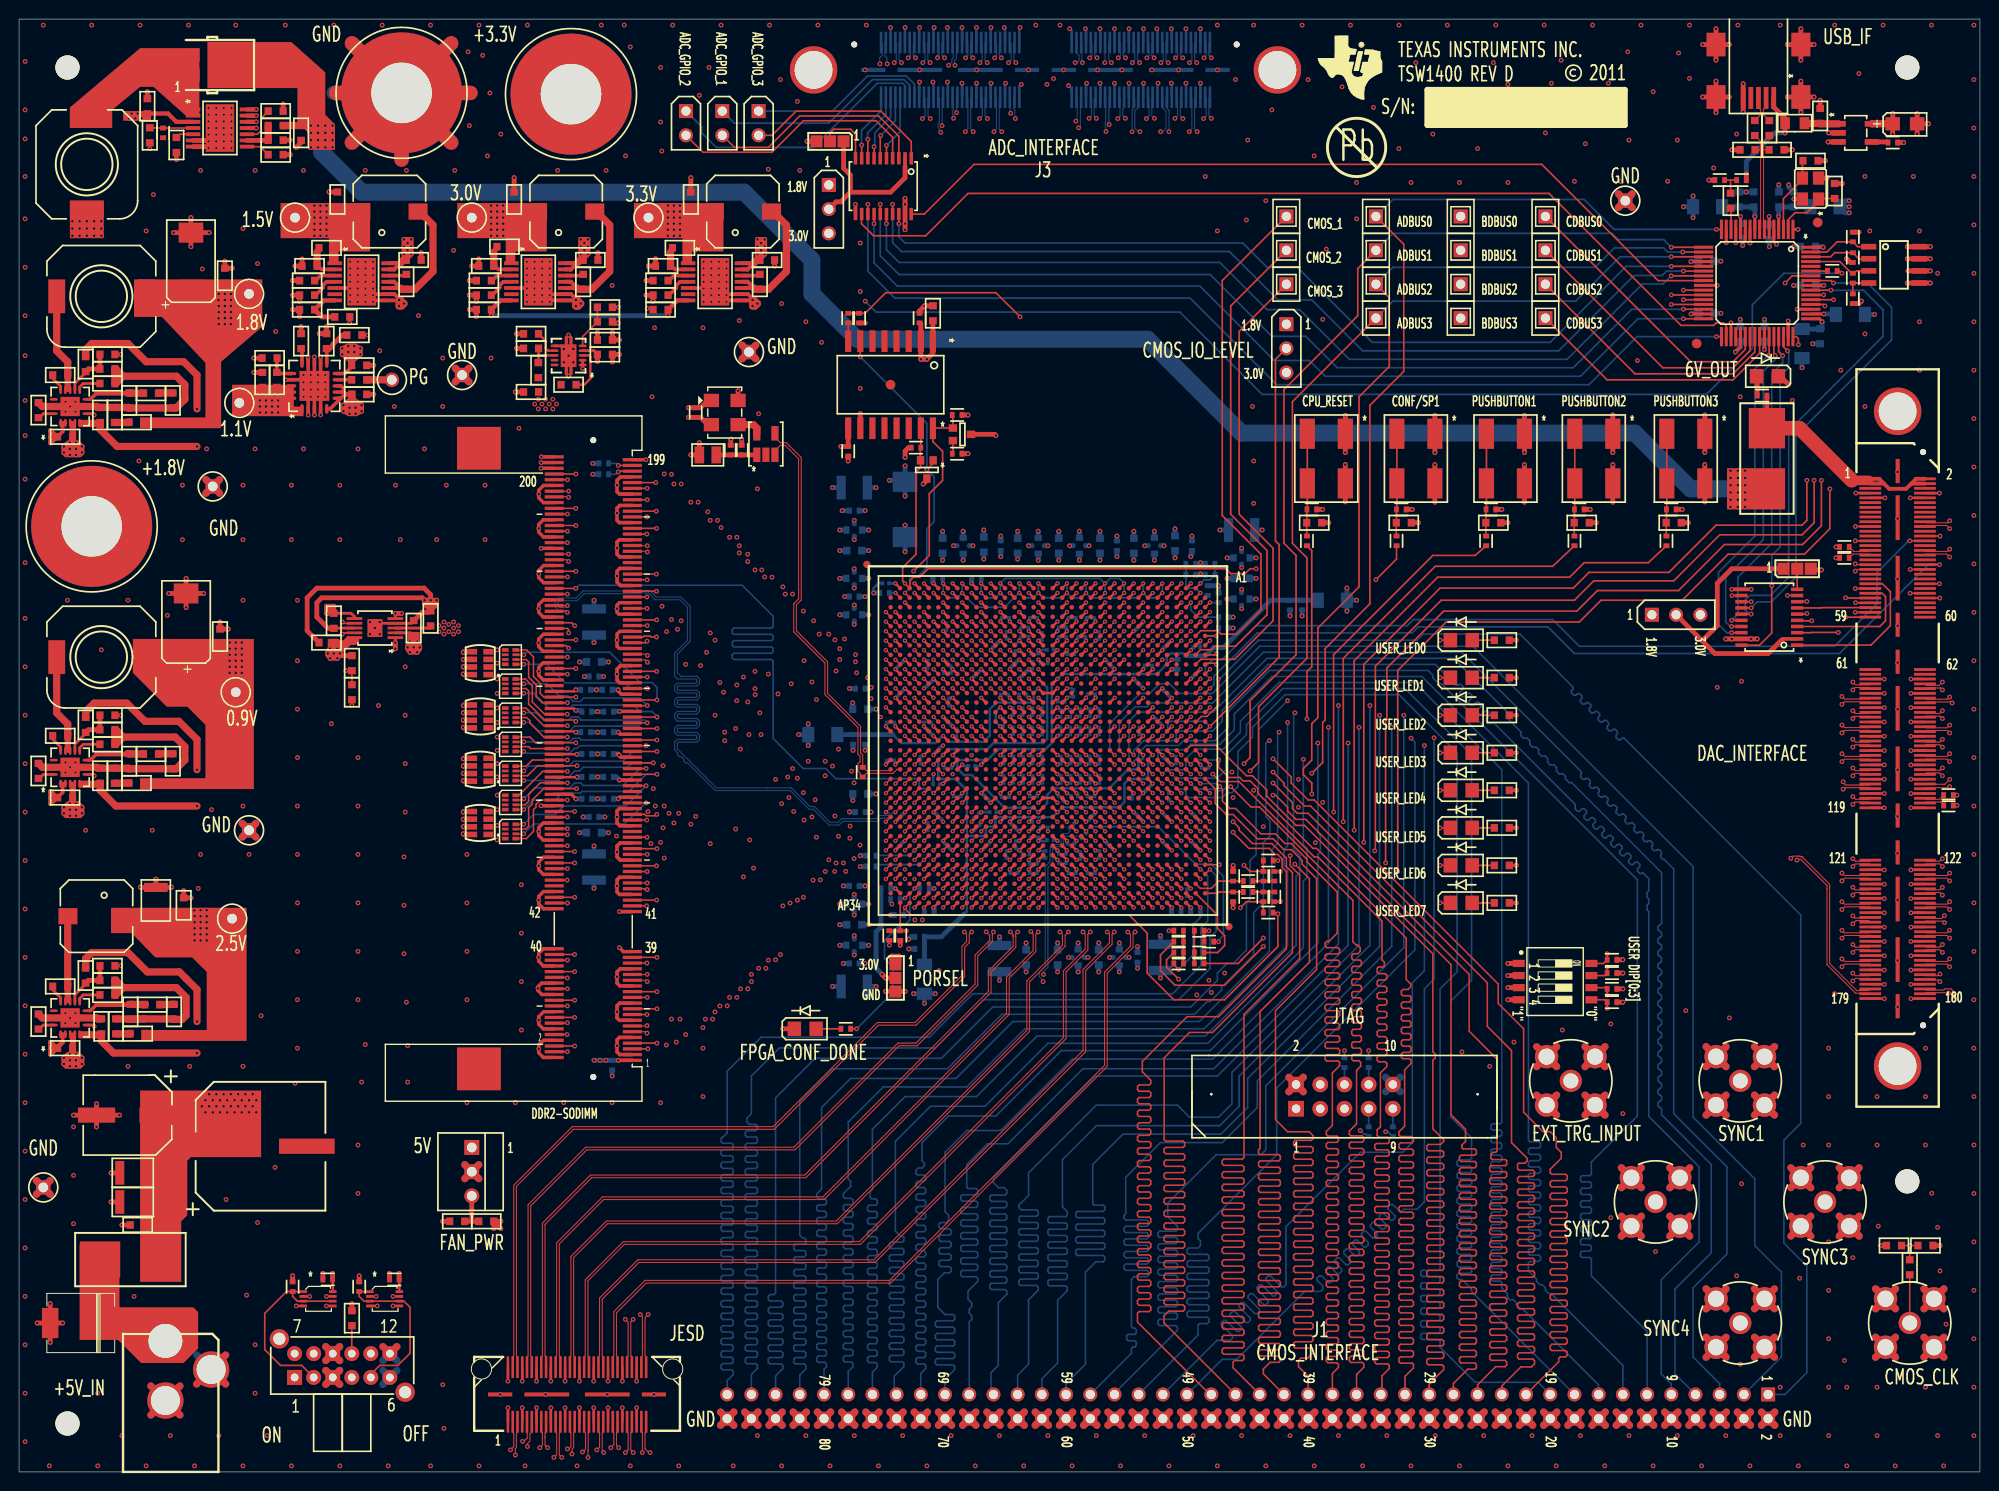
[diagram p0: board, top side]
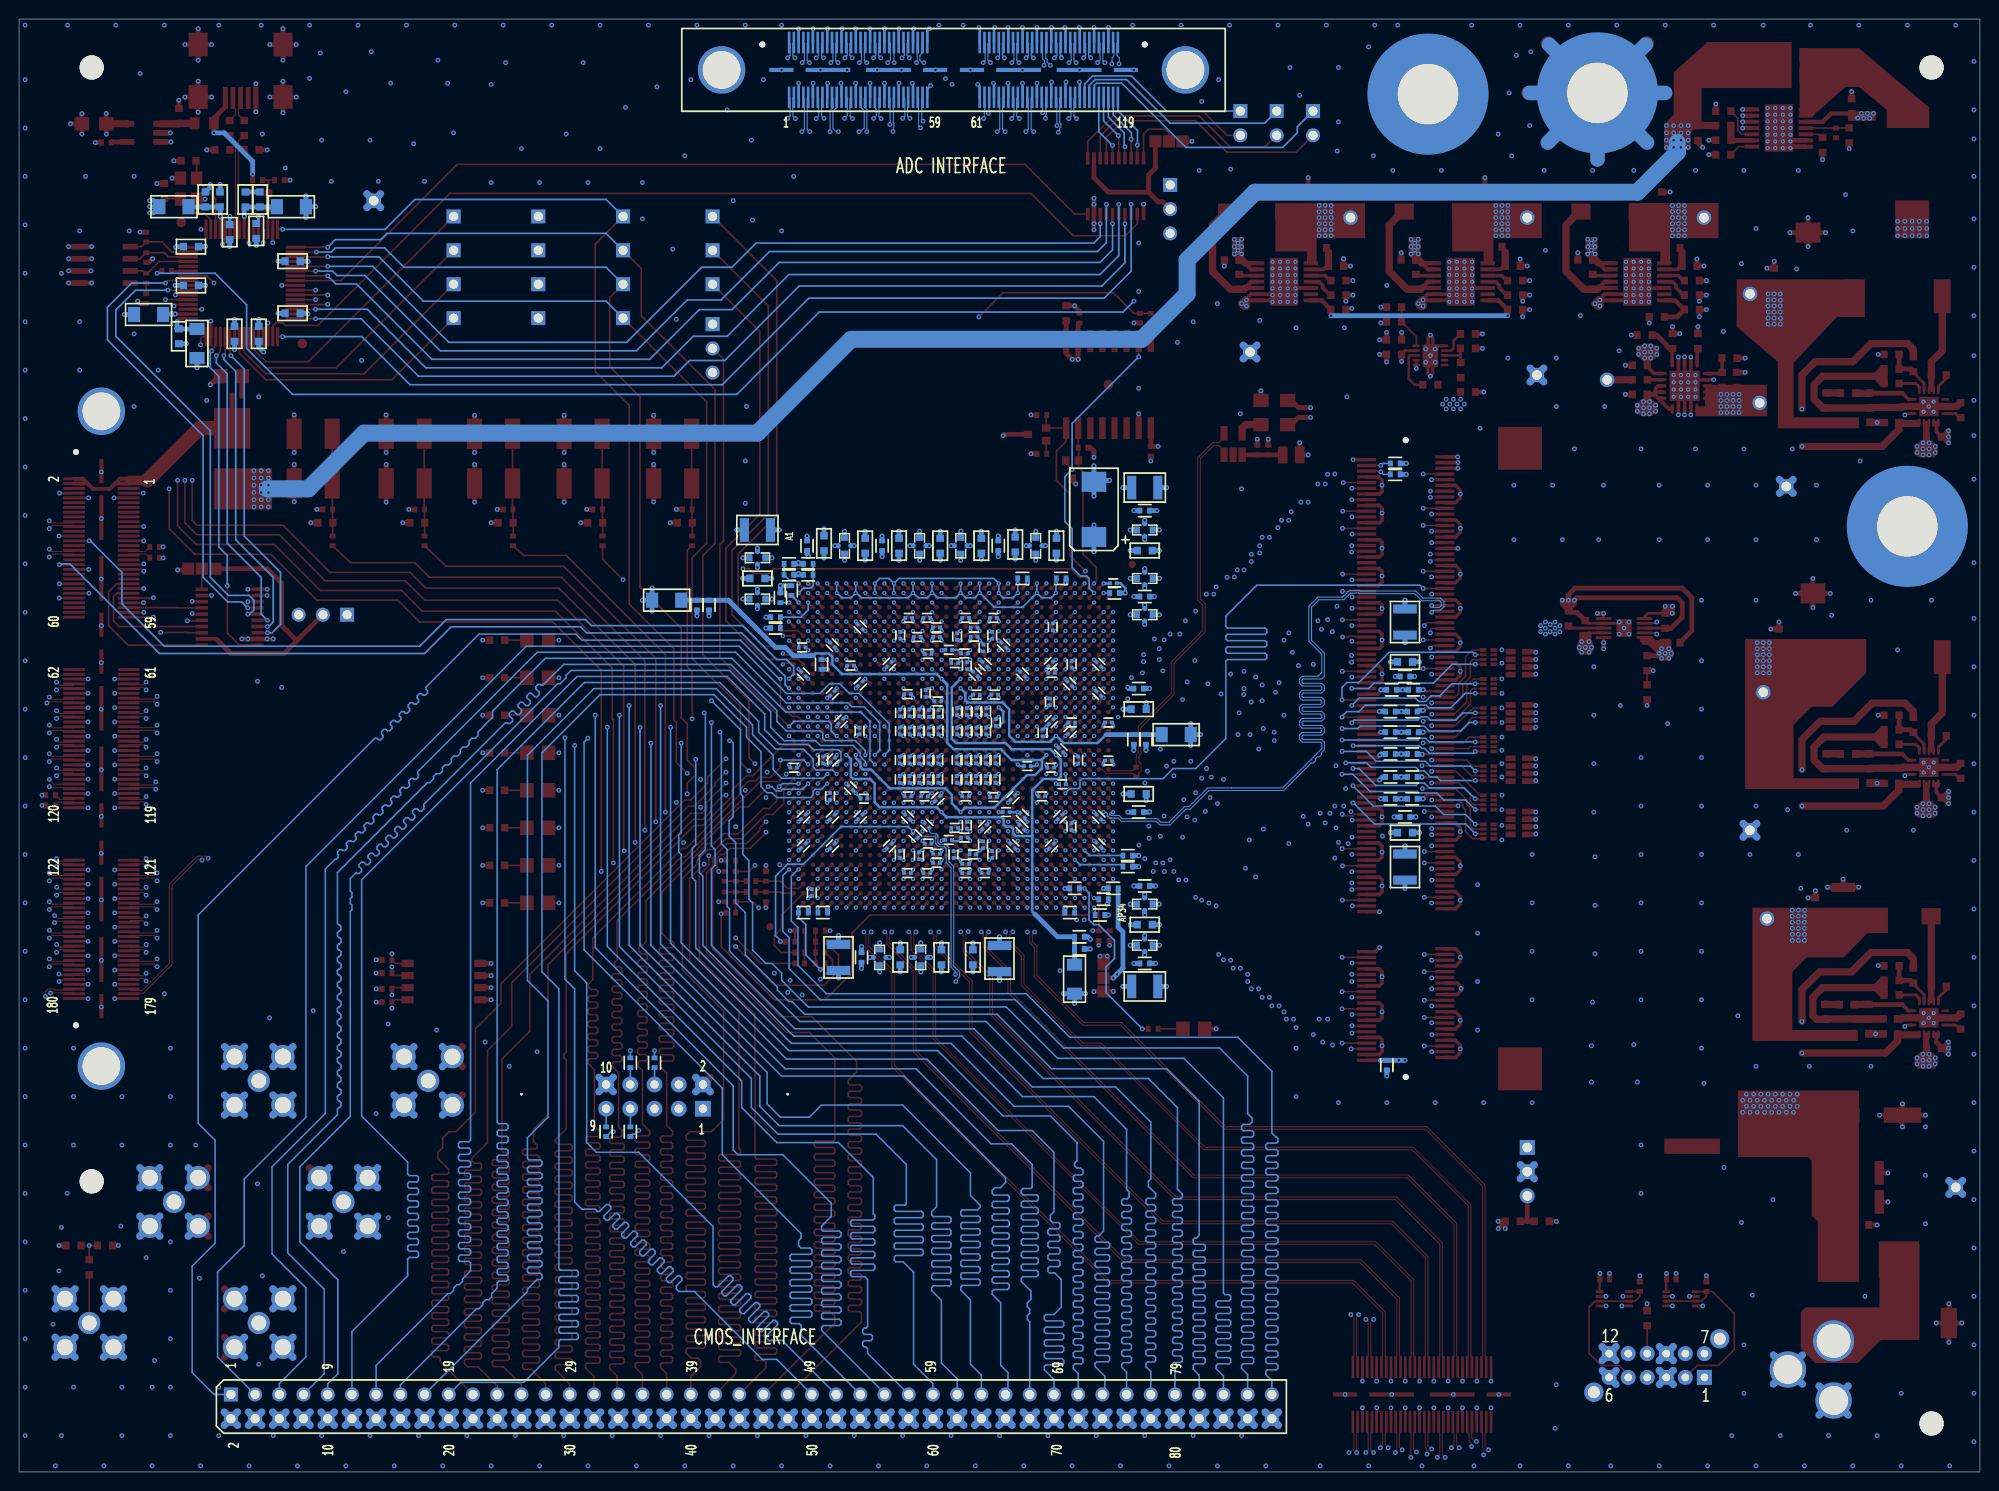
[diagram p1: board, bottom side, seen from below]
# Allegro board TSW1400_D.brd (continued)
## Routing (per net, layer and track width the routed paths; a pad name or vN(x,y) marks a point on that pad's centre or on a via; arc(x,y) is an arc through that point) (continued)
ADBUS0: length 118.5
  TOP w0.178: U3.16 v1(178.09,130.34) ; v1(135.64,73.28) 136.78,74.42 136.78,78.61 137.03,78.87 137.03,86.36 141.73,91.06 141.73,111.89 145.29,115.44 145.29,128.78 TP1.1 ; U5.D22 v2(121.95,71.2)
  L10-SIG4 w0.102: 121.97,71.2 v2(121.95,71.2)
  L10-SIG4 w0.178: v1(135.64,73.28) 135.64,72.92 133.17,70.46 130.99,70.46 130.51,70.94 128.96,70.94 128.52,71.37 125.86,71.37 125.22,70.74 122.43,70.74 121.97,71.2
  BOTTOM w0.178: TP1.1 144.15,133.48 164.21,133.48 167.35,130.34 v1(178.09,130.34)
ADBUS1: length 110.6
  TOP w0.178: v1(128.52,74.3) 129.16,74.93 129.16,80.9 133.99,85.72 133.99,96.14 132.72,97.41 132.72,113.54 140.46,121.28 140.46,126.24 TP2.1 ; U5.J20 v2(116.95,73.2) ; U3.17 v1(173.35,128.46)
  L10-SIG4 w0.178: v2(116.95,73.2) 116.95,73.21 117.45,73.71 118.19,73.71 118.44,73.96 118.44,74.35 118.77,74.68 122.15,74.68 123.29,75.82 127,75.82 v1(128.52,74.3)
  BOTTOM w0.178: TP2.1 144.15,129.92 167.13,129.92 167.79,129.26 172.56,129.26 v1(173.35,128.46)
ADBUS2: length 113.5
  TOP w0.178: U3.18 v1(174.55,127.96) ; TP3.1 143.76,123.19 143.76,115.95 140.59,112.78 140.59,92.84 136.27,88.52 136.27,79.12 135.64,78.49 135.64,74.68 134.75,73.79 134.75,73.15 135.64,72.26 v1(135.64,71.12) ; U5.D25 v2(121.95,68.2)
  L10-SIG4 w0.178: v1(135.64,71.12) 136.63,71.12 137.29,70.46 137.29,69.88 136.63,69.22 126.16,69.22 125.63,68.68 122.43,68.68 v2(121.95,68.2)
  BOTTOM w0.178: TP3.1 144.15,126.36 165.35,126.36 167.39,128.4 172.54,128.4 172.98,127.96 v1(174.55,127.96)
ADBUS3: length 102.5
  TOP w0.178: U5.F21 v2(119.95,72.2) ; U3.19 v1(173.35,127.46) ; TP4.1 133.6,112.27 133.6,97.41 135.13,95.89 135.13,85.34 130.05,80.26 130.05,74.42 v1(129.16,73.53)
  L10-SIG4 w0.178: v1(129.16,73.53) 128.02,73.53 127.65,73.89 126.47,73.89 126.24,73.66 120.65,73.66 120.4,73.41 120.4,72.65 v2(119.95,72.2)
  BOTTOM w0.178: v1(173.35,127.46) 167.98,127.46 163.32,122.81 144.15,122.81 TP4.1
ADC_0: length 90.3
  TOP w0.178: U3.24 171.96,124.96 159.77,137.16 100.2,137.16 94.99,131.94 U16.20
ADC_1: length 94.7
  TOP w0.178: U16.18 v1(92.31,130.94) ; U3.21 v1(173.35,126.46)
  BOTTOM w0.178: v1(92.31,130.94) 92.31,129.56 92.96,128.9 128.4,128.9 130.94,126.36 134.11,126.36 141.99,118.49 160.66,118.49 168.63,126.46 v1(173.35,126.46)
ADC_2: length 98.3
  TOP w0.178: U3.22 v1(174.62,125.96) ; U16.17 v1(91.66,132.97)
  BOTTOM w0.178: v1(174.62,125.96) 172.85,125.96 172.39,125.5 169.44,125.5 161.54,117.6 140.97,117.6 135.64,122.94 132.08,122.94 127,128.02 92.58,128.02 91.66,128.94 v1(91.66,132.97)
ADC_3: length 97.9
  TOP w0.178: U16.16 v1(91.01,130.94) ; U3.23 v1(173.35,125.46)
  BOTTOM w0.178: v1(173.35,125.46) 172.5,124.61 170.33,124.61 162.43,116.71 139.57,116.71 134.37,121.92 130.94,121.92 125.98,126.87 92.33,126.87 91.01,128.19 v1(91.01,130.94)
ADC_4: length 100.2
  TOP w0.178: U3.30 v1(174.62,121.96) ; U16.15 v1(90.36,132.97)
  BOTTOM w0.178: v1(90.36,132.97) 90.36,127.57 92.33,125.6 124.97,125.6 131.44,119.13 135,119.13 138.3,115.82 163.07,115.82 169.21,121.96 v1(174.62,121.96)
ADC_5: length 99.6
  TOP w0.178: U3.32 v1(174.62,120.96) ; U16.14 v1(89.71,130.94)
  BOTTOM w0.178: v1(174.62,120.96) 169.86,120.96 163.83,114.94 137.03,114.94 135.38,116.59 131.7,116.59 123.89,124.4 92.14,124.4 89.71,126.83 v1(89.71,130.94)
ADC_6: length 104.6
  TOP w0.178: U3.33 v1(178.09,119.09) ; U16.13 v1(89.06,132.97)
  BOTTOM w0.178: v1(178.09,119.09) 169.76,119.09 164.72,114.05 131.95,114.05 122.87,123.13 91.88,123.13 89.06,125.95 v1(89.06,132.97)
ADC_7: length 101.2
  TOP w0.178: U16.12 88.39,131.93 88.39,130.94 89.66,129.67 95.12,129.67 99.57,134.11 160.53,134.11 174.37,120.27 177.8,120.27 178.05,120.52 178.82,120.52 179.12,120.22 U3.34
ADC_GPIO_0: length 20.2
  TOP w0.178: U16.1 93.61,139.56 90.42,142.75 81.53,142.75 78.99,140.21 JP5.2
ADC_GPIO_1: length 23.6
  TOP w0.178: U16.3 92.31,140.1 90.17,142.24 81.92,142.24 78.61,138.94 75.06,138.94 JP6.2
ADC_GPIO_2: length 26.7
  TOP w0.178: JP7.2 71.75,138.43 78.99,138.43 82.3,141.73 89.92,141.73 91.66,139.99 U16.4
ADC_GPIO_3: length 7
  TOP w0.178: U16.5 v1(91.01,139.14)
  BOTTOM w0.178: J3.111 92.45,140.58 v1(91.01,139.14)
ADC_GPIO_4: length 7.1
  TOP w0.178: U16.6 90.36,140.18 v1(90.4,140.18)
  BOTTOM w0.178: J3.113 91.95,141.73 90.39,140.18 v1(90.4,140.18)
ADC_GPIO_5: length 7.1
  TOP w0.178: U16.7 v1(89.71,139.02)
  BOTTOM w0.178: v1(89.71,139.02) 89.79,139.1 89.79,140.46 91.45,142.12 J3.115
ADC_GPIO_6: length 7.2
  TOP w0.178: U16.8 v1(89.06,139.79)
  BOTTOM w0.178: v1(89.06,139.79) 89.03,139.83 89.03,140.46 90.95,142.38 J3.117
ADC_GPIO_7: length 7.3
  TOP w0.178: U16.9 v1(88.41,139.18)
  BOTTOM w0.178: v1(88.41,139.18) 88.39,139.19 88.39,140.72 90.45,142.77 J3.119
ASDI: length 91.8
  TOP w0.178: R156.2 v1(132.08,64.14) ; U19.15 C351.1 94.55,107.38 94.55,106.15 DN1.2 94.59,105.38 94.11,104.9 94.11,96.27 92.71,94.87 92.71,93.44 v2(92.95,93.2) U5.AM1 93.47,92.72 93.47,93.47 93.85,93.85 94.49,93.85 95.38,94.74 126.62,94.74 127.13,94.23 128.65,94.23 129.16,94.74 v1(129.79,94.74)
  L3-SIG1 w0.178: v1(132.08,64.14) 129.41,66.8 129.41,68.58 127.89,70.1 127.25,70.1 126.49,70.87 126.49,72.52 126.36,72.64 126.36,83.57 130.43,87.63 130.43,94.11 v1(129.79,94.74)
BDBUS0: length 106.7
  TOP w0.178: U5.D23 v2(121.95,70.2) ; U3.26 v1(174.62,123.96)
  L3-SIG1 w0.178: TP5.1 140.59,121.03 140.59,97.92 132.46,89.79 132.46,88.14 127.13,82.8 127.13,74.3 126.75,73.91 126.75,73.03 127.76,72.02 127.76,71.11 v1(127.38,70.74)
  L4-SIG2 w0.178: v2(121.95,70.2) 122.49,70.74 v1(127.38,70.74)
  L10-SIG4 w0.178: TP5.1 153.03,129.92 167.89,129.92 173.35,124.46 174.13,124.46 v1(174.62,123.96)
BDBUS1: length 104.2
  TOP w0.178: U5.J21 v2(116.95,72.2) ; U3.27 v1(173.35,123.46)
  L3-SIG1 w0.178: v1(127.25,73.41) 127.89,74.04 127.89,82.17 136.4,90.68 136.4,92.46 141.99,98.04 141.99,118.87 TP6.1
  L4-SIG2 w0.178: v1(127.25,73.41) 127.04,73.62 125.46,73.62 125.43,73.65 125.06,73.65 125.04,73.62 117.78,73.62 117.53,73.37 117.53,73.36 117.42,73.25 117.42,72.67 v2(116.95,72.2)
  L10-SIG4 w0.178: TP6.1 153.16,126.24 169.04,126.24 171.83,123.44 173.34,123.44 v1(173.35,123.46)
BDBUS2: length 103.2
  TOP w0.178: U3.28 v1(174.62,122.96) ; U5.D26 v2(121.95,67.2)
  L3-SIG1 w0.178: TP7.1 144.91,118.24 144.91,99.44 137.54,92.08 137.54,90.42 129.79,82.68 129.79,72.77 128.91,71.88 128.91,71.12 130.56,69.47 v1(130.56,67.69)
  L4-SIG2 w0.178: v2(121.95,67.2) 121.95,67.2 122.37,66.78 126.56,66.78 126.72,66.62 128.6,66.62 129.67,67.69 v1(130.56,67.69)
  L10-SIG4 w0.178: v1(174.62,122.96) 174.6,122.94 172.72,122.94 172.47,122.68 153.16,122.68 TP7.1
BDBUS3: length 96.9
  TOP w0.178: U3.29 v1(173.35,122.46) ; U5.F22 v2(119.95,71.2)
  L3-SIG1 w0.178: TP8.1 145.67,115.44 145.67,98.17 138.68,91.19 138.68,90.17 130.56,82.04 130.56,72.52 v1(129.54,71.5)
  L4-SIG2 w0.178: v1(129.54,71.5) 129.29,71.25 125.73,71.25 125.22,71.75 120.5,71.75 v2(119.95,71.2)
  L10-SIG4 w0.178: v1(173.35,122.46) 173.26,122.46 170.05,119.25 153.03,119.25 TP8.1
CDBUS0: length 117.1
  TOP w0.178: U3.38 181.12,117.75 179.83,116.46 175.39,116.46 TP9.1 ; U5.D24 v2(121.95,69.2)
  L3-SIG1 w0.178: TP9.1 157.61,129.16 157.61,124.33 147.19,113.92 147.19,99.82 147.26,99.75 147.26,94.55 133.99,81.28 133.99,80.77 132.46,79.25 132.46,78.23 133.48,77.22 133.48,70.48 v1(134.24,69.72)
  L4-SIG2 w0.102: v2(121.95,69.2) 122.03,69.2
  L4-SIG2 w0.178: v1(134.24,69.72) 133.68,70.28 127.69,70.28 127.13,69.72 122.56,69.72 122.03,69.2
CDBUS1: length 112.5
  TOP w0.178: U5.H21 v2(117.95,72.2) ; TP10.1 172.47,115.82 179.83,115.82 181.62,117.61 U3.39
  L3-SIG1 w0.178: TP10.1 158.5,126.49 158.5,123.95 149.1,114.55 149.1,94.74 135,80.64 135,79.76 134.11,78.87 134.11,72.77 v1(134.24,72.64)
  L4-SIG2 w0.178: v2(117.95,72.2) 118.44,72.69 125.32,72.69 125.38,72.76 125.43,72.76 125.59,72.92 127.68,72.92 127.71,72.9 132.46,72.9 132.72,72.64 v1(134.24,72.64)
CDBUS2: length 113
  TOP w0.178: U5.D27 v2(121.95,66.2) ; U3.40 182.12,117.48 179.83,115.19 169.54,115.19 TP11.1
  L3-SIG1 w0.178: v1(136.02,66.01) 136.02,66.04 135,67.06 135,73.91 135.38,74.3 135.38,77.98 136.14,78.74 136.14,79.5 150.62,93.98 150.62,115.06 TP11.1
  L4-SIG2 w0.178: v2(121.95,66.2) 122.49,65.66 130.48,65.66 130.81,65.99 135.71,65.99 135.74,66.01 v1(136.02,66.01)
CDBUS3: length 106.8
  TOP w0.178: TP12.1 166.62,114.55 179.83,114.55 182.62,117.34 U3.41 ; U5.F23 v2(119.95,70.2)
  L3-SIG1 w0.178: TP12.1 152.53,113.41 152.53,93.42 137.92,78.82 137.92,71.37 v1(136.78,70.23)
  L10-SIG4 w0.178: v2(119.95,70.2) 120.43,69.72 125.35,69.72 125.48,69.85 127.36,69.85 127.79,70.28 129.77,70.28 130.2,69.85 133.16,69.85 133.54,70.23 v1(136.78,70.23)
CLK_GXB1_M: length 79.5
  TOP w0.114: U5.AD34 v2(100.95,59.2) ; J2.54 64.3,12.08 64.18,12.19 64.18,15.75 64.44,16 v1(64.43,16)
  L9-SIG3 w0.102: v2(100.95,59.2) 100.95,59.06 100.98,59.03 100.98,34.95 91.17,25.15 65.53,25.15 64.14,23.75 64.14,16.3 v1(64.43,16)
CLK_GXB1_P: length 80.7
  TOP w0.114: U5.AD33 v2(100.95,60.2) ; v1(63.61,16) 63.62,16 63.63,16 63.91,15.72 63.91,12.18 63.8,12.06 J2.52
  L9-SIG3 w0.102: v2(100.95,60.2) 100.95,59.74 100.57,59.36 100.57,59.04 100.7,58.92 100.7,35.07 91.05,25.43 65.42,25.43 63.86,23.86 63.86,16.25 v1(63.61,16)
CLK_GXB2_M: length 79.3
  TOP w0.114: U5.AB34 v2(102.95,59.2) ; J2.60 65.8,12.08 65.68,12.19 65.68,16.19 v1(66.01,16.51)
  L9-SIG3 w0.102: v2(102.95,59.2) 102.95,57.02 103.66,56.32 103.66,33.93 90.55,20.83 66.52,20.83 66.42,20.73 66.42,20.7 65.66,19.94 65.66,16.86 v1(66.01,16.51)
CLK_GXB2_P: length 80.4
  TOP w0.114: J2.58 65.3,12.06 65.41,12.18 65.41,16.29 v1(65.19,16.51) ; U5.AB33 v2(102.95,60.2)
  L9-SIG3 w0.102: v2(102.95,60.2) 102.95,59.77 102.57,59.39 102.57,59.04 102.67,58.94 102.67,56.91 103.38,56.2 103.38,34.05 90.44,21.11 66.41,21.11 66.14,20.84 66.14,20.82 65.38,20.05 65.38,16.7 v1(65.19,16.51)
CLK_GXB3_M: length 83.3
  TOP w0.114: v1(64.44,2.03) 64.18,2.28 64.18,4.08 64.3,4.19 J2.53 ; U5.M34 v2(113.95,59.2)
  L4-SIG2 w0.102: v1(64.44,2.03) 64.16,2.31 64.16,4.21 70.61,10.66 70.61,16.89 105.03,51.31 106.05,51.31 111.12,56.39 111.12,57.15 112,58.03 112.56,58.03 112.58,58.04 113.16,58.04 113.95,58.83 v2(113.95,59.2)
CLK_GXB3_P: length 84.4
  TOP w0.114: J2.51 63.8,4.19 63.91,4.08 63.91,2.32 v1(63.62,2.03) ; U5.M33 v2(113.95,60.2)
  L4-SIG2 w0.102: v2(113.95,60.2) 113.95,60.1 113.41,59.56 113.41,58.67 113.03,58.29 112.58,58.29 112.56,58.31 111.89,58.31 110.85,57.27 110.85,56.5 105.93,51.59 104.91,51.59 70.33,17.01 70.33,10.77 63.88,4.32 63.88,2.3 v1(63.62,2.03)
CLK_GXB4_M: length 82.7
  TOP w0.114: v1(66.21,2.03) 66.07,2.03 65.68,2.41 65.68,4.06 65.8,4.17 J2.59 ; U5.K34 v2(115.95,59.2)
  L4-SIG2 w0.102: v2(115.95,59.2) 115.95,59.04 114.8,57.89 114.29,57.89 113.69,57.29 113.69,56.65 111.02,53.99 111.02,52.92 110.72,52.62 110.72,52.04 81,22.33 80.87,22.33 74.42,15.88 74.42,12.93 65.91,4.42 65.91,2.33 v1(66.21,2.03)
CLK_GXB4_P: length 83.5
  TOP w0.114: U5.K33 v2(115.95,60.2) ; v1(65.39,2.03) 65.41,2.05 65.41,4.08 65.3,4.19 J2.57
  L4-SIG2 w0.102: v1(65.39,2.03) 65.63,2.28 65.63,4.54 74.14,13.04 74.14,15.99 80.76,22.61 80.88,22.61 110.44,52.16 110.44,52.74 110.74,53.04 110.74,54.1 113.41,56.77 113.41,57.4 114.17,58.17 114.68,58.17 115.32,58.8 115.32,59.03 115.33,59.04 115.33,59.36 115.32,59.37 115.32,59.44 115.95,60.07 v2(115.95,60.2)
CLK_OSCN: length 42.8
  TOP w0.114: U6.4 79.31,108.52 79.88,107.95 80.52,107.95 82.07,106.4 82.07,91.47 81.56,90.96 81.56,88.24 84.84,84.96 84.84,81.66 88.29,78.21 88.29,75.41 88.52,75.18 R76.1 88.54,73.91 88.9,73.56 91.31,73.56 U5.AP20
CLK_OSCP: length 44.8
  TOP w0.114: U6.3 79.31,107.12 79.86,107.67 80.4,107.67 81.79,106.28 81.79,91.58 81.28,91.07 81.28,88.12 84.56,84.85 84.56,81.55 88.01,78.09 88.01,75.3 88.24,75.07 88.24,74.52 88.02,74.3 88.02,73.53 88.27,73.28 88.27,73.15 R76.2 88.9,73.28 91.27,73.28 91.27,73.27 91.63,73.27 91.63,73.28 91.69,73.28 92.12,73.7 U5.AN20
CMOS_CLK: length 115
  TOP w0.165: R16.1 v1(198.37,23.75) ; v1(198.37,23.75) C46.2 ; v1(198.37,23.75) R15.2 ; U5.B18 v2(123.95,75.2)
  L3-SIG1 w0.102: 125.35,74.42 124.57,75.2 v2(123.95,75.2)
  L3-SIG1 w0.114: v1(198.37,23.75) 194.94,27.18 194.94,32.38 187.2,40.13 187.2,43.56 179.32,51.44 153.29,51.44 152.15,52.58 132.33,52.58 129.92,54.99 129.92,56.26 131.19,57.53 131.19,64.01 128.91,66.29 128.91,68.07 127.76,69.22 127.25,69.22 126.36,70.1 126.36,70.48 125.6,71.25 125.6,71.68 125.48,71.81 125.48,72.52 125.73,72.77 125.73,74.04 125.35,74.42
CMOS_PORT0_0: length 140
  TOP w0.165: U5.B15 123.51,78.7 124.05,79.25 124.64,79.25 125.86,80.47 v2(125.86,83.19)
  BOTTOM w0.165: J1.1 185.28,8.13 187.58,10.42 187.58,21.59 185.17,24 185.17,34.8 186.94,36.58 186.94,58.42 168.41,76.96 168.17,76.96 168.02,76.81 167.79,76.81 167.56,77.04 167.56,77.28 167.71,77.43 167.71,77.66 167.47,77.89 167.24,77.89 167.09,77.74 166.86,77.74 166.62,77.98 166.62,78.21 166.77,78.36 166.77,78.59 166.54,78.83 166.3,78.83 166.16,78.68 165.92,78.68 165.69,78.91 165.69,79.15 165.84,79.29 165.84,79.53 165.6,79.76 165.37,79.76 165.22,79.61 164.99,79.61 164.76,79.85 164.76,80.08 164.9,80.23 164.9,80.46 164.67,80.69 164.44,80.69 164.29,80.55 164.06,80.55 163.82,80.78 163.82,81.01 163.97,81.16 163.97,81.39 163.74,81.63 163.5,81.63 163.35,81.48 163.12,81.48 162.89,81.71 162.89,81.95 163.04,82.1 163.04,82.33 157.48,87.88 147.32,87.88 146.69,87.25 130.05,87.25 125.98,83.19 v2(125.86,83.19)
CMOS_PORT0_1: length 140
  TOP w0.165: U5.L18 v2(114.95,75.2)
  BOTTOM w0.165: J1.3 184.91,12.06 184.91,20.95 182.12,23.75 182.12,30.73 175.64,37.21 175.64,63.5 152.53,86.61 130.18,86.61 125.22,81.66 121.72,81.66 120.7,82.68 119.63,82.68 118.62,81.66 117.6,81.66 114.43,78.49 114.43,75.72 v2(114.95,75.2)
CMOS_PORT0_2: length 140.1
  TOP w0.165: U5.K18 v2(115.95,75.2)
  BOTTOM w0.165: v2(115.95,75.2) 115.44,75.71 115.44,78.61 117.09,80.26 118.36,80.26 118.77,80.67 125.25,80.67 130.56,85.98 151.38,85.98 163.92,73.44 163.92,73.21 163.84,73.13 163.84,72.89 164.07,72.66 164.3,72.66 164.39,72.74 164.62,72.74 164.85,72.51 164.85,72.28 164.77,72.19 164.77,71.96 165,71.72 165.24,71.72 165.32,71.81 165.55,71.81 165.79,71.58 165.79,71.34 165.7,71.26 165.7,71.02 165.94,70.79 166.17,70.79 166.25,70.87 166.49,70.87 166.72,70.64 166.72,70.41 166.64,70.32 166.64,70.09 166.87,69.86 167.1,69.86 167.19,69.94 167.42,69.94 167.66,69.71 167.66,69.47 167.57,69.39 167.57,69.16 167.81,68.92 168.04,68.92 168.12,69.01 168.36,69.01 168.59,68.77 168.59,68.54 168.51,68.46 168.51,68.22 168.74,67.99 168.97,67.99 169.06,68.07 169.29,68.07 169.52,67.84 169.52,67.61 169.44,67.52 169.44,67.29 169.67,67.05 169.91,67.05 169.99,67.14 170.22,67.14 170.46,66.91 170.46,66.67 170.37,66.59 170.37,66.35 170.61,66.12 170.84,66.12 170.92,66.2 171.16,66.2 171.39,65.97 171.39,65.74 171.31,65.65 171.31,65.42 171.54,65.19 171.77,65.19 171.86,65.27 172.09,65.27 172.33,65.04 172.33,64.8 172.24,64.72 172.24,64.49 172.47,64.25 172.6,64.25 173.61,63.25 173.61,37.59 179.2,32 179.2,22.86 175.64,19.3 175.64,12.06 178.44,9.27 178.44,8.13
CMOS_PORT0_3: length 140
  TOP w0.165: U5.K19 v2(115.95,74.2)
  BOTTOM w0.165: v2(115.95,74.2) 116.46,74.71 116.46,78.74 117.42,79.71 125.3,79.71 130.94,85.34 150.52,85.34 156.06,79.8 156.06,79.17 156.83,78.4 156.83,78.37 157.58,77.62 157.58,77.24 157.86,76.97 158.24,76.97 158.51,76.69 158.51,76.31 158.79,76.03 159.17,76.03 159.45,75.76 159.45,75.38 159.72,75.1 160.11,75.1 160.38,74.82 160.38,74.44 160.66,74.16 161.04,74.16 161.32,73.89 161.32,73.51 161.59,73.23 161.97,73.23 162.25,72.95 162.25,72.7 162.65,72.3 162.91,72.3 172.34,62.87 172.34,57.54 172.17,57.38 172.12,57.38 171.96,57.21 171.96,56.88 172.12,56.72 172.17,56.72 172.34,56.55 172.34,56.22 172.17,56.06 172.12,56.06 171.96,55.89 171.96,55.56 172.12,55.4 172.17,55.4 172.34,55.23 172.34,54.9 172.17,54.74 172.12,54.74 171.96,54.57 171.96,54.24 172.12,54.08 172.17,54.08 172.34,53.91 172.34,53.58 172.17,53.42 172.12,53.42 171.96,53.25 171.96,52.92 172.12,52.75 172.17,52.75 172.34,52.59 172.34,52.26 172.17,52.09 172.12,52.09 171.96,51.93 171.96,51.6 172.12,51.43 172.17,51.43 172.34,51.27 172.34,50.94 172.17,50.77 172.12,50.77 171.96,50.61 171.96,50.28 172.12,50.11 172.17,50.11 172.34,49.95 172.34,49.62 172.17,49.45 172.12,49.45 171.96,49.29 171.96,48.96 172.12,48.79 172.17,48.79 172.34,48.63 172.34,48.3 172.17,48.13 172.12,48.13 171.96,47.97 171.96,47.64 172.12,47.47 172.17,47.47 172.34,47.31 172.34,46.98 172.17,46.81 172.12,46.81 171.96,46.65 171.96,46.32 172.12,46.15 172.17,46.15 172.34,45.99 172.34,45.66 172.17,45.49 172.12,45.49 171.96,45.33 171.96,44.99 172.12,44.83 172.17,44.83 172.34,44.66 172.34,44.33 172.17,44.17 172.12,44.17 171.96,44 171.96,43.67 172.12,43.51 172.17,43.51 172.34,43.34 172.34,43.01 172.17,42.85 172.12,42.85 171.96,42.68 171.96,42.35 172.12,42.19 172.17,42.19 172.34,42.02 172.34,41.69 172.17,41.53 172.12,41.53 171.96,41.36 171.96,41.03 172.12,40.87 172.17,40.87 172.34,40.7 172.34,40.37 172.17,40.21 172.12,40.21 171.96,40.04 171.96,39.71 172.12,39.55 172.17,39.55 172.34,39.38 172.34,39.05 172.17,38.89 172.12,38.89 171.96,38.72 171.96,38.39 172.12,38.23 172.17,38.23 172.34,38.06 172.34,37.47 177.55,32.26 177.55,22.99 173.74,19.18 173.74,10.29 175.9,8.13
CMOS_PORT0_4: length 140
  TOP w0.165: U5.J18 v2(116.95,75.2)
  BOTTOM w0.165: v2(116.95,75.2) 116.97,75.22 116.97,75.69 117.98,76.71 121.16,76.71 121.41,76.96 121.41,77.47 121.67,77.72 125.22,77.72 126.24,78.74 126.24,79.88 131.06,84.71 148.59,84.71 150.75,82.55 150.98,82.55 151.04,82.61 151.28,82.61 151.51,82.37 151.51,82.14 151.16,81.79 151.16,81.56 151.39,81.32 151.63,81.32 151.98,81.67 152.21,81.67 152.44,81.44 152.44,81.21 152.09,80.86 152.09,80.62 152.33,80.39 152.56,80.39 152.91,80.74 153.14,80.74 153.38,80.51 153.38,80.27 153.03,79.92 153.03,79.69 153.26,79.45 153.49,79.45 153.84,79.8 154.08,79.8 154.31,79.57 154.31,79.34 153.96,78.99 153.96,78.75 154.19,78.52 154.43,78.52 154.49,78.58 154.72,78.58 163.28,70.02 163.28,69.79 163.27,69.78 163.27,69.55 163.5,69.31 163.74,69.31 163.98,69.56 164.22,69.56 164.45,69.33 164.45,69.1 164.2,68.85 164.2,68.61 164.44,68.38 164.67,68.38 164.92,68.63 165.15,68.63 165.39,68.4 165.39,68.16 165.14,67.91 165.14,67.68 165.37,67.45 165.6,67.45 165.85,67.7 166.09,67.7 166.32,67.46 166.32,67.23 166.07,66.98 166.07,66.75 166.3,66.51 166.54,66.51 166.79,66.76 167.02,66.76 167.25,66.53 167.25,66.29 167,66.05 167,65.81 167.24,65.58 167.47,65.58 167.72,65.83 167.95,65.83 168.19,65.59 168.19,65.36 167.94,65.11 167.94,64.88 168.17,64.64 168.41,64.64 168.65,64.89 168.89,64.89 169.12,64.66 169.12,64.43 168.87,64.18 168.87,63.94 169.11,63.71 169.34,63.71 169.59,63.96 169.82,63.96 170.06,63.73 170.06,63.49 169.81,63.24 169.81,63.01 170.04,62.78 170.27,62.78 170.36,62.87 170.99,62.24 170.99,60.95 170.81,60.77 170.81,60.29 170.99,60.11 170.99,59.63 170.81,59.45 170.81,58.97 170.99,58.79 170.99,37.29 176.28,32 176.28,24.13 172.3,20.15 172.3,10.29 173.35,9.23 J1.9
CMOS_PORT0_5: length 140
  TOP w0.165: U5.J19 v2(116.95,74.2)
  BOTTOM w0.165: v2(116.95,74.2) 116.95,74.53 117.47,75.06 117.47,75.44 118.24,76.2 121.67,76.2 122.17,76.71 125.48,76.71 126.87,78.11 126.87,79.76 131.19,84.07 147.83,84.07 148.34,83.57 148.34,83.31 148.97,82.68 149.22,82.68 169.8,62.1 169.8,37.34 164.97,32.51 164.97,31.25 164.81,31.08 164,31.08 163.83,30.92 163.83,30.59 164,30.42 164.81,30.42 164.97,30.26 164.97,29.93 164.81,29.76 164,29.76 163.83,29.6 163.83,29.27 164,29.1 164.81,29.1 164.97,28.94 164.97,28.61 164.81,28.44 164,28.44 163.83,28.27 163.83,27.94 164,27.78 164.81,27.78 164.97,27.61 164.97,27.28 164.81,27.12 164,27.12 163.83,26.95 163.83,26.62 164,26.46 164.81,26.46 164.97,26.29 164.97,25.96 164.81,25.8 164,25.8 163.83,25.63 163.83,25.3 164,25.14 164.81,25.14 164.97,24.97 164.97,24.64 164.81,24.48 164,24.48 163.83,24.31 163.83,23.98 164,23.82 164.81,23.82 164.97,23.65 164.97,23.32 164.81,23.16 164,23.16 163.83,22.99 163.83,22.66 164,22.5 164.81,22.5 164.97,22.33 164.97,20.57 170.81,14.73 J1.11
CMOS_PORT0_6: length 140
  TOP w0.165: U5.F19 v2(119.95,74.2)
  BOTTOM w0.165: 168.28,8.13 168.28,11.18 160.75,18.71 160.49,18.71 160.15,19.05 160.15,19.3 159.81,19.64 159.56,19.64 159.22,19.98 159.22,20.23 158.37,21.08 158.37,21.92 158.53,22.08 159.47,22.08 159.64,22.25 159.64,22.58 159.47,22.74 158.53,22.74 158.37,22.91 158.37,23.24 158.53,23.41 159.47,23.41 159.64,23.57 159.64,23.9 159.47,24.07 158.53,24.07 158.37,24.23 158.37,24.56 158.53,24.73 159.47,24.73 159.64,24.89 159.64,25.22 159.47,25.39 158.53,25.39 158.37,25.55 158.37,25.88 158.53,26.05 159.47,26.05 159.64,26.21 159.64,26.54 159.47,26.71 158.53,26.71 158.37,26.87 158.37,27.2 158.53,27.37 159.47,27.37 159.64,27.53 159.64,27.86 159.47,28.03 158.53,28.03 158.37,28.19 158.37,28.52 158.53,28.69 159.47,28.69 159.64,28.85 159.64,29.18 159.47,29.35 158.53,29.35 158.37,29.51 158.37,29.84 158.53,30.01 159.47,30.01 159.64,30.17 159.64,30.5 159.47,30.67 158.53,30.67 158.37,30.83 158.37,31.16 158.53,31.33 159.47,31.33 159.64,31.5 159.64,31.83 159.47,31.99 158.53,31.99 158.37,32.16 158.37,32.49 158.53,32.65 159.47,32.65 159.64,32.82 159.64,33.15 159.47,33.31 158.53,33.31 158.37,33.48 158.37,33.81 158.53,33.97 159.47,33.97 159.64,34.14 159.64,34.47 159.47,34.63 158.53,34.63 158.37,34.8 158.37,72.26 147.19,83.44 131.44,83.44 127.51,79.5 127.51,77.85 125.98,76.33 122.94,76.33 122.37,75.76 119.76,75.76 119.51,75.51 119.51,74.64 v2(119.95,74.2)
CMOS_PORT0_7: length 140
  TOP w0.165: U5.F20 v2(119.95,73.2)
  BOTTOM w0.165: 165.74,8.13 165.74,9.12 157.73,17.12 157.5,17.12 157.09,17.54 157.09,17.77 156.8,18.06 156.44,18.06 156.15,18.34 156.15,18.7 155.57,19.28 155.57,19.85 155.41,20.01 154.6,20.01 154.43,20.18 154.43,20.51 154.6,20.67 155.41,20.67 155.57,20.84 155.57,21.17 155.41,21.33 154.6,21.33 154.43,21.5 154.43,21.83 154.6,21.99 155.41,21.99 155.57,22.16 155.57,22.49 155.41,22.65 154.6,22.65 154.43,22.82 154.43,23.15 154.6,23.31 155.41,23.31 155.57,23.48 155.57,23.81 155.41,23.98 154.6,23.98 154.43,24.14 154.43,24.47 154.6,24.64 155.41,24.64 155.57,24.8 155.57,25.13 155.41,25.3 154.6,25.3 154.43,25.46 154.43,25.79 154.6,25.96 155.41,25.96 155.57,26.12 155.57,26.45 155.41,26.62 154.6,26.62 154.43,26.78 154.43,27.11 154.6,27.28 155.41,27.28 155.57,27.44 155.57,27.77 155.41,27.94 154.6,27.94 154.43,28.1 154.43,28.43 154.6,28.6 155.41,28.6 155.57,28.76 155.57,29.09 155.41,29.26 154.6,29.26 154.43,29.42 154.43,29.75 154.6,29.92 155.41,29.92 155.57,30.08 155.57,30.41 155.41,30.58 154.6,30.58 154.43,30.74 154.43,31.07 154.6,31.24 155.41,31.24 155.57,31.4 155.57,31.73 155.41,31.9 154.6,31.9 154.43,32.07 154.43,32.4 154.6,32.56 155.41,32.56 155.57,32.73 155.57,33.06 155.41,33.22 154.6,33.22 154.43,33.39 154.43,33.72 154.6,33.88 155.41,33.88 155.57,34.05 155.57,34.38 155.41,34.54 154.6,34.54 154.43,34.71 154.43,35.04 154.6,35.2 155.41,35.2 155.57,35.37 155.57,35.7 155.41,35.86 154.6,35.86 154.43,36.03 154.43,36.36 154.6,36.52 155.41,36.52 155.57,36.69 155.57,73.66 146.43,82.8 132.21,82.8 128.14,78.74 128.14,77.6 126.36,75.82 123.44,75.82 122.43,74.8 122.43,73.96 122.1,73.64 120.39,73.64 v2(119.95,73.2)
CMOS_PORT0_8: length 140.1
  TOP w0.165: U5.E20 v2(120.95,73.2)
  BOTTOM w0.165: J1.17 152.4,18.92 152.4,19.18 151.4,20.18 151.04,20.18 150.88,20.34 150.88,20.67 151.04,20.84 152.23,20.84 152.4,21 152.4,21.34 152.23,21.5 151.04,21.5 150.88,21.67 150.88,22 151.04,22.16 152.23,22.16 152.4,22.33 152.4,22.66 152.23,22.82 151.04,22.82 150.88,22.99 150.88,23.32 151.04,23.48 152.23,23.48 152.4,23.65 152.4,23.98 152.23,24.14 151.04,24.14 150.88,24.31 150.88,24.64 151.04,24.8 152.23,24.8 152.4,24.97 152.4,25.3 152.23,25.46 151.04,25.46 150.88,25.63 150.88,25.96 151.04,26.12 152.23,26.12 152.4,26.29 152.4,26.62 152.23,26.78 151.04,26.78 150.88,26.95 150.88,27.28 151.04,27.44 152.23,27.44 152.4,27.61 152.4,27.94 152.23,28.1 151.04,28.1 150.88,28.27 150.88,28.6 151.04,28.76 152.23,28.76 152.4,28.93 152.4,29.26 152.23,29.43 151.04,29.43 150.88,29.59 150.88,29.92 151.04,30.09 152.23,30.09 152.4,30.25 152.4,30.58 152.23,30.75 151.04,30.75 150.88,30.91 150.88,31.24 151.04,31.41 152.23,31.41 152.4,31.57 152.4,31.9 152.23,32.07 151.04,32.07 150.88,32.23 150.88,32.56 151.04,32.73 152.23,32.73 152.4,32.89 152.4,35.05 150.24,37.21 150.24,49.4 152.4,51.56 152.4,75.18 145.41,82.17 132.59,82.17 128.78,78.36 128.78,77.34 126.62,75.18 126.62,73.66 125.72,72.76 124.83,72.76 124.83,72.76 121.39,72.76 v2(120.95,73.2)
CMOS_PORT0_9: length 140
  TOP w0.165: U5.E21 v2(120.95,72.2)
  BOTTOM w0.165: 160.66,8.13 159.38,9.4 152.78,9.4 149.1,13.08 149.1,13.73 148.93,13.89 147.23,13.89 147.07,14.06 147.07,14.39 147.23,14.55 148.93,14.55 149.1,14.72 149.1,15.05 148.93,15.21 147.23,15.21 147.07,15.38 147.07,15.71 147.23,15.87 148.93,15.87 149.1,16.04 149.1,16.37 148.93,16.53 147.23,16.53 147.07,16.7 147.07,17.03 147.23,17.19 148.93,17.19 149.1,17.36 149.1,17.69 148.93,17.85 147.23,17.85 147.07,18.02 147.07,18.35 147.23,18.51 148.93,18.51 149.1,18.68 149.1,19.01 148.93,19.17 147.23,19.17 147.07,19.34 147.07,19.67 147.23,19.83 148.93,19.83 149.1,20 149.1,20.33 148.93,20.5 147.23,20.5 147.07,20.66 147.07,20.99 147.23,21.16 148.93,21.16 149.1,21.32 149.1,50.67 150.88,52.45 150.88,75.44 144.78,81.53 132.84,81.53 129.41,78.11 129.41,77.09 127.89,75.56 127.89,71.88 127.25,71.25 126.75,71.25 126.24,70.74 122.68,70.74 122.43,70.99 122.43,71.37 122.17,71.63 121.54,71.63 121.03,72.14 121.01,72.14 v2(120.95,72.2)
CMOS_PORT0_10: length 140
  TOP w0.165: v1(131.57,74.8) 133.48,72.9 133.48,72.26 135.25,70.48 135.89,70.48 155.19,51.18 155.19,49.15 157.86,46.48 157.86,37.73 159.91,35.69 160.66,35.69 161.29,35.05 161.29,34.04 161.8,33.52 161.8,32.9 160.66,31.75 160.66,31.39 160.82,31.22 162.27,31.22 162.43,31.06 162.43,30.73 162.27,30.56 160.82,30.56 160.66,30.4 160.66,30.07 160.82,29.9 162.27,29.9 162.43,29.74 162.43,29.41 162.27,29.24 160.82,29.24 160.66,29.08 160.66,28.75 160.82,28.58 162.27,28.58 162.43,28.41 162.43,28.08 162.27,27.92 160.82,27.92 160.66,27.75 160.66,27.42 160.82,27.26 162.27,27.26 162.43,27.09 162.43,26.76 162.27,26.6 160.82,26.6 160.66,26.43 160.66,26.1 160.82,25.94 162.27,25.94 162.43,25.77 162.43,25.44 162.27,25.28 160.82,25.28 160.66,25.11 160.66,24.78 160.82,24.62 162.27,24.62 162.43,24.45 162.43,24.12 162.27,23.96 160.82,23.96 160.66,23.79 160.66,23.46 160.82,23.3 162.27,23.3 162.43,23.13 162.43,22.8 162.27,22.64 160.82,22.64 160.66,22.47 160.66,22.14 160.82,21.98 162.27,21.98 162.43,21.81 162.43,21.48 162.27,21.32 160.82,21.32 160.66,21.15 160.66,20.82 160.82,20.66 162.27,20.66 162.43,20.49 162.43,20.16 162.27,19.99 160.82,19.99 160.66,19.83 160.66,19.5 160.82,19.33 162.27,19.33 162.43,19.17 162.43,18.84 162.27,18.67 160.82,18.67 160.66,18.51 160.66,18.18 160.82,18.01 162.27,18.01 162.43,17.85 162.43,17.52 162.27,17.35 160.82,17.35 160.66,17.19 160.66,16.86 160.82,16.69 162.27,16.69 162.43,16.53 162.43,16.2 162.27,16.03 160.82,16.03 160.66,15.87 160.66,15.54 160.82,15.37 162.27,15.37 162.43,15.21 162.43,14.88 162.27,14.71 160.82,14.71 160.66,14.55 160.66,14.22 160.82,14.05 162.27,14.05 162.43,13.89 162.43,13.56 162.27,13.39 160.82,13.39 160.66,13.23 160.66,12.9 160.82,12.73 162.27,12.73 162.43,12.57 162.43,12.24 162.27,12.07 161.71,12.07 161.54,11.9 161.54,11.56 158.12,8.13 ; U5.D18 v2(121.95,75.2)
  L10-SIG4 w0.114: v1(131.57,74.8) 131.44,74.93 128.78,74.93 127.38,76.33 123.08,76.33 v2(121.95,75.2)
CMOS_PORT0_11: length 140
  TOP w0.165: U5.D19 v2(121.95,74.2) ; v1(131.57,73.41) 132.72,72.26 132.72,72.01 134.87,69.85 135.51,69.85 154.05,51.31 154.05,46.74 156.59,44.2 156.59,34.54 158.24,32.89 158.24,32.64 157.99,32.38 157.35,32.38 157.23,32.26 157.23,31.82 157.39,31.65 158.84,31.65 159,31.49 159,31.16 158.84,30.99 157.39,30.99 157.23,30.83 157.23,30.5 157.39,30.33 158.84,30.33 159,30.17 159,29.84 158.84,29.67 157.39,29.67 157.23,29.51 157.23,29.18 157.39,29.01 158.84,29.01 159,28.85 159,28.52 158.84,28.35 157.39,28.35 157.23,28.18 157.23,27.85 157.39,27.69 158.84,27.69 159,27.52 159,27.19 158.84,27.03 157.39,27.03 157.23,26.86 157.23,26.53 157.39,26.37 158.84,26.37 159,26.2 159,25.87 158.84,25.71 157.39,25.71 157.23,25.54 157.23,25.21 157.39,25.05 158.84,25.05 159,24.88 159,24.55 158.84,24.39 157.39,24.39 157.23,24.22 157.23,23.89 157.39,23.73 158.84,23.73 159,23.56 159,23.23 158.84,23.07 157.39,23.07 157.23,22.9 157.23,22.57 157.39,22.41 158.84,22.41 159,22.24 159,21.91 158.84,21.75 157.39,21.75 157.23,21.58 157.23,21.25 157.39,21.09 158.84,21.09 159,20.92 159,20.59 158.84,20.43 157.39,20.43 157.23,20.26 157.23,19.93 157.39,19.76 158.84,19.76 159,19.6 159,19.27 158.84,19.1 157.39,19.1 157.23,18.94 157.23,18.61 157.39,18.44 158.84,18.44 159,18.28 159,17.95 158.84,17.78 157.39,17.78 157.23,17.62 157.23,17.29 157.39,17.12 158.84,17.12 159,16.96 159,16.63 158.84,16.46 157.39,16.46 157.23,16.3 157.23,15.97 157.39,15.8 158.84,15.8 159,15.64 159,15.31 158.84,15.14 157.39,15.14 157.23,14.98 157.23,14.65 157.39,14.48 158.84,14.48 159,14.32 159,13.99 158.84,13.82 157.39,13.82 157.23,13.66 157.23,13.33 157.39,13.16 158.84,13.16 159,13 159,12.67 158.84,12.5 157.39,12.5 157.23,12.34 157.23,12.01 157.39,11.84 158.84,11.84 159,11.67 159,11.34 158.67,11.01 157.57,11.01 155.57,9.02 J1.23
  L10-SIG4 w0.114: v2(121.95,74.2) 122.26,74.2 122.73,74.68 125.09,74.68 125.51,74.26 126.03,74.26 126.19,74.42 127.81,74.42 128.35,73.88 128.69,73.88 128.85,74.04 130.94,74.04 v1(131.57,73.41)
CMOS_PORT0_12: length 140
  TOP w0.165: J1.25 153.03,9.14 154.93,11.04 155.92,11.04 156.08,11.21 156.08,11.54 155.92,11.7 154.47,11.7 154.31,11.87 154.31,12.2 154.47,12.36 155.92,12.36 156.08,12.53 156.08,12.86 155.92,13.02 154.47,13.02 154.31,13.19 154.31,13.52 154.47,13.68 155.92,13.68 156.08,13.85 156.08,14.18 155.92,14.34 154.47,14.34 154.31,14.51 154.31,14.84 154.47,15 155.92,15 156.08,15.17 156.08,15.5 155.92,15.66 154.47,15.66 154.31,15.83 154.31,16.16 154.47,16.32 155.92,16.32 156.08,16.49 156.08,16.82 155.92,16.98 154.47,16.98 154.31,17.15 154.31,17.48 154.47,17.65 155.92,17.65 156.08,17.81 156.08,18.14 155.92,18.31 154.47,18.31 154.31,18.47 154.31,18.8 154.47,18.97 155.92,18.97 156.08,19.13 156.08,19.46 155.92,19.63 154.47,19.63 154.31,19.79 154.31,20.12 154.47,20.29 155.92,20.29 156.08,20.45 156.08,20.78 155.92,20.95 154.47,20.95 154.31,21.11 154.31,21.44 154.47,21.61 155.92,21.61 156.08,21.77 156.08,22.1 155.92,22.27 154.47,22.27 154.31,22.43 154.31,22.76 154.47,22.93 155.92,22.93 156.08,23.09 156.08,23.42 155.92,23.59 154.47,23.59 154.31,23.75 154.31,24.08 154.47,24.25 155.92,24.25 156.08,24.41 156.08,24.74 155.92,24.91 154.47,24.91 154.31,25.07 154.31,25.4 154.47,25.57 155.92,25.57 156.08,25.74 156.08,26.07 155.92,26.23 154.47,26.23 154.31,26.4 154.31,26.73 154.47,26.89 155.92,26.89 156.08,27.06 156.08,27.39 155.92,27.55 154.47,27.55 154.31,27.72 154.31,28.05 154.47,28.21 155.92,28.21 156.08,28.38 156.08,28.71 155.92,28.87 154.47,28.87 154.31,29.04 154.31,29.37 154.47,29.53 155.92,29.53 156.08,29.7 156.08,30.03 155.92,30.19 154.47,30.19 154.31,30.36 154.31,30.69 154.47,30.85 155.92,30.85 156.08,31.02 156.08,31.37 155.96,31.5 154.43,31.5 154.31,31.62 154.31,32 154.43,32.13 155.96,32.13 156.08,32.26 156.08,32.64 155.96,32.77 154.56,32.77 154.43,32.89 154.43,33.27 154.69,33.53 154.94,33.53 155.07,33.66 155.07,43.31 152.15,46.23 152.15,52.2 135.25,69.09 134.11,69.09 133.6,69.6 133.6,70.23 v1(131.57,72.26) ; U5.D20 v2(121.95,73.2)
  L10-SIG4 w0.114: v1(131.57,72.26) 130.81,73.03 127.46,73.03 127.19,72.76 122.39,72.76 v2(121.95,73.2)
CMOS_PORT0_13: length 140.1
  TOP w0.165: U5.D21 v2(121.95,72.2) ; v1(131.57,70.99) 131.83,70.99 133.1,69.72 133.1,69.34 133.99,68.45 135,68.45 150.24,53.21 150.24,37.47 151.76,35.94 151.76,34.67 151.38,34.29 151.38,34.01 151.51,33.88 152.74,33.88 152.91,33.72 152.91,33.39 152.74,33.22 151.3,33.22 151.13,33.06 151.13,32.73 151.3,32.56 152.74,32.56 152.91,32.4 152.91,32.07 152.74,31.9 151.3,31.9 151.13,31.74 151.13,31.41 151.3,31.24 152.74,31.24 152.91,31.08 152.91,30.75 152.74,30.58 151.3,30.58 151.13,30.42 151.13,30.09 151.3,29.92 152.74,29.92 152.91,29.76 152.91,29.43 152.74,29.26 151.3,29.26 151.13,29.1 151.13,28.77 151.3,28.6 152.74,28.6 152.91,28.44 152.91,28.11 152.74,27.94 151.3,27.94 151.13,27.78 151.13,27.45 151.3,27.28 152.74,27.28 152.91,27.12 152.91,26.79 152.74,26.62 151.3,26.62 151.13,26.45 151.13,26.12 151.3,25.96 152.74,25.96 152.91,25.79 152.91,25.46 152.74,25.3 151.3,25.3 151.13,25.13 151.13,24.8 151.3,24.64 152.74,24.64 152.91,24.47 152.91,24.14 152.74,23.98 151.3,23.98 151.13,23.81 151.13,23.48 151.3,23.32 152.74,23.32 152.91,23.15 152.91,22.82 152.74,22.66 151.3,22.66 151.13,22.49 151.13,22.16 151.3,22 152.74,22 152.91,21.83 152.91,21.5 152.74,21.34 151.3,21.34 151.13,21.17 151.13,20.84 151.3,20.68 152.74,20.68 152.91,20.51 152.91,20.18 152.74,20.02 151.3,20.02 151.13,19.85 151.13,19.52 151.3,19.36 152.74,19.36 152.91,19.19 152.91,18.86 152.74,18.7 151.3,18.7 151.13,18.53 151.13,18.2 151.3,18.03 152.74,18.03 152.91,17.87 152.91,17.54 152.74,17.37 151.3,17.37 151.13,17.21 151.13,16.88 151.3,16.71 152.74,16.71 152.91,16.55 152.91,16.22 152.74,16.05 151.3,16.05 151.13,15.89 151.13,15.56 151.3,15.39 152.74,15.39 152.91,15.23 152.91,14.9 152.74,14.73 151.3,14.73 151.13,14.57 151.13,14.24 151.3,14.07 152.74,14.07 152.91,13.91 152.91,13.58 152.74,13.41 151.3,13.41 151.13,13.25 151.13,12.92 151.3,12.75 152.74,12.75 152.91,12.59 152.91,12.26 152.74,12.09 151.3,12.09 151.13,11.93 151.13,11.6 151.3,11.43 152.74,11.43 152.91,11.27 152.91,10.94 152.74,10.77 151.99,10.77 150.5,9.27 150.5,8.13
  L10-SIG4 w0.102: 125.51,72.29 124.97,71.75 122.4,71.75 v2(121.95,72.2)
  L10-SIG4 w0.114: v1(131.57,70.99) 130.27,72.29 125.51,72.29
CMOS_PORT0_14: length 140
  TOP w0.165: U5.C18 122.95,76.2 125.6,76.2 128.78,73.03 129.41,73.03 130.91,71.53 130.91,70.89 133.99,67.82 134.87,67.82 148.34,54.36 148.34,44.07 148.59,43.81 148.59,43.43 148.34,43.18 148.34,35.99 149.48,34.85 149.48,34.67 149.16,34.35 147.87,34.35 147.7,34.19 147.7,33.86 147.87,33.69 149.31,33.69 149.48,33.53 149.48,33.2 149.31,33.03 147.87,33.03 147.7,32.87 147.7,32.54 147.87,32.37 149.31,32.37 149.48,32.21 149.48,31.88 149.31,31.71 147.87,31.71 147.7,31.55 147.7,31.22 147.87,31.05 149.31,31.05 149.48,30.89 149.48,30.55 149.31,30.39 147.87,30.39 147.7,30.22 147.7,29.89 147.87,29.73 149.31,29.73 149.48,29.56 149.48,29.23 149.31,29.07 147.87,29.07 147.7,28.9 147.7,28.57 147.87,28.41 149.31,28.41 149.48,28.24 149.48,27.91 149.31,27.75 147.87,27.75 147.7,27.58 147.7,27.25 147.87,27.09 149.31,27.09 149.48,26.92 149.48,26.59 149.31,26.43 147.87,26.43 147.7,26.26 147.7,25.93 147.87,25.77 149.31,25.77 149.48,25.6 149.48,25.27 149.31,25.11 147.87,25.11 147.7,24.94 147.7,24.61 147.87,24.45 149.31,24.45 149.48,24.28 149.48,23.95 149.31,23.79 147.87,23.79 147.7,23.62 147.7,23.29 147.87,23.13 149.31,23.13 149.48,22.96 149.48,22.63 149.31,22.46 147.87,22.46 147.7,22.3 147.7,21.97 147.87,21.8 149.31,21.8 149.48,21.64 149.48,21.31 149.31,21.14 147.87,21.14 147.7,20.98 147.7,20.65 147.87,20.48 149.31,20.48 149.48,20.32 149.48,19.99 149.31,19.82 147.87,19.82 147.7,19.66 147.7,19.33 147.87,19.16 149.31,19.16 149.48,19 149.48,18.67 149.31,18.5 147.87,18.5 147.7,18.34 147.7,18.01 147.87,17.84 149.31,17.84 149.48,17.68 149.48,17.35 149.31,17.18 147.87,17.18 147.7,17.02 147.7,16.69 147.87,16.52 149.31,16.52 149.48,16.36 149.48,16.03 149.31,15.86 147.87,15.86 147.7,15.7 147.7,15.37 147.87,15.2 149.31,15.2 149.48,15.04 149.48,14.71 149.31,14.54 147.87,14.54 147.7,14.38 147.7,14.04 147.87,13.88 149.31,13.88 149.48,13.71 149.48,13.38 149.31,13.22 147.87,13.22 147.7,13.05 147.7,12.72 147.87,12.56 149.31,12.56 149.48,12.39 149.48,12.06 149.31,11.9 147.87,11.9 147.7,11.73 147.7,11.4 147.87,11.24 149.31,11.24 149.48,11.07 149.48,10.74 147.96,9.22 147.96,8.13
CMOS_PORT0_15: length 140
  TOP w0.165: J1.31 145.41,10.02 146.3,10.91 146.3,11.28 146.18,11.41 144.95,11.41 144.78,11.57 144.78,11.9 144.95,12.07 146.14,12.07 146.3,12.23 146.3,12.56 146.14,12.73 144.95,12.73 144.78,12.89 144.78,13.22 144.95,13.39 146.14,13.39 146.3,13.55 146.3,13.88 146.14,14.05 144.95,14.05 144.78,14.21 144.78,14.54 144.95,14.71 146.14,14.71 146.3,14.87 146.3,15.2 146.14,15.37 144.95,15.37 144.78,15.53 144.78,15.86 144.95,16.03 146.14,16.03 146.3,16.19 146.3,16.52 146.14,16.69 144.95,16.69 144.78,16.85 144.78,17.19 144.95,17.35 146.14,17.35 146.3,17.52 146.3,17.85 146.14,18.01 144.95,18.01 144.78,18.18 144.78,18.51 144.95,18.67 146.14,18.67 146.3,18.84 146.3,19.17 146.14,19.33 144.95,19.33 144.78,19.5 144.78,19.83 144.95,19.99 146.14,19.99 146.3,20.16 146.3,20.49 146.14,20.65 144.95,20.65 144.78,20.82 144.78,21.15 144.95,21.31 146.14,21.31 146.3,21.48 146.3,21.81 146.14,21.97 144.95,21.97 144.78,22.14 144.78,22.47 144.95,22.63 146.14,22.63 146.3,22.8 146.3,23.13 146.14,23.29 144.95,23.29 144.78,23.46 144.78,23.79 144.95,23.95 146.14,23.95 146.3,24.12 146.3,24.45 146.14,24.61 144.95,24.61 144.78,24.78 144.78,25.11 144.95,25.28 146.14,25.28 146.3,25.44 146.3,25.77 146.14,25.94 144.95,25.94 144.78,26.1 144.78,26.43 144.95,26.6 146.14,26.6 146.3,26.76 146.3,27.09 146.14,27.26 144.95,27.26 144.78,27.42 144.78,27.75 144.95,27.92 146.14,27.92 146.3,28.08 146.3,28.41 146.14,28.58 144.95,28.58 144.78,28.74 144.78,29.07 144.95,29.24 146.14,29.24 146.3,29.4 146.3,29.73 146.14,29.9 144.95,29.9 144.78,30.06 144.78,30.39 144.95,30.56 146.14,30.56 146.3,30.72 146.3,31.05 146.14,31.22 144.95,31.22 144.78,31.38 144.78,31.71 144.95,31.88 146.14,31.88 146.3,32.04 146.3,32.37 146.14,32.54 144.95,32.54 144.78,32.7 144.78,33.03 144.95,33.2 146.14,33.2 146.3,33.36 146.3,33.7 146.14,33.86 144.95,33.86 144.78,34.03 144.78,34.36 144.95,34.52 146.14,34.52 146.3,34.69 146.3,35.02 146.14,35.18 144.95,35.18 144.78,35.35 144.78,35.68 145.38,36.27 145.38,42.18 146.05,42.85 146.05,43.18 145.88,43.35 145.2,43.35 145.03,43.51 145.03,43.84 145.2,44.01 145.88,44.01 146.05,44.17 146.05,44.5 145.88,44.67 145.2,44.67 145.03,44.83 145.03,45.16 145.2,45.33 145.88,45.33 146.05,45.49 146.05,45.82 145.88,45.99 145.2,45.99 145.03,46.15 145.03,46.48 145.2,46.65 145.88,46.65 146.05,46.81 146.05,47.14 145.88,47.31 145.2,47.31 145.03,47.47 145.03,47.8 145.2,47.97 145.88,47.97 146.05,48.13 146.05,48.46 145.88,48.63 145.2,48.63 145.03,48.79 145.03,49.12 145.2,49.29 145.88,49.29 146.05,49.46 146.05,49.79 145.88,49.95 145.2,49.95 145.03,50.12 145.03,50.45 145.2,50.61 145.73,50.61 146.02,50.9 146.02,51.17 145.54,51.65 145.54,56.01 136.14,65.41 135.76,65.41 129.98,71.19 129.98,71.68 129.72,71.94 129.71,71.94 129.16,72.49 128.44,72.49 128.08,72.85 126.92,72.85 125.86,73.91 v1(125.86,74.68) ; U5.C19 v2(122.94,74.21)
  BOTTOM w0.165: v2(122.94,74.21) 123.41,74.68 v1(125.86,74.68)
CMOS_PORT0_16: length 140
  TOP w0.165: v1(125.25,73.2) 126.03,72.42 127.99,72.42 135.89,64.52 136.27,64.52 143,57.78 143,53.72 143.26,53.47 143.26,53.09 143.13,52.96 142.62,52.96 142.49,52.83 142.49,52.43 142.66,52.27 143.34,52.27 143.51,52.1 143.51,51.77 143.34,51.61 142.66,51.61 142.49,51.44 142.49,51.11 142.66,50.95 143.34,50.95 143.51,50.78 143.51,50.45 143.34,50.29 142.66,50.29 142.49,50.12 142.49,49.79 142.66,49.63 143.34,49.63 143.51,49.46 143.51,49.13 143.34,48.97 142.66,48.97 142.49,48.8 142.49,48.47 142.66,48.3 143.34,48.3 143.51,48.14 143.51,47.81 143.34,47.64 142.66,47.64 142.49,47.48 142.49,47.15 142.66,46.98 143.34,46.98 143.51,46.82 143.51,46.49 143.34,46.32 142.66,46.32 142.49,46.16 142.49,45.83 142.66,45.66 143.34,45.66 143.51,45.5 143.51,45.17 143.34,45 142.66,45 142.49,44.84 142.49,44.51 142.66,44.34 143.34,44.34 143.51,44.18 143.51,43.85 143.34,43.68 142.66,43.68 142.49,43.52 142.49,43.19 142.66,43.02 143.34,43.02 143.51,42.86 143.51,42.53 142.84,41.85 142.84,36.2 142.49,35.86 142.49,35.31 142.69,35.11 143.6,35.11 143.76,34.94 143.76,34.61 143.6,34.45 142.41,34.45 142.24,34.28 142.24,33.95 142.41,33.79 143.6,33.79 143.76,33.62 143.76,33.29 143.6,33.13 142.41,33.13 142.24,32.96 142.24,32.63 142.41,32.47 143.6,32.47 143.76,32.3 143.76,31.97 143.6,31.81 142.41,31.81 142.24,31.64 142.24,31.31 142.41,31.15 143.6,31.15 143.76,30.98 143.76,30.65 143.6,30.49 142.41,30.49 142.24,30.32 142.24,29.99 142.41,29.83 143.6,29.83 143.76,29.66 143.76,29.33 143.6,29.17 142.41,29.17 142.24,29 142.24,28.67 142.41,28.5 143.6,28.5 143.76,28.34 143.76,28.01 143.6,27.84 142.41,27.84 142.24,27.68 142.24,27.35 142.41,27.18 143.6,27.18 143.76,27.02 143.76,26.69 143.6,26.52 142.41,26.52 142.24,26.36 142.24,26.03 142.41,25.86 143.6,25.86 143.76,25.7 143.76,25.37 143.6,25.2 142.41,25.2 142.24,25.04 142.24,24.71 142.41,24.54 143.6,24.54 143.76,24.38 143.76,24.05 143.6,23.88 142.41,23.88 142.24,23.72 142.24,23.39 142.41,23.22 143.6,23.22 143.76,23.06 143.76,22.73 143.6,22.56 142.41,22.56 142.24,22.4 142.24,22.07 142.41,21.9 143.6,21.9 143.76,21.74 143.76,21.41 143.6,21.24 142.41,21.24 142.24,21.08 142.24,20.75 142.41,20.58 143.6,20.58 143.76,20.41 143.76,20.08 143.6,19.92 142.41,19.92 142.24,19.75 142.24,19.42 142.41,19.26 143.6,19.26 143.76,19.09 143.76,18.76 143.6,18.6 142.41,18.6 142.24,18.43 142.24,18.1 142.41,17.94 143.6,17.94 143.76,17.77 143.76,17.44 143.6,17.28 142.41,17.28 142.24,17.11 142.24,16.78 142.41,16.62 143.6,16.62 143.76,16.45 143.76,16.12 143.6,15.96 142.41,15.96 142.24,15.79 142.24,15.46 142.41,15.3 143.6,15.3 143.76,15.13 143.76,14.8 143.6,14.64 142.41,14.64 142.24,14.47 142.24,14.14 142.41,13.98 143.6,13.98 143.76,13.81 143.76,13.48 143.6,13.32 142.41,13.32 142.24,13.15 142.24,12.82 142.41,12.66 143.6,12.66 143.76,12.49 143.76,12.16 143.6,11.99 142.41,11.99 142.24,11.83 142.24,11.5 142.41,11.33 143.6,11.33 143.76,11.17 143.76,10.84 143,10.08 143,8.26 J1.33 ; U5.C20 v2(122.95,73.2)
  L3-SIG1 w0.102: v2(122.95,73.2) 123.41,73.66 124.71,73.66 125.17,73.2 v1(125.25,73.2)
CMOS_PORT0_17: length 140
  TOP w0.165: U5.C21 v2(122.95,72.2) ; 140.34,8.13 140.34,10.22 141.1,10.98 141.1,11.31 140.93,11.48 139.74,11.48 139.57,11.64 139.57,11.97 139.74,12.14 140.93,12.14 141.1,12.3 141.1,12.63 140.93,12.8 139.74,12.8 139.57,12.96 139.57,13.29 139.74,13.46 140.93,13.46 141.1,13.63 141.1,13.96 140.93,14.12 139.74,14.12 139.57,14.29 139.57,14.62 139.74,14.78 140.93,14.78 141.1,14.95 141.1,15.28 140.93,15.44 139.74,15.44 139.57,15.61 139.57,15.94 139.74,16.1 140.93,16.1 141.1,16.27 141.1,16.6 140.93,16.76 139.74,16.76 139.57,16.93 139.57,17.26 139.74,17.42 140.93,17.42 141.1,17.59 141.1,17.92 140.93,18.08 139.74,18.08 139.57,18.25 139.57,18.58 139.74,18.74 140.93,18.74 141.1,18.91 141.1,19.24 140.93,19.4 139.74,19.4 139.57,19.57 139.57,19.9 139.74,20.06 140.93,20.06 141.1,20.23 141.1,20.56 140.93,20.72 139.74,20.72 139.57,20.89 139.57,21.22 139.74,21.38 140.93,21.38 141.1,21.55 141.1,21.88 140.93,22.05 139.74,22.05 139.57,22.21 139.57,22.54 139.74,22.71 140.93,22.71 141.1,22.87 141.1,23.2 140.93,23.37 139.74,23.37 139.57,23.53 139.57,23.86 139.74,24.03 140.93,24.03 141.1,24.19 141.1,24.52 140.93,24.69 139.74,24.69 139.57,24.85 139.57,25.18 139.74,25.35 140.93,25.35 141.1,25.51 141.1,25.84 140.93,26.01 139.74,26.01 139.57,26.17 139.57,26.5 139.74,26.67 140.93,26.67 141.1,26.83 141.1,27.16 140.93,27.33 139.74,27.33 139.57,27.49 139.57,27.82 139.74,27.99 140.93,27.99 141.1,28.15 141.1,28.48 140.93,28.65 139.74,28.65 139.57,28.81 139.57,29.14 139.74,29.31 140.93,29.31 141.1,29.47 141.1,29.8 140.93,29.97 139.74,29.97 139.57,30.14 139.57,30.47 139.74,30.63 140.93,30.63 141.1,30.8 141.1,31.13 140.93,31.29 139.74,31.29 139.57,31.46 139.57,31.79 139.74,31.95 140.93,31.95 141.1,32.12 141.1,32.45 140.93,32.61 139.74,32.61 139.57,32.78 139.57,33.11 139.74,33.27 140.93,33.27 141.1,33.44 141.1,33.77 140.93,33.93 139.74,33.93 139.57,34.1 139.57,34.43 139.74,34.59 140.93,34.59 141.1,34.76 141.1,35.09 140.93,35.25 139.74,35.25 139.57,35.42 139.57,35.75 140.34,36.51 140.34,42.13 140.77,42.56 140.77,42.95 140.59,43.13 139.99,43.13 139.83,43.29 139.83,43.63 139.99,43.79 140.68,43.79 140.84,43.96 140.84,44.29 140.68,44.45 139.99,44.45 139.83,44.62 139.83,44.95 139.99,45.11 140.68,45.11 140.84,45.28 140.84,45.61 140.68,45.77 139.99,45.77 139.83,45.94 139.83,46.27 139.99,46.43 140.68,46.43 140.84,46.6 140.84,46.93 140.68,47.09 139.99,47.09 139.83,47.26 139.83,47.59 139.99,47.75 140.68,47.75 140.84,47.92 140.84,48.25 140.68,48.41 139.99,48.41 139.83,48.58 139.83,48.91 139.99,49.07 140.68,49.07 140.84,49.24 140.84,49.57 140.68,49.73 139.99,49.73 139.83,49.9 139.83,50.23 139.99,50.39 140.68,50.39 140.84,50.56 140.84,50.89 140.68,51.05 139.99,51.05 139.83,51.22 139.83,51.55 139.99,51.72 140.68,51.72 140.84,51.88 140.84,52.21 140.68,52.38 139.99,52.38 139.83,52.54 139.83,52.87 139.99,53.04 140.68,53.04 140.84,53.2 140.84,53.53 140.68,53.7 139.99,53.7 139.83,53.86 139.83,54.19 139.99,54.36 140.46,54.36 140.72,54.61 140.72,54.99 140.46,55.24 140.31,55.24 139.95,55.6 139.95,59.94 130.15,69.75 129.26,69.75 v1(127.13,71.88)
  BOTTOM w0.165: v2(122.95,72.2) 123.52,71.63 124.04,71.63 124.05,71.61 125.63,71.61 125.8,71.44 126.31,71.44 126.75,71.88 v1(127.13,71.88)
CMOS_PORT0_18: length 140
  TOP w0.165: J1.37 137.79,10.32 138.43,10.96 138.43,11.29 138.26,11.45 137.33,11.45 137.16,11.62 137.16,11.95 137.33,12.12 138.26,12.12 138.43,12.28 138.43,12.61 138.26,12.78 137.33,12.78 137.16,12.94 137.16,13.27 137.33,13.44 138.26,13.44 138.43,13.6 138.43,13.93 138.26,14.1 137.33,14.1 137.16,14.26 137.16,14.59 137.33,14.76 138.26,14.76 138.43,14.92 138.43,15.25 138.26,15.42 137.33,15.42 137.16,15.58 137.16,15.91 137.33,16.08 138.26,16.08 138.43,16.24 138.43,16.57 138.26,16.74 137.33,16.74 137.16,16.9 137.16,17.23 137.33,17.4 138.26,17.4 138.43,17.56 138.43,17.89 138.26,18.06 137.33,18.06 137.16,18.22 137.16,18.55 137.33,18.72 138.26,18.72 138.43,18.88 138.43,19.21 138.26,19.38 137.33,19.38 137.16,19.54 137.16,19.87 137.33,20.04 138.26,20.04 138.43,20.21 138.43,20.54 138.26,20.7 137.33,20.7 137.16,20.87 137.16,21.2 137.33,21.36 138.26,21.36 138.43,21.53 138.43,21.86 138.26,22.02 137.33,22.02 137.16,22.19 137.16,22.52 137.33,22.68 138.26,22.68 138.43,22.85 138.43,23.18 138.26,23.34 137.33,23.34 137.16,23.51 137.16,23.84 137.33,24 138.26,24 138.43,24.17 138.43,24.5 138.26,24.66 137.33,24.66 137.16,24.83 137.16,25.16 137.33,25.32 138.26,25.32 138.43,25.49 138.43,25.82 138.26,25.98 137.33,25.98 137.16,26.15 137.16,26.48 137.33,26.64 138.26,26.64 138.43,26.81 138.43,27.14 138.26,27.3 137.33,27.3 137.16,27.47 137.16,27.8 137.33,27.96 138.26,27.96 138.43,28.13 138.43,28.46 138.26,28.63 137.33,28.63 137.16,28.79 137.16,29.12 137.33,29.29 138.26,29.29 138.43,29.45 138.43,29.78 138.26,29.95 137.33,29.95 137.16,30.11 137.16,30.44 137.33,30.61 138.26,30.61 138.43,30.77 138.43,31.1 138.26,31.27 137.33,31.27 137.16,31.43 137.16,31.76 137.33,31.93 138.26,31.93 138.43,32.09 138.43,32.42 138.26,32.59 137.33,32.59 137.16,32.75 137.16,33.08 137.33,33.25 138.26,33.25 138.43,33.41 138.43,33.74 138.26,33.91 137.33,33.91 137.16,34.07 137.16,34.4 137.33,34.57 138.26,34.57 138.43,34.73 138.43,35.06 138.26,35.23 137.33,35.23 137.16,35.39 137.16,35.72 137.79,36.36 137.79,41.85 138.56,42.61 138.56,42.94 138.39,43.11 137.2,43.11 137.03,43.27 137.03,43.6 137.2,43.77 138.39,43.77 138.56,43.93 138.56,44.26 138.39,44.43 137.2,44.43 137.03,44.59 137.03,44.92 137.2,45.09 138.39,45.09 138.56,45.25 138.56,45.58 138.39,45.75 137.2,45.75 137.03,45.91 137.03,46.24 137.2,46.41 138.39,46.41 138.56,46.57 138.56,46.9 138.39,47.07 137.2,47.07 137.03,47.23 137.03,47.56 137.2,47.73 138.39,47.73 138.56,47.89 138.56,48.22 138.39,48.39 137.2,48.39 137.03,48.55 137.03,48.88 137.2,49.05 138.39,49.05 138.56,49.21 138.56,49.54 138.39,49.71 137.2,49.71 137.03,49.87 137.03,50.21 137.2,50.37 138.39,50.37 138.56,50.54 138.56,50.87 138.39,51.03 137.2,51.03 137.03,51.2 137.03,51.53 137.2,51.69 138.39,51.69 138.56,51.86 138.56,52.19 138.39,52.35 137.2,52.35 137.03,52.52 137.03,52.85 137.2,53.01 138.39,53.01 138.56,53.18 138.56,53.51 138.39,53.67 137.2,53.67 137.03,53.84 137.03,54.17 137.2,54.33 138.39,54.33 138.56,54.5 138.56,54.83 138.39,54.99 137.2,54.99 137.03,55.16 137.03,55.49 137.2,55.65 137.44,55.65 138.3,56.52 138.3,60.83 135.13,64.01 135.13,64.26 133.48,65.91 132.84,65.91 131.83,66.93 130.3,66.93 127.64,69.6 127.03,69.6 126.26,70.36 126.26,71.6 v1(125.98,71.88) ; U5.B21 v2(123.95,72.2)
  BOTTOM w0.165: v2(123.95,72.2) 125.67,72.2 v1(125.98,71.88)
CMOS_PORT0_19: length 140
  TOP w0.165: U5.A21 124.45,72.7 125.5,71.65 125.5,70.13 126.67,68.96 127.38,68.96 129.92,66.42 131.57,66.42 132.72,65.28 133.48,65.28 134.62,64.14 134.62,63.75 136.14,62.23 136.14,52.7 131.83,48.39 131.83,36.96 133.1,35.69 135.36,35.69 135.76,35.28 135.76,34.95 135.6,34.79 133.9,34.79 133.73,34.62 133.73,34.29 133.9,34.13 135.6,34.13 135.76,33.96 135.76,33.63 135.6,33.46 133.9,33.46 133.73,33.3 133.73,32.97 133.9,32.8 135.6,32.8 135.76,32.64 135.76,32.31 135.6,32.14 133.9,32.14 133.73,31.98 133.73,31.65 133.9,31.48 135.6,31.48 135.76,31.32 135.76,30.99 135.6,30.82 133.9,30.82 133.73,30.66 133.73,30.33 133.9,30.16 135.6,30.16 135.76,30 135.76,29.67 135.6,29.5 133.9,29.5 133.73,29.34 133.73,29.01 133.9,28.84 135.6,28.84 135.76,28.68 135.76,28.35 135.6,28.18 133.9,28.18 133.73,28.02 133.73,27.69 133.9,27.52 135.6,27.52 135.76,27.36 135.76,27.03 135.6,26.86 133.9,26.86 133.73,26.7 133.73,26.37 133.9,26.2 135.6,26.2 135.76,26.04 135.76,25.7 135.6,25.54 133.9,25.54 133.73,25.37 133.73,25.04 133.9,24.88 135.6,24.88 135.76,24.71 135.76,24.38 135.6,24.22 133.9,24.22 133.73,24.05 133.73,23.72 133.9,23.56 135.6,23.56 135.76,23.39 135.76,23.06 135.6,22.9 133.9,22.9 133.73,22.73 133.73,22.4 133.9,22.24 135.6,22.24 135.76,22.07 135.76,21.74 135.6,21.58 133.9,21.58 133.73,21.41 133.73,21.08 133.9,20.92 135.6,20.92 135.76,20.75 135.76,20.42 135.6,20.26 133.9,20.26 133.73,20.09 133.73,19.76 133.9,19.6 135.6,19.6 135.76,19.43 135.76,19.1 135.6,18.94 133.9,18.94 133.73,18.77 133.73,18.44 133.9,18.28 135.6,18.28 135.76,18.11 135.76,17.78 135.6,17.62 133.9,17.62 133.73,17.45 133.73,17.12 133.9,16.95 135.6,16.95 135.76,16.79 135.76,16.46 135.6,16.29 133.9,16.29 133.73,16.13 133.73,15.8 133.9,15.63 135.6,15.63 135.76,15.47 135.76,15.14 135.6,14.97 133.9,14.97 133.73,14.81 133.73,14.48 133.9,14.31 135.6,14.31 135.76,14.15 135.76,13.82 135.6,13.65 133.9,13.65 133.73,13.49 133.73,13.16 133.9,12.99 135.6,12.99 135.76,12.83 135.76,12.5 135.2,11.94 134.49,11.94 134.24,11.68 134.24,11.05 135.25,10.03 J1.39
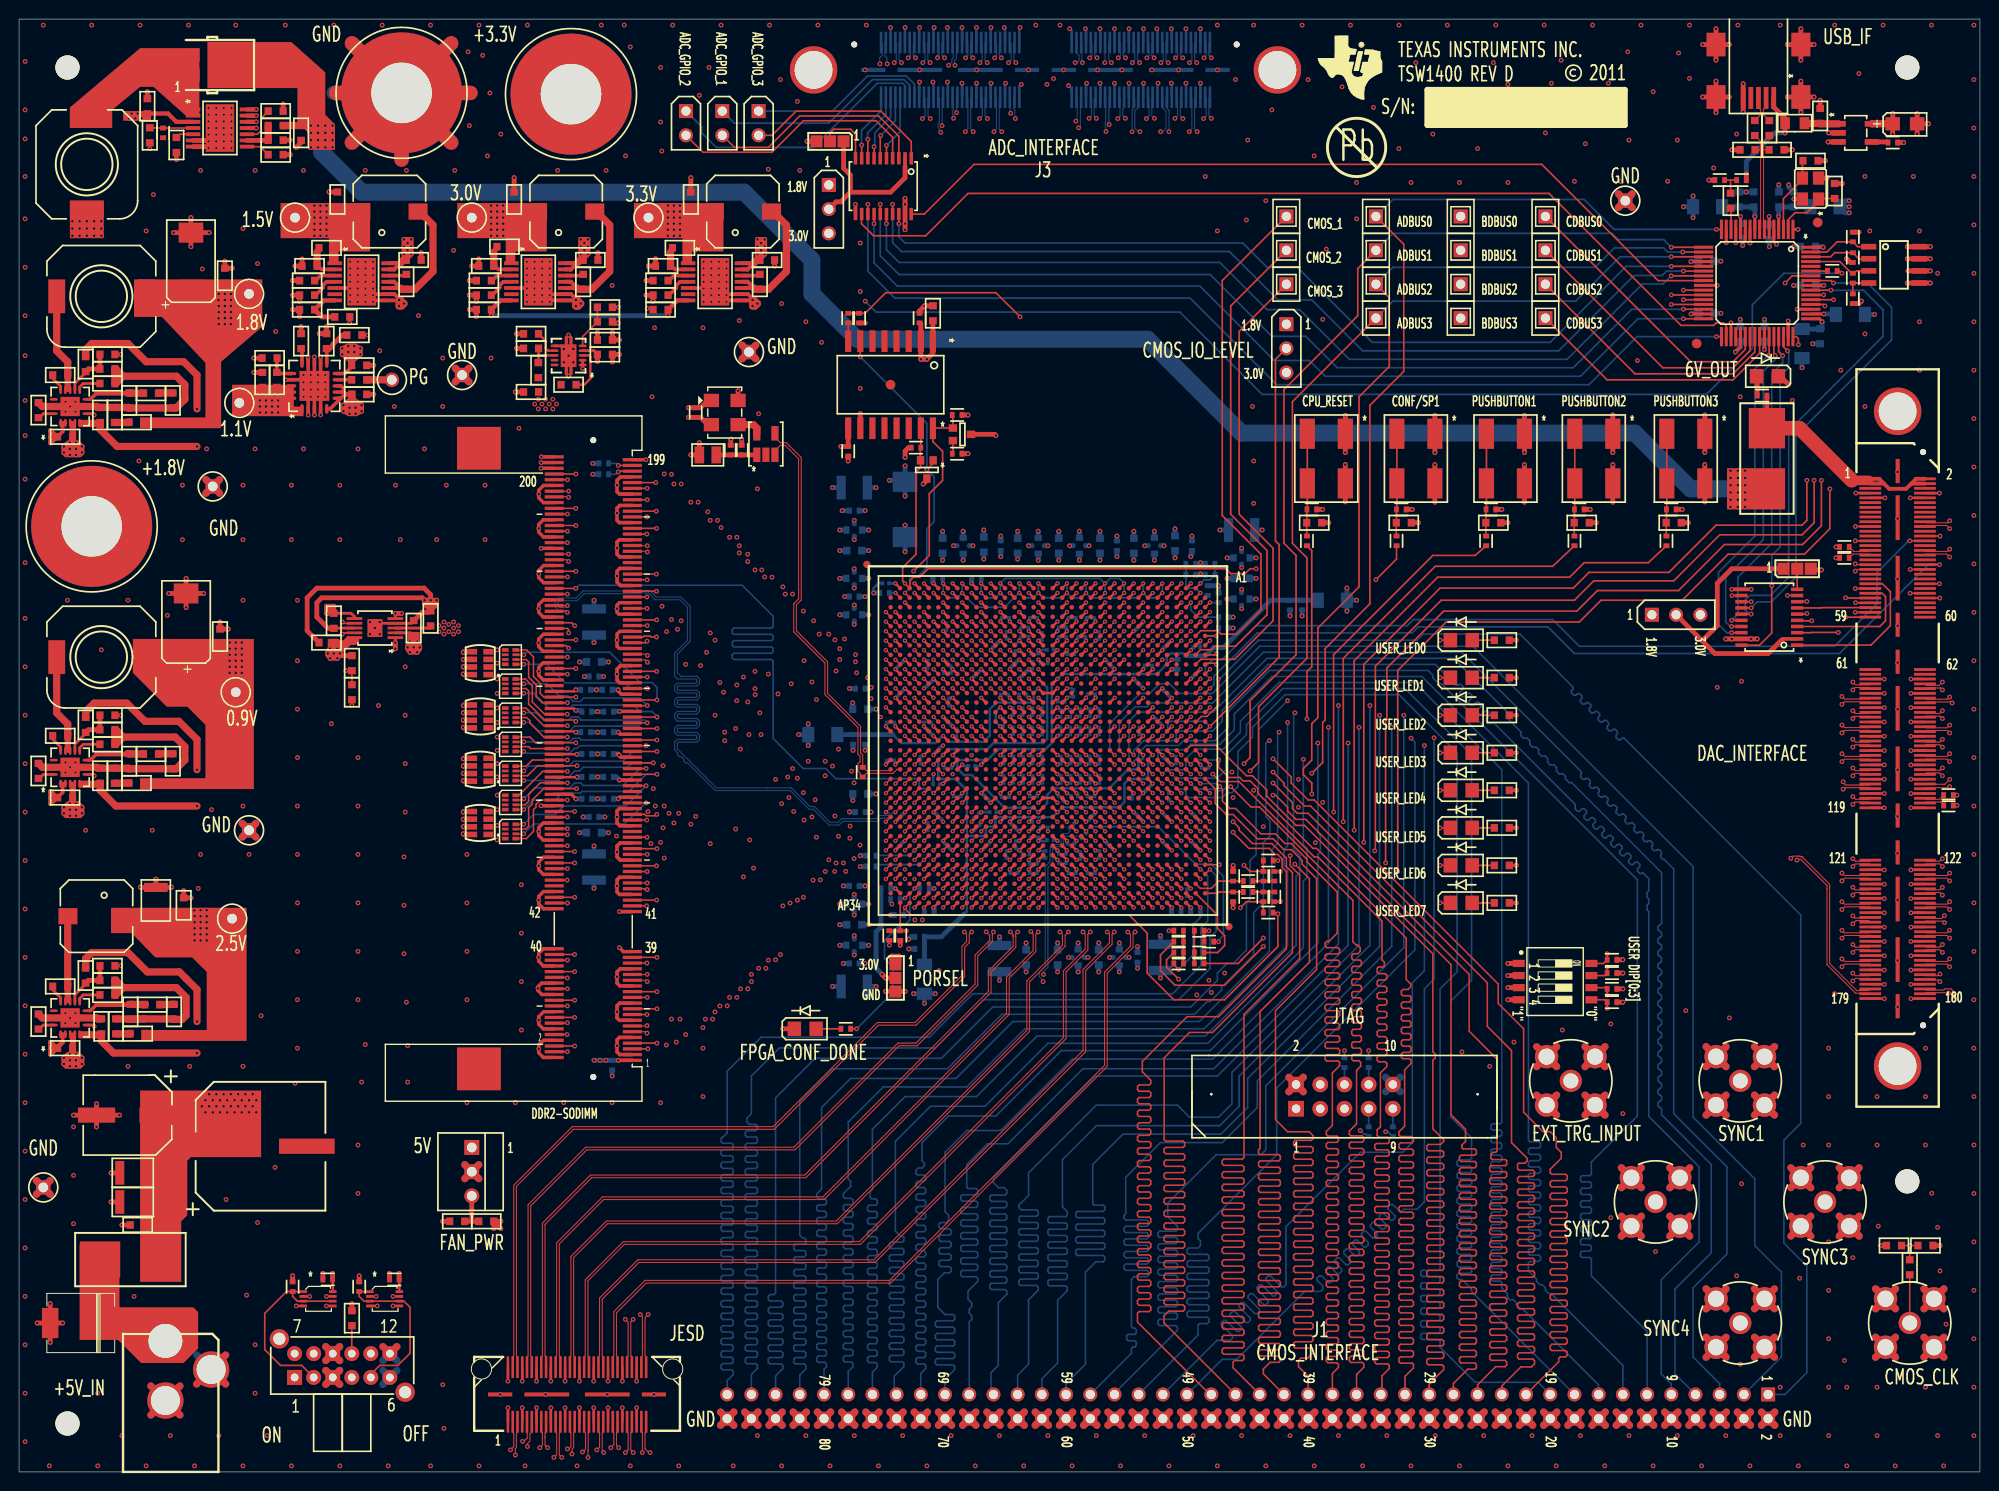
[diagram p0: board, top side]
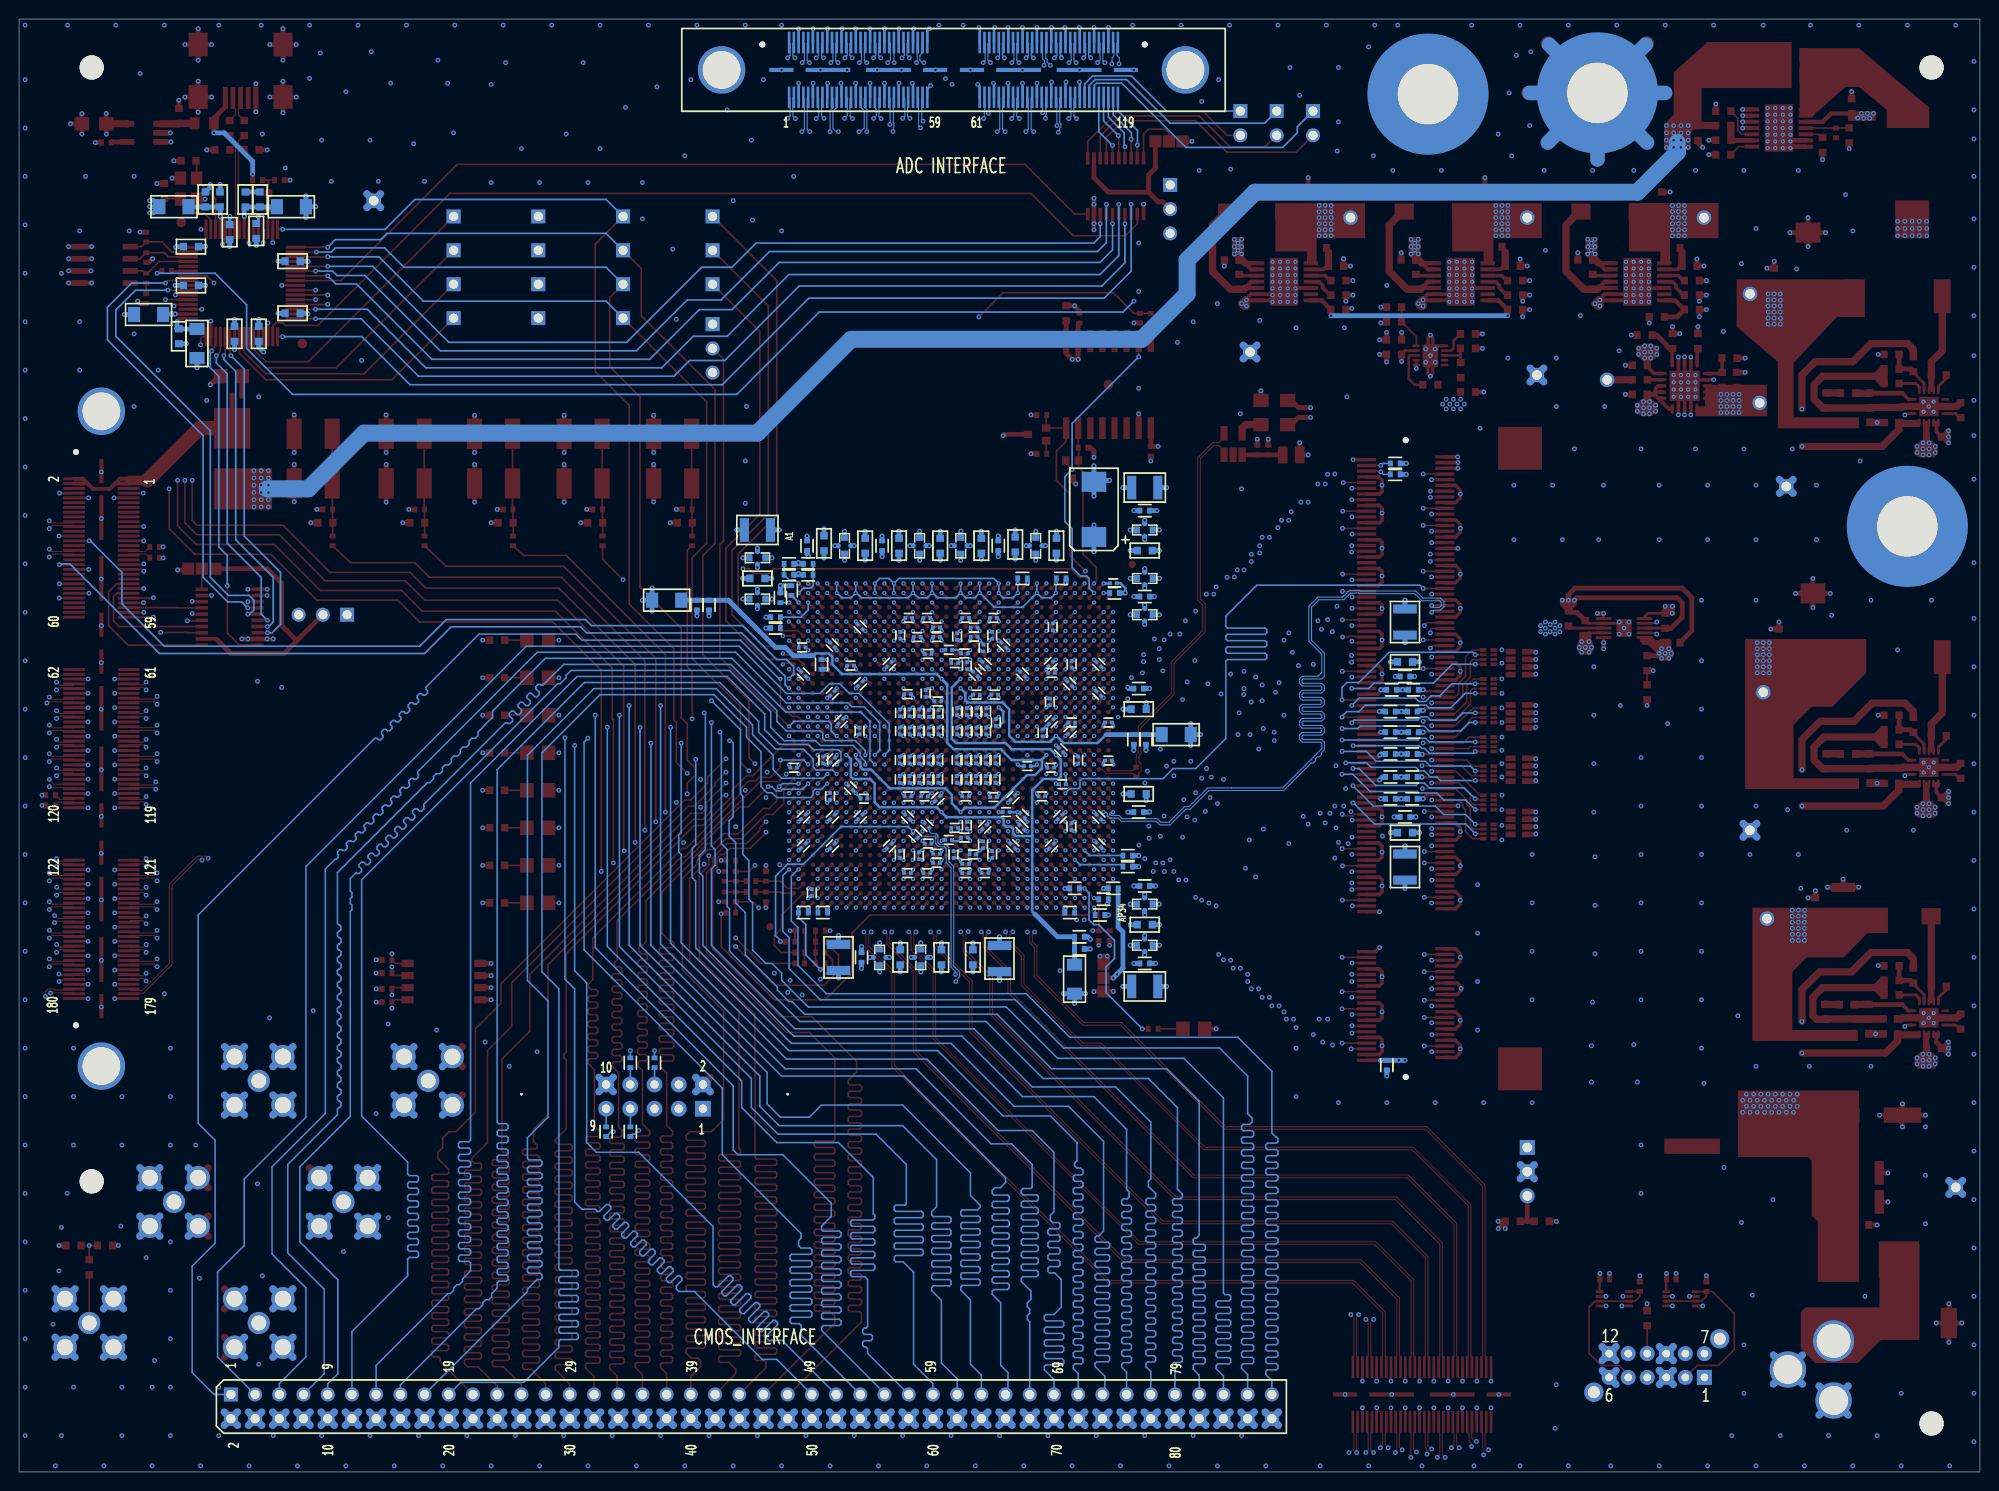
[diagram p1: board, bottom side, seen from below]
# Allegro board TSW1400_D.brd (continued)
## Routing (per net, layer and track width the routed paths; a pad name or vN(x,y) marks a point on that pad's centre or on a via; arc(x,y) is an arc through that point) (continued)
CMOS_PORT0_20: length 140
  TOP w0.165: v1(125.93,63.7) U5.A30 ; v1(133.86,63.75) 135.38,62.23 135.38,53.47 130.21,48.3 130.21,33.95 130.05,33.78 130.05,33.45 130.21,33.29 132.17,33.29 132.33,33.12 132.33,32.79 132.17,32.63 130.21,32.63 130.05,32.46 130.05,32.13 130.21,31.96 132.17,31.96 132.33,31.8 132.33,31.47 132.17,31.3 130.21,31.3 130.05,31.14 130.05,30.81 130.21,30.64 132.17,30.64 132.33,30.48 132.33,30.15 132.17,29.98 130.21,29.98 130.05,29.82 130.05,29.49 130.21,29.32 132.17,29.32 132.33,29.16 132.33,28.83 132.17,28.66 130.21,28.66 130.05,28.5 130.05,28.17 130.21,28 132.17,28 132.33,27.84 132.33,27.51 132.17,27.34 130.21,27.34 130.05,27.18 130.05,26.85 130.21,26.68 132.17,26.68 132.33,26.52 132.33,26.19 132.17,26.02 130.21,26.02 130.05,25.86 130.05,25.53 130.21,25.36 132.17,25.36 132.33,25.2 132.33,24.87 132.17,24.7 130.21,24.7 130.05,24.54 130.05,24.21 130.21,24.04 132.17,24.04 132.33,23.87 132.33,23.54 132.17,23.38 130.21,23.38 130.05,23.21 130.05,22.88 130.21,22.72 132.17,22.72 132.33,22.55 132.33,22.22 132.17,22.06 130.21,22.06 130.05,21.89 130.05,21.56 130.21,21.4 132.17,21.4 132.33,21.23 132.33,20.9 132.17,20.74 130.21,20.74 130.05,20.57 130.05,20.24 130.21,20.08 132.17,20.08 132.33,19.91 132.33,19.58 132.17,19.42 130.21,19.42 130.05,19.25 130.05,18.92 130.21,18.76 132.17,18.76 132.33,18.59 132.33,18.26 132.17,18.1 130.21,18.1 130.05,17.93 130.05,17.6 130.21,17.44 132.17,17.44 132.33,17.27 132.33,16.94 132.17,16.78 130.21,16.78 130.05,16.61 130.05,16.28 130.21,16.12 132.17,16.12 132.33,15.95 132.33,15.62 132.17,15.45 130.21,15.45 130.05,15.29 130.05,14.96 130.21,14.79 132.17,14.79 132.33,14.63 132.33,14.3 132.17,14.13 130.21,14.13 130.05,13.97 130.05,13.64 130.21,13.47 132.17,13.47 132.33,13.31 132.33,12.98 132.17,12.81 130.21,12.81 130.05,12.65 130.05,12.32 130.21,12.15 132.17,12.15 132.33,11.99 132.33,11.66 132.17,11.49 131.25,11.49 130.56,10.79 130.56,10.29 132.72,8.13
  L10-SIG4 w0.114: v1(125.93,63.7) 125.93,63.7 126.87,64.64 130.68,64.64 131.7,63.63 133.73,63.63 v1(133.86,63.75)
CMOS_PORT0_21: length 140
  TOP w0.165: v1(133.37,64.64) 133.37,63.61 134.37,62.61 134.37,53.85 128.52,48.01 128.52,32.98 128.36,32.82 126.4,32.82 126.24,32.65 126.24,32.32 126.4,32.16 128.36,32.16 128.52,31.99 128.52,31.66 128.36,31.5 126.4,31.5 126.24,31.33 126.24,31 126.4,30.84 128.36,30.84 128.52,30.67 128.52,30.34 128.36,30.18 126.4,30.18 126.24,30.01 126.24,29.68 126.4,29.52 128.36,29.52 128.52,29.35 128.52,29.02 128.36,28.86 126.4,28.86 126.24,28.69 126.24,28.36 126.4,28.19 128.36,28.19 128.52,28.03 128.52,27.7 128.36,27.53 126.4,27.53 126.24,27.37 126.24,27.04 126.4,26.87 128.36,26.87 128.52,26.71 128.52,26.38 128.36,26.21 126.4,26.21 126.24,26.05 126.24,25.72 126.4,25.55 128.36,25.55 128.52,25.39 128.52,25.06 128.36,24.89 126.4,24.89 126.24,24.73 126.24,24.4 126.4,24.23 128.36,24.23 128.52,24.07 128.52,23.74 128.36,23.57 126.4,23.57 126.24,23.41 126.24,23.08 126.4,22.91 128.36,22.91 128.52,22.75 128.52,22.42 128.36,22.25 126.4,22.25 126.24,22.09 126.24,21.76 126.4,21.59 128.36,21.59 128.52,21.43 128.52,21.1 128.36,20.93 126.4,20.93 126.24,20.77 126.24,20.44 126.4,20.27 128.36,20.27 128.52,20.11 128.52,19.77 128.36,19.61 126.4,19.61 126.24,19.44 126.24,19.11 126.4,18.95 128.36,18.95 128.52,18.78 128.52,18.45 128.36,18.29 126.4,18.29 126.24,18.12 126.24,17.79 126.4,17.63 128.36,17.63 128.52,17.46 128.52,17.13 128.36,16.97 126.4,16.97 126.24,16.8 126.24,16.47 126.4,16.31 128.36,16.31 128.52,16.14 128.52,15.81 128.36,15.65 126.4,15.65 126.24,15.48 126.24,15.15 126.4,14.99 128.36,14.99 128.52,14.82 128.52,14.49 128.36,14.33 126.4,14.33 126.24,14.16 126.24,13.83 126.4,13.67 128.36,13.67 128.52,13.5 128.52,13.17 128.36,13.01 126.4,13.01 126.24,12.84 126.24,12.51 126.4,12.35 128.36,12.35 128.52,12.18 128.52,11.85 128.36,11.68 127.55,11.68 127.38,11.52 127.38,10.92 130.18,8.13 ; U5.B29 v2(123.95,64.2)
  L9-SIG3 w0.102: v2(123.95,64.2) 123.95,64.14 124.38,63.7 125.07,63.7 125.35,63.98
  L9-SIG3 w0.114: v1(133.37,64.64) 133.22,64.64 132.08,63.5 130.81,63.5 129.79,64.52 125.88,64.52 125.35,63.98
CMOS_PORT1_0: length 140
  TOP w0.165: v1(127.38,68.2) 128.02,67.56 128.02,67.31 129.41,65.91 131.44,65.91 132.97,64.39 132.97,63.5 133.6,62.87 133.6,54.48 125.22,46.1 122.81,46.1 120.14,43.43 120.14,34.86 120.31,34.7 122.14,34.7 122.3,34.53 122.3,34.2 122.14,34.04 120.31,34.04 120.14,33.87 120.14,33.54 120.31,33.38 122.14,33.38 122.3,33.21 122.3,32.88 122.14,32.72 120.31,32.72 120.14,32.55 120.14,32.22 120.31,32.06 122.14,32.06 122.3,31.89 122.3,31.56 122.14,31.4 120.31,31.4 120.14,31.23 120.14,30.9 120.31,30.74 122.14,30.74 122.3,30.57 122.3,30.24 122.14,30.08 120.31,30.08 120.14,29.91 120.14,29.58 120.31,29.42 122.14,29.42 122.3,29.25 122.3,28.92 122.14,28.76 120.31,28.76 120.14,28.59 120.14,28.26 120.31,28.09 122.14,28.09 122.3,27.93 122.3,27.6 122.14,27.43 120.31,27.43 120.14,27.27 120.14,26.94 120.31,26.77 122.14,26.77 122.3,26.61 122.3,26.28 122.14,26.11 120.31,26.11 120.14,25.95 120.14,25.62 120.31,25.45 122.14,25.45 122.3,25.29 122.3,24.96 122.14,24.79 120.31,24.79 120.14,24.63 120.14,24.3 120.31,24.13 122.14,24.13 122.3,23.97 122.3,23.64 122.14,23.47 120.31,23.47 120.14,23.31 120.14,22.98 120.31,22.81 122.14,22.81 122.3,22.65 122.3,22.32 122.14,22.15 120.31,22.15 120.14,21.99 120.14,21.66 120.31,21.49 122.14,21.49 122.3,21.33 122.3,21 122.14,20.83 120.31,20.83 120.14,20.67 120.14,20.34 120.31,20.17 122.14,20.17 122.3,20 122.3,19.67 122.14,19.51 120.31,19.51 120.14,19.34 120.14,19.01 120.31,18.85 122.14,18.85 122.3,18.68 122.3,18.35 122.14,18.19 120.31,18.19 120.14,18.02 120.14,17.69 120.31,17.53 122.14,17.53 122.3,17.36 122.3,17.03 122.14,16.87 120.63,16.87 120.14,16.38 120.14,15.62 127.64,8.13 ; U5.B20 v2(123.95,73.2)
  L9-SIG3 w0.102: v2(123.95,73.2) 123.47,72.72 122.76,72.72 122.43,72.39 122.43,69.11 122.68,68.86 122.68,68.81 122.78,68.71 125.35,68.71
  L9-SIG3 w0.114: 125.35,68.71 126.87,68.71 v1(127.38,68.2)
CMOS_PORT1_1: length 140
  TOP w0.165: U5.K17 v2(115.95,77.2) ; 125.09,8.13 124.94,8.13 117.35,15.72 117.35,16.65 117.51,16.82 118.58,16.82 118.75,16.98 118.75,17.31 118.58,17.48 117.51,17.48 117.35,17.64 117.35,17.97 117.51,18.14 118.58,18.14 118.75,18.3 118.75,18.63 118.58,18.8 117.51,18.8 117.35,18.96 117.35,19.29 117.51,19.46 118.58,19.46 118.75,19.62 118.75,19.95 118.58,20.12 117.51,20.12 117.35,20.28 117.35,20.61 117.51,20.78 118.58,20.78 118.75,20.94 118.75,21.27 118.58,21.44 117.51,21.44 117.35,21.6 117.35,21.94 117.51,22.1 118.58,22.1 118.75,22.27 118.75,22.6 118.58,22.76 117.51,22.76 117.35,22.93 117.35,23.26 117.51,23.42 118.58,23.42 118.75,23.59 118.75,23.92 118.58,24.08 117.51,24.08 117.35,24.25 117.35,24.58 117.51,24.74 118.58,24.74 118.75,24.91 118.75,25.24 118.58,25.4 117.51,25.4 117.35,25.57 117.35,25.9 117.51,26.06 118.58,26.06 118.75,26.23 118.75,26.56 118.58,26.72 117.51,26.72 117.35,26.89 117.35,27.22 117.51,27.38 118.58,27.38 118.75,27.55 118.75,27.88 118.58,28.04 117.51,28.04 117.35,28.21 117.35,28.54 117.51,28.7 118.58,28.7 118.75,28.87 118.75,29.2 118.58,29.36 117.51,29.36 117.35,29.53 117.35,29.86 117.51,30.03 118.58,30.03 118.75,30.19 118.75,30.52 118.58,30.69 117.51,30.69 117.35,30.85 117.35,31.18 117.51,31.35 118.58,31.35 118.75,31.51 118.75,31.84 118.58,32.01 117.51,32.01 117.35,32.17 117.35,32.5 117.51,32.67 118.58,32.67 118.75,32.83 118.75,33.16 118.58,33.33 117.51,33.33 117.35,33.49 117.35,33.82 117.51,33.99 118.58,33.99 118.75,34.15 118.75,34.48 118.58,34.65 117.51,34.65 117.35,34.81 117.35,35.14 117.51,35.31 118.58,35.31 118.75,35.47 118.75,35.8 118.58,35.97 117.51,35.97 117.35,36.13 117.35,36.46 117.51,36.63 118.58,36.63 118.75,36.79 118.75,37.12 118.58,37.29 117.51,37.29 117.35,37.45 117.35,37.78 117.51,37.95 118.58,37.95 118.75,38.11 118.75,38.45 118.58,38.61 117.51,38.61 117.35,38.78 117.35,39.11 117.51,39.27 118.58,39.27 118.75,39.44 118.75,39.77 118.58,39.93 117.51,39.93 117.35,40.1 117.35,40.43 117.51,40.59 118.58,40.59 118.75,40.76 118.75,41.09 117.86,41.98 117.86,43.05 122.56,47.75 125.86,47.75 132.97,54.86 132.97,62.98 132.52,63.43 132.52,64.32 132.06,64.77 131.8,64.77 131.17,65.41 129.03,65.41 127.38,67.06 v1(127.38,67.11)
  L9-SIG3 w0.102: 125.2,67.59 121.89,67.59 121.41,68.07 121.41,70.36 121.03,70.74 116.84,70.74 116.46,71.12 116.46,75.82 115.95,76.33 v2(115.95,77.2)
  L9-SIG3 w0.114: v1(127.38,67.11) 127.33,67.11 127.25,67.18 125.6,67.18 125.2,67.59
CMOS_PORT1_2: length 140
  TOP w0.165: U5.K16 v2(115.95,78.2)
  L9-SIG3 w0.102: v2(115.95,78.2) 116.24,78.2 116.84,77.6 119.25,77.6 119.51,77.34 119.51,76.58 120.4,75.69 122.3,75.69
  L9-SIG3 w0.114: v1(148.46,77.01) 147.12,77.01 145.92,75.82 140.72,75.82 138.3,73.41 136.09,73.41 135.81,73.69 132.43,73.69 131.95,74.17 131.06,74.17 130.18,75.06 126.06,75.06 126.03,75.09 125.38,75.09 125.09,74.8 123.19,74.8 122.3,75.69
  BOTTOM w0.165: v1(148.46,77.01) 148.46,51.69 147.45,50.67 147.45,28.32 146.69,27.56 145.29,27.56 145.07,27.34 144.84,27.34 144.13,28.05 143.9,28.05 143.66,27.81 143.66,27.58 144.37,26.87 144.37,26.64 144.13,26.41 143.9,26.41 143.2,27.11 142.96,27.11 142.73,26.88 142.73,26.65 143.43,25.94 143.43,25.71 143.2,25.47 142.97,25.47 142.26,26.18 142.03,26.18 141.79,25.94 141.79,25.71 142.5,25.01 142.5,24.77 142.27,24.54 142.03,24.54 141.33,25.24 141.09,25.24 140.86,25.01 140.86,24.78 141.57,24.07 141.57,23.84 141.33,23.6 141.1,23.6 140.39,24.31 140.16,24.31 139.93,24.08 139.93,23.84 140.63,23.14 140.63,22.9 140.4,22.67 140.17,22.67 139.46,23.38 139.23,23.38 138.99,23.14 138.99,22.91 139.7,22.2 139.7,21.97 139.47,21.74 139.23,21.74 138.53,22.44 138.29,22.44 138.06,22.21 138.06,21.98 138.76,21.27 138.76,21.04 138.53,20.8 138.3,20.8 137.59,21.51 137.36,21.51 137.12,21.28 137.12,21.04 137.83,20.34 137.83,20.1 137.6,19.87 137.36,19.87 136.66,20.57 136.42,20.57 136.19,20.34 136.19,20.11 136.78,19.52 136.78,19.19 136.53,18.93 134.89,18.93 127.76,11.81 126.24,11.81 122.56,8.13
CMOS_PORT1_3: length 140.1
  TOP w0.165: U5.J17 v2(116.95,77.2)
  L9-SIG3 w0.102: v2(116.95,77.2) 116.96,77.2 ; 118.44,75.72 118.44,74.09
  L9-SIG3 w0.114: 118.44,74.09 118.85,73.69 125.65,73.69 125.88,73.91 128.04,73.91 129.06,72.9 133.86,72.9 134.11,73.15 134.49,73.15 134.87,72.77 143.89,72.77 147.32,76.2 v1(147.45,76.2) ; 116.96,77.2 118.44,75.72
  BOTTOM w0.165: 120.02,8.13 125.69,13.8 127.09,13.8 127.32,14.04 127.32,14.27 126.16,15.43 126.16,15.67 126.39,15.9 126.62,15.9 127.79,14.74 128.02,14.74 128.26,14.97 128.26,15.2 127.09,16.37 127.09,16.6 127.33,16.84 127.56,16.84 128.72,15.67 128.96,15.67 129.19,15.91 129.19,16.14 128.03,17.3 128.03,17.54 128.26,17.77 128.49,17.77 129.66,16.61 129.89,16.61 130.12,16.84 130.12,17.07 128.96,18.24 128.96,18.47 129.19,18.7 129.43,18.7 130.59,17.54 130.82,17.54 131.06,17.77 131.06,18.01 129.89,19.17 129.89,19.4 130.13,19.64 130.36,19.64 131.52,18.47 131.76,18.47 131.99,18.71 131.99,18.94 130.83,20.1 130.83,20.34 131.06,20.57 131.29,20.57 132.46,19.41 132.69,19.41 132.93,19.64 132.93,25.74 140.72,33.53 145.16,33.53 146.18,34.54 146.18,51.31 147.45,52.58 v1(147.45,76.2)
CMOS_PORT1_4: length 140.1
  TOP w0.165: U5.J16 v2(116.95,78.2)
  L9-SIG3 w0.102: 124.59,75.95 124.46,76.07 123.06,76.07 122.81,76.33 122.17,76.33 121.41,77.09 121.41,78.61 121.28,78.74 117.49,78.74 v2(116.95,78.2)
  L9-SIG3 w0.114: v1(146.05,76.96) 137.95,76.96 135.32,74.33 133.69,74.33 132.08,75.95 124.59,75.95
  BOTTOM w0.165: v1(146.05,76.96) 146.46,76.56 146.46,54.76 131.95,40.26 131.95,33.27 123.7,25.02 123.7,24.51 123.95,24.26 123.95,23.75 123.69,23.48 122.72,23.48 122.56,23.32 122.56,22.99 122.72,22.82 124.68,22.82 124.84,22.66 124.84,22.33 124.68,22.16 122.72,22.16 122.56,22 122.56,21.67 122.72,21.5 124.68,21.5 124.84,21.34 124.84,21.01 124.68,20.84 122.72,20.84 122.56,20.68 122.56,20.35 122.72,20.18 124.68,20.18 124.84,20.02 124.84,19.69 124.68,19.52 122.72,19.52 122.56,19.36 122.56,19.03 122.72,18.86 124.68,18.86 124.84,18.7 124.84,18.37 124.68,18.2 122.72,18.2 122.56,18.04 122.56,17.71 122.72,17.54 124.68,17.54 124.84,17.38 124.84,17.05 124.68,16.88 122.72,16.88 122.56,16.72 122.56,16.39 122.72,16.22 124.68,16.22 124.84,16.06 124.84,15.73 124.68,15.56 123.86,15.56 123.7,15.39 123.7,14.35 117.47,8.13
CMOS_PORT1_5: length 140
  TOP w0.165: U5.B14 v2(123.95,80.2)
  L9-SIG3 w0.102: v2(123.95,80.2) 123.95,80.14 124.59,79.5
  L9-SIG3 w0.114: v1(145.29,79.38) 144.88,78.96 141.99,78.96 141.5,79.45 134.7,79.45 134.37,79.12 133.73,79.12 133.35,79.5 124.59,79.5
  BOTTOM w0.165: 114.94,8.13 114.94,8.26 120.65,13.97 121.54,14.86 121.54,15.19 121.37,15.35 119.67,15.35 119.51,15.52 119.51,15.85 119.67,16.01 121.37,16.01 121.54,16.18 121.54,16.51 121.37,16.67 119.67,16.67 119.51,16.84 119.51,17.17 119.67,17.34 121.37,17.34 121.54,17.5 121.54,17.83 121.37,18 119.67,18 119.51,18.16 119.51,18.49 119.67,18.66 121.37,18.66 121.54,18.82 121.54,19.15 121.37,19.32 119.67,19.32 119.51,19.48 119.51,19.81 119.67,19.98 121.37,19.98 121.54,20.14 121.54,20.47 121.37,20.64 119.67,20.64 119.51,20.8 119.51,21.13 119.67,21.3 121.37,21.3 121.54,21.46 121.54,21.79 121.37,21.96 119.67,21.96 119.51,22.12 119.51,22.45 119.67,22.62 121.37,22.62 121.54,22.78 121.54,23.11 121.37,23.28 119.67,23.28 119.51,23.44 119.51,23.77 119.67,23.94 121.37,23.94 121.54,24.1 121.54,24.43 121.37,24.6 119.67,24.6 119.51,24.76 119.51,25.09 119.67,25.26 121.37,25.26 121.54,25.43 121.54,25.78 120.52,26.8 120.52,28.19 125.6,33.27 130.3,33.27 130.81,33.78 130.81,40.51 145.29,54.99 145.29,79.25 145.16,79.38 v1(145.29,79.38)
CMOS_PORT1_6: length 140
  TOP w0.165: U5.G16 v2(118.95,78.2)
  L4-SIG2 w0.102: 119.55,77.6 v2(118.95,78.2)
  L4-SIG2 w0.114: 119.55,77.6 124.86,77.6 124.87,77.6 124.97,77.6 125.6,78.23 128.52,78.23 130.43,80.14 136.91,80.14 138.3,78.74 143.38,78.74 v1(144.02,78.11)
  BOTTOM w0.165: 112.39,8.13 116.71,12.45 116.71,12.94 116.88,13.11 117.06,13.11 117.22,13.27 117.22,13.6 117.06,13.77 116.37,13.77 116.2,13.93 116.2,14.26 116.37,14.43 117.06,14.43 117.22,14.59 117.22,14.92 117.06,15.09 116.88,15.09 116.71,15.25 116.71,20.19 117,20.48 118.33,20.48 118.49,20.65 118.49,20.98 118.33,21.14 116.12,21.14 115.95,21.31 115.95,21.64 116.12,21.8 118.33,21.8 118.49,21.97 118.49,22.3 118.33,22.46 116.12,22.46 115.95,22.63 115.95,22.96 116.12,23.12 118.33,23.12 118.49,23.29 118.49,23.62 118.33,23.78 116.12,23.78 115.95,23.95 115.95,24.28 116.12,24.44 118.33,24.44 118.49,24.61 118.49,24.94 118.33,25.11 116.12,25.11 115.95,25.27 115.95,25.6 116.12,25.77 118.33,25.77 118.49,25.93 118.49,26.26 118.33,26.43 116.12,26.43 115.95,26.59 115.95,26.92 116.12,27.09 116.12,30.9 119.76,34.54 126.24,34.54 129.92,38.23 129.92,41.02 144.02,55.12 v1(144.02,78.11)
CMOS_PORT1_7: length 140
  TOP w0.165: U5.F15 v2(119.95,79.2)
  L10-SIG4 w0.114: v2(119.95,79.2) 119.97,79.2 120.47,79.71 132.92,79.71 133.38,80.16 135.97,80.16 136.4,79.73 142.39,79.73 v1(142.75,79.38)
  BOTTOM w0.165: v1(142.75,79.38) 142.75,55.12 128.91,41.27 128.91,38.23 126.11,35.43 115.82,35.43 112.65,32.26 112.65,28.12 112.78,27.99 113.75,27.99 113.92,27.83 113.92,27.5 113.75,27.33 111.04,27.33 110.87,27.17 110.87,26.84 111.04,26.67 113.75,26.67 113.92,26.5 113.92,26.17 113.75,26.01 111.04,26.01 110.87,25.84 110.87,25.51 111.04,25.35 113.75,25.35 113.92,25.18 113.92,24.85 113.75,24.69 111.04,24.69 110.87,24.52 110.87,24.19 111.04,24.03 113.75,24.03 113.92,23.86 113.92,23.53 113.75,23.37 111.04,23.37 110.87,23.2 110.87,22.87 111.04,22.71 113.75,22.71 113.92,22.54 113.92,22.21 113.75,22.05 112.98,22.05 111.89,20.95 111.89,11.3 109.86,9.27 109.86,8.13
CMOS_PORT1_8: length 140
  TOP w0.165: U5.E14 v2(120.95,80.2)
  L9-SIG3 w0.114: v2(120.95,80.2) 121.4,80.2 121.79,80.59 121.79,80.59 123.75,82.55 123.75,82.55 123.79,82.59 139.54,82.59 v1(141.73,80.39)
  BOTTOM w0.165: v1(141.73,80.39) 141.73,55.24 128.02,41.53 128.02,38.35 125.98,36.32 113.03,36.32 109.47,32.77 109.47,27.81 109.98,27.3 109.98,26.95 109.82,26.78 108.12,26.78 107.95,26.62 107.95,26.29 108.12,26.12 109.82,26.12 109.98,25.96 109.98,25.63 109.82,25.46 108.12,25.46 107.95,25.3 107.95,24.97 108.12,24.8 109.82,24.8 109.98,24.64 109.98,24.31 109.82,24.14 108.12,24.14 107.95,23.98 107.95,23.65 108.12,23.48 109.82,23.48 109.98,23.32 109.98,22.99 109.82,22.82 108.12,22.82 107.95,22.65 107.95,22.32 108.12,22.16 109.82,22.16 109.98,21.99 109.98,21.66 109.82,21.5 108.12,21.5 107.95,21.33 107.95,21 108.12,20.84 109.82,20.84 109.98,20.67 109.98,20.34 109.82,20.18 108.12,20.18 107.95,20.01 107.95,19.68 108.12,19.52 109.82,19.52 109.98,19.35 109.98,19.02 108.97,18.01 108.97,11.43 107.31,9.78 107.31,8.13
CMOS_PORT1_9: length 140.1
  TOP w0.165: U5.E15 v2(120.95,79.2)
  L9-SIG3 w0.102: v2(120.95,79.2) 121.38,79.63 ; 122.56,79.63 123.32,79.63
  L9-SIG3 w0.114: 121.38,79.63 122.56,79.63 ; 123.32,79.63 123.77,79.17 133.17,79.17 133.86,78.49 136.14,78.49 136.27,78.61 140.08,78.61 v1(140.59,78.11)
  BOTTOM w0.165: v1(140.59,78.11) 140.59,55.24 127.25,41.91 127.25,38.61 125.86,37.21 122.81,37.21 121.54,38.48 113.03,38.48 105.92,31.37 105.92,29 104.9,27.99 104.9,27.74 105.16,27.49 106.77,27.49 106.93,27.33 106.93,27 106.77,26.83 105.07,26.83 104.9,26.67 104.9,26.34 105.07,26.17 106.77,26.17 106.93,26.01 106.93,25.67 106.77,25.51 105.07,25.51 104.9,25.34 104.9,25.01 105.07,24.85 106.77,24.85 106.93,24.68 106.93,24.35 106.77,24.19 105.07,24.19 104.9,24.02 104.9,23.69 105.07,23.53 106.77,23.53 106.93,23.36 106.93,23.03 106.77,22.87 105.07,22.87 104.9,22.7 104.9,22.37 105.07,22.21 106.77,22.21 106.93,22.04 106.93,21.71 106.77,21.55 105.07,21.55 104.9,21.38 104.9,21.05 105.07,20.89 106.77,20.89 106.93,20.72 106.93,20.39 106.77,20.23 105.07,20.23 104.9,20.06 104.9,19.73 105.07,19.57 106.77,19.57 106.93,19.4 106.93,19.07 105.92,18.05 105.92,11.3 104.78,10.16 104.78,8.13
CMOS_PORT1_10: length 140
  TOP w0.165: U5.E17 v2(120.95,77.2)
  L9-SIG3 w0.102: 124.33,75.69 122.94,75.69 122.68,75.95 121.92,75.95 120.95,76.92 v2(120.95,77.2)
  L9-SIG3 w0.114: 124.33,75.69 124.59,75.44 131.7,75.44 133.1,74.04 137.03,74.04 v1(139.45,76.45)
  BOTTOM w0.165: 102.23,8.13 101.98,8.38 101.98,10.41 102.74,11.18 102.74,17.75 103.63,18.64 103.63,18.97 103.47,19.13 102.02,19.13 101.85,19.3 101.85,19.63 102.02,19.79 103.47,19.79 103.63,19.96 103.63,20.29 103.47,20.45 102.02,20.45 101.85,20.62 101.85,20.95 102.02,21.11 103.47,21.11 103.63,21.28 103.63,21.61 103.47,21.77 102.02,21.77 101.85,21.94 101.85,22.27 102.02,22.43 103.47,22.43 103.63,22.6 103.63,22.93 103.47,23.1 102.02,23.1 101.85,23.26 101.85,23.59 102.02,23.76 103.47,23.76 103.63,23.92 103.63,24.25 103.47,24.42 102.02,24.42 101.85,24.58 101.85,24.91 102.02,25.08 103.47,25.08 103.63,25.24 103.63,25.57 103.47,25.74 102.02,25.74 101.85,25.9 101.85,26.23 102.02,26.4 103.47,26.4 103.63,26.56 103.63,26.89 103.47,27.06 102.02,27.06 101.85,27.22 101.85,27.55 102.02,27.72 103.47,27.72 103.63,27.88 103.63,28.21 103.47,28.38 102.02,28.38 101.85,28.54 101.85,28.87 102.02,29.04 103.47,29.04 103.63,29.2 103.63,29.53 103.35,29.82 102.77,29.82 102.23,30.35 102.23,30.86 112.9,41.53 125.73,41.53 139.45,55.24 v1(139.45,76.45)
CMOS_PORT1_11: length 140
  TOP w0.165: U5.D14 v2(121.95,80.2)
  L9-SIG3 w0.114: v1(138.43,80.39) 137.29,81.53 125.16,81.53 125.11,81.59 123.62,81.59 122.24,80.2 v2(121.95,80.2)
  BOTTOM w0.165: v1(138.43,80.39) 138.43,55.37 125.35,42.29 111.63,42.29 103.76,34.42 101.6,34.42 99.44,32.26 99.44,29.85 99.57,29.73 100.42,29.73 100.58,29.56 100.58,29.23 100.42,29.07 98.97,29.07 98.81,28.9 98.81,28.57 98.97,28.41 100.42,28.41 100.58,28.24 100.58,27.91 100.42,27.75 98.97,27.75 98.81,27.58 98.81,27.25 98.97,27.08 100.42,27.08 100.58,26.92 100.58,26.59 100.42,26.42 98.97,26.42 98.81,26.26 98.81,25.93 98.97,25.76 100.42,25.76 100.58,25.6 100.58,25.27 100.42,25.1 98.97,25.1 98.81,24.94 98.81,24.61 98.97,24.44 100.42,24.44 100.58,24.28 100.58,23.95 100.42,23.78 98.97,23.78 98.81,23.62 98.81,23.29 98.97,23.12 100.42,23.12 100.58,22.96 100.58,22.63 100.42,22.46 98.97,22.46 98.81,22.3 98.81,21.97 98.97,21.8 100.42,21.8 100.58,21.64 100.58,21.31 100.42,21.14 98.97,21.14 98.81,20.98 98.81,20.65 98.97,20.48 100.42,20.48 100.58,20.32 100.58,19.99 99.57,18.97 99.57,18.11 99.95,17.73 99.95,17.32 99.69,17.07 99.69,16.66 99.95,16.41 99.95,16 99.69,15.75 J1.67
CMOS_PORT1_12: length 140
  TOP w0.165: U5.D15 v2(121.95,79.2)
  L9-SIG3 w0.102: 125.35,78.58 125.23,78.58 125.2,78.61 122.54,78.61 v2(121.95,79.2)
  L9-SIG3 w0.114: 125.35,78.58 125.38,78.58 125.7,78.26 132.31,78.26 132.84,77.72 137,77.72 v1(137.38,78.11)
  BOTTOM w0.165: 97.16,8.13 97.16,9.71 98.17,10.73 98.17,11.06 98.01,11.23 96.3,11.23 96.14,11.39 96.14,11.72 96.3,11.89 98.01,11.89 98.17,12.05 98.17,12.38 98.01,12.55 96.3,12.55 96.14,12.71 96.14,13.04 96.3,13.21 98.01,13.21 98.17,13.37 98.17,13.7 98.01,13.87 96.3,13.87 96.14,14.03 96.14,14.36 96.3,14.53 98.01,14.53 98.17,14.69 98.17,15.02 98.01,15.19 96.3,15.19 96.14,15.35 96.14,15.68 96.3,15.85 98.01,15.85 98.17,16.01 98.17,16.34 98.01,16.51 97.16,16.51 96.39,17.27 96.39,20.19 97.08,20.88 97.62,20.88 97.79,21.04 97.79,21.37 97.62,21.54 96.69,21.54 96.52,21.7 96.52,22.04 96.69,22.2 97.62,22.2 97.79,22.37 97.79,22.7 97.62,22.86 96.69,22.86 96.52,23.03 96.52,23.36 96.69,23.52 97.62,23.52 97.79,23.69 97.79,24.02 97.62,24.18 96.69,24.18 96.52,24.35 96.52,24.68 96.69,24.84 97.62,24.84 97.79,25.01 97.79,25.34 97.62,25.5 96.69,25.5 96.52,25.67 96.52,26 96.69,26.16 97.28,26.16 97.54,26.42 97.54,26.92 97.16,27.3 97.16,33.53 99.44,35.81 103,35.81 110.49,43.31 125.22,43.31 137.38,55.47 v1(137.38,78.11)
CMOS_PORT1_13: length 140.1
  TOP w0.165: U5.D16 v2(121.95,78.2)
  L9-SIG3 w0.102: 125.6,77.47 125.22,77.47 125.11,77.58 124.79,77.58 124.68,77.47 123.32,77.47 123.06,77.72 122.43,77.72 v2(121.95,78.2)
  L9-SIG3 w0.114: 125.6,77.47 131.32,77.47 131.95,76.83 135.89,76.83 v1(136.27,76.45)
  BOTTOM w0.165: 94.61,8.13 94.61,10.33 95.12,10.84 95.12,11.17 94.96,11.33 94.27,11.33 94.11,11.5 94.11,11.83 94.27,11.99 94.96,11.99 95.12,12.16 95.12,12.49 94.96,12.66 94.27,12.66 94.11,12.82 94.11,13.15 94.27,13.32 94.96,13.32 95.12,13.48 95.12,13.81 94.96,13.98 94.27,13.98 94.11,14.14 94.11,14.47 94.27,14.64 94.96,14.64 95.12,14.8 95.12,15.13 94.96,15.3 94.27,15.3 94.11,15.46 94.11,15.79 94.27,15.96 94.96,15.96 95.12,16.12 95.12,16.45 94.96,16.62 94.27,16.62 94.11,16.78 94.11,17.11 94.27,17.28 94.96,17.28 95.12,17.44 95.12,17.77 94.96,17.94 94.27,17.94 94.11,18.1 94.11,18.43 94.27,18.6 94.96,18.6 95.12,18.76 95.12,19.09 94.96,19.26 94.27,19.26 94.11,19.42 94.11,19.75 94.27,19.92 94.96,19.92 95.12,20.08 95.12,20.41 94.96,20.58 94.27,20.58 94.11,20.75 94.11,21.08 94.27,21.24 94.96,21.24 95.12,21.41 95.12,21.74 94.96,21.9 94.27,21.9 94.11,22.07 94.11,22.4 94.27,22.56 94.96,22.56 95.12,22.73 95.12,23.06 94.96,23.22 94.27,23.22 94.11,23.39 94.11,23.72 94.27,23.88 94.96,23.88 95.12,24.05 95.12,24.38 94.96,24.54 94.27,24.54 94.11,24.71 94.11,25.04 94.27,25.2 94.96,25.2 95.12,25.37 95.12,25.7 94.96,25.86 94.27,25.86 94.11,26.03 94.11,26.36 94.27,26.52 94.96,26.52 95.12,26.69 95.12,27.02 94.96,27.18 94.27,27.18 94.11,27.35 94.11,27.68 94.27,27.84 94.96,27.84 95.12,28.01 95.12,28.34 94.96,28.5 94.27,28.5 94.11,28.67 94.11,29 94.27,29.17 94.96,29.17 95.12,29.33 95.12,29.66 94.96,29.83 94.27,29.83 94.11,29.99 94.11,30.32 94.27,30.49 94.96,30.49 95.12,30.65 95.12,30.98 94.96,31.15 94.27,31.15 94.11,31.31 94.11,31.64 94.34,31.88 94.74,31.88 95,32.13 95,32.38 94.74,32.64 94.74,34.54 97.54,37.34 102.49,37.34 109.35,44.2 124.97,44.2 136.27,55.5 136.27,64.77 136.53,65.02 136.53,66.8 136.27,67.06 v1(136.27,76.45)
CMOS_PORT1_14: length 140
  TOP w0.165: U5.D17 v2(121.95,77.2)
  L9-SIG3 w0.102: 122.94,76.71 122.44,76.71 v2(121.95,77.2)
  L9-SIG3 w0.114: v1(134.75,74.75) 133.2,76.3 130.84,76.3 130.68,76.45 123.19,76.45 122.94,76.71
  BOTTOM w0.165: 92.08,8.13 91.82,8.38 91.82,10.05 92.84,11.06 92.84,11.39 92.67,11.56 91.48,11.56 91.31,11.72 91.31,12.05 91.48,12.22 92.67,12.22 92.84,12.38 92.84,12.71 92.67,12.88 91.48,12.88 91.31,13.04 91.31,13.37 91.48,13.54 92.67,13.54 92.84,13.7 92.84,14.03 92.67,14.2 91.48,14.2 91.31,14.36 91.31,14.69 91.48,14.86 92.67,14.86 92.84,15.02 92.84,15.35 92.67,15.52 91.48,15.52 91.31,15.68 91.31,16.01 91.48,16.18 92.67,16.18 92.84,16.34 92.84,16.68 92.67,16.84 91.48,16.84 91.31,17.01 91.31,17.34 91.48,17.5 92.67,17.5 92.84,17.67 92.84,18 92.67,18.16 91.48,18.16 91.31,18.33 91.31,18.66 91.48,18.82 92.67,18.82 92.84,18.99 92.84,19.32 92.67,19.48 91.48,19.48 91.31,19.65 91.31,19.98 91.48,20.14 92.67,20.14 92.84,20.31 92.84,20.64 92.67,20.8 91.48,20.8 91.31,20.97 91.31,21.3 91.48,21.46 92.67,21.46 92.84,21.63 92.84,21.96 92.67,22.12 91.48,22.12 91.31,22.29 91.31,22.62 91.48,22.78 92.67,22.78 92.84,22.95 92.84,23.28 92.67,23.44 91.48,23.44 91.31,23.61 91.31,23.94 91.48,24.1 92.67,24.1 92.84,24.27 92.84,24.6 92.67,24.77 92.46,24.77 91.95,25.27 91.95,34.67 95.63,38.35 101.35,38.35 107.95,44.96 124.71,44.96 134.75,54.99 134.75,61.98 135.13,62.36 135.13,65.41 134.75,65.79 v1(134.75,74.75)
CMOS_PORT1_15: length 140
  TOP w0.165: U5.C14 v2(122.95,80.2)
  L9-SIG3 w0.114: v2(122.95,80.2) 123.25,80.2 123.7,80.64 124.21,80.64 124.56,80.29 124.56,80.04 124.79,79.81 125.38,79.81 125.73,80.16 133.32,80.16 v1(133.86,79.63)
  BOTTOM w0.165: 89.53,8.13 89.53,10.46 90.04,10.97 90.04,11.3 89.88,11.47 89.19,11.47 89.03,11.63 89.03,11.96 89.19,12.13 89.88,12.13 90.04,12.29 90.04,12.62 89.88,12.79 89.19,12.79 89.03,12.95 89.03,13.28 89.19,13.45 89.88,13.45 90.04,13.61 90.04,13.94 89.88,14.11 89.19,14.11 89.03,14.27 89.03,14.6 89.19,14.77 89.88,14.77 90.04,14.93 90.04,15.26 89.88,15.43 89.19,15.43 89.03,15.59 89.03,15.92 89.19,16.09 89.88,16.09 90.04,16.25 90.04,16.58 89.88,16.75 89.19,16.75 89.03,16.92 89.03,17.25 89.19,17.41 89.88,17.41 90.04,17.58 90.04,17.91 89.88,18.07 89.19,18.07 89.03,18.24 89.03,18.57 89.19,18.73 89.88,18.73 90.04,18.9 90.04,19.23 89.88,19.39 89.19,19.39 89.03,19.56 89.03,19.89 89.19,20.05 89.88,20.05 90.04,20.22 90.04,20.55 89.88,20.71 89.19,20.71 89.03,20.88 89.03,21.21 89.19,21.37 89.88,21.37 90.04,21.54 90.04,21.87 89.88,22.03 89.19,22.03 89.03,22.2 89.03,22.53 89.19,22.69 89.88,22.69 90.04,22.86 90.04,23.19 89.88,23.35 89.19,23.35 89.03,23.52 89.03,23.85 89.19,24.01 89.88,24.01 90.04,24.18 90.04,24.51 89.88,24.67 89.19,24.67 89.03,24.84 89.03,25.17 89.19,25.34 89.88,25.34 90.04,25.5 90.04,25.83 89.88,26 89.19,26 89.03,26.16 89.03,26.49 89.19,26.66 89.88,26.66 90.04,26.82 90.04,27.15 89.88,27.32 89.19,27.32 89.03,27.48 89.03,27.81 89.19,27.98 89.88,27.98 90.04,28.14 90.04,28.47 89.88,28.64 89.47,28.64 89.28,28.83 89.28,29.39 89.53,29.64 89.53,35.94 92.96,39.37 100.46,39.37 106.81,45.72 124.46,45.72 133.99,55.24 133.99,62.48 134.37,62.87 134.37,64.64 133.73,65.28 133.73,79.5 v1(133.86,79.63)
CMOS_PORT1_16: length 140
  TOP w0.165: U5.C15 v2(122.95,79.2)
  L9-SIG3 w0.102: 125.6,78.87 123.44,78.87 123.11,79.2 v2(122.95,79.2)
  L9-SIG3 w0.114: 125.6,78.87 125.86,78.61 v1(133.1,78.61)
  BOTTOM w0.165: v1(133.1,78.61) 133.1,65.66 132.72,65.28 132.72,63.63 133.1,63.25 133.1,55.24 124.33,46.48 105.54,46.48 99.44,40.39 90.68,40.39 87,36.7 87,30.73 87.25,30.48 87.25,29.95 86.49,29.19 86.49,28.86 86.65,28.7 87.34,28.7 87.5,28.53 87.5,28.2 87.34,28.04 86.65,28.04 86.49,27.87 86.49,27.54 86.65,27.38 87.34,27.38 87.5,27.21 87.5,26.88 87.34,26.72 86.65,26.72 86.49,26.55 86.49,26.22 86.65,26.06 87.34,26.06 87.5,25.89 87.5,25.56 87.34,25.4 86.65,25.4 86.49,25.23 86.49,24.9 86.65,24.74 87.34,24.74 87.5,24.57 87.5,24.24 87.34,24.07 86.65,24.07 86.49,23.91 86.49,23.58 86.65,23.41 87.34,23.41 87.5,23.25 87.5,22.92 87.34,22.75 86.65,22.75 86.49,22.59 86.49,22.26 86.65,22.09 87.34,22.09 87.5,21.93 87.5,21.6 87.34,21.43 86.65,21.43 86.49,21.27 86.49,20.94 86.65,20.77 87.34,20.77 87.5,20.61 87.5,20.28 87.34,20.11 86.65,20.11 86.49,19.95 86.49,19.62 86.65,19.45 87.34,19.45 87.5,19.29 87.5,18.96 87.34,18.79 86.65,18.79 86.49,18.63 86.49,18.3 86.65,18.13 87.34,18.13 87.5,17.97 87.5,17.64 87.34,17.47 86.65,17.47 86.49,17.31 86.49,16.98 86.65,16.81 87.34,16.81 87.5,16.65 87.5,16.31 87.34,16.15 86.65,16.15 86.49,15.98 86.49,15.65 86.65,15.49 87.34,15.49 87.5,15.32 87.5,14.99 87.34,14.83 86.65,14.83 86.49,14.66 86.49,14.33 86.65,14.17 87.34,14.17 87.5,14 87.5,13.67 87.34,13.51 86.65,13.51 86.49,13.34 86.49,13.01 86.65,12.85 87.34,12.85 87.5,12.68 87.5,12.35 87.34,12.19 86.65,12.19 86.49,12.02 86.49,11.69 86.65,11.53 87.34,11.53 87.5,11.36 87.5,11.03 87,10.52 87,8.13
CMOS_PORT1_17: length 140.1
  TOP w0.165: U5.C16 v2(122.95,78.2)
  L9-SIG3 w0.102: v2(122.95,78.2) 123.35,78.2 123.75,77.8 124.69,77.8 124.7,77.81 125.1,77.81 125.14,77.85 125.6,77.85
  L9-SIG3 w0.114: v1(132.21,77.6) 131.95,77.85 125.6,77.85
  BOTTOM w0.165: 84.45,8.13 84.45,10.75 84.71,11 84.71,11.33 84.54,11.5 83.86,11.5 83.69,11.66 83.69,11.99 83.86,12.16 84.54,12.16 84.71,12.32 84.71,12.65 84.54,12.82 83.86,12.82 83.69,12.98 83.69,13.31 83.86,13.48 84.54,13.48 84.71,13.64 84.71,13.97 84.54,14.14 83.86,14.14 83.69,14.3 83.69,14.63 83.86,14.8 84.54,14.8 84.71,14.96 84.71,15.29 84.54,15.46 83.86,15.46 83.69,15.62 83.69,15.95 83.86,16.12 84.54,16.12 84.71,16.28 84.71,16.62 84.54,16.78 83.86,16.78 83.69,16.95 83.69,17.28 83.86,17.44 84.54,17.44 84.71,17.61 84.71,17.94 84.54,18.1 83.86,18.1 83.69,18.27 83.69,18.6 83.86,18.76 84.54,18.76 84.71,18.93 84.71,19.26 84.54,19.42 83.86,19.42 83.69,19.59 83.69,19.92 83.86,20.08 84.54,20.08 84.71,20.25 84.71,20.58 84.54,20.74 83.86,20.74 83.69,20.91 83.69,21.24 83.86,21.4 84.54,21.4 84.71,21.57 84.71,21.9 84.54,22.06 83.86,22.06 83.69,22.23 83.69,22.56 83.86,22.72 84.54,22.72 84.71,22.89 84.71,23.22 84.54,23.38 83.86,23.38 83.69,23.55 83.69,23.88 83.86,24.04 84.54,24.04 84.71,24.21 84.71,24.54 84.54,24.7 83.86,24.7 83.69,24.87 83.69,25.2 83.86,25.37 84.54,25.37 84.71,25.53 84.71,25.86 84.54,26.03 83.86,26.03 83.69,26.19 83.69,26.52 83.86,26.69 84.54,26.69 84.71,26.85 84.71,27.18 84.54,27.35 83.86,27.35 83.69,27.51 83.69,27.84 83.86,28.01 84.54,28.01 84.71,28.17 84.71,28.5 84.54,28.67 83.86,28.67 83.69,28.83 83.69,29.16 84.2,29.67 84.2,38.23 87.25,41.27 98.3,41.27 104.27,47.24 123.83,47.24 131.19,54.61 131.19,59.05 131.44,59.31 131.44,65.3 132.05,65.91 132.05,77.44 v1(132.21,77.6)
CMOS_PORT1_18: length 140
  TOP w0.165: U5.C17 v2(122.95,77.2)
  L9-SIG3 w0.102: v2(122.95,77.2) 123.06,77.09 123.06,77.09
  L9-SIG3 w0.114: v1(131.19,76.71) 131.09,76.81 124.58,76.81 124.31,77.09 123.06,77.09
  BOTTOM w0.165: v1(131.19,76.71) 131.19,76.83 130.81,76.45 130.81,68.73 131.24,68.3 131.24,66.7 130.56,66.01 130.56,59.69 129.54,58.67 129.54,54.23 126.17,50.86 126.17,50.55 124.97,49.34 124.65,49.34 123.32,48.01 103.12,48.01 97.41,42.29 85.34,42.29 81.92,38.86 81.92,24.82 82.19,24.54 82.38,24.54 82.55,24.38 82.55,24.05 82.38,23.88 81.45,23.88 81.28,23.72 81.28,23.39 81.45,23.22 82.38,23.22 82.55,23.06 82.55,22.73 82.38,22.56 81.45,22.56 81.28,22.4 81.28,22.07 81.45,21.9 82.38,21.9 82.55,21.74 82.55,21.41 82.38,21.24 81.45,21.24 81.28,21.08 81.28,20.75 81.45,20.58 82.38,20.58 82.55,20.41 82.55,20.08 82.38,19.92 81.45,19.92 81.28,19.75 81.28,19.42 81.45,19.26 82.38,19.26 82.55,19.09 82.55,18.76 82.38,18.6 81.45,18.6 81.28,18.43 81.28,18.1 81.45,17.94 82.38,17.94 82.55,17.77 82.55,17.44 82.38,17.28 81.45,17.28 81.28,17.11 81.28,16.78 81.45,16.62 82.38,16.62 82.55,16.45 82.55,16.12 82.38,15.96 81.45,15.96 81.28,15.79 81.28,15.46 81.45,15.3 82.38,15.3 82.55,15.13 82.55,14.8 82.38,14.64 81.45,14.64 81.28,14.47 81.28,14.14 81.45,13.98 82.38,13.98 82.55,13.81 82.55,13.48 82.38,13.32 81.45,13.32 81.28,13.15 81.28,12.82 81.45,12.66 82.38,12.66 82.55,12.49 82.55,12.16 82.38,11.99 81.45,11.99 81.28,11.83 81.28,11.5 81.45,11.33 82.38,11.33 82.55,11.17 82.55,10.79 81.92,10.16 81.92,8.13
CMOS_PORT1_19: length 140
  TOP w0.165: U5.A14 v2(124.95,80.2)
  L9-SIG3 w0.102: v2(124.95,80.2) 125.03,80.2
  L9-SIG3 w0.114: 125.03,80.2 125.73,80.9 v1(133.1,80.9)
  BOTTOM w0.165: 79.38,8.13 79.38,10.08 80.14,10.84 80.14,11.17 79.97,11.33 78.78,11.33 78.61,11.5 78.61,11.83 78.78,11.99 79.97,11.99 80.14,12.16 80.14,12.49 79.97,12.66 78.78,12.66 78.61,12.82 78.61,13.15 78.78,13.32 79.97,13.32 80.14,13.48 80.14,13.81 79.97,13.98 78.78,13.98 78.61,14.14 78.61,14.47 78.78,14.64 79.97,14.64 80.14,14.8 80.14,15.13 79.97,15.3 78.78,15.3 78.61,15.46 78.61,15.79 78.78,15.96 79.97,15.96 80.14,16.12 80.14,16.45 79.97,16.62 78.78,16.62 78.61,16.78 78.61,17.11 78.78,17.28 79.97,17.28 80.14,17.44 80.14,17.77 79.97,17.94 78.78,17.94 78.61,18.1 78.61,18.43 78.78,18.6 79.21,18.6 79.38,18.76 79.38,39.24 83.52,43.38 96.77,43.38 102.16,48.77 122.94,48.77 125.73,51.56 125.73,52.32 126.75,53.34 127.38,53.34 128.78,54.74 128.78,59.69 129.16,60.07 129.16,64.14 129.79,64.77 129.79,70.87 130.05,71.12 130.05,77.85 v1(133.1,80.9)
CMOS_PORT1_20: length 140.1
  TOP w0.165: U5.A31 124.45,62.73 124.92,63.2 v2(124.95,63.2)
  BOTTOM w0.165: 76.83,8.13 76.83,10.23 77.47,10.86 77.47,11.19 77.3,11.36 76.37,11.36 76.2,11.52 76.2,11.85 76.37,12.02 77.3,12.02 77.47,12.18 77.47,12.51 77.3,12.68 76.37,12.68 76.2,12.84 76.2,13.17 76.37,13.34 77.3,13.34 77.47,13.5 77.47,13.84 77.3,14 76.37,14 76.2,14.17 76.2,14.5 76.37,14.66 77.3,14.66 77.47,14.83 77.47,15.16 77.3,15.32 76.37,15.32 76.2,15.49 76.2,15.82 76.37,15.98 77.3,15.98 77.47,16.15 77.47,16.48 77.3,16.64 76.37,16.64 76.2,16.81 76.2,17.14 76.37,17.3 77.3,17.3 77.47,17.47 77.47,17.8 77.3,17.96 76.37,17.96 76.2,18.13 76.2,18.46 76.37,18.62 77.3,18.62 77.47,18.79 77.47,19.12 77.3,19.28 76.37,19.28 76.2,19.45 76.2,19.78 76.37,19.94 77.3,19.94 77.47,20.11 77.47,20.44 77.3,20.6 76.37,20.6 76.2,20.77 76.2,21.1 76.37,21.26 77.3,21.26 77.47,21.43 77.47,21.76 77.3,21.92 76.37,21.92 76.2,22.09 76.2,22.42 76.37,22.59 77.3,22.59 77.47,22.75 77.47,23.08 77.3,23.25 76.37,23.25 76.2,23.41 76.2,23.74 76.37,23.91 77.3,23.91 77.47,24.07 77.47,24.4 77.3,24.57 76.37,24.57 76.2,24.73 76.2,25.06 76.37,25.23 77.3,25.23 77.47,25.39 77.47,25.72 77.3,25.89 76.37,25.89 76.2,26.05 76.2,26.38 76.37,26.55 77.3,26.55 77.47,26.71 77.47,27.04 77.3,27.21 76.37,27.21 76.2,27.37 76.2,27.7 76.37,27.87 77.3,27.87 77.47,28.03 77.47,28.36 77.3,28.53 76.37,28.53 76.2,28.69 76.2,29.02 76.37,29.19 77.3,29.19 77.47,29.35 77.47,29.68 77.3,29.85 76.37,29.85 76.2,30.01 76.2,30.35 76.37,30.51 77.3,30.51 77.47,30.68 77.47,31.01 77.3,31.17 76.37,31.17 76.2,31.34 76.2,31.67 76.37,31.83 77.3,31.83 77.47,32 77.47,32.33 77.3,32.49 76.37,32.49 76.2,32.66 76.2,32.99 76.37,33.15 77.3,33.15 77.47,33.32 77.47,33.65 77.3,33.81 76.37,33.81 76.2,33.98 76.2,34.31 76.37,34.47 77.3,34.47 77.47,34.64 77.47,34.97 77.3,35.13 76.37,35.13 76.2,35.3 76.2,35.63 76.37,35.79 77.3,35.79 77.47,35.96 77.47,36.29 77.3,36.45 76.61,36.45 76.37,36.7 76.37,37.11 76.83,37.58 76.83,41.53 79.78,44.48 96.14,44.48 101.19,49.53 121.67,49.53 124.95,52.81 124.95,56.06 125.6,56.71 125.6,62.55 v2(124.95,63.2)
CMOS_PORT1_21: length 140
  TOP w0.165: U5.B30 v2(123.95,63.2)
  BOTTOM w0.165: v2(123.95,63.2) 124,63.2 124.71,62.48 124.71,57.78 124.02,57.09 124.02,53.15 121.03,50.16 100.08,50.16 95.5,45.59 77.85,45.59 74.3,42.04 74.3,35.56 73.88,35.14 73.83,35.14 73.66,34.98 73.66,34.65 73.83,34.48 74.76,34.48 74.93,34.32 74.93,33.99 74.76,33.82 73.83,33.82 73.66,33.66 73.66,33.33 73.83,33.16 74.76,33.16 74.93,33 74.93,32.67 74.76,32.5 73.83,32.5 73.66,32.34 73.66,32.01 73.83,31.84 74.76,31.84 74.93,31.68 74.93,31.35 74.76,31.18 73.83,31.18 73.66,31.02 73.66,30.69 73.83,30.52 74.76,30.52 74.93,30.36 74.93,30.03 74.76,29.86 73.83,29.86 73.66,29.7 73.66,29.36 73.83,29.2 74.76,29.2 74.93,29.03 74.93,28.7 74.76,28.54 73.83,28.54 73.66,28.37 73.66,28.04 73.83,27.88 74.76,27.88 74.93,27.71 74.93,27.38 74.76,27.22 73.83,27.22 73.66,27.05 73.66,26.72 73.83,26.56 74.76,26.56 74.93,26.39 74.93,26.06 74.76,25.9 73.83,25.9 73.66,25.73 73.66,25.4 73.83,25.24 74.76,25.24 74.93,25.07 74.93,24.74 74.76,24.58 73.83,24.58 73.66,24.41 73.66,24.08 73.83,23.92 74.76,23.92 74.93,23.75 74.93,23.42 74.76,23.26 73.83,23.26 73.66,23.09 73.66,22.76 73.83,22.6 74.76,22.6 74.93,22.43 74.93,22.1 74.76,21.94 73.83,21.94 73.66,21.77 73.66,21.44 73.83,21.28 74.76,21.28 74.93,21.11 74.93,20.78 74.76,20.61 73.83,20.61 73.66,20.45 73.66,20.12 73.83,19.95 74.76,19.95 74.93,19.79 74.93,19.46 74.76,19.29 73.83,19.29 73.66,19.13 73.66,18.8 73.83,18.63 74.76,18.63 74.93,18.47 74.93,18.14 74.76,17.97 73.83,17.97 73.66,17.81 73.66,17.48 73.83,17.31 74.76,17.31 74.93,17.15 74.93,16.82 74.76,16.65 73.83,16.65 73.66,16.49 73.66,16.16 73.83,15.99 74.76,15.99 74.93,15.83 74.93,15.5 74.76,15.33 73.83,15.33 73.66,15.17 73.66,14.84 73.83,14.67 74.76,14.67 74.93,14.51 74.93,14.18 74.76,14.01 73.83,14.01 73.66,13.85 73.66,13.52 73.83,13.35 74.76,13.35 74.93,13.19 74.93,12.85 74.76,12.69 73.83,12.69 73.66,12.52 73.66,12.19 73.83,12.03 74.76,12.03 74.93,11.86 74.93,11.53 74.76,11.37 73.83,11.37 73.66,11.2 73.66,10.87 73.83,10.71 74.76,10.71 74.93,10.54 74.93,10.21 74.3,9.58 74.3,8.13
CMOS_SP1: length 89.4
  TOP w0.178: U5.A10 v2(124.95,84.2) ; J4.26 v1(201.55,98.17)
  L9-SIG3 w0.102: 125.35,84.2 v2(124.95,84.2)
  L9-SIG3 w0.178: v1(201.55,98.17) 202.44,98.17 203.2,97.41 203.2,95.89 202.56,95.25 202.06,95.25 201.42,95.89 192.41,95.89 189.99,93.47 178.82,93.47 177.93,92.58 140.34,92.58 139.7,91.95 137.41,91.95 133.48,88.01 131.95,88.01 128.14,84.2 125.35,84.2
CMOS_SP2: length 87.4
  TOP w0.178: J4.28 v1(198.38,97.67) ; U5.A11 v2(124.95,83.2)
  BOTTOM w0.178: v2(124.95,83.2) 124.46,83.69 124.46,84.45 125.22,85.22 126.24,85.22 129.79,88.77 145.67,88.77 146.3,89.41 160.91,89.41 163.7,86.61 190.5,86.61 194.94,91.06 194.94,94.36 198.25,97.67 v1(198.38,97.67)
CMOS_SP3: length 87.1
  TOP w0.178: J4.38 v1(201.5,95.17) ; U5.A12 v2(124.95,82.2)
  BOTTOM w0.178: v2(124.95,82.2) 125,82.2 125.37,82.57 125.37,83.46 129.92,88.01 146.18,88.01 146.81,88.65 160.4,88.65 163.19,85.85 191.01,85.85 200.41,95.25 201.42,95.25 v1(201.5,95.17)
CMOS_SP4: length 106
  TOP w0.178: J4.40 v1(198.43,94.67) ; U5.A13 v2(124.95,81.2)
  L10-SIG4 w0.102: v2(124.95,81.2) 125.35,81.2
  L10-SIG4 w0.178: v1(198.43,94.67) 198.86,94.23 202.95,94.23 204.09,93.09 204.09,79.5 203.45,78.87 202.44,78.87 202.06,78.49 201.04,78.49 198.63,80.9 195.2,80.9 192.41,83.69 185.55,83.69 183.13,81.28 145.92,81.28 144.65,82.55 131.95,82.55 130.6,81.2 125.35,81.2
CMOS_SP5: length 81.4
  TOP w0.178: U5.A4 v2(124.95,90.2) ; J4.46 v1(201.5,93.17)
  L10-SIG4 w0.102: v2(124.95,90.2) 125.35,90.2
  L10-SIG4 w0.178: 125.35,90.2 126.52,90.2 128.4,92.08 134.75,92.08 137.29,94.61 187.32,94.61 188.34,93.6 195.96,93.6 196.6,92.96 201.29,92.96 v1(201.5,93.17)
CMOS_SP6: length 79.5
  TOP w0.178: U5.A6 v2(125.6,87.7) ; J4.50 v1(198.41,92.17)
  L10-SIG4 w0.178: v2(125.6,87.7) 125.6,88.27 126.36,89.03 128.52,89.03 130.94,91.44 135.25,91.44 137.92,94.11 186.69,94.11 188.34,92.46 191.77,92.46 192.28,91.95 198.19,91.95 v1(198.41,92.17)
CMOS_SP7: length 83.4
  TOP w0.178: J4.52 v1(201.52,91.67) ; U5.A7 v2(124.95,87.2)
  L10-SIG4 w0.102: 125.35,87.2 v2(124.95,87.2)
  L10-SIG4 w0.178: 125.35,87.2 127.84,87.2 130.94,90.3 134.87,90.3 138.05,93.47 141.48,93.47 141.99,92.96 170.05,92.96 170.56,93.47 186.31,93.47 188.98,90.81 192.45,90.81 192.51,90.74 192.88,90.74 192.94,90.81 200.66,90.81 v1(201.52,91.67)
CPU_RESET: length 30.2
  TOP w0.178: v1(135.13,78.99) 135.13,83.95 135.64,84.45 135.64,96.65 R103.1 ; U5.A17 v2(124.95,77.2)
  L4-SIG2 w0.178: v1(135.13,78.99) 134.24,78.11 129.41,78.11 129.03,77.72 125.87,77.72 125.35,77.2 v2(124.95,77.2)
DA0N: length 135.4
  TOP w0.114: U5.AB26 v2(102.95,67.2) ; v1(191.26,52.99) 191.54,53.27 194.13,53.27 J4.165
  L4-SIG2 w0.102: v1(191.26,52.99) 191.05,53.21 190.3,53.21 190.01,52.92 187.49,52.92 187.39,52.82 187.39,51.83 187.13,51.56 186.69,51.56 186.43,51.83 186.43,52.82 186.32,52.92 186.12,52.92 186.02,52.82 186.02,51.83 185.75,51.56 185.32,51.56 185.05,51.83 185.05,52.82 184.95,52.92 184.75,52.92 184.65,52.82 184.65,51.83 184.38,51.56 183.95,51.56 183.68,51.83 183.68,52.82 183.58,52.92 183.38,52.92 183.28,52.82 183.28,51.83 183.01,51.56 182.58,51.56 182.31,51.83 182.31,52.82 182.21,52.92 182.01,52.92 181.9,52.82 181.9,51.83 181.64,51.56 181.2,51.56 180.94,51.83 180.94,52.82 180.84,52.92 180.63,52.92 180.53,52.82 180.53,51.83 180.27,51.56 179.83,51.56 179.57,51.83 179.57,52.82 179.47,52.92 179.26,52.92 179.16,52.82 179.16,51.83 178.9,51.56 178.46,51.56 178.2,51.83 178.2,52.82 178.09,52.92 177.89,52.92 177.79,52.82 177.79,51.83 177.52,51.56 177.09,51.56 176.82,51.83 176.82,52.82 176.72,52.92 176.52,52.92 176.42,52.82 176.42,51.83 176.15,51.56 175.72,51.56 175.45,51.83 175.45,52.82 175.35,52.92 175.15,52.92 175.05,52.82 175.05,51.83 174.78,51.56 174.35,51.56 174.08,51.83 174.08,52.82 173.98,52.92 173.78,52.92 173.67,52.82 173.67,51.83 173.41,51.56 172.97,51.56 172.71,51.83 172.71,52.82 172.61,52.92 172.4,52.92 172.3,52.82 172.3,51.83 172.04,51.56 171.6,51.56 171.34,51.83 171.34,52.82 171.24,52.92 170.52,52.92 168.34,55.09 165.74,55.09 163.47,52.83 158.23,52.83 157.08,53.98 155.72,53.98 154.45,52.7 131.06,52.7 130.81,52.96 124.97,52.96 121.28,56.64 121.28,59 121.33,59.04 121.33,59.36 121.28,59.4 121.28,60 121.33,60.04 121.33,60.36 121.11,60.58 104.55,60.58 103.33,61.8 103.33,67.28 103.03,67.58 102.77,67.58 102.56,67.37 102.56,67.11 102.64,67.03 102.78,67.03 v2(102.95,67.2)
DA0P: length 135.5
  TOP w0.114: U5.AC25 v2(101.95,68.2) ; v1(191.26,53.81) 191.52,53.55 194.13,53.55 J4.163
  L4-SIG2 w0.102: v1(191.26,53.81) 191.26,53.8 190.95,53.49 190.18,53.49 189.89,53.2 187.38,53.2 187.11,52.93 187.11,51.94 187.01,51.84 186.81,51.84 186.7,51.94 186.7,52.93 186.44,53.2 186,53.2 185.74,52.93 185.74,51.94 185.64,51.84 185.43,51.84 185.33,51.94 185.33,52.93 185.07,53.2 184.63,53.2 184.37,52.93 184.37,51.94 184.27,51.84 184.06,51.84 183.96,51.94 183.96,52.93 183.7,53.2 183.26,53.2 183,52.93 183,51.94 182.89,51.84 182.69,51.84 182.59,51.94 182.59,52.93 182.32,53.2 181.89,53.2 181.62,52.93 181.62,51.94 181.52,51.84 181.32,51.84 181.22,51.94 181.22,52.93 180.95,53.2 180.52,53.2 180.25,52.93 180.25,51.94 180.15,51.84 179.95,51.84 179.85,51.94 179.85,52.93 179.58,53.2 179.15,53.2 178.88,52.93 178.88,51.94 178.78,51.84 178.58,51.84 178.47,51.94 178.47,52.93 178.21,53.2 177.77,53.2 177.51,52.93 177.51,51.94 177.41,51.84 177.2,51.84 177.1,51.94 177.1,52.93 176.84,53.2 176.4,53.2 176.14,52.93 176.14,51.94 176.04,51.84 175.83,51.84 175.73,51.94 175.73,52.93 175.47,53.2 175.03,53.2 174.77,52.93 174.77,51.94 174.66,51.84 174.46,51.84 174.36,51.94 174.36,52.93 174.09,53.2 173.66,53.2 173.39,52.93 173.39,51.94 173.29,51.84 173.09,51.84 172.99,51.94 172.99,52.93 172.72,53.2 172.29,53.2 172.02,52.93 172.02,51.94 171.92,51.84 171.72,51.84 171.62,51.94 171.62,52.93 171.35,53.2 170.64,53.2 168.46,55.37 165.62,55.37 163.36,53.11 158.34,53.11 157.1,54.36 155.7,54.36 154.33,52.98 131.18,52.98 130.93,53.24 125.08,53.24 121.56,56.76 121.56,58.41 121.52,58.45 121.52,58.9 121.57,58.94 121.57,59.46 121.52,59.5 121.52,59.9 121.57,59.94 121.57,60.46 121.21,60.82 104.65,60.82 103.57,61.9 103.57,67.38 103.13,67.82 102.66,67.82 102.27,68.2 v2(101.95,68.2)
DA1N: length 135.4
  TOP w0.114: U5.AA27 v2(103.95,66.2) ; v1(192.41,54.5) 192.68,54.77 194.13,54.77 J4.159
  L10-SIG4 w0.102: v2(103.95,66.2) 103.95,66.37 104.07,66.49 104.21,66.49 104.33,66.37 104.33,58.75 105.32,57.76 122.06,57.76 125.08,54.74 127.38,54.74 128.16,53.96 133.69,53.96 133.96,54.23 133.96,55.21 134.06,55.32 134.26,55.32 134.36,55.21 134.36,54.23 134.63,53.96 135.06,53.96 135.33,54.23 135.33,55.21 135.43,55.32 135.63,55.32 135.74,55.21 135.74,54.23 136,53.96 136.44,53.96 136.7,54.23 136.7,55.21 136.8,55.32 137.01,55.32 137.11,55.21 137.11,54.23 137.37,53.96 137.81,53.96 138.07,54.23 138.07,55.21 138.17,55.32 138.38,55.32 138.48,55.21 138.48,54.23 138.74,53.96 139.18,53.96 139.44,54.23 139.44,55.21 139.55,55.32 139.75,55.32 139.85,55.21 139.85,54.23 140.12,53.96 140.55,53.96 140.82,54.23 140.82,55.21 140.92,55.32 141.12,55.32 141.22,55.21 141.22,54.23 141.49,53.96 141.92,53.96 142.19,54.23 142.19,55.21 142.29,55.32 142.49,55.32 142.59,55.21 142.59,54.23 142.86,53.96 143.29,53.96 143.56,54.23 143.56,55.21 143.66,55.32 143.86,55.32 143.97,55.21 143.97,54.23 144.23,53.96 144.67,53.96 144.93,54.23 144.93,55.21 145.03,55.32 145.24,55.32 145.34,55.21 145.34,54.23 145.6,53.96 146.04,53.96 146.3,54.23 146.3,55.21 146.4,55.32 146.61,55.32 146.71,55.21 146.71,54.23 146.97,53.96 147.41,53.96 147.67,54.23 147.67,55.21 147.78,55.32 147.98,55.32 148.08,55.21 148.08,54.23 148.35,53.96 148.78,53.96 149.05,54.23 149.05,55.21 149.15,55.32 149.35,55.32 149.45,55.21 149.45,54.23 149.72,53.96 150.15,53.96 150.42,54.23 150.42,55.21 150.52,55.32 150.72,55.32 150.82,55.21 150.82,54.23 151.09,53.96 151.52,53.96 151.79,54.23 151.79,55.21 151.89,55.32 152.09,55.32 152.2,55.21 152.2,54.23 152.46,53.96 152.89,53.96 153.16,54.23 153.16,55.21 153.26,55.32 153.47,55.32 153.57,55.21 153.57,54.71 154.31,53.96 164.7,53.96 165.5,54.76 192.14,54.76 v1(192.41,54.5)
DA1P: length 135.4
  TOP w0.114: v1(192.41,55.32) 192.68,55.05 194.13,55.05 J4.157 ; U5.AA26 v2(103.95,67.2)
  L10-SIG4 w0.102: v2(103.95,67.2) 103.95,67.09 104.57,66.47 104.57,58.85 104.95,58.46 105.01,58.46 105.44,58.04 122.17,58.04 125.2,55.02 127.5,55.02 128.27,54.24 133.58,54.24 133.68,54.34 133.68,55.33 133.94,55.6 134.38,55.6 134.64,55.33 134.64,54.34 134.75,54.24 134.95,54.24 135.05,54.34 135.05,55.33 135.32,55.6 135.75,55.6 136.02,55.33 136.02,54.34 136.12,54.24 136.32,54.24 136.42,54.34 136.42,55.33 136.69,55.6 137.12,55.6 137.39,55.33 137.39,54.34 137.49,54.24 137.69,54.24 137.79,54.34 137.79,55.33 138.06,55.6 138.49,55.6 138.76,55.33 138.76,54.34 138.86,54.24 139.06,54.24 139.16,54.34 139.16,55.33 139.43,55.6 139.86,55.6 140.13,55.33 140.13,54.34 140.23,54.24 140.43,54.24 140.54,54.34 140.54,55.33 140.8,55.6 141.24,55.6 141.5,55.33 141.5,54.34 141.6,54.24 141.81,54.24 141.91,54.34 141.91,55.33 142.17,55.6 142.61,55.6 142.87,55.33 142.87,54.34 142.97,54.24 143.18,54.24 143.28,54.34 143.28,55.33 143.54,55.6 143.98,55.6 144.24,55.33 144.24,54.34 144.35,54.24 144.55,54.24 144.65,54.34 144.65,55.33 144.92,55.6 145.35,55.6 145.62,55.33 145.62,54.34 145.72,54.24 145.92,54.24 146.02,54.34 146.02,55.33 146.29,55.6 146.72,55.6 146.99,55.33 146.99,54.34 147.09,54.24 147.29,54.24 147.39,54.34 147.39,55.33 147.66,55.6 148.09,55.6 148.36,55.33 148.36,54.34 148.46,54.24 148.66,54.24 148.77,54.34 148.77,55.33 149.03,55.6 149.47,55.6 149.73,55.33 149.73,54.34 149.83,54.24 150.04,54.24 150.14,54.34 150.14,55.33 150.4,55.6 150.84,55.6 151.1,55.33 151.1,54.34 151.2,54.24 151.41,54.24 151.51,54.34 151.51,55.33 151.77,55.6 152.21,55.6 152.47,55.33 152.47,54.34 152.58,54.24 152.78,54.24 152.88,54.34 152.88,55.33 153.15,55.6 153.58,55.6 153.85,55.33 153.85,54.82 154.43,54.24 164.58,54.24 165.38,55.04 192.12,55.04 v1(192.41,55.32)
DA2N: length 135.4
  TOP w0.114: J4.153 194.13,56.27 191.54,56.27 v1(191.26,55.99) ; U5.Y25 v2(104.95,68.2)
  L4-SIG2 w0.102: v1(191.26,55.99) 191.05,56.21 191.03,56.18 189.4,56.18 189.01,55.79 189.01,55.71 188.27,54.97 186.96,54.97 186.85,54.87 186.85,54.49 186.59,54.22 186.15,54.22 185.89,54.49 185.89,55.63 185.79,55.73 185.58,55.73 185.48,55.63 185.48,54.49 185.22,54.22 184.78,54.22 184.52,54.49 184.52,55.63 184.42,55.73 184.21,55.73 184.11,55.63 184.11,54.49 183.85,54.22 183.41,54.22 183.15,54.49 183.15,55.63 183.04,55.73 182.84,55.73 182.74,55.63 182.74,54.49 182.47,54.22 182.04,54.22 181.77,54.49 181.77,55.63 181.67,55.73 181.47,55.73 181.37,55.63 181.37,54.49 181.1,54.22 180.67,54.22 180.4,54.49 180.4,55.63 180.3,55.73 180.1,55.73 180,55.63 180,54.49 179.73,54.22 179.3,54.22 179.03,54.49 179.03,55.63 178.93,55.73 178.73,55.73 178.63,55.63 178.63,54.49 178.36,54.22 177.93,54.22 177.66,54.49 177.66,55.63 177.56,55.73 177.36,55.73 177.25,55.63 177.25,54.49 176.99,54.22 176.55,54.22 176.29,54.49 176.29,55.63 176.19,55.73 175.98,55.73 175.88,55.63 175.88,54.49 175.62,54.22 175.18,54.22 174.92,54.49 174.92,55.63 174.82,55.73 174.61,55.73 174.51,55.63 174.51,54.49 174.25,54.22 173.81,54.22 173.55,54.49 173.55,55.63 173.44,55.73 173.24,55.73 173.14,55.63 173.14,55.24 172.87,54.97 171.07,54.97 169.86,56.18 169.49,56.18 169.39,56.08 168.5,56.08 168.43,56.01 167.36,56.01 167.28,56.08 166.39,56.08 166.29,56.18 164.41,56.18 163.78,55.55 161.36,55.55 161.1,55.82 161.1,56.34 161,56.44 160.79,56.44 160.69,56.34 160.69,54.93 160.43,54.66 159.99,54.66 159.73,54.93 159.73,56.34 159.62,56.44 159.42,56.44 159.32,56.34 159.32,55.82 159.05,55.55 155.75,55.55 153.8,53.59 131.84,53.59 131.58,53.85 125.86,53.85 124.29,55.42 124.14,55.42 124.05,55.32 123.9,55.32 123.76,55.46 123.76,55.61 123.86,55.7 123.86,55.85 123.71,55.99 123.57,55.99 123.47,55.89 123.33,55.89 123.18,56.04 123.18,56.18 123.28,56.28 123.28,56.42 123.14,56.57 123,56.57 122.9,56.47 122.75,56.47 122.61,56.61 122.61,56.76 122.71,56.85 122.71,57 122.33,57.37 122.33,61.39 122.14,61.58 121.79,61.58 121.78,61.57 121.12,61.57 121.11,61.58 120.79,61.58 120.78,61.57 120.12,61.57 120.11,61.58 119.79,61.58 119.78,61.57 119.12,61.57 119.11,61.58 118.79,61.58 118.78,61.57 118.12,61.57 118.11,61.58 117.79,61.58 117.78,61.57 116.12,61.57 116.11,61.58 115.79,61.58 115.78,61.57 114.12,61.57 114.11,61.58 113.79,61.58 113.78,61.57 113.12,61.57 113.11,61.58 112.79,61.58 112.78,61.57 112.12,61.57 112.11,61.58 111.79,61.58 111.78,61.57 111.12,61.57 111.11,61.58 110.79,61.58 110.78,61.57 110.12,61.57 110.11,61.58 109.79,61.58 109.78,61.57 109.12,61.57 109.11,61.58 108.24,61.58 107.33,62.49 107.33,67.44 107.19,67.58 105.57,67.58 v2(104.95,68.2)
DA2P: length 135.5
  TOP w0.114: v1(191.26,56.82) 191.52,56.55 194.13,56.55 J4.151 ; U5.AA24 v2(103.95,69.2)
  L4-SIG2 w0.102: v1(191.26,56.82) 190.91,56.46 189.28,56.46 188.73,55.91 188.73,55.82 188.16,55.25 186.84,55.25 186.58,54.99 186.58,54.6 186.47,54.5 186.27,54.5 186.17,54.6 186.17,55.74 185.9,56.01 185.47,56.01 185.2,55.74 185.2,54.6 185.1,54.5 184.9,54.5 184.8,54.6 184.8,55.74 184.53,56.01 184.1,56.01 183.83,55.74 183.83,54.6 183.73,54.5 183.53,54.5 183.43,54.6 183.43,55.74 183.16,56.01 182.73,56.01 182.46,55.74 182.46,54.6 182.36,54.5 182.16,54.5 182.05,54.6 182.05,55.74 181.79,56.01 181.35,56.01 181.09,55.74 181.09,54.6 180.99,54.5 180.78,54.5 180.68,54.6 180.68,55.74 180.42,56.01 179.98,56.01 179.72,55.74 179.72,54.6 179.62,54.5 179.41,54.5 179.31,54.6 179.31,55.74 179.05,56.01 178.61,56.01 178.35,55.74 178.35,54.6 178.24,54.5 178.04,54.5 177.94,54.6 177.94,55.74 177.67,56.01 177.24,56.01 176.97,55.74 176.97,54.6 176.87,54.5 176.67,54.5 176.57,54.6 176.57,55.74 176.3,56.01 175.87,56.01 175.6,55.74 175.6,54.6 175.5,54.5 175.3,54.5 175.2,54.6 175.2,55.74 174.93,56.01 174.5,56.01 174.23,55.74 174.23,54.6 174.13,54.5 173.93,54.5 173.82,54.6 173.82,55.74 173.56,56.01 173.12,56.01 172.86,55.74 172.86,55.36 172.76,55.25 171.19,55.25 169.98,56.46 169.38,56.46 169.27,56.36 168.39,56.36 168.31,56.29 167.47,56.29 167.4,56.36 166.51,56.36 166.41,56.46 164.3,56.46 163.66,55.83 161.48,55.83 161.38,55.93 161.38,56.45 161.11,56.72 160.68,56.72 160.41,56.45 160.41,55.04 160.31,54.94 160.11,54.94 160.01,55.04 160.01,56.45 159.74,56.72 159.31,56.72 159.04,56.45 159.04,55.93 158.94,55.83 155.64,55.83 153.68,53.87 131.95,53.87 131.7,54.13 125.97,54.13 122.61,57.49 122.61,58.29 122.57,58.33 122.57,61.49 122.24,61.82 121.69,61.82 121.68,61.81 121.22,61.81 121.21,61.82 120.69,61.82 120.68,61.81 120.22,61.81 120.21,61.82 119.69,61.82 119.68,61.81 119.22,61.81 119.21,61.82 118.69,61.82 118.68,61.81 118.22,61.81 118.21,61.82 117.69,61.82 117.68,61.81 116.22,61.81 116.21,61.82 115.69,61.82 115.68,61.81 114.22,61.81 114.21,61.82 113.69,61.82 113.68,61.81 113.22,61.81 113.21,61.82 112.69,61.82 112.68,61.81 112.22,61.81 112.21,61.82 111.69,61.82 111.68,61.81 111.22,61.81 111.21,61.82 110.69,61.82 110.68,61.81 110.22,61.81 110.21,61.82 109.69,61.82 109.68,61.81 109.22,61.81 109.21,61.82 108.34,61.82 107.57,62.59 107.57,67.56 107.31,67.82 105.67,67.82 105.33,68.16 105.33,68.36 105.11,68.58 104.57,68.58 v2(103.95,69.2)
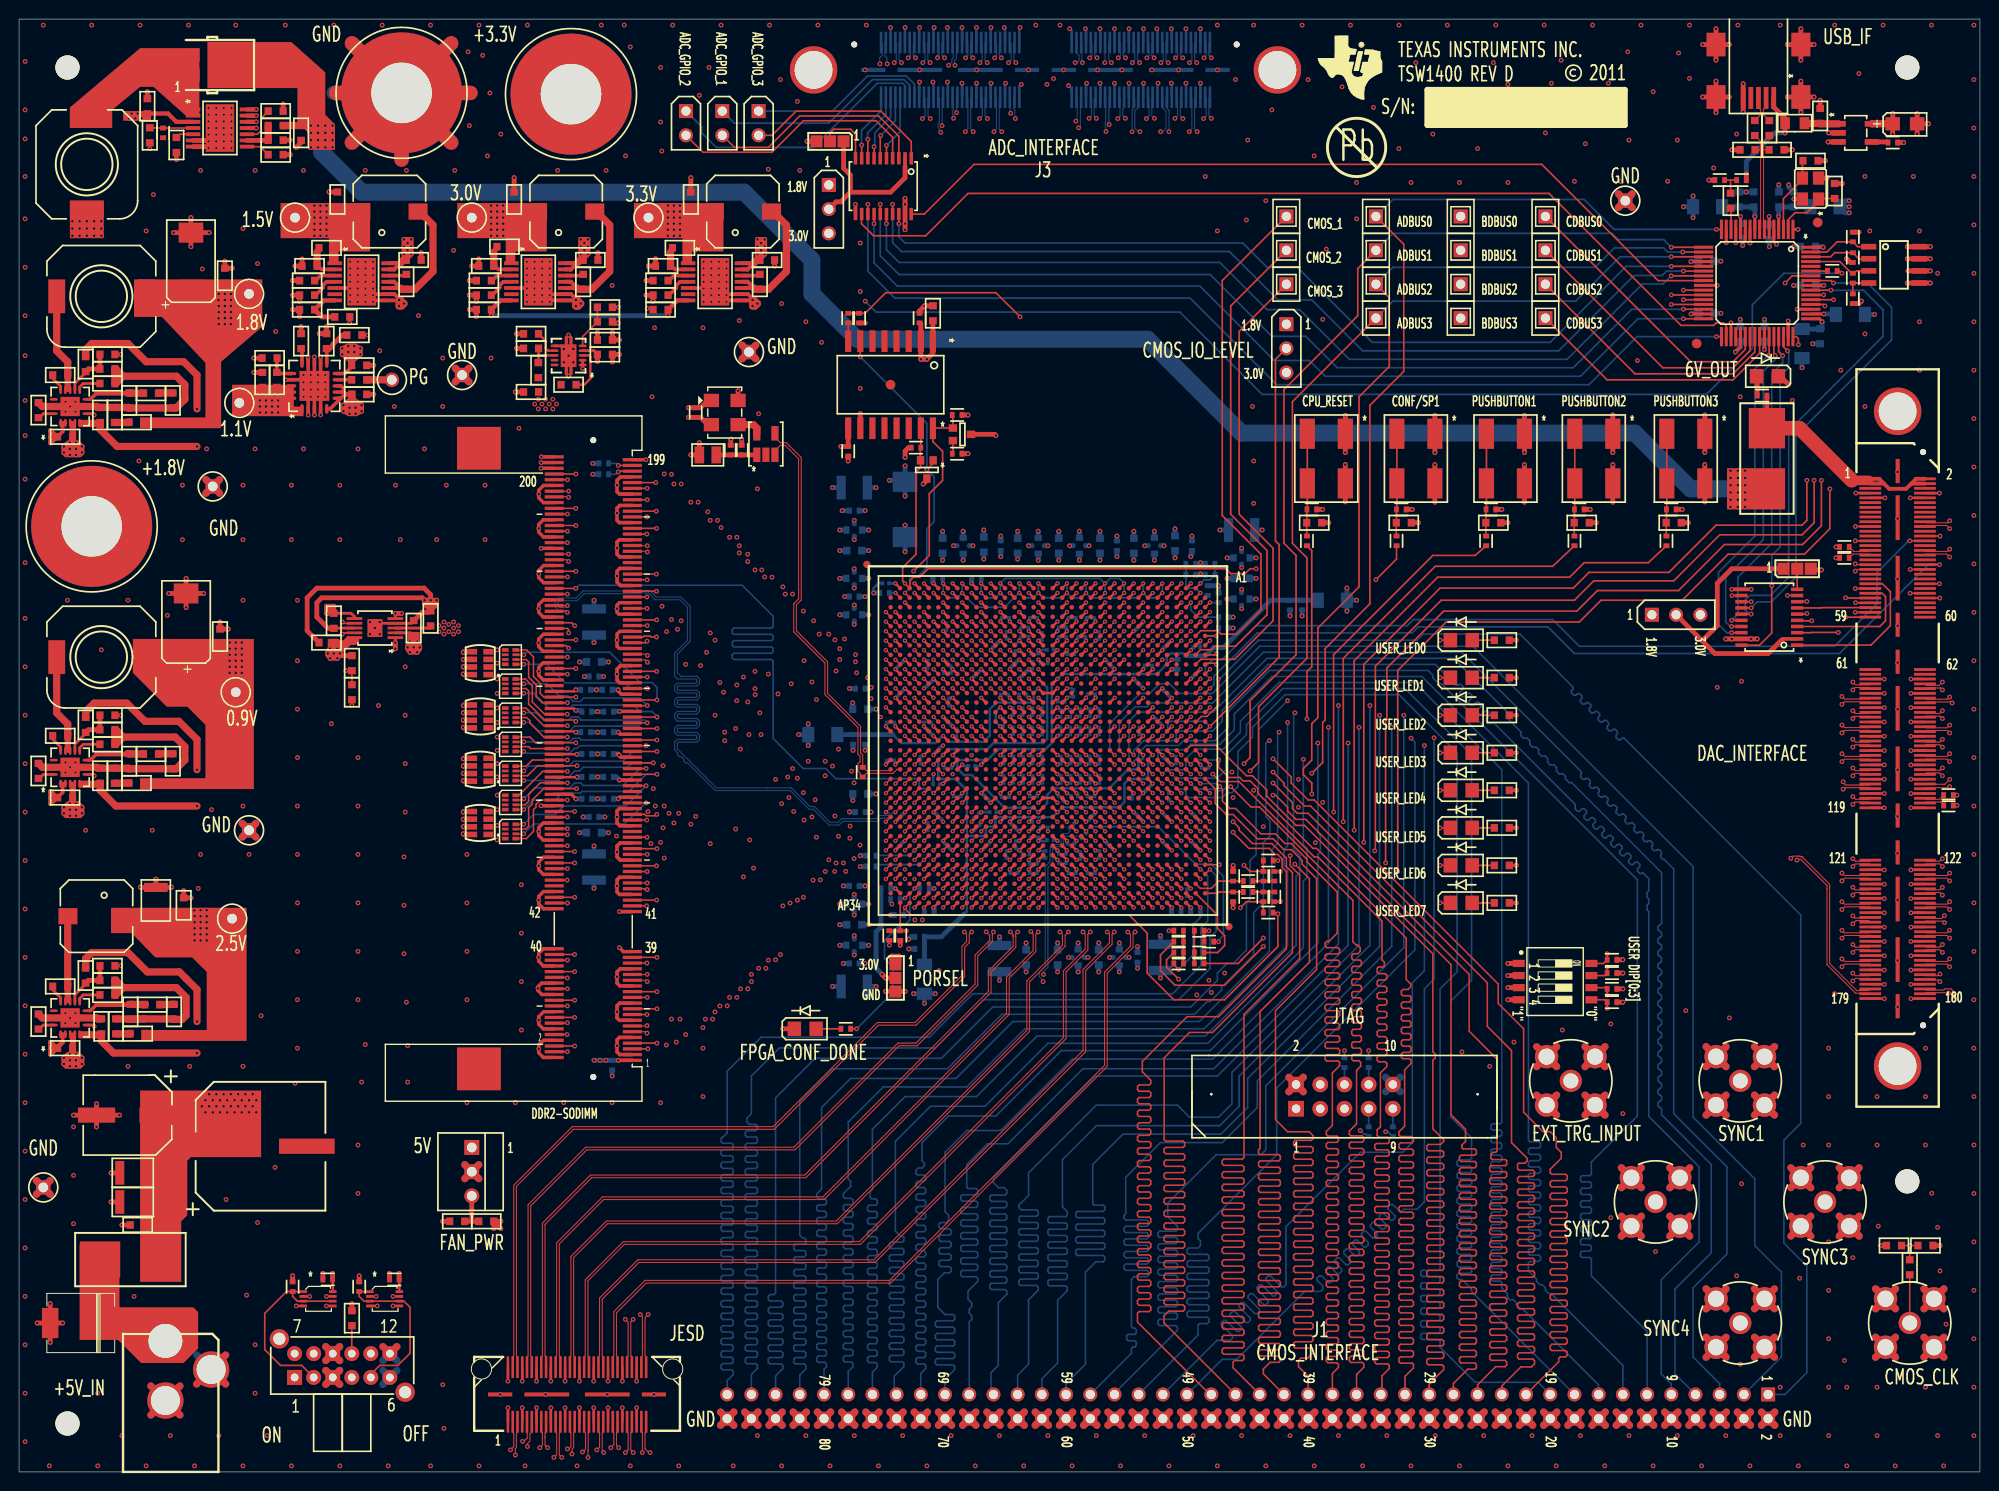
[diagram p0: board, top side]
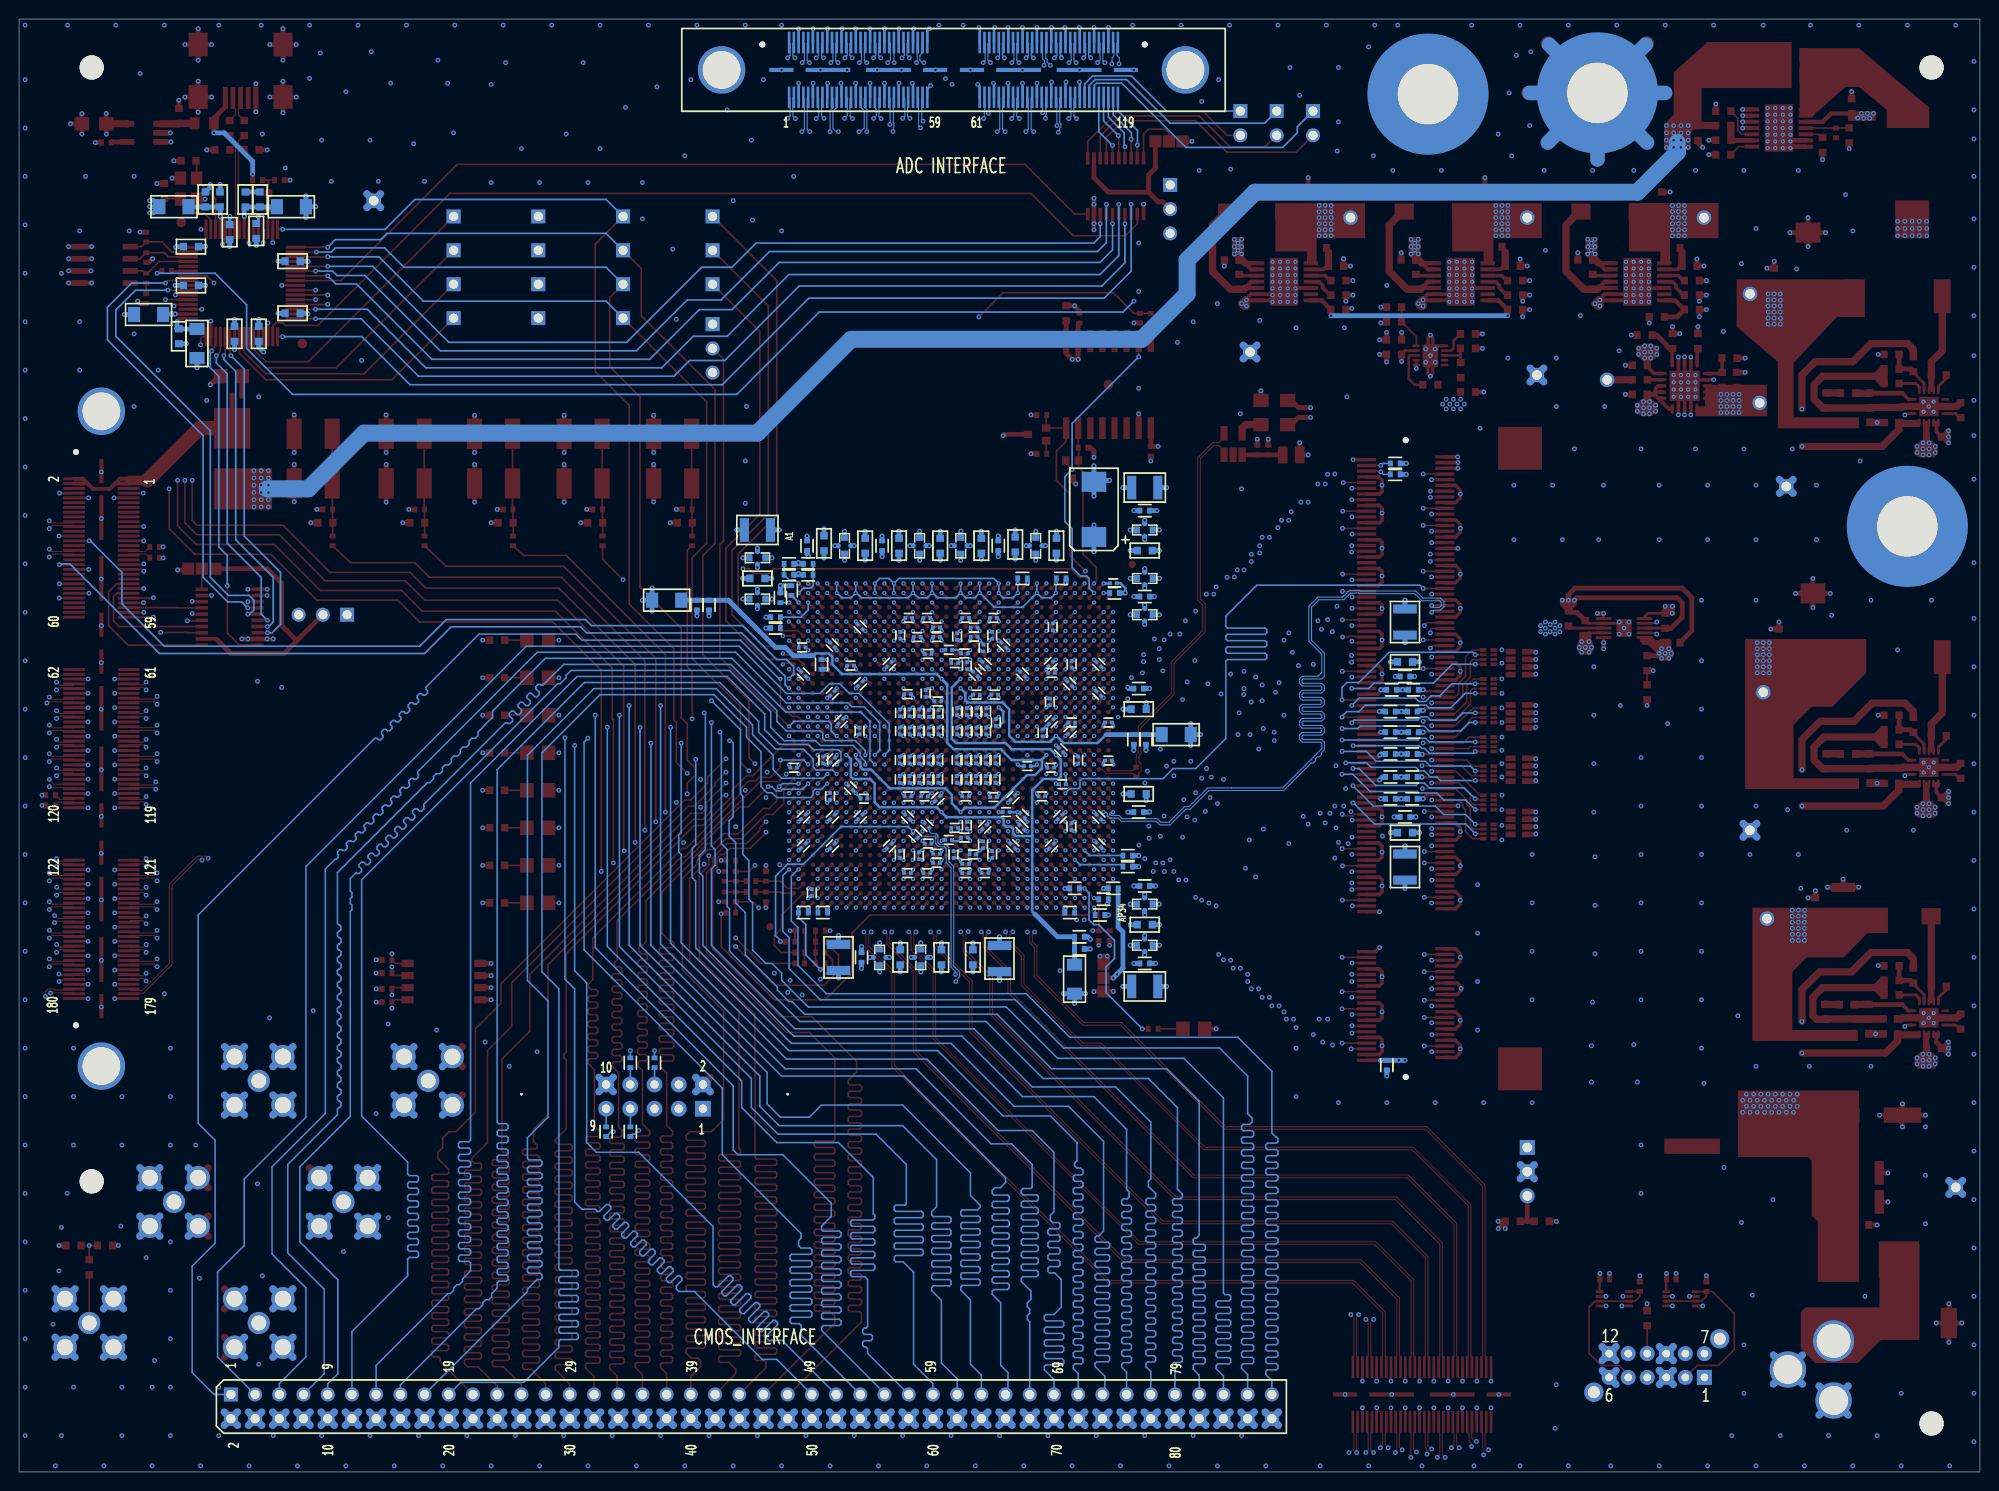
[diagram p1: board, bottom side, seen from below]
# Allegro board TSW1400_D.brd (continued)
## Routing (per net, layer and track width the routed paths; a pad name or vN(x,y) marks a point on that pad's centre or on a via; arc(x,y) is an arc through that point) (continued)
DA3N: length 135.5
  TOP w0.114: U5.Y24 v2(104.95,69.2) ; J4.147 194.08,57.83 192.73,57.83 v1(192.41,57.5)
  L4-SIG2 w0.102: v1(192.41,57.5) 192.15,57.76 187.35,57.76 187.07,58.04 187.07,58.8 186.97,58.9 186.76,58.9 186.66,58.8 186.66,56.88 186.4,56.62 185.96,56.62 185.7,56.88 185.7,58.8 185.59,58.9 185.39,58.9 185.29,58.8 185.29,56.88 185.02,56.62 184.59,56.62 184.32,56.88 184.32,58.8 184.22,58.9 184.02,58.9 183.92,58.8 183.92,56.88 183.65,56.62 183.22,56.62 182.95,56.88 182.95,58.8 182.85,58.9 182.65,58.9 182.55,58.8 182.55,56.88 182.28,56.62 181.85,56.62 181.58,56.88 181.58,58.8 181.48,58.9 181.28,58.9 181.17,58.8 181.17,56.88 180.91,56.62 180.47,56.62 180.21,56.88 180.21,58.8 180.11,58.9 179.9,58.9 179.8,58.8 179.8,56.88 179.54,56.62 179.1,56.62 178.84,56.88 178.84,58.8 178.74,58.9 178.53,58.9 178.43,58.8 178.43,56.88 178.17,56.62 177.73,56.62 177.47,56.88 177.47,58.8 177.36,58.9 177.16,58.9 177.06,58.8 177.06,58.02 176.79,57.76 171.77,57.76 171.5,58.02 171.5,58.83 171.4,58.93 171.2,58.93 171.1,58.83 171.1,58.02 170.83,57.76 168.97,57.76 168.28,58.45 167.08,58.45 166.39,57.76 158.55,57.76 157.43,56.64 154.45,56.64 152.64,54.84 132.6,54.84 130.69,56.74 126.26,56.74 124.48,58.53 124.48,59.46 123.46,60.48 123.46,61.35 122.23,62.58 121.69,62.58 121.69,62.59 121.21,62.59 121.21,62.58 120.69,62.58 120.69,62.59 120.21,62.59 120.21,62.58 119.69,62.58 119.69,62.59 119.21,62.59 119.21,62.58 118.69,62.58 118.69,62.59 118.21,62.59 118.21,62.58 117.69,62.58 117.69,62.59 116.21,62.59 116.21,62.58 115.69,62.58 115.69,62.59 115.21,62.59 115.21,62.58 114.69,62.58 114.69,62.59 114.21,62.59 114.21,62.58 113.69,62.58 113.69,62.59 113.21,62.59 113.21,62.58 112.69,62.58 112.69,62.59 112.21,62.59 112.21,62.58 111.69,62.58 111.69,62.59 111.21,62.59 111.21,62.58 110.69,62.58 110.69,62.59 110.21,62.59 110.21,62.58 109.69,62.58 109.69,62.59 109.21,62.59 109.21,62.58 108.61,62.58 108.32,62.87 108.32,67.03 108.33,67.04 108.33,67.36 108.32,67.37 108.32,67.52 107.27,68.57 107.12,68.57 107.11,68.58 105.69,68.58 105.33,68.94 105.33,69.48 105.19,69.62 105.04,69.62 104.95,69.53 v2(104.95,69.2)
DA3P: length 135.3
  TOP w0.114: v1(192.41,58.33) 192.62,58.11 194.16,58.11 194.21,58.17 J4.145 ; U5.Y23 v2(104.95,70.2)
  L4-SIG2 w0.102: v2(104.95,70.2) 104.95,70.14 105.23,69.86 105.29,69.86 105.57,69.58 105.57,69.04 105.79,68.82 107.21,68.82 107.22,68.81 107.37,68.81 108.56,67.62 108.56,67.47 108.57,67.46 108.57,66.94 108.56,66.93 108.56,62.97 108.71,62.82 108.79,62.82 108.79,62.82 109.11,62.82 109.11,62.82 109.79,62.82 109.79,62.82 110.11,62.82 110.11,62.82 110.79,62.82 110.79,62.82 111.11,62.82 111.11,62.82 111.79,62.82 111.79,62.82 112.11,62.82 112.11,62.82 112.79,62.82 112.79,62.82 113.11,62.82 113.11,62.82 113.79,62.82 113.79,62.82 114.11,62.82 114.11,62.82 114.79,62.82 114.79,62.82 115.11,62.82 115.11,62.82 115.79,62.82 115.79,62.82 116.11,62.82 116.11,62.82 117.79,62.82 117.79,62.82 118.11,62.82 118.11,62.82 118.79,62.82 118.79,62.82 119.11,62.82 119.11,62.82 119.79,62.82 119.79,62.82 120.11,62.82 120.11,62.82 120.79,62.82 120.79,62.82 121.11,62.82 121.11,62.82 121.79,62.82 121.79,62.82 122.33,62.82 123.7,61.45 123.7,60.58 124.71,59.56 124.71,58.63 124.85,58.49 124.91,58.49 126.38,57.02 130.81,57.02 132.72,55.12 152.53,55.12 154.31,56.92 157.31,56.92 158.43,58.04 166.27,58.04 166.97,58.73 168.39,58.73 169.09,58.04 170.72,58.04 170.82,58.14 170.82,58.94 171.08,59.21 171.52,59.21 171.78,58.94 171.78,58.14 171.88,58.04 176.68,58.04 176.78,58.14 176.78,58.92 177.05,59.18 177.48,59.18 177.75,58.92 177.75,57 177.85,56.9 178.05,56.9 178.15,57 178.15,58.92 178.42,59.18 178.85,59.18 179.12,58.92 179.12,57 179.22,56.9 179.42,56.9 179.52,57 179.52,58.92 179.79,59.18 180.22,59.18 180.49,58.92 180.49,57 180.59,56.9 180.79,56.9 180.9,57 180.9,58.92 181.16,59.18 181.6,59.18 181.86,58.92 181.86,57 181.96,56.9 182.17,56.9 182.27,57 182.27,58.92 182.53,59.18 182.97,59.18 183.23,58.92 183.23,57 183.33,56.9 183.54,56.9 183.64,57 183.64,58.92 183.9,59.18 184.34,59.18 184.6,58.92 184.6,57 184.71,56.9 184.91,56.9 185.01,57 185.01,58.92 185.28,59.18 185.71,59.18 185.98,58.92 185.98,57 186.08,56.9 186.28,56.9 186.38,57 186.38,58.92 186.65,59.18 187.08,59.18 187.35,58.92 187.35,58.17 187.47,58.04 188.09,58.04 188.21,58.17 188.47,58.17 188.59,58.04 192.12,58.04 v1(192.41,58.33)
DA4N: length 135.4
  TOP w0.114: J4.141 194.13,59.28 191.54,59.28 v1(191.26,59) ; U5.W23 v2(105.95,70.2)
  L10-SIG4 w0.102: v2(105.95,70.2) 105.56,70.2 105.48,70.29 105.48,70.46 105.6,70.58 106.2,70.58 106.33,70.45 106.33,70.04 106.13,69.84 105.71,69.84 105.33,69.46 105.33,64.04 105.33,61.92 105.33,59.94 105.69,59.58 125.19,59.58 126.43,58.34 127.74,57.03 137.21,57.03 138.34,58.16 140.58,58.16 141.71,57.03 149.16,57.03 150.53,58.4 150.74,58.4 150.84,58.3 150.84,57.29 151.1,57.03 151.54,57.03 151.8,57.29 151.8,58.3 151.9,58.4 152.11,58.4 152.21,58.3 152.21,57.29 152.47,57.03 152.91,57.03 153.17,57.29 153.17,58.3 153.28,58.4 153.48,58.4 153.58,58.3 153.58,57.29 153.85,57.03 154.28,57.03 154.55,57.29 154.55,58.3 154.65,58.4 154.85,58.4 154.95,58.3 154.95,57.29 155.22,57.03 155.65,57.03 155.92,57.29 155.92,58.3 156.02,58.4 156.22,58.4 156.32,58.3 156.32,57.29 156.59,57.03 157.02,57.03 157.29,57.29 157.29,58.3 157.39,58.4 157.59,58.4 157.7,58.3 157.7,57.29 157.96,57.03 158.4,57.03 158.66,57.29 158.66,58.3 158.76,58.4 158.97,58.4 159.07,58.3 159.07,57.29 159.33,57.03 159.77,57.03 160.03,57.29 160.03,58.3 160.13,58.4 160.34,58.4 160.44,58.3 160.44,57.29 160.7,57.03 161.14,57.03 161.4,57.29 161.4,58.3 161.51,58.4 161.71,58.4 161.81,58.3 161.81,57.29 162.08,57.03 162.51,57.03 162.78,57.29 162.78,58.3 162.88,58.4 163.08,58.4 163.18,58.3 163.18,57.29 163.45,57.03 163.88,57.03 164.15,57.29 164.15,58.3 164.25,58.4 164.45,58.4 164.55,58.3 164.55,57.29 164.82,57.03 165.25,57.03 165.52,57.29 165.52,58.3 165.62,58.4 165.82,58.4 165.93,58.3 165.93,57.29 166.19,57.03 166.63,57.03 166.89,57.29 166.89,58.3 166.99,58.4 167.2,58.4 167.3,58.3 167.3,57.29 167.56,57.03 187.95,57.03 189.27,58.34 190.18,59.26 191,59.26 v1(191.26,59)
DA4P: length 135.3
  TOP w0.114: U5.Y22 v2(104.95,71.2) ; J4.139 194.13,59.56 191.52,59.56 v1(191.26,59.82)
  L10-SIG4 w0.102: v1(191.26,59.82) 190.98,59.54 190.06,59.54 187.83,57.31 167.68,57.31 167.58,57.41 167.58,58.42 167.31,58.68 166.88,58.68 166.61,58.42 166.61,57.41 166.51,57.31 166.31,57.31 166.21,57.41 166.21,58.42 165.94,58.68 165.51,58.68 165.24,58.42 165.24,57.41 165.14,57.31 164.94,57.31 164.83,57.41 164.83,58.42 164.57,58.68 164.13,58.68 163.87,58.42 163.87,57.41 163.77,57.31 163.56,57.31 163.46,57.41 163.46,58.42 163.2,58.68 162.76,58.68 162.5,58.42 162.5,57.41 162.4,57.31 162.19,57.31 162.09,57.41 162.09,58.42 161.83,58.68 161.39,58.68 161.13,58.42 161.13,57.41 161.02,57.31 160.82,57.31 160.72,57.41 160.72,58.42 160.45,58.68 160.02,58.68 159.75,58.42 159.75,57.41 159.65,57.31 159.45,57.31 159.35,57.41 159.35,58.42 159.08,58.68 158.65,58.68 158.38,58.42 158.38,57.41 158.28,57.31 158.08,57.31 157.98,57.41 157.98,58.42 157.71,58.68 157.28,58.68 157.01,58.42 157.01,57.41 156.91,57.31 156.71,57.31 156.6,57.41 156.6,58.42 156.34,58.68 155.9,58.68 155.64,58.42 155.64,57.41 155.54,57.31 155.33,57.31 155.23,57.41 155.23,58.42 154.97,58.68 154.53,58.68 154.27,58.42 154.27,57.41 154.17,57.31 153.96,57.31 153.86,57.41 153.86,58.42 153.6,58.68 153.16,58.68 152.9,58.42 152.9,57.41 152.79,57.31 152.59,57.31 152.49,57.41 152.49,58.42 152.22,58.68 151.79,58.68 151.52,58.42 151.52,57.41 151.42,57.31 151.22,57.31 151.12,57.41 151.12,58.42 150.85,58.68 150.42,58.68 149.04,57.31 141.83,57.31 140.69,58.44 138.22,58.44 137.09,57.31 127.86,57.31 126.62,58.54 125.55,59.62 125.35,59.82 105.79,59.82 105.57,60.04 105.57,61.26 105.57,63.36 105.57,69.36 105.81,69.6 106.23,69.6 106.57,69.94 106.57,70.55 106.3,70.82 105.33,70.82 v2(104.95,71.2)
DA5N: length 135.4
  TOP w0.114: U5.V25 v2(106.95,68.2) ; J4.135 194.13,60.78 192.68,60.78 v1(192.41,60.51)
  L10-SIG4 w0.102: v1(192.41,60.51) 192.18,60.73 186.35,60.73 185.52,59.9 185.52,59.83 185.25,59.56 184.82,59.56 184.55,59.83 184.55,60.63 184.45,60.73 184.25,60.73 184.15,60.63 184.15,59.83 183.88,59.56 183.45,59.56 183.18,59.83 183.18,60.63 183.08,60.73 182.88,60.73 182.77,60.63 182.77,59.83 182.51,59.56 182.07,59.56 181.81,59.83 181.81,60.63 181.71,60.73 181.5,60.73 181.4,60.63 181.4,59.83 181.14,59.56 180.7,59.56 180.44,59.83 180.44,60.63 180.34,60.73 180.13,60.73 180.03,60.63 180.03,59.83 179.77,59.56 179.33,59.56 179.07,59.83 179.07,60.63 178.96,60.73 178.76,60.73 178.66,60.63 178.66,59.83 178.39,59.56 177.96,59.56 177.69,59.83 177.69,60.63 177.59,60.73 177.39,60.73 177.29,60.63 177.29,59.83 177.02,59.56 176.59,59.56 176.32,59.83 176.32,60.63 176.22,60.73 176.02,60.73 175.92,60.63 175.92,59.83 175.65,59.56 175.22,59.56 174.95,59.83 174.95,60.63 174.85,60.73 174.65,60.73 174.54,60.63 174.54,59.83 174.28,59.56 173.85,59.56 173.58,59.83 173.58,60.63 173.48,60.73 173.27,60.73 173.17,60.63 173.17,59.83 172.91,59.56 172.47,59.56 172.21,59.83 172.21,60.63 172.11,60.73 171.9,60.73 171.8,60.63 171.8,59.83 171.54,59.56 171.1,59.56 170.84,59.83 170.84,60.63 170.73,60.73 170.53,60.73 170.43,60.63 170.43,59.83 170.16,59.56 169.73,59.56 169.46,59.83 169.46,60.63 169.36,60.73 169.16,60.73 169.06,60.63 169.06,59.83 168.79,59.56 168.36,59.56 168.09,59.83 168.09,60.63 167.99,60.73 167.79,60.73 167.69,60.63 167.69,59.83 167.42,59.56 166.99,59.56 166.72,59.83 166.72,60.63 166.62,60.73 166.42,60.73 166.32,60.63 166.32,59.83 166.05,59.56 165.62,59.56 165.35,59.83 165.35,60.63 165.25,60.73 165.05,60.73 164.94,60.63 164.94,59.83 164.68,59.56 164.24,59.56 163.98,59.83 163.98,60.63 163.88,60.73 163.67,60.73 163.57,60.63 163.57,59.83 163.31,59.56 162.87,59.56 162.61,59.83 162.61,60.63 162.51,60.73 162.3,60.73 162.2,60.63 162.2,59.83 161.94,59.56 161.5,59.56 161.24,59.83 161.24,60.63 161.13,60.73 160.93,60.73 160.83,60.63 160.83,59.83 160.56,59.56 160.13,59.56 159.86,59.83 159.86,60.63 159.76,60.73 159.56,60.73 159.46,60.63 159.46,59.83 159.19,59.56 158.76,59.56 158.49,59.83 158.49,59.83 157.58,60.73 143.76,60.73 142.97,59.94 136.14,59.94 135.25,59.05 129.67,59.05 128.14,60.58 108.37,60.58 107.33,61.62 107.33,68.44 107.19,68.58 106.61,68.58 106.53,68.51 106.53,68.28 106.61,68.2 v2(106.95,68.2)
DA5P: length 135.4
  TOP w0.114: J4.133 194.13,61.06 192.68,61.06 v1(192.41,61.33) ; U5.W24 v2(105.95,69.2)
  L10-SIG4 w0.102: v2(105.95,69.2) 106.33,68.82 107.29,68.82 107.57,68.54 107.57,61.72 108.47,60.82 125.19,60.82 125.23,60.86 128.26,60.86 129.78,59.33 135.14,59.33 136.03,60.22 142.86,60.22 143.65,61.01 157.7,61.01 158.6,60.11 158.61,60.11 158.87,59.84 159.08,59.84 159.18,59.94 159.18,60.75 159.44,61.01 159.88,61.01 160.14,60.75 160.14,59.94 160.24,59.84 160.45,59.84 160.55,59.94 160.55,60.75 160.81,61.01 161.25,61.01 161.51,60.75 161.51,59.94 161.62,59.84 161.82,59.84 161.92,59.94 161.92,60.75 162.19,61.01 162.62,61.01 162.89,60.75 162.89,59.94 162.99,59.84 163.19,59.84 163.29,59.94 163.29,60.75 163.56,61.01 163.99,61.01 164.26,60.75 164.26,59.94 164.36,59.84 164.56,59.84 164.66,59.94 164.66,60.75 164.93,61.01 165.36,61.01 165.63,60.75 165.63,59.94 165.73,59.84 165.93,59.84 166.04,59.94 166.04,60.75 166.3,61.01 166.74,61.01 167,60.75 167,59.94 167.1,59.84 167.31,59.84 167.41,59.94 167.41,60.75 167.67,61.01 168.11,61.01 168.37,60.75 168.37,59.94 168.47,59.84 168.68,59.84 168.78,59.94 168.78,60.75 169.04,61.01 169.48,61.01 169.74,60.75 169.74,59.94 169.85,59.84 170.05,59.84 170.15,59.94 170.15,60.75 170.42,61.01 170.85,61.01 171.12,60.75 171.12,59.94 171.22,59.84 171.42,59.84 171.52,59.94 171.52,60.75 171.79,61.01 172.22,61.01 172.49,60.75 172.49,59.94 172.59,59.84 172.79,59.84 172.89,59.94 172.89,60.75 173.16,61.01 173.59,61.01 173.86,60.75 173.86,59.94 173.96,59.84 174.16,59.84 174.27,59.94 174.27,60.75 174.53,61.01 174.97,61.01 175.23,60.75 175.23,59.94 175.33,59.84 175.54,59.84 175.64,59.94 175.64,60.75 175.9,61.01 176.34,61.01 176.6,60.75 176.6,59.94 176.7,59.84 176.91,59.84 177.01,59.94 177.01,60.75 177.27,61.01 177.71,61.01 177.97,60.75 177.97,59.94 178.08,59.84 178.28,59.84 178.38,59.94 178.38,60.75 178.65,61.01 179.08,61.01 179.35,60.75 179.35,59.94 179.45,59.84 179.65,59.84 179.75,59.94 179.75,60.75 180.02,61.01 180.45,61.01 180.72,60.75 180.72,59.94 180.82,59.84 181.02,59.84 181.12,59.94 181.12,60.75 181.39,61.01 181.82,61.01 182.09,60.75 182.09,59.94 182.19,59.84 182.39,59.84 182.5,59.94 182.5,60.75 182.76,61.01 183.2,61.01 183.46,60.75 183.46,59.94 183.56,59.84 183.77,59.84 183.87,59.94 183.87,60.75 184.13,61.01 184.57,61.01 184.83,60.75 184.83,59.94 184.93,59.84 185.14,59.84 185.24,59.94 185.24,60.02 186.23,61.01 192.09,61.01 v1(192.41,61.33)
DA6N: length 135.3
  TOP w0.114: J4.129 194.13,62.28 191.54,62.28 v1(191.26,62) ; U5.U25 v2(108.95,68.2)
  L10-SIG4 w0.102: v2(108.95,68.2) 108.95,68.34 109.08,68.47 109.17,68.47 109.33,68.31 109.33,61.94 109.69,61.58 124.55,61.58 124.61,61.52 142.34,61.52 143.13,62.31 145.44,62.31 145.54,62.2 145.54,62.04 145.81,61.77 146.24,61.77 146.51,62.04 146.51,62.74 146.61,62.84 146.81,62.84 146.91,62.74 146.91,62.04 147.18,61.77 147.61,61.77 147.88,62.04 147.88,62.74 147.98,62.84 148.18,62.84 148.29,62.74 148.29,62.04 148.55,61.77 148.99,61.77 149.25,62.04 149.25,62.74 149.35,62.84 149.56,62.84 149.66,62.74 149.66,62.04 149.92,61.77 150.36,61.77 150.62,62.04 150.62,62.74 150.72,62.84 150.93,62.84 151.03,62.74 151.03,62.04 151.29,61.77 151.73,61.77 151.99,62.04 151.99,62.74 152.1,62.84 152.3,62.84 152.4,62.74 152.4,62.04 152.67,61.77 153.1,61.77 153.37,62.04 153.37,62.74 153.47,62.84 153.67,62.84 153.77,62.74 153.77,62.04 154.04,61.77 154.47,61.77 154.74,62.04 154.74,62.74 154.84,62.84 155.04,62.84 155.14,62.74 155.14,62.04 155.41,61.77 155.84,61.77 156.11,62.04 156.11,62.74 156.21,62.84 156.41,62.84 156.52,62.74 156.52,62.04 156.78,61.77 157.22,61.77 157.48,62.04 157.48,62.74 157.58,62.84 157.79,62.84 157.89,62.74 157.89,62.04 158.15,61.77 158.59,61.77 158.85,62.04 158.85,62.74 158.95,62.84 159.16,62.84 159.26,62.74 159.26,62.04 159.52,61.77 159.96,61.77 160.22,62.04 160.22,62.74 160.33,62.84 160.53,62.84 160.63,62.74 160.63,62.04 160.9,61.77 161.33,61.77 161.6,62.04 161.6,62.74 161.7,62.84 161.9,62.84 162,62.74 162,62.04 162.27,61.77 162.7,61.77 162.97,62.04 162.97,62.74 163.07,62.84 163.27,62.84 163.37,62.74 163.37,62.04 163.64,61.77 164.07,61.77 164.34,62.04 164.34,62.74 164.44,62.84 164.64,62.84 164.74,62.74 164.74,62.04 165.01,61.77 165.44,61.77 165.71,62.04 165.71,62.74 165.81,62.84 166.01,62.84 166.12,62.74 166.12,62.04 166.38,61.77 166.82,61.77 167.08,62.04 167.08,62.74 167.18,62.84 167.39,62.84 167.49,62.74 167.49,62.04 167.75,61.77 168.19,61.77 168.45,62.04 168.45,62.74 168.55,62.84 168.76,62.84 168.86,62.74 168.86,62.04 169.12,61.77 169.56,61.77 169.82,62.04 169.82,62.74 169.93,62.84 170.13,62.84 170.23,62.74 170.23,62.04 170.5,61.77 170.93,61.77 171.2,62.04 171.2,62.74 171.3,62.84 171.5,62.84 171.6,62.74 171.6,62.04 171.87,61.77 172.3,61.77 172.57,62.04 172.57,62.74 172.67,62.84 172.87,62.84 172.97,62.74 172.97,62.04 173.24,61.77 173.67,61.77 173.94,62.04 173.94,62.74 174.04,62.84 174.24,62.84 174.35,62.74 174.35,62.04 174.61,61.77 175.05,61.77 175.31,62.04 175.31,62.74 175.41,62.84 175.62,62.84 175.72,62.74 175.72,62.04 175.98,61.77 176.42,61.77 176.68,62.04 176.68,62.74 176.78,62.84 176.99,62.84 177.09,62.74 177.09,62.04 177.35,61.77 177.79,61.77 178.05,62.04 178.05,62.74 178.16,62.84 178.36,62.84 178.46,62.74 178.46,62.04 178.73,61.77 179.27,61.77 179.43,61.93 179.43,62.2 179.53,62.31 183.07,62.31 183.4,62.64 183.87,62.64 184.2,62.31 190.95,62.31 v1(191.26,62)
DA6P: length 135.5
  TOP w0.114: U5.T24 v2(109.95,69.2) ; v1(191.26,62.82) 191.52,62.56 194.13,62.56 J4.127
  L10-SIG4 w0.102: v2(109.95,69.2) 109.95,68.81 109.57,68.43 109.57,62.04 109.79,61.82 124.65,61.82 124.71,61.76 125.17,61.76 125.21,61.8 142.23,61.8 143.01,62.59 145.56,62.59 145.82,62.32 145.82,62.15 145.92,62.05 146.13,62.05 146.23,62.15 146.23,62.85 146.49,63.12 146.93,63.12 147.19,62.85 147.19,62.15 147.3,62.05 147.5,62.05 147.6,62.15 147.6,62.85 147.87,63.12 148.3,63.12 148.57,62.85 148.57,62.15 148.67,62.05 148.87,62.05 148.97,62.15 148.97,62.85 149.24,63.12 149.67,63.12 149.94,62.85 149.94,62.15 150.04,62.05 150.24,62.05 150.34,62.15 150.34,62.85 150.61,63.12 151.04,63.12 151.31,62.85 151.31,62.15 151.41,62.05 151.61,62.05 151.71,62.15 151.71,62.85 151.98,63.12 152.41,63.12 152.68,62.85 152.68,62.15 152.78,62.05 152.98,62.05 153.09,62.15 153.09,62.85 153.35,63.12 153.79,63.12 154.05,62.85 154.05,62.15 154.15,62.05 154.36,62.05 154.46,62.15 154.46,62.85 154.72,63.12 155.16,63.12 155.42,62.85 155.42,62.15 155.52,62.05 155.73,62.05 155.83,62.15 155.83,62.85 156.09,63.12 156.53,63.12 156.79,62.85 156.79,62.15 156.9,62.05 157.1,62.05 157.2,62.15 157.2,62.85 157.47,63.12 157.9,63.12 158.17,62.85 158.17,62.15 158.27,62.05 158.47,62.05 158.57,62.15 158.57,62.85 158.84,63.12 159.27,63.12 159.54,62.85 159.54,62.15 159.64,62.05 159.84,62.05 159.94,62.15 159.94,62.85 160.21,63.12 160.64,63.12 160.91,62.85 160.91,62.15 161.01,62.05 161.21,62.05 161.32,62.15 161.32,62.85 161.58,63.12 162.02,63.12 162.28,62.85 162.28,62.15 162.38,62.05 162.59,62.05 162.69,62.15 162.69,62.85 162.95,63.12 163.39,63.12 163.65,62.85 163.65,62.15 163.75,62.05 163.96,62.05 164.06,62.15 164.06,62.85 164.32,63.12 164.76,63.12 165.02,62.85 165.02,62.15 165.13,62.05 165.33,62.05 165.43,62.15 165.43,62.85 165.7,63.12 166.13,63.12 166.4,62.85 166.4,62.15 166.5,62.05 166.7,62.05 166.8,62.15 166.8,62.85 167.07,63.12 167.5,63.12 167.77,62.85 167.77,62.15 167.87,62.05 168.07,62.05 168.17,62.15 168.17,62.85 168.44,63.12 168.87,63.12 169.14,62.85 169.14,62.15 169.24,62.05 169.44,62.05 169.55,62.15 169.55,62.85 169.81,63.12 170.25,63.12 170.51,62.85 170.51,62.15 170.61,62.05 170.82,62.05 170.92,62.15 170.92,62.85 171.18,63.12 171.62,63.12 171.88,62.85 171.88,62.15 171.98,62.05 172.19,62.05 172.29,62.15 172.29,62.85 172.55,63.12 172.99,63.12 173.25,62.85 173.25,62.15 173.36,62.05 173.56,62.05 173.66,62.15 173.66,62.85 173.93,63.12 174.36,63.12 174.63,62.85 174.63,62.15 174.73,62.05 174.93,62.05 175.03,62.15 175.03,62.85 175.3,63.12 175.73,63.12 176,62.85 176,62.15 176.1,62.05 176.3,62.05 176.4,62.15 176.4,62.85 176.67,63.12 177.1,63.12 177.37,62.85 177.37,62.15 177.47,62.05 177.67,62.05 177.78,62.15 177.78,62.85 178.04,63.12 178.48,63.12 178.74,62.85 178.74,62.15 178.84,62.05 179.05,62.05 179.15,62.15 179.15,62.32 179.41,62.59 182.95,62.59 183.28,62.92 183.99,62.92 184.32,62.59 184.91,62.59 185.01,62.69 185.01,62.74 185.11,62.84 185.31,62.84 185.42,62.74 185.42,62.69 185.52,62.59 191.03,62.59 v1(191.26,62.82)
DA7N: length 135.4
  TOP w0.114: U5.R24 v2(110.95,69.2) ; v1(192.41,63.51) 192.68,63.78 194.13,63.78 J4.123
  L10-SIG4 w0.102: v2(110.95,69.2) 110.95,69.08 110.33,68.46 110.33,68.04 110.34,67.9 110.34,67.46 110.33,67.46 110.33,66.94 110.34,66.94 110.34,66.46 110.33,66.46 110.33,65.94 110.34,65.94 110.34,65.46 110.33,65.46 110.33,64.94 110.34,64.94 110.34,64.46 110.33,64.46 110.33,63.94 110.34,63.94 110.34,63.46 110.33,63.46 110.33,62.94 110.69,62.58 125.3,62.58 125.34,62.53 125.68,62.53 125.73,62.58 130.68,62.58 131.03,62.23 133.63,62.23 133.98,62.58 140.7,62.58 140.7,62.58 141.12,62.58 141.28,62.74 143.1,64.57 143.34,64.57 155.96,64.57 156.38,64.98 156.55,64.98 156.75,65.19 156.75,65.36 156.95,65.56 157.13,65.56 157.33,65.76 157.33,65.93 157.9,66.5 158.42,66.5 159.46,65.46 159.46,65.42 159.73,65.16 160.16,65.16 160.43,65.42 160.43,66.4 160.53,66.5 160.73,66.5 160.83,66.4 160.83,65.42 161.1,65.16 161.53,65.16 161.8,65.42 161.8,66.4 161.9,66.5 162.1,66.5 162.2,66.4 162.2,65.42 162.47,65.16 162.9,65.16 163.17,65.42 163.17,66.4 163.27,66.5 163.47,66.5 163.58,66.4 163.58,65.42 163.84,65.16 164.28,65.16 164.54,65.42 164.54,66.4 164.64,66.5 164.85,66.5 164.95,66.4 164.95,65.42 165.21,65.16 165.65,65.16 165.91,65.42 165.91,66.4 166.01,66.5 166.22,66.5 166.32,66.4 166.32,65.42 166.58,65.16 167.02,65.16 167.28,65.42 167.28,66.4 167.39,66.5 167.59,66.5 167.69,66.4 167.69,65.42 167.96,65.16 168.39,65.16 168.66,65.42 168.66,66.4 168.76,66.5 168.96,66.5 169.06,66.4 169.06,65.42 169.33,65.16 169.76,65.16 170.03,65.42 170.03,66.4 170.13,66.5 170.33,66.5 170.43,66.4 170.43,65.42 170.7,65.16 171.13,65.16 171.4,65.42 171.4,66.4 171.5,66.5 171.7,66.5 171.81,66.4 171.81,65.42 172.07,65.16 172.51,65.16 172.77,65.42 172.77,66.4 172.87,66.5 173.08,66.5 173.18,66.4 173.18,65.42 173.44,65.16 173.88,65.16 174.14,65.42 174.14,66.4 174.24,66.5 174.45,66.5 174.55,66.4 174.55,65.42 174.81,65.16 175.25,65.16 175.51,65.42 175.51,66.4 175.62,66.5 175.82,66.5 175.92,66.4 175.92,65.42 176.19,65.16 176.62,65.16 176.89,65.42 176.89,66.4 176.99,66.5 177.19,66.5 177.29,66.4 177.29,65.42 177.56,65.16 177.99,65.16 178.26,65.42 178.26,66.4 178.36,66.5 178.56,66.5 178.66,66.4 178.66,65.42 178.93,65.16 179.36,65.16 179.63,65.42 179.63,66.4 179.73,66.5 179.93,66.5 180.04,66.4 180.04,65.42 180.3,65.16 180.74,65.16 181,65.42 181,66.4 181.1,66.5 181.31,66.5 181.41,66.4 181.41,65.42 181.67,65.16 182.11,65.16 182.37,65.42 182.37,66.4 182.47,66.5 182.68,66.5 182.78,66.4 182.78,65.42 183.04,65.16 183.48,65.16 183.74,65.42 183.74,66.4 183.85,66.5 184.05,66.5 184.15,66.4 184.15,65.42 184.42,65.16 189.58,65.16 190.98,63.75 192.16,63.75 v1(192.41,63.51)
DA7P: length 135.4
  TOP w0.114: U5.R23 v2(110.95,70.2) ; J4.121 194.13,64.06 192.68,64.06 v1(192.41,64.33)
  L10-SIG4 w0.102: v1(192.41,64.33) 192.18,64.11 191.03,64.11 189.69,65.44 184.53,65.44 184.43,65.54 184.43,66.51 184.16,66.78 183.73,66.78 183.46,66.51 183.46,65.54 183.36,65.44 183.16,65.44 183.06,65.54 183.06,66.51 182.79,66.78 182.36,66.78 182.09,66.51 182.09,65.54 181.99,65.44 181.79,65.44 181.69,65.54 181.69,66.51 181.42,66.78 180.99,66.78 180.72,66.51 180.72,65.54 180.62,65.44 180.42,65.44 180.31,65.54 180.31,66.51 180.05,66.78 179.61,66.78 179.35,66.51 179.35,65.54 179.25,65.44 179.04,65.44 178.94,65.54 178.94,66.51 178.68,66.78 178.24,66.78 177.98,66.51 177.98,65.54 177.88,65.44 177.67,65.44 177.57,65.54 177.57,66.51 177.31,66.78 176.87,66.78 176.61,66.51 176.61,65.54 176.5,65.44 176.3,65.44 176.2,65.54 176.2,66.51 175.93,66.78 175.5,66.78 175.23,66.51 175.23,65.54 175.13,65.44 174.93,65.44 174.83,65.54 174.83,66.51 174.56,66.78 174.13,66.78 173.86,66.51 173.86,65.54 173.76,65.44 173.56,65.44 173.46,65.54 173.46,66.51 173.19,66.78 172.76,66.78 172.49,66.51 172.49,65.54 172.39,65.44 172.19,65.44 172.08,65.54 172.08,66.51 171.82,66.78 171.38,66.78 171.12,66.51 171.12,65.54 171.02,65.44 170.81,65.44 170.71,65.54 170.71,66.51 170.45,66.78 170.01,66.78 169.75,66.51 169.75,65.54 169.65,65.44 169.44,65.44 169.34,65.54 169.34,66.51 169.08,66.78 168.64,66.78 168.38,66.51 168.38,65.54 168.27,65.44 168.07,65.44 167.97,65.54 167.97,66.51 167.7,66.78 167.27,66.78 167,66.51 167,65.54 166.9,65.44 166.7,65.44 166.6,65.54 166.6,66.51 166.33,66.78 165.9,66.78 165.63,66.51 165.63,65.54 165.53,65.44 165.33,65.44 165.23,65.54 165.23,66.51 164.96,66.78 164.53,66.78 164.26,66.51 164.26,65.54 164.16,65.44 163.96,65.44 163.86,65.54 163.86,66.51 163.59,66.78 163.16,66.78 162.89,66.51 162.89,65.54 162.79,65.44 162.59,65.44 162.48,65.54 162.48,66.51 162.22,66.78 161.78,66.78 161.52,66.51 161.52,65.54 161.42,65.44 161.21,65.44 161.11,65.54 161.11,66.51 160.85,66.78 160.41,66.78 160.15,66.51 160.15,66.04 159.89,65.79 159.53,65.79 158.53,66.78 157.78,66.78 155.85,64.85 143.22,64.85 142.99,64.85 141,62.86 140.58,62.86 133.87,62.86 133.52,62.51 131.15,62.51 130.8,62.86 125.59,62.86 125.55,62.82 125.35,62.82 125.29,62.82 110.79,62.82 110.57,63.04 110.57,63.36 110.58,63.36 110.58,64.04 110.57,64.04 110.57,64.36 110.58,64.36 110.58,65.04 110.57,65.04 110.57,65.36 110.58,65.36 110.58,66.04 110.57,66.04 110.57,66.36 110.58,66.36 110.58,67.04 110.57,67.04 110.57,67.36 110.58,67.36 110.58,68.04 110.57,68.04 110.57,68.05 110.57,68.36 111.03,68.82 111.11,68.82 111.33,69.04 111.33,69.36 111.19,69.5 111.19,69.91 110.95,70.14 v2(110.95,70.2)
DA8N: length 135.5
  TOP w0.114: U5.J27 v2(116.95,66.2) ; v1(191.39,71.63) 191.54,71.77 194.13,71.77 J4.111
  L4-SIG2 w0.102: v2(116.95,66.2) 117.29,66.54 117.44,66.54 117.69,66.29 118.38,66.29 118.62,66.53 118.62,66.67 120.52,68.58 120.79,68.58 121.79,68.58 122.79,68.58 123.79,68.58 124.79,68.58 127.13,68.58 127.57,69.02 133.29,69.02 133.48,68.83 134.49,68.83 137.16,71.5 146.56,71.5 147.7,72.64 152.02,72.64 155.07,69.6 157.9,69.6 158,69.49 158,69.1 158.26,68.83 158.7,68.83 158.96,69.1 158.96,70.26 159.06,70.36 159.27,70.36 159.37,70.26 159.37,69.1 159.63,68.83 160.07,68.83 160.33,69.1 160.33,70.26 160.44,70.36 160.64,70.36 160.74,70.26 160.74,69.1 161.01,68.83 161.44,68.83 161.71,69.1 161.71,70.26 161.81,70.36 162.01,70.36 162.11,70.26 162.11,69.1 162.38,68.83 162.81,68.83 163.08,69.1 163.08,70.26 163.18,70.36 163.38,70.36 163.48,70.26 163.48,69.1 163.75,68.83 164.18,68.83 164.45,69.1 164.45,70.26 164.55,70.36 164.75,70.36 164.86,70.26 164.86,69.1 165.12,68.83 165.56,68.83 165.82,69.1 165.82,70.26 165.92,70.36 166.13,70.36 166.23,70.26 166.23,69.1 166.49,68.83 166.93,68.83 167.19,69.1 167.19,70.26 167.29,70.36 167.5,70.36 167.6,70.26 167.6,69.1 167.86,68.83 168.3,68.83 168.56,69.1 168.56,70.26 168.67,70.36 168.87,70.36 168.97,70.26 168.97,69.1 169.24,68.83 169.67,68.83 169.94,69.1 169.94,70.26 170.04,70.36 170.24,70.36 170.34,70.26 170.34,69.1 170.61,68.83 171.04,68.83 171.31,69.1 171.31,70.26 171.41,70.36 171.61,70.36 171.71,70.26 171.71,69.1 171.98,68.83 172.41,68.83 172.68,69.1 172.68,70.26 172.78,70.36 172.98,70.36 173.09,70.26 173.09,69.1 173.35,68.83 173.79,68.83 174.05,69.1 174.05,70.26 174.15,70.36 174.36,70.36 174.46,70.26 174.46,69.1 174.72,68.83 175.16,68.83 175.42,69.1 175.42,70.26 175.52,70.36 175.73,70.36 175.83,70.26 175.83,69.1 176.09,68.83 176.53,68.83 176.79,69.1 176.79,70.26 176.9,70.36 177.1,70.36 177.2,70.26 177.2,69.1 177.47,68.83 177.9,68.83 178.17,69.1 178.17,70.26 178.27,70.36 178.47,70.36 178.57,70.26 178.57,69.1 178.84,68.83 179.27,68.83 179.54,69.1 179.54,70.26 179.64,70.36 179.84,70.36 179.94,70.26 179.94,69.1 180.21,68.83 180.64,68.83 180.91,69.1 180.91,70.26 181.01,70.36 181.21,70.36 181.31,70.26 181.31,69.1 181.58,68.83 182.01,68.83 182.28,69.1 182.28,70.26 182.38,70.36 182.58,70.36 182.69,70.26 182.69,69.1 182.95,68.83 183.39,68.83 183.65,69.1 183.65,70.26 183.75,70.36 183.96,70.36 184.06,70.26 184.06,69.1 184.32,68.83 184.76,68.83 185.02,69.1 185.02,70.26 185.12,70.36 185.33,70.36 185.43,70.26 185.43,70.21 186.04,69.6 188.34,69.6 190.6,71.86 191.16,71.86 v1(191.39,71.63)
DA8P: length 135.4
  TOP w0.114: v1(191.39,72.39) 191.39,72.31 191.64,72.05 194.13,72.05 J4.109 ; U5.H26 v2(117.95,67.2)
  L4-SIG2 w0.102: v2(117.95,67.2) 117.61,66.86 117.61,66.71 117.79,66.53 118.28,66.53 118.38,66.63 118.38,66.77 120.42,68.82 120.69,68.82 120.69,68.82 121.21,68.82 121.21,68.82 121.69,68.82 121.69,68.82 122.21,68.82 122.21,68.82 122.69,68.82 122.69,68.82 123.21,68.82 123.21,68.82 123.69,68.82 123.69,68.82 124.21,68.82 124.21,68.82 124.69,68.82 124.69,68.82 125.31,68.82 125.35,68.86 127.01,68.86 127.46,69.3 133.4,69.3 133.59,69.11 134.38,69.11 137.04,71.78 146.44,71.78 147.59,72.92 152.13,72.92 155.18,69.88 158.01,69.88 158.28,69.61 158.28,69.22 158.38,69.11 158.58,69.11 158.68,69.22 158.68,70.37 158.95,70.64 159.38,70.64 159.65,70.37 159.65,69.22 159.75,69.11 159.95,69.11 160.06,69.22 160.06,70.37 160.32,70.64 160.76,70.64 161.02,70.37 161.02,69.22 161.12,69.11 161.33,69.11 161.43,69.22 161.43,70.37 161.69,70.64 162.13,70.64 162.39,70.37 162.39,69.22 162.49,69.11 162.7,69.11 162.8,69.22 162.8,70.37 163.06,70.64 163.5,70.64 163.76,70.37 163.76,69.22 163.87,69.11 164.07,69.11 164.17,69.22 164.17,70.37 164.44,70.64 164.87,70.64 165.14,70.37 165.14,69.22 165.24,69.11 165.44,69.11 165.54,69.22 165.54,70.37 165.81,70.64 166.24,70.64 166.51,70.37 166.51,69.22 166.61,69.11 166.81,69.11 166.91,69.22 166.91,70.37 167.18,70.64 167.61,70.64 167.88,70.37 167.88,69.22 167.98,69.11 168.18,69.11 168.28,69.22 168.28,70.37 168.55,70.64 168.98,70.64 169.25,70.37 169.25,69.22 169.35,69.11 169.55,69.11 169.66,69.22 169.66,70.37 169.92,70.64 170.36,70.64 170.62,70.37 170.62,69.22 170.72,69.11 170.93,69.11 171.03,69.22 171.03,70.37 171.29,70.64 171.73,70.64 171.99,70.37 171.99,69.22 172.09,69.11 172.3,69.11 172.4,69.22 172.4,70.37 172.66,70.64 173.1,70.64 173.36,70.37 173.36,69.22 173.47,69.11 173.67,69.11 173.77,69.22 173.77,70.37 174.04,70.64 174.47,70.64 174.74,70.37 174.74,69.22 174.84,69.11 175.04,69.11 175.14,69.22 175.14,70.37 175.41,70.64 175.84,70.64 176.11,70.37 176.11,69.22 176.21,69.11 176.41,69.11 176.51,69.22 176.51,70.37 176.78,70.64 177.21,70.64 177.48,70.37 177.48,69.22 177.58,69.11 177.78,69.11 177.89,69.22 177.89,70.37 178.15,70.64 178.59,70.64 178.85,70.37 178.85,69.22 178.95,69.11 179.16,69.11 179.26,69.22 179.26,70.37 179.52,70.64 179.96,70.64 180.22,70.37 180.22,69.22 180.32,69.11 180.53,69.11 180.63,69.22 180.63,70.37 180.89,70.64 181.33,70.64 181.59,70.37 181.59,69.22 181.7,69.11 181.9,69.11 182,69.22 182,70.37 182.27,70.64 182.7,70.64 182.97,70.37 182.97,69.22 183.07,69.11 183.27,69.11 183.37,69.22 183.37,70.37 183.64,70.64 184.07,70.64 184.34,70.37 184.34,69.22 184.44,69.11 184.64,69.11 184.74,69.22 184.74,70.37 185.01,70.64 185.44,70.64 185.71,70.37 185.71,70.32 186.16,69.88 188.23,69.88 190.49,72.14 191.13,72.14 v1(191.39,72.39)
DA9N: length 135.4
  TOP w0.114: U5.P24 v2(111.95,69.2) ; J4.105 194.23,73.16 194.13,73.27 192.64,73.27 192.41,73.03 v1(192.41,73.02)
  L4-SIG2 w0.102: v2(111.95,69.2) 111.95,69.34 111.95,69.35 111.95,69.5 111.99,69.54 112.2,69.54 112.33,69.4 112.33,66.89 112.64,66.58 115.21,66.58 115.57,66.94 115.57,74.36 115.79,74.58 122.78,74.58 122.78,74.59 123.1,74.59 123.11,74.58 125.1,74.58 125.2,74.68 125.26,74.68 125.66,75.08 126.03,75.08 126.32,74.79 129.3,74.79 130.25,73.84 135.95,73.84 136.21,73.58 153.5,73.58 153.5,73.57 153.51,73.57 154.67,72.42 157.24,72.42 158.54,73.72 159.31,73.72 159.41,73.62 159.41,72.53 159.68,72.26 160.11,72.26 160.38,72.53 160.38,73.62 160.48,73.72 160.68,73.72 160.78,73.62 160.78,72.53 161.05,72.26 161.48,72.26 161.75,72.53 161.75,73.62 161.85,73.72 162.05,73.72 162.16,73.62 162.16,72.53 162.42,72.26 162.86,72.26 163.12,72.53 163.12,73.62 163.22,73.72 163.43,73.72 163.53,73.62 163.53,72.53 163.79,72.26 164.23,72.26 164.49,72.53 164.49,73.62 164.59,73.72 164.8,73.72 164.9,73.62 164.9,72.53 165.16,72.26 165.6,72.26 165.86,72.53 165.86,73.62 165.97,73.72 166.17,73.72 166.27,73.62 166.27,72.53 166.54,72.26 166.97,72.26 167.24,72.53 167.24,73.62 167.34,73.72 167.54,73.72 167.64,73.62 167.64,72.53 167.91,72.26 168.34,72.26 168.61,72.53 168.61,73.62 168.71,73.72 168.91,73.72 169.01,73.62 169.01,72.53 169.28,72.26 169.71,72.26 169.98,72.53 169.98,73.62 170.08,73.72 170.28,73.72 170.39,73.62 170.39,72.53 170.65,72.26 171.09,72.26 171.35,72.53 171.35,73.62 171.45,73.72 171.66,73.72 171.76,73.62 171.76,72.53 172.02,72.26 172.46,72.26 172.72,72.53 172.72,73.62 172.82,73.72 173.03,73.72 173.13,73.62 173.13,72.53 173.39,72.26 173.83,72.26 174.09,72.53 174.09,73.62 174.2,73.72 174.4,73.72 174.5,73.62 174.5,72.53 174.77,72.26 175.2,72.26 175.47,72.53 175.47,73.62 175.57,73.72 175.77,73.72 175.87,73.62 175.87,72.53 176.14,72.26 176.57,72.26 176.84,72.53 176.84,73.62 176.94,73.72 177.14,73.72 177.24,73.62 177.24,72.53 177.51,72.26 177.94,72.26 178.21,72.53 178.21,73.62 178.31,73.72 178.51,73.72 178.61,73.62 178.61,72.53 178.88,72.26 179.31,72.26 179.58,72.53 179.58,73.62 179.68,73.72 179.88,73.72 179.99,73.62 179.99,72.53 180.25,72.26 180.69,72.26 180.95,72.53 180.95,72.97 181.29,73.3 182.37,73.3 182.91,72.77 185.42,72.77 185.95,73.3 192.13,73.3 192.41,73.03 v1(192.41,73.02)
DA9P: length 135.3
  TOP w0.114: v1(192.41,73.85) 192.69,73.56 194.13,73.56 194.23,73.67 J4.103 ; U5.P23 v2(111.95,70.2)
  L4-SIG2 w0.102: v2(111.95,70.2) 112.57,69.58 112.57,66.98 112.73,66.82 115.11,66.82 115.33,67.04 115.33,74.49 115.66,74.82 122.68,74.82 122.69,74.83 123.2,74.83 123.21,74.82 125.01,74.82 125.55,75.36 126.14,75.36 126.44,75.07 129.42,75.07 130.37,74.12 136.07,74.12 136.32,73.86 153.61,73.86 153.62,73.85 153.63,73.85 153.97,73.52 154.79,72.69 157.13,72.69 158.43,74 159.43,74 159.69,73.73 159.69,72.64 159.79,72.54 160,72.54 160.1,72.64 160.1,73.73 160.36,74 160.8,74 161.06,73.73 161.06,72.64 161.17,72.54 161.37,72.54 161.47,72.64 161.47,73.73 161.74,74 162.17,74 162.44,73.73 162.44,72.64 162.54,72.54 162.74,72.54 162.84,72.64 162.84,73.73 163.11,74 163.54,74 163.81,73.73 163.81,72.64 163.91,72.54 164.11,72.54 164.21,72.64 164.21,73.73 164.48,74 164.91,74 165.18,73.73 165.18,72.64 165.28,72.54 165.48,72.54 165.58,72.64 165.58,73.73 165.85,74 166.28,74 166.55,73.73 166.55,72.64 166.65,72.54 166.85,72.54 166.96,72.64 166.96,73.73 167.22,74 167.66,74 167.92,73.73 167.92,72.64 168.02,72.54 168.23,72.54 168.33,72.64 168.33,73.73 168.59,74 169.03,74 169.29,73.73 169.29,72.64 169.39,72.54 169.6,72.54 169.7,72.64 169.7,73.73 169.96,74 170.4,74 170.66,73.73 170.66,72.64 170.77,72.54 170.97,72.54 171.07,72.64 171.07,73.73 171.34,74 171.77,74 172.04,73.73 172.04,72.64 172.14,72.54 172.34,72.54 172.44,72.64 172.44,73.73 172.71,74 173.14,74 173.41,73.73 173.41,72.64 173.51,72.54 173.71,72.54 173.81,72.64 173.81,73.73 174.08,74 174.51,74 174.78,73.73 174.78,72.64 174.88,72.54 175.08,72.54 175.19,72.64 175.19,73.73 175.45,74 175.89,74 176.15,73.73 176.15,72.64 176.25,72.54 176.46,72.54 176.56,72.64 176.56,73.73 176.82,74 177.26,74 177.52,73.73 177.52,72.64 177.62,72.54 177.83,72.54 177.93,72.64 177.93,73.73 178.19,74 178.63,74 178.89,73.73 178.89,72.64 179,72.54 179.2,72.54 179.3,72.64 179.3,73.73 179.57,74 180,74 180.27,73.73 180.27,72.64 180.37,72.54 180.57,72.54 180.67,72.64 180.67,73.08 181.17,73.58 182.49,73.58 183.02,73.05 185.3,73.05 185.84,73.58 192.15,73.58 192.41,73.84 v1(192.41,73.85)
DA10N: length 135.4
  TOP w0.114: J4.99 194.14,74.76 191.51,74.76 v1(191.26,74.51) ; U5.N26 v2(112.95,67.2)
  L4-SIG2 w0.102: v1(191.26,74.51) 191.24,74.54 189,74.54 188.38,75.16 188.15,75.16 186.86,76.44 186.66,76.44 186.56,76.34 186.56,75.42 186.29,75.16 185.86,75.16 185.59,75.42 185.59,76.34 185.49,76.44 185.29,76.44 185.19,76.34 185.19,75.42 184.92,75.16 184.49,75.16 184.22,75.42 184.22,76.34 184.12,76.44 183.92,76.44 183.81,76.34 183.81,75.42 183.55,75.16 183.11,75.16 182.85,75.42 182.85,76.34 182.75,76.44 182.54,76.44 182.44,76.34 182.44,75.42 182.18,75.16 181.74,75.16 181.48,75.42 181.48,76.34 181.38,76.44 181.17,76.44 181.07,76.34 181.07,75.42 180.81,75.16 180.37,75.16 180.11,75.42 180.11,76.34 180,76.44 179.8,76.44 179.7,76.34 179.7,75.42 179.43,75.16 179,75.16 178.73,75.42 178.73,76.34 178.63,76.44 178.43,76.44 178.33,76.34 178.33,75.42 178.06,75.16 177.63,75.16 177.36,75.42 177.36,76.34 177.26,76.44 177.06,76.44 176.96,76.34 176.96,75.42 176.69,75.16 176.26,75.16 175.99,75.42 175.99,76.34 175.89,76.44 175.69,76.44 175.58,76.34 175.58,75.42 175.32,75.16 174.88,75.16 174.62,75.42 174.62,76.34 174.52,76.44 174.31,76.44 174.21,76.34 174.21,75.42 173.95,75.16 173.51,75.16 173.25,75.42 173.25,76.34 173.15,76.44 172.94,76.44 172.84,76.34 172.84,75.42 172.58,75.16 172.14,75.16 171.88,75.42 171.88,76.34 171.77,76.44 171.57,76.44 171.47,76.34 171.47,75.42 171.2,75.16 170.77,75.16 170.5,75.42 170.5,76.34 170.4,76.44 170.2,76.44 170.1,76.34 170.1,75.42 169.83,75.16 169.4,75.16 169.13,75.42 169.13,76.34 169.03,76.44 168.83,76.44 168.73,76.34 168.73,75.42 168.46,75.16 168.03,75.16 167.76,75.42 167.76,76.34 167.66,76.44 167.46,76.44 167.36,76.34 167.36,75.42 167.09,75.16 166.66,75.16 166.39,75.42 166.39,76.34 166.29,76.44 166.09,76.44 165.98,76.34 165.98,75.42 165.72,75.16 165.28,75.16 165.02,75.42 165.02,76.34 164.92,76.44 164.71,76.44 164.61,76.34 164.61,75.42 164.35,75.16 163.91,75.16 163.65,75.42 163.65,76.34 163.55,76.44 163.34,76.44 163.24,76.34 163.24,75.42 162.98,75.16 162.54,75.16 162.28,75.42 162.28,76.34 162.17,76.44 161.97,76.44 161.87,76.34 161.87,75.42 161.6,75.16 161.17,75.16 160.9,75.42 160.9,76.34 160.8,76.44 160.6,76.44 160.5,76.34 160.5,75.42 160.23,75.16 159.8,75.16 159.53,75.42 159.53,76.34 159.43,76.44 159.23,76.44 159.13,76.34 159.13,75.42 158.86,75.16 158.23,75.16 157.54,74.47 136.59,74.47 136.37,74.69 135.14,75.92 126.23,75.92 126.01,75.7 114.91,75.7 114.57,75.36 114.57,74.04 114.58,74.03 114.58,71.37 114.57,71.36 114.57,68.96 114.57,68.94 114.21,68.58 113.79,68.58 113.55,68.34 113.55,68.01 112.95,67.41 v2(112.95,67.2)
DA10P: length 135.5
  TOP w0.114: J4.97 194.17,75.17 194.06,75.06 191.54,75.06 v1(191.26,75.34) ; U5.N25 v2(112.95,68.2)
  L4-SIG2 w0.102: v1(191.26,75.34) 191.13,75.21 191.13,75.01 190.94,74.82 189.12,74.82 188.5,75.44 188.26,75.44 186.98,76.72 186.54,76.72 186.44,76.62 186.28,76.46 186.28,75.54 186.18,75.44 185.97,75.44 185.87,75.54 185.87,76.46 185.61,76.72 185.17,76.72 184.91,76.46 184.91,75.54 184.8,75.44 184.6,75.44 184.5,75.54 184.5,76.46 184.23,76.72 183.8,76.72 183.53,76.46 183.53,75.54 183.43,75.44 183.23,75.44 183.13,75.54 183.13,76.46 182.86,76.72 182.43,76.72 182.16,76.46 182.16,75.54 182.06,75.44 181.86,75.44 181.76,75.54 181.76,76.46 181.49,76.72 181.06,76.72 180.79,76.46 180.79,75.54 180.69,75.44 180.49,75.44 180.39,75.54 180.39,76.46 180.12,76.72 179.69,76.72 179.42,76.46 179.42,75.54 179.32,75.44 179.12,75.44 179.01,75.54 179.01,76.46 178.75,76.72 178.31,76.72 178.05,76.46 178.05,75.54 177.95,75.44 177.74,75.44 177.64,75.54 177.64,76.46 177.38,76.72 176.94,76.72 176.68,76.46 176.68,75.54 176.58,75.44 176.37,75.44 176.27,75.54 176.27,76.46 176.01,76.72 175.57,76.72 175.31,76.46 175.31,75.54 175.2,75.44 175,75.44 174.9,75.54 174.9,76.46 174.63,76.72 174.2,76.72 173.93,76.46 173.93,75.54 173.83,75.44 173.63,75.44 173.53,75.54 173.53,76.46 173.26,76.72 172.83,76.72 172.56,76.46 172.56,75.54 172.46,75.44 172.26,75.44 172.16,75.54 172.16,76.46 171.89,76.72 171.46,76.72 171.19,76.46 171.19,75.54 171.09,75.44 170.89,75.44 170.78,75.54 170.78,76.46 170.52,76.72 170.08,76.72 169.82,76.46 169.82,75.54 169.72,75.44 169.51,75.44 169.41,75.54 169.41,76.46 169.15,76.72 168.71,76.72 168.45,76.46 168.45,75.54 168.35,75.44 168.14,75.44 168.04,75.54 168.04,76.46 167.78,76.72 167.34,76.72 167.08,76.46 167.08,75.54 166.97,75.44 166.77,75.44 166.67,75.54 166.67,76.46 166.4,76.72 165.97,76.72 165.7,76.46 165.7,75.54 165.6,75.44 165.4,75.44 165.3,75.54 165.3,76.46 165.03,76.72 164.6,76.72 164.33,76.46 164.33,75.54 164.23,75.44 164.03,75.44 163.93,75.54 163.93,76.46 163.66,76.72 163.23,76.72 162.96,76.46 162.96,75.54 162.86,75.44 162.66,75.44 162.55,75.54 162.55,76.46 162.29,76.72 161.85,76.72 161.59,76.46 161.59,75.54 161.49,75.44 161.28,75.44 161.18,75.54 161.18,76.46 160.92,76.72 160.48,76.72 160.22,76.46 160.22,75.54 160.12,75.44 159.91,75.44 159.81,75.54 159.81,76.46 159.55,76.72 159.11,76.72 158.85,76.46 158.85,75.54 158.74,75.44 158.12,75.44 157.43,74.75 136.7,74.75 135.25,76.2 126.11,76.2 125.9,75.98 114.79,75.98 114.33,75.52 114.33,75.04 114.33,75.04 114.33,74.46 114.33,74.46 114.33,70.99 114.33,70.99 114.33,69.04 114.11,68.82 113.69,68.82 113.32,68.44 113.32,68.12 113.25,68.05 113.1,68.05 v2(112.95,68.2)
DA11N: length 135.4
  TOP w0.114: U5.M24 v2(113.95,69.2) ; v1(192.41,76.03) 192.41,76.03 192.64,76.26 194.14,76.26 194.23,76.17 J4.93
  L4-SIG2 w0.102: v1(192.41,76.03) 190.7,76.03 189.23,77.5 179.41,77.5 179.22,77.69 177.75,77.69 177.55,77.5 174.45,77.5 174.19,77.76 174.19,78.45 174.09,78.55 173.88,78.55 173.78,78.45 173.78,77.76 173.52,77.5 173.08,77.5 172.82,77.76 172.82,78.45 172.72,78.55 172.51,78.55 172.41,78.45 172.41,77.76 172.15,77.5 171.71,77.5 171.45,77.76 171.45,78.45 171.34,78.55 171.14,78.55 171.04,78.45 171.04,77.76 170.77,77.5 170.34,77.5 170.07,77.76 170.07,78.45 169.97,78.55 169.77,78.55 169.67,78.45 169.67,77.76 169.4,77.5 168.97,77.5 168.7,77.76 168.7,78.45 168.6,78.55 168.4,78.55 168.3,78.45 168.3,77.76 168.03,77.5 167.6,77.5 167.33,77.76 167.33,78.45 167.23,78.55 167.03,78.55 166.92,78.45 166.92,77.76 166.66,77.5 166.22,77.5 165.96,77.76 165.96,78.45 165.86,78.55 165.65,78.55 165.55,78.45 165.55,77.76 165.29,77.5 164.85,77.5 164.59,77.76 164.59,78.45 164.49,78.55 164.28,78.55 164.18,78.45 164.18,77.76 163.92,77.5 163.48,77.5 163.22,77.76 163.22,78.45 163.11,78.55 162.91,78.55 162.81,78.45 162.81,77.76 162.54,77.5 162.11,77.5 161.84,77.76 161.84,78.45 161.74,78.55 161.54,78.55 161.44,78.45 161.44,77.76 161.17,77.5 160.74,77.5 160.47,77.76 160.47,78.45 160.37,78.55 160.17,78.55 160.07,78.45 160.07,77.76 159.8,77.5 159.37,77.5 159.1,77.76 159.1,78.45 159,78.55 158.8,78.55 158.69,78.45 158.69,77.76 158.43,77.5 156.31,77.5 156.04,77.76 156.04,80.14 155.94,80.25 155.74,80.25 155.63,80.14 155.63,77.76 155.37,77.5 154.93,77.5 154.67,77.76 154.67,80.14 154.57,80.25 154.36,80.25 154.26,80.14 154.26,77.76 154,77.5 153.56,77.5 153.3,77.76 153.3,80.14 153.2,80.25 152.99,80.25 152.89,80.14 152.89,77.76 152.63,77.5 152.19,77.5 151.93,77.76 151.93,80.14 151.82,80.25 151.62,80.25 151.52,80.14 151.52,77.76 151.25,77.5 150.82,77.5 150.55,77.76 150.55,80.14 150.45,80.25 150.25,80.25 150.15,80.14 150.15,77.76 149.88,77.5 144.81,77.5 144.48,77.17 134.76,77.17 134.38,76.78 132.15,76.78 131.92,76.78 131.47,77.24 129.81,77.24 129.24,76.67 125.68,76.67 125.54,76.53 114.58,76.53 113.57,75.52 113.57,70.04 113.61,70 113.61,69.99 113.95,69.65 v2(113.95,69.2)
DA11P: length 135.5
  TOP w0.114: U5.N23 v2(112.95,70.2) ; J4.91 194.23,76.67 194.12,76.56 192.7,76.56 v1(192.41,76.85)
  L4-SIG2 w0.102: v1(192.41,76.85) 192.27,76.71 192.27,76.46 192.24,76.43 192.24,76.43 192.11,76.3 190.82,76.3 189.35,77.77 179.53,77.77 179.32,77.98 177.65,77.98 177.44,77.77 174.57,77.77 174.47,77.88 174.47,78.56 174.2,78.83 173.77,78.83 173.5,78.56 173.5,77.88 173.4,77.77 173.2,77.77 173.1,77.88 173.1,78.56 172.83,78.83 172.4,78.83 172.13,78.56 172.13,77.88 172.03,77.77 171.83,77.77 171.72,77.88 171.72,78.56 171.46,78.83 171.02,78.83 170.76,78.56 170.76,77.88 170.66,77.77 170.45,77.77 170.35,77.88 170.35,78.56 170.09,78.83 169.65,78.83 169.39,78.56 169.39,77.88 169.29,77.77 169.08,77.77 168.98,77.88 168.98,78.56 168.72,78.83 168.28,78.83 168.02,78.56 168.02,77.88 167.91,77.77 167.71,77.77 167.61,77.88 167.61,78.56 167.34,78.83 166.91,78.83 166.64,78.56 166.64,77.88 166.54,77.77 166.34,77.77 166.24,77.88 166.24,78.56 165.97,78.83 165.54,78.83 165.27,78.56 165.27,77.88 165.17,77.77 164.97,77.77 164.87,77.88 164.87,78.56 164.6,78.83 164.17,78.83 163.9,78.56 163.9,77.88 163.8,77.77 163.6,77.77 163.49,77.88 163.49,78.56 163.23,78.83 162.8,78.83 162.53,78.56 162.53,77.88 162.43,77.77 162.22,77.77 162.12,77.88 162.12,78.56 161.86,78.83 161.42,78.83 161.16,78.56 161.16,77.88 161.06,77.77 160.85,77.77 160.75,77.88 160.75,78.56 160.49,78.83 160.05,78.83 159.79,78.56 159.79,77.88 159.68,77.77 159.48,77.77 159.38,77.88 159.38,78.56 159.11,78.83 158.68,78.83 158.41,78.56 158.41,77.88 158.31,77.77 156.42,77.77 156.32,77.88 156.32,80.26 156.06,80.53 155.62,80.53 155.36,80.26 155.36,77.88 155.25,77.77 155.05,77.77 154.95,77.88 154.95,80.26 154.68,80.53 154.25,80.53 153.98,80.26 153.98,77.88 153.88,77.77 153.68,77.77 153.58,77.88 153.58,80.26 153.31,80.53 152.88,80.53 152.61,80.26 152.61,77.88 152.51,77.77 152.31,77.77 152.21,77.88 152.21,80.26 151.94,80.53 151.51,80.53 151.24,80.26 151.24,77.88 151.14,77.77 150.94,77.77 150.83,77.88 150.83,80.26 150.57,80.53 150.13,80.53 149.87,80.26 149.87,77.88 149.77,77.77 144.69,77.77 144.36,77.44 134.64,77.44 134.26,77.06 132.27,77.06 132.04,77.06 131.58,77.52 129.7,77.52 129.22,77.04 129.12,76.95 125.56,76.95 125.43,76.81 114.5,76.81 113.33,75.64 113.33,70.21 113.27,70.15 113,70.15 v2(112.95,70.2)
DA12N: length 135.4
  TOP w0.114: v1(191.26,77.52) 191.53,77.79 194.12,77.79 194.24,77.67 J4.87 ; U5.N27 v2(112.95,66.2)
  L10-SIG4 w0.102: v2(112.95,66.2) 113.33,66.58 115.21,66.58 115.57,66.94 115.57,68.38 115.77,68.58 116.21,68.58 116.57,68.94 116.57,73.42 116.57,73.42 116.57,74.04 116.57,75.04 116.57,77.04 116.57,77.46 116.69,77.58 129.05,77.58 130.59,76.04 130.6,76.04 131,75.64 145.81,75.64 145.97,75.8 147.65,77.47 148.69,77.47 152.23,73.93 158.02,73.93 158.28,74.2 158.28,75 158.38,75.1 158.59,75.1 158.69,75 158.69,74.2 158.95,73.93 159.39,73.93 159.65,74.2 159.65,75 159.75,75.1 159.96,75.1 160.06,75 160.06,74.2 160.32,73.93 160.76,73.93 161.02,74.2 161.02,75 161.13,75.1 161.33,75.1 161.43,75 161.43,74.2 161.7,73.93 162.13,73.93 162.4,74.2 162.4,75 162.5,75.1 162.7,75.1 162.8,75 162.8,74.2 163.07,73.93 163.5,73.93 163.77,74.2 163.77,75 163.87,75.1 164.07,75.1 164.17,75 164.17,74.2 164.44,73.93 164.87,73.93 165.14,74.2 165.14,75 165.24,75.1 165.44,75.1 165.55,75 165.55,74.2 165.81,73.93 166.25,73.93 166.51,74.2 166.51,75 166.61,75.1 166.82,75.1 166.92,75 166.92,74.2 167.18,73.93 167.62,73.93 167.88,74.2 167.88,75 167.98,75.1 168.19,75.1 168.29,75 168.29,74.2 168.55,73.93 168.99,73.93 169.25,74.2 169.25,75 169.36,75.1 169.56,75.1 169.66,75 169.66,74.2 169.93,73.93 170.36,73.93 170.63,74.2 170.63,75 170.73,75.1 170.93,75.1 171.03,75 171.03,74.2 171.3,73.93 171.73,73.93 172,74.2 172,75 172.1,75.1 172.3,75.1 172.4,75 172.4,74.2 172.67,73.93 173.1,73.93 173.37,74.2 173.37,75 173.47,75.1 173.67,75.1 173.77,75 173.77,74.2 174.04,73.93 174.47,73.93 174.74,74.2 174.74,75 174.84,75.1 175.04,75.1 175.15,75 175.15,74.2 175.41,73.93 175.85,73.93 176.11,74.2 176.11,75 176.21,75.1 176.42,75.1 176.52,75 176.52,74.2 176.78,73.93 177.22,73.93 177.48,74.2 177.48,75 177.58,75.1 177.79,75.1 177.89,75 177.89,74.2 178.15,73.93 178.59,73.93 178.85,74.2 178.85,75 178.96,75.1 179.16,75.1 179.26,75 179.26,74.2 179.53,73.93 179.96,73.93 180.23,74.2 180.23,75 180.33,75.1 180.53,75.1 180.63,75 180.63,74.2 180.9,73.93 181.33,73.93 181.6,74.2 181.6,75 181.7,75.1 181.9,75.1 182,75 182,74.2 182.27,73.93 182.7,73.93 182.97,74.2 182.97,75 183.07,75.1 183.27,75.1 183.38,75 183.38,74.2 183.64,73.93 184.08,73.93 184.34,74.2 184.34,75 184.44,75.1 184.65,75.1 184.75,75 184.75,74.2 185.01,73.93 186.16,73.93 190.05,77.83 190.99,77.83 191.26,77.55 v1(191.26,77.52)
DA12P: length 135.5
  TOP w0.114: J4.85 194.22,78.17 194.13,78.08 191.52,78.08 v1(191.26,78.34) ; U5.M26 v2(113.95,67.2)
  L10-SIG4 w0.102: v1(191.26,78.34) 191.03,78.11 190.17,78.11 190.17,78.11 189.94,78.11 189.92,78.11 186.03,74.21 185.13,74.21 185.03,74.32 185.03,75.11 184.76,75.38 184.33,75.38 184.06,75.11 184.06,74.32 183.96,74.21 183.76,74.21 183.66,74.32 183.66,75.11 183.39,75.38 182.96,75.38 182.69,75.11 182.69,74.32 182.59,74.21 182.39,74.21 182.28,74.32 182.28,75.11 182.02,75.38 181.58,75.38 181.32,75.11 181.32,74.32 181.22,74.21 181.01,74.21 180.91,74.32 180.91,75.11 180.65,75.38 180.21,75.38 179.95,75.11 179.95,74.32 179.85,74.21 179.64,74.21 179.54,74.32 179.54,75.11 179.28,75.38 178.84,75.38 178.58,75.11 178.58,74.32 178.47,74.21 178.27,74.21 178.17,74.32 178.17,75.11 177.9,75.38 177.47,75.38 177.2,75.11 177.2,74.32 177.1,74.21 176.9,74.21 176.8,74.32 176.8,75.11 176.53,75.38 176.1,75.38 175.83,75.11 175.83,74.32 175.73,74.21 175.53,74.21 175.43,74.32 175.43,75.11 175.16,75.38 174.73,75.38 174.46,75.11 174.46,74.32 174.36,74.21 174.16,74.21 174.05,74.32 174.05,75.11 173.79,75.38 173.35,75.38 173.09,75.11 173.09,74.32 172.99,74.21 172.78,74.21 172.68,74.32 172.68,75.11 172.42,75.38 171.98,75.38 171.72,75.11 171.72,74.32 171.62,74.21 171.41,74.21 171.31,74.32 171.31,75.11 171.05,75.38 170.61,75.38 170.35,75.11 170.35,74.32 170.24,74.21 170.04,74.21 169.94,74.32 169.94,75.11 169.67,75.38 169.24,75.38 168.97,75.11 168.97,74.32 168.87,74.21 168.67,74.21 168.57,74.32 168.57,75.11 168.3,75.38 167.87,75.38 167.6,75.11 167.6,74.32 167.5,74.21 167.3,74.21 167.2,74.32 167.2,75.11 166.93,75.38 166.5,75.38 166.23,75.11 166.23,74.32 166.13,74.21 165.93,74.21 165.82,74.32 165.82,75.11 165.56,75.38 165.12,75.38 164.86,75.11 164.86,74.32 164.76,74.21 164.55,74.21 164.45,74.32 164.45,75.11 164.19,75.38 163.75,75.38 163.49,75.11 163.49,74.32 163.39,74.21 163.18,74.21 163.08,74.32 163.08,75.11 162.82,75.38 162.38,75.38 162.12,75.11 162.12,74.32 162.01,74.21 161.81,74.21 161.71,74.32 161.71,75.11 161.44,75.38 161.01,75.38 160.74,75.11 160.74,74.32 160.64,74.21 160.44,74.21 160.34,74.32 160.34,75.11 160.07,75.38 159.64,75.38 159.37,75.11 159.37,74.32 159.27,74.21 159.07,74.21 158.97,74.32 158.97,75.11 158.7,75.38 158.27,75.38 158,75.11 158,74.32 157.9,74.21 152.35,74.21 148.82,77.75 148.81,77.75 147.53,77.75 147.37,77.59 145.7,75.92 131.12,75.92 129.16,77.88 125.32,77.88 125.27,77.82 116.59,77.82 116.33,77.56 116.33,77.46 116.33,77.46 116.33,76.94 116.33,76.94 116.33,75.46 116.33,75.46 116.33,74.94 116.33,74.94 116.33,74.46 116.33,74.46 116.33,73.94 116.33,73.94 116.33,73.52 116.33,73.51 116.33,69.04 116.11,68.82 115.67,68.82 115.33,68.48 115.33,67.04 115.11,66.82 113.69,66.82 113.51,67 113.51,67.2 113.61,67.3 113.85,67.3 v2(113.95,67.2)
DA13N: length 135.3
  TOP w0.114: U5.K27 v2(115.95,66.2) ; v1(192.41,79.03) 192.41,79.04 192.63,79.26 194.14,79.26 194.23,79.17 J4.81
  L10-SIG4 w0.102: v2(115.95,66.2) 115.95,66.29 116.05,66.4 116.26,66.4 116.31,66.34 116.31,65.87 116.26,65.82 114.11,65.82 114.11,65.82 113.79,65.82 113.79,65.82 113.11,65.82 113.11,65.82 112.79,65.82 112.57,66.04 112.57,67.43 112.72,67.58 113.21,67.58 113.23,67.61 113.67,67.61 113.69,67.58 114.21,67.58 114.57,67.94 114.57,68.36 114.58,68.37 114.58,69.03 114.57,69.04 114.57,69.36 114.79,69.58 115.28,69.58 115.62,69.92 115.62,71.42 115.57,71.47 115.57,78.46 115.69,78.58 124.3,78.58 124.35,78.62 125.19,78.62 125.23,78.58 131.74,78.58 131.86,78.58 132.72,77.72 135.25,77.72 136.12,78.59 149.24,78.59 151.19,76.63 157.23,76.63 157.84,77.24 158.28,77.24 158.35,77.17 158.35,76.62 158.62,76.35 159.05,76.35 159.32,76.62 159.32,77.36 159.42,77.46 159.62,77.46 159.72,77.36 159.72,76.62 159.99,76.35 160.42,76.35 160.69,76.62 160.69,77.36 160.79,77.46 160.99,77.46 161.1,77.36 161.1,76.62 161.36,76.35 161.8,76.35 162.06,76.62 162.06,77.36 162.16,77.46 162.37,77.46 162.47,77.36 162.47,76.62 162.73,76.35 163.17,76.35 163.43,76.62 163.43,77.36 163.53,77.46 163.74,77.46 163.84,77.36 163.84,76.62 164.1,76.35 164.54,76.35 164.8,76.62 164.8,77.36 164.91,77.46 165.11,77.46 165.21,77.36 165.21,76.62 165.48,76.35 165.91,76.35 166.18,76.62 166.18,77.36 166.28,77.46 166.48,77.46 166.58,77.36 166.58,76.62 166.85,76.35 167.28,76.35 167.55,76.62 167.55,77.36 167.65,77.46 167.85,77.46 167.95,77.36 167.95,76.62 168.22,76.35 168.65,76.35 168.92,76.62 168.92,77.36 169.02,77.46 169.22,77.46 169.33,77.36 169.33,76.62 169.59,76.35 170.03,76.35 170.29,76.62 170.29,77.36 170.39,77.46 170.6,77.46 170.7,77.36 170.7,76.62 170.96,76.35 171.4,76.35 171.66,76.62 171.66,77.36 171.76,77.46 171.97,77.46 172.07,77.36 172.07,76.62 172.33,76.35 172.77,76.35 173.03,76.62 173.03,77.36 173.14,77.46 173.34,77.46 173.44,77.36 173.44,76.62 173.71,76.35 174.14,76.35 174.41,76.62 174.41,77.36 174.51,77.46 174.71,77.46 174.81,77.36 174.81,76.62 175.08,76.35 175.51,76.35 175.78,76.62 175.78,77.36 175.88,77.46 176.08,77.46 176.18,77.36 176.18,76.62 176.45,76.35 176.88,76.35 177.15,76.62 177.15,77.36 177.25,77.46 177.45,77.46 177.55,77.36 177.55,76.62 177.82,76.35 178.25,76.35 178.52,76.62 178.52,77.36 178.62,77.46 178.82,77.46 178.93,77.36 178.93,76.62 179.19,76.35 179.63,76.35 179.89,76.62 179.89,77.36 179.99,77.46 180.2,77.46 180.3,77.36 180.3,76.62 180.56,76.35 181,76.35 181.26,76.62 181.26,77.36 181.36,77.46 181.57,77.46 181.67,77.36 181.67,76.62 181.93,76.35 182.37,76.35 182.63,76.62 182.63,77.36 182.74,77.46 182.94,77.46 183.04,77.36 183.04,76.65 183.33,76.35 187.1,76.35 189.97,79.23 192.17,79.23 192.37,79.03 v1(192.41,79.03)
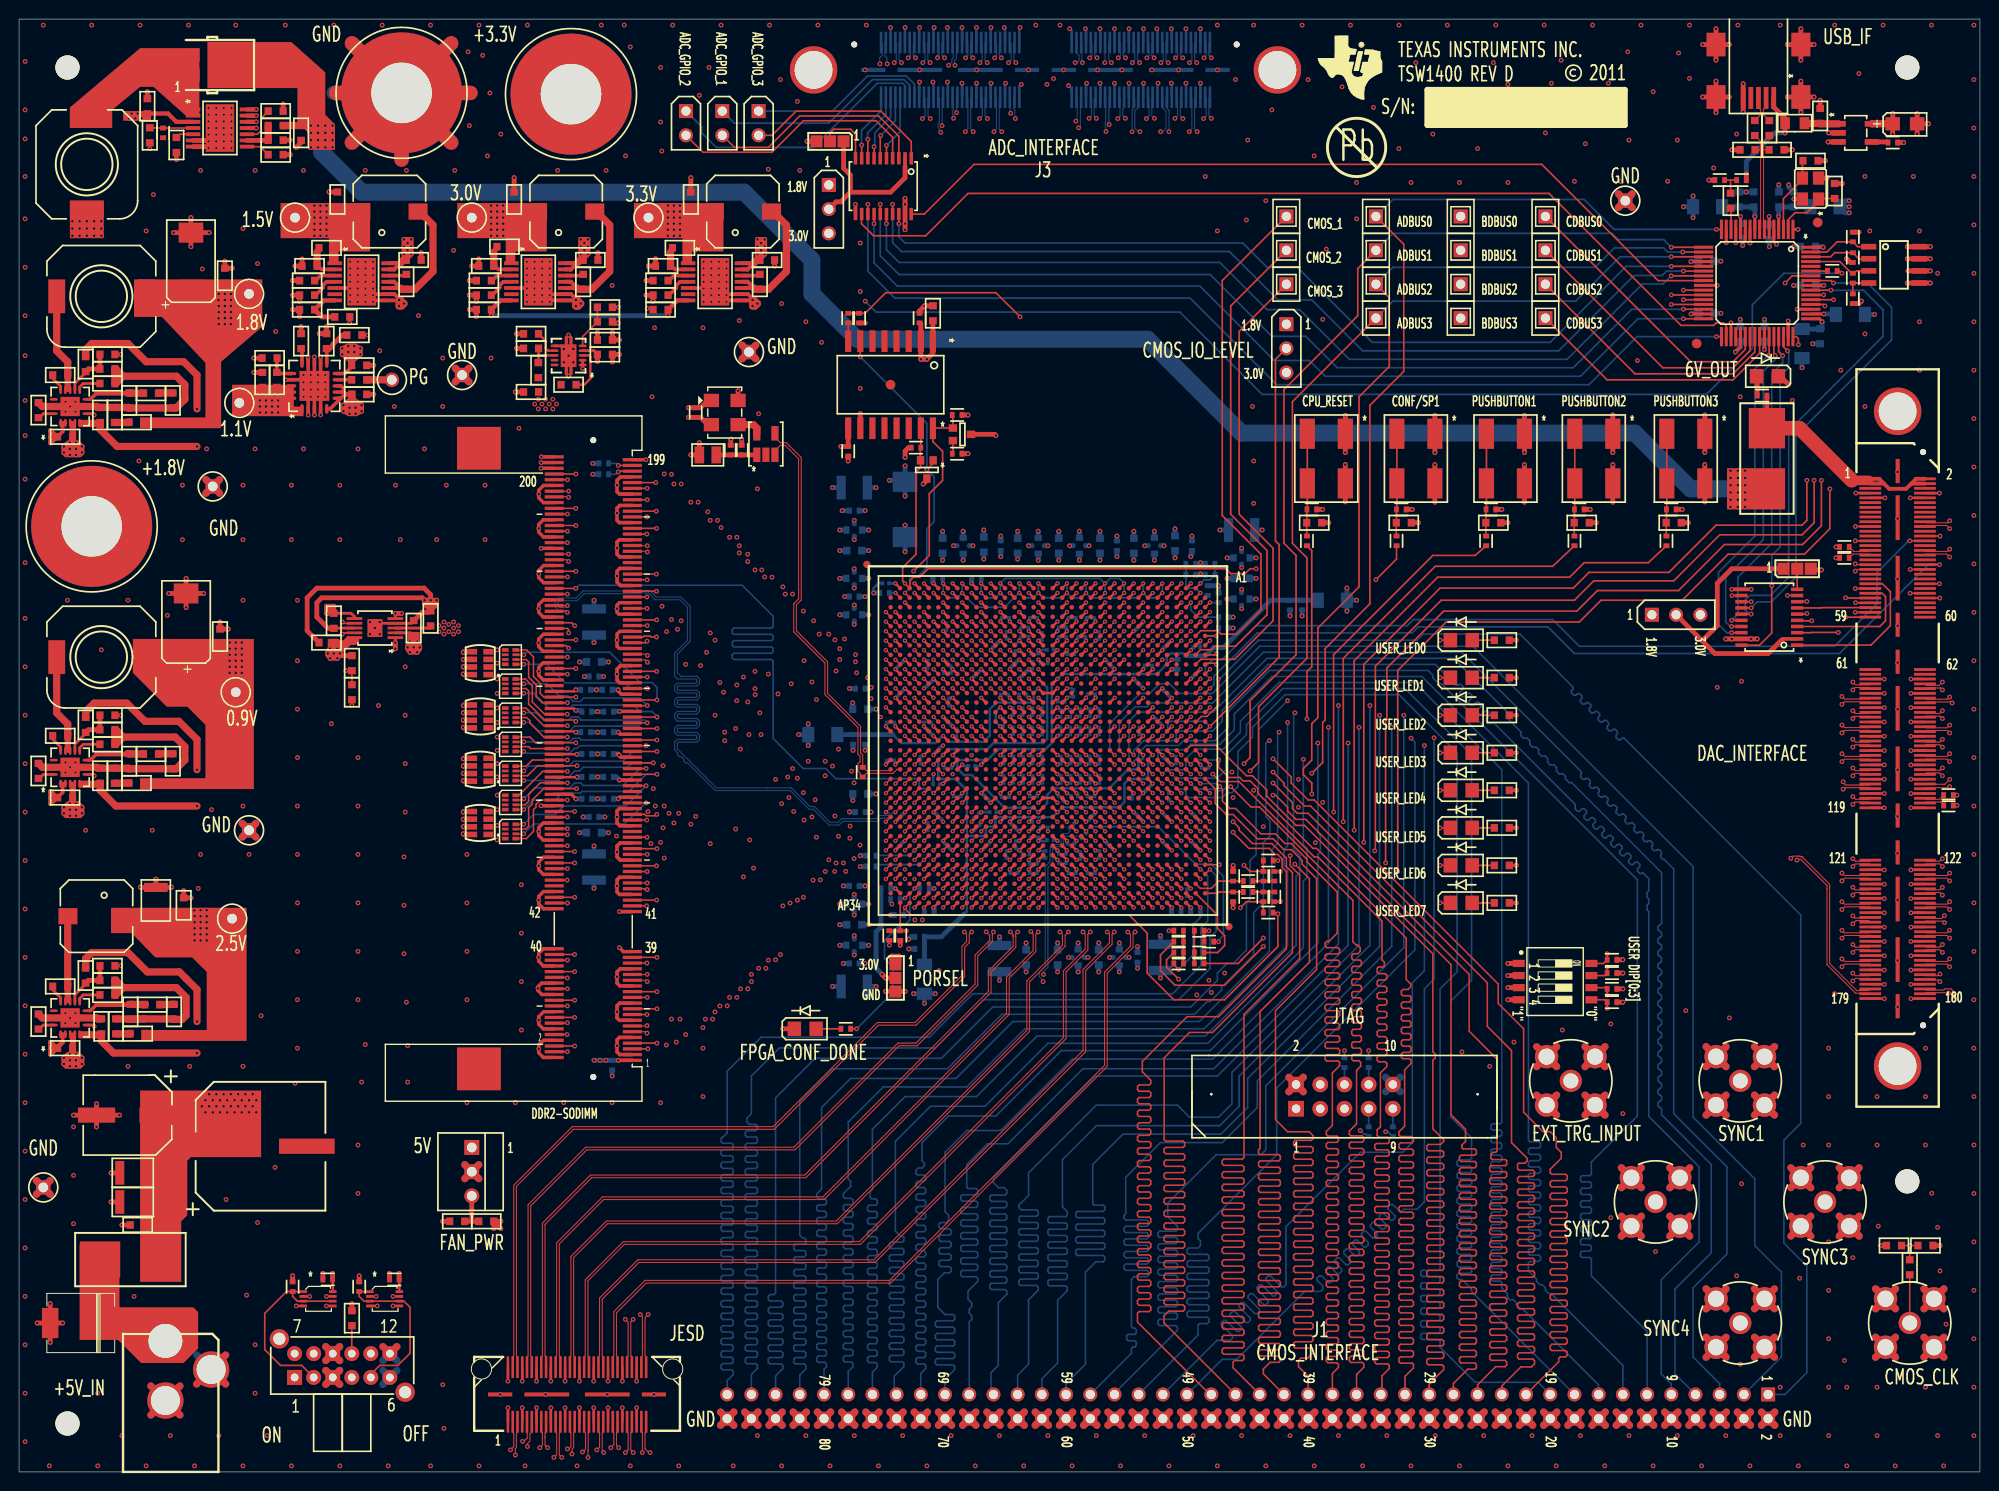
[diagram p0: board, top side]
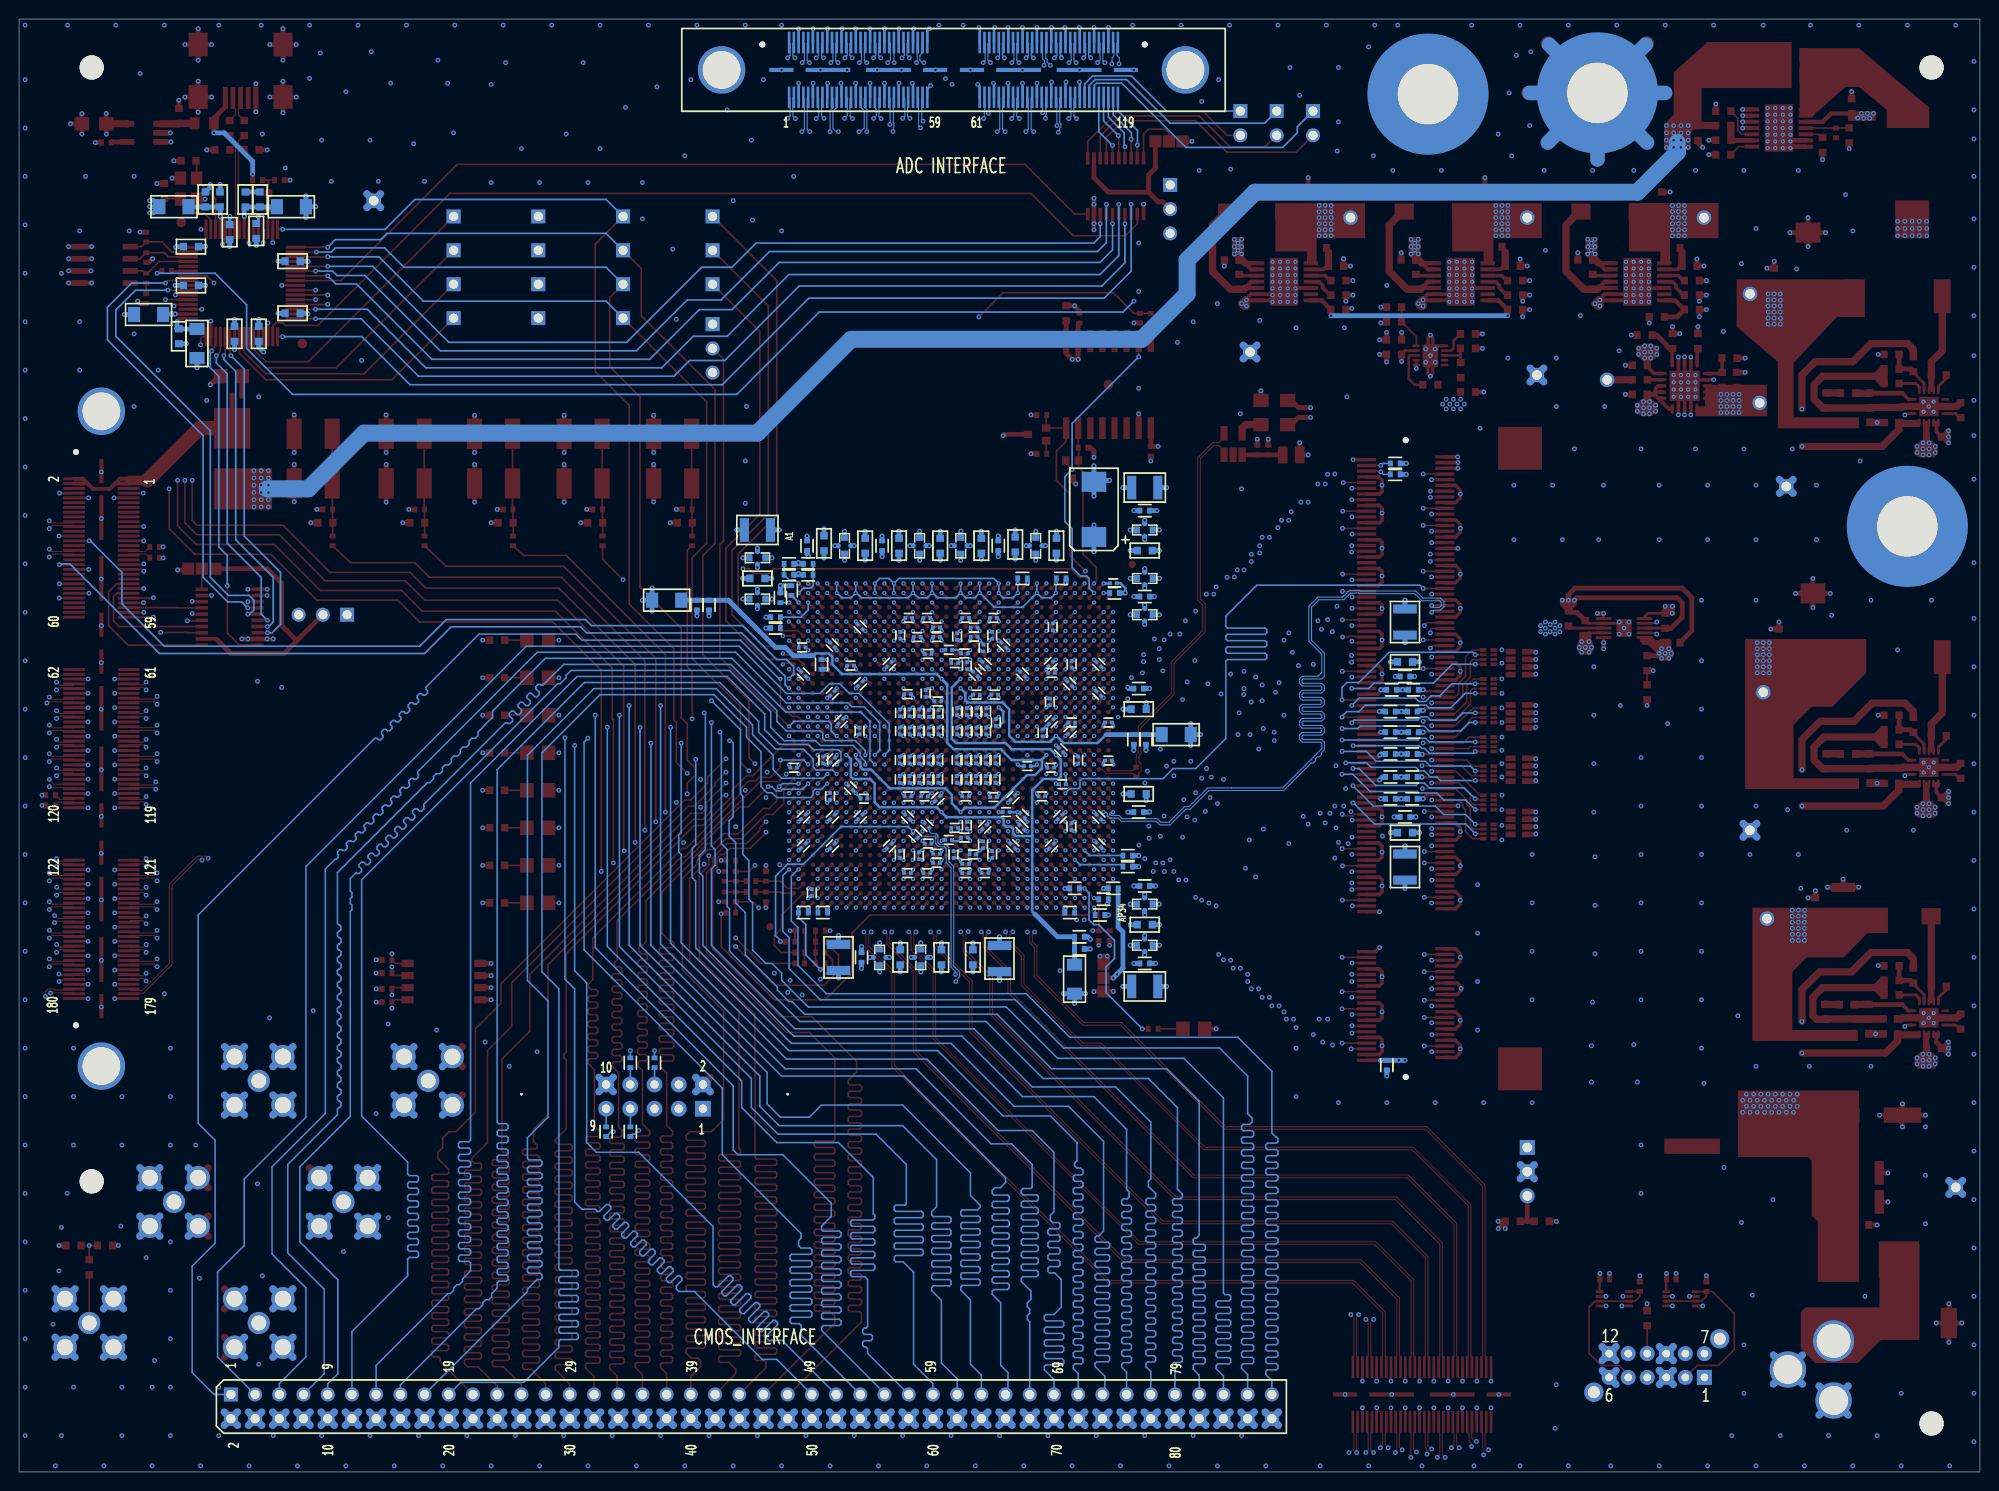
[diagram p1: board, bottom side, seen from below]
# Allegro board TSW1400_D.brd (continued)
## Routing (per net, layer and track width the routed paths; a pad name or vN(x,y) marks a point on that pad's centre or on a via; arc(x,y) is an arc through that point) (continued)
DA13P: length 135.5
  TOP w0.114: J4.79 194.23,79.67 194.12,79.55 192.7,79.55 v1(192.41,79.85) ; U5.K26 v2(115.95,67.2)
  L10-SIG4 w0.102: v2(115.95,67.2) 116.56,66.59 116.56,65.79 116.36,65.58 114.21,65.58 114.21,65.58 113.69,65.58 113.69,65.58 113.21,65.58 113.21,65.58 112.69,65.58 112.33,65.94 112.33,67.55 112.6,67.82 113.11,67.82 113.13,67.84 113.77,67.84 113.79,67.82 114.11,67.82 114.33,68.04 114.33,68.46 114.34,68.47 114.34,68.93 114.33,68.94 114.33,69.46 114.69,69.82 115.18,69.82 115.38,70.02 115.38,71.32 115.33,71.37 115.33,78.58 115.61,78.86 118.75,78.86 118.79,78.82 124.21,78.82 124.25,78.86 131.63,78.86 131.97,78.86 132.14,78.7 132.83,78 135.14,78 136,78.87 149.35,78.87 151.31,76.91 157.1,76.91 157.67,77.48 157.67,77.48 157.93,77.74 158.37,77.74 158.63,77.48 158.63,76.74 158.73,76.63 158.94,76.63 159.04,76.74 159.04,77.48 159.3,77.74 159.74,77.74 160,77.48 160,76.74 160.11,76.63 160.31,76.63 160.41,76.74 160.41,77.48 160.68,77.74 161.11,77.74 161.38,77.48 161.38,76.74 161.48,76.63 161.68,76.63 161.78,76.74 161.78,77.48 162.05,77.74 162.48,77.74 162.75,77.48 162.75,76.74 162.85,76.63 163.05,76.63 163.15,76.74 163.15,77.48 163.42,77.74 163.85,77.74 164.12,77.48 164.12,76.74 164.22,76.63 164.42,76.63 164.52,76.74 164.52,77.48 164.79,77.74 165.22,77.74 165.49,77.48 165.49,76.74 165.59,76.63 165.79,76.63 165.9,76.74 165.9,77.48 166.16,77.74 166.6,77.74 166.86,77.48 166.86,76.74 166.96,76.63 167.17,76.63 167.27,76.74 167.27,77.48 167.53,77.74 167.97,77.74 168.23,77.48 168.23,76.74 168.33,76.63 168.54,76.63 168.64,76.74 168.64,77.48 168.9,77.74 169.34,77.74 169.6,77.48 169.6,76.74 169.71,76.63 169.91,76.63 170.01,76.74 170.01,77.48 170.28,77.74 170.71,77.74 170.98,77.48 170.98,76.74 171.08,76.63 171.28,76.63 171.38,76.74 171.38,77.48 171.65,77.74 172.08,77.74 172.35,77.48 172.35,76.74 172.45,76.63 172.65,76.63 172.75,76.74 172.75,77.48 173.02,77.74 173.45,77.74 173.72,77.48 173.72,76.74 173.82,76.63 174.02,76.63 174.13,76.74 174.13,77.48 174.39,77.74 174.83,77.74 175.09,77.48 175.09,76.74 175.19,76.63 175.4,76.63 175.5,76.74 175.5,77.48 175.76,77.74 176.2,77.74 176.46,77.48 176.46,76.74 176.56,76.63 176.77,76.63 176.87,76.74 176.87,77.48 177.13,77.74 177.57,77.74 177.83,77.48 177.83,76.74 177.94,76.63 178.14,76.63 178.24,76.74 178.24,77.48 178.51,77.74 178.94,77.74 179.21,77.48 179.21,76.74 179.31,76.63 179.51,76.63 179.61,76.74 179.61,77.48 179.88,77.74 180.31,77.74 180.58,77.48 180.58,76.74 180.68,76.63 180.88,76.63 180.98,76.74 180.98,77.48 181.25,77.74 183.06,77.74 183.32,77.48 183.32,77.16 183.84,76.63 186.98,76.63 189.86,79.51 192.07,79.51 v1(192.41,79.85)
DA14N: length 135.4
  TOP w0.114: J4.75 194.24,80.68 194.13,80.78 191.53,80.78 v1(191.26,80.52) ; U5.L23 v2(114.95,70.2)
  L10-SIG4 w0.102: v1(191.26,80.52) 190.4,81.38 186.96,81.38 184.03,78.44 183.38,78.44 183.12,78.71 183.12,79.65 183.02,79.76 182.81,79.76 182.71,79.65 182.71,78.71 182.45,78.44 182.01,78.44 181.75,78.71 181.75,79.65 181.65,79.76 181.44,79.76 181.34,79.65 181.34,78.71 181.08,78.44 180.64,78.44 180.38,78.71 180.38,79.65 180.27,79.76 180.07,79.76 179.97,79.65 179.97,78.71 179.7,78.44 179.27,78.44 179,78.71 179,79.65 178.9,79.76 178.7,79.76 178.6,79.65 178.6,78.71 178.33,78.44 177.9,78.44 177.63,78.71 177.63,79.65 177.53,79.76 177.33,79.76 177.23,79.65 177.23,78.71 176.96,78.44 176.53,78.44 176.26,78.71 176.26,79.65 176.16,79.76 175.96,79.76 175.85,79.65 175.85,78.71 175.59,78.44 175.15,78.44 174.89,78.71 174.89,79.65 174.79,79.76 174.58,79.76 174.48,79.65 174.48,78.71 174.22,78.44 173.78,78.44 173.52,78.71 173.52,79.65 173.42,79.76 173.21,79.76 173.11,79.65 173.11,78.71 172.85,78.44 172.41,78.44 172.15,78.71 172.15,79.65 172.04,79.76 171.84,79.76 171.74,79.65 171.74,78.71 171.47,78.44 171.04,78.44 170.77,78.71 170.77,79.65 170.67,79.76 170.47,79.76 170.37,79.65 170.37,78.71 170.1,78.44 169.67,78.44 169.4,78.71 169.4,79.65 169.3,79.76 169.1,79.76 169,79.65 169,78.71 168.73,78.44 168.3,78.44 168.03,78.71 168.03,79.65 167.93,79.76 167.73,79.76 167.62,79.65 167.62,78.71 167.36,78.44 166.92,78.44 166.66,78.71 166.66,79.65 166.56,79.76 166.35,79.76 166.25,79.65 166.25,78.71 165.99,78.44 165.55,78.44 165.29,78.71 165.29,79.65 165.19,79.76 164.98,79.76 164.88,79.65 164.88,78.71 164.62,78.44 164.18,78.44 163.92,78.71 163.92,79.65 163.81,79.76 163.61,79.76 163.51,79.65 163.51,78.71 163.24,78.44 162.81,78.44 162.54,78.71 162.54,79.65 162.44,79.76 162.24,79.76 162.14,79.65 162.14,78.71 161.87,78.44 161.44,78.44 161.17,78.71 161.17,79.65 161.07,79.76 160.87,79.76 160.77,79.65 160.77,78.71 160.5,78.44 160.07,78.44 159.8,78.71 159.8,79.65 159.7,79.76 159.5,79.76 159.39,79.65 159.39,78.71 159.13,78.44 158.69,78.44 158.43,78.71 158.43,79.65 158.33,79.76 158.12,79.76 158.02,79.65 158.02,78.71 157.76,78.44 151.34,78.44 150.04,79.74 150.01,79.74 149.48,80.26 144.83,80.26 143.34,81.76 132.82,81.76 131.63,80.58 120.69,80.58 118.79,80.58 116.52,80.58 114.56,78.61 114.56,75.47 114.57,75.46 114.57,74.94 114.42,74.79 114.42,70.58 114.8,70.2 v2(114.95,70.2)
DA14P: length 135.4
  TOP w0.114: v1(191.26,81.34) 191.53,81.08 194.13,81.08 194.22,81.17 J4.73 ; U5.M23 v2(113.95,70.2)
  L10-SIG4 w0.102: v2(113.95,70.2) 114.18,70.43 114.18,74.89 114.33,75.04 114.33,75.36 114.32,75.37 114.32,78.71 116.42,80.82 118.69,80.82 120.59,80.82 125.31,80.82 125.35,80.86 131.52,80.86 132.7,82.04 143.45,82.04 144.95,80.54 149.6,80.54 150.12,80.02 150.16,80.02 151.45,78.72 157.64,78.72 157.74,78.82 157.74,79.77 158.01,80.04 158.44,80.04 158.71,79.77 158.71,78.82 158.81,78.72 159.01,78.72 159.12,78.82 159.12,79.77 159.38,80.04 159.82,80.04 160.08,79.77 160.08,78.82 160.18,78.72 160.39,78.72 160.49,78.82 160.49,79.77 160.75,80.04 161.19,80.04 161.45,79.77 161.45,78.82 161.55,78.72 161.76,78.72 161.86,78.82 161.86,79.77 162.12,80.04 162.56,80.04 162.82,79.77 162.82,78.82 162.93,78.72 163.13,78.72 163.23,78.82 163.23,79.77 163.5,80.04 163.93,80.04 164.2,79.77 164.2,78.82 164.3,78.72 164.5,78.72 164.6,78.82 164.6,79.77 164.87,80.04 165.3,80.04 165.57,79.77 165.57,78.82 165.67,78.72 165.87,78.72 165.97,78.82 165.97,79.77 166.24,80.04 166.67,80.04 166.94,79.77 166.94,78.82 167.04,78.72 167.24,78.72 167.35,78.82 167.35,79.77 167.61,80.04 168.05,80.04 168.31,79.77 168.31,78.82 168.41,78.72 168.62,78.72 168.72,78.82 168.72,79.77 168.98,80.04 169.42,80.04 169.68,79.77 169.68,78.82 169.78,78.72 169.99,78.72 170.09,78.82 170.09,79.77 170.35,80.04 170.79,80.04 171.05,79.77 171.05,78.82 171.16,78.72 171.36,78.72 171.46,78.82 171.46,79.77 171.73,80.04 172.16,80.04 172.43,79.77 172.43,78.82 172.53,78.72 172.73,78.72 172.83,78.82 172.83,79.77 173.1,80.04 173.53,80.04 173.8,79.77 173.8,78.82 173.9,78.72 174.1,78.72 174.2,78.82 174.2,79.77 174.47,80.04 174.9,80.04 175.17,79.77 175.17,78.82 175.27,78.72 175.47,78.72 175.57,78.82 175.57,79.77 175.84,80.04 176.27,80.04 176.54,79.77 176.54,78.82 176.64,78.72 176.84,78.72 176.95,78.82 176.95,79.77 177.21,80.04 177.65,80.04 177.91,79.77 177.91,78.82 178.01,78.72 178.22,78.72 178.32,78.82 178.32,79.77 178.58,80.04 179.02,80.04 179.28,79.77 179.28,78.82 179.38,78.72 179.59,78.72 179.69,78.82 179.69,79.77 179.95,80.04 180.39,80.04 180.65,79.77 180.65,78.82 180.76,78.72 180.96,78.72 181.06,78.82 181.06,79.77 181.33,80.04 181.76,80.04 182.03,79.77 182.03,78.82 182.13,78.72 182.33,78.72 182.43,78.82 182.43,79.77 182.7,80.04 183.13,80.04 183.4,79.77 183.4,78.82 183.5,78.72 183.91,78.72 186.85,81.66 190.92,81.66 191.24,81.33 191.25,81.33 v1(191.26,81.34)
DA15N: length 135.3
  TOP w0.114: U5.K24 v2(115.95,69.2) ; J4.69 194.23,82.17 194.12,82.28 192.65,82.28 192.41,82.04 v1(192.41,82.03)
  L9-SIG3 w0.102: v1(192.4,82.03) 192.06,82.37 185.43,82.37 183.5,84.3 180.92,84.3 180.65,84.57 180.65,85.72 180.55,85.83 180.35,85.83 180.24,85.72 180.24,84.57 179.98,84.3 179.54,84.3 179.28,84.57 179.28,85.72 179.18,85.83 178.97,85.83 178.87,85.72 178.87,84.57 178.61,84.3 178.17,84.3 177.91,84.57 177.91,85.72 177.81,85.83 177.6,85.83 177.5,85.72 177.5,84.57 177.24,84.3 176.8,84.3 176.54,84.57 176.54,85.72 176.43,85.83 176.23,85.83 176.13,85.72 176.13,84.57 175.86,84.3 175.43,84.3 175.16,84.57 175.16,85.72 175.06,85.83 174.86,85.83 174.76,85.72 174.76,84.57 174.49,84.3 174.06,84.3 173.79,84.57 173.79,85.72 173.69,85.83 173.49,85.83 173.39,85.72 173.39,84.57 173.12,84.3 172.69,84.3 172.42,84.57 172.42,85.72 172.32,85.83 172.12,85.83 172.01,85.72 172.01,84.57 171.75,84.3 171.31,84.3 171.05,84.57 171.05,85.72 170.95,85.83 170.74,85.83 170.64,85.72 170.64,84.57 170.38,84.3 169.94,84.3 169.68,84.57 169.68,85.72 169.58,85.83 169.37,85.83 169.27,85.72 169.27,84.57 169.01,84.3 168.57,84.3 168.31,84.57 168.31,85.72 168.2,85.83 168,85.83 167.9,85.72 167.9,84.57 167.63,84.3 167.2,84.3 166.93,84.57 166.93,85.72 166.83,85.83 166.63,85.83 166.53,85.72 166.53,84.57 166.26,84.3 165.83,84.3 165.56,84.57 165.56,85.72 165.46,85.83 165.26,85.83 165.16,85.72 165.16,84.57 164.89,84.3 164.46,84.3 164.19,84.57 164.19,85.72 164.09,85.83 163.89,85.83 163.78,85.72 163.78,84.57 163.52,84.3 161.57,84.3 156.49,89.38 145.89,89.38 145.54,89.03 145.54,88.92 145.14,88.52 144.71,88.52 144.44,88.78 144.44,88.9 144.34,89 144.14,89 144.04,88.9 144.04,88.78 143.77,88.52 143.34,88.52 143.07,88.78 143.07,88.9 142.97,89 142.77,89 142.66,88.9 142.66,88.78 142.4,88.52 141.96,88.52 141.7,88.78 141.7,88.9 141.6,89 141.39,89 141.29,88.9 141.29,88.78 141.03,88.52 140.59,88.52 140.33,88.78 140.33,88.9 140.23,89 140.02,89 139.92,88.9 139.92,88.78 139.66,88.52 139.22,88.52 138.96,88.78 138.96,88.9 138.85,89 138.65,89 138.55,88.9 138.55,88.78 138.28,88.52 137.85,88.52 137.58,88.78 137.58,88.9 137.48,89 136.46,89 131.03,83.57 125.46,83.57 125.48,83.58 122.57,83.58 120.02,81.03 119,81.03 118.75,80.77 118.7,80.77 117.51,79.58 115.63,79.58 115.23,79.18 115.23,79.16 114.57,78.5 114.57,76.83 115.57,75.83 115.57,69.58 v2(115.95,69.2)
DA15P: length 135.4
  TOP w0.114: v1(192.41,82.85) 192.68,82.58 194.14,82.58 194.23,82.67 J4.67 ; U5.L24 v2(114.95,69.2)
  L9-SIG3 w0.102: v2(114.95,69.2) 115.33,69.58 115.33,75.74 114.33,76.74 114.33,78.63 115.49,79.82 117.41,79.82 118.6,81.01 118.65,81.01 118.9,81.26 119.87,81.26 122.43,83.82 125.31,83.82 125.35,83.86 125.66,83.86 125.68,83.85 130.91,83.85 136.35,89.28 137.6,89.28 137.86,89.02 137.86,88.9 137.96,88.8 138.17,88.8 138.27,88.9 138.27,89.02 138.53,89.28 138.97,89.28 139.23,89.02 139.23,88.9 139.34,88.8 139.54,88.8 139.64,88.9 139.64,89.02 139.91,89.28 140.34,89.28 140.61,89.02 140.61,88.9 140.71,88.8 140.91,88.8 141.01,88.9 141.01,89.02 141.28,89.28 141.71,89.28 141.98,89.02 141.98,88.9 142.08,88.8 142.28,88.8 142.38,88.9 142.38,89.02 142.65,89.28 143.08,89.28 143.35,89.02 143.35,88.9 143.45,88.8 143.65,88.8 143.76,88.9 143.76,89.02 144.02,89.28 144.46,89.28 144.84,88.9 145.01,88.9 145.77,89.66 156.61,89.66 161.69,84.58 163.4,84.58 163.51,84.68 163.51,85.84 163.77,86.11 164.21,86.11 164.47,85.84 164.47,84.68 164.57,84.58 164.78,84.58 164.88,84.68 164.88,85.84 165.14,86.11 165.58,86.11 165.84,85.84 165.84,84.68 165.94,84.58 166.15,84.58 166.25,84.68 166.25,85.84 166.51,86.11 166.95,86.11 167.21,85.84 167.21,84.68 167.32,84.58 167.52,84.58 167.62,84.68 167.62,85.84 167.89,86.11 168.32,86.11 168.59,85.84 168.59,84.68 168.69,84.58 168.89,84.58 168.99,84.68 168.99,85.84 169.26,86.11 169.69,86.11 169.96,85.84 169.96,84.68 170.06,84.58 170.26,84.58 170.36,84.68 170.36,85.84 170.63,86.11 171.06,86.11 171.33,85.84 171.33,84.68 171.43,84.58 171.63,84.58 171.74,84.68 171.74,85.84 172,86.11 172.43,86.11 172.7,85.84 172.7,84.68 172.8,84.58 173.01,84.58 173.11,84.68 173.11,85.84 173.37,86.11 173.81,86.11 174.07,85.84 174.07,84.68 174.17,84.58 174.38,84.58 174.48,84.68 174.48,85.84 174.74,86.11 175.18,86.11 175.44,85.84 175.44,84.68 175.55,84.58 175.75,84.58 175.85,84.68 175.85,85.84 176.12,86.11 176.55,86.11 176.82,85.84 176.82,84.68 176.92,84.58 177.12,84.58 177.22,84.68 177.22,85.84 177.49,86.11 177.92,86.11 178.19,85.84 178.19,84.68 178.29,84.58 178.49,84.58 178.59,84.68 178.59,85.84 178.86,86.11 179.29,86.11 179.56,85.84 179.56,84.68 179.66,84.58 179.86,84.58 179.96,84.68 179.96,85.84 180.23,86.11 180.66,86.11 180.93,85.84 180.93,84.68 181.03,84.58 183.62,84.58 185.55,82.65 192.2,82.65 192.4,82.85 v1(192.41,82.85)
DAC_0: length 35.8
  TOP w0.178: U3.46 185.12,118.03 v1(185.55,117.6) ; v1(183.9,92.96) 183.9,88.01 182.62,86.73 U17.20
  BOTTOM w0.178: v1(185.55,117.6) 185.67,117.47 185.67,115.82 184.78,114.94 184.78,97.03 183.9,96.14 v1(183.9,92.96)
DAC_1: length 35.2
  TOP w0.178: U3.43 183.62,117.22 183.51,117.11 v1(183.51,117.09) ; U17.18 v1(179.68,88.03)
  BOTTOM w0.178: v1(179.68,88.03) 179.18,88.03 178.31,88.9 178.31,94.36 182.12,98.17 182.12,115.7 v1(183.51,117.09)
DAC_2: length 34
  TOP w0.178: U17.17 v1(179.68,88.68) ; U3.44 184.12,117.23 v1(184.25,117.09)
  BOTTOM w0.178: v1(184.25,117.09) 184.25,116.69 183.01,115.44 183.01,97.79 179.07,93.85 179.07,89.15 179.54,88.68 v1(179.68,88.68)
DAC_3: length 33.2
  TOP w0.178: v1(185.04,117.09) 184.62,117.51 U3.45 ; U17.16 v1(179.68,89.33)
  BOTTOM w0.178: v1(185.04,117.09) 185.04,116.33 183.9,115.19 183.9,97.41 180.34,93.85 180.34,89.99 v1(179.68,89.33)
DAC_4: length 49
  TOP w0.178: U3.55 v1(190.12,123.96) ; U17.15 v1(181.74,89.98)
  BOTTOM w0.178: v1(190.12,123.96) 190.13,123.95 193.52,123.95 195.58,121.89 195.58,119.13 185.67,109.22 185.67,93.85 183.77,91.95 181.61,91.95 181.1,91.44 181.1,90.42 181.52,90.01 181.72,90.01 v1(181.74,89.98)
DAC_5: length 49.2
  TOP w0.178: v1(190.37,124.71) 190.12,124.96 U3.57 ; U17.14 v1(181.74,90.63)
  BOTTOM w0.178: v1(181.74,90.63) 182.37,91.26 183.84,91.26 186.44,93.85 186.44,108.71 196.47,118.75 196.47,122.17 193.93,124.71 v1(190.37,124.71)
DAC_6: length 68.3
  TOP w0.178: U17.13 v1(181.74,91.28) ; U5.B11 v2(123.95,83.2)
  L3-SIG1 w0.178: v1(181.74,91.28) 180.72,90.26 v1(180.72,82.93)
  L10-SIG4 w0.102: v2(123.95,83.2) 123.95,83.06 124.33,82.68 125.35,82.68
  L10-SIG4 w0.178: 125.35,82.68 129.79,82.68 130.43,83.31 146.3,83.31 147.07,82.55 177.29,82.55 177.67,82.93 v1(180.72,82.93)
DAC_7: length 67.5
  TOP w0.178: U5.B12 v2(123.95,82.2) ; U17.12 v1(179.72,91.93)
  L3-SIG1 w0.178: v1(179.72,91.93) 178.18,90.39 v1(178.18,82.3)
  L10-SIG4 w0.102: 125.35,81.66 124.46,81.66 123.95,82.17 v2(123.95,82.2)
  L10-SIG4 w0.178: 125.35,81.66 129.92,81.66 131.19,82.93 145.67,82.93 146.69,81.92 177.8,81.92 v1(178.18,82.3)
DAC_GPIO_0: length 16.6
  TOP w0.178: U17.1 194.3,86.73 196.34,88.77 196.34,92.33 195.5,93.17 J4.45
DAC_GPIO_1: length 12.3
  TOP w0.178: v1(192.66,92.67) J4.47 ; U17.3 188.06,88.03 188.09,88.06 v1(190.88,88.06)
  L3-SIG1 w0.178: v1(190.88,88.06) 191.57,88.06 193.42,89.92 193.42,91.9 v1(192.66,92.67)
DAC_GPIO_2: length 13.8
  TOP w0.178: U17.4 195.23,88.68 195.83,89.28 195.83,91.82 195.49,92.17 J4.49
DAC_GPIO_3: length 8.7
  TOP w0.178: v1(191.64,91.69) 191.67,91.67 J4.51 ; v1(188.09,89.28) 186.61,89.28 U17.5
  L3-SIG1 w0.178: v1(188.09,89.28) 190.5,91.69 v1(191.64,91.69)
DAC_GPIO_4: length 9.3
  TOP w0.178: v1(192.69,91.19) 192.71,91.17 J4.53 ; U17.6 187.52,89.98 v1(187.58,90.04)
  L3-SIG1 w0.178: v1(192.69,91.19) 192.69,91.53 191.9,92.33 189.87,92.33 v1(187.58,90.04)
DAC_GPIO_5: length 7.7
  TOP w0.178: J4.55 189.12,90.67 189.08,90.63 U17.7
DAC_GPIO_6: length 11.5
  TOP w0.178: v1(187.58,91.31) 186.53,91.31 U17.8 ; v1(192.66,90.16) J4.57
  L3-SIG1 w0.178: v1(192.66,90.16) 190.11,90.16 188.59,88.65 187.71,88.65 186.94,89.41 186.94,90.68 v1(187.58,91.31)
DAC_GPIO_7: length 13.4
  TOP w0.178: U17.9 186.58,91.95 v1(185.55,91.95) ; J4.59 v1(191.64,89.66)
  L3-SIG1 w0.178: v1(191.64,89.66) 190.76,89.66 189.1,88.01 187.2,88.01 185.55,89.66 v1(185.55,91.95)
DACLKN: length 135.3
  TOP w0.114: J4.117 194.23,70.16 194.13,70.27 192.65,70.27 192.41,70.03 v1(192.41,70.02) ; U5.M29 v2(113.95,64.2)
  L10-SIG4 w0.102: v2(113.95,64.2) 113.96,64.2 114.34,64.58 114.69,64.58 114.69,64.58 115.21,64.58 115.21,64.58 115.69,64.58 115.69,64.58 116.21,64.58 116.21,64.58 117.69,64.58 117.69,64.58 118.21,64.58 118.21,64.58 120.69,64.58 120.69,64.58 121.21,64.58 121.21,64.58 122.19,64.58 123.19,65.58 125.35,65.58 125.35,65.58 125.44,65.58 126,66.14 131.84,66.14 132.32,66.62 136.23,66.62 136.59,66.27 140.34,66.27 143.92,69.85 145.08,69.85 145.18,69.75 145.18,69.61 145.45,69.34 145.88,69.34 146.15,69.61 146.15,70.26 146.25,70.36 146.45,70.36 146.55,70.26 146.55,69.61 146.82,69.34 147.25,69.34 147.52,69.61 147.52,70.26 147.62,70.36 147.82,70.36 147.92,70.26 147.92,69.61 148.19,69.34 148.62,69.34 148.89,69.61 148.89,70.26 148.99,70.36 149.19,70.36 149.3,70.26 149.3,69.61 149.56,69.34 150,69.34 150.26,69.61 150.26,70.26 150.36,70.36 150.57,70.36 150.67,70.26 150.67,69.61 150.93,69.34 151.37,69.34 151.63,69.61 151.63,70.26 151.73,70.36 151.94,70.36 152.04,70.26 152.04,69.61 152.3,69.34 152.74,69.34 153,69.61 153,70.26 153.11,70.36 153.31,70.36 153.41,70.26 153.41,69.61 153.68,69.34 154.11,69.34 154.38,69.61 154.38,70.26 154.48,70.36 154.68,70.36 154.78,70.26 154.78,69.61 155.05,69.34 155.48,69.34 155.75,69.61 155.75,70.26 155.85,70.36 156.05,70.36 156.15,70.26 156.15,69.61 156.42,69.34 156.85,69.34 157.12,69.61 157.12,70.26 157.22,70.36 157.42,70.36 157.53,70.26 157.53,69.61 157.79,69.34 158.23,69.34 158.49,69.61 158.49,70.26 158.59,70.36 158.8,70.36 158.9,70.26 158.9,69.61 159.16,69.34 159.6,69.34 159.86,69.61 159.86,70.26 159.96,70.36 160.17,70.36 160.27,70.26 160.27,69.61 160.53,69.34 160.97,69.34 161.23,69.61 161.23,70.26 161.34,70.36 161.54,70.36 161.64,70.26 161.64,69.61 161.91,69.34 162.34,69.34 162.61,69.61 162.61,70.26 162.71,70.36 162.91,70.36 163.01,70.26 163.01,69.61 163.28,69.34 163.71,69.34 163.98,69.61 163.98,70.26 164.08,70.36 164.28,70.36 164.38,70.26 164.38,69.61 164.65,69.34 165.08,69.34 165.35,69.61 165.35,70.26 165.45,70.36 165.65,70.36 165.75,70.26 165.75,69.61 166.02,69.34 166.45,69.34 166.72,69.61 166.72,70.26 166.82,70.36 167.02,70.36 167.13,70.26 167.13,69.61 167.39,69.34 167.83,69.34 168.09,69.61 168.09,70.26 168.19,70.36 168.4,70.36 168.5,70.26 168.5,69.61 168.76,69.34 169.2,69.34 169.46,69.61 169.46,70.26 169.56,70.36 169.77,70.36 169.87,70.26 169.87,69.61 170.14,69.34 170.57,69.34 170.83,69.61 170.83,70.26 170.94,70.36 171.14,70.36 171.24,70.26 171.24,69.61 171.51,69.34 171.94,69.34 172.21,69.61 172.21,70.26 172.31,70.36 172.51,70.36 172.61,70.26 172.61,69.61 172.88,69.34 173.31,69.34 173.58,69.61 173.58,70.26 173.68,70.36 173.88,70.36 173.98,70.26 173.98,69.61 174.25,69.34 174.68,69.34 174.95,69.61 174.95,70.26 175.05,70.36 175.25,70.36 175.36,70.26 175.36,69.61 175.62,69.34 176.06,69.34 176.32,69.61 176.32,70.26 176.42,70.36 176.63,70.36 176.73,70.26 176.73,69.61 176.99,69.34 177.43,69.34 177.69,69.61 177.69,70.26 177.79,70.36 178,70.36 178.1,70.26 178.1,69.61 178.36,69.34 178.8,69.34 179.06,69.61 179.06,70.26 179.17,70.36 179.37,70.36 179.47,70.26 179.47,69.61 179.74,69.34 180.17,69.34 180.44,69.61 180.44,70.26 180.54,70.36 180.74,70.36 180.84,70.26 180.84,69.61 181.11,69.34 181.54,69.34 181.81,69.61 181.81,70.26 181.91,70.36 182.11,70.36 182.21,70.26 182.21,69.61 182.48,69.34 182.91,69.34 183.18,69.61 183.18,70.26 183.28,70.36 183.48,70.36 183.59,70.26 183.59,69.61 183.85,69.34 184.29,69.34 184.55,69.61 184.55,70.26 184.65,70.36 184.86,70.36 184.96,70.26 184.96,69.61 185.22,69.34 185.66,69.34 185.92,69.61 185.92,70.26 186.02,70.36 186.23,70.36 186.33,70.26 186.33,69.61 186.59,69.34 187.03,69.34 187.29,69.61 187.29,70.26 187.4,70.36 187.6,70.36 187.7,70.26 187.7,69.61 187.97,69.34 188.4,69.34 188.67,69.61 188.67,70.26 188.77,70.36 188.97,70.36 189.07,70.26 189.07,70.12 189.49,69.7 190.86,69.7 191.45,70.29 192.13,70.29 v1(192.41,70.02)
DACLKP: length 135.3
  TOP w0.114: U5.M28 v2(113.95,65.2) ; v1(192.41,70.84) 192.69,70.56 194.13,70.56 194.23,70.66 J4.115
  L10-SIG4 w0.102: v2(113.95,65.2) 114.33,64.82 114.79,64.82 114.79,64.82 115.11,64.82 115.11,64.82 115.79,64.82 115.79,64.82 116.11,64.82 116.11,64.82 117.79,64.82 117.79,64.82 118.11,64.82 118.11,64.82 120.79,64.82 120.79,64.82 121.11,64.82 121.11,64.82 122.09,64.82 123.09,65.82 125.19,65.82 125.24,65.86 125.32,65.86 125.88,66.42 131.72,66.42 132.21,66.9 136.35,66.9 136.7,66.55 140.22,66.55 143.8,70.13 145.2,70.13 145.46,69.86 145.46,69.72 145.56,69.62 145.77,69.62 145.87,69.72 145.87,70.37 146.13,70.64 146.57,70.64 146.83,70.37 146.83,69.72 146.93,69.62 147.14,69.62 147.24,69.72 147.24,70.37 147.5,70.64 147.94,70.64 148.2,70.37 148.2,69.72 148.31,69.62 148.51,69.62 148.61,69.72 148.61,70.37 148.88,70.64 149.31,70.64 149.58,70.37 149.58,69.72 149.68,69.62 149.88,69.62 149.98,69.72 149.98,70.37 150.25,70.64 150.68,70.64 150.95,70.37 150.95,69.72 151.05,69.62 151.25,69.62 151.35,69.72 151.35,70.37 151.62,70.64 152.05,70.64 152.32,70.37 152.32,69.72 152.42,69.62 152.62,69.62 152.72,69.72 152.72,70.37 152.99,70.64 153.42,70.64 153.69,70.37 153.69,69.72 153.79,69.62 153.99,69.62 154.1,69.72 154.1,70.37 154.36,70.64 154.8,70.64 155.06,70.37 155.06,69.72 155.16,69.62 155.37,69.62 155.47,69.72 155.47,70.37 155.73,70.64 156.17,70.64 156.43,70.37 156.43,69.72 156.53,69.62 156.74,69.62 156.84,69.72 156.84,70.37 157.1,70.64 157.54,70.64 157.8,70.37 157.8,69.72 157.91,69.62 158.11,69.62 158.21,69.72 158.21,70.37 158.48,70.64 158.91,70.64 159.18,70.37 159.18,69.72 159.28,69.62 159.48,69.62 159.58,69.72 159.58,70.37 159.85,70.64 160.28,70.64 160.55,70.37 160.55,69.72 160.65,69.62 160.85,69.62 160.95,69.72 160.95,70.37 161.22,70.64 161.65,70.64 161.92,70.37 161.92,69.72 162.02,69.62 162.22,69.62 162.33,69.72 162.33,70.37 162.59,70.64 163.03,70.64 163.29,70.37 163.29,69.72 163.39,69.62 163.6,69.62 163.7,69.72 163.7,70.37 163.96,70.64 164.4,70.64 164.66,70.37 164.66,69.72 164.76,69.62 164.97,69.62 165.07,69.72 165.07,70.37 165.33,70.64 165.77,70.64 166.03,70.37 166.03,69.72 166.14,69.62 166.34,69.62 166.44,69.72 166.44,70.37 166.71,70.64 167.14,70.64 167.41,70.37 167.41,69.72 167.51,69.62 167.71,69.62 167.81,69.72 167.81,70.37 168.08,70.64 168.51,70.64 168.78,70.37 168.78,69.72 168.88,69.62 169.08,69.62 169.18,69.72 169.18,70.37 169.45,70.64 169.88,70.64 170.15,70.37 170.15,69.72 170.25,69.62 170.45,69.62 170.56,69.72 170.56,70.37 170.82,70.64 171.26,70.64 171.52,70.37 171.52,69.72 171.62,69.62 171.83,69.62 171.93,69.72 171.93,70.37 172.19,70.64 172.63,70.64 172.89,70.37 172.89,69.72 172.99,69.62 173.2,69.62 173.3,69.72 173.3,70.37 173.56,70.64 174,70.64 174.26,70.37 174.26,69.72 174.37,69.62 174.57,69.62 174.67,69.72 174.67,70.37 174.94,70.64 175.37,70.64 175.64,70.37 175.64,69.72 175.74,69.62 175.94,69.62 176.04,69.72 176.04,70.37 176.31,70.64 176.74,70.64 177.01,70.37 177.01,69.72 177.11,69.62 177.31,69.62 177.41,69.72 177.41,70.37 177.68,70.64 178.11,70.64 178.38,70.37 178.38,69.72 178.48,69.62 178.68,69.62 178.79,69.72 178.79,70.37 179.05,70.64 179.49,70.64 179.75,70.37 179.75,69.72 179.85,69.62 180.06,69.62 180.16,69.72 180.16,70.37 180.42,70.64 180.86,70.64 181.12,70.37 181.12,69.72 181.22,69.62 181.43,69.62 181.53,69.72 181.53,70.37 181.79,70.64 182.23,70.64 182.49,70.37 182.49,69.72 182.6,69.62 182.8,69.62 182.9,69.72 182.9,70.37 183.17,70.64 183.6,70.64 183.87,70.37 183.87,69.72 183.97,69.62 184.17,69.62 184.27,69.72 184.27,70.37 184.54,70.64 184.97,70.64 185.24,70.37 185.24,69.72 185.34,69.62 185.54,69.62 185.64,69.72 185.64,70.37 185.91,70.64 186.34,70.64 186.61,70.37 186.61,69.72 186.71,69.62 186.91,69.62 187.01,69.72 187.01,70.37 187.28,70.64 187.71,70.64 187.98,70.37 187.98,69.72 188.08,69.62 188.28,69.62 188.39,69.72 188.39,70.37 188.65,70.64 189.09,70.64 189.35,70.37 189.35,70.23 189.61,69.98 190.74,69.98 191.33,70.57 192.13,70.57 v1(192.41,70.84)
DATA0: length 133.2
  TOP w0.178: R134.1 C354.1 88.77,121.54 90.93,123.7 102.49,123.7 v1(105.03,121.16) ; v1(125.86,55.63) R127.2 ; U5.P26 v2(111.95,67.2)
  L3-SIG1 w0.178: v1(125.86,55.63) 125.86,52.2 125.98,52.07 125.98,51.56 134.75,42.8 136.65,42.8 137.79,41.66 137.79,36.96 138.94,35.81 v1(140.72,35.81)
  L9-SIG3 w0.102: v2(111.95,67.2) 111.95,67.25 111.51,67.69 111.51,68.45 111.25,68.71 108.2,68.71 107.57,69.34 107.57,84.84 107.44,84.96 107.44,94.11
  L9-SIG3 w0.178: 107.44,94.11 107.44,97.03 105.03,99.44 v1(105.03,121.16)
  BOTTOM w0.178: R135.2 112.07,67.08 v2(111.95,67.2) 112.44,67.69 119.51,67.69 123.44,63.75 125.09,63.75 126.36,62.48 126.36,56.26 125.86,55.75 v1(125.86,55.63) ; 141.6,35.18 141.35,35.43 141.1,35.43 v1(140.72,35.81)
DATA1: length 1
  TOP w0.114: U5.R25 v2(110.95,68.2)
  BOTTOM w0.114: R136.2 110.82,68.07 v2(110.95,68.2)
DB0N: length 135.3
  TOP w0.114: v1(202.56,52.99) 202.28,53.27 200.08,53.27 J4.166 ; U5.AG12 v2(97.95,82.2)
  L9-SIG3 w0.102: v2(97.95,82.2) 98.16,81.99 98.24,81.99 98.37,81.86 98.37,81.38 99.31,80.44 99.31,80.37 99.33,80.36 99.33,80.04 99.31,80.03 99.31,79.37 99.33,79.36 99.33,79.04 99.31,79.03 99.31,78.37 99.33,78.36 99.33,76.77 100.28,75.82 100.28,75.39 100.33,75.34 100.33,69.3 100.33,69.29 100.33,61.94 100.69,61.58 103.16,61.58 103.33,61.41 103.33,61.04 103.33,61.04 103.33,60.36 103.33,60.36 103.33,60.04 103.33,60.04 103.33,59.36 103.33,59.36 103.33,58.37 103.4,58.29 104.32,57.38 104.82,57.38 105.29,56.91 105.29,56.49 108.55,53.24 117.59,53.24 118.74,52.08 118.74,51.72 119.66,50.8 125.37,50.8 125.64,51.07 154.1,51.07 154.29,51.26 190.69,51.26 190.77,51.34 192.76,53.31 195.91,53.31 196.34,52.88 197.74,52.88 198.09,53.24 202.32,53.24 v1(202.56,52.99)
DB0P: length 135.3
  TOP w0.114: v1(202.56,53.81) 202.3,53.55 200.08,53.55 J4.164 ; U5.AF12 v2(98.95,82.2)
  L9-SIG3 w0.102: v1(202.56,53.81) 202.56,53.8 202.28,53.52 197.98,53.52 197.62,53.16 196.46,53.16 196.03,53.59 192.65,53.59 190.58,51.54 187.8,51.54 187.68,51.66 187.4,51.66 187.27,51.54 186.99,51.54 186.86,51.66 186.58,51.66 186.46,51.54 186.18,51.54 186.05,51.66 185.77,51.66 185.65,51.54 185.37,51.54 185.24,51.66 184.96,51.66 184.83,51.54 154.18,51.54 153.99,51.35 125.53,51.35 125.26,51.08 119.78,51.08 119.02,51.84 119.02,52.2 117.7,53.52 108.66,53.52 105.57,56.61 105.57,57.03 104.92,57.68 104.42,57.68 103.57,58.53 103.57,59.46 103.57,59.46 103.57,59.94 103.57,59.94 103.57,60.46 103.57,60.46 103.57,60.94 103.57,60.94 103.57,61.51 103.26,61.82 100.79,61.82 100.57,62.04 100.57,69.39 100.57,69.39 100.57,75.44 100.52,75.49 100.52,75.92 99.57,76.87 99.57,78.46 99.55,78.47 99.55,78.93 99.57,78.94 99.57,79.46 99.55,79.47 99.55,79.93 99.57,79.94 99.57,80.52 98.61,81.48 98.61,81.86 v2(98.95,82.2)
DB1N: length 135.3
  TOP w0.114: J4.160 200.08,54.77 201.53,54.77 v1(201.8,54.5) ; U5.AF11 v2(98.95,83.2)
  L9-SIG3 w0.102: v2(98.95,83.2) 98.95,82.84 99.2,82.59 100.12,82.59 100.57,82.14 100.57,82.04 100.79,81.82 101.4,81.82 101.55,81.67 101.55,81.48 101.57,81.46 101.57,80.94 101.55,80.92 101.55,78.95 101.66,78.84 101.66,70.93 101.55,70.82 101.55,69.48 101.57,69.46 101.57,62.95 101.7,62.82 103.51,62.82 104.56,61.77 104.56,60.47 104.57,60.46 104.57,58.97 105.22,58.32 105.45,58.32 106.29,57.48 107.76,57.48 117.65,57.48 119.66,55.47 123.23,55.47 124.41,54.3 131.61,54.3 131.88,54.03 131.88,53.85 131.98,53.75 132.18,53.75 132.28,53.85 132.28,54.03 132.55,54.3 132.98,54.3 133.25,54.03 133.25,53.85 133.35,53.75 133.55,53.75 133.66,53.85 133.66,54.03 133.92,54.3 134.36,54.3 134.62,54.03 134.62,53.85 134.72,53.75 134.93,53.75 135.03,53.85 135.03,54.03 135.29,54.3 135.73,54.3 135.99,54.03 135.99,53.85 136.09,53.75 136.3,53.75 136.4,53.85 136.4,54.03 136.66,54.3 137.1,54.3 137.36,54.03 137.36,53.85 137.47,53.75 137.67,53.75 137.77,53.85 137.77,54.03 138.04,54.3 164.88,54.3 165.83,55.25 166.06,55.25 166.06,55.24 191.22,55.24 192.01,56.03 192.88,56.03 193.89,55.02 200,55.02 200.64,54.38 201.68,54.38 v1(201.8,54.5)
DB1P: length 135.3
  TOP w0.114: U5.AE12 v2(99.95,82.2) ; J4.158 200.08,55.05 201.53,55.05 v1(201.8,55.32)
  L9-SIG3 w0.102: v2(99.95,82.2) 100.07,82.2 100.69,81.58 101.3,81.58 101.31,81.57 101.31,81.38 101.33,81.36 101.33,81.04 101.31,81.02 101.31,78.85 101.42,78.74 101.42,71.02 101.32,70.92 101.31,70.92 101.31,69.38 101.33,69.36 101.33,62.85 101.6,62.58 103.41,62.58 104.32,61.67 104.32,60.37 104.33,60.36 104.33,58.87 105.12,58.08 105.29,58.08 106.17,57.2 107.88,57.2 117.54,57.2 119.54,55.19 123.11,55.19 124.29,54.02 131.5,54.02 131.6,53.91 131.6,53.73 131.86,53.47 132.3,53.47 132.56,53.73 132.56,53.91 132.67,54.02 132.87,54.02 132.97,53.91 132.97,53.73 133.24,53.47 133.67,53.47 133.94,53.73 133.94,53.91 134.04,54.02 134.24,54.02 134.34,53.91 134.34,53.73 134.61,53.47 135.04,53.47 135.31,53.73 135.31,53.91 135.41,54.02 135.61,54.02 135.71,53.91 135.71,53.73 135.98,53.47 136.41,53.47 136.68,53.73 136.68,53.91 136.78,54.02 136.98,54.02 137.09,53.91 137.09,53.73 137.35,53.47 137.79,53.47 138.05,53.73 138.05,53.91 138.15,54.02 165,54.02 165.95,54.97 191.34,54.97 192.13,55.75 192.76,55.75 193.78,54.74 199.89,54.74 200.52,54.1 201.61,54.1 201.61,54.09 201.97,54.09 202.21,54.33 202.21,54.67 201.8,55.08 v1(201.8,55.32)
DB2N: length 135.3
  TOP w0.114: v1(202.56,55.99) 202.28,56.27 200.08,56.27 J4.154 ; U5.AD11 v2(100.95,83.2)
  L9-SIG3 w0.102: v2(100.95,83.2) 101.18,83.2 101.28,83.1 101.28,82.89 101.17,82.78 100.8,82.78 100.57,83.01 100.57,83.39 100.76,83.58 102.17,83.58 102.33,83.42 102.33,82.04 102.28,81.99 102.28,70.41 102.33,70.36 102.33,63.78 102.53,63.58 104.12,63.58 104.31,63.39 104.31,63.38 104.33,63.36 104.33,62.88 104.63,62.58 105.16,62.58 105.33,62.41 105.33,58.93 105.71,58.55 106.3,58.55 106.51,58.33 106.63,58.33 106.88,58.08 125.14,58.08 126.45,56.77 130.67,56.77 131.32,56.11 140.86,56.11 141.2,55.78 141.67,55.78 142,56.11 142.24,56.11 142.57,55.78 143.04,55.78 143.37,56.11 143.61,56.11 143.94,55.78 144.41,55.78 144.74,56.11 144.98,56.11 145.31,55.78 145.78,55.78 146.12,56.11 146.35,56.11 146.69,55.78 147.15,55.78 147.49,56.11 147.72,56.11 148.06,55.78 148.52,55.78 148.86,56.11 189.01,56.11 190.17,57.28 191.64,57.28 192.18,56.74 194.92,56.74 195.4,56.26 202.3,56.26 v1(202.56,55.99)
DB2P: length 135.3
  TOP w0.114: U5.AD12 v2(100.95,82.2) ; v1(202.56,56.82) 202.3,56.55 200.08,56.55 J4.152
  L9-SIG3 w0.102: v2(100.95,82.2) 100.95,82.29 100.33,82.91 100.33,83.49 100.66,83.82 102.26,83.82 102.57,83.51 102.57,81.94 102.51,81.89 102.51,70.51 102.57,70.46 102.57,63.88 102.63,63.82 104.22,63.82 104.55,63.49 104.55,63.48 104.57,63.46 104.57,62.98 104.73,62.82 105.26,62.82 105.57,62.51 105.57,59.03 105.81,58.78 106.4,58.78 106.61,58.57 106.73,58.57 106.98,58.32 125.3,58.32 126.57,57.05 130.78,57.05 131.44,56.39 140.98,56.39 141.32,56.06 141.55,56.06 141.89,56.39 142.35,56.39 142.69,56.06 142.92,56.06 143.26,56.39 143.72,56.39 144.06,56.06 144.29,56.06 144.63,56.39 145.1,56.39 145.43,56.06 145.67,56.06 146,56.39 146.47,56.39 146.8,56.06 147.04,56.06 147.37,56.39 147.84,56.39 148.17,56.06 148.41,56.06 148.74,56.39 188.9,56.39 190.06,57.56 190.29,57.56 191.76,57.56 192.29,57.02 195.05,57.02 195.53,56.54 202.3,56.54 202.56,56.81 v1(202.56,56.82)
DB3N: length 135.5
  TOP w0.114: U5.AE9 v2(99.95,85.2) ; v1(202.02,57.62) 201.87,57.78 200.08,57.78 J4.148
  L9-SIG3 w0.102: v1(202.02,57.62) 201.89,57.49 200.26,57.49 199.71,58.04 194.48,58.04 193.32,59.2 192.24,59.2 191.53,58.49 167.86,58.49 167.71,58.34 167.71,58.1 167.63,58.01 167.41,58.01 167.3,58.12 167.3,58.23 167.04,58.49 166.6,58.49 166.34,58.23 166.34,58.12 166.24,58.01 166.03,58.01 165.93,58.12 165.93,58.23 165.67,58.49 165.23,58.49 164.97,58.23 164.97,58.12 164.87,58.01 164.66,58.01 164.56,58.12 164.56,58.23 164.3,58.49 163.86,58.49 163.6,58.23 163.6,58.12 163.49,58.01 163.29,58.01 163.19,58.12 163.19,58.23 162.92,58.49 162.49,58.49 162.06,58.06 161.89,58.06 161.46,58.49 132.9,58.49 132.55,58.14 127.42,58.14 125.49,60.07 125.23,60.07 125.19,60.03 123.58,60.03 123.37,59.82 106.79,59.82 106.57,60.04 106.57,63.56 106.31,63.82 105.68,63.82 105.57,63.93 105.57,64.56 105.31,64.82 103.69,64.82 103.57,64.94 103.57,84.46 103.21,84.82 99.53,84.82 99.35,85 99.35,85.25 99.53,85.43 99.72,85.43 v2(99.95,85.2)
DB3P: length 135.5
  TOP w0.114: U5.AE10 v2(99.95,84.2) ; J4.146 200.08,58.06 201.71,58.06 v1(202.01,58.36)
  L9-SIG3 w0.102: v1(202.01,58.36) 202.43,57.94 202.43,57.45 202.18,57.21 200.15,57.21 199.6,57.76 194.36,57.76 193.2,58.92 192.35,58.92 191.65,58.21 168.08,58.21 167.99,58.12 167.99,57.98 167.74,57.73 167.29,57.73 167.02,58 167.02,58.11 166.92,58.21 166.72,58.21 166.62,58.11 166.62,58 166.35,57.73 165.92,57.73 165.65,58 165.65,58.11 165.55,58.21 165.35,58.21 165.25,58.11 165.25,58 164.98,57.73 164.55,57.73 164.28,58 164.28,58.11 164.18,58.21 163.98,58.21 163.87,58.11 163.87,58 163.61,57.73 163.18,57.73 162.91,58 162.91,58.11 162.81,58.21 162.6,58.21 162.18,57.78 161.77,57.78 161.35,58.21 133.01,58.21 132.66,57.86 127.3,57.86 125.38,59.78 123.67,59.78 123.47,59.58 106.69,59.58 106.33,59.94 106.33,63.46 106.21,63.58 105.58,63.58 105.33,63.83 105.33,64.46 105.21,64.58 103.59,64.58 103.33,64.84 103.33,79.51 103.3,79.54 103.3,79.59 103.33,79.62 103.33,84.36 103.11,84.58 100.33,84.58 v2(99.95,84.2)
DB4N: length 135.3
  TOP w0.114: J4.142 200.08,59.28 202.28,59.28 v1(202.56,59) ; U5.AE8 v2(99.95,86.2)
  L9-SIG3 w0.102: v2(99.95,86.2) 100.23,86.2 100.3,86.13 100.3,86 100.14,85.84 99.73,85.84 99.57,86 99.57,86.28 99.87,86.58 103.15,86.58 103.33,86.4 103.33,85.94 103.69,85.58 104.16,85.58 104.33,85.41 104.33,65.85 104.6,65.58 106.11,65.58 106.33,65.36 106.33,64.94 106.69,64.58 107.11,64.58 107.34,64.35 107.34,60.83 107.59,60.58 110.11,60.58 110.11,60.58 110.69,60.58 110.69,60.58 111.11,60.58 111.11,60.58 111.69,60.58 111.69,60.58 112.11,60.58 112.11,60.58 112.69,60.58 112.69,60.58 113.11,60.58 113.11,60.58 113.69,60.58 113.69,60.58 114.11,60.58 114.11,60.58 114.69,60.58 114.69,60.58 115.11,60.58 115.11,60.58 115.69,60.58 115.69,60.58 116.11,60.58 116.11,60.58 116.69,60.58 116.69,60.58 117.11,60.58 117.11,60.58 117.69,60.58 117.69,60.58 118.11,60.58 118.11,60.58 118.69,60.58 118.69,60.58 119.11,60.58 119.11,60.58 119.69,60.58 119.69,60.58 120.11,60.58 120.11,60.58 120.69,60.58 120.69,60.58 121.01,60.58 121.11,60.58 121.11,60.58 121.69,60.58 121.69,60.58 128,60.58 129.45,59.13 140.04,59.13 141.26,60.35 159.29,60.35 159.44,60.2 160.2,60.2 160.35,60.35 160.66,60.35 160.81,60.2 161.57,60.2 161.72,60.35 162.03,60.35 162.18,60.2 162.94,60.2 163.1,60.35 163.4,60.35 163.68,60.07 164.19,60.07 164.47,60.35 191.49,60.35 192.07,59.77 194.37,59.77 194.91,59.23 202.33,59.23 v1(202.56,59)
DB4P: length 135.4
  TOP w0.114: U5.AF9 v2(98.95,85.2) ; v1(202.56,59.82) 202.3,59.56 200.08,59.56 J4.140
  L9-SIG3 w0.102: v2(98.95,85.2) 99.33,85.58 99.33,86.38 99.77,86.82 103.25,86.82 103.57,86.5 103.57,86.04 103.79,85.82 104.26,85.82 104.57,85.51 104.57,65.95 104.7,65.82 106.21,65.82 106.57,65.46 106.57,65.04 106.79,64.82 107.21,64.82 107.58,64.45 107.58,60.93 107.69,60.82 110.21,60.82 110.21,60.82 110.59,60.82 110.59,60.82 111.21,60.82 111.21,60.82 111.59,60.82 111.59,60.82 112.21,60.82 112.21,60.82 112.59,60.82 112.59,60.82 113.21,60.82 113.21,60.82 113.59,60.82 113.59,60.82 114.21,60.82 114.21,60.82 114.59,60.82 114.59,60.82 115.21,60.82 115.21,60.82 115.59,60.82 115.59,60.82 116.21,60.82 116.21,60.82 116.59,60.82 116.59,60.82 117.21,60.82 117.21,60.82 117.59,60.82 117.59,60.82 118.21,60.82 118.21,60.82 118.59,60.82 118.59,60.82 119.21,60.82 119.21,60.82 119.59,60.82 119.59,60.82 120.21,60.82 120.21,60.82 120.59,60.82 120.59,60.82 121.11,60.82 121.21,60.82 121.21,60.82 121.59,60.82 121.59,60.82 125.19,60.82 125.23,60.86 128.12,60.86 129.57,59.41 139.93,59.41 141.14,60.63 159.4,60.63 159.55,60.48 160.08,60.48 160.24,60.63 160.77,60.63 160.93,60.48 161.46,60.48 161.61,60.63 162.14,60.63 162.3,60.48 162.83,60.48 162.98,60.63 163.52,60.63 163.8,60.35 164.07,60.35 164.35,60.63 191.61,60.63 192.19,60.05 194.49,60.05 195.02,59.51 202.28,59.51 202.56,59.8 v1(202.56,59.82)
DB5N: length 136.2
  TOP w0.114: J4.136 200.08,60.78 201.53,60.78 v1(201.8,60.51) ; U5.AF10 v2(98.95,84.2)
  L9-SIG3 w0.102: v1(201.8,60.51) 201.55,60.76 195.2,60.76 194.18,61.77 192.17,61.77 191.61,61.21 190.82,61.21 190.49,61.54 125.23,61.54 125.19,61.58 108.64,61.58 108.19,62.03 108.19,65.54 107.16,66.58 105.87,66.58 105.68,66.58 105.33,66.93 105.33,86.39 105.14,86.58 104.69,86.58 104.33,86.94 104.33,87.36 104.11,87.58 98.76,87.58 98.57,87.39 98.57,83.7 98.69,83.58 98.96,83.58 99.07,83.69 99.07,84.08 v2(98.95,84.2)
DB5P: length 136.1
  TOP w0.114: J4.134 200.08,61.06 201.53,61.06 v1(201.8,61.33) ; U5.AG11 v2(97.96,83.19)
  L9-SIG3 w0.102: v2(97.96,83.19) 97.96,83.23 98.33,83.6 98.33,87.51 98.64,87.82 104.21,87.82 104.57,87.46 104.57,87.04 104.79,86.82 105.24,86.82 105.57,86.49 105.57,67.02 105.77,66.82 107.25,66.82 108.43,65.64 108.43,62.13 108.74,61.82 190.61,61.82 190.93,61.49 191.49,61.49 192.05,62.05 194.3,62.05 195.31,61.04 201.51,61.04 v1(201.8,61.33)
DB6N: length 135.4
  TOP w0.114: v1(202.56,62) 202.28,62.28 200.08,62.28 J4.130 ; U5.AC11 v2(101.95,83.2)
  L4-SIG2 w0.102: v2(101.95,83.2) 101.95,83.2 101.34,82.58 101.34,79.75 102.29,78.8 102.29,76.89 103.3,75.87 105.89,75.87 106.33,75.43 106.33,69.89 106.64,69.58 107.15,69.58 107.34,69.39 107.36,69.39 108.18,68.57 108.78,68.57 108.79,68.58 109.11,68.58 109.33,68.36 109.33,67.94 109.34,67.94 109.34,66.46 109.33,66.46 109.33,65.94 109.34,65.94 109.34,65.46 109.33,65.46 109.33,63.94 109.69,63.58 122.24,63.58 123.24,62.58 124.49,62.58 124.73,62.35 124.73,62.32 125.15,61.9 125.15,61.84 126.16,60.83 126.16,59.05 126.72,58.5 126.75,58.5 127.46,57.78 152.95,57.78 158.41,63.25 159.18,63.25 159.28,63.14 159.28,63.1 159.55,62.84 159.98,62.84 160.25,63.1 160.25,63.55 160.35,63.65 160.55,63.65 160.65,63.55 160.65,63.1 160.92,62.84 161.35,62.84 161.62,63.1 161.62,63.55 161.72,63.65 161.92,63.65 162.02,63.55 162.02,63.1 162.29,62.84 162.72,62.84 162.99,63.1 162.99,63.55 163.09,63.65 163.29,63.65 163.4,63.55 163.4,63.1 163.66,62.84 164.1,62.84 164.36,63.1 164.36,63.55 164.46,63.65 164.67,63.65 164.77,63.55 164.77,63.1 165.03,62.84 165.47,62.84 165.73,63.1 165.73,63.55 165.83,63.65 166.04,63.65 166.14,63.55 166.14,63.1 166.4,62.84 166.84,62.84 167.1,63.1 167.1,63.55 167.21,63.65 167.41,63.65 167.51,63.55 167.51,63.4 167.66,63.25 191.52,63.25 192.69,62.07 202.49,62.07 v1(202.56,62)
DB6P: length 135.4
  TOP w0.114: J4.128 200.08,62.56 202.3,62.56 v1(202.56,62.82) ; U5.AC12 v2(101.95,82.2)
  L4-SIG2 w0.102: v1(202.56,62.82) 202.1,62.35 192.81,62.35 191.63,63.53 167.82,63.53 167.79,63.55 167.79,63.67 167.52,63.93 167.09,63.93 166.82,63.67 166.82,63.22 166.72,63.12 166.52,63.12 166.42,63.22 166.42,63.67 166.15,63.93 165.72,63.93 165.45,63.67 165.45,63.22 165.35,63.12 165.15,63.12 165.05,63.22 165.05,63.67 164.78,63.93 164.35,63.93 164.08,63.67 164.08,63.22 163.98,63.12 163.78,63.12 163.67,63.22 163.67,63.67 163.41,63.93 162.97,63.93 162.71,63.67 162.71,63.22 162.61,63.12 162.4,63.12 162.3,63.22 162.3,63.67 162.04,63.93 161.6,63.93 161.34,63.67 161.34,63.22 161.24,63.12 161.03,63.12 160.93,63.22 160.93,63.67 160.67,63.93 160.23,63.93 159.97,63.67 159.97,63.22 159.86,63.12 159.66,63.12 159.56,63.22 159.56,63.26 159.29,63.53 158.29,63.53 152.83,58.06 127.57,58.06 126.86,58.78 126.83,58.78 126.44,59.17 126.44,60.95 124.97,62.42 124.97,62.44 124.59,62.82 123.34,62.82 122.34,63.82 109.79,63.82 109.57,64.04 109.57,65.36 109.58,65.36 109.58,66.04 109.57,66.04 109.57,66.36 109.58,66.36 109.58,68.04 109.57,68.04 109.57,68.54 109.3,68.81 109.22,68.81 109.21,68.82 108.69,68.82 108.68,68.81 108.28,68.81 107.27,69.82 106.74,69.82 106.57,69.99 106.57,75.55 105.99,76.12 103.4,76.12 102.54,76.99 102.54,78.94 101.59,79.89 101.59,82.51 101.91,82.82 101.99,82.82 102.08,82.73 102.08,82.33 v2(101.95,82.2)
DB7N: length 135.3
  TOP w0.114: U5.AB9 v2(102.95,85.2) ; J4.124 200.08,63.78 201.53,63.78 v1(201.8,63.51)
  L4-SIG2 w0.102: v2(102.95,85.2) 102.95,85.13 102.78,84.95 102.68,84.95 102.57,85.07 102.57,86.36 102.79,86.58 106.11,86.58 106.33,86.36 106.33,85.87 106.62,85.58 107.11,85.58 107.33,85.36 107.33,84.81 108.55,83.59 108.68,83.59 108.69,83.58 109.21,83.58 109.22,83.59 109.68,83.59 109.69,83.58 110.21,83.58 110.22,83.59 110.68,83.59 110.69,83.58 111.21,83.58 111.22,83.59 111.68,83.59 111.69,83.58 112.21,83.58 112.22,83.59 113.68,83.59 113.69,83.58 114.21,83.58 114.22,83.59 114.68,83.59 114.69,83.58 115.21,83.58 115.22,83.59 117.68,83.59 117.69,83.58 118.21,83.58 118.22,83.59 118.68,83.59 118.69,83.58 119.21,83.58 119.22,83.59 120.68,83.59 120.69,83.58 121.21,83.58 121.22,83.59 121.55,83.59 122.64,84.68 122.64,84.7 124.18,86.23 126.24,86.23 127.51,87.5 127.64,87.5 131.98,91.85 139.69,91.85 139.89,92.05 165.81,92.05 171.22,86.64 198.73,86.64 204.06,81.31 204.06,67.09 201.74,64.77 201.55,64.77 201.29,64.52 201.29,64.14 201.8,63.63 v1(201.8,63.51)
DB7P: length 135.4
  TOP w0.114: v1(201.8,64.33) 201.53,64.06 200.08,64.06 J4.122 ; U5.AC10 v2(101.95,84.2)
  L4-SIG2 w0.102: v2(101.95,84.2) 102.33,84.58 102.33,86.46 102.69,86.82 106.21,86.82 106.57,86.46 106.57,85.97 106.72,85.82 107.21,85.82 107.57,85.46 107.57,84.91 108.65,83.83 108.78,83.83 108.79,83.82 109.11,83.82 109.12,83.83 109.78,83.83 109.79,83.82 110.11,83.82 110.12,83.83 110.78,83.83 110.79,83.82 111.11,83.82 111.12,83.83 111.78,83.83 111.79,83.82 112.11,83.82 112.12,83.83 113.78,83.83 113.79,83.82 114.11,83.82 114.12,83.83 114.78,83.83 114.79,83.82 115.11,83.82 115.12,83.83 117.78,83.83 117.79,83.82 118.11,83.82 118.12,83.83 118.78,83.83 118.79,83.82 119.11,83.82 119.12,83.83 120.78,83.83 120.79,83.82 121.11,83.82 121.12,83.83 121.45,83.83 122.41,84.78 122.41,84.79 124.08,86.47 125.19,86.47 125.23,86.51 126.12,86.51 127.39,87.78 127.52,87.78 131.86,92.13 139.57,92.13 139.78,92.33 165.93,92.33 171.34,86.92 198.85,86.92 204.34,81.42 204.34,66.98 201.8,64.44 201.8,64.33 v1(201.8,64.33)
DB8N: length 135.3
  TOP w0.114: J4.112 200.08,71.77 202.3,71.77 v1(202.56,71.88) ; U5.AB10 v2(102.95,84.2)
  L4-SIG2 w0.102: v1(202.56,71.88) 202.44,72.01 202.43,72.01 202.33,72.11 199.78,72.11 198.61,73.28 198.23,73.28 196.75,74.76 195.42,74.76 193.55,76.64 193.55,76.71 190.37,79.88 181.88,79.88 181.65,80.12 181.34,80.12 181.11,79.88 180.51,79.88 180.28,80.12 179.97,80.12 179.74,79.88 179.14,79.88 178.91,80.12 178.6,80.12 178.37,79.88 177.77,79.88 177.53,80.12 177.23,80.12 177,79.88 176.4,79.88 176.16,80.12 158.9,80.12 157.71,81.31 157.11,81.31 148.17,81.31 146.75,82.72 146.55,82.72 146.45,82.62 146.45,81.57 146.18,81.31 145.75,81.31 145.48,81.57 145.48,82.62 145.38,82.72 145.18,82.72 145.08,82.62 145.08,81.57 144.81,81.31 144.38,81.31 144.11,81.57 144.11,82.62 144.01,82.72 143.81,82.72 143.71,82.62 143.71,81.57 143.44,81.31 143.01,81.31 142.74,81.57 142.74,82.62 142.64,82.72 142.44,82.72 142.33,82.62 142.33,81.57 142.07,81.31 141.63,81.31 141.37,81.57 141.37,82.62 141.27,82.72 141.06,82.72 140.96,82.62 140.96,81.57 140.7,81.31 140.26,81.31 140,81.57 140,82.62 139.9,82.72 139.69,82.72 139.59,82.62 139.59,81.57 139.33,81.31 138.89,81.31 138.63,81.57 138.63,82.62 138.52,82.72 138.32,82.72 138.22,82.62 138.22,81.57 137.95,81.31 137.52,81.31 137.25,81.57 137.25,82.62 137.15,82.72 136.95,82.72 136.85,82.62 136.85,81.57 136.58,81.31 136.15,81.31 135.88,81.57 135.88,82.62 135.78,82.72 135.58,82.72 135.48,82.62 135.48,82.38 134.41,81.31 130.07,81.31 127.53,78.77 124.84,78.77 124.66,78.58 103.69,78.58 103.33,78.94 103.33,78.97 103.33,78.98 103.33,79.04 103.33,79.04 103.33,79.36 103.33,79.36 103.33,79.43 103.17,79.58 102.68,79.58 102.33,79.93 102.33,83.58 v2(102.95,84.2)
DB8P: length 135.3
  TOP w0.114: v1(202.56,72.64) 202.06,72.14 200,72.14 J4.110 ; U5.AB11 v2(102.95,83.2)
  L4-SIG2 w0.102: v1(202.56,72.64) 202.31,72.39 199.9,72.39 198.73,73.56 198.35,73.56 196.87,75.04 195.54,75.04 193.83,76.75 193.83,76.82 190.49,80.16 182,80.16 181.76,80.4 181.23,80.4 180.99,80.16 180.63,80.16 180.39,80.4 179.86,80.4 179.62,80.16 179.26,80.16 179.02,80.4 178.49,80.4 178.25,80.16 177.88,80.16 177.65,80.4 177.11,80.4 176.88,80.16 176.51,80.16 176.28,80.4 159.01,80.4 157.82,81.58 156.99,81.58 148.28,81.58 146.87,83 146.44,83 146.17,82.73 146.17,81.69 146.07,81.58 145.87,81.58 145.76,81.69 145.76,82.73 145.5,83 145.06,83 144.8,82.73 144.8,81.69 144.7,81.58 144.49,81.58 144.39,81.69 144.39,82.73 144.13,83 143.69,83 143.43,82.73 143.43,81.69 143.33,81.58 143.12,81.58 143.02,81.69 143.02,82.73 142.76,83 142.32,83 142.06,82.73 142.06,81.69 141.95,81.58 141.75,81.58 141.65,81.69 141.65,82.73 141.38,83 140.95,83 140.68,82.73 140.68,81.69 140.58,81.58 140.38,81.58 140.28,81.69 140.28,82.73 140.01,83 139.58,83 139.31,82.73 139.31,81.69 139.21,81.58 139.01,81.58 138.91,81.69 138.91,82.73 138.64,83 138.21,83 137.94,82.73 137.94,81.69 137.84,81.58 137.64,81.58 137.53,81.69 137.53,82.73 137.27,83 136.83,83 136.57,82.73 136.57,81.69 136.47,81.58 136.26,81.58 136.16,81.69 136.16,82.73 135.9,83 135.46,83 135.2,82.73 135.2,82.49 134.29,81.58 129.96,81.58 127.42,79.04 125.23,79.04 125.19,79 124.74,79 124.56,78.82 103.79,78.82 103.57,79.04 103.57,79.46 103.57,79.46 103.57,79.53 103.27,79.82 102.78,79.82 102.57,80.03 102.57,83.48 102.81,83.72 103.02,83.72 103.12,83.62 103.12,83.44 102.95,83.27 v2(102.95,83.2)
DB9N: length 135.5
  TOP w0.114: U5.AB12 v2(102.95,82.2) ; v1(201.8,73.02) 201.55,73.28 201.51,73.28 201.45,73.33 200.13,73.33 J4.106
  L4-SIG2 w0.102: v2(102.95,82.2) 103.33,81.82 103.33,80.89 103.64,80.58 104.22,80.58 104.33,80.47 104.33,79.94 104.69,79.58 119.23,79.58 119.24,79.59 120.68,79.59 120.69,79.58 126.09,79.58 131.44,84.92 131.44,85.14 131.54,85.24 131.74,85.24 131.84,85.14 131.84,84.47 132.11,84.2 132.54,84.2 132.81,84.47 132.81,85.14 132.91,85.24 133.11,85.24 133.21,85.14 133.21,84.47 133.48,84.2 133.91,84.2 134.18,84.47 134.18,85.14 134.28,85.24 134.48,85.24 134.58,85.14 134.58,84.47 134.85,84.2 135.28,84.2 135.55,84.47 135.55,85.14 135.65,85.24 135.85,85.24 135.96,85.14 135.96,84.47 136.22,84.2 136.66,84.2 136.92,84.47 136.92,85.14 137.02,85.24 137.23,85.24 137.33,85.14 137.33,84.47 137.59,84.2 138.03,84.2 138.29,84.47 138.29,85.14 138.39,85.24 138.6,85.24 138.7,85.14 138.7,84.47 138.96,84.2 139.4,84.2 139.66,84.47 139.66,85.14 139.77,85.24 139.97,85.24 140.07,85.14 140.07,84.47 140.34,84.2 140.77,84.2 141.04,84.47 141.04,85.14 141.14,85.24 141.34,85.24 141.44,85.14 141.44,84.47 141.71,84.2 142.14,84.2 142.41,84.47 142.41,85.14 142.51,85.24 142.71,85.24 142.81,85.14 142.81,84.47 143.08,84.2 143.51,84.2 143.78,84.47 143.78,85.14 143.88,85.24 144.08,85.24 144.19,85.14 144.19,84.47 144.45,84.2 144.89,84.2 145.15,84.47 145.15,85.14 145.25,85.24 145.46,85.24 145.56,85.14 145.56,84.47 145.82,84.2 146.26,84.2 146.52,84.47 146.52,85.14 146.62,85.24 146.83,85.24 146.93,85.14 146.93,84.47 147.19,84.2 147.63,84.2 147.89,84.47 147.89,85.14 148,85.24 148.2,85.24 148.3,85.14 148.3,84.47 148.57,84.2 149,84.2 149.27,84.47 149.27,85.14 149.37,85.24 149.57,85.24 149.67,85.14 149.67,84.47 149.94,84.2 150.37,84.2 150.64,84.47 150.64,85.14 150.74,85.24 150.94,85.24 151.04,85.14 151.04,84.86 151.7,84.2 157.37,84.2 160.06,81.51 190.17,81.51 190.5,81.84 191.47,81.84 193.17,80.14 193.17,79.12 194.69,77.6 196.47,77.6 197.74,76.33 198.74,76.33 199.26,75.8 199.26,75.49 199.26,75.49 199.26,75.25 199.26,75.25 201.09,73.43 201.36,73.15 201.67,73.15 v1(201.8,73.02)
DB9P: length 135.3
  TOP w0.114: J4.104 200.03,73.61 201.57,73.61 v1(201.8,73.85) ; U5.AA12 v2(103.95,82.2)
  L4-SIG2 w0.102: v1(201.8,73.85) 201.83,73.82 201.83,73.56 201.71,73.43 201.48,73.43 199.54,75.37 199.54,75.92 198.86,76.61 197.85,76.61 196.58,77.88 194.81,77.88 193.45,79.24 193.45,80.25 191.58,82.12 190.38,82.12 190.05,81.79 160.17,81.79 157.48,84.48 151.82,84.48 151.32,84.97 151.32,85.25 151.06,85.52 150.62,85.52 150.36,85.25 150.36,84.58 150.26,84.48 150.05,84.48 149.95,84.58 149.95,85.25 149.69,85.52 149.25,85.52 148.99,85.25 148.99,84.58 148.89,84.48 148.68,84.48 148.58,84.58 148.58,85.25 148.31,85.52 147.88,85.52 147.62,85.25 147.62,84.58 147.51,84.48 147.31,84.48 147.21,84.58 147.21,85.25 146.94,85.52 146.51,85.52 146.24,85.25 146.24,84.58 146.14,84.48 145.94,84.48 145.84,84.58 145.84,85.25 145.57,85.52 145.14,85.52 144.87,85.25 144.87,84.58 144.77,84.48 144.57,84.48 144.47,84.58 144.47,85.25 144.2,85.52 143.77,85.52 143.5,85.25 143.5,84.58 143.4,84.48 143.2,84.48 143.09,84.58 143.09,85.25 142.83,85.52 142.39,85.52 142.13,85.25 142.13,84.58 142.03,84.48 141.82,84.48 141.72,84.58 141.72,85.25 141.46,85.52 141.02,85.52 140.76,85.25 140.76,84.58 140.66,84.48 140.45,84.48 140.35,84.58 140.35,85.25 140.09,85.52 139.65,85.52 139.39,85.25 139.39,84.58 139.28,84.48 139.08,84.48 138.98,84.58 138.98,85.25 138.71,85.52 138.28,85.52 138.01,85.25 138.01,84.58 137.91,84.48 137.71,84.48 137.61,84.58 137.61,85.25 137.34,85.52 136.91,85.52 136.64,85.25 136.64,84.58 136.54,84.48 136.34,84.48 136.24,84.58 136.24,85.25 135.97,85.52 135.54,85.52 135.27,85.25 135.27,84.58 135.17,84.48 134.97,84.48 134.86,84.58 134.86,85.25 134.6,85.52 134.16,85.52 133.9,85.25 133.9,84.58 133.8,84.48 133.59,84.48 133.49,84.58 133.49,85.25 133.23,85.52 132.79,85.52 132.53,85.25 132.53,84.58 132.43,84.48 132.22,84.48 132.12,84.58 132.12,85.25 131.86,85.52 131.42,85.52 131.16,85.25 131.16,85.04 125.98,79.86 125.35,79.86 125.31,79.82 120.79,79.82 120.78,79.83 120.59,79.83 119.14,79.83 119.13,79.82 104.79,79.82 104.57,80.04 104.57,80.56 104.31,80.82 103.79,80.82 103.57,81.04 103.57,81.84 103.93,82.2 v2(103.95,82.2)
DB10N: length 135.4
  TOP w0.114: U5.Y12 v2(104.95,82.2) ; v1(202.56,74.51) 202.3,74.78 200.08,74.78 J4.100
  L4-SIG2 w0.102: v2(104.95,82.2) 105.31,81.84 105.31,81.38 105.33,81.36 105.33,80.94 105.69,80.58 107.11,80.58 107.18,80.51 108.72,80.51 108.79,80.58 113.11,80.58 113.18,80.51 118.72,80.51 118.79,80.58 119.11,80.58 119.18,80.51 120.72,80.51 120.79,80.58 125.29,80.58 125.35,80.52 125.48,80.52 130.05,85.09 130.05,85.93 130.47,86.35 130.47,86.36 131.2,87.1 131.2,87.3 131.36,87.45 131.51,87.45 131.61,87.35 131.61,86.45 131.88,86.18 132.31,86.18 132.58,86.45 132.58,87.35 132.68,87.45 132.88,87.45 132.98,87.35 132.98,86.45 133.25,86.18 133.68,86.18 133.95,86.45 133.95,87.35 134.05,87.45 134.25,87.45 134.35,87.35 134.35,86.45 134.62,86.18 135.05,86.18 135.32,86.45 135.32,87.35 135.42,87.45 135.62,87.45 135.72,87.35 135.72,86.45 135.99,86.18 136.42,86.18 136.69,86.45 136.69,87.35 136.79,87.45 136.99,87.45 137.1,87.35 137.1,86.45 137.36,86.18 137.8,86.18 138.06,86.45 138.06,87.35 138.16,87.45 138.37,87.45 138.47,87.35 138.47,86.45 138.73,86.18 139.17,86.18 139.43,86.45 139.43,87.35 139.53,87.45 139.74,87.45 139.84,87.35 139.84,86.45 140.1,86.18 140.54,86.18 140.8,86.45 140.8,87.35 140.91,87.45 141.11,87.45 141.21,87.35 141.21,86.45 141.48,86.18 141.91,86.18 142.18,86.45 142.18,87.35 142.28,87.45 142.48,87.45 142.58,87.35 142.58,86.45 142.85,86.18 143.28,86.18 143.55,86.45 143.55,87.35 143.65,87.45 143.85,87.45 143.95,87.35 143.95,86.45 144.22,86.18 144.65,86.18 144.92,86.45 144.92,87.35 145.02,87.45 145.22,87.45 145.33,87.35 145.33,86.45 145.59,86.18 157.52,86.18 160.87,82.83 178.68,82.83 179.26,83.41 182.05,83.41 182.64,82.83 189.36,82.83 189.87,83.33 192.89,83.33 194.44,81.78 194.44,80.05 195.29,79.2 196.12,79.2 197.52,77.8 198.86,77.8 200.48,76.18 200.48,75.62 201.04,75.05 202.27,75.05 202.56,74.76 v1(202.56,74.51)
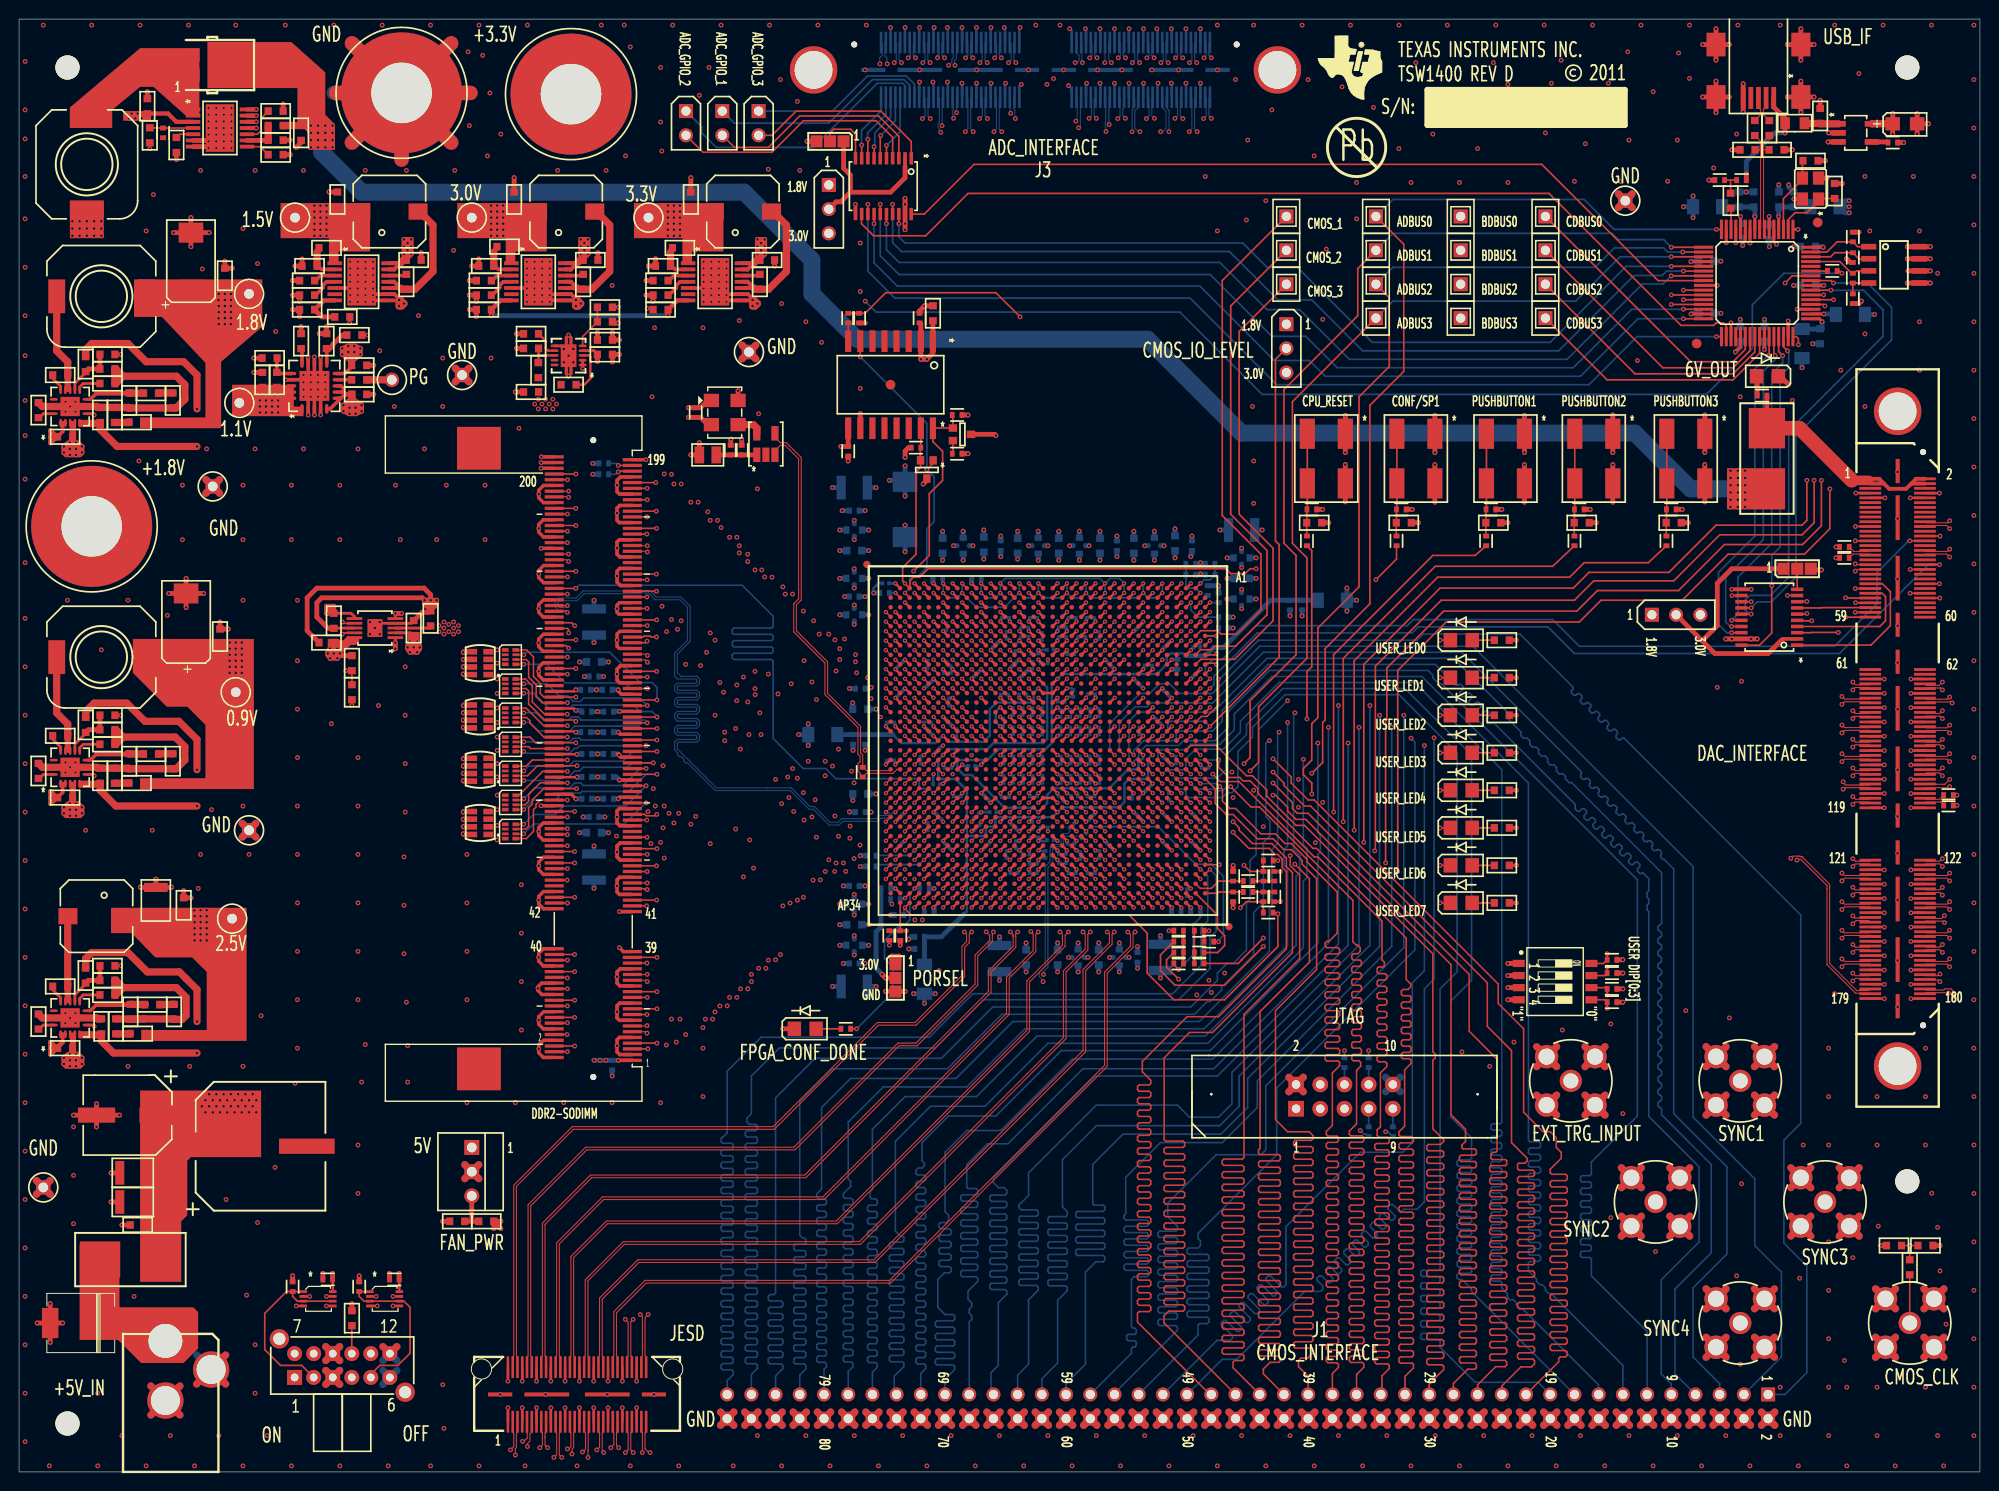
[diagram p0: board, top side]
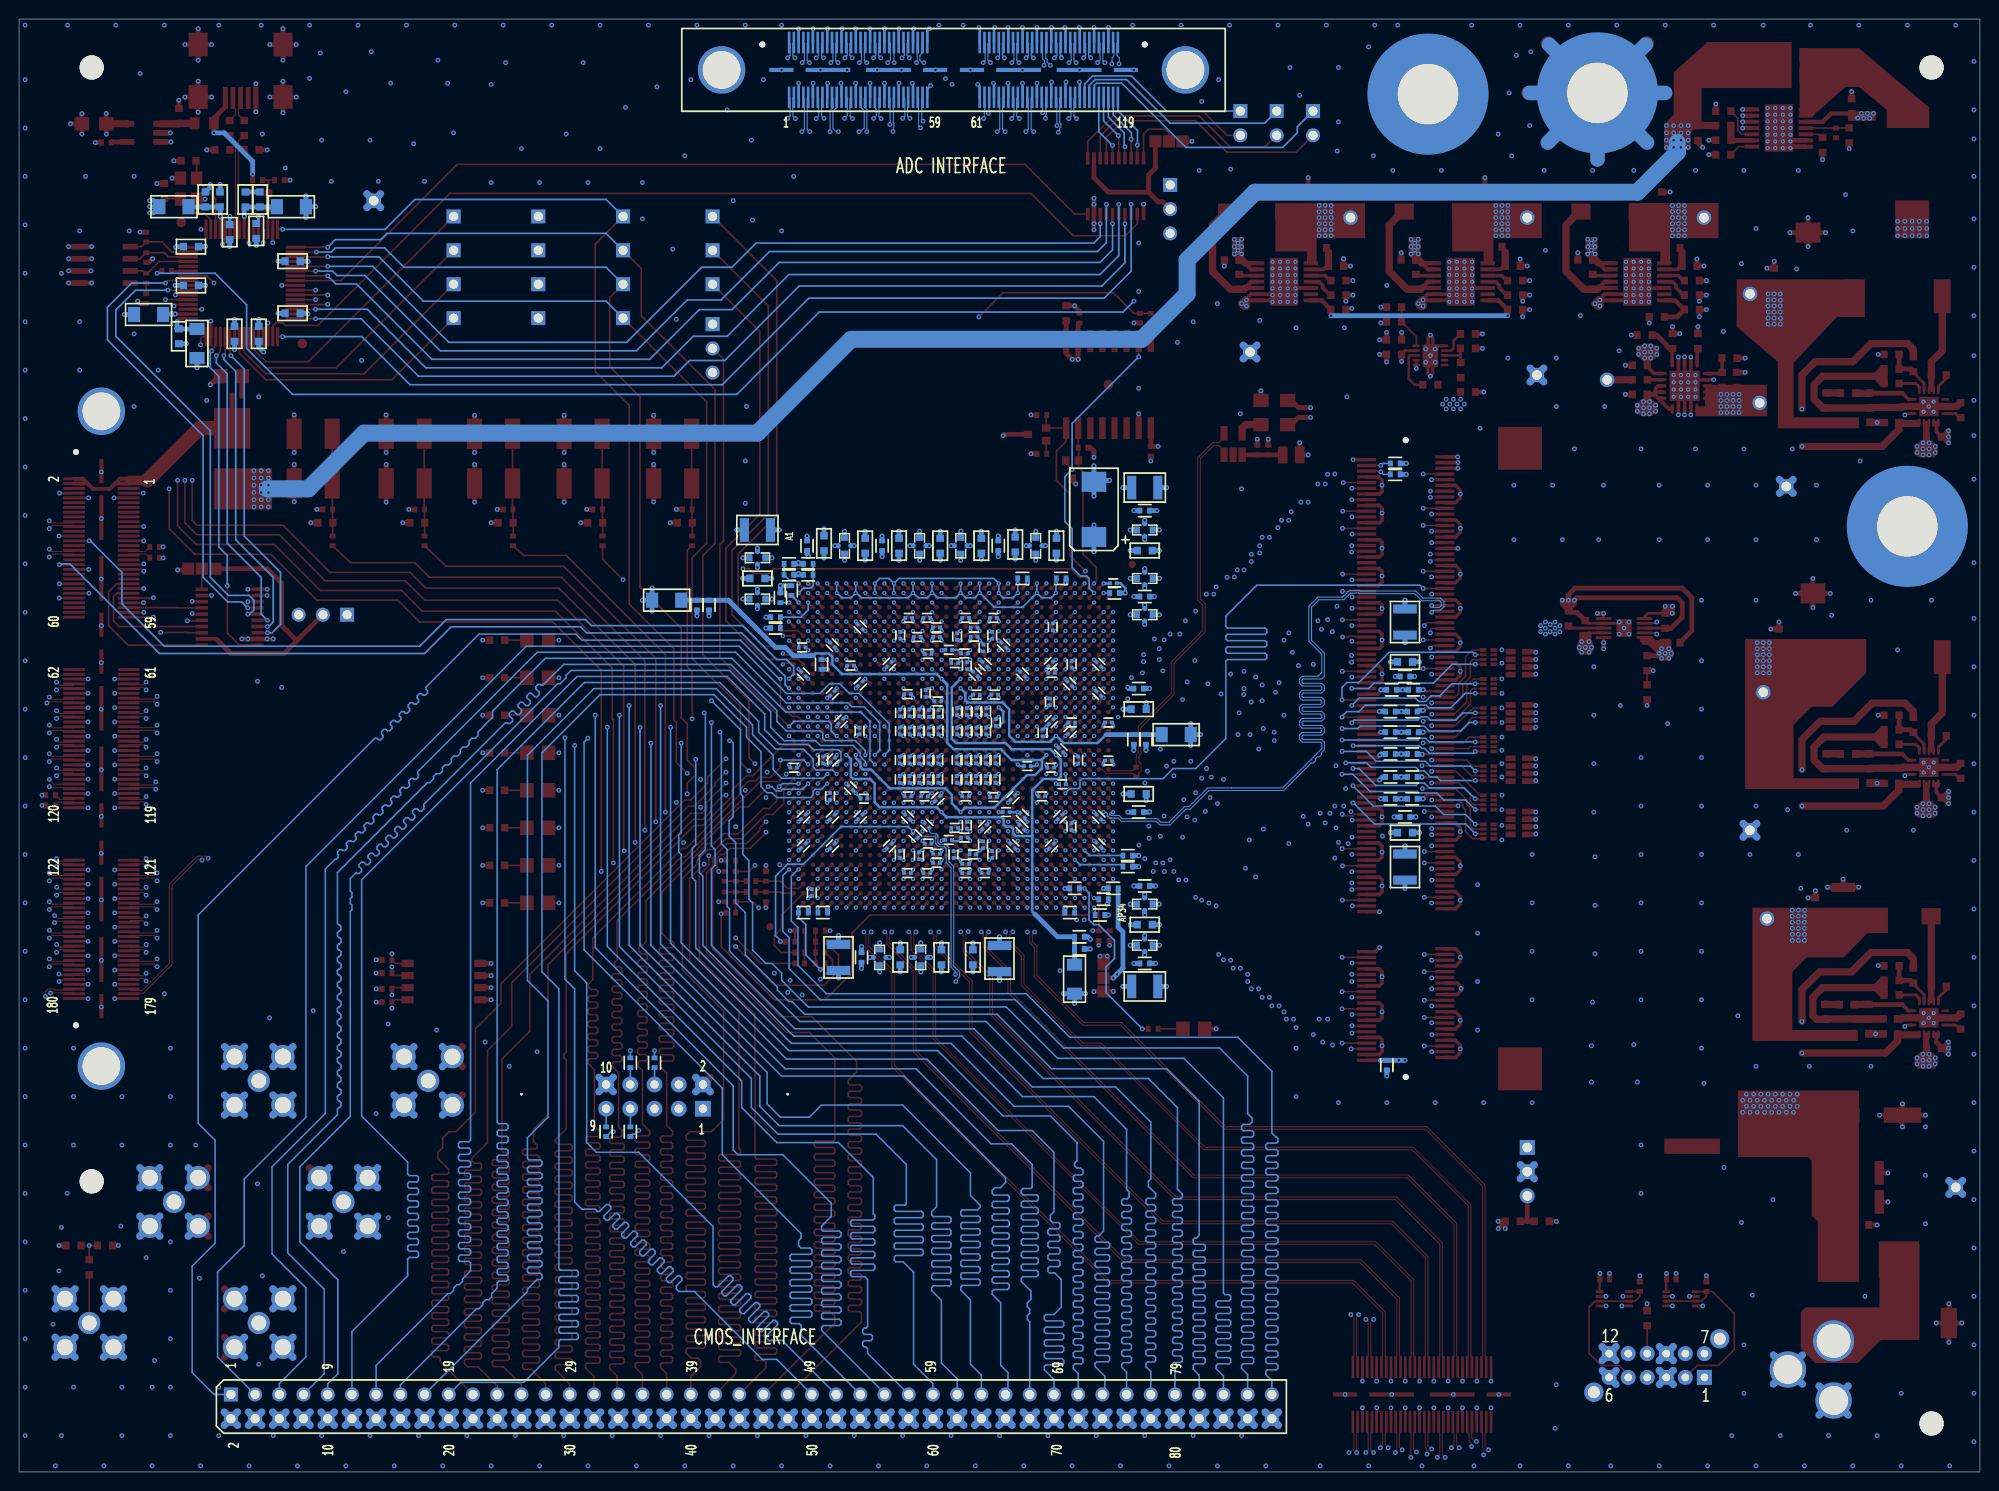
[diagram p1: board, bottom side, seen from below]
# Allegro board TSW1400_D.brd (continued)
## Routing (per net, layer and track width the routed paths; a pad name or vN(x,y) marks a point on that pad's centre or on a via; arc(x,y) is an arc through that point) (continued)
DB10P: length 135.3
  TOP w0.114: J4.98 200.08,75.06 202.28,75.06 v1(202.56,75.34) ; U5.W12 v2(105.95,82.2)
  L4-SIG2 w0.102: v2(105.95,82.2) 105.81,82.34 105.43,82.34 105.33,82.24 105.33,82.16 105.55,81.94 105.55,81.48 105.57,81.46 105.57,81.04 105.79,80.82 107.21,80.82 107.28,80.75 108.62,80.75 108.69,80.82 113.21,80.82 113.28,80.75 118.62,80.75 118.69,80.82 119.21,80.82 119.28,80.75 120.62,80.75 120.69,80.82 125.38,80.82 125.41,80.84 129.77,85.21 129.77,86.04 130.19,86.46 130.19,86.47 130.92,87.21 130.92,87.42 131.24,87.73 131.62,87.73 131.89,87.47 131.89,86.56 131.99,86.46 132.19,86.46 132.3,86.56 132.3,87.47 132.56,87.73 133,87.73 133.26,87.47 133.26,86.56 133.36,86.46 133.57,86.46 133.67,86.56 133.67,87.47 133.93,87.73 134.37,87.73 134.63,87.47 134.63,86.56 134.73,86.46 134.94,86.46 135.04,86.56 135.04,87.47 135.3,87.73 135.74,87.73 136,87.47 136,86.56 136.11,86.46 136.31,86.46 136.41,86.56 136.41,87.47 136.68,87.73 137.11,87.73 137.38,87.47 137.38,86.56 137.48,86.46 137.68,86.46 137.78,86.56 137.78,87.47 138.05,87.73 138.48,87.73 138.75,87.47 138.75,86.56 138.85,86.46 139.05,86.46 139.15,86.56 139.15,87.47 139.42,87.73 139.85,87.73 140.12,87.47 140.12,86.56 140.22,86.46 140.42,86.46 140.53,86.56 140.53,87.47 140.79,87.73 141.23,87.73 141.49,87.47 141.49,86.56 141.59,86.46 141.8,86.46 141.9,86.56 141.9,87.47 142.16,87.73 142.6,87.73 142.86,87.47 142.86,86.56 142.96,86.46 143.17,86.46 143.27,86.56 143.27,87.47 143.53,87.73 143.97,87.73 144.23,87.47 144.23,86.56 144.34,86.46 144.54,86.46 144.64,86.56 144.64,87.47 144.91,87.73 145.34,87.73 145.61,87.47 145.61,86.56 145.71,86.46 157.63,86.46 160.99,83.11 178.56,83.11 179.15,83.69 182.17,83.69 182.75,83.11 189.25,83.11 189.75,83.61 193,83.61 194.72,81.9 194.72,80.17 195.41,79.48 196.24,79.48 197.64,78.08 198.98,78.08 200.76,76.29 200.76,75.73 201.16,75.33 202.41,75.33 202.42,75.34 v1(202.56,75.34)
DB11N: length 135.5
  TOP w0.114: v1(201.8,76.03) 201.55,76.28 200.08,76.28 J4.94 ; U5.AA8 v2(103.95,86.2)
  L4-SIG2 w0.102: v2(103.95,86.2) 104.54,85.61 104.54,85 104.73,84.82 106.22,84.82 106.57,84.47 106.57,83.96 106.71,83.82 107.22,83.82 108.23,82.81 108.69,82.81 108.69,82.82 109.21,82.82 109.21,82.81 109.69,82.81 109.69,82.82 110.21,82.82 110.21,82.81 110.69,82.81 110.69,82.82 111.21,82.82 111.21,82.81 111.69,82.81 111.69,82.82 112.21,82.82 112.21,82.81 112.69,82.81 112.69,82.82 113.21,82.82 113.21,82.81 113.69,82.81 113.69,82.82 114.21,82.82 114.21,82.81 117.69,82.81 117.69,82.82 118.21,82.82 118.21,82.81 119.69,82.81 119.69,82.82 120.21,82.82 120.21,82.81 121.52,82.81 122.52,83.82 125.19,83.82 125.23,83.86 125.63,83.86 126.34,84.57 126.34,84.57 126.58,84.81 126.66,84.89 126.66,85.77 127.51,86.63 127.65,86.63 131.6,90.58 138.2,90.58 138.63,91.01 139.31,91.01 139.73,91.01 140.16,90.58 140.96,90.58 141.92,91.54 142.36,91.54 142.62,91.28 142.62,90.68 142.72,90.58 142.93,90.58 143.03,90.68 143.03,91.28 143.29,91.54 143.73,91.54 143.99,91.28 143.99,90.68 144.1,90.58 144.3,90.58 144.4,90.68 144.4,91.28 144.67,91.54 145.1,91.54 145.37,91.28 145.37,90.68 145.47,90.58 145.67,90.58 145.77,90.68 145.77,91.28 146.04,91.54 146.47,91.54 146.74,91.28 146.74,90.68 146.84,90.58 147.04,90.58 147.14,90.68 147.14,91.28 147.41,91.54 147.84,91.54 148.11,91.28 148.11,90.68 148.21,90.58 148.41,90.58 148.52,90.68 148.52,91.28 148.78,91.54 149.22,91.54 149.48,91.28 149.48,90.68 149.58,90.58 149.79,90.58 149.89,90.68 149.89,91.28 150.15,91.54 150.59,91.54 150.85,91.28 150.85,90.68 150.95,90.58 151.16,90.58 151.26,90.68 151.26,91.28 151.52,91.54 151.96,91.54 152.22,91.28 152.22,90.68 152.33,90.58 152.53,90.58 152.63,90.68 152.63,91.28 152.9,91.54 153.33,91.54 153.6,91.28 153.6,90.68 153.7,90.58 153.9,90.58 154,90.68 154,91.28 154.27,91.54 154.7,91.54 154.97,91.28 154.97,90.68 155.07,90.58 155.27,90.58 155.37,90.68 155.37,91.28 155.64,91.54 156.07,91.54 156.34,91.28 156.34,90.68 156.44,90.58 156.64,90.58 156.75,90.68 156.75,91.28 157.01,91.54 157.78,91.54 163.45,85.88 198.74,85.88 200.03,84.6 200.03,82.77 203.32,79.48 203.32,77.18 202.43,76.3 202.07,76.3 v1(201.8,76.03)
DB11P: length 135.5
  TOP w0.114: U5.AA9 v2(103.95,85.2) ; J4.92 200.08,76.56 201.51,76.56 v1(201.8,76.85)
  L4-SIG2 w0.102: v1(201.8,76.85) 202.07,76.58 202.32,76.58 203.04,77.3 203.04,79.36 199.75,82.65 199.75,84.48 198.63,85.6 163.33,85.6 157.67,91.26 157.13,91.26 157.02,91.16 157.02,90.56 156.76,90.3 156.32,90.3 156.06,90.56 156.06,91.16 155.96,91.26 155.75,91.26 155.65,91.16 155.65,90.56 155.39,90.3 154.95,90.3 154.69,90.56 154.69,91.16 154.59,91.26 154.38,91.26 154.28,91.16 154.28,90.56 154.02,90.3 153.58,90.3 153.32,90.56 153.32,91.16 153.21,91.26 153.01,91.26 152.91,91.16 152.91,90.56 152.64,90.3 152.21,90.3 151.94,90.56 151.94,91.16 151.84,91.26 151.64,91.26 151.54,91.16 151.54,90.56 151.27,90.3 150.84,90.3 150.57,90.56 150.57,91.16 150.47,91.26 150.27,91.26 150.17,91.16 150.17,90.56 149.9,90.3 149.47,90.3 149.2,90.56 149.2,91.16 149.1,91.26 148.9,91.26 148.8,91.16 148.8,90.56 148.53,90.3 148.1,90.3 147.83,90.56 147.83,91.16 147.73,91.26 147.53,91.26 147.42,91.16 147.42,90.56 147.16,90.3 146.72,90.3 146.46,90.56 146.46,91.16 146.36,91.26 146.15,91.26 146.05,91.16 146.05,90.56 145.79,90.3 145.35,90.3 145.09,90.56 145.09,91.16 144.99,91.26 144.78,91.26 144.68,91.16 144.68,90.56 144.42,90.3 143.98,90.3 143.72,90.56 143.72,91.16 143.61,91.26 143.41,91.26 143.31,91.16 143.31,90.56 143.04,90.3 142.61,90.3 142.34,90.56 142.34,91.16 142.24,91.26 142.04,91.26 141.07,90.3 140.04,90.3 139.61,90.73 139.19,90.73 138.75,90.73 138.32,90.3 131.71,90.3 127.76,86.35 127.62,86.35 126.94,85.66 126.94,84.77 126.78,84.61 126.46,84.29 126.46,84.29 125.75,83.58 122.62,83.58 121.62,82.58 120.11,82.58 120.11,82.58 119.79,82.58 119.79,82.58 118.11,82.58 118.11,82.58 117.79,82.58 117.79,82.58 114.11,82.58 114.11,82.58 113.79,82.58 113.79,82.58 113.11,82.58 113.11,82.58 112.79,82.58 112.79,82.58 112.11,82.58 112.11,82.58 111.79,82.58 111.79,82.58 111.11,82.58 111.11,82.58 110.79,82.58 110.79,82.58 110.11,82.58 110.11,82.58 109.79,82.58 109.79,82.58 109.11,82.58 109.11,82.58 108.79,82.58 108.79,82.58 108.13,82.58 107.12,83.58 106.61,83.58 106.33,83.86 106.33,84.37 106.12,84.58 104.57,84.58 104.3,84.85 104.3,85.51 104.03,85.79 103.77,85.79 103.67,85.69 103.67,85.49 103.95,85.21 v2(103.95,85.2)
DB12N: length 135.5
  TOP w0.114: U5.Y10 v2(104.95,84.2) ; v1(202.56,77.52) 202.3,77.78 200.08,77.78 J4.88
  L4-SIG2 w0.102: v1(202.56,77.52) 201.74,77.52 200.58,78.68 200.58,79.1 198.86,80.82 197.9,80.82 196.45,82.27 195.54,82.27 193.25,84.56 172.27,84.56 172.17,84.45 172.17,84.34 171.9,84.07 171.47,84.07 171.2,84.34 171.2,84.45 171.1,84.56 170.9,84.56 170.8,84.45 170.8,84.34 170.53,84.07 170.1,84.07 169.83,84.34 169.83,84.45 169.73,84.56 169.53,84.56 169.43,84.45 169.43,84.34 169.16,84.07 168.73,84.07 168.46,84.34 168.46,84.45 168.36,84.56 168.16,84.56 168.05,84.45 168.05,84.34 167.79,84.07 167.35,84.07 167.09,84.34 167.09,84.45 166.99,84.56 166.78,84.56 166.68,84.45 166.68,84.34 166.42,84.07 165.98,84.07 165.72,84.34 165.72,84.45 165.62,84.56 165.41,84.56 165.31,84.45 165.31,84.34 165.05,84.07 164.61,84.07 164.35,84.34 164.35,84.45 164.24,84.56 164.04,84.56 163.94,84.45 163.94,84.34 163.67,84.07 163.24,84.07 162.97,84.34 162.97,84.45 162.87,84.56 161.67,84.56 157.02,89.2 154.88,89.2 154.78,89.1 154.78,88.66 154.51,88.39 154.08,88.39 153.81,88.66 153.81,89.1 153.71,89.2 153.51,89.2 153.4,89.1 153.4,88.66 153.14,88.39 152.7,88.39 152.44,88.66 152.44,89.1 152.34,89.2 152.13,89.2 152.03,89.1 152.03,88.66 151.77,88.39 151.33,88.39 151.07,88.66 151.07,89.1 150.97,89.2 150.76,89.2 150.66,89.1 150.66,88.66 150.4,88.39 149.96,88.39 149.7,88.66 149.7,89.1 149.59,89.2 149.39,89.2 149.29,89.1 149.29,88.66 149.02,88.39 148.59,88.39 148.32,88.66 148.32,89.1 148.22,89.2 148.02,89.2 147.92,89.1 147.92,88.66 147.65,88.39 147.22,88.39 146.95,88.66 146.95,89.1 146.85,89.2 146.65,89.2 146.55,89.1 146.55,88.66 146.28,88.39 145.85,88.39 145.58,88.66 145.58,89.1 145.48,89.2 145.28,89.2 145.17,89.1 145.17,88.66 144.91,88.39 144.47,88.39 144.21,88.66 144.21,89.1 144.11,89.2 143.9,89.2 143.8,89.1 143.8,88.66 143.54,88.39 143.1,88.39 142.84,88.66 142.84,89.1 142.74,89.2 142.53,89.2 142.43,89.1 142.43,88.66 142.17,88.39 141.73,88.39 141.47,88.66 141.47,89.1 141.36,89.2 141.16,89.2 141.06,89.1 141.06,88.66 140.79,88.39 140.36,88.39 140.09,88.66 140.09,89.1 139.99,89.2 139.79,89.2 139.69,89.1 139.69,88.66 139.42,88.39 138.99,88.39 138.72,88.66 138.72,89.1 138.62,89.2 138.42,89.2 138.32,89.1 138.32,88.66 138.05,88.39 137.62,88.39 137.35,88.66 137.35,89.1 137.25,89.2 137.05,89.2 136.94,89.1 136.94,88.66 136.68,88.39 136.24,88.39 135.98,88.66 135.98,89.1 135.88,89.2 135.37,89.2 134.91,88.75 131.42,88.75 128.02,85.34 128.02,84.2 125.59,81.77 125.59,81.73 125.37,81.51 125.18,81.51 125.11,81.58 124.79,81.58 124.79,81.58 124.11,81.58 124.11,81.58 123.79,81.58 123.79,81.58 121.11,81.58 121.11,81.58 120.79,81.58 120.79,81.58 118.11,81.58 118.11,81.58 117.79,81.58 117.79,81.58 115.11,81.58 115.11,81.58 114.79,81.58 114.79,81.58 113.11,81.58 113.11,81.58 112.79,81.58 112.79,81.58 112.11,81.58 112.11,81.58 111.79,81.58 111.79,81.58 111.11,81.58 111.11,81.58 110.79,81.58 110.79,81.58 110.11,81.58 110.11,81.58 109.79,81.58 109.79,81.58 109.11,81.58 109.11,81.58 108.79,81.58 108.79,81.58 107.11,81.58 107.11,81.58 106.69,81.58 106.33,81.94 106.33,82.36 106.11,82.58 103.74,82.58 103.35,82.97 103.35,83.54 103.61,83.8 104.55,83.8 v2(104.95,84.2)
DB12P: length 135.4
  TOP w0.114: v1(202.56,78.34) 202.28,78.06 200.08,78.06 J4.86 ; U5.AA11 v2(103.95,83.2)
  L4-SIG2 w0.102: v2(103.95,83.2) 104.05,83.1 104.46,83.1 104.57,83.21 104.57,83.47 104.48,83.56 103.71,83.56 103.59,83.44 103.59,83.07 103.84,82.82 106.21,82.82 106.57,82.46 106.57,82.04 106.79,81.82 107.21,81.82 107.21,81.81 108.69,81.81 108.69,81.82 109.21,81.82 109.21,81.81 109.69,81.81 109.69,81.82 110.21,81.82 110.21,81.81 110.69,81.81 110.69,81.82 111.21,81.82 111.21,81.81 111.69,81.81 111.69,81.82 112.21,81.82 112.21,81.81 112.69,81.81 112.69,81.82 113.21,81.82 113.21,81.81 114.69,81.81 114.69,81.82 115.21,81.82 115.21,81.81 117.69,81.81 117.69,81.82 118.21,81.82 118.21,81.81 120.69,81.81 120.69,81.82 121.21,81.82 121.21,81.81 123.69,81.81 123.69,81.82 124.21,81.82 124.21,81.81 124.69,81.81 124.69,81.82 125.24,81.82 127.74,84.32 127.74,85.46 131.3,89.03 134.8,89.03 135.25,89.48 135.99,89.48 136.26,89.22 136.26,88.77 136.36,88.67 136.56,88.67 136.67,88.77 136.67,89.22 136.93,89.48 137.37,89.48 137.63,89.22 137.63,88.77 137.73,88.67 137.94,88.67 138.04,88.77 138.04,89.22 138.3,89.48 138.74,89.48 139,89.22 139,88.77 139.1,88.67 139.31,88.67 139.41,88.77 139.41,89.22 139.67,89.48 140.11,89.48 140.37,89.22 140.37,88.77 140.48,88.67 140.68,88.67 140.78,88.77 140.78,89.22 141.05,89.48 141.48,89.48 141.75,89.22 141.75,88.77 141.85,88.67 142.05,88.67 142.15,88.77 142.15,89.22 142.42,89.48 142.85,89.48 143.12,89.22 143.12,88.77 143.22,88.67 143.42,88.67 143.52,88.77 143.52,89.22 143.79,89.48 144.22,89.48 144.49,89.22 144.49,88.77 144.59,88.67 144.79,88.67 144.89,88.77 144.89,89.22 145.16,89.48 145.59,89.48 145.86,89.22 145.86,88.77 145.96,88.67 146.16,88.67 146.27,88.77 146.27,89.22 146.53,89.48 146.97,89.48 147.23,89.22 147.23,88.77 147.33,88.67 147.54,88.67 147.64,88.77 147.64,89.22 147.9,89.48 148.34,89.48 148.6,89.22 148.6,88.77 148.7,88.67 148.91,88.67 149.01,88.77 149.01,89.22 149.28,89.48 149.71,89.48 149.97,89.22 149.97,88.77 150.08,88.67 150.28,88.67 150.38,88.77 150.38,89.22 150.65,89.48 151.08,89.48 151.35,89.22 151.35,88.77 151.45,88.67 151.65,88.67 151.75,88.77 151.75,89.22 152.02,89.48 152.45,89.48 152.72,89.22 152.72,88.77 152.82,88.67 153.02,88.67 153.12,88.77 153.12,89.22 153.39,89.48 153.82,89.48 154.09,89.22 154.09,88.77 154.19,88.67 154.39,88.67 154.5,88.77 154.5,89.22 154.76,89.48 157.14,89.48 161.79,84.84 162.99,84.84 163.25,84.57 163.25,84.45 163.36,84.35 163.56,84.35 163.66,84.45 163.66,84.57 163.93,84.84 164.36,84.84 164.63,84.57 164.63,84.45 164.73,84.35 164.93,84.35 165.03,84.45 165.03,84.57 165.3,84.84 165.73,84.84 166,84.57 166,84.45 166.1,84.35 166.3,84.35 166.4,84.45 166.4,84.57 166.67,84.84 167.1,84.84 167.37,84.57 167.37,84.45 167.47,84.35 167.67,84.35 167.78,84.45 167.78,84.57 168.04,84.84 168.48,84.84 168.74,84.57 168.74,84.45 168.84,84.35 169.05,84.35 169.15,84.45 169.15,84.57 169.41,84.84 169.85,84.84 170.11,84.57 170.11,84.45 170.21,84.35 170.42,84.35 170.52,84.45 170.52,84.57 170.78,84.84 171.22,84.84 171.48,84.57 171.48,84.45 171.59,84.35 171.79,84.35 171.89,84.45 171.89,84.57 172.16,84.84 193.37,84.84 195.66,82.55 196.57,82.55 198.02,81.1 198.97,81.1 200.86,79.21 200.86,78.79 201.86,77.8 202.19,77.8 202.56,78.17 v1(202.56,78.34)
DB13N: length 135.3
  TOP w0.114: J4.82 200.08,79.28 201.55,79.28 v1(201.8,79.03) ; U5.V10 v2(106.95,84.2)
  L10-SIG4 w0.102: v2(106.95,84.2) 106.87,84.28 106.53,84.28 106.45,84.2 106.45,83.97 106.53,83.89 107.28,83.89 108.33,84.94 108.33,85.46 108.69,85.82 115.66,85.82 116.59,86.74 117.62,86.74 117.69,86.82 120.21,86.82 120.28,86.74 122.62,86.74 122.69,86.82 123.21,86.82 123.28,86.74 130.34,86.74 132.55,88.95 134.85,88.95 137.46,91.57 139.37,91.57 140.35,90.59 141.39,90.59 142.75,91.95 144.04,91.95 144.31,91.68 144.31,91.31 144.41,91.21 144.61,91.21 144.71,91.31 144.71,91.68 144.98,91.95 145.41,91.95 145.68,91.68 145.68,91.31 145.78,91.21 145.98,91.21 146.08,91.31 146.08,91.68 146.35,91.95 146.78,91.95 147.05,91.68 147.05,91.31 147.15,91.21 147.35,91.21 147.46,91.31 147.46,91.68 147.72,91.95 148.16,91.95 148.42,91.68 148.42,91.31 148.52,91.21 148.73,91.21 148.83,91.31 148.83,91.68 149.09,91.95 149.53,91.95 149.79,91.68 149.79,91.31 149.89,91.21 150.1,91.21 150.2,91.31 150.2,91.68 150.46,91.95 150.9,91.95 151.16,91.68 151.16,91.31 151.27,91.21 151.47,91.21 151.57,91.31 151.57,91.68 151.84,91.95 152.27,91.95 152.54,91.68 152.54,91.31 152.64,91.21 152.84,91.21 152.94,91.31 152.94,91.68 153.21,91.95 153.64,91.95 153.91,91.68 153.91,91.31 154.01,91.21 154.21,91.21 154.31,91.31 154.31,91.68 154.58,91.95 155.01,91.95 155.28,91.68 155.28,91.31 155.38,91.21 155.58,91.21 155.68,91.31 155.68,91.68 155.95,91.95 156.38,91.95 156.65,91.68 156.65,91.31 156.75,91.21 156.95,91.21 157.06,91.31 157.06,91.68 157.32,91.95 157.76,91.95 158.02,91.68 158.02,91.31 158.12,91.21 158.33,91.21 158.43,91.31 158.43,91.68 158.69,91.95 159.13,91.95 159.39,91.68 159.39,91.31 159.49,91.21 159.7,91.21 159.8,91.31 159.8,91.68 160.07,91.95 160.5,91.95 160.76,91.68 160.76,91.31 160.87,91.21 161.07,91.21 161.17,91.31 161.17,91.68 161.44,91.95 161.87,91.95 162.14,91.68 162.14,91.31 162.24,91.21 162.44,91.21 162.54,91.31 162.54,91.68 162.81,91.95 163.24,91.95 163.51,91.68 163.51,91.31 163.61,91.21 163.81,91.21 163.91,91.31 163.91,91.68 164.18,91.95 164.61,91.95 164.88,91.68 164.88,91.31 164.98,91.21 165.18,91.21 165.29,91.31 165.29,91.68 165.55,91.95 165.99,91.95 166.25,91.68 166.25,91.31 166.35,91.21 166.56,91.21 166.66,91.31 166.66,91.68 166.92,91.95 167.36,91.95 167.62,91.68 167.62,91.31 167.72,91.21 167.93,91.21 168.03,91.31 168.03,91.68 168.29,91.95 168.73,91.95 168.99,91.68 168.99,91.48 169.05,91.42 169.14,91.42 169.67,91.95 178.57,91.95 181.4,89.12 182.1,89.12 183.85,87.37 191.29,87.37 192.19,88.27 200.28,88.27 203.59,84.96 203.59,80.11 202.82,79.34 202.12,79.34 v1(201.8,79.03)
DB13P: length 135.4
  TOP w0.114: J4.80 200.08,79.56 201.51,79.56 v1(201.8,79.85) ; U5.W11 v2(105.95,83.2)
  L10-SIG4 w0.102: v2(105.95,83.2) 106.4,83.65 107.37,83.65 108.57,84.84 108.57,85.36 108.79,85.58 115.76,85.58 116.68,86.5 117.71,86.5 117.79,86.58 120.11,86.58 120.19,86.5 122.71,86.5 122.79,86.58 123.11,86.58 123.19,86.5 125.19,86.5 125.23,86.46 130.45,86.46 132.66,88.67 134.96,88.67 137.58,91.29 139.25,91.29 140.23,90.31 141.51,90.31 142.87,91.67 143.92,91.67 144.03,91.57 144.03,91.2 144.29,90.93 144.73,90.93 144.99,91.2 144.99,91.57 145.09,91.67 145.3,91.67 145.4,91.57 145.4,91.2 145.66,90.93 146.1,90.93 146.36,91.2 146.36,91.57 146.46,91.67 146.67,91.67 146.77,91.57 146.77,91.2 147.03,90.93 147.47,90.93 147.73,91.2 147.73,91.57 147.84,91.67 148.04,91.67 148.14,91.57 148.14,91.2 148.41,90.93 148.84,90.93 149.11,91.2 149.11,91.57 149.21,91.67 149.41,91.67 149.51,91.57 149.51,91.2 149.78,90.93 150.21,90.93 150.48,91.2 150.48,91.57 150.58,91.67 150.78,91.67 150.88,91.57 150.88,91.2 151.15,90.93 151.58,90.93 151.85,91.2 151.85,91.57 151.95,91.67 152.15,91.67 152.26,91.57 152.26,91.2 152.52,90.93 152.96,90.93 153.22,91.2 153.22,91.57 153.32,91.67 153.53,91.67 153.63,91.57 153.63,91.2 153.89,90.93 154.33,90.93 154.59,91.2 154.59,91.57 154.69,91.67 154.9,91.67 155,91.57 155,91.2 155.26,90.93 155.7,90.93 155.96,91.2 155.96,91.57 156.07,91.67 156.27,91.67 156.37,91.57 156.37,91.2 156.64,90.93 157.07,90.93 157.34,91.2 157.34,91.57 157.44,91.67 157.64,91.67 157.74,91.57 157.74,91.2 158.01,90.93 158.44,90.93 158.71,91.2 158.71,91.57 158.81,91.67 159.01,91.67 159.11,91.57 159.11,91.2 159.38,90.93 159.81,90.93 160.08,91.2 160.08,91.57 160.18,91.67 160.38,91.67 160.49,91.57 160.49,91.2 160.75,90.93 161.19,90.93 161.45,91.2 161.45,91.57 161.55,91.67 161.76,91.67 161.86,91.57 161.86,91.2 162.12,90.93 162.56,90.93 162.82,91.2 162.82,91.57 162.92,91.67 163.13,91.67 163.23,91.57 163.23,91.2 163.49,90.93 163.93,90.93 164.19,91.2 164.19,91.57 164.3,91.67 164.5,91.67 164.6,91.57 164.6,91.2 164.87,90.93 165.3,90.93 165.57,91.2 165.57,91.57 165.67,91.67 165.87,91.67 165.97,91.57 165.97,91.2 166.24,90.93 166.67,90.93 166.94,91.2 166.94,91.57 167.04,91.67 167.24,91.67 167.34,91.57 167.34,91.2 167.61,90.93 168.04,90.93 168.31,91.2 168.31,91.57 168.41,91.67 168.61,91.67 168.72,91.57 168.72,91.2 168.98,90.93 169.42,90.93 169.68,91.2 169.68,91.57 169.78,91.67 170.13,91.67 170.23,91.57 170.23,91.54 170.33,91.44 170.54,91.44 170.64,91.54 170.64,91.57 170.74,91.67 170.94,91.67 171.04,91.57 171.04,91.54 171.15,91.44 171.35,91.44 171.45,91.54 171.45,91.57 171.55,91.67 171.76,91.67 171.86,91.57 171.86,91.54 171.96,91.44 172.16,91.44 172.26,91.54 172.26,91.57 172.37,91.67 178.46,91.67 181.28,88.84 181.98,88.84 183.73,87.09 191.41,87.09 192.3,87.99 200.16,87.99 203.31,84.84 203.31,80.23 202.7,79.62 202.03,79.62 v1(201.8,79.85)
DB14N: length 135.5
  TOP w0.114: J4.76 200.07,80.77 202.72,80.77 v1(202.83,80.66) ; U5.R10 v2(110.95,84.2)
  L10-SIG4 w0.102: v2(110.95,84.2) 111.47,84.72 111.49,84.72 111.58,84.81 111.69,84.81 111.69,84.82 112.21,84.82 112.21,84.81 112.69,84.81 112.69,84.82 113.21,84.82 113.21,84.81 113.69,84.81 113.69,84.82 114.21,84.82 114.21,84.81 114.69,84.81 114.69,84.82 115.21,84.82 115.21,84.81 115.69,84.81 115.69,84.82 116.21,84.82 116.21,84.81 116.69,84.81 116.69,84.82 117.21,84.82 117.21,84.81 117.69,84.81 117.69,84.82 118.21,84.82 118.21,84.81 118.69,84.81 118.69,84.82 119.21,84.82 119.21,84.81 120.69,84.81 120.69,84.82 121.21,84.82 121.21,84.81 122.02,84.81 122.08,84.87 122.92,85.71 125.13,85.71 125.4,85.44 128.62,85.44 129.03,85.85 132.9,85.85 134.35,87.3 139.38,87.3 140.59,88.51 141.39,88.51 141.49,88.61 141.49,89.24 141.76,89.51 142.19,89.51 142.46,89.24 142.46,88.61 142.56,88.51 142.76,88.51 142.86,88.61 142.86,89.24 143.13,89.51 143.56,89.51 143.83,89.24 143.83,88.61 143.93,88.51 144.13,88.51 144.23,88.61 144.23,89.24 144.5,89.51 144.93,89.51 145.2,89.24 145.2,88.61 145.3,88.51 145.5,88.51 145.61,88.61 145.61,89.24 145.87,89.51 146.31,89.51 146.57,89.24 146.57,88.61 146.67,88.51 146.88,88.51 146.98,88.61 146.98,89.24 147.24,89.51 147.68,89.51 147.94,89.24 147.94,88.61 148.04,88.51 148.25,88.51 148.35,88.61 148.35,89.24 148.61,89.51 149.05,89.51 149.31,89.24 149.31,88.61 149.42,88.51 149.62,88.51 149.72,88.61 149.72,89.24 149.99,89.51 150.42,89.51 150.69,89.24 150.69,88.61 150.79,88.51 150.99,88.51 151.09,88.61 151.09,89.24 151.36,89.51 151.79,89.51 152.06,89.24 152.06,88.61 152.16,88.51 152.36,88.51 152.46,88.61 152.46,89.24 152.73,89.51 153.16,89.51 153.43,89.24 153.43,88.61 153.53,88.51 153.73,88.51 153.83,88.61 153.83,89.24 154.1,89.51 154.53,89.51 154.8,89.24 154.8,88.61 154.9,88.51 155.1,88.51 155.21,88.61 155.21,89.24 155.47,89.51 155.91,89.51 156.17,89.24 156.17,88.61 156.27,88.51 156.48,88.51 156.58,88.61 156.58,89.24 156.84,89.51 157.28,89.51 157.54,89.24 157.54,88.61 157.64,88.51 157.85,88.51 157.95,88.61 157.95,89.24 158.21,89.51 158.65,89.51 158.91,89.24 159.65,88.51 160.25,88.51 160.51,88.24 160.51,87.78 160.61,87.68 160.76,87.68 160.92,87.84 160.92,88.24 161.18,88.51 161.62,88.51 161.88,88.24 161.88,87.78 161.98,87.68 162.19,87.68 162.29,87.78 162.29,88.24 162.55,88.51 162.99,88.51 163.25,88.24 163.25,87.78 163.36,87.68 163.56,87.68 163.66,87.78 163.66,88.24 163.93,88.51 164.36,88.51 164.63,88.24 164.63,87.78 164.73,87.68 164.93,87.68 165.03,87.78 165.03,88.24 165.3,88.51 165.73,88.51 166,88.24 166,87.78 166.1,87.68 166.3,87.68 166.4,87.78 166.4,88.24 166.67,88.51 167.1,88.51 167.37,88.24 167.37,87.78 167.47,87.68 167.67,87.68 167.78,87.78 167.78,88.24 168.04,88.51 168.48,88.51 168.74,88.24 168.74,87.78 168.84,87.68 169.05,87.68 169.15,87.78 169.15,88.24 169.41,88.51 169.85,88.51 170.11,88.24 170.11,87.78 170.21,87.68 170.42,87.68 170.52,87.78 170.52,88.24 170.78,88.51 171.22,88.51 171.48,88.24 171.48,87.78 171.59,87.68 171.79,87.68 171.89,87.78 171.89,88.24 172.16,88.51 172.59,88.51 172.86,88.24 172.86,87.78 172.96,87.68 173.16,87.68 173.26,87.78 173.26,88.24 173.53,88.51 174.91,88.51 176.94,86.47 178.77,86.47 178.91,86.33 193.08,86.33 193.72,86.97 199.34,86.97 202.82,83.49 202.82,81.66 202.97,81.51 202.97,81.45 202.97,81.45 202.97,81.09 202.83,80.95 v1(202.83,80.66)
DB14P: length 135.5
  TOP w0.114: J4.74 200.09,81.05 201.53,81.05 201.54,81.06 202.35,81.06 v1(202.57,81.28) ; U5.R11 v2(110.95,83.2)
  L10-SIG4 w0.102: v1(202.57,81.28) 202.56,81.52 202.54,81.55 202.54,83.38 199.23,86.69 193.83,86.69 193.2,86.06 178.79,86.06 178.66,86.19 178.45,86.19 178.35,86.09 178.35,86.06 178.25,85.95 178.05,85.95 177.95,86.06 177.95,86.09 177.84,86.19 176.83,86.19 174.79,88.23 173.64,88.23 173.54,88.13 173.54,87.67 173.28,87.4 172.84,87.4 172.58,87.67 172.58,88.13 172.47,88.23 172.27,88.23 172.17,88.13 172.17,87.67 171.9,87.4 171.47,87.4 171.2,87.67 171.2,88.13 171.1,88.23 170.9,88.23 170.8,88.13 170.8,87.67 170.53,87.4 170.1,87.4 169.83,87.67 169.83,88.13 169.73,88.23 169.53,88.23 169.43,88.13 169.43,87.67 169.16,87.4 168.73,87.4 168.46,87.67 168.46,88.13 168.36,88.23 168.16,88.23 168.05,88.13 168.05,87.67 167.79,87.4 167.35,87.4 167.09,87.67 167.09,88.13 166.99,88.23 166.78,88.23 166.68,88.13 166.68,87.67 166.42,87.4 165.98,87.4 165.72,87.67 165.72,88.13 165.62,88.23 165.41,88.23 165.31,88.13 165.31,87.67 165.05,87.4 164.61,87.4 164.35,87.67 164.35,88.13 164.24,88.23 164.04,88.23 163.94,88.13 163.94,87.67 163.67,87.4 163.24,87.4 162.97,87.67 162.97,88.13 162.87,88.23 162.67,88.23 162.57,88.13 162.57,87.67 162.3,87.4 161.87,87.4 161.6,87.67 161.6,88.13 161.5,88.23 161.3,88.23 161.2,88.13 161.2,87.67 160.93,87.4 160.5,87.4 160.23,87.67 160.23,88.13 160.13,88.23 158.9,88.23 158.64,88.49 158.64,89.13 158.53,89.23 158.33,89.23 158.23,89.13 158.23,88.49 157.96,88.23 157.53,88.23 157.26,88.49 157.26,89.13 157.16,89.23 156.96,89.23 156.86,89.13 156.86,88.49 156.59,88.23 156.16,88.23 155.89,88.49 155.89,89.13 155.79,89.23 155.59,89.23 155.49,89.13 155.49,88.49 155.22,88.23 154.79,88.23 154.52,88.49 154.52,89.13 154.42,89.23 154.22,89.23 154.11,89.13 154.11,88.49 153.85,88.23 153.41,88.23 153.15,88.49 153.15,89.13 153.05,89.23 152.84,89.23 152.74,89.13 152.74,88.49 152.48,88.23 152.04,88.23 151.78,88.49 151.78,89.13 151.68,89.23 151.47,89.23 151.37,89.13 151.37,88.49 151.11,88.23 150.67,88.23 150.41,88.49 150.41,89.13 150.3,89.23 150.1,89.23 150,89.13 150,88.49 149.73,88.23 149.3,88.23 149.03,88.49 149.03,89.13 148.93,89.23 148.73,89.23 148.63,89.13 148.63,88.49 148.36,88.23 147.93,88.23 147.66,88.49 147.66,89.13 147.56,89.23 147.36,89.23 147.26,89.13 147.26,88.49 146.99,88.23 146.56,88.23 146.29,88.49 146.29,89.13 146.19,89.23 145.99,89.23 145.88,89.13 145.88,88.49 145.62,88.23 145.18,88.23 144.92,88.49 144.92,89.13 144.82,89.23 144.61,89.23 144.51,89.13 144.51,88.49 144.25,88.23 143.81,88.23 143.55,88.49 143.55,89.13 143.45,89.23 143.24,89.23 143.14,89.13 143.14,88.49 142.88,88.23 142.44,88.23 142.18,88.49 142.18,89.13 142.07,89.23 141.87,89.23 141.77,89.13 141.77,88.49 141.67,88.39 141.5,88.23 140.7,88.23 139.5,87.02 134.47,87.02 133.02,85.57 129.15,85.57 128.73,85.16 125.28,85.16 125.18,85.26 125.18,85.32 125.03,85.47 123.02,85.47 122.12,84.57 121.12,84.57 121.11,84.58 120.79,84.58 120.78,84.57 119.12,84.57 119.11,84.58 118.79,84.58 118.78,84.57 118.12,84.57 118.11,84.58 117.79,84.58 117.78,84.57 117.12,84.57 117.11,84.58 116.79,84.58 116.78,84.57 116.12,84.57 116.11,84.58 115.79,84.58 115.78,84.57 115.12,84.57 115.11,84.58 114.79,84.58 114.78,84.57 114.12,84.57 114.11,84.58 113.79,84.58 113.78,84.57 113.12,84.57 113.11,84.58 112.79,84.58 112.78,84.57 112.12,84.57 112.11,84.58 111.79,84.58 111.78,84.57 111.67,84.57 111.58,84.48 111.57,84.48 111.48,84.39 111.48,84.18 110.95,83.64 v2(110.95,83.2)
DB15N: length 135.3
  TOP w0.114: U5.U10 v2(108.95,84.2) ; J4.70 200.02,82.17 200.08,82.23 201.57,82.23 201.58,82.24 201.6,82.24 v1(201.8,82.03)
  L10-SIG4 w0.102: v1(201.8,82.03) 201.72,82.03 201.68,82.07 201.6,82.07 200.18,83.49 200.18,83.76 198.24,85.7 195.67,85.7 194.88,84.91 172.21,84.91 172.1,85.01 172.1,85.04 172,85.14 171.8,85.14 171.7,85.04 171.7,85.01 171.6,84.91 171.39,84.91 171.29,85.01 171.29,85.04 171.19,85.14 170.99,85.14 170.89,85.04 170.89,85.01 170.78,84.91 170.15,84.91 170.07,85 170.07,85.15 169.81,85.42 169.37,85.42 169.11,85.15 169.11,84.51 169,84.4 168.8,84.4 168.7,84.51 168.7,85.15 168.43,85.42 168,85.42 167.73,85.15 167.73,84.51 167.63,84.4 167.43,84.4 167.33,84.51 167.33,85.15 167.06,85.42 166.63,85.42 166.36,85.15 166.36,84.51 166.26,84.4 166.06,84.4 165.96,84.51 165.96,85.15 165.69,85.42 165.26,85.42 164.99,85.15 164.99,84.51 164.89,84.4 164.69,84.4 164.58,84.51 164.58,85.15 164.32,85.42 163.88,85.42 163.62,85.15 163.62,84.51 163.52,84.4 163.31,84.4 163.21,84.51 163.21,85.15 162.95,85.42 162.51,85.42 162.25,85.15 162.25,84.51 162.15,84.4 161.94,84.4 161.84,84.51 161.84,85.15 161.58,85.42 161.14,85.42 160.88,85.15 160.88,84.51 160.77,84.4 160.57,84.4 160.47,84.51 160.47,85.15 160.2,85.42 159.77,85.42 159.5,85.15 159.5,84.51 159.4,84.4 159.2,84.4 159.1,84.51 159.1,85.15 158.83,85.42 158.4,85.42 158.13,85.15 158.13,84.51 158.03,84.4 157.83,84.4 157.73,84.51 157.73,85.15 157.46,85.42 157.03,85.42 156.76,85.15 156.76,84.51 156.66,84.4 156.46,84.4 156.35,84.51 156.35,85.15 156.09,85.42 155.65,85.42 155.39,85.15 155.39,84.51 155.29,84.4 155.08,84.4 154.98,84.51 154.98,85.15 154.72,85.42 154.28,85.42 154.02,85.15 154.02,84.51 153.92,84.4 153.71,84.4 153.61,84.51 153.61,85.15 153.35,85.42 152.91,85.42 152.65,85.15 152.65,84.51 152.54,84.4 152.34,84.4 152.24,84.51 152.24,85.15 151.97,85.42 151.54,85.42 151.27,85.15 151.27,84.51 151.17,84.4 150.97,84.4 150.87,84.51 150.87,85.15 150.6,85.42 150.17,85.42 149.9,85.15 149.9,84.51 149.8,84.4 149.6,84.4 149.5,84.51 149.5,85.15 149.23,85.42 148.8,85.42 148.53,85.15 148.53,84.51 148.43,84.4 148.23,84.4 148.12,84.51 148.12,85.15 147.86,85.42 147.42,85.42 147.16,85.15 147.16,84.51 147.06,84.4 146.85,84.4 146.75,84.51 146.75,85.15 146.49,85.42 146.05,85.42 145.79,85.15 145.79,84.51 145.69,84.4 145.48,84.4 145.38,84.51 145.38,85.15 145.12,85.42 144.68,85.42 144.42,85.15 144.42,84.51 144.31,84.4 144.11,84.4 144.01,84.51 144.01,85.15 143.74,85.42 143.31,85.42 143.04,85.15 143.04,84.51 142.94,84.4 142.74,84.4 142.64,84.51 142.64,85.15 142.37,85.42 141.94,85.42 141.67,85.15 141.67,84.51 141.57,84.4 141.37,84.4 141.27,84.51 141.27,84.65 141,84.91 129.49,84.91 128.44,83.86 125.3,83.86 125.26,83.82 111.68,83.82 111.33,83.47 111.33,82.94 111.34,82.93 111.34,82.47 111.33,82.46 111.33,81.97 111.18,81.82 111.11,81.82 111.11,81.82 110.79,81.82 110.79,81.82 110.71,81.82 110.57,81.96 110.57,82.46 110.49,82.54 110.49,83.36 110.17,83.69 109.45,83.69 108.95,84.19 v2(108.95,84.2)
DB15P: length 135.3
  TOP w0.114: J4.68 200.13,82.51 201.46,82.51 v1(201.8,82.85) ; U5.T11 v2(109.95,83.2)
  L10-SIG4 w0.102: v1(201.8,82.85) 201.8,82.63 202.21,82.22 202.21,81.81 202.02,81.62 201.59,81.62 201.28,81.93 201.28,81.99 199.9,83.37 199.9,83.64 198.12,85.42 195.78,85.42 195,84.63 170.03,84.63 169.79,84.87 169.79,85.04 169.69,85.14 169.49,85.14 169.38,85.04 169.38,84.29 169.21,84.12 168.58,84.12 168.42,84.29 168.42,85.04 168.32,85.14 168.11,85.14 168.01,85.04 168.01,84.39 167.75,84.12 167.31,84.12 167.05,84.39 167.05,85.04 166.95,85.14 166.74,85.14 166.64,85.04 166.64,84.39 166.38,84.12 165.94,84.12 165.68,84.39 165.68,85.04 165.57,85.14 165.37,85.14 165.27,85.04 165.27,84.39 165,84.12 164.57,84.12 164.3,84.39 164.3,85.04 164.2,85.14 164,85.14 163.9,85.04 163.9,84.39 163.63,84.12 163.2,84.12 162.93,84.39 162.93,85.04 162.83,85.14 162.63,85.14 162.53,85.04 162.53,84.39 162.26,84.12 161.83,84.12 161.56,84.39 161.56,85.04 161.46,85.14 161.26,85.14 161.15,85.04 161.15,84.39 160.89,84.12 160.46,84.12 160.19,84.39 160.19,85.04 160.09,85.14 159.88,85.14 159.78,85.04 159.78,84.39 159.52,84.12 159.08,84.12 158.82,84.39 158.82,85.04 158.72,85.14 158.51,85.14 158.41,85.04 158.41,84.39 158.15,84.12 157.71,84.12 157.45,84.39 157.45,85.04 157.34,85.14 157.14,85.14 157.04,85.04 157.04,84.39 156.77,84.12 156.34,84.12 156.07,84.39 156.07,85.04 155.97,85.14 155.77,85.14 155.67,85.04 155.67,84.39 155.4,84.12 154.97,84.12 154.7,84.39 154.7,85.04 154.6,85.14 154.4,85.14 154.3,85.04 154.3,84.39 154.03,84.12 153.6,84.12 153.33,84.39 153.33,85.04 153.23,85.14 153.03,85.14 152.93,85.04 152.93,84.39 152.66,84.12 152.23,84.12 151.96,84.39 151.96,85.04 151.86,85.14 151.66,85.14 151.55,85.04 151.55,84.39 151.29,84.12 150.85,84.12 150.59,84.39 150.59,85.04 150.49,85.14 150.28,85.14 150.18,85.04 150.18,84.39 149.92,84.12 149.48,84.12 149.22,84.39 149.22,85.04 149.12,85.14 148.91,85.14 148.81,85.04 148.81,84.39 148.55,84.12 148.11,84.12 147.85,84.39 147.85,85.04 147.74,85.14 147.54,85.14 147.44,85.04 147.44,84.39 147.17,84.12 146.74,84.12 146.47,84.39 146.47,85.04 146.37,85.14 146.17,85.14 146.07,85.04 146.07,84.39 145.8,84.12 145.37,84.12 145.1,84.39 145.1,85.04 145,85.14 144.8,85.14 144.7,85.04 144.7,84.39 144.43,84.12 144,84.12 143.73,84.39 143.73,85.04 143.63,85.14 143.43,85.14 143.32,85.04 143.32,84.39 143.06,84.12 142.62,84.12 142.36,84.39 142.36,85.04 142.26,85.14 142.05,85.14 141.95,85.04 141.95,84.39 141.69,84.12 141.25,84.12 140.99,84.39 140.99,84.53 140.89,84.63 129.6,84.63 128.55,83.58 111.78,83.58 111.57,83.37 111.57,83.04 111.58,83.03 111.58,82.37 111.57,82.36 111.57,81.88 111.28,81.58 111.21,81.58 111.21,81.58 110.69,81.58 110.69,81.58 110.61,81.58 110.33,81.86 110.33,82.06 110.33,82.36 110.21,82.48 110.21,82.93 109.95,83.19 v2(109.95,83.2)
DBCLKN: length 135.4
  TOP w0.114: J4.39 192.84,94.67 v1(192.66,94.49) ; U5.U9 v2(108.95,85.2)
  L9-SIG3 w0.102: v1(192.66,94.49) 192.67,94.5 192.84,94.5 192.92,94.59 196.86,94.59 197.62,93.83 202.67,93.83 204.09,95.25 204.09,101.6 202.01,103.68 199.86,103.68 194.04,109.5 134.21,109.5 133.22,110.49 126.22,110.49 113.77,98.03 113.77,97.4 110.61,94.24 109.99,94.24 109.33,93.58 109.33,86.04 109.29,86 109.29,85.54 v2(108.95,85.2)
DBCLKP: length 135.3
  TOP w0.114: J4.37 192.74,95.17 v1(192.66,95.25) ; U5.T9 v2(109.95,85.2)
  L9-SIG3 w0.102: v1(192.66,95.25) 193.04,94.87 196.98,94.87 197.74,94.11 202.55,94.11 203.81,95.37 203.81,101.48 201.89,103.4 199.75,103.4 193.93,109.22 137.25,109.22 137.15,109.12 137.15,108.94 137.04,108.84 136.84,108.84 136.74,108.94 136.74,109.12 136.64,109.22 136.44,109.22 136.33,109.12 136.33,108.94 136.23,108.84 136.03,108.84 135.93,108.94 135.93,109.12 135.83,109.22 134.1,109.22 133.11,110.21 126.34,110.21 114.05,97.92 114.05,97.28 110.73,93.96 110.11,93.96 110.05,93.91 109.99,93.91 109.57,93.48 109.57,85.94 109.52,85.9 109.52,85.63 v2(109.95,85.2)
DCLK: length 97.2
  TOP w0.178: R126.2 120.4,53.72 120.4,52.96 v1(121.67,51.69) ; v1(93.85,94.49) 95.5,96.14 95.5,102.62 96.9,104.01 96.9,107.06 95.89,108.08 U19.16 95.9,109.5 DN2.1 97.98,110.81 C353.1
  TOP w0.254: U5.AM3 v2(92.95,91.2)
  L9-SIG3 w0.102: v2(92.95,91.2) 93.47,91.72 93.47,93.6 93.85,93.98 93.85,94.11
  L9-SIG3 w0.178: 93.85,94.11 v1(93.85,94.49)
  L10-SIG4 w0.102: 99.44,58.29 99.44,63.37 98.55,64.26 98.55,66.42 98.93,66.8 99.19,66.8 99.44,67.06 99.44,67.44 99.69,67.69 100.33,67.69 100.46,67.82 100.46,69.47 100.71,69.72 100.71,70.9 100.57,71.04 100.57,71.36 100.71,71.5 100.71,72.52 101.98,73.79 101.98,80.26 101.47,80.77 101.47,82.42 101.22,82.68 100.71,82.68 100.46,82.93 100.46,87.5 100.2,87.76 93.6,87.76 93.47,87.88 93.47,90.04 92.95,90.56 v2(92.95,91.2)
  L10-SIG4 w0.178: v1(121.67,51.69) 118.87,54.48 101.85,54.48 100.58,55.75 100.58,57.15 99.44,58.29
DCLK_M: length 118.6
  TOP w0.114: U5.AA6 v2(103.95,88.2)
  L3-SIG1 w0.102: v1(111.57,147.83) 111.57,147.89 111.23,148.23 110.59,148.23 110.19,147.83 108.88,147.83 106.83,145.78 106.83,141.58 109.04,139.37 109.04,137.77 109.54,137.28 109.69,137.28 109.8,137.16 109.8,136.96 109.72,136.87 109.31,136.87 109.04,136.6 109.04,136.17 109.31,135.9 110.06,135.9 110.16,135.8 110.16,135.6 110.06,135.5 109.31,135.5 109.04,135.23 109.04,134.8 109.31,134.53 110.06,134.53 110.16,134.43 110.16,134.23 110.06,134.13 109.31,134.13 109.04,133.86 109.04,133.43 109.31,133.16 110.06,133.16 110.16,133.06 110.16,132.86 110.06,132.76 109.31,132.76 109.04,132.49 109.04,132.06 109.31,131.79 110.06,131.79 110.16,131.69 110.16,131.49 110.06,131.38 109.31,131.38 109.04,131.12 109.04,130.68 109.31,130.42 110.06,130.42 110.16,130.32 110.16,130.11 110.06,130.01 109.31,130.01 109.04,129.75 109.04,129.31 109.31,129.05 110.06,129.05 110.16,128.95 110.16,128.74 110.06,128.64 109.31,128.64 109.04,128.38 109.04,127.94 109.31,127.68 110.06,127.68 110.16,127.57 110.16,127.37 110.06,127.27 109.31,127.27 109.04,127 109.04,126.57 109.31,126.3 110.06,126.3 110.16,126.2 110.16,126 110.06,125.9 109.31,125.9 109.04,125.63 109.04,125.2 109.31,124.93 110.06,124.93 110.16,124.83 110.16,124.63 110.06,124.53 109.31,124.53 109.04,124.26 109.04,123.83 109.31,123.56 110.06,123.56 110.16,123.46 110.16,123.26 110.06,123.15 109.31,123.15 109.04,122.89 109.04,122.45 109.31,122.19 110.06,122.19 110.16,122.09 110.16,121.88 110.06,121.78 109.31,121.78 109.04,121.52 109.04,121.08 109.31,120.82 110.06,120.82 110.16,120.72 110.16,120.51 110.06,120.41 109.31,120.41 109.04,120.15 109.04,119.71 109.31,119.45 110.06,119.45 110.16,119.34 110.16,119.14 110.06,119.04 109.31,119.04 109.04,118.77 109.04,118.34 109.31,118.07 110.06,118.07 110.16,117.97 110.16,117.77 110.06,117.67 109.31,117.67 109.04,117.4 109.04,116.97 109.31,116.7 110.06,116.7 110.16,116.6 110.16,116.4 110.06,116.3 109.31,116.3 109.04,116.03 109.04,115.6 109.31,115.33 110.06,115.33 110.16,115.23 110.16,115.03 110.06,114.92 109.31,114.92 109.04,114.66 109.04,114.22 109.31,113.96 110.06,113.96 110.16,113.86 110.16,113.65 110.06,113.55 109.31,113.55 109.04,113.29 109.04,112.85 109.31,112.59 110.06,112.59 110.16,112.49 110.16,112.28 110.06,112.18 109.31,112.18 109.04,111.92 109.04,111.48 109.31,111.22 110.06,111.22 110.16,111.11 110.16,110.91 110.06,110.81 109.31,110.81 109.04,110.54 109.04,110.11 109.31,109.84 110.06,109.84 110.16,109.74 110.16,109.54 110.06,109.44 109.31,109.44 109.04,109.17 109.04,108.74 109.31,108.47 110.06,108.47 110.16,108.37 110.16,108.17 110.06,108.07 109.31,108.07 109.04,107.8 109.04,107.37 109.31,107.1 110.06,107.1 110.16,107 110.16,106.8 110.06,106.69 109.31,106.69 109.04,106.43 109.04,105.99 109.31,105.73 110.06,105.73 110.16,105.63 110.16,105.42 110.06,105.32 109.31,105.32 109.04,105.06 109.04,104.62 109.31,104.36 110.06,104.36 110.16,104.26 110.16,104.05 110.06,103.95 109.31,103.95 109.04,103.69 109.04,103.25 109.31,102.99 110.06,102.99 110.16,102.88 110.16,102.68 110.06,102.58 109.31,102.58 109.04,102.31 109.04,101.88 109.31,101.61 110.06,101.61 110.16,101.51 110.16,101.31 110.06,101.21 109.31,101.21 109.04,100.94 109.04,100.39 107.92,99.28 107.92,98.54 106.81,97.42 106.81,96.85 104.63,94.67 104.63,94.16 104.33,93.87 104.33,87.92 104.22,87.81 104.04,87.81 103.96,87.88 103.96,88.19 v2(103.95,88.2)
  BOTTOM w0.114: R54.1 103.86,88.11 v2(103.95,88.2) ; v1(111.57,147.83) 111.51,147.89 111.51,149.88 J3.56
DCLK_P: length 118.4
  TOP w0.114: U5.AA7 v2(103.95,87.2)
  L3-SIG1 w0.102: v1(110.81,147.83) 110.79,147.83 110.52,147.55 108.99,147.55 107.11,145.67 107.11,141.7 109.32,139.49 109.32,137.9 109.66,137.56 110.17,137.56 110.44,137.29 110.44,136.86 110.17,136.59 109.42,136.59 109.32,136.49 109.32,136.29 109.42,136.18 110.17,136.18 110.44,135.92 110.44,135.48 110.17,135.22 109.42,135.22 109.32,135.12 109.32,134.91 109.42,134.81 110.17,134.81 110.44,134.55 110.44,134.11 110.17,133.85 109.42,133.85 109.32,133.75 109.32,133.54 109.42,133.44 110.17,133.44 110.44,133.18 110.44,132.74 110.17,132.48 109.42,132.48 109.32,132.37 109.32,132.17 109.42,132.07 110.17,132.07 110.44,131.8 110.44,131.37 110.17,131.1 109.42,131.1 109.32,131 109.32,130.8 109.42,130.7 110.17,130.7 110.44,130.43 110.44,130 110.17,129.73 109.42,129.73 109.32,129.63 109.32,129.43 109.42,129.33 110.17,129.33 110.44,129.06 110.44,128.63 110.17,128.36 109.42,128.36 109.32,128.26 109.32,128.06 109.42,127.95 110.17,127.95 110.44,127.69 110.44,127.25 110.17,126.99 109.42,126.99 109.32,126.89 109.32,126.68 109.42,126.58 110.17,126.58 110.44,126.32 110.44,125.88 110.17,125.62 109.42,125.62 109.32,125.52 109.32,125.31 109.42,125.21 110.17,125.21 110.44,124.95 110.44,124.51 110.17,124.25 109.42,124.25 109.32,124.14 109.32,123.94 109.42,123.84 110.17,123.84 110.44,123.57 110.44,123.14 110.17,122.87 109.42,122.87 109.32,122.77 109.32,122.57 109.42,122.47 110.17,122.47 110.44,122.2 110.44,121.77 110.17,121.5 109.42,121.5 109.32,121.4 109.32,121.2 109.42,121.1 110.17,121.1 110.44,120.83 110.44,120.4 110.17,120.13 109.42,120.13 109.32,120.03 109.32,119.83 109.42,119.72 110.17,119.72 110.44,119.46 110.44,119.03 110.17,118.76 109.42,118.76 109.32,118.66 109.32,118.45 109.42,118.35 110.17,118.35 110.44,118.09 110.44,117.65 110.17,117.39 109.42,117.39 109.32,117.29 109.32,117.08 109.42,116.98 110.17,116.98 110.44,116.72 110.44,116.28 110.17,116.02 109.42,116.02 109.32,115.91 109.32,115.71 109.42,115.61 110.17,115.61 110.44,115.34 110.44,114.91 110.17,114.64 109.42,114.64 109.32,114.54 109.32,114.34 109.42,114.24 110.17,114.24 110.44,113.97 110.44,113.54 110.17,113.27 109.42,113.27 109.32,113.17 109.32,112.97 109.42,112.87 110.17,112.87 110.44,112.6 110.44,112.17 110.17,111.9 109.42,111.9 109.32,111.8 109.32,111.6 109.42,111.5 110.17,111.5 110.44,111.23 110.44,110.8 110.17,110.53 109.42,110.53 109.32,110.43 109.32,110.23 109.42,110.12 110.17,110.12 110.44,109.86 110.44,109.42 110.17,109.16 109.42,109.16 109.32,109.06 109.32,108.85 109.42,108.75 110.17,108.75 110.44,108.49 110.44,108.05 110.17,107.79 109.42,107.79 109.32,107.69 109.32,107.48 109.42,107.38 110.17,107.38 110.44,107.12 110.44,106.68 110.17,106.42 109.42,106.42 109.32,106.31 109.32,106.11 109.42,106.01 110.17,106.01 110.44,105.74 110.44,105.31 110.17,105.04 109.42,105.04 109.32,104.94 109.32,104.74 109.42,104.64 110.17,104.64 110.44,104.37 110.44,103.94 110.17,103.67 109.42,103.67 109.32,103.57 109.32,103.37 109.42,103.27 110.17,103.27 110.44,103 110.44,102.57 110.17,102.3 109.42,102.3 109.32,102.2 109.32,102 109.42,101.89 110.17,101.89 110.44,101.63 110.44,101.19 110.17,100.93 109.42,100.93 109.32,100.83 109.32,100.28 108.2,99.16 108.2,98.42 107.09,97.31 107.09,96.73 104.91,94.55 104.91,94.05 104.8,93.94 104.74,93.94 104.57,93.77 104.57,87.82 v2(103.95,87.2)
  BOTTOM w0.114: v2(103.95,87.2) 103.75,87.4 R54.2 ; J3.58 111,149.88 111,148.82 111.23,148.59 111.23,148.08 110.97,147.83 v1(110.81,147.83)
DDR2_A0: length 82.2
  TOP w0.165: U5.AE24 v2(99.95,69.21) ; RN12.6 53.27,79.12 53.59,78.8 53.59,78.56 55.08,77.08 J6.102 v1(57.52,77.08)
  L4-SIG2 w0.102: 99.71,76.31 99.95,76.07 99.95,75.82 99.57,75.44 99.57,74.8 100.2,74.17 ; v2(99.95,69.21) 99.97,69.22 ; 95.57,75.95 96.49,75.95 96.62,75.82 97.11,75.82 97.13,75.83
  L4-SIG2 w0.114: 99.97,69.22 100.2,69.45 100.2,69.94 100.09,70.05 100.06,70.05 99.95,70.17 99.95,70.4 100.06,70.51 100.34,70.51 100.46,70.62 100.46,70.85 100.34,70.97 100.06,70.97 99.95,71.08 99.95,71.31 100.06,71.42 100.34,71.42 100.46,71.54 100.46,71.77 100.34,71.88 100.06,71.88 99.95,72 99.95,72.22 100.06,72.34 100.34,72.34 100.46,72.45 100.46,72.68 100.34,72.8 100.06,72.8 99.95,72.91 99.95,73.14 100.06,73.25 100.34,73.25 100.46,73.37 100.46,73.6 100.34,73.71 100.32,73.71 100.2,73.82 100.2,74.17 ; 95.57,75.95 94.74,75.95 94.36,76.33 92.86,76.33 92.35,76.83 90.12,76.83 89.87,77.09 82.93,77.09 82.19,76.35 81.57,76.35 81.38,76.54 81.11,76.54 80.92,76.35 80.66,76.35 80.47,76.54 80.2,76.54 80.01,76.35 79.74,76.35 79.55,76.54 79.29,76.54 79.1,76.35 78.83,76.35 78.64,76.54 78.37,76.54 78.18,76.35 77.91,76.35 77.72,76.54 77.46,76.54 77.27,76.35 77,76.35 76.81,76.54 76.54,76.54 76.35,76.35 75.46,76.35 75.31,76.2 73.81,76.2 73.25,76.76 72.73,76.76 72.53,76.57 72.27,76.57 72.17,76.66 72.17,76.85 72.08,76.95 71.81,76.95 71.72,76.85 71.72,76.66 71.62,76.57 71.35,76.57 71.26,76.66 71.26,76.85 71.16,76.95 70.9,76.95 70.8,76.85 70.8,76.66 70.71,76.57 70.44,76.57 70.25,76.76 69.93,76.76 69.43,77.25 69.14,77.25 69.03,77.15 69.03,76.93 68.92,76.82 68.68,76.82 68.57,76.93 68.57,77.15 68.47,77.25 68.22,77.25 68.12,77.15 68.12,76.93 68.01,76.82 67.77,76.82 67.55,77.04 67.49,77.04 67.31,77.22 66.65,77.22 66.51,77.08 65.92,77.08 65.66,77.34 65.42,77.34 65.15,77.08 64.88,77.08 64.76,77.19 64.76,77.61 64.65,77.72 64.42,77.72 64.31,77.61 64.31,77.19 64.19,77.08 63.96,77.08 63.85,77.19 63.85,77.61 63.73,77.72 63.51,77.72 63.39,77.61 63.39,77.19 63.28,77.08 62.75,77.08 62.61,77.22 62.24,77.22 62.1,77.08 61.8,77.08 61.69,77.19 61.69,77.61 61.58,77.72 61.35,77.72 61.23,77.61 61.23,77.19 61.12,77.08 60.35,77.08 60.23,77.19 60.23,77.23 60.12,77.34 59.89,77.34 59.77,77.23 59.77,77.19 59.66,77.08 59.43,77.08 59.32,77.19 59.32,77.23 59.2,77.34 58.97,77.34 58.86,77.23 58.86,77.19 58.75,77.08 58.16,77.08 57.66,76.58 56.13,76.58 55.94,76.39 55.94,76.01 55.75,75.82 55.56,75.82 55.45,75.93 55.45,76.59 55.33,76.71 55.11,76.71 54.99,76.59 54.99,75.93 54.88,75.82 54.65,75.82 54.53,75.93 54.53,76.59 54.42,76.71 54.19,76.71 54.08,76.59 54.08,75.93 53.96,75.82 53.72,75.82 53.47,76.07 53.47,76.83 53.68,77.05 57.49,77.05 v1(57.52,77.08) ; 97.13,75.83 97.5,76.2 97.74,76.2 97.85,76.09 97.85,76.06 97.97,75.95 98.2,75.95 98.31,76.06 98.31,76.34 98.42,76.45 98.65,76.45 99.03,76.07 99.21,76.07 99.45,76.31 99.71,76.31
DDR2_A1: length 82.3
  TOP w0.165: J6.101 v1(66.93,76.78) ; v1(52.95,76.58) 52.95,76.58 RN13.7 ; U5.AF23 v2(98.96,70.21)
  L10-SIG4 w0.102: 90.37,76.15 96.27,76.15 96.6,75.82 97.26,75.82 97.56,76.12 99.9,76.12 100.46,75.56 100.46,75.06 100.08,74.68 96.77,74.68 96.52,74.42 96.52,73.91 96.7,73.74 98.27,73.74 98.65,73.36 98.65,72.72 98.15,72.21 97.61,72.21 97.23,72.59 95.55,72.59 95.41,72.45 95.41,72.31 95.53,72.19 96.42,72.19 96.54,72.07 96.54,71.93 96.39,71.78 94.67,71.78 94.36,71.48 94.36,71.25 94.79,70.82 98.35,70.82 v2(98.96,70.21)
  L10-SIG4 w0.114: 90.37,76.15 89.94,76.58 86.87,76.58 86.67,76.78 84.4,76.78 83.41,75.79 82.42,75.79 82.29,75.92 77.11,75.92 75.91,77.12 73.47,77.12 73.36,77.24 73.36,77.39 73.24,77.51 73.02,77.51 72.9,77.39 72.9,76.85 72.79,76.73 72.56,76.73 72.44,76.85 72.44,77.39 72.33,77.51 72.1,77.51 71.99,77.39 71.99,76.85 71.87,76.73 71.64,76.73 71.53,76.85 71.53,77.39 71.42,77.51 71.19,77.51 71.07,77.39 71.07,76.85 70.96,76.73 70.73,76.73 70.61,76.85 70.61,77.39 70.5,77.51 70.27,77.51 70.16,77.39 70.16,76.85 70.04,76.73 69.81,76.73 69.7,76.85 69.7,77.39 69.59,77.51 69.36,77.51 69.24,77.39 69.24,76.85 69.13,76.73 68.9,76.73 68.79,76.85 68.79,77.39 68.67,77.51 68.44,77.51 68.33,77.39 68.33,76.85 68.21,76.73 67.99,76.73 67.87,76.85 67.87,77.01 67.76,77.12 67.27,77.12 v1(66.93,76.78)
  BOTTOM w0.165: v1(52.95,76.58) 57.78,76.58 58.17,76.96 58.8,76.96 58.98,76.78 v1(66.93,76.78)
DDR2_A2: length 82.2
  TOP w0.165: v1(58.42,76.48) J6.100 54.2,76.48 53.61,77.08 RN13.8 ; U5.AF25 v2(98.95,68.21)
  L4-SIG2 w0.102: 97.79,75.59 96.11,75.59 ; 99.81,68.69 100.22,68.69 100.46,68.45 100.46,62.87 100.28,62.69 98.63,62.69 98.4,62.92 98.4,63.93 99.57,65.1 99.57,67.6 v2(98.95,68.21)
  L4-SIG2 w0.114: 96.11,75.59 94.61,75.59 94.26,75.95 92.15,75.95 91.64,76.45 91.06,76.45 90.81,76.2 89.99,76.2 89.39,76.8 89.15,76.8 88.93,76.58 88.69,76.58 88.47,76.8 88.23,76.8 88.02,76.58 87.78,76.58 87.56,76.8 87.32,76.8 87.1,76.58 86.86,76.58 86.65,76.8 86.4,76.8 86.19,76.58 85.95,76.58 85.73,76.8 85.49,76.8 85.27,76.58 85.03,76.58 84.82,76.8 84.58,76.8 84.36,76.58 83.92,76.58 83.13,75.79 81.91,75.79 81.73,75.97 81.46,75.97 81.36,75.88 81.36,75.7 81.27,75.6 81,75.6 80.91,75.7 80.91,75.88 80.81,75.97 80.54,75.97 80.45,75.88 80.45,75.7 80.36,75.6 80.08,75.6 79.99,75.7 79.99,75.88 79.9,75.97 79.63,75.97 79.53,75.88 79.53,75.7 79.44,75.6 79.17,75.6 79.08,75.7 79.08,75.88 78.99,75.97 78.71,75.97 78.62,75.88 78.62,75.7 78.53,75.6 78.25,75.6 78.16,75.7 78.16,75.88 78.07,75.97 77.8,75.97 77.71,75.88 77.71,75.7 77.61,75.6 77.34,75.6 77.25,75.7 77.25,75.88 77.16,75.97 76.88,75.97 76.7,75.79 76.3,75.79 75.87,75.36 75.39,75.36 75.13,75.62 73.48,75.62 73.03,76.07 72.63,76.07 72.47,75.92 72.17,75.92 72.09,76 72.09,76.15 72.02,76.23 71.71,76.23 71.64,76.15 71.64,76 71.56,75.92 71.26,75.92 71.18,76 71.18,76.15 71.1,76.23 70.8,76.23 70.72,76.15 70.72,76 70.65,75.92 70.34,75.92 70.26,76 70.26,76.15 70.19,76.23 69.88,76.23 69.73,76.07 69.37,76.07 68.96,76.48 67.25,76.48 67.11,76.34 66.75,76.34 66.47,76.62 65.59,76.62 65.46,76.48 64.81,76.48 64.6,76.68 64.35,76.68 64.25,76.58 64.25,76.38 64.15,76.28 63.89,76.28 63.79,76.38 63.79,76.58 63.69,76.68 63.43,76.68 63.33,76.58 63.33,76.38 63.23,76.28 62.98,76.28 62.88,76.38 62.88,76.58 62.77,76.68 62.52,76.68 62.42,76.58 62.42,76.38 62.32,76.28 62.06,76.28 61.96,76.38 61.96,76.58 61.86,76.68 61.6,76.68 61.5,76.58 61.5,76.38 61.4,76.28 61.15,76.28 61.05,76.38 61.05,76.58 60.95,76.68 60.69,76.68 60.59,76.58 60.59,76.38 60.49,76.28 60.23,76.28 60.13,76.38 60.13,76.58 60.03,76.68 59.78,76.68 59.67,76.58 59.67,76.38 59.57,76.28 59.32,76.28 59.12,76.48 v1(58.42,76.48) ; 99.81,68.69 99.44,69.06 99.44,71.59 99.33,71.7 98.92,71.7 98.81,71.82 98.81,72.04 98.92,72.16 99.33,72.16 99.44,72.27 99.44,72.5 99.33,72.62 98.92,72.62 98.81,72.73 98.81,72.96 98.92,73.07 99.33,73.07 99.44,73.19 99.44,74.3 98.93,74.8 98.93,75.06 99.19,75.31 99.19,75.44 99.04,75.59 98.83,75.59 98.68,75.44 98.45,75.44 98.3,75.59 97.79,75.59
DDR2_A3: length 82.3
  TOP w0.165: v1(65.78,76.18) 65.78,76.18 J6.99 ; U5.AF26 v2(98.95,67.21) ; RN13.5 v1(52.95,75.58)
  L3-SIG1 w0.102: v2(98.95,67.21) 98.35,67.82 97.66,67.82 97.41,68.07 97.41,68.45 97.66,68.71 101.98,68.71 102.23,68.96 102.23,69.47 101.98,69.72 97.66,69.72 97.41,69.98 97.41,70.36 97.66,70.61 102.11,70.61 102.36,70.87 102.36,71.5 102.11,71.75 98.68,71.75 98.42,72.01 98.42,72.99 98.53,73.09 98.83,73.09 98.93,73.2 98.93,73.4 98.83,73.5 98.53,73.5 98.42,73.6 98.42,74.68 98.93,75.18 v2(99.95,75.18)
  L10-SIG4 w0.102: 95.93,75.72 96.06,75.59 99.54,75.59 v2(99.95,75.18)
  L10-SIG4 w0.114: v1(65.78,76.18) 67.59,76.18 67.71,76.06 68.05,76.06 68.11,76.12 68.11,76.24 68.16,76.3 68.5,76.3 68.56,76.24 68.56,76.12 68.62,76.06 68.96,76.06 69.02,76.12 69.02,76.24 69.08,76.3 69.42,76.3 69.48,76.24 69.48,76.12 69.54,76.06 69.87,76.06 69.93,76.12 69.93,76.24 69.99,76.3 70.33,76.3 70.39,76.24 70.39,76.12 70.45,76.06 70.79,76.06 70.85,76.12 70.85,76.24 70.91,76.3 71.25,76.3 71.31,76.24 71.31,76.12 71.36,76.06 71.7,76.06 71.76,76.12 71.76,76.24 71.82,76.3 72.16,76.3 72.22,76.24 72.22,76.12 72.28,76.06 72.62,76.06 72.68,76.12 72.68,76.24 72.74,76.3 73.08,76.3 73.13,76.24 73.13,76.12 73.19,76.06 73.53,76.06 73.59,76.12 73.59,76.24 73.65,76.3 73.99,76.3 74.11,76.18 74.46,76.18 74.61,76.33 75.95,76.33 76.83,75.44 83.67,75.44 84.56,76.33 86.28,76.33 86.41,76.2 89.18,76.2 89.66,75.72 95.93,75.72
  BOTTOM w0.165: v1(52.95,75.58) 53.14,75.39 57.76,75.39 58.27,75.9 58.55,75.9 58.83,76.18 v1(65.78,76.18)
DDR2_A4: length 82.2
  TOP w0.165: v1(57.53,75.88) J6.98 53.67,75.88 53.47,76.08 RN13.6 ; U5.AF27 v2(98.95,66.21)
  L3-SIG1 w0.114: v1(85.98,66.67) 85.98,64.77 85.74,64.53 85.47,64.53 85.26,64.75 85.26,67.57 86.01,68.33 86.01,69.17 85.85,69.33 85.85,70.05 85.74,70.16 85.59,70.16 85.47,70.28 85.47,70.51 85.59,70.62 85.74,70.62 85.85,70.74 85.85,70.96 85.74,71.08 85.59,71.08 85.47,71.19 85.47,71.42 85.59,71.54 85.74,71.54 85.85,71.65 85.85,71.88 85.74,71.99 85.59,71.99 85.47,72.11 85.47,72.34 85.59,72.45 85.74,72.45 85.85,72.56 85.85,72.79 85.74,72.91 85.59,72.91 85.47,73.02 85.47,73.25 85.59,73.36 85.74,73.36 85.85,73.48 85.85,75.69 v1(85.98,75.82)
  L4-SIG2 w0.102: v2(98.95,66.21) 98.61,66.21 98.15,66.67 95.65,66.67 95.5,66.82 90.53,66.82 90.2,67.16
  L4-SIG2 w0.114: 90.2,67.16 87.96,67.16 87.78,66.98 86.84,66.98 86.54,66.67 v1(85.98,66.67) ; v1(57.53,75.88) 57.46,75.95 56.52,75.95 56.01,75.44 53.72,75.44 53.59,75.31 53.59,75.06 53.72,74.93 56.13,74.93 56.52,75.31 57.66,75.31 58.23,75.88 59.12,75.88 59.24,75.76 59.24,75.17 59.35,75.06 59.58,75.06 59.69,75.17 59.69,75.76 59.81,75.88 61.22,75.88 61.33,75.76 61.33,75.17 61.45,75.06 61.67,75.06 61.79,75.17 61.79,75.76 61.9,75.88 63.38,75.88 63.5,75.76 63.5,75.17 63.61,75.06 63.84,75.06 63.95,75.17 63.95,75.76 64.07,75.88 64.3,75.88 64.41,75.76 64.41,75.17 64.52,75.06 64.75,75.06 64.87,75.17 64.87,75.76 64.98,75.88 65.45,75.88 65.59,75.74 65.96,75.74 66.23,76.02 68.44,76.02 69.02,75.44 69.36,75.44 69.55,75.63 69.82,75.63 69.91,75.53 69.91,75.34 70.01,75.25 70.27,75.25 70.37,75.34 70.37,75.53 70.46,75.63 70.73,75.63 70.82,75.53 70.82,75.34 70.92,75.25 71.19,75.25 71.28,75.34 71.28,75.53 71.38,75.63 71.64,75.63 71.74,75.53 71.74,75.34 71.83,75.25 72.1,75.25 72.29,75.44 72.8,75.44 73.3,74.93 73.56,74.93 73.67,75.04 73.67,75.06 73.79,75.18 74.02,75.18 74.13,75.06 74.13,75.04 74.25,74.93 74.47,74.93 74.59,75.04 74.59,75.06 74.7,75.18 74.93,75.18 75.05,75.06 75.05,75.04 75.16,74.93 76.2,74.93 76.58,75.31 82.04,75.31 82.17,75.44 83.57,75.44 84.18,76.05 84.61,76.05 84.73,75.93 84.73,75.92 84.84,75.81 85.07,75.81 85.19,75.92 85.19,75.93 85.3,76.05 85.75,76.05 v1(85.98,75.82)
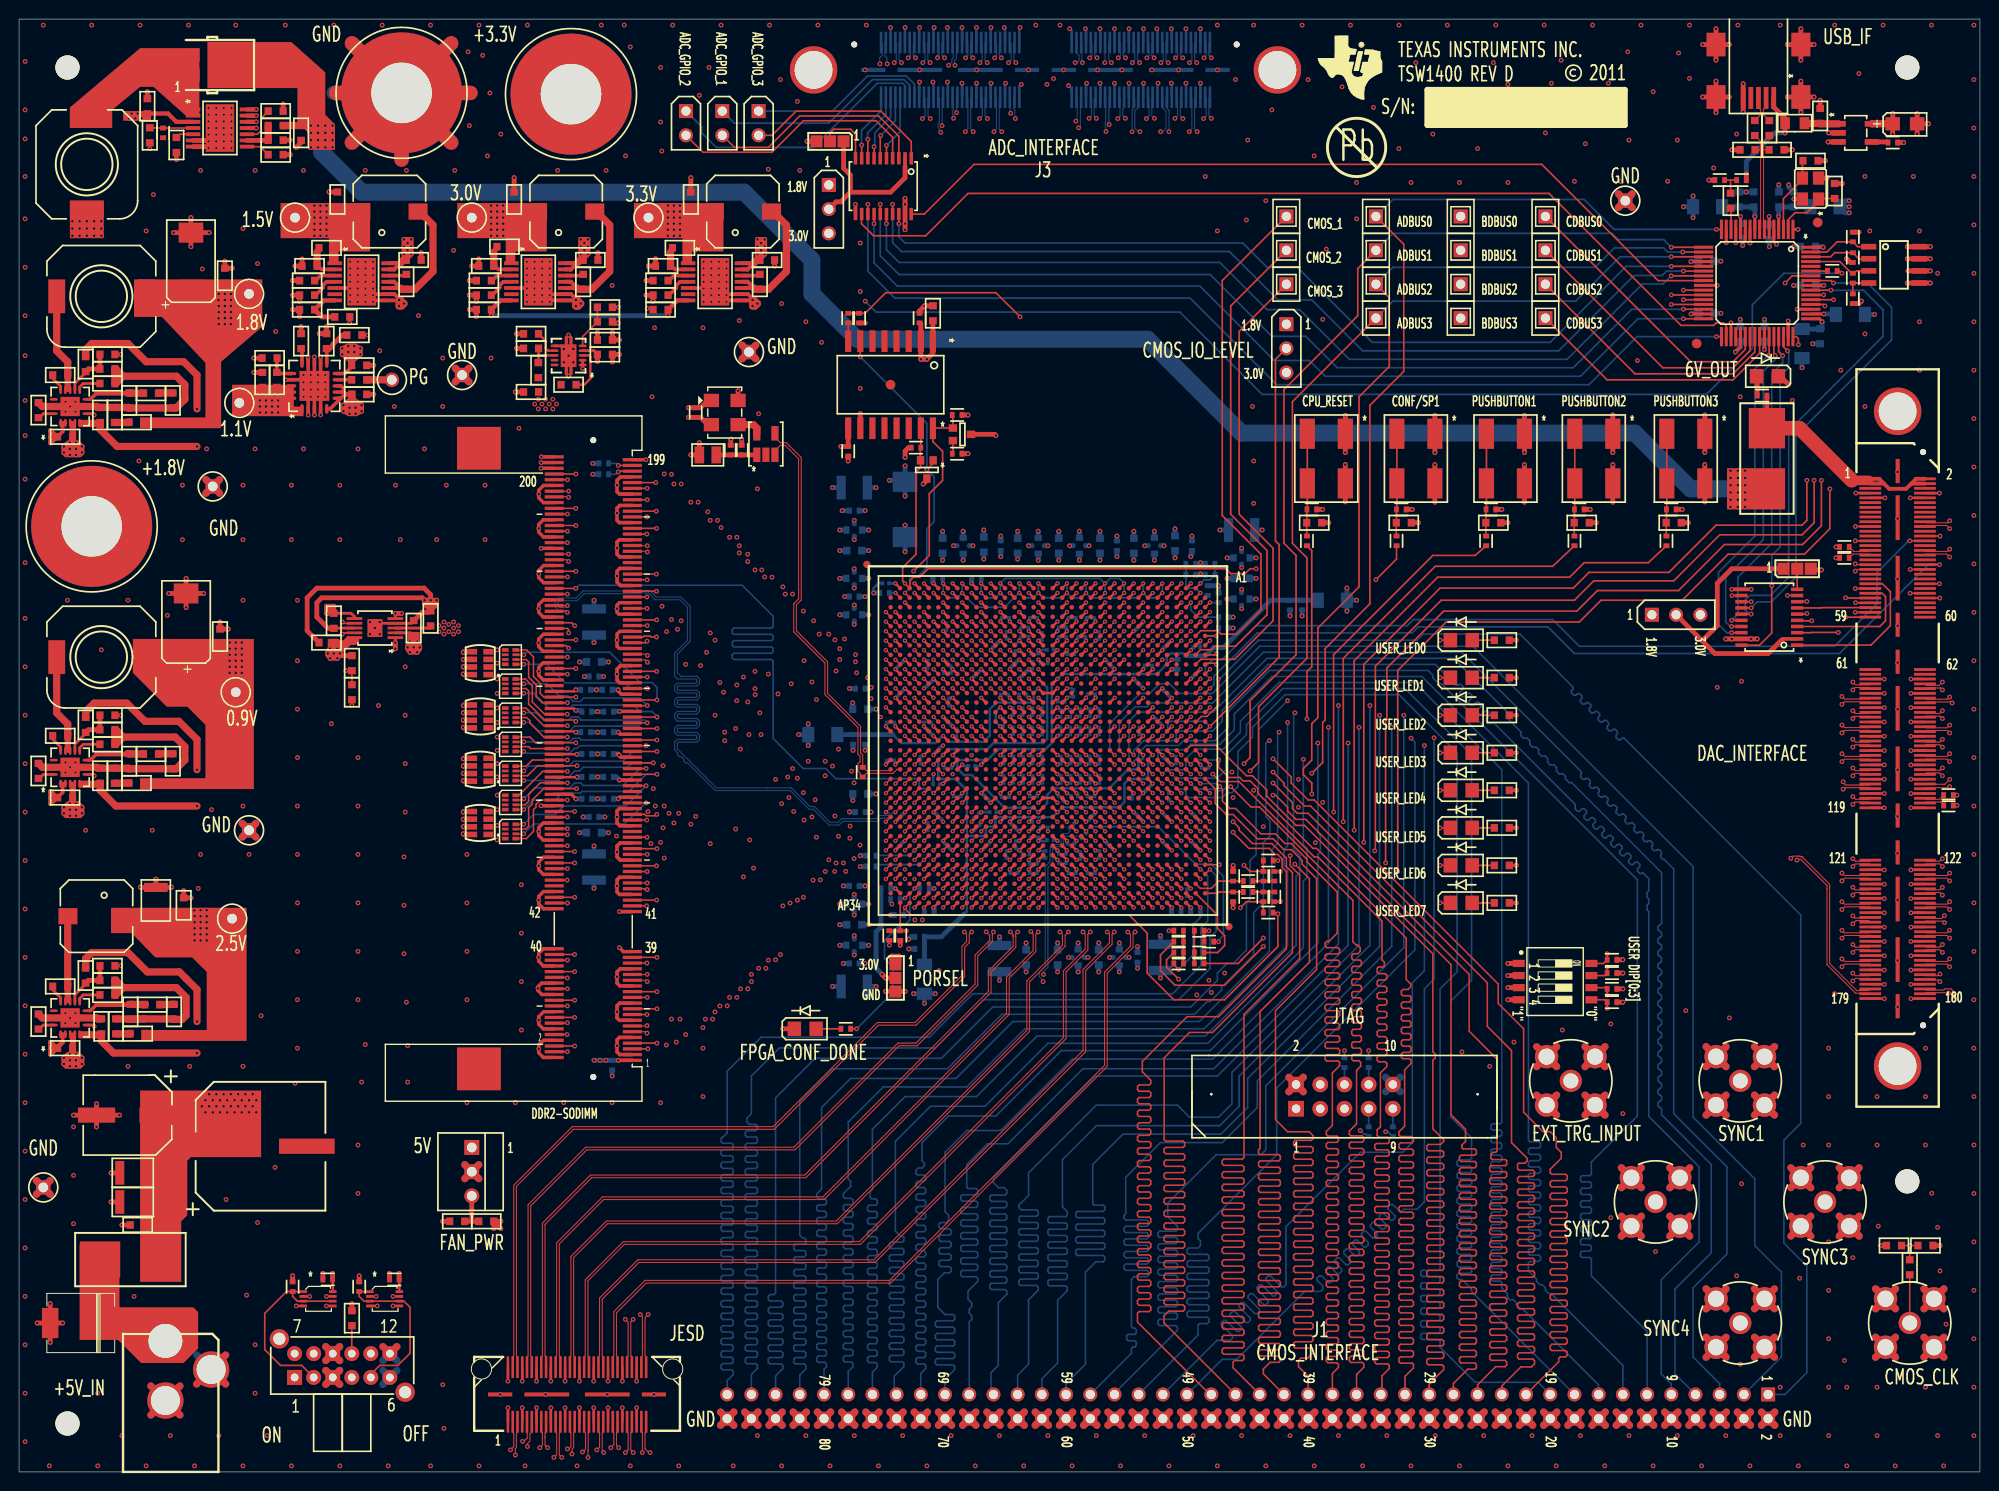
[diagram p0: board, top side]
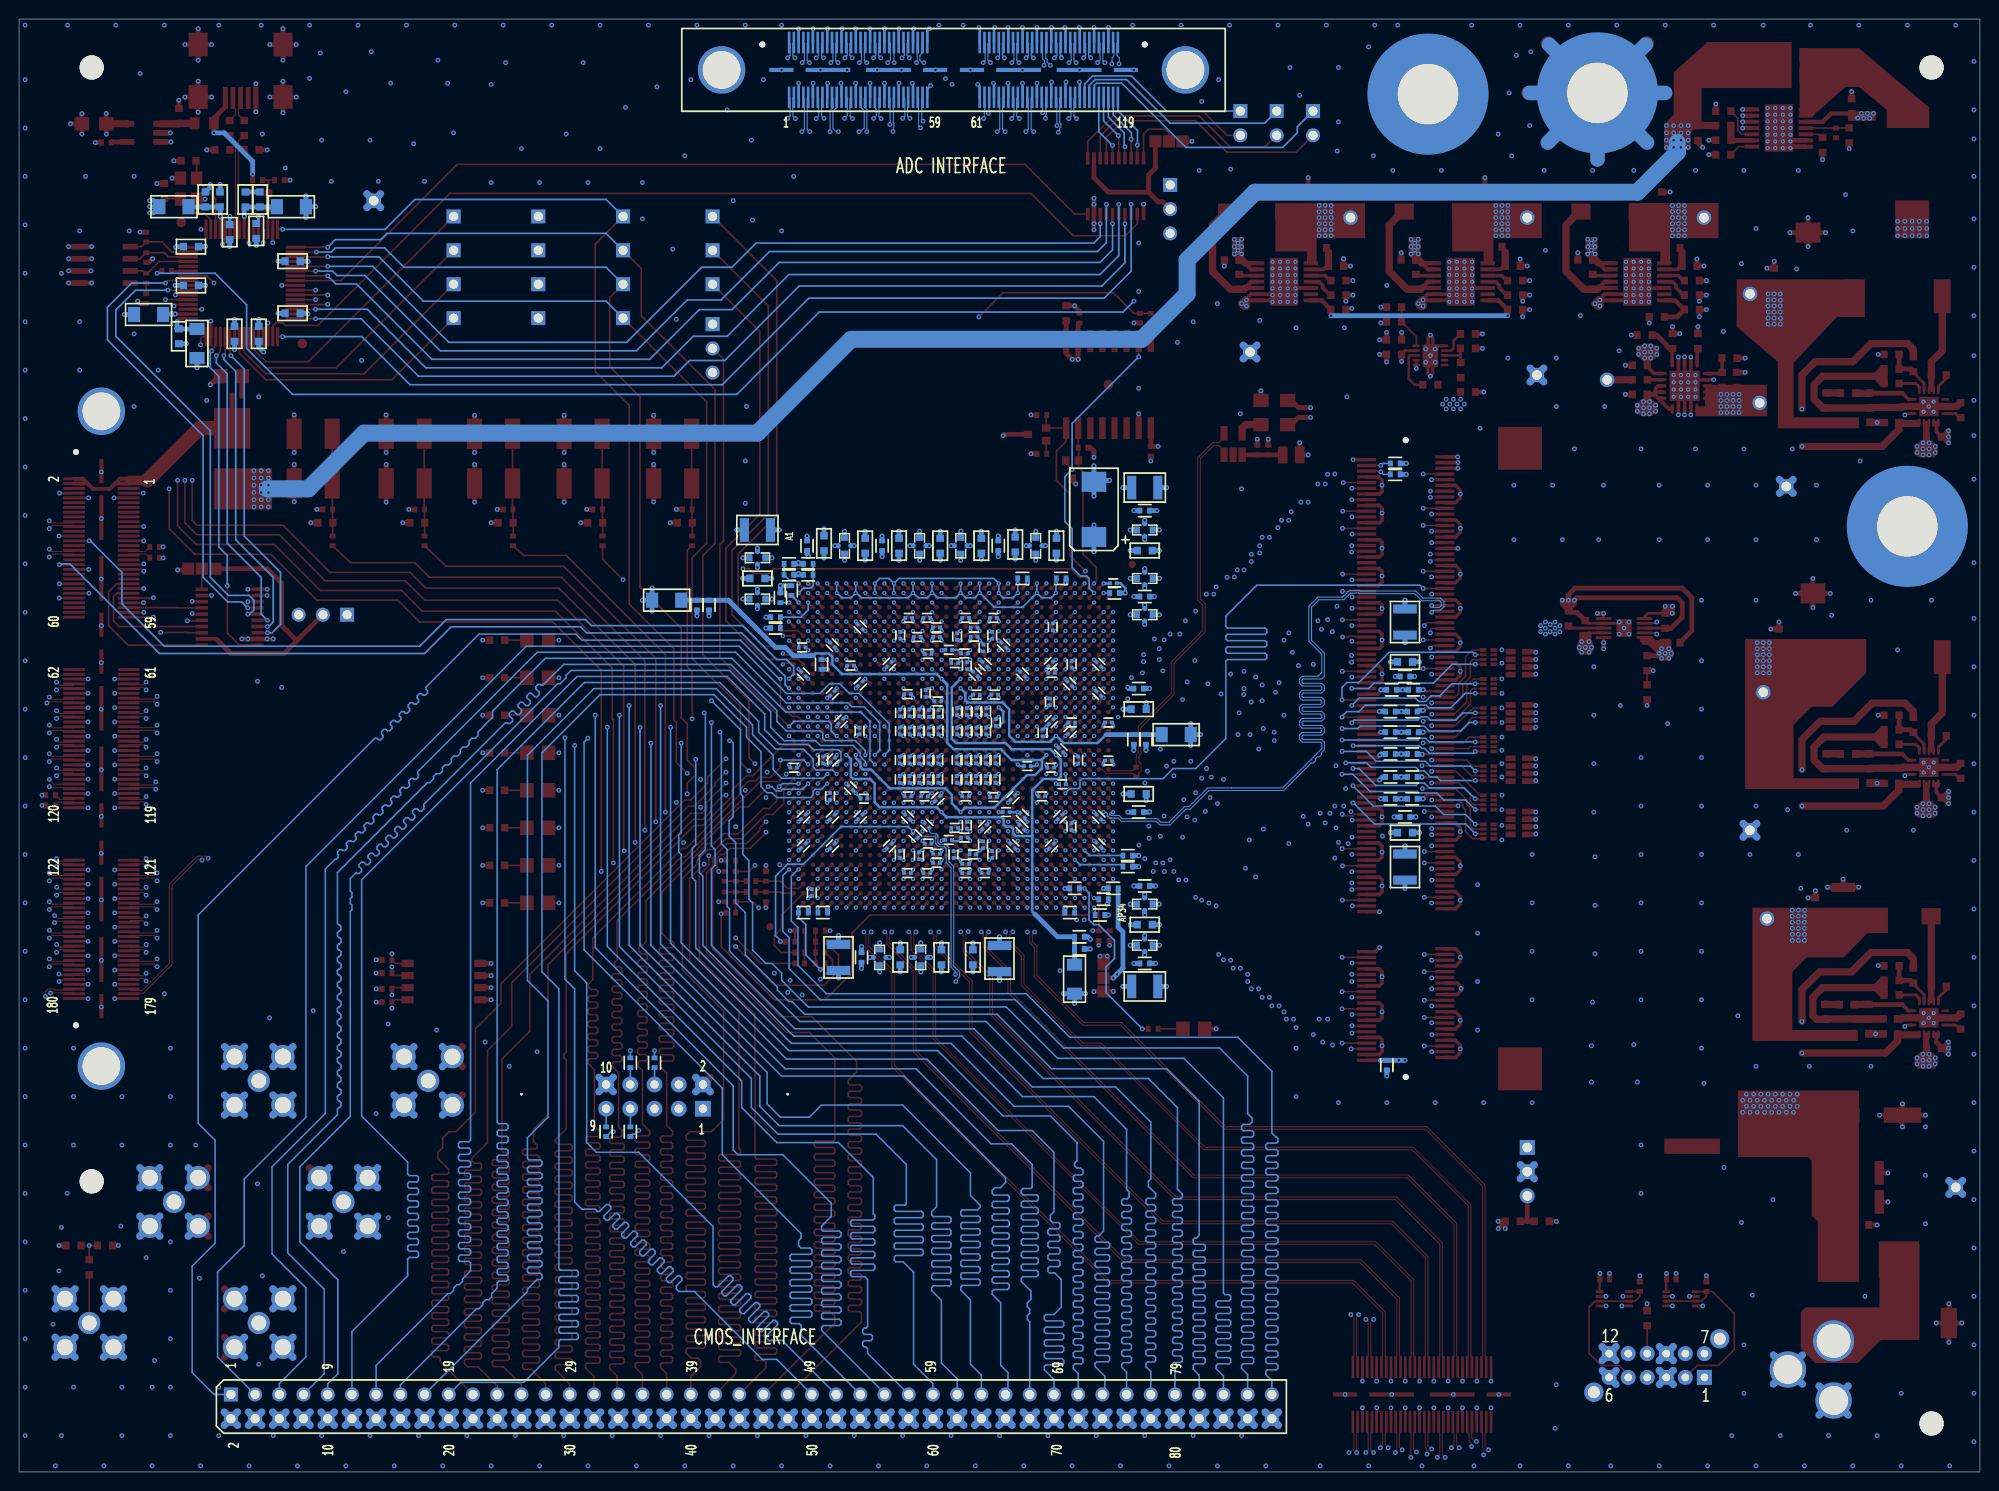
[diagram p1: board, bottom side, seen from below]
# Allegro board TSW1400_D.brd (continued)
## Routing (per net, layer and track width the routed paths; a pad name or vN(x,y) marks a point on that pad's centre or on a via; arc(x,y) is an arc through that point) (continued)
DDR2_A5: length 82.2
  TOP w0.165: J6.97 v1(66.93,75.58) ; U5.AG23 v2(97.96,70.21) ; v1(52.95,73.53) 52.95,73.53 RN18.7
  L4-SIG2 w0.102: 90.11,75.07 90.26,75.07 90.42,75.23 90.42,75.69 90.53,75.79 90.78,75.79 90.86,75.72 90.86,75.44 ; 97.63,67.82 98.25,67.82
  L4-SIG2 w0.114: 98.25,67.82 98.42,68 98.42,68.38 98.65,68.6 99.01,68.6 99.19,68.77 99.19,68.96 99.01,69.14 99.01,69.52 98.45,70.08 98.45,71.42 98.25,71.63 97.92,71.63 97.79,71.75 97.79,71.88 97.92,72.01 98.3,72.01 98.41,72.12 98.41,72.33 98.3,72.44 97.92,72.44 97.81,72.55 97.81,72.71 97.89,72.8 98.2,72.8 98.41,73.01 98.41,73.27 98.65,73.51 98.65,73.72 98.41,73.96 98.41,74.43 98.17,74.68 97.69,74.68 97.51,74.5 97.31,74.5 97.13,74.68 96.67,74.68 96.49,74.5 96.29,74.5 96.11,74.68 95.71,74.68 95.5,74.47 95.29,74.47 95.08,74.68 94.82,74.68 94.49,75.01 94.49,75.31 94.2,75.6 92.59,75.6 92.38,75.39 92.08,75.39 91.59,75.87 91.39,75.87 91.26,75.74 91.26,75.46 91.16,75.36 90.93,75.36 90.86,75.44 ; 90.11,75.07 90.02,75.16 90.02,75.74 89.92,75.84 89.69,75.84 89.59,75.74 89.59,74.93 89.46,74.8 88.98,74.8 88.87,74.9 88.87,75.08 89.2,75.41 89.2,75.92 88.95,76.17 88.49,76.17 88.24,75.92 87.99,75.92 87.73,76.17 87,76.17 86.77,75.95 86.77,75.59 86.46,75.29 85.83,75.29 85.6,75.51 85.24,75.51 85.04,75.31 84.76,75.31 84.58,75.49 84.22,75.49 83.51,74.78 83.26,74.78 82.98,75.06 82.42,75.06 82.17,74.8 81.59,74.8 81.39,74.6 81.21,74.6 81.07,74.74 81.07,74.87 80.93,75.01 80.75,75.01 80.61,74.87 80.61,74.74 80.47,74.6 80.3,74.6 80.16,74.74 80.16,74.87 80.02,75.01 79.84,75.01 79.7,74.87 79.7,74.74 79.56,74.6 79.38,74.6 79.24,74.74 79.24,74.87 79.1,75.01 78.92,75.01 78.78,74.87 78.78,74.74 78.64,74.6 78.47,74.6 78.33,74.74 78.33,74.87 78.19,75.01 77.93,75.01 77.8,74.88 77.8,74.7 77.7,74.6 77.5,74.6 77.39,74.7 77.39,74.9 77.29,75.01 77.09,75.01 76.63,74.55 75.77,74.55 75.69,74.47 75.34,74.47 75.26,74.55 74.85,74.55 74.78,74.47 74.19,74.47 74.12,74.55 73.79,74.55 73.71,74.47 73.2,74.47 73.13,74.55 72.67,74.55 72.47,74.75 72.21,74.75 72.03,74.57 71.75,74.57 71.66,74.66 71.66,74.84 71.57,74.93 71.29,74.93 71.2,74.84 71.2,74.66 71.11,74.57 70.84,74.57 70.75,74.66 70.75,74.84 70.66,74.93 70.38,74.93 70.29,74.84 70.29,74.66 70.2,74.57 69.92,74.57 69.83,74.66 69.83,74.84 69.74,74.93 69.46,74.93 69.24,74.7 69.01,74.7 68.91,74.8 68.91,75.06 68.81,75.16 68.66,75.16 68.53,75.03 68.53,74.8 68.43,74.7 68.17,74.7 68,74.87 68,75.09 68.28,75.36 68.28,75.54 68.12,75.69 67.59,75.69 67.46,75.56 67.46,75.39 67.64,75.21 67.64,75.08 67.46,74.9 67.23,74.9 67.03,75.11 66.94,75.11 66.93,75.11 66.16,75.11 66.02,75.11 65.94,75.02 65.34,75.02 65.26,75.1 65.26,75.31 65.38,75.44 66.31,75.44 66.45,75.58 v1(66.93,75.58) ; 97.63,67.82 97.46,68 97.46,68.55 97.73,68.82 98.26,68.82 98.45,69.01 98.45,69.42 97.96,69.91 v2(97.96,70.21)
  BOTTOM w0.165: v1(66.93,75.58) 64.38,75.58 63.35,74.55 58.19,74.55 57.68,74.04 53.47,74.04 v1(52.95,73.53)
DDR2_A6: length 82.2
  TOP w0.165: RN18.8 53.2,74.03 53.85,74.68 J6.94 v1(57.53,74.68) ; U5.AG24 v2(97.96,69.21)
  L4-SIG2 w0.102: 92.69,74.83 92.91,74.83 92.91,74.82 93.21,74.82 93.22,74.82 94.09,74.82 94.49,74.42 94.49,73.94 94.77,73.66 97.16,73.66 97.43,73.38 ; 97.43,71.09 97.59,70.94 97.59,70.38 97.58,70.37 97.58,70.05 97.59,70.04 97.59,69.6 97.96,69.22 v2(97.96,69.21)
  L4-SIG2 w0.114: 97.43,73.38 97.43,71.09 ; v1(57.53,74.68) 57.27,74.42 56.3,74.42 56.18,74.55 55.84,74.55 55.72,74.42 55.39,74.42 55.26,74.55 54.93,74.55 54.8,74.42 54.47,74.42 54.35,74.55 54.02,74.55 53.89,74.42 53.56,74.42 53.43,74.55 53.1,74.55 52.97,74.42 52.45,74.42 52.32,74.55 52.32,76.45 52.1,76.68 51.31,76.68 51.17,76.54 51.17,75.81 51.05,75.69 50.83,75.69 50.71,75.81 50.71,76.56 50.6,76.68 50.01,76.68 49.61,76.28 49.61,75.49 49.82,75.28 51.72,75.28 51.82,75.18 51.82,74.93 51.69,74.8 49.78,74.8 49.56,74.57 49.56,73.99 49.89,73.66 50.8,73.66 50.93,73.79 50.93,74.3 51.05,74.42 51.56,74.42 51.69,74.3 51.69,73.79 51.82,73.66 52.07,73.66 52.45,74.04 57.78,74.04 58.42,74.68 66.14,74.68 66.28,74.82 66.81,74.82 67.08,74.55 67.84,74.55 68.22,74.17 69.13,74.17 69.24,74.28 69.59,74.28 69.64,74.23 69.64,74.11 69.7,74.05 70.04,74.05 70.1,74.11 70.1,74.23 70.16,74.28 70.5,74.28 70.56,74.23 70.56,74.11 70.62,74.05 70.96,74.05 71.02,74.11 71.02,74.23 71.07,74.28 71.42,74.28 71.47,74.23 71.47,74.11 71.54,74.04 71.86,74.04 71.99,74.17 80.64,74.17 80.77,74.3 81.96,74.3 82.12,74.14 83.53,74.14 84.35,74.96 84.4,74.96 84.41,74.96 84.75,74.96 84.76,74.96 88.09,74.96 88.57,74.47 90.12,74.47 90.58,74.93 92.58,74.93 92.69,74.83
DDR2_A7: length 82.3
  TOP w0.165: v1(58.55,74.08) J6.92 54.39,74.08 53.34,73.03 RN18.6 ; U5.AG26 v2(97.96,67.21)
  L4-SIG2 w0.102: 90.68,67.82 93.68,67.82 93.7,67.79 93.9,67.79 94.12,67.56 94.78,67.56 94.79,67.58 96.11,67.58 96.12,67.56 96.32,67.56 96.67,67.21 v2(97.96,67.21)
  L4-SIG2 w0.114: v1(67.56,67.56) 69.98,67.56 70.1,67.44 72.84,67.44 73.06,67.65 73.3,67.65 73.52,67.44 73.76,67.44 73.97,67.65 74.22,67.65 74.43,67.44 74.56,67.44 75,67 75.37,67 75.55,67.18 75.98,67.18 76.11,67.31 76.44,67.31 76.57,67.18 76.9,67.18 77.03,67.31 77.36,67.31 77.48,67.18 77.81,67.18 77.94,67.31 78.27,67.31 78.4,67.18 78.73,67.18 78.85,67.31 79.18,67.31 79.31,67.18 79.64,67.18 79.77,67.31 80.1,67.31 80.23,67.18 80.56,67.18 80.68,67.31 81.01,67.31 81.14,67.18 81.47,67.18 81.6,67.31 81.93,67.31 82.05,67.18 83.06,67.18 83.44,67.56 83.97,67.56 84.2,67.79 86.33,67.79 86.75,68.21 87.06,68.21 87.07,68.22 87.61,68.22 87.86,67.97 90.53,67.97 90.68,67.82 ; v1(67.56,74.08) 67.43,73.94 66.29,73.94 66.01,74.23 65.41,74.23 65.27,74.08 64.7,74.08 64.59,73.96 64.59,73.93 64.47,73.81 64.24,73.81 64.13,73.93 64.13,74.23 64.01,74.34 63.78,74.34 63.67,74.23 63.67,73.93 63.56,73.81 63.33,73.81 63.21,73.93 63.21,74.23 63.1,74.34 62.87,74.34 62.76,74.23 62.76,73.93 62.64,73.81 62.41,73.81 62.3,73.93 62.3,74.23 62.18,74.34 61.96,74.34 61.84,74.23 61.84,73.93 61.73,73.81 61.5,73.81 61.38,73.93 61.38,74.23 61.27,74.34 61.04,74.34 60.93,74.23 60.93,73.93 60.81,73.81 60.58,73.81 60.47,73.93 60.47,74.23 60.36,74.34 60.13,74.34 60.01,74.23 60.01,73.93 59.9,73.81 59.67,73.81 59.56,73.93 59.56,73.96 59.44,74.08 v1(58.55,74.08)
  L9-SIG3 w0.114: v1(67.56,74.08) 67.69,73.95 67.69,70.87 67.23,70.41 67.23,69.49 67.41,69.31 67.41,68.63 66.88,68.1 66.88,67.31 68.15,66.04 68.15,63.93 67.56,63.35 67.56,59.66 67.01,59.11 67.01,58.34 67.34,58.01 67.77,58.01 68.5,58.75 68.5,66.88 67.82,67.56 v1(67.56,67.56)
DDR2_A8: length 82.3
  TOP w0.165: U5.AG27 v2(97.96,66.21) ; J6.93 v1(66.55,74.38) ; RN18.5 v1(52.95,72.53)
  L9-SIG3 w0.114: v1(66.55,74.38) 66.55,73.99 66.78,73.76 67.08,73.76 67.34,73.5 67.34,72.75 67.06,72.47 67.06,71.25 66.27,70.46 66.27,69.67 66.42,69.52 66.42,66.93 v1(67.31,66.04)
  L10-SIG4 w0.102: v2(97.96,66.21) 97.41,65.66 97.41,64.14 97.92,63.63 98.17,63.63 98.48,63.32 98.48,62.03 98.17,61.72 97.79,61.72 97.43,62.08 97.43,62.36 97.05,62.74 96.65,62.74 96.52,62.87 96.52,65.41 96.24,65.68 95.78,65.68 95.5,65.41 95.5,62.81 96.47,61.85 96.47,61.12 96.17,60.82 95.52,60.82 94.39,61.95 94.39,64.34 93.91,64.82 93.79,64.82 93.57,65.04 93.57,65.16 92.91,65.82 90.59,65.82
  L10-SIG4 w0.114: v1(67.31,66.04) 70.48,66.04 71.03,65.49 72.44,65.49 72.72,65.21 73.04,65.21 73.11,65.28 73.11,65.42 73.18,65.49 73.5,65.49 73.57,65.42 73.57,65.28 73.64,65.21 73.95,65.21 74.02,65.28 74.02,65.42 74.09,65.49 74.41,65.49 74.48,65.42 74.48,65.28 74.55,65.21 74.87,65.21 74.94,65.28 74.94,65.42 75.01,65.49 75.33,65.49 75.4,65.42 75.4,65.28 75.47,65.21 75.78,65.21 75.85,65.28 75.85,65.42 75.92,65.49 76.24,65.49 76.31,65.42 76.31,65.28 76.38,65.21 76.7,65.21 76.77,65.28 76.77,65.42 76.84,65.49 77.16,65.49 77.22,65.42 77.22,65.28 77.29,65.21 77.61,65.21 77.68,65.28 77.68,65.42 77.75,65.49 78.07,65.49 78.14,65.42 78.14,65.28 78.21,65.21 78.53,65.21 78.6,65.28 78.6,65.42 78.67,65.49 78.98,65.49 79.05,65.42 79.05,65.28 79.12,65.21 79.44,65.21 79.51,65.28 79.51,65.42 79.58,65.49 79.9,65.49 79.97,65.42 79.97,65.28 80.04,65.21 80.36,65.21 80.43,65.28 80.43,65.42 80.5,65.49 80.81,65.49 80.88,65.42 80.88,65.28 80.95,65.21 81.27,65.21 81.34,65.28 81.34,65.42 81.41,65.49 81.73,65.49 81.8,65.42 81.8,65.28 81.87,65.21 82.18,65.21 82.25,65.28 82.25,65.42 82.32,65.49 82.64,65.49 82.71,65.42 82.71,65.28 82.78,65.21 83.1,65.21 83.17,65.28 83.17,65.42 83.24,65.49 83.56,65.49 83.7,65.35 84.02,65.35 84.33,65.66 87.5,65.66 88.04,66.19 90.22,66.19 90.59,65.82
  BOTTOM w0.165: v1(52.95,72.53) 56.62,72.53 56.99,72.9 57.66,72.9 58.29,73.53 58.8,73.53 59.18,73.91 63.88,73.91 64.35,74.38 v1(66.55,74.38)
DDR2_A9: length 82.3
  TOP w0.165: J6.91 65.78,73.78 v1(65.79,73.79) ; v1(52.95,70.61) 52.82,70.48 RN19.7 ; U5.AH28 v2(96.95,65.2)
  L3-SIG1 w0.102: v2(96.95,65.2) 96.96,65.21 96.96,64.84 97.13,64.67 98.15,64.67 98.33,64.48 98.33,63.91 98.12,63.7 97.71,63.7 97.49,63.47 97.49,63.07 97.1,62.69 95.81,62.69 95.48,63.02 95.48,63.35 95.78,63.65 96.06,63.65 96.42,64.01 96.42,64.36 96.06,64.72 95.76,64.72 95.48,65 95.48,65.41 95.73,65.66 96.04,65.66 96.39,66.01 96.39,66.45 96.06,66.78 95.73,66.78 95.48,67.03 95.48,67.39 95.78,67.69 96.22,67.69 96.47,67.94 96.47,68.43 96.19,68.71 95.66,68.71 95.45,68.91 95.45,69.55 95.61,69.7 96.22,69.7 96.42,69.9 96.42,70.56 96.57,70.71 97.13,70.71 97.43,71.02 97.43,71.6 97.76,71.93 97.76,72.14 97.43,72.47 97.43,72.8 97.92,73.28 97.92,73.23 v2(97.95,73.2)
  L10-SIG4 w0.102: v2(97.95,73.2) 97.92,73.23 97.9,73.23 97.51,72.85 97.14,72.85 97.11,72.82 96.79,72.82 96.76,72.85 96.14,72.85 96.11,72.82 92.69,72.82 92.25,73.25 90.3,73.25
  L10-SIG4 w0.114: 90.3,73.25 90.04,73.51 89.2,73.51 88.77,73.94 87,73.94 85.64,72.58 84.29,72.58 83.54,73.33 80.87,73.33 80.77,73.43 79.14,73.43 78.89,73.69 78.71,73.69 78.54,73.51 78.54,73.29 78.43,73.18 78.2,73.18 78.09,73.29 78.09,73.57 77.97,73.69 77.74,73.69 77.63,73.57 77.63,73.29 77.52,73.18 77.29,73.18 77.17,73.29 77.17,73.57 77.06,73.69 76.83,73.69 76.71,73.57 76.71,73.29 76.6,73.18 76.37,73.18 76.26,73.29 76.26,73.57 76.14,73.69 75.91,73.69 75.8,73.57 75.8,73.29 75.69,73.18 75.46,73.18 75.34,73.29 75.34,73.57 75.23,73.69 75,73.69 74.89,73.57 74.89,73.29 74.77,73.18 74.54,73.18 74.43,73.29 74.43,73.57 74.31,73.69 74.09,73.69 73.97,73.57 73.97,73.29 73.86,73.18 73.63,73.18 73.51,73.29 73.51,73.57 73.4,73.69 73.17,73.69 73.06,73.57 73.06,73.29 72.94,73.18 72.71,73.18 72.6,73.29 72.6,73.57 72.49,73.69 72.26,73.69 72.14,73.57 72.14,73.29 72.03,73.18 71.8,73.18 71.69,73.29 71.69,73.57 71.57,73.69 71.34,73.69 71.23,73.57 71.23,73.29 71.11,73.18 70.89,73.18 70.77,73.29 70.77,73.57 70.66,73.69 70.43,73.69 70.31,73.57 70.31,73.29 70.2,73.18 69.97,73.18 69.86,73.29 69.86,73.57 69.74,73.69 69.51,73.69 69.4,73.57 69.4,73.29 69.29,73.18 69.06,73.18 68.94,73.29 68.94,73.57 68.83,73.69 68.6,73.69 68.49,73.57 68.49,73.29 68.37,73.18 68.14,73.18 68.03,73.29 68.03,73.32 67.91,73.43 67.49,73.43 67.28,73.64 65.93,73.64 v1(65.79,73.79)
  BOTTOM w0.165: v1(52.95,70.61) 52.96,70.61 54.1,71.75 57.78,71.75 58.29,72.26 58.93,72.26 59.18,72.01 63.37,72.01 65.15,73.79 v1(65.79,73.79)
DDR2_A10: length 82.3
  TOP w0.165: v1(66.93,77.98) J6.105 ; U5.AJ26 v2(95.95,67.2) ; RN12.5 v1(52.95,78.62)
  L3-SIG1 w0.114: v1(75.18,77.98) 75.18,76.94 74.47,76.23 74.47,75.9 74.59,75.79 74.89,75.79 75.01,75.68 75.01,75.45 74.89,75.33 74.05,75.33 73.94,75.22 73.94,74.99 74.05,74.88 74.89,74.88 75.01,74.76 75.01,74.53 74.89,74.42 74.05,74.42 73.94,74.3 73.94,74.08 74.05,73.96 74.89,73.96 75.01,73.85 75.01,73.62 74.89,73.5 74.05,73.5 73.94,73.39 73.94,73.16 74.05,73.05 74.89,73.05 75.01,72.93 75.01,72.7 74.89,72.59 74.05,72.59 73.94,72.48 73.94,72.25 74.05,72.13 74.89,72.13 75.01,72.02 75.01,71.79 74.89,71.68 74.05,71.68 73.94,71.56 73.94,71.33 74.05,71.22 74.89,71.22 75.01,71.1 75.01,70.88 74.89,70.76 74.05,70.76 73.94,70.65 73.94,70.42 74.05,70.3 74.89,70.3 75.01,70.19 75.01,69.96 74.89,69.85 74.05,69.85 73.94,69.73 73.94,67.67 74.17,67.44 74.17,64.14 74.42,63.88 74.8,63.88 75.06,64.14 75.06,67.31 v1(75.18,67.44)
  L10-SIG4 w0.102: 90.4,66.83 90.78,66.83 90.79,66.82 91.11,66.82 91.12,66.83 92.78,66.83 92.79,66.82 93.11,66.82 93.12,66.83 93.78,66.83 93.79,66.82 95.57,66.82 v2(95.95,67.2)
  L10-SIG4 w0.114: v1(75.18,67.44) 75.29,67.34 82.5,67.34 82.62,67.45 82.62,67.7 82.73,67.82 82.96,67.82 83.07,67.7 83.07,67.45 83.19,67.34 83.42,67.34 83.53,67.45 83.53,67.7 83.64,67.82 83.87,67.82 83.99,67.7 83.99,67.45 84.1,67.34 84.33,67.34 84.44,67.45 84.44,67.7 84.56,67.82 84.79,67.82 84.9,67.7 84.9,67.45 85.02,67.34 85.24,67.34 85.36,67.45 85.36,67.7 85.47,67.82 85.7,67.82 85.82,67.7 85.82,67.45 85.93,67.34 86.22,67.34 86.37,67.18 88.9,67.18 89.1,66.98 90.25,66.98 90.4,66.83 ; v1(75.18,77.98) 75.13,78.03 73.47,78.03 73.42,77.98 v1(66.93,77.98)
  BOTTOM w0.165: v1(66.93,77.98) 65.28,77.98 65.02,78.23 58.29,78.23 57.78,77.72 54.48,77.72 53.58,78.62 v1(52.95,78.62)
DDR2_A11: length 82.2
  TOP w0.165: U5.AJ28 v2(95.95,65.2) ; v1(57.53,73.48) J6.90 54.94,73.48 52.44,70.98 RN19.8
  L3-SIG1 w0.114: v1(87.17,66.47) 87.17,66.95 88.01,67.79 88.01,70.92 87.18,71.76 87.18,72.62 87.35,72.8 v1(87.35,73.51)
  L4-SIG2 w0.102: v2(95.95,65.2) 95.95,65.21 95.96,65.22 95.96,65.75 95.12,66.59 94.8,66.59 94.8,66.59 93.07,66.59 93.06,66.58 90.89,66.58 90.89,66.58 90.79,66.58 90.79,66.57 90.7,66.57
  L4-SIG2 w0.114: v1(87.35,73.51) 86.33,73.51 86.14,73.32 84.87,73.32 84.75,73.44 84.38,73.44 84.22,73.28 80.84,73.28 80.73,73.38 79.98,73.38 79.87,73.49 79.87,73.55 79.75,73.66 79.52,73.66 79.41,73.55 79.41,73.22 79.3,73.1 79.07,73.1 78.95,73.22 78.95,73.55 78.84,73.66 78.61,73.66 78.5,73.55 78.5,73.22 78.38,73.1 78.15,73.1 78.04,73.22 78.04,73.55 77.92,73.66 77.7,73.66 77.58,73.55 77.58,73.22 77.47,73.1 77.24,73.1 77.12,73.22 77.12,73.55 77.01,73.66 76.78,73.66 76.67,73.55 76.67,73.22 76.55,73.1 76.32,73.1 76.21,73.22 76.21,73.55 76.1,73.66 75.87,73.66 75.75,73.55 75.75,73.22 75.64,73.1 75.41,73.1 75.3,73.22 75.3,73.55 75.18,73.66 74.95,73.66 74.84,73.55 74.84,73.22 74.72,73.1 74.5,73.1 74.38,73.22 74.38,73.55 74.27,73.66 74.04,73.66 73.92,73.55 73.92,73.22 73.81,73.1 73.58,73.1 73.47,73.22 73.47,73.55 73.35,73.66 73.12,73.66 73.01,73.55 73.01,73.22 72.89,73.1 72.67,73.1 72.55,73.22 72.55,73.55 72.44,73.66 72.21,73.66 72.09,73.55 72.09,73.22 71.98,73.1 71.75,73.1 71.64,73.22 71.64,73.55 71.52,73.66 71.29,73.66 71.18,73.55 71.18,73.22 71.07,73.1 70.84,73.1 70.72,73.22 70.72,73.55 70.61,73.66 70.38,73.66 70.27,73.55 70.27,73.22 70.15,73.1 69.92,73.1 69.81,73.22 69.81,73.55 69.69,73.66 69.47,73.66 69.35,73.55 69.35,73.22 69.24,73.1 69.01,73.1 68.89,73.22 68.89,73.55 68.78,73.66 68.55,73.66 68.44,73.55 68.44,73.22 68.32,73.1 68.09,73.1 67.98,73.22 67.98,73.27 67.87,73.38 67.35,73.38 67.11,73.62 66.75,73.62 66.48,73.35 65.75,73.35 65.55,73.15 65.29,73.15 65.1,73.35 64.84,73.35 64.64,73.15 64.38,73.15 64.18,73.35 63.92,73.35 63.73,73.15 63.46,73.15 63.27,73.35 63.01,73.35 62.81,73.15 62.55,73.15 62.35,73.35 62.09,73.35 61.9,73.15 61.64,73.15 61.44,73.35 58.11,73.35 57.66,72.9 54.36,72.9 53.47,72.01 51.05,72.01 50.8,72.26 50.8,73.06 51.05,73.31 52.42,73.31 52.7,73.03 53.47,73.03 53.98,73.53 57.48,73.53 v1(57.53,73.48) ; v1(87.17,66.47) 87.3,66.6 88.14,66.6 88.29,66.75 89.46,66.75 89.69,66.52 90.65,66.52 90.7,66.57
DDR2_A12: length 82.2
  TOP w0.165: J6.89 v1(66.93,73.18) ; RN19.5 v1(52.95,69.48) ; U5.AJ29 v2(95.95,64.2)
  L4-SIG2 w0.102: 93.37,62.74 94.31,63.68 95.43,63.68 v2(95.95,64.2)
  L4-SIG2 w0.114: 93.37,62.74 90.24,62.74 90.12,62.62 90.12,62.27 90.01,62.15 89.78,62.15 89.67,62.27 89.67,63.21 89.55,63.32 89.32,63.32 89.21,63.21 89.21,62.27 89.09,62.15 88.87,62.15 88.75,62.27 88.75,62.62 88.64,62.74 88.27,62.74 87.12,63.88 87.12,64.26 86.74,64.64 85.15,64.64 85.14,64.65 84.78,64.65 84.78,64.64 84.33,64.64 83.95,64.26 67.82,64.26 v1(67.69,64.39)
  L9-SIG3 w0.114: v1(66.93,73.18) 65.13,73.18 63.53,71.58 62.64,71.58 59.89,68.83 59.89,66.88 62.64,64.14 63.2,64.14 63.3,64.03 63.3,63.2 63.4,63.09 63.6,63.09 63.7,63.2 63.7,65.07 63.81,65.18 64.01,65.18 64.11,65.07 64.11,63.2 64.21,63.09 64.42,63.09 64.52,63.2 64.52,65.07 64.62,65.18 64.82,65.18 64.92,65.07 64.92,63.2 65.03,63.09 65.23,63.09 65.33,63.2 65.33,64.03 65.43,64.14 67.44,64.14 v1(67.69,64.39)
  BOTTOM w0.165: v1(66.93,73.18) 65.79,73.18 63.98,71.37 59.05,71.37 58.9,71.21 56.99,71.21 56.26,70.48 53.95,70.48 v1(52.95,69.48)
DDR2_A13: length 82.2
  TOP w0.165: v1(58.42,81.28) J6.116 55.07,81.28 54.69,81.66 54.69,82.73 53.98,83.44 53.98,85.5 53.25,86.22 RN8.8 ; U5.AK27 v2(94.96,66.21)
  L3-SIG1 w0.114: v1(76.45,80.77) 76.68,80.54 76.68,79.63 76.81,79.5 76.81,79.17 76.75,79.11 76.62,79.11 76.56,79.05 76.56,78.72 76.81,78.46 76.81,78.26 76.68,78.13 76.68,77.86 77.02,77.52 77.02,74.61 76.66,74.25 76.66,73.92 76.53,73.79 76.53,73.46 76.6,73.39 76.73,73.39 76.8,73.33 76.8,73 76.73,72.94 76.6,72.94 76.53,72.87 76.53,72.55 76.6,72.48 76.73,72.48 76.8,72.41 76.8,72.09 76.73,72.02 76.6,72.02 76.53,71.96 76.53,71.63 76.6,71.57 76.73,71.57 76.8,71.5 76.8,71.17 76.73,71.11 76.6,71.11 76.53,71.04 76.53,70.72 76.6,70.65 76.73,70.65 76.8,70.58 76.8,70.26 76.73,70.19 76.6,70.19 76.53,70.13 76.53,69.8 76.6,69.74 76.73,69.74 76.8,69.67 76.8,69.35 76.73,69.28 76.6,69.28 76.53,69.21 76.53,68.89 76.6,68.82 76.73,68.82 76.8,68.76 76.8,68.43 76.73,68.37 76.6,68.37 76.53,68.3 76.53,67.97 76.6,67.91 76.73,67.91 76.8,67.84 76.8,67.52 76.73,67.45 76.6,67.45 76.53,67.38 76.53,67.06 76.66,66.93 v1(76.66,66.29)
  L4-SIG2 w0.102: 90.27,66.19 90.65,65.82 92.17,65.82 93.25,65.82 93.26,65.82 94.52,65.82 94.91,66.21 v2(94.96,66.21)
  L4-SIG2 w0.114: v1(76.45,80.77) 76.14,80.46 74.35,80.46 72.92,81.89 72.27,81.89 72.15,81.78 72.15,81.62 72.04,81.51 71.81,81.51 71.7,81.62 71.7,82.16 71.58,82.27 71.35,82.27 71.24,82.16 71.24,81.62 71.13,81.51 70.9,81.51 70.78,81.62 70.78,82.16 70.67,82.27 70.44,82.27 70.33,82.16 70.33,81.62 70.21,81.51 69.98,81.51 69.87,81.62 69.87,82.16 69.75,82.27 69.53,82.27 69.41,82.16 69.41,81.62 69.3,81.51 69.07,81.51 68.95,81.62 68.95,82.16 68.84,82.27 68.61,82.27 68.5,82.16 68.5,81.62 68.38,81.51 68.15,81.51 68.04,81.62 68.04,82.16 67.93,82.27 67.7,82.27 67.58,82.16 67.58,81.62 67.47,81.51 67.24,81.51 67.13,81.62 67.13,81.78 67.01,81.89 66.57,81.89 66.09,81.41 65.63,81.41 65.48,81.56 65.18,81.56 65.1,81.48 65.1,81.33 65.02,81.25 64.72,81.25 64.64,81.33 64.64,81.48 64.57,81.56 64.26,81.56 64.19,81.48 64.19,81.33 64.11,81.25 63.8,81.25 63.73,81.33 63.73,81.48 63.65,81.56 63.35,81.56 63.27,81.48 63.27,81.33 63.2,81.25 62.89,81.25 62.81,81.33 62.81,81.48 62.74,81.56 62.43,81.56 62.36,81.48 62.36,81.33 62.28,81.25 61.98,81.25 61.9,81.33 61.9,81.48 61.82,81.56 61.52,81.56 61.44,81.48 61.44,81.33 61.37,81.25 61.06,81.25 60.99,81.33 60.99,81.48 60.91,81.56 60.6,81.56 60.53,81.48 60.53,81.33 60.45,81.25 60.15,81.25 60.07,81.33 60.07,81.48 59.99,81.56 59.69,81.56 59.61,81.48 59.61,81.33 59.54,81.25 59.23,81.25 59.08,81.41 58.55,81.41 v1(58.42,81.28) ; v1(76.66,66.29) 76.89,66.07 77.25,66.07 77.37,65.95 77.37,65.85 77.48,65.74 77.71,65.74 77.82,65.85 77.82,66.28 77.94,66.4 78.17,66.4 78.28,66.28 78.28,65.85 78.4,65.74 78.62,65.74 78.74,65.85 78.74,66.28 78.85,66.4 79.08,66.4 79.2,66.28 79.2,65.85 79.31,65.74 79.54,65.74 79.65,65.85 79.65,66.28 79.77,66.4 80,66.4 80.11,66.28 80.11,65.85 80.22,65.74 80.45,65.74 80.57,65.85 80.57,66.28 80.68,66.4 80.91,66.4 81.02,66.28 81.02,65.85 81.14,65.74 81.37,65.74 81.48,65.85 81.48,66.28 81.6,66.4 81.82,66.4 81.94,66.28 81.94,65.85 82.05,65.74 82.28,65.74 82.4,65.85 82.4,65.95 82.51,66.07 83.16,66.07 83.44,65.79 87.6,65.79 88.01,66.19 90.27,66.19
DDR2_A14: length 82.3
  TOP w0.165: RN19.6 53.09,69.98 53.47,70.36 53.47,71.07 54.69,72.29 56.14,72.29 J6.86 v1(57.53,72.28) ; U5.AL29 v2(93.95,64.2)
  L3-SIG1 w0.114: v1(87.61,64.33) 87.5,64.44 87.5,66.06 88.52,67.07 88.52,71.37 v1(87.61,72.28)
  L4-SIG2 w0.102: v2(93.95,64.2) 93.73,63.98 93.73,63.88 93.6,63.75
  L4-SIG2 w0.114: v1(87.61,72.28) 87.59,72.25 82.58,72.25 82.39,72.06 80.82,72.06 80.64,72.24 79.55,72.24 79.55,72.23 79.2,72.23 79.2,72.24 79.05,72.24 78.67,72.62 78.09,72.62 77.94,72.77 77.63,72.77 77.48,72.62 77.17,72.62 77.02,72.77 76.72,72.77 76.56,72.62 76.26,72.62 76.11,72.77 75.8,72.77 75.65,72.62 75.34,72.62 75.19,72.77 74.89,72.77 74.74,72.62 74.43,72.62 74.28,72.77 73.97,72.77 73.82,72.62 73.52,72.62 73.36,72.77 73.06,72.77 72.91,72.62 72.6,72.62 72.45,72.77 72.14,72.77 71.99,72.62 71.69,72.62 71.53,72.77 71.23,72.77 71.08,72.62 70.77,72.62 70.62,72.77 70.32,72.77 70.16,72.62 69.86,72.62 69.71,72.77 69.4,72.77 69.25,72.62 68.94,72.62 68.79,72.77 68.49,72.77 68.33,72.62 68.03,72.62 67.88,72.77 67.57,72.77 67.42,72.62 66.58,72.62 66.37,72.42 66.12,72.42 66.02,72.52 66.02,72.72 65.92,72.82 65.66,72.82 65.56,72.72 65.56,72.52 65.46,72.42 65.2,72.42 65.1,72.52 65.1,72.72 65,72.82 64.75,72.82 64.65,72.72 64.65,72.52 64.54,72.42 64.29,72.42 64.09,72.62 63.65,72.62 63.17,72.14 62.64,72.14 62.47,71.97 62.19,71.97 62.1,72.06 62.1,72.23 62.02,72.31 61.73,72.31 61.64,72.23 61.64,72.06 61.56,71.97 61.27,71.97 61.19,72.06 61.19,72.23 61.1,72.31 60.81,72.31 60.73,72.23 60.73,72.06 60.64,71.97 60.36,71.97 60.27,72.06 60.27,72.23 60.19,72.31 59.9,72.31 59.82,72.23 59.82,72.06 59.73,71.97 59.44,71.97 59.27,72.14 59.03,72.14 58.89,72.28 58.17,72.28 58.17,72.26 57.66,71.75 54.86,71.75 53.21,70.1 52.36,70.1 52.24,70.22 52.24,70.62 52.13,70.74 51.9,70.74 51.79,70.62 51.79,70.22 51.67,70.1 51.44,70.1 51.33,70.22 51.33,70.62 51.22,70.74 50.99,70.74 50.87,70.62 50.87,70.22 50.76,70.1 49.91,70.1 49.15,70.87 49.15,71.88 49.53,72.26 49.91,72.26 50.67,71.5 53.72,71.5 54.74,72.52 57.29,72.52 v1(57.53,72.28) ; 93.6,63.75 93.14,63.75 93.03,63.87 93.03,64.27 92.91,64.39 92.69,64.39 92.57,64.27 92.57,63.87 92.46,63.75 89.83,63.75 89.71,63.87 89.71,64.31 89.6,64.43 89.37,64.43 89.26,64.31 89.26,63.87 89.14,63.75 88.9,63.75 88.52,64.14 87.81,64.14 v1(87.61,64.33)
DDR2_A15: length 82.2
  TOP w0.165: v1(58.5,71.68) J6.84 55.04,71.68 53.85,70.48 53.85,70.07 53.47,69.69 53.47,67.73 53.17,67.43 RN24.7 ; U5.AM28 v2(92.95,65.2)
  L4-SIG2 w0.102: v2(92.95,65.2) 92.96,65.21 92.96,65.15 92.53,64.72 90.42,64.72
  L4-SIG2 w0.114: v1(66.55,71.68) 66.41,71.54 65.35,71.54 65.22,71.68 v1(58.5,71.68) ; 90.42,64.72 88.77,64.72 88.44,65.05 88.09,65.05 88.01,64.97 83.81,64.97 83.67,64.82 83.3,64.82 83.1,65.02 82.84,65.02 82.74,64.92 82.74,64.72 82.64,64.62 82.39,64.62 82.29,64.72 82.29,64.92 82.18,65.02 81.93,65.02 81.83,64.92 81.83,64.72 81.73,64.62 81.47,64.62 81.37,64.72 81.37,64.92 81.27,65.02 81.02,65.02 80.91,64.92 80.91,64.72 80.81,64.62 80.56,64.62 80.46,64.72 80.46,64.92 80.35,65.02 80.1,65.02 80,64.92 80,64.72 79.9,64.62 79.64,64.62 79.54,64.72 79.54,64.92 79.44,65.02 79.19,65.02 79.08,64.92 79.08,64.72 78.98,64.62 78.73,64.62 78.63,64.72 78.63,64.92 78.53,65.02 78.27,65.02 78.17,64.92 78.17,64.72 78.07,64.62 77.81,64.62 77.71,64.72 77.71,64.92 77.61,65.02 77.36,65.02 77.26,64.92 77.26,64.72 77.15,64.62 76.9,64.62 76.8,64.72 76.8,64.92 76.7,65.02 76.44,65.02 76.34,64.92 76.34,64.72 76.24,64.62 75.99,64.62 75.88,64.72 75.88,64.92 75.78,65.02 75.53,65.02 75.43,64.92 75.43,64.72 75.33,64.62 75.07,64.62 74.97,64.72 74.97,64.92 74.87,65.02 74.61,65.02 74.51,64.92 74.51,64.72 74.41,64.62 74.16,64.62 74.06,64.72 74.06,64.92 73.95,65.02 73.7,65.02 73.6,64.92 73.6,64.72 73.5,64.62 73.24,64.62 73.14,64.72 73.14,64.92 73.04,65.02 72.79,65.02 72.68,64.92 72.68,64.72 72.58,64.62 72.33,64.62 72.23,64.72 72.23,64.92 72.13,65.02 71.87,65.02 71.77,64.92 71.77,64.72 71.67,64.62 71.41,64.62 71.31,64.72 71.31,64.92 71.21,65.02 70.96,65.02 70.86,64.92 70.86,64.72 70.75,64.62 70.5,64.62 70.4,64.72 70.4,64.92 70.3,65.02 70.04,65.02 69.94,64.92 69.94,64.72 69.84,64.62 69.59,64.62 69.48,64.72 69.48,64.92 69.38,65.02 69.13,65.02 69.03,64.92 69.03,64.72 68.92,64.62 68.67,64.62 68.32,64.97 66.61,64.97 66.29,65.28 v1(66.29,65.91)
  L9-SIG3 w0.114: v1(66.55,71.68) 66.21,71.34 65.62,71.34 65.33,71.04 65.33,70.8 65.21,70.69 63.49,70.69 63.37,70.57 63.37,70.35 63.49,70.23 65.21,70.23 65.33,70.12 65.33,69.89 65.21,69.77 63.49,69.77 63.37,69.66 63.37,69.43 63.49,69.32 65.21,69.32 65.33,69.2 65.33,68.97 65.21,68.86 63.49,68.86 63.37,68.75 63.37,68.52 63.49,68.4 65.21,68.4 65.33,68.29 65.33,68.06 65.21,67.94 63.49,67.94 63.37,67.83 63.37,67.6 63.49,67.49 65.21,67.49 65.33,67.37 65.33,67.14 65.21,67.03 63.49,67.03 63.37,66.92 63.37,66.69 63.49,66.57 63.77,66.57 63.89,66.46 63.89,65.9 64,65.79 64.23,65.79 64.34,65.9 64.34,66.46 64.46,66.57 64.87,66.57 65.53,65.91 v1(66.29,65.91)
DDR2_BA0: length 82.3
  TOP w0.165: v1(65.91,78.58) J6.107 ; v1(52.95,79.62) 52.95,79.63 RN12.7 ; U5.AE15 v2(99.95,79.2)
  L10-SIG4 w0.102: 90.61,78.64 99.39,78.64 v2(99.95,79.2)
  L10-SIG4 w0.114: 90.61,78.64 90.6,78.64 83.6,78.64 83.03,78.07 82.45,78.07 82.07,78.46 72.31,78.46 72.2,78.58 66.69,78.58 63.58,75.46 63.58,74.75 62.92,74.09 62.74,74.09 62.65,74.18 62.65,74.51 62.53,74.63 62.31,74.63 62.19,74.51 62.19,73.77 62.08,73.66 61.85,73.66 61.73,73.77 61.73,74.51 61.62,74.63 61.39,74.63 61.28,74.51 61.28,73.77 61.16,73.66 60.93,73.66 60.82,73.77 60.82,74.51 60.7,74.63 60.48,74.63 60.36,74.51 60.36,73.77 60.25,73.66 59.72,73.66 59.56,73.81 59.56,75.4 59.44,75.53 59.44,75.86 59.5,75.92 59.63,75.92 59.69,75.98 59.69,76.31 59.56,76.44 59.56,76.78 59.74,76.96 60.1,76.96 60.3,76.76 60.3,75.91 60.42,75.79 60.64,75.79 60.76,75.91 60.76,76.9 60.87,77.01 61.1,77.01 61.22,76.9 61.22,75.91 61.33,75.79 61.56,75.79 61.67,75.91 61.67,76.9 61.79,77.01 62.02,77.01 62.13,76.9 62.13,75.91 62.25,75.79 62.47,75.79 62.59,75.91 62.59,76.9 62.7,77.01 62.93,77.01 63.05,76.9 63.05,76.52 63.16,76.4 63.74,76.4 v1(65.91,78.58)
  BOTTOM w0.165: v1(65.91,78.58) 65.95,78.58 65.66,78.87 58.98,78.87 58.65,79.2 57.99,79.2 57.66,78.87 54.99,78.87 54.23,79.62 v1(52.95,79.62)
DDR2_BA1: length 82.2
  TOP w0.165: U5.AF15 v2(98.95,79.2) ; v1(57.53,78.28) J6.106 55.05,78.28 53.42,79.91 53.41,79.91 53.19,80.13 RN12.8
  L4-SIG2 w0.102: v2(98.95,79.2) 98.88,79.2 98.3,78.61 96.65,78.61 96.39,78.36 96.39,77.09 96.01,76.71 94.87,76.71 94.36,77.22 94.36,77.41 94.01,77.77 93.68,77.77 93.47,77.98 93.47,78.36 93.24,78.59 91.01,78.59
  L4-SIG2 w0.114: v1(57.53,78.28) 57.32,78.49 53.59,78.49 53.21,78.11 52.7,78.11 52.12,78.69 52.12,78.85 52.22,78.94 52.22,79.1 52.05,79.26 51.89,79.26 51.8,79.17 51.64,79.17 51.44,79.38 51.44,79.62 51.55,79.73 51.96,79.73 52.07,79.84 52.07,80.07 51.96,80.19 51.55,80.19 51.44,80.3 51.44,80.53 51.55,80.64 51.96,80.64 52.07,80.76 52.07,80.99 51.96,81.1 51.55,81.1 51.44,81.22 51.44,81.66 51.69,81.92 52.07,81.92 52.45,81.53 52.45,79.38 52.7,79.12 53.34,79.12 53.59,78.87 57.66,78.87 58.04,79.25 63.59,79.25 63.81,79.46 64.05,79.46 64.16,79.36 64.16,79.14 64.27,79.03 64.51,79.03 64.62,79.14 64.62,79.36 64.72,79.46 64.97,79.46 65.07,79.36 65.07,79.14 65.18,79.03 65.42,79.03 65.64,79.25 66.04,79.25 66.67,78.61 67.33,78.61 67.44,78.5 67.44,78.27 67.56,78.16 67.78,78.16 67.9,78.27 67.9,78.96 68.01,79.07 68.24,79.07 68.36,78.96 68.36,78.27 68.47,78.16 68.7,78.16 68.81,78.27 68.81,78.96 68.93,79.07 69.16,79.07 69.27,78.96 69.27,78.27 69.38,78.16 69.61,78.16 69.73,78.27 69.73,78.96 69.84,79.07 70.07,79.07 70.18,78.96 70.18,78.27 70.3,78.16 70.53,78.16 70.64,78.27 70.64,78.96 70.76,79.07 70.98,79.07 71.1,78.96 71.1,78.27 71.21,78.16 71.44,78.16 71.56,78.27 71.56,78.96 71.67,79.07 71.9,79.07 72.01,78.96 72.01,78.27 72.13,78.16 72.36,78.16 72.47,78.27 72.47,78.5 72.59,78.61 73.14,78.61 73.36,78.39 75.35,78.39 75.39,78.36 79.38,78.36 79.71,78.69 82.27,78.69 82.52,78.94 83.13,78.94 83.46,78.61 88.77,78.61 89.03,78.36 90.43,78.36 90.61,78.54 90.74,78.54 90.79,78.59 91.01,78.59
DDR2_BA2: length 82.2
  TOP w0.165: U5.AF14 v2(98.95,80.2) ; RN24.8 52.95,67.93 v1(52.95,67.94) ; J6.85 v1(65.79,71.98)
  L10-SIG4 w0.102: v2(98.95,80.2) 99.01,80.14 99.82,80.14 100.33,79.63 100.33,79.36 100.33,78.36 100.33,77.36 100.33,76.83 100.69,76.48 100.69,74.47 100.57,74.36 100.57,73.59 100.36,73.38 99.49,73.38 99.21,73.1 99.21,72.19 99.95,71.45 99.95,70.51 99.27,69.83 98.7,69.83 98.42,70.1 98.42,70.28 98.12,70.59 97.8,70.59 97.8,70.59 96.12,70.59 96.12,70.59 95.8,70.59 95.8,70.59 95.12,70.59 95.12,70.59 94.8,70.59 94.8,70.59 93.93,70.59 93.47,71.04 93.47,71.25 93.17,71.55 93.14,71.55 93.11,71.58 92.79,71.58 92.76,71.55 92.14,71.55 92.1,71.59 91.8,71.59 91.76,71.55 91.4,71.55 91.19,71.75 90.7,71.75
  L10-SIG4 w0.114: v1(65.79,71.98) 65.79,72.01 66.19,72.42 66.88,72.42 67.08,72.62 67.36,72.62 67.46,72.52 67.46,71.99 67.62,71.83 67.85,71.83 67.96,71.95 67.96,72.58 68.07,72.69 68.3,72.69 68.42,72.58 68.42,71.95 68.53,71.83 68.76,71.83 68.87,71.95 68.87,72.58 68.99,72.69 69.22,72.69 69.33,72.58 69.33,71.95 69.45,71.83 69.67,71.83 69.79,71.95 69.79,72.58 69.9,72.69 70.13,72.69 70.25,72.58 70.25,71.95 70.36,71.83 70.59,71.83 70.7,71.95 70.7,72.58 70.82,72.69 71.05,72.69 71.16,72.58 71.16,71.95 71.27,71.83 71.5,71.83 71.62,71.95 71.62,72.58 71.73,72.69 71.96,72.69 72.07,72.58 72.07,71.95 72.19,71.83 72.42,71.83 72.53,71.95 72.53,72.58 72.65,72.69 72.87,72.69 72.99,72.58 72.99,71.95 73.1,71.83 73.33,71.83 73.45,71.95 73.45,72.58 73.56,72.69 73.79,72.69 73.9,72.58 73.9,71.95 74.02,71.83 74.25,71.83 74.36,71.95 74.36,72.58 74.48,72.69 74.7,72.69 74.82,72.58 74.82,71.95 74.93,71.83 75.16,71.83 75.28,71.95 75.28,72.58 75.39,72.69 75.62,72.69 75.73,72.58 75.73,71.95 75.85,71.83 76.08,71.83 76.19,71.95 76.19,72.58 76.3,72.69 76.53,72.69 76.65,72.58 76.65,71.95 76.76,71.83 76.99,71.83 77.1,71.95 77.1,72.52 77.23,72.64 77.47,72.64 78.25,71.86 83.66,71.86 83.83,71.69 86.51,71.69 86.66,71.84 88.61,71.84 88.85,72.09 90.37,72.09 90.7,71.75
  BOTTOM w0.165: v1(65.79,71.98) 63.66,69.85 57.15,69.85 56.26,68.96 53.98,68.96 v1(52.95,67.94)
DDR2_CAS_N: length 82.2
  TOP w0.165: v1(52.95,82.67) 52.95,82.67 RN9.7 ; J6.113 65.9,80.38 v1(65.91,80.39) ; U5.AD17 v2(100.96,77.19)
  L10-SIG4 w0.102: v2(100.96,77.19) 100.56,77.59 100.56,78.45 100.56,78.45 100.56,78.95 100.56,78.95 100.56,79.45 100.56,79.45 100.56,80.42 100.15,80.82 98.11,80.82 98.11,80.82 97.79,80.82 97.79,80.82 97.11,80.82 97.11,80.82 96.79,80.82 96.79,80.82 95.11,80.82 95.11,80.82 94.79,80.82 94.79,80.82 94.11,80.82 94.11,80.82 93.79,80.82 93.79,80.82 93.11,80.82 93.11,80.82 92.85,80.82 92.61,80.58 90.63,80.58 90.49,80.44
  L10-SIG4 w0.114: v1(65.91,80.39) 64.14,80.39 63.45,81.08 63.45,82.19 63.02,82.63 61.24,82.63 60.83,83.03 60.83,83.41 60.66,83.59 60.22,83.59 60.02,83.39 60.02,82.37 59.87,82.22 59.21,82.22 59.03,82.04 59.03,81.76 59.21,81.58 62.38,81.58 62.56,81.4 62.56,81.16 62.43,81.03 59.16,81.03 59,80.87 59,80.54 59.14,80.4 63.18,80.4 63.6,79.98 67.44,79.98 67.84,80.39 74.65,80.39 75.13,79.91 76.96,79.91 77.09,80.04 78.33,80.04 78.61,79.76 88.8,79.76 89.45,80.4 89.71,80.4 89.74,80.44 90.49,80.44
  BOTTOM w0.165: v1(52.95,82.67) 55.4,82.67 56.67,81.41 57.58,81.41 58.17,80.81 58.87,80.81 59.23,81.18 65.13,81.18 v1(65.91,80.39)
DDR2_CKE0: length 82.3
  TOP w0.165: v1(65.79,70.18) J6.79 ; RN24.6 52.94,66.93 v1(52.95,66.94) ; U5.AJ12 v2(95.95,82.2)
  L3-SIG1 w0.114: v1(81.01,82.68) 80.77,82.44 80.77,74.55 80.14,73.91 80.14,72.46 80.39,72.21 80.39,71.12 v1(80.77,70.74)
  L10-SIG4 w0.102: 90.7,82.58 92.79,82.58 92.79,82.58 93.11,82.58 93.11,82.58 93.79,82.58 93.79,82.58 94.11,82.58 94.11,82.58 94.79,82.58 94.79,82.58 95.11,82.58 95.11,82.58 95.57,82.58 v2(95.95,82.2)
  L10-SIG4 w0.114: v1(65.79,70.18) 66.07,70.46 67.54,70.46 67.94,70.87 68.35,70.87 68.53,70.69 68.53,69.99 68.64,69.88 68.87,69.88 68.98,69.99 68.98,70.83 69.1,70.94 69.33,70.94 69.44,70.83 69.44,69.99 69.56,69.88 69.78,69.88 69.9,69.99 69.9,70.83 70.01,70.94 70.24,70.94 70.36,70.83 70.36,69.99 70.47,69.88 70.7,69.88 70.81,69.99 70.81,70.83 70.93,70.94 71.16,70.94 71.27,70.83 71.27,69.99 71.39,69.88 71.61,69.88 71.73,69.99 71.73,70.83 71.84,70.94 72.07,70.94 72.19,70.83 72.19,69.99 72.3,69.88 72.53,69.88 72.64,69.99 72.64,70.83 72.76,70.94 72.99,70.94 73.1,70.83 73.1,69.99 73.21,69.88 73.44,69.88 73.56,69.99 73.56,70.83 73.67,70.94 73.9,70.94 74.01,70.83 74.01,69.99 74.13,69.88 74.36,69.88 74.47,69.99 74.47,70.83 74.59,70.94 74.81,70.94 74.93,70.83 74.93,69.99 75.04,69.88 75.27,69.88 75.39,69.99 75.39,70.83 75.5,70.94 75.73,70.94 75.84,70.83 75.84,69.99 75.96,69.88 76.19,69.88 76.3,69.99 76.3,70.83 76.41,70.94 76.64,70.94 76.76,70.83 76.76,69.99 76.87,69.88 77.1,69.88 77.21,69.99 77.21,70.83 77.33,70.94 77.56,70.94 77.67,70.83 77.67,69.99 77.79,69.88 78.01,69.88 78.13,69.99 78.13,70.83 78.24,70.94 78.47,70.94 78.59,70.83 78.59,69.99 78.7,69.88 78.93,69.88 79.04,69.99 79.04,70.29 79.16,70.41 79.4,70.41 79.73,70.74 v1(80.77,70.74) ; 90.7,82.58 90.37,82.58 90.24,82.71 88.39,82.71 88.33,82.65 86.43,82.65 86.2,82.42 82.68,82.42 82.55,82.55 81.14,82.55 v1(81.01,82.68)
  BOTTOM w0.165: v1(65.79,70.18) 65.73,70.18 63.53,67.97 53.98,67.97 v1(52.95,66.94)
DDR2_CKE1: length 82.2
  TOP w0.165: U5.AJ20 v2(96.95,73.2) ; RN24.5 53.22,66.43 53.98,67.18 53.98,69.47 54.23,69.72 54.23,70.02 54.69,70.48 J6.80 v1(57.52,70.48)
  L4-SIG2 w0.102: v2(96.95,73.2) 96.94,73.21 96.5,72.77 96.11,72.77 96.01,72.67 96.01,72.11 95.91,72.01 95.71,72.01 95.6,72.11 95.6,72.52 95.35,72.77 93.98,72.77 93.47,72.26 93.47,72.17 93.18,71.88 93.17,71.88 93.11,71.82 92.79,71.82 92.78,71.83 92.12,71.83 92.11,71.82 91.79,71.82 91.78,71.83 91.12,71.83 91.11,71.82 90.79,71.82 90.78,71.83 90.68,71.83 90.37,72.14
  L4-SIG2 w0.114: 90.37,72.14 89.92,72.14 89.7,71.92 89.46,71.92 89.36,72.03 89.36,72.24 89.25,72.35 89.01,72.35 88.9,72.24 88.9,72.03 88.79,71.92 88.55,71.92 88.33,72.14 88.09,72.14 87.8,71.84 82.58,71.84 82.49,71.75 78.64,71.75 78.51,71.88 77.96,71.88 77.85,71.77 77.85,71.69 77.73,71.58 77.5,71.58 77.39,71.69 77.39,72.07 77.27,72.19 77.05,72.19 76.93,72.07 76.93,71.69 76.82,71.58 76.59,71.58 76.47,71.69 76.47,72.07 76.36,72.19 76.13,72.19 76.02,72.07 76.02,71.69 75.9,71.58 75.67,71.58 75.56,71.69 75.56,72.07 75.45,72.19 75.22,72.19 75.1,72.07 75.1,71.69 74.99,71.58 74.76,71.58 74.65,71.69 74.65,72.07 74.53,72.19 74.3,72.19 74.19,72.07 74.19,71.69 74.07,71.58 73.85,71.58 73.73,71.69 73.73,72.07 73.62,72.19 73.39,72.19 73.27,72.07 73.27,71.69 73.16,71.58 72.93,71.58 72.82,71.69 72.82,72.07 72.7,72.19 72.47,72.19 72.36,72.07 72.36,71.69 72.25,71.58 72.02,71.58 71.9,71.69 71.9,72.07 71.79,72.19 71.56,72.19 71.45,72.07 71.45,71.69 71.33,71.58 71.1,71.58 70.99,71.69 70.99,72.07 70.87,72.19 70.65,72.19 70.53,72.07 70.53,71.69 70.42,71.58 70.19,71.58 70.07,71.69 70.07,72.07 69.96,72.19 69.73,72.19 69.62,72.07 69.62,71.69 69.5,71.58 69.27,71.58 69.16,71.69 69.16,72.07 69.04,72.19 68.82,72.19 68.7,72.07 68.7,71.69 68.59,71.58 68.36,71.58 68.24,71.69 68.24,71.77 68.13,71.88 67.68,71.88 67.05,71.25 63.94,71.25 63.81,71.12 63.48,71.12 63.42,71.18 63.42,71.31 63.35,71.38 63.03,71.38 62.96,71.31 62.96,71.18 62.89,71.12 62.57,71.12 62.5,71.18 62.5,71.31 62.44,71.38 62.11,71.38 62.05,71.31 62.05,71.18 61.98,71.12 61.65,71.12 61.59,71.18 61.59,71.31 61.52,71.38 61.2,71.38 61.13,71.31 61.13,71.18 61.07,71.12 60.74,71.12 60.67,71.18 60.67,71.31 60.61,71.38 60.28,71.38 60.22,71.31 60.22,71.18 60.15,71.12 59.82,71.12 59.76,71.18 59.76,71.31 59.69,71.38 59.37,71.38 59.3,71.31 59.3,71.18 59.24,71.12 58.91,71.12 58.78,71.25 54.86,71.25 53.59,69.98 53.59,69.2 53.35,68.96 52.7,68.96 52.45,69.22 52.45,69.47 52.32,69.6 51.56,69.6 51.44,69.47 51.44,69.22 52.2,68.45 53.72,68.45 54.34,69.07 54.34,70.21 54.99,70.87 55.23,70.87 55.35,70.75 55.35,70.35 55.46,70.23 55.69,70.23 55.8,70.35 55.8,70.75 55.92,70.87 56.15,70.87 56.26,70.75 56.26,70.35 56.38,70.23 56.6,70.23 56.72,70.35 56.72,70.75 56.83,70.87 57.14,70.87 v1(57.52,70.48)
DDR2_CLK_N0: length 82.3
  TOP w0.165: J6.32 v1(58.29,52.48) ; U5.AF16 v2(98.95,78.2)
  L3-SIG1 w0.114: v1(77.6,52.83) 77.6,53.28 77.71,53.39 77.89,53.39 78,53.51 78,53.74 77.89,53.85 77.3,53.85 77.19,53.97 77.19,54.19 77.3,54.31 77.89,54.31 78,54.42 78,54.65 77.89,54.77 77.3,54.77 77.19,54.88 77.19,55.11 77.3,55.22 77.89,55.22 78,55.34 78,55.57 77.89,55.68 77.3,55.68 77.19,55.79 77.19,56.02 77.3,56.14 77.89,56.14 78,56.25 78,56.48 77.89,56.59 77.3,56.59 77.19,56.71 77.19,56.94 77.3,57.05 77.89,57.05 78,57.17 78,57.39 77.89,57.51 77.3,57.51 77.19,57.62 77.19,57.85 77.3,57.97 77.89,57.97 78,58.08 78,58.31 77.89,58.42 77.3,58.42 77.19,58.54 77.19,58.77 77.3,58.88 77.89,58.88 78,58.99 78,59.22 77.89,59.34 77.3,59.34 77.19,59.45 77.19,59.68 77.3,59.79 77.89,59.79 78,59.91 78,60.14 77.89,60.25 77.3,60.25 77.19,60.37 77.19,60.6 77.3,60.71 77.89,60.71 78,60.82 78,61.05 77.89,61.17 77.3,61.17 77.19,61.28 77.19,61.51 77.3,61.62 77.89,61.62 78,61.74 78,61.97 77.71,62.26 77.71,62.75 77.85,62.89 v1(77.85,77.34)
  L4-SIG2 w0.114: v1(77.6,52.83) 58.65,52.83 v1(58.29,52.48)
  L10-SIG4 w0.102: 90.25,77.34 92.15,77.34 92.68,76.82 94.11,76.82 94.49,77.2 94.49,77.35 94.79,77.66 98.42,77.66 98.96,78.19 v2(98.95,78.2)
  L10-SIG4 w0.114: v1(77.85,77.34) 78.28,76.91 82.12,76.91 82.3,77.09 83.34,77.09 84.1,77.85 86.92,77.85 87.17,77.6 89.99,77.6 90.25,77.34
DDR2_CLK_N1: length 82.3
  TOP w0.114: U5.AJ15 v2(95.96,79.19) ; J6.166 v1(57.66,96.28)
  L3-SIG1 w0.102: v1(76.45,96.27) 76.71,96.01 77.18,96.01 77.45,95.75 77.45,95.45 77.55,95.35 77.75,95.35 77.85,95.45 77.85,96.41 78.12,96.67 78.55,96.67 78.82,96.41 78.82,95.45 78.92,95.35 79.12,95.35 79.23,95.45 79.23,96.41 79.49,96.67 79.93,96.67 80.19,96.41 80.19,95.45 80.29,95.35 80.5,95.35 80.6,95.45 80.6,95.96 81.25,96.62 81.53,96.62 81.69,96.47 82.04,96.47 82.19,96.62 82.45,96.62 83.11,95.96 83.11,95.61 83.29,95.43 83.29,95.1 83.11,94.92 83.11,94.66 83.29,94.49 83.54,94.49 83.67,94.36 83.67,94.1 83.77,94.01 83.89,94.01 84.02,93.88 84.02,93.75 84.35,93.42 84.35,92.76 84.51,92.61 84.84,92.61 84.99,92.46 84.99,92.13 85.12,92 85.37,92 85.57,91.8 85.57,91.54 87.45,89.66 87.84,89.66 88.32,89.18 88.32,88.24 88.52,88.04 88.52,86.87 90.57,84.82 91.27,84.82 91.52,84.57 91.52,84.51 91.57,84.46 91.57,83.95 91.58,83.94 91.58,82.94 91.58,82.9 91.67,82.81 92.12,82.81 92.12,82.82 93.23,82.82 93.57,82.48 93.57,79.04 93.58,79.03 93.58,78.95 93.68,78.85 93.7,78.85 93.73,78.82 95.59,78.82 v2(95.96,79.19)
  L4-SIG2 w0.102: v1(76.45,96.27) 76.23,96.04 76.21,96.04 76.13,95.96 75.36,95.96 74.83,96.49 74.35,96.49 74.15,96.3 74.15,95.5 74.05,95.4 73.85,95.4 73.75,95.5 73.75,96.61 73.48,96.88 73.05,96.88 72.78,96.61 72.78,95.5 72.68,95.4 72.48,95.4 72.37,95.5 72.37,96.61 72.11,96.88 71.67,96.88 71.41,96.61 71.41,95.5 71.31,95.4 71.1,95.4 71,95.5 71,96.61 70.74,96.88 70.3,96.88 70.04,96.61 70.04,95.5 69.94,95.4 69.73,95.4 69.63,95.5 69.63,96.61 69.36,96.88 68.93,96.88 68.67,96.61 68.67,95.5 68.56,95.4 68.36,95.4 68.26,95.5 68.26,96.84 68,97.1 66.95,97.1 66.67,96.82 66.67,95.36 66.56,95.25 65.32,95.25 65.22,95.34 65.22,96.02 64.96,96.28 64.52,96.28 64.26,96.02 64.26,95.28 64.2,95.22 63.91,95.22 63.85,95.28 63.85,96.02 63.59,96.28 63.15,96.28 62.89,96.02 62.89,95.28 62.79,95.18 62.58,95.18 62.48,95.28 62.48,96.02 62.22,96.28 61.78,96.28 61.52,96.02 61.52,95.28 61.41,95.18 61.21,95.18 61.11,95.28 61.11,96.02 60.84,96.28 60.41,96.28 60.14,96.02 60.14,95.26 60.06,95.17 59.53,95.17 59.44,95.26 59.44,95.78 59.18,96.04 57.9,96.04 57.68,96.25 57.68,96.25 v1(57.66,96.28)
DDR2_CLK_P0: length 82.2
  TOP w0.165: U5.AE16 v2(99.95,78.2) ; J6.30 57.47,51.88 v1(57.53,51.82)
  L3-SIG1 w0.114: v1(76.45,50.67) 76.12,51 76.12,52.48 76.31,52.67 76.39,52.67 76.5,52.79 76.5,53.01 76.39,53.13 76.01,53.13 75.9,53.24 75.9,53.47 76.01,53.59 76.39,53.59 76.5,53.7 76.5,53.93 76.39,54.04 76.01,54.04 75.9,54.16 75.9,54.39 76.01,54.5 76.39,54.5 76.5,54.62 76.5,54.84 76.39,54.96 76.01,54.96 75.9,55.07 75.9,55.3 76.01,55.42 76.39,55.42 76.5,55.53 76.5,55.76 76.39,55.87 76.01,55.87 75.9,55.99 75.9,56.22 76.01,56.33 76.39,56.33 76.5,56.44 76.5,56.67 76.39,56.79 76.01,56.79 75.9,56.9 75.9,57.13 76.01,57.24 76.39,57.24 76.5,57.36 76.5,57.59 76.39,57.7 76.01,57.7 75.9,57.82 75.9,58.04 76.01,58.16 76.39,58.16 76.5,58.27 76.5,58.5 76.39,58.62 76.01,58.62 75.9,58.73 75.9,58.96 76.01,59.07 76.39,59.07 76.5,59.19 76.5,59.42 76.39,59.53 76.08,59.53 75.97,59.64 75.97,59.95 76.2,60.18 76.2,61.22 76.56,61.58 76.56,62.76 76.1,63.22 76.1,74.6 76.58,75.08 v1(76.58,77.34)
  L4-SIG2 w0.114: v1(57.53,51.82) 61.98,51.82 62.36,51.44 65.13,51.44 65.56,51 66.29,51 66.68,51.38 75.74,51.38 v1(76.45,50.67)
  L10-SIG4 w0.102: v2(99.95,78.2) 99.96,78.19 99.57,77.8 99.57,76.96 99.31,76.71 95.12,76.71 95,76.58 92.02,76.58 91.64,76.96
  L10-SIG4 w0.114: v1(76.58,77.34) 77.57,76.35 82.25,76.35 82.55,76.66 83.62,76.66 84.3,77.34 86.77,77.34 87.15,76.96 91.64,76.96
DDR2_CLK_P1: length 82.3
  TOP w0.114: U5.AH16 v2(96.95,78.2) ; v1(57.66,95.5) 57.48,95.68 J6.164
  L3-SIG1 w0.102: v1(76.45,95.5) 76.68,95.73 77.07,95.73 77.17,95.63 77.17,95.34 77.43,95.07 77.87,95.07 78.13,95.34 78.13,96.29 78.23,96.39 78.44,96.39 78.54,96.29 78.54,95.34 78.8,95.07 79.24,95.07 79.5,95.34 79.5,96.29 79.61,96.39 79.81,96.39 79.91,96.29 79.91,95.34 80.18,95.07 80.61,95.07 80.88,95.34 80.88,95.84 81.23,96.19 82.37,96.19 82.83,95.73 82.83,94.55 84.07,93.3 84.07,92.61 87.3,89.38 87.72,89.38 88.04,89.07 88.04,88.11 88.24,87.91 88.24,86.74 89.64,85.34 89.87,85.12 90.4,84.58 91.17,84.58 91.28,84.47 91.28,84.41 91.33,84.36 91.33,83.85 91.34,83.84 91.34,83 91.34,83 91.34,82.9 91.34,82.81 91.34,82.8 91.41,82.74 91.47,82.67 91.48,82.67 91.57,82.57 92.21,82.57 92.22,82.58 93.13,82.58 93.33,82.38 93.33,78.94 93.34,78.93 93.34,78.85 93.58,78.61 93.6,78.61 93.64,78.58 96.22,78.58 96.6,78.2 v2(96.95,78.2)
  L4-SIG2 w0.102: v1(57.66,95.5) 57.91,95.76 59.07,95.76 59.16,95.67 59.16,95.15 59.41,94.89 60.17,94.89 60.42,95.15 60.42,95.9 60.53,96 60.73,96 60.83,95.9 60.83,95.17 61.1,94.9 61.53,94.9 61.8,95.17 61.8,95.9 61.9,96 62.1,96 62.2,95.9 62.2,95.17 62.47,94.9 62.9,94.9 63.17,95.17 63.17,95.9 63.27,96 63.47,96 63.57,95.9 63.57,95.17 63.8,94.95 64.32,94.95 64.54,95.17 64.54,95.9 64.64,96 64.84,96 64.95,95.9 64.95,95.23 65.2,94.97 66.67,94.97 66.95,95.24 66.95,96.7 67.07,96.82 67.88,96.82 67.98,96.73 67.98,95.39 68.24,95.12 68.68,95.12 68.94,95.39 68.94,96.49 69.05,96.6 69.25,96.6 69.35,96.49 69.35,95.39 69.62,95.12 70.05,95.12 70.32,95.39 70.32,96.49 70.42,96.6 70.62,96.6 70.72,96.49 70.72,95.39 70.99,95.12 71.42,95.12 71.69,95.39 71.69,96.49 71.79,96.6 71.99,96.6 72.09,96.49 72.09,95.39 72.36,95.12 72.79,95.12 73.06,95.39 73.06,96.49 73.16,96.6 73.36,96.6 73.47,96.49 73.47,95.39 73.73,95.12 74.17,95.12 74.43,95.39 74.43,96.18 74.46,96.22 74.71,96.22 75.25,95.68 76.28,95.68 v1(76.45,95.5)
DDR2_CS_N0: length 82.2
  TOP w0.165: RN9.8 53.12,83.17 53.85,82.45 53.85,80.77 55.14,79.48 J6.110 v1(57.51,79.48) ; U5.AK17 v2(94.96,77.19)
  L4-SIG2 w0.102: 90.65,79.5 92.71,79.5 92.79,79.58 93.27,79.58 93.47,79.38 93.47,78.99 93.73,78.74 95.12,78.74 95.38,78.49 95.38,77.72 94.96,77.31 v2(94.96,77.19)
  L4-SIG2 w0.114: 90.65,79.5 90.57,79.58 89.1,79.58 88.97,79.46 88.64,79.46 88.58,79.52 88.58,79.64 88.52,79.71 88.18,79.71 88.12,79.64 88.12,79.52 88.06,79.46 87.73,79.46 87.66,79.52 87.66,79.64 87.6,79.71 87.27,79.71 87.21,79.64 87.21,79.52 87.14,79.46 86.81,79.46 86.75,79.52 86.75,79.64 86.69,79.71 86.35,79.71 86.23,79.58 85.87,79.58 85.45,80.01 79.12,80.01 78.3,79.19 77.4,79.19 77.09,79.5 73.66,79.5 73.28,79.88 72.51,79.88 72.4,79.77 72.4,79.74 72.28,79.63 72.05,79.63 71.94,79.74 71.94,80.02 71.82,80.14 71.6,80.14 71.48,80.02 71.48,79.74 71.37,79.63 71.14,79.63 71.02,79.74 71.02,80.02 70.91,80.14 70.68,80.14 70.57,80.02 70.57,79.74 70.45,79.63 70.22,79.63 70.11,79.74 70.11,80.02 69.99,80.14 69.77,80.14 69.65,80.02 69.65,79.74 69.54,79.63 69.31,79.63 69.19,79.74 69.19,80.02 69.08,80.14 68.85,80.14 68.74,80.02 68.74,79.74 68.62,79.63 68.39,79.63 68.28,79.74 68.28,80.02 68.17,80.14 67.94,80.14 67.82,80.02 67.82,79.74 67.71,79.63 67.48,79.63 67.37,79.74 67.37,80.02 67.25,80.14 67.02,80.14 66.91,80.02 66.91,79.74 66.79,79.63 66.57,79.63 66.45,79.74 66.45,79.77 66.34,79.88 65.41,79.88 64.9,80.39 64.51,80.39 64.39,80.52 64.06,80.52 63.99,80.45 63.99,80.33 63.93,80.26 63.6,80.26 63.54,80.33 63.54,80.45 63.47,80.52 63.14,80.52 63.08,80.45 63.08,80.33 63.01,80.26 62.68,80.26 62.62,80.33 62.62,80.45 62.56,80.52 62.23,80.52 62.16,80.45 62.16,80.33 62.1,80.26 61.77,80.26 61.71,80.33 61.71,80.45 61.64,80.52 61.31,80.52 61.25,80.45 61.25,80.33 61.19,80.26 60.86,80.26 60.79,80.33 60.79,80.45 60.73,80.52 60.4,80.52 60.34,80.45 60.34,80.33 60.27,80.26 59.94,80.26 59.88,80.33 59.88,80.45 59.81,80.52 59.48,80.52 59.42,80.45 59.42,80.33 59.36,80.26 59.03,80.26 58.9,80.39 58.14,80.39 57.89,80.14 56.13,80.14 54.86,81.41 54.86,82.93 53.97,83.82 53.97,84.2 54.23,84.45 54.23,84.82 54.1,84.95 53.71,84.95 53.47,84.71 53.47,84.2 52.96,83.69 52.96,83.48 53.58,82.86 54.37,82.86 54.48,82.74 54.48,82.51 54.37,82.4 53.58,82.4 53.47,82.28 53.47,82.06 53.58,81.94 54.37,81.94 54.48,81.83 54.48,81.6 54.37,81.48 53.58,81.48 53.47,81.37 53.47,81.14 53.58,81.03 54.37,81.03 54.48,80.91 54.48,80.68 54.37,80.57 53.58,80.57 53.47,80.46 53.47,79.73 53.72,79.48 54.66,79.48 54.77,79.59 54.77,80.4 54.89,80.52 55.11,80.52 55.23,80.4 55.23,79.59 55.34,79.48 v1(57.51,79.48)
DDR2_CS_N1: length 82.2
  TOP w0.165: U5.AL18 v2(93.96,75.21) ; v1(52.95,85.72) 52.95,85.72 RN8.7 ; J6.115 v1(66.93,80.98)
  L3-SIG1 w0.102: 94.13,76.12 93.45,75.44 93.45,75.01 93.17,74.73 92.81,74.73 92.48,74.4 92.48,73.63 92.25,73.41 90.91,73.41 90.81,73.3 90.81,72.8 90.88,72.72 92.28,72.72 92.48,72.52 92.48,72.09 92.76,71.81 93.17,71.81 93.42,72.06 93.42,74.35 93.96,74.88 v2(93.96,75.21)
  L3-SIG1 w0.114: 94.13,76.12 94.13,76.58 94.01,76.71 92.98,76.71 92.87,76.59 92.87,75.91 92.75,75.79 92.52,75.79 92.41,75.91 92.41,76.59 92.3,76.71 92.07,76.71 91.95,76.59 91.95,76.37 91.84,76.25 91.53,76.25 91.37,76.08 91.2,76.08 91.04,76.25 91.04,76.41 91.54,76.9 91.54,77.06 91.38,77.23 91.21,77.23 90.72,76.73 90.56,76.73 90.4,76.89 90.4,77.05 90.89,77.55 90.89,77.71 90.73,77.87 90.57,77.87 90.07,77.38 89.91,77.38 89.75,77.54 89.75,77.7 90.24,78.2 90.24,78.36 90.08,78.52 89.92,78.52 89.75,78.35 89.59,78.35 89.41,78.54 89.41,81.11 v1(89.41,81.11)
  L10-SIG4 w0.114: v1(89.41,81.11) 89.32,81.11 89.28,81.15 87.02,81.15 86.79,80.92 84.44,80.92 84.1,80.58 83.33,80.58 83.11,80.8 77.32,80.8 76.71,81.41 75.01,81.41 74.58,80.98 67.75,80.98 67.26,80.49 66.67,80.49 66.17,81 64.47,81 63.88,81.58 63.88,83.19 64.01,83.31 64.39,83.31 64.52,83.19 64.52,81.76 64.86,81.42 66.48,81.42 66.93,80.98 v1(66.93,80.98)
  BOTTOM w0.165: v1(66.93,80.98) 66.93,82.3 66.42,82.8 65.15,82.8 61.98,85.98 53.21,85.98 v1(52.95,85.72)
DDR2_DM0: length 82.2
  TOP w0.165: U5.AP10 v2(90.95,84.2) ; J6.10 v1(57.5,45.88)
  L4-SIG2 w0.114: v1(69.95,45.88) 66.55,45.88 66.14,45.47 57.91,45.47 v1(57.5,45.88)
  L9-SIG3 w0.114: v1(69.95,84.71) 70.26,84.4 70.26,69.52 69.95,69.21 69.95,59.29 69.85,59.19 69.85,58.92 70.13,58.64 70.13,58.37 70.04,58.28 69.85,58.28 69.76,58.19 69.76,57.91 69.85,57.82 70.04,57.82 70.13,57.73 70.13,57.46 70.04,57.36 69.85,57.36 69.76,57.27 69.76,57 69.85,56.91 70.04,56.91 70.13,56.82 70.13,56.54 70.04,56.45 69.85,56.45 69.76,56.36 69.76,56.09 69.85,55.99 70.04,55.99 70.13,55.9 70.13,55.63 70.04,55.54 69.85,55.54 69.76,55.44 69.76,55.17 69.85,55.08 70.04,55.08 70.13,54.99 70.13,54.71 70.04,54.62 69.85,54.62 69.76,54.53 69.76,54.26 69.85,54.16 70.04,54.16 70.13,54.07 70.13,53.8 70.04,53.71 69.85,53.71 69.76,53.62 69.76,53.34 69.85,53.25 70.04,53.25 70.13,53.16 70.13,52.88 70.04,52.79 69.85,52.79 69.76,52.7 69.76,52.43 69.85,52.34 70.04,52.34 70.13,52.24 70.13,51.97 70.04,51.88 69.85,51.88 69.76,51.79 69.76,51.51 69.85,51.42 70.04,51.42 70.13,51.33 70.13,51.06 70.04,50.96 69.85,50.96 69.76,50.87 69.76,50.6 69.85,50.51 70.04,50.51 70.13,50.42 70.13,50.14 70.04,50.05 69.85,50.05 69.76,49.96 69.76,49.68 69.85,49.59 70.04,49.59 70.13,49.5 70.13,49.23 70.04,49.14 69.85,49.14 69.76,49.04 69.76,48.77 69.85,48.68 70.04,48.68 70.13,48.59 70.13,48.31 69.95,48.13 v1(69.95,45.88)
  L10-SIG4 w0.114: v1(69.95,84.71) 70.17,84.94 70.48,84.94 71.28,84.14 71.8,84.14 72.09,84.43 79.78,84.43 80.39,83.82 85.22,83.82 85.43,83.61 86.53,83.61 87.38,84.45 90.7,84.45 v2(90.95,84.2)
DDR2_DM1: length 82.2
  TOP w0.165: U5.AK12 v2(95.94,81.21) ; J6.26 v1(57.53,50.68)
  L3-SIG1 w0.102: 90.5,68.94 90.73,68.71 92.18,68.71 92.46,68.43 92.46,64.01 ; 90.75,70.69 93.17,70.69 93.47,70.99 93.47,71.5 93.6,71.63 93.98,71.63 94.49,72.14 94.49,75.51 95.55,76.58 99.06,76.58 99.34,76.86 99.34,78.49 99.14,78.69 96.85,78.69 96.47,79.07 96.47,79.38 96.27,79.58 95.53,79.58 95.33,79.78 95.33,80.04 95.33,80.04 95.33,80.36 95.33,80.36 95.33,80.87 95.66,81.21 v2(95.94,81.21)
  L3-SIG1 w0.114: 92.46,64.01 92.1,63.65 91.69,63.65 91.44,63.4 91.44,62.99 91.19,62.74 90.83,62.74 86.64,58.55 85.85,58.55 84.1,56.79 83.93,56.79 83.72,57.01 83.55,57.01 83.39,56.85 83.39,56.69 83.61,56.47 83.61,56.31 83.45,56.14 83.29,56.14 83.07,56.36 82.91,56.36 82.75,56.2 82.75,56.04 82.96,55.82 82.96,55.66 82.8,55.5 82.64,55.5 82.42,55.72 82.26,55.72 82.1,55.56 82.1,55.39 82.32,55.17 82.32,55.01 82.16,54.85 81.99,54.85 81.78,55.07 81.61,55.07 81.45,54.91 81.45,54.75 81.67,54.53 81.67,54.37 81.51,54.2 81.35,54.2 81.13,54.42 80.97,54.42 80.81,54.26 80.81,54.1 81.02,53.88 81.02,53.72 80.86,53.56 80.7,53.56 80.48,53.78 80.32,53.78 80.16,53.62 80.16,53.45 80.38,53.23 80.38,53.07 80.22,52.91 80.06,52.91 79.84,53.13 79.67,53.13 79.51,52.97 79.51,52.81 79.73,52.59 79.73,52.43 79.57,52.27 79.41,52.27 79.19,52.48 79.03,52.48 78.87,52.32 78.87,52.16 79.09,51.94 79.09,51.78 78.92,51.62 78.76,51.62 78.54,51.84 78.38,51.84 78.22,51.68 78.22,51.51 78.44,51.3 78.44,51.13 78.28,50.97 78.12,50.97 77.9,51.19 77.73,51.19 77.57,51.03 77.57,50.87 77.79,50.65 77.79,50.49 77.19,49.89 76.23,49.89 75.69,50.42 v1(75.69,50.68) ; 90.75,70.69 90.5,70.43 90.5,68.94
  L4-SIG2 w0.114: v1(75.69,50.68) 67.44,50.68 67.3,50.82 66.75,50.82 66.22,50.29 57.91,50.29 v1(57.53,50.68)
DDR2_DM2: length 82.2
  TOP w0.165: U5.AJ19 v2(95.95,74.2) ; J6.52 v1(57.51,62.08)
  L4-SIG2 w0.114: v1(83.31,62.08) 83.06,61.82 82.27,61.82 82.16,61.94 82.16,62.14 82.04,62.26 81.81,62.26 81.7,62.14 81.7,61.51 81.58,61.39 81.36,61.39 81.24,61.51 81.24,62.14 81.13,62.26 80.9,62.26 80.78,62.14 80.78,61.51 80.67,61.39 80.44,61.39 80.33,61.51 80.33,62.14 80.21,62.26 79.98,62.26 79.87,62.14 79.87,61.51 79.76,61.39 79.53,61.39 79.41,61.51 79.41,62.14 79.3,62.26 79.07,62.26 78.96,62.14 78.96,61.51 78.84,61.39 78.61,61.39 78.5,61.51 78.5,62.14 78.38,62.26 78.15,62.26 78.04,62.14 78.04,61.51 77.93,61.39 77.7,61.39 77.58,61.51 77.58,62.14 77.47,62.26 77.24,62.26 77.13,62.14 77.13,61.51 77.01,61.39 76.78,61.39 76.67,61.51 76.67,61.71 76.55,61.82 75.22,61.82 75.1,61.71 75.1,61.51 74.99,61.39 74.76,61.39 74.65,61.51 74.65,62.14 74.53,62.26 74.3,62.26 74.19,62.14 74.19,61.51 74.07,61.39 73.85,61.39 73.73,61.51 73.73,62.14 73.62,62.26 73.39,62.26 73.27,62.14 73.27,61.51 73.16,61.39 72.93,61.39 72.82,61.51 72.82,62.14 72.7,62.26 72.47,62.26 72.36,62.14 72.36,61.51 72.25,61.39 72.02,61.39 71.9,61.51 71.9,62.14 71.79,62.26 71.56,62.26 71.44,62.14 71.44,61.51 71.33,61.39 71.1,61.39 70.99,61.51 70.99,62.14 70.87,62.26 70.64,62.26 70.53,62.14 70.53,61.51 70.42,61.39 70.19,61.39 70.07,61.51 70.07,62.14 69.96,62.26 69.73,62.26 69.62,62.14 69.62,61.51 69.5,61.39 69.27,61.39 69.16,61.51 69.16,62.14 69.04,62.26 68.82,62.26 68.7,62.14 68.7,61.51 68.59,61.39 68.36,61.39 68.24,61.51 68.24,62.14 68.13,62.26 67.9,62.26 67.79,62.14 67.79,61.51 67.67,61.39 67.44,61.39 67.33,61.51 67.33,61.71 67.22,61.82 66.67,61.82 66.12,62.38 64.81,62.38 64.69,62.5 64.69,62.55 64.58,62.66 64.35,62.66 64.24,62.55 64.24,62.22 64.12,62.1 63.89,62.1 63.78,62.22 63.78,62.55 63.66,62.66 63.44,62.66 63.32,62.55 63.32,62.22 63.21,62.1 62.98,62.1 62.86,62.22 62.86,62.55 62.75,62.66 62.52,62.66 62.41,62.55 62.41,62.22 62.29,62.1 62.06,62.1 61.95,62.22 61.95,62.55 61.84,62.66 61.61,62.66 61.49,62.55 61.49,62.22 61.38,62.1 61.15,62.1 61.04,62.22 61.04,62.55 60.92,62.66 60.69,62.66 60.58,62.55 60.58,62.22 60.46,62.1 60.24,62.1 60.12,62.22 60.12,62.55 60.01,62.66 59.78,62.66 59.66,62.55 59.66,62.22 59.55,62.1 59.32,62.1 59.21,62.22 59.21,62.55 59.09,62.66 58.86,62.66 58.75,62.55 58.75,62.22 58.64,62.1 58.41,62.1 58.29,62.22 58.29,62.27 58.18,62.38 57.81,62.38 v1(57.51,62.08)
  L9-SIG3 w0.114: v1(83.31,62.08) 81.92,63.48 81.92,68.96 82.8,69.85 v1(82.8,74.55)
  L10-SIG4 w0.102: 92.63,74.75 95.05,74.75 95.6,74.2 v2(95.95,74.2)
  L10-SIG4 w0.114: v1(82.8,74.55) 83.87,74.55 84.38,75.06 85.55,75.06 85.7,74.9 92.48,74.9 92.63,74.75
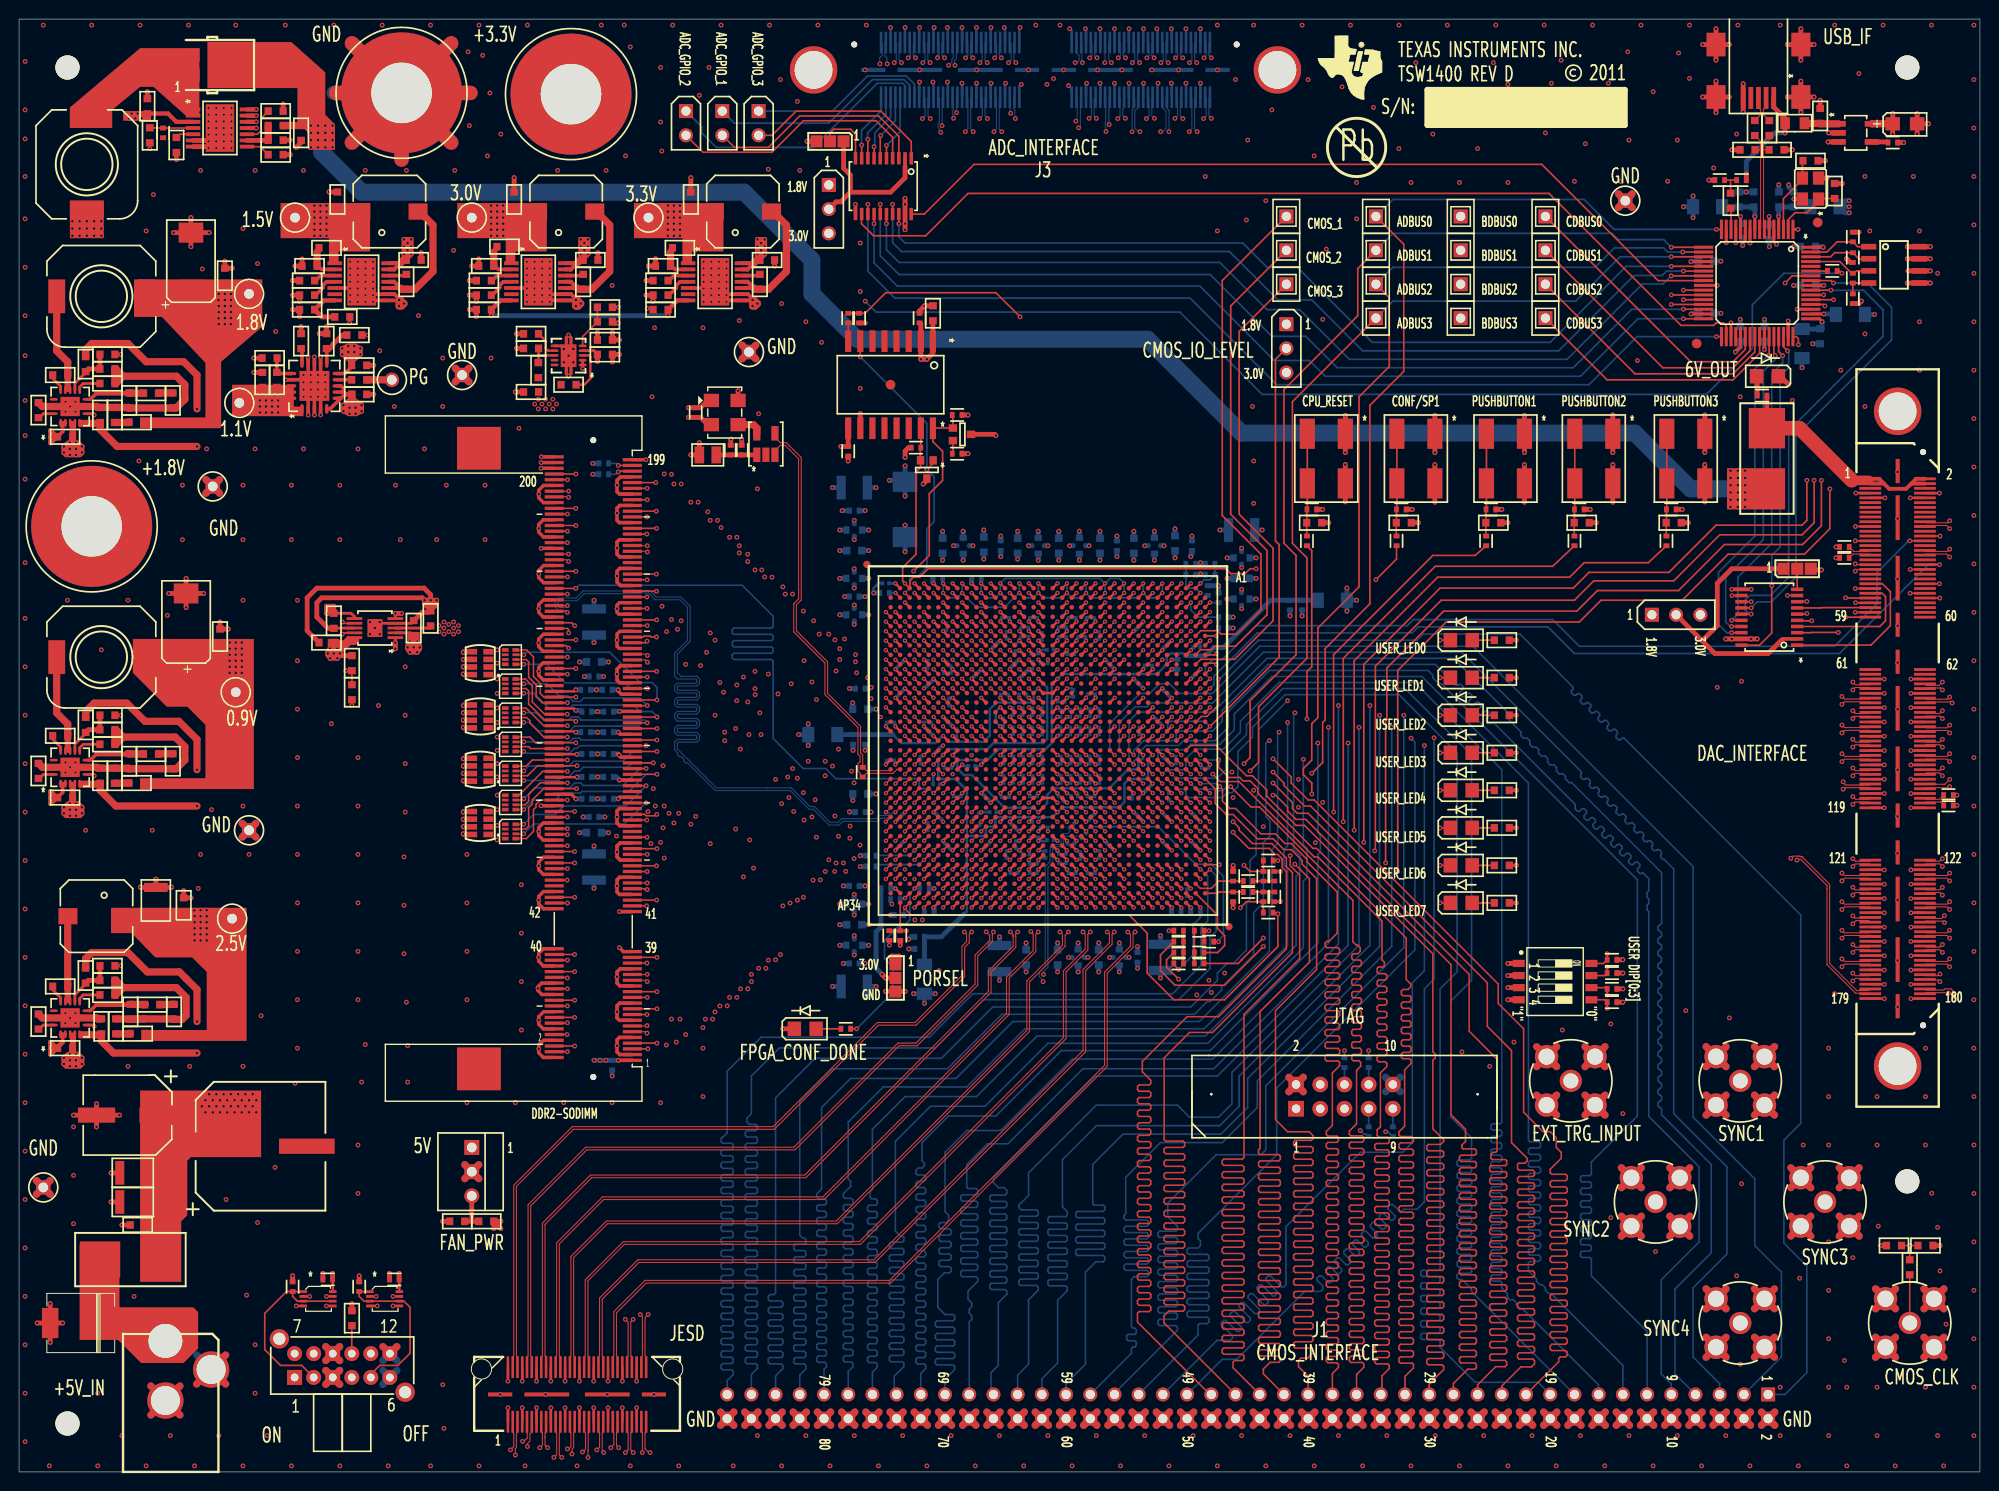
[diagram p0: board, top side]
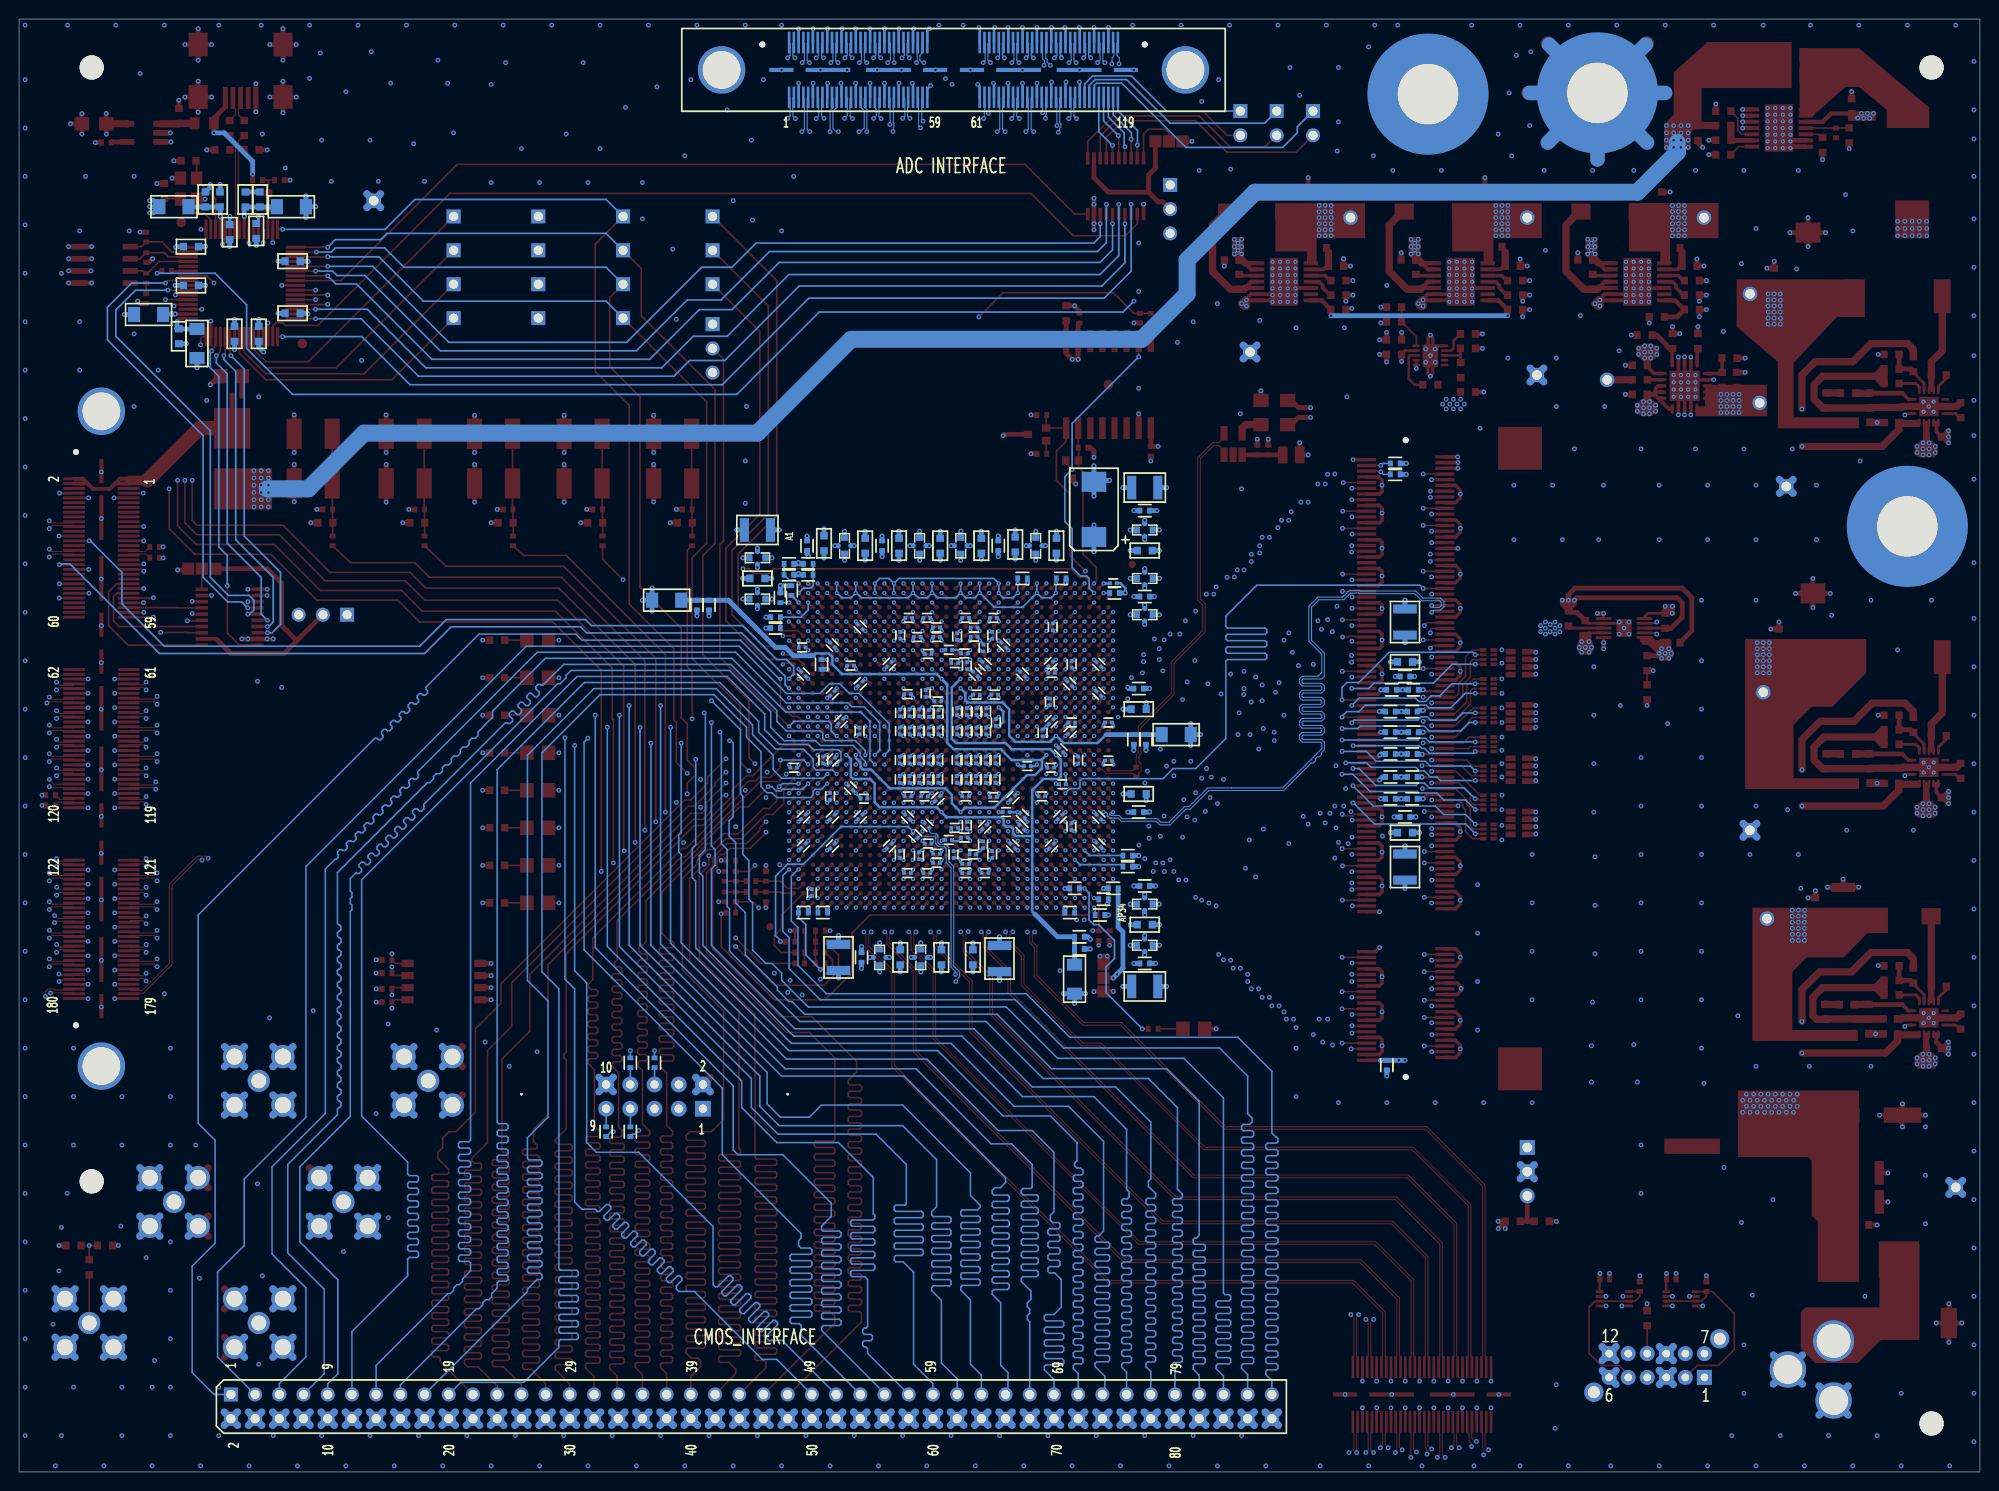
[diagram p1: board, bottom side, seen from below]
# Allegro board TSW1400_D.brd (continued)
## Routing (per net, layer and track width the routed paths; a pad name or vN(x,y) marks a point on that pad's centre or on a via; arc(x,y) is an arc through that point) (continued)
DDR2_DM3: length 82.3
  TOP w0.165: U5.AH13 v2(96.95,81.2) ; J6.67 v1(65.88,66.58)
  L3-SIG1 w0.114: v1(83.66,66.58) 83.66,66.54 83.34,66.22 83.34,65.98 83.45,65.86 83.53,65.86 83.64,65.75 83.64,65.52 83.53,65.41 83.15,65.41 83.03,65.29 83.03,65.06 83.15,64.95 83.53,64.95 83.64,64.83 83.64,64.6 83.53,64.49 83.15,64.49 83.03,64.38 83.03,64.15 83.15,64.03 83.53,64.03 83.64,63.92 83.64,63.69 83.53,63.58 83.45,63.58 83.34,63.46 83.34,63.07 82.85,62.59 82.85,61.9 83.46,61.29 85.01,61.29 85.22,61.09 85.22,60.83 84.96,60.58 83.9,60.58 83.79,60.69 83.79,60.85 83.68,60.96 83.45,60.96 83.33,60.85 83.33,60.69 83.22,60.58 82.93,60.58 82.25,61.26 82.25,61.92 82.36,62.03 82.44,62.03 82.55,62.15 82.55,62.37 82.44,62.49 82.36,62.49 82.25,62.6 82.25,62.84 82.36,62.96 82.5,62.96 82.61,63.07 82.61,63.3 82.5,63.42 82.36,63.42 82.25,63.53 82.25,63.76 82.36,63.87 82.5,63.87 82.61,63.99 82.61,64.22 82.5,64.33 82.36,64.33 82.25,64.44 82.25,64.67 82.36,64.79 82.5,64.79 82.61,64.9 82.61,65.13 82.5,65.24 82.36,65.24 82.25,65.36 82.25,65.59 82.36,65.7 82.5,65.7 82.61,65.82 82.61,66.04 82.5,66.16 82.36,66.16 82.25,66.27 82.25,66.83 82.42,67.01 82.59,67.01 82.78,66.81 82.94,66.81 83.1,66.97 83.1,67.14 82.91,67.33 82.91,67.49 83.07,67.65 83.23,67.65 83.43,67.46 83.59,67.46 83.66,67.53 83.66,67.88 83.78,67.99 83.96,67.99 84.07,68.11 84.07,68.34 83.96,68.45 83.78,68.45 83.66,68.57 83.66,68.79 83.78,68.91 83.96,68.91 84.07,69.02 84.07,69.25 83.96,69.37 83.78,69.37 83.66,69.48 83.66,69.78 83.97,70.09 83.97,70.82 83.66,71.13 83.66,74.26 83.79,74.4 83.79,80.89 v1(83.66,81.02)
  L4-SIG2 w0.102: v2(96.95,81.2) 96.95,81.2 96.33,80.58 95.79,80.58 95.57,80.36 95.57,80.28 95.11,79.82 94.79,79.82 94.36,80.25 94.36,80.33 93.97,80.72
  L4-SIG2 w0.114: 93.97,80.72 90.81,80.72 90.68,80.85 89.74,80.85 89.6,80.71 89.57,80.71 89.53,80.67 88.37,80.67 87.93,81.1 83.75,81.1 v1(83.66,81.02)
  L10-SIG4 w0.114: v1(65.88,66.58) 66.04,66.73 67.87,66.73 68.08,66.52 68.32,66.52 68.43,66.63 68.43,66.84 68.53,66.94 68.78,66.94 68.88,66.84 68.88,66.63 68.99,66.52 69.24,66.52 69.34,66.63 69.34,66.84 69.45,66.94 69.69,66.94 69.8,66.84 69.8,66.63 69.9,66.52 70.15,66.52 70.26,66.63 70.26,66.84 70.36,66.94 70.61,66.94 70.71,66.84 70.71,66.63 70.82,66.52 71.07,66.52 71.17,66.63 71.17,66.84 71.28,66.94 71.52,66.94 71.63,66.84 71.63,66.63 71.73,66.52 71.98,66.52 72.09,66.63 72.09,66.84 72.19,66.94 72.44,66.94 72.54,66.84 72.54,66.63 72.65,66.52 72.89,66.52 73,66.63 73,66.84 73.1,66.94 73.35,66.94 73.46,66.84 73.46,66.63 73.56,66.52 73.81,66.52 73.91,66.63 73.91,66.84 74.02,66.94 74.27,66.94 74.37,66.84 74.37,66.63 74.48,66.52 74.72,66.52 74.83,66.63 74.83,66.84 74.93,66.94 75.18,66.94 75.29,66.84 75.29,66.63 75.39,66.52 75.64,66.52 75.74,66.63 75.74,66.84 75.85,66.94 76.1,66.94 76.3,66.73 77.19,66.73 77.36,66.9 77.65,66.9 77.74,66.82 77.74,66.65 77.82,66.56 78.11,66.56 78.19,66.65 78.19,66.82 78.28,66.9 78.56,66.9 78.65,66.82 78.65,66.65 78.74,66.56 79.02,66.56 79.11,66.65 79.11,66.82 79.19,66.9 79.48,66.9 79.56,66.82 79.56,66.65 79.65,66.56 79.94,66.56 80.02,66.65 80.02,66.82 80.11,66.9 80.39,66.9 80.48,66.82 80.48,66.65 80.56,66.56 80.85,66.56 80.94,66.65 80.94,66.82 81.02,66.9 81.31,66.9 81.39,66.82 81.39,66.65 81.48,66.56 81.76,66.56 81.85,66.65 81.85,66.82 81.94,66.9 82.22,66.9 82.31,66.82 82.31,66.65 82.39,66.56 82.68,66.56 82.85,66.73 83.51,66.73 v1(83.66,66.58)
DDR2_DM4: length 82.2
  TOP w0.165: v1(57.53,85.48) J6.130 ; U5.AM26 v2(92.95,67.2)
  L3-SIG1 w0.114: v1(87.2,67.74) 87.2,68.53 87.6,68.94 87.6,69.44 86.82,70.23 86.82,73.84 87.02,74.04 87.55,74.04 87.76,74.24 87.76,74.75 87.53,74.98 86.97,74.98 86.82,75.13 86.82,76.6 86.98,76.77 87.11,76.77 87.25,76.91 87.25,77.08 87.11,77.22 86.63,77.22 86.51,77.34 86.51,77.57 86.63,77.68 87.11,77.68 87.25,77.82 87.25,78 87.11,78.14 86.63,78.14 86.51,78.25 86.51,78.48 86.63,78.59 87.11,78.59 87.27,78.76 87.27,78.89 87.11,79.05 86.63,79.05 86.51,79.17 86.51,79.39 86.63,79.51 87.11,79.51 87.25,79.65 87.25,79.83 87.11,79.97 86.79,79.97 86.64,80.11 86.64,80.92 86.79,81.08 87.33,81.08 87.48,81.23 87.48,81.53 87.33,81.69 86.79,81.69 86.64,81.84 86.64,82.5 86.79,82.65 87.38,82.65 87.45,82.73 87.45,82.93 87.35,83.03 86.74,83.03 86.63,83.14 86.63,83.35 86.72,83.44 87.33,83.44 87.45,83.57 87.45,83.74 87.33,83.87 86.72,83.87 86.03,84.56 85.6,84.56 85.47,84.68 85.47,85.83 85.6,85.95 85.93,85.95 86.11,85.78 v1(86.11,85.22)
  L4-SIG2 w0.114: v1(57.53,85.48) 57.78,85.72 58.35,85.72 58.55,85.52 58.8,85.52 58.91,85.62 58.91,85.83 59.01,85.93 59.26,85.93 59.36,85.83 59.36,85.62 59.46,85.52 59.72,85.52 59.82,85.62 59.82,85.83 59.92,85.93 60.18,85.93 60.28,85.83 60.28,85.62 60.38,85.52 60.63,85.52 60.73,85.62 60.73,85.83 60.84,85.93 61.09,85.93 61.19,85.83 61.19,85.62 61.29,85.52 61.55,85.52 61.65,85.62 61.65,85.83 61.75,85.93 62,85.93 62.11,85.83 62.11,85.62 62.21,85.52 62.46,85.52 62.56,85.62 62.56,85.83 62.66,85.93 62.92,85.93 63.02,85.83 63.02,85.62 63.12,85.52 63.38,85.52 63.71,85.85 64.14,85.85 65.56,84.43 66.29,84.43 67.32,85.46 67.49,85.46 67.6,85.34 67.83,85.34 67.94,85.46 67.94,85.89 68.06,86 68.29,86 68.4,85.89 68.4,85.46 68.52,85.34 68.74,85.34 68.86,85.46 68.86,85.89 68.97,86 69.2,86 69.32,85.89 69.32,85.46 69.43,85.34 69.66,85.34 69.77,85.46 69.77,85.89 69.89,86 70.12,86 70.23,85.89 70.23,85.46 70.34,85.34 70.57,85.34 70.69,85.46 70.69,85.89 70.8,86 71.03,86 71.14,85.89 71.14,85.79 71.26,85.67 71.58,85.67 71.83,85.42 72.58,85.42 72.81,85.19 73.04,85.19 73.15,85.31 73.15,85.53 73.27,85.65 73.5,85.65 73.61,85.53 73.61,85.31 73.73,85.19 73.95,85.19 74.07,85.31 74.07,85.53 74.18,85.65 74.41,85.65 74.53,85.53 74.53,85.31 74.64,85.19 74.87,85.19 74.98,85.31 74.98,85.53 75.1,85.65 75.33,85.65 75.44,85.53 75.44,85.31 75.56,85.19 75.78,85.19 75.9,85.31 75.9,85.53 76.01,85.65 76.24,85.65 76.36,85.53 76.36,85.31 76.47,85.19 76.7,85.19 76.81,85.31 76.81,85.53 76.93,85.65 77.16,85.65 77.27,85.53 77.27,85.31 77.38,85.19 77.61,85.19 77.73,85.31 77.73,85.53 77.84,85.65 78.07,85.65 78.18,85.53 78.18,85.31 78.3,85.19 78.53,85.19 78.64,85.31 78.64,85.53 78.76,85.65 78.98,85.65 79.1,85.53 79.1,85.31 79.21,85.19 79.44,85.19 79.56,85.31 79.56,85.53 79.67,85.65 79.9,85.65 80.01,85.53 80.01,85.31 80.13,85.19 80.36,85.19 80.58,85.42 81.28,85.42 82.08,84.62 82.66,84.62 83.26,85.22 83.67,85.22 83.87,85.01 84.12,85.01 84.23,85.12 84.23,85.32 84.33,85.42 84.58,85.42 84.68,85.32 84.68,85.12 84.78,85.01 85.04,85.01 85.24,85.22 v1(86.11,85.22)
  L10-SIG4 w0.102: 89.31,67.56 89.48,67.39 90.45,67.39 90.64,67.58 91.22,67.58 91.6,67.2 v2(92.95,67.2)
  L10-SIG4 w0.114: v1(87.2,67.74) 87.2,67.79 87.25,67.74 87.33,67.74 87.5,67.56 89.31,67.56
DDR2_DM5: length 82.3
  TOP w0.165: J6.147 v1(65.89,90.58) ; U5.AH22 v2(96.95,71.2)
  L4-SIG2 w0.102: v2(96.95,71.2) 96.6,71.55 96.14,71.55 96.11,71.58 95.79,71.58 95.76,71.55 95.14,71.55 95.11,71.58 94.79,71.58 94.76,71.55 94.14,71.55 94.11,71.58 93.79,71.58 93.76,71.55 93.14,71.55 93.11,71.58 92.79,71.58 92.76,71.55 92.14,71.55 92.11,71.58 91.79,71.58 91.76,71.55 91.14,71.55 91.11,71.58 90.79,71.58 90.76,71.55 89.59,71.55
  L4-SIG2 w0.114: v1(82.3,71.25) 82.68,71.25 82.93,71.5 89.53,71.5 89.59,71.55
  L9-SIG3 w0.114: v1(82.3,71.25) 82.3,77.67 81.79,78.18 81.79,78.99 81.5,79.28 81.5,79.28 81.38,79.4 81.38,79.62 81.5,79.74 82.08,79.74 82.19,79.85 82.19,80.08 82.08,80.2 81.5,80.2 81.38,80.31 81.38,80.54 81.5,80.65 82.08,80.65 82.19,80.77 82.19,81 82.08,81.11 81.5,81.11 81.38,81.22 81.38,81.45 81.5,81.57 82.08,81.57 82.19,81.68 82.19,81.91 82.08,82.02 81.9,82.02 81.79,82.14 81.79,85.52 81.67,85.64 81.11,85.64 81,85.75 81,85.98 81.11,86.09 82.46,86.09 82.58,86.21 82.58,86.44 82.46,86.55 81.11,86.55 81,86.66 81,86.89 81.11,87.01 82.46,87.01 82.58,87.12 82.58,87.35 82.46,87.46 81.11,87.46 81,87.58 81,87.81 81.11,87.92 82.46,87.92 82.58,88.04 82.58,88.26 82.46,88.38 81.11,88.38 81,88.49 81,88.72 81.11,88.84 82.46,88.84 82.58,88.95 82.58,89.18 82.46,89.29 81.9,89.29 81.79,89.41 81.79,89.79 v1(82.3,90.3)
  L10-SIG4 w0.114: v1(65.89,90.58) 66.14,90.83 66.67,90.83 67.08,91.24 68.28,91.24 68.52,91 68.52,90.67 68.64,90.55 68.86,90.55 68.98,90.67 68.98,91 69.09,91.11 69.32,91.11 69.44,91 69.44,90.67 69.55,90.55 69.78,90.55 69.89,90.67 69.89,91 70.01,91.11 70.24,91.11 70.35,91 70.35,90.67 70.46,90.55 70.69,90.55 70.81,90.67 70.81,91 70.92,91.11 71.15,91.11 71.26,91 71.26,90.67 71.38,90.55 71.61,90.55 71.72,90.67 71.72,91 71.84,91.11 72.06,91.11 72.18,91 72.18,90.67 72.29,90.55 72.52,90.55 72.64,90.67 72.64,91 72.75,91.11 72.98,91.11 73.09,91 73.09,90.67 73.21,90.55 73.44,90.55 73.55,90.67 73.55,91 73.66,91.11 73.89,91.11 74.01,91 74.01,90.67 74.12,90.55 74.35,90.55 74.46,90.67 74.46,91 74.58,91.11 74.81,91.11 74.92,91 74.92,90.67 75.04,90.55 75.26,90.55 75.38,90.67 75.38,91 75.49,91.11 75.72,91.11 75.84,91 75.84,90.67 75.95,90.55 76.18,90.55 76.29,90.67 76.29,91 76.41,91.11 76.64,91.11 76.75,91 76.75,90.67 76.87,90.55 77.09,90.55 77.21,90.67 77.21,91 77.32,91.11 77.55,91.11 77.67,91 77.67,90.67 77.78,90.55 78.01,90.55 78.12,90.67 78.12,91 78.24,91.11 78.47,91.11 78.58,91 78.58,90.67 78.69,90.55 78.92,90.55 79.04,90.67 79.04,91 79.15,91.11 79.38,91.11 79.49,91 79.49,90.67 79.61,90.55 79.84,90.55 79.95,90.67 79.95,91 80.07,91.11 80.29,91.11 80.41,91 80.41,90.67 80.52,90.55 80.75,90.55 80.87,90.67 80.87,91 80.98,91.11 82.65,91.11 82.83,90.93 82.83,90.55 82.75,90.47 82.47,90.47 v1(82.3,90.3)
DDR2_DM6: length 82.2
  TOP w0.165: U5.AM17 v2(92.95,77.2) ; J6.170 v1(57.53,97.48)
  L3-SIG1 w0.114: v1(75.31,98.04) 74.93,97.66 74.93,95.89 75.19,95.62 75.32,95.62 75.44,95.51 75.44,95.28 75.32,95.17 74.54,95.17 74.42,95.05 74.42,94.82 74.54,94.71 75.32,94.71 75.44,94.59 75.44,94.37 75.32,94.25 74.54,94.25 74.42,94.14 74.42,93.91 74.54,93.79 75.32,93.79 75.44,93.68 75.44,93.45 75.32,93.34 74.54,93.34 74.42,93.22 74.42,92.99 74.54,92.88 75.32,92.88 75.44,92.77 75.44,92.54 75.32,92.42 74.54,92.42 74.42,92.31 74.42,92.08 74.54,91.97 75.32,91.97 75.44,91.85 75.44,91.62 75.32,91.51 74.54,91.51 74.42,91.39 74.42,91.17 74.54,91.05 75.32,91.05 75.44,90.94 75.44,90.71 75.32,90.59 74.54,90.59 74.42,90.48 74.42,90.25 74.54,90.14 75.32,90.14 75.44,90.02 75.44,89.79 75.32,89.68 74.54,89.68 74.42,89.57 74.42,89.34 74.54,89.22 75.32,89.22 75.44,89.11 75.44,88.88 75.32,88.77 74.54,88.77 74.42,88.65 74.42,88.42 74.54,88.31 75.32,88.31 75.44,88.19 75.44,87.97 75.32,87.85 74.54,87.85 74.42,87.74 74.42,87.51 74.54,87.39 75.32,87.39 75.44,87.28 75.44,87.05 75.32,86.94 74.54,86.94 74.42,86.82 74.42,86.59 74.54,86.48 75.32,86.48 75.44,86.37 75.44,86.14 75.32,86.02 74.54,86.02 74.42,85.91 74.42,85.68 74.54,85.57 75.32,85.57 75.44,85.45 75.44,85.22 75.32,85.11 74.54,85.11 74.42,84.99 74.42,84.77 74.8,84.38 74.8,83.06 74.42,82.68 74.42,78.47 74.47,78.42 74.47,77.14 v1(74.04,76.71)
  L4-SIG2 w0.102: v2(92.95,77.2) 92.83,77.32 90.81,77.32
  L4-SIG2 w0.114: v1(57.53,97.48) 57.82,97.76 74,97.76 74.17,97.59 74.86,97.59 v1(75.31,98.04) ; v1(74.04,76.71) 75.13,76.71 75.39,76.96 76.38,76.96 76.41,76.93 76.75,76.93 76.78,76.96 77.65,76.96 77.68,76.93 78.02,76.93 78.05,76.96 81.59,76.96 81.62,76.93 81.96,76.93 81.99,76.96 82.17,76.96 82.68,77.47 90.2,77.47 90.35,77.32 90.81,77.32
DDR2_DM7: length 82.3
  TOP w0.165: J6.185 v1(65.91,101.98) ; U5.AM25 v2(92.95,68.2)
  L4-SIG2 w0.102: 90.42,68.58 90.79,68.58 92.57,68.58 v2(92.95,68.2)
  L4-SIG2 w0.114: v1(70.48,67.94) 77.1,67.94 77.35,67.69 82.03,67.69 82.06,67.65 82.82,67.65 83.11,67.94 83.74,67.94 84.15,68.35 86.38,68.35 86.53,68.5 86.94,68.5 86.94,68.51 87.95,68.51 88.14,68.33 90.17,68.33 90.42,68.58
  L9-SIG3 w0.114: v1(70.48,101.73) 70.48,100.7 70.6,100.58 70.8,100.58 70.92,100.47 70.92,100.24 70.8,100.12 70.17,100.12 70.05,100.01 70.05,99.78 70.17,99.67 70.8,99.67 70.92,99.55 70.92,99.32 70.8,99.21 70.17,99.21 70.05,99.1 70.05,98.87 70.17,98.75 70.8,98.75 70.92,98.64 70.92,98.41 70.8,98.3 70.17,98.3 70.05,98.18 70.05,97.95 70.17,97.84 70.8,97.84 70.92,97.72 70.92,97.5 70.8,97.38 70.17,97.38 70.05,97.27 70.05,97.04 70.17,96.92 70.8,96.92 70.92,96.81 70.92,96.58 70.8,96.47 70.17,96.47 70.05,96.35 70.05,96.12 70.17,96.01 70.8,96.01 70.92,95.9 70.92,95.67 70.8,95.55 70.17,95.55 70.05,95.44 70.05,95.21 70.17,95.1 70.8,95.1 70.92,94.98 70.92,94.75 70.8,94.64 70.17,94.64 70.05,94.52 70.05,94.3 70.17,94.18 70.8,94.18 70.92,94.07 70.92,93.84 70.8,93.72 70.17,93.72 70.05,93.61 70.05,93.38 70.17,93.27 70.8,93.27 70.92,93.15 70.92,92.92 70.8,92.81 70.17,92.81 70.05,92.7 70.05,92.47 70.17,92.35 70.8,92.35 70.92,92.24 70.92,92.01 70.8,91.89 70.17,91.89 70.05,91.78 70.05,91.55 70.17,91.44 70.8,91.44 70.92,91.32 70.92,91.09 70.8,90.98 70.17,90.98 70.05,90.87 70.05,90.64 70.17,90.52 70.8,90.52 70.92,90.41 70.92,90.18 70.8,90.07 70.17,90.07 70.05,89.95 70.05,89.72 70.17,89.61 70.8,89.61 70.92,89.49 70.92,89.27 70.48,88.83 70.48,85.22 70.84,84.86 70.84,69.52 70.48,69.16 v1(70.48,67.94)
  L10-SIG4 w0.114: v1(65.91,101.98) 66.16,101.73 v1(70.48,101.73)
DDR2_DQ0: length 82.2
  TOP w0.165: U5.AP4 v2(90.95,90.2) ; J6.5 v1(65.97,44.38)
  L3-SIG1 w0.114: v1(68.45,89.41) 68.45,88.04 68.61,87.88 68.61,70.11 67.76,69.27 67.76,68.26 68.45,67.56 68.45,63.9 68.35,63.8 68.35,63.55 68.66,63.24 68.66,62.99 68.55,62.89 68.35,62.89 68.25,62.78 68.25,62.53 68.35,62.43 68.55,62.43 68.66,62.33 68.66,62.07 68.55,61.97 68.35,61.97 68.25,61.87 68.25,61.62 68.35,61.51 68.55,61.51 68.66,61.41 68.66,61.16 68.55,61.06 68.35,61.06 68.25,60.95 68.25,60.7 68.35,60.6 68.55,60.6 68.66,60.5 68.66,60.24 68.55,60.14 68.35,60.14 68.25,60.04 68.25,59.79 68.35,59.68 68.55,59.68 68.66,59.58 68.66,59.33 68.55,59.23 68.35,59.23 68.25,59.13 68.25,58.87 68.35,58.77 68.55,58.77 68.66,58.67 68.66,58.41 68.55,58.31 68.35,58.31 68.25,58.21 68.25,57.96 68.35,57.86 68.55,57.86 68.66,57.75 68.66,57.5 68.55,57.4 68.35,57.4 68.25,57.3 68.25,57.04 68.35,56.94 68.55,56.94 68.66,56.84 68.66,56.59 68.55,56.48 68.35,56.48 68.25,56.38 68.25,56.13 68.35,56.03 68.55,56.03 68.66,55.93 68.66,55.67 68.55,55.57 68.35,55.57 68.25,55.47 68.25,55.21 68.35,55.11 68.55,55.11 68.66,55.01 68.66,54.76 68.55,54.66 68.35,54.66 68.25,54.55 68.25,54.3 68.35,54.2 68.55,54.2 68.66,54.1 68.66,53.84 68.55,53.74 68.35,53.74 68.25,53.64 68.25,53.39 68.35,53.28 68.55,53.28 68.66,53.18 68.66,52.93 68.55,52.83 68.35,52.83 68.25,52.73 68.25,52.47 68.35,52.37 68.55,52.37 68.66,52.27 68.66,52.01 68.55,51.91 68.35,51.91 68.25,51.81 68.25,51.56 68.35,51.46 68.55,51.46 68.66,51.35 68.66,51.1 68.55,51 68.35,51 68.25,50.9 68.25,50.64 68.35,50.54 68.55,50.54 68.66,50.44 68.66,50.19 68.55,50.08 68.35,50.08 68.25,49.98 68.25,49.73 68.35,49.63 68.55,49.63 68.66,49.52 68.66,49.27 68.55,49.17 68.35,49.17 68.25,49.07 68.25,48.81 68.35,48.71 68.41,48.71 68.63,48.49 68.63,48.33 68.45,48.15 v1(68.45,47.5)
  L4-SIG2 w0.102: 90.42,90.2 v2(90.95,90.2)
  L4-SIG2 w0.114: v1(68.45,89.41) 69.47,90.42 81.8,90.42 82.72,91.34 89.28,91.34 90.42,90.2
  L10-SIG4 w0.114: v1(68.45,47.5) 65.97,45.01 v1(65.97,44.38)
DDR2_DQ1: length 82.2
  TOP w0.165: J6.7 v1(66.93,44.98) ; U5.AP5 v2(90.95,89.2)
  L3-SIG1 w0.114: v1(69.34,47.5) 69.34,48.27 69.55,48.48 69.55,48.73 69.44,48.83 69.24,48.83 69.14,48.93 69.14,49.19 69.24,49.29 69.44,49.29 69.55,49.39 69.55,49.65 69.44,49.75 69.24,49.75 69.14,49.85 69.14,50.1 69.24,50.2 69.44,50.2 69.55,50.31 69.55,50.56 69.44,50.66 69.24,50.66 69.14,50.76 69.14,51.02 69.24,51.12 69.44,51.12 69.55,51.22 69.55,51.47 69.44,51.58 69.24,51.58 69.14,51.68 69.14,51.93 69.24,52.03 69.44,52.03 69.55,52.13 69.55,52.39 69.44,52.49 69.24,52.49 69.14,52.59 69.14,52.85 69.24,52.95 69.44,52.95 69.55,53.05 69.55,53.3 69.44,53.4 69.24,53.4 69.14,53.51 69.14,53.76 69.24,53.86 69.44,53.86 69.55,53.96 69.55,54.22 69.44,54.32 69.24,54.32 69.14,54.42 69.14,54.67 69.24,54.78 69.44,54.78 69.55,54.88 69.55,55.13 69.44,55.23 69.24,55.23 69.14,55.33 69.14,55.59 69.24,55.69 69.44,55.69 69.55,55.79 69.55,56.05 69.44,56.15 69.24,56.15 69.14,56.25 69.14,56.5 69.24,56.6 69.44,56.6 69.55,56.71 69.55,56.96 69.44,57.06 69.24,57.06 69.14,57.16 69.14,57.42 69.24,57.52 69.44,57.52 69.55,57.62 69.55,57.87 69.44,57.98 69.24,57.98 69.14,58.08 69.14,58.33 69.24,58.43 69.44,58.43 69.55,58.54 69.55,58.79 69.44,58.89 69.24,58.89 69.14,58.99 69.14,59.25 69.24,59.35 69.44,59.35 69.55,59.45 69.55,59.7 69.44,59.81 69.24,59.81 69.14,59.91 69.14,60.16 69.24,60.26 69.44,60.26 69.55,60.36 69.55,60.62 69.44,60.72 69.24,60.72 69.14,60.82 69.14,61.08 69.24,61.18 69.44,61.18 69.55,61.28 69.55,61.53 69.44,61.63 69.24,61.63 69.14,61.74 69.14,61.99 69.24,62.09 69.44,62.09 69.55,62.19 69.55,62.45 69.44,62.55 69.24,62.55 69.14,62.65 69.14,62.9 69.24,63.01 69.44,63.01 69.55,63.11 69.55,63.36 69.44,63.46 69.24,63.46 69.14,63.56 69.14,63.82 69.24,63.92 69.44,63.92 69.55,64.02 69.55,64.28 69.44,64.38 69.24,64.38 69.14,64.48 69.14,64.73 69.24,64.83 69.44,64.83 69.55,64.94 69.55,65.19 69.32,65.42 69.32,65.82 69.65,66.16 69.65,83.6 69.47,83.79 69.47,85.25 69.98,85.76 69.98,88.77 v1(69.47,89.28)
  L4-SIG2 w0.102: 90.25,89.61 90.54,89.61 v2(90.95,89.2)
  L4-SIG2 w0.114: v1(69.47,89.28) 70.03,89.84 82.73,89.84 83.31,90.42 89.43,90.42 90.25,89.61
  L10-SIG4 w0.114: v1(69.34,47.5) 66.93,45.09 v1(66.93,44.98)
DDR2_DQ2: length 82.2
  TOP w0.165: J6.17 v1(65.89,47.98) ; U5.AP6 v2(90.95,88.2)
  L3-SIG1 w0.114: v1(72.77,47.5) 72.39,47.88 72.39,48.54 72.62,48.77 72.62,49 72.5,49.11 72.28,49.11 72.16,49.22 72.16,49.45 72.28,49.57 72.5,49.57 72.62,49.68 72.62,49.91 72.5,50.02 72.28,50.02 72.16,50.14 72.16,50.37 72.28,50.48 72.5,50.48 72.62,50.6 72.62,50.82 72.5,50.94 72.28,50.94 72.16,51.05 72.16,51.28 72.28,51.4 72.5,51.4 72.62,51.51 72.62,51.74 72.5,51.85 72.28,51.85 72.16,51.97 72.16,52.2 72.28,52.31 72.5,52.31 72.62,52.42 72.62,52.65 72.5,52.77 72.28,52.77 72.16,52.88 72.16,53.11 72.28,53.22 72.5,53.22 72.62,53.34 72.62,53.57 72.5,53.68 72.28,53.68 72.16,53.8 72.16,54.02 72.28,54.14 72.5,54.14 72.62,54.25 72.62,54.48 72.5,54.6 72.28,54.6 72.16,54.71 72.16,54.94 72.28,55.05 72.5,55.05 72.62,55.17 72.62,55.4 72.5,55.51 72.35,55.51 72.24,55.63 72.24,55.93 72.39,56.08 72.39,65.17 72.96,65.73 72.96,66.09 72.39,66.66 72.39,67.31 72.24,67.46 72.24,67.77 72.31,67.84 72.47,67.84 72.54,67.92 72.54,68.22 72.47,68.3 72.31,68.3 72.24,68.38 72.24,68.68 72.31,68.76 72.47,68.76 72.54,68.83 72.54,69.14 72.47,69.21 72.31,69.21 72.24,69.29 72.24,69.59 72.31,69.67 72.47,69.67 72.54,69.75 72.54,70.05 72.47,70.13 72.31,70.13 72.24,70.2 72.24,70.51 72.31,70.59 72.47,70.59 72.54,70.66 72.54,70.97 72.47,71.04 72.31,71.04 72.24,71.12 72.24,71.42 72.31,71.5 72.47,71.5 72.54,71.58 72.54,71.88 72.47,71.96 72.31,71.96 72.24,72.03 72.24,72.34 72.31,72.41 72.47,72.41 72.54,72.49 72.54,72.79 72.47,72.87 72.31,72.87 72.24,72.95 72.24,73.25 72.31,73.33 72.47,73.33 72.54,73.4 72.54,73.71 72.47,73.79 72.31,73.79 72.24,73.86 72.24,74.17 72.31,74.24 72.47,74.24 72.54,74.32 72.54,74.62 72.47,74.7 72.31,74.7 72.24,74.78 72.24,75.08 72.31,75.16 72.47,75.16 72.54,75.23 72.54,75.54 72.47,75.61 72.31,75.61 72.24,75.69 72.24,76 72.31,76.07 72.47,76.07 72.54,76.15 72.54,76.45 72.47,76.53 72.31,76.53 72.24,76.6 72.24,76.91 72.31,76.99 72.47,76.99 72.54,77.06 72.54,77.37 72.47,77.44 72.31,77.44 72.24,77.52 72.24,77.82 72.31,77.9 72.47,77.9 72.54,77.98 72.54,78.28 72.47,78.36 72.31,78.36 72.24,78.43 72.24,78.74 72.31,78.81 72.47,78.81 72.54,78.89 72.54,79.2 72.47,79.27 72.31,79.27 72.24,79.35 72.24,79.65 72.31,79.73 72.47,79.73 72.54,79.81 72.54,80.11 72.47,80.19 72.31,80.19 72.24,80.26 72.24,80.57 72.31,80.64 72.47,80.64 72.54,80.72 72.54,81.02 72.47,81.1 72.31,81.1 72.24,81.18 72.24,81.48 72.31,81.56 72.47,81.56 72.54,81.63 72.54,81.94 72.47,82.02 72.31,82.02 72.24,82.09 72.24,82.4 72.31,82.47 72.47,82.47 72.54,82.55 72.54,82.85 72.47,82.93 72.31,82.93 72.24,83.01 72.24,83.31 72.31,83.39 72.47,83.39 72.54,83.46 72.54,83.77 72.47,83.84 72.31,83.84 72.24,83.92 72.24,84.22 72.64,84.63 72.64,86.36 72.52,86.49 v1(72.52,88.01)
  L4-SIG2 w0.102: v2(90.95,88.2) 90.79,88.04 90.26,88.04
  L4-SIG2 w0.114: v1(72.52,88.01) 72.71,88.2 83.62,88.2 83.69,88.27 83.74,88.27 83.78,88.3 83.84,88.3 83.89,88.35 86.89,88.35 87.21,88.04 90.26,88.04
  L10-SIG4 w0.114: v1(72.77,47.5) 72.29,47.98 v1(65.89,47.98)
DDR2_DQ3: length 82.2
  TOP w0.165: U5.AP7 v2(90.95,87.2) ; J6.19 v1(66.93,48.58)
  L4-SIG2 w0.102: v2(90.95,87.2) 90.86,87.2 90.53,87.53
  L4-SIG2 w0.114: v1(73.03,87.25) 73.18,87.25 73.3,87.38 85.08,87.38 85.51,87.81 87.02,87.81 87.3,87.53 90.53,87.53
  L9-SIG3 w0.114: v1(73.03,87.25) 73.18,87.1 73.18,83.95 72.52,83.29 72.52,74.8 73.03,74.3 73.03,64.95 72.92,64.85 72.54,64.85 72.44,64.74 72.44,64.47 72.53,64.38 72.91,64.38 73.03,64.26 73.03,64.03 72.91,63.92 72.58,63.92 72.47,63.81 72.47,63.58 72.58,63.46 72.91,63.46 73.03,63.35 73.03,63.12 72.91,63.01 72.58,63.01 72.47,62.89 72.47,62.66 72.58,62.55 72.91,62.55 73.03,62.43 73.03,62.21 72.91,62.09 72.58,62.09 72.47,61.98 72.47,61.75 72.58,61.63 72.91,61.63 73.03,61.52 73.03,61.29 72.91,61.18 72.58,61.18 72.47,61.06 72.47,60.83 72.58,60.72 72.91,60.72 73.03,60.61 73.03,60.38 72.91,60.26 72.58,60.26 72.47,60.15 72.47,59.92 72.58,59.81 72.91,59.81 73.03,59.69 73.03,59.46 72.91,59.35 72.58,59.35 72.47,59.23 72.47,59.01 72.58,58.89 72.91,58.89 73.03,58.78 73.03,58.55 72.91,58.43 72.58,58.43 72.47,58.32 72.47,58.09 72.58,57.98 72.91,57.98 73.03,57.86 73.03,57.63 72.91,57.52 72.58,57.52 72.47,57.41 72.47,57.18 72.58,57.06 72.91,57.06 73.03,56.95 73.03,56.72 72.91,56.61 72.58,56.61 72.47,56.49 72.47,56.26 72.58,56.15 72.91,56.15 73.03,56.03 73.03,55.8 72.91,55.69 72.58,55.69 72.47,55.58 72.47,55.35 72.58,55.23 72.91,55.23 73.03,55.12 73.03,54.89 72.91,54.78 72.58,54.78 72.47,54.66 72.47,54.43 72.58,54.32 72.91,54.32 73.03,54.2 73.03,53.98 72.91,53.86 72.58,53.86 72.47,53.75 72.47,53.52 72.58,53.4 72.91,53.4 73.03,53.29 73.03,53.06 72.91,52.95 72.58,52.95 72.47,52.83 72.47,52.6 72.58,52.49 72.91,52.49 73.03,52.38 73.03,52.15 72.91,52.03 72.58,52.03 72.47,51.92 72.47,51.69 72.58,51.58 72.91,51.58 73.03,51.46 73.03,51.23 72.91,51.12 72.58,51.12 72.47,51 72.47,50.78 72.58,50.66 72.91,50.66 73.03,50.55 73.03,50.32 72.91,50.2 72.58,50.2 72.47,50.09 72.47,49.86 72.58,49.75 72.58,49.75 72.82,49.5 72.82,49.34 72.52,49.03 72.52,48.56 72.82,48.26 v1(73.03,48.26)
  L10-SIG4 w0.114: v1(66.93,48.58) 72.71,48.58 v1(73.03,48.26)
DDR2_DQ4: length 82.3
  TOP w0.165: U5.AN6 v2(91.95,88.2) ; v1(57.53,44.08) J6.4
  L4-SIG2 w0.102: 90.34,88.49 90.6,88.49 90.7,88.59 91.5,88.59 91.89,88.2 v2(91.95,88.2)
  L4-SIG2 w0.114: v1(67.92,44.78) 67.03,43.89 57.72,43.89 v1(57.53,44.08) ; v1(67.94,88.15) 67.95,88.14 68.45,88.14 68.71,87.88 69.47,87.88 69.72,88.14 70.99,88.14 71.45,88.6 82.64,88.6 82.68,88.56 83.62,88.56 83.66,88.59 83.72,88.59 83.9,88.77 87,88.77 87.28,88.49 90.34,88.49
  L9-SIG3 w0.114: v1(67.92,44.78) 67.92,56.9 68.88,57.86 68.88,67.03 68.1,67.82 68.1,68.43 67.76,68.76 67.76,69.27 68.2,69.71 68.2,74.17 67.94,74.42 v1(67.94,88.15)
DDR2_DQ5: length 82.2
  TOP w0.165: U5.AN5 v2(91.95,89.2) ; v1(58.29,44.68) J6.6
  L4-SIG2 w0.102: v2(91.95,89.2) 91.87,89.2 91.49,88.82 90.61,88.82 90.43,89 90.14,89
  L4-SIG2 w0.114: v1(68.96,45.09) 68.58,45.47 66.67,45.47 66.17,44.96 63.3,44.96 63.12,45.14 62.1,45.14 61.64,44.68 v1(58.29,44.68) ; v1(69.09,88.39) 69.22,88.52 70.36,88.52 70.87,89.03 82.78,89.03 82.96,88.85 83.5,88.85 83.53,88.88 83.6,88.88 84.12,89.41 89.53,89.41 89.94,89 90.14,89
  L9-SIG3 w0.114: v1(69.09,88.39) 69.09,69.62 68.78,69.31 68.78,68.82 69.29,68.31 69.29,56.74 68.9,56.36 68.9,50.14 69.04,50.01 69.04,49.68 68.97,49.62 68.84,49.62 68.77,49.55 68.77,49.23 69.04,48.96 69.04,48.77 68.9,48.64 68.9,45.14 v1(68.96,45.09)
DDR2_DQ6: length 82.2
  TOP w0.165: J6.14 57.49,47.08 v1(57.53,47.12) ; U5.AN9 v2(91.95,85.2)
  L3-SIG1 w0.114: v1(71.5,84.58) 71.43,84.51 71.43,67.35 71.37,67.29 71.37,60.88 71.25,60.75 71.25,60.42 71.31,60.36 71.44,60.36 71.5,60.29 71.5,59.96 71.44,59.9 71.31,59.9 71.25,59.84 71.25,59.51 71.31,59.44 71.44,59.44 71.5,59.38 71.5,59.05 71.44,58.98 71.31,58.98 71.25,58.92 71.25,58.59 71.31,58.53 71.44,58.53 71.5,58.46 71.5,58.13 71.44,58.07 71.31,58.07 71.25,58.01 71.25,57.68 71.31,57.61 71.44,57.61 71.5,57.55 71.5,57.22 71.44,57.16 71.31,57.16 71.25,57.09 71.25,56.76 71.31,56.7 71.44,56.7 71.5,56.64 71.5,56.31 71.44,56.24 71.31,56.24 71.25,56.18 71.25,55.85 71.31,55.78 71.44,55.78 71.5,55.72 71.5,55.39 71.44,55.33 71.31,55.33 71.25,55.26 71.25,54.93 71.31,54.87 71.44,54.87 71.5,54.81 71.5,54.48 71.44,54.41 71.31,54.41 71.25,54.35 71.25,54.02 71.31,53.96 71.44,53.96 71.5,53.89 71.5,53.56 71.44,53.5 71.31,53.5 71.25,53.43 71.25,53.1 71.31,53.04 71.44,53.04 71.5,52.98 71.5,52.65 71.44,52.58 71.31,52.58 71.25,52.52 71.25,52.19 71.31,52.13 71.44,52.13 71.5,52.06 71.5,51.73 71.44,51.67 71.31,51.67 71.25,51.61 71.25,51.28 71.31,51.21 71.44,51.21 71.5,51.15 71.5,50.82 71.44,50.76 71.31,50.76 71.25,50.69 71.25,50.36 71.31,50.3 71.44,50.3 71.5,50.23 71.5,49.9 71.44,49.84 71.31,49.84 71.25,49.78 71.25,49.45 71.31,49.38 71.44,49.38 71.5,49.32 71.5,48.99 71.44,48.93 71.31,48.93 71.25,48.86 71.25,48.53 71.31,48.47 71.44,48.47 71.5,48.41 71.5,48.08 71.37,47.95 71.37,46.99 v1(71.75,46.61)
  L4-SIG2 w0.102: v2(91.95,85.2) 91.5,85.2 91.11,85.59 90.79,85.59 90.77,85.57
  L4-SIG2 w0.114: v1(71.75,46.61) 71.7,46.61 71.3,47.02 68.15,47.02 67.87,47.3 65.73,47.3 65.73,47.3 62.03,47.3 61.85,47.12 v1(57.53,47.12) ; v1(71.5,84.58) 71.75,84.84 79.38,84.84 79.93,84.28 83.01,84.28 83.34,84.61 84.23,84.61 84.43,84.4 85.22,84.4 85.42,84.61 86.28,84.61 87.12,85.45 87.12,85.75 87.55,86.18 89.81,86.18 90.43,85.57 90.77,85.57
DDR2_DQ7: length 82.3
  TOP w0.165: J6.16 v1(58.29,47.68) ; U5.AP9 v2(90.95,85.2)
  L4-SIG2 w0.114: v1(72.01,47.5) 71.5,48.01 66.48,48.01 66.07,48.42 65.43,48.42 64.7,47.68 v1(58.29,47.68)
  L9-SIG3 w0.114: v1(72.01,47.5) 71.5,48.01 71.5,48.75 71.63,48.88 71.63,49.21 71.56,49.28 71.44,49.28 71.37,49.34 71.37,49.67 71.44,49.73 71.56,49.73 71.63,49.8 71.63,50.13 71.56,50.19 71.44,50.19 71.37,50.25 71.37,50.58 71.44,50.65 71.56,50.65 71.63,50.71 71.63,51.04 71.56,51.1 71.44,51.1 71.37,51.17 71.37,51.5 71.44,51.56 71.56,51.56 71.63,51.63 71.63,51.96 71.56,52.02 71.44,52.02 71.37,52.08 71.37,52.41 71.44,52.48 71.56,52.48 71.63,52.54 71.63,52.87 71.56,52.93 71.44,52.93 71.37,53 71.37,53.33 71.44,53.39 71.56,53.39 71.63,53.45 71.63,53.78 71.56,53.85 71.44,53.85 71.37,53.91 71.37,54.24 71.44,54.3 71.56,54.3 71.63,54.37 71.63,54.7 71.56,54.76 71.44,54.76 71.37,54.83 71.37,55.16 71.44,55.22 71.56,55.22 71.63,55.28 71.63,55.61 71.56,55.68 71.44,55.68 71.37,55.74 71.37,56.07 71.44,56.13 71.56,56.13 71.63,56.2 71.63,56.53 71.56,56.59 71.44,56.59 71.37,56.65 71.37,56.98 71.44,57.05 71.56,57.05 71.63,57.11 71.63,57.44 71.56,57.51 71.44,57.51 71.37,57.57 71.37,57.9 71.44,57.96 71.56,57.96 71.63,58.03 71.63,58.36 71.56,58.42 71.44,58.42 71.37,58.48 71.37,58.81 71.44,58.88 71.56,58.88 71.63,58.94 71.63,59.27 71.56,59.33 71.44,59.33 71.37,59.4 71.37,59.73 71.44,59.79 71.56,59.79 71.63,59.85 71.63,60.18 71.56,60.25 71.44,60.25 71.37,60.31 71.37,60.64 71.44,60.71 71.56,60.71 71.63,60.77 71.63,61.1 71.56,61.16 71.44,61.16 71.37,61.23 71.37,61.56 71.44,61.62 71.56,61.62 71.63,61.68 71.63,62.01 71.56,62.08 71.44,62.08 71.37,62.14 71.37,62.47 71.44,62.53 71.56,62.53 71.63,62.6 71.63,62.93 71.56,62.99 71.44,62.99 71.37,63.06 71.37,63.39 71.44,63.45 71.56,63.45 71.63,63.51 71.63,63.84 71.56,63.91 71.44,63.91 71.37,63.97 71.37,64.3 71.44,64.36 71.56,64.36 71.63,64.43 71.63,64.76 71.56,64.82 71.44,64.82 71.37,64.88 71.37,65.21 71.44,65.28 71.56,65.28 71.63,65.34 71.63,65.67 71.5,65.8 71.5,69.42 71.37,69.55 71.37,83.74 72.14,84.51 v1(72.14,85.98)
  L10-SIG4 w0.114: v2(90.95,85.2) 90.3,85.2 90.29,85.19 88.91,85.19 87.86,86.23 86.56,86.23 86.28,85.95 85.94,85.95 85.9,85.98 v1(72.14,85.98)
DDR2_DQ8: length 82.3
  TOP w0.165: U5.AM13 v2(92.95,81.2) ; J6.23 v1(65.91,49.78)
  L9-SIG3 w0.102: v2(92.95,81.2) 93.23,81.48 93.25,81.48 93.43,81.66 95.12,81.66 95.38,81.41 95.38,80.19 95.81,79.76 96.06,79.76 96.44,79.38 96.44,77.05 96.78,76.71 97.16,76.71 97.41,76.45 97.41,65.05 96.01,63.65 95.78,63.65 95.5,63.37 95.5,63.14 95.05,62.69 94.82,62.69 94.46,62.33 94.46,62.08 94.11,61.72 93.85,61.72 92.84,60.71 91.41,60.71
  L9-SIG3 w0.114: v1(74.55,49.78) 74.55,49.78 75.08,49.25 81.64,49.25 81.93,49.54 81.93,49.7 80.95,50.68 80.95,50.85 81.11,51.01 81.27,51.01 82.25,50.03 82.41,50.03 82.57,50.19 82.57,50.35 81.59,51.33 81.59,51.49 81.75,51.65 81.92,51.65 82.9,50.67 83.06,50.67 83.22,50.84 83.22,51 82.24,51.98 82.24,52.14 82.4,52.3 82.56,52.3 83.54,51.32 83.7,51.32 83.87,51.48 83.87,51.64 82.89,52.62 82.89,52.79 83.05,52.95 83.21,52.95 84.19,51.97 84.35,51.97 84.51,52.13 84.51,52.29 83.53,53.27 83.53,53.43 83.69,53.59 83.86,53.59 84.84,52.61 85,52.61 85.16,52.77 85.16,52.94 84.18,53.92 84.18,54.08 84.34,54.24 84.5,54.24 85.48,53.26 85.64,53.26 85.81,53.42 85.81,53.58 84.83,54.56 84.83,54.73 84.99,54.89 85.15,54.89 85.43,54.61 87,54.61 89.66,57.28 89.66,58.95 91.41,60.71
  L10-SIG4 w0.114: v1(65.91,49.78) v1(74.55,49.78)
DDR2_DQ9: length 82.2
  TOP w0.165: U5.AL12 v2(93.95,82.2) ; J6.25 v1(66.93,50.38)
  L9-SIG3 w0.114: v1(75.31,49.78) 75.18,49.91 75.18,51.38 75.3,51.49 75.35,51.49 75.46,51.61 75.46,51.84 75.35,51.95 75.02,51.95 74.9,52.06 74.9,52.29 75.02,52.41 75.35,52.41 75.46,52.52 75.46,52.75 75.35,52.86 75.02,52.86 74.9,52.98 74.9,53.21 75.02,53.32 75.35,53.32 75.46,53.44 75.46,53.66 75.35,53.78 75.02,53.78 74.9,53.89 74.9,54.12 75.02,54.24 75.35,54.24 75.46,54.35 75.46,54.58 75.35,54.69 75.02,54.69 74.9,54.81 74.9,55.04 75.02,55.15 75.35,55.15 75.46,55.26 75.46,55.49 75.35,55.61 75.02,55.61 74.9,55.72 74.9,55.95 75.02,56.06 75.35,56.06 75.46,56.18 75.46,56.41 75.35,56.52 75.02,56.52 74.9,56.64 74.9,56.86 75.02,56.98 75.35,56.98 75.46,57.09 75.46,57.32 75.35,57.44 75.02,57.44 74.9,57.55 74.9,57.78 75.02,57.89 75.35,57.89 75.46,58.01 75.46,58.24 75.35,58.35 75.02,58.35 74.9,58.46 74.9,58.69 75.02,58.81 75.35,58.81 75.46,58.92 75.46,59.15 75.35,59.27 75.02,59.27 74.9,59.38 74.9,59.61 75.02,59.72 75.35,59.72 75.46,59.84 75.46,60.07 75.35,60.18 75.02,60.18 74.9,60.29 74.9,60.52 75.02,60.64 75.35,60.64 75.46,60.75 75.46,60.98 75.35,61.09 75.02,61.09 74.9,61.21 74.9,61.44 75.02,61.55 75.35,61.55 75.46,61.67 75.46,61.89 75.35,62.01 75.02,62.01 74.9,62.12 74.9,62.35 75.02,62.47 75.35,62.47 75.46,62.58 75.46,62.81 75.35,62.92 75.02,62.92 74.9,63.04 74.9,63.27 75.02,63.38 75.35,63.38 75.46,63.49 75.46,63.72 75.35,63.84 75.02,63.84 74.9,63.95 74.9,64.18 75.02,64.29 75.35,64.29 75.46,64.41 75.46,64.64 75.35,64.75 75.02,64.75 74.9,64.87 74.9,65.09 75.02,65.21 75.35,65.21 75.46,65.32 75.46,65.55 75.35,65.67 75.3,65.67 75.18,65.78 75.18,66.47 74.7,66.95 74.7,68.34 74.82,68.45 74.84,68.45 74.96,68.56 74.96,68.79 74.84,68.91 74.56,68.91 74.45,69.02 74.45,69.25 74.56,69.36 74.84,69.36 74.96,69.48 74.96,69.71 74.84,69.82 74.56,69.82 74.45,69.94 74.45,70.16 74.56,70.28 74.84,70.28 74.96,70.39 74.96,70.62 74.84,70.74 74.56,70.74 74.45,70.85 74.45,71.08 74.56,71.19 74.84,71.19 74.96,71.31 74.96,71.54 74.84,71.65 74.56,71.65 74.45,71.76 74.45,71.99 74.56,72.11 74.84,72.11 74.96,72.22 74.96,72.45 74.84,72.56 74.56,72.56 74.45,72.68 74.45,72.91 74.56,73.02 74.84,73.02 74.96,73.14 74.96,73.36 74.84,73.48 74.56,73.48 74.45,73.59 74.45,73.82 74.56,73.94 74.84,73.94 74.96,74.05 74.96,74.28 74.84,74.39 74.56,74.39 74.45,74.51 74.45,74.74 74.56,74.85 74.84,74.85 74.96,74.96 74.96,75.21 74.75,75.41 74.75,76.45 75.74,77.44 75.74,80.47 75.32,80.9 v1(75.31,80.9)
  L10-SIG4 w0.102: v2(93.95,82.2) 93.95,82.18 93.43,81.66 91.87,81.66 91.57,81.36 91.57,81.26 91.12,80.81 90.23,80.81
  L10-SIG4 w0.114: 90.23,80.81 89.7,80.81 89.59,80.7 88.34,80.7 87.76,80.11 82.52,80.11 82.27,80.36 75.85,80.36 v1(75.31,80.9) ; v1(75.31,49.78) 74.72,50.38 v1(66.93,50.38)
DDR2_DQ10: length 82.3
  TOP w0.165: U5.AL13 v2(93.95,81.2) ; J6.35 v1(65.87,53.38)
  L9-SIG3 w0.102: 90.75,61.47 91.01,61.72 93.09,61.72 93.47,62.1 93.47,62.46 94.74,63.73 95.1,63.73 95.43,64.06 95.43,64.22 95.8,64.59 95.96,64.59 96.39,65.02 96.39,75.82 95.45,76.76 95.45,79.25 94.95,79.76 94.79,79.76 94.46,80.09 94.46,80.69 v2(93.95,81.2)
  L9-SIG3 w0.114: 90.75,61.47 90.04,61.47 89.13,60.56 88.97,60.56 88.67,60.86 88.51,60.86 88.34,60.7 88.34,60.54 88.65,60.23 88.65,60.07 88.39,59.82 87.27,59.82 86.28,58.82 86.28,58.66 87.75,57.18 87.75,57.02 87.59,56.86 87.43,56.86 85.95,58.34 85.79,58.34 85.47,58.01 85.47,56.64 85.05,56.22 84.89,56.22 83.97,57.14 83.81,57.14 83.65,56.98 83.65,56.82 84.57,55.9 84.57,55.74 84.41,55.58 84.24,55.58 83.33,56.5 83.17,56.5 83,56.33 83,56.17 83.92,55.25 83.92,55.09 83.76,54.93 83.6,54.93 82.68,55.85 82.52,55.85 82.36,55.69 82.36,55.53 83.28,54.61 83.28,54.45 83.11,54.28 82.95,54.28 82.03,55.2 81.87,55.2 81.71,55.04 81.71,54.88 82.63,53.96 82.63,53.8 82.47,53.64 82.31,53.64 81.39,54.56 81.23,54.56 81.06,54.39 81.06,54.23 81.98,53.31 81.98,53.15 81.82,52.99 81.66,52.99 80.74,53.91 80.58,53.91 80.42,53.75 80.42,53.59 81.34,52.67 81.34,52.51 81.17,52.34 81.01,52.34 80.09,53.26 79.93,53.26 79.77,53.1 79.77,52.94 80.69,52.02 80.69,51.86 80.52,51.69 79.5,51.69 v1(78.36,52.83)
  L10-SIG4 w0.114: v1(65.87,53.38) 77.81,53.38 v1(78.36,52.83)
DDR2_DQ11: length 82.3
  TOP w0.165: U5.AP13 v2(90.96,81.19) ; J6.37 v1(66.93,53.98)
  L9-SIG3 w0.102: v2(90.96,81.19) 91.57,80.58 93.11,80.58 93.33,80.36 93.33,79.94 93.34,79.93 93.34,73.15 93.73,72.77 94.11,72.77 94.36,72.52 94.36,64.01 93.09,62.74 90.55,62.74
  L9-SIG3 w0.114: 90.55,62.74 89.79,61.98 86.11,61.98 85.4,61.27 85.4,61.11 86.13,60.38 86.13,60.22 85.96,60.06 85.8,60.06 85.08,60.78 84.91,60.78 84.75,60.62 84.75,60.46 85.48,59.73 85.48,59.57 85.32,59.41 85.16,59.41 84.43,60.14 84.27,60.14 84.11,59.98 84.11,59.81 84.83,59.09 84.83,58.93 84.67,58.76 84.51,58.76 83.78,59.49 83.62,59.49 83.46,59.33 83.46,59.17 84.19,58.44 84.19,58.28 84.02,58.12 83.86,58.12 83.14,58.84 82.97,58.84 82.81,58.68 82.81,58.52 83.54,57.79 83.54,57.63 83.38,57.47 83.22,57.47 82.49,58.2 82.33,58.2 82.17,58.04 82.17,57.87 82.89,57.15 82.89,56.99 82.73,56.82 82.57,56.82 81.84,57.55 81.68,57.55 81.52,57.39 81.52,57.23 82.25,56.5 82.25,56.34 82.09,56.18 81.92,56.18 81.2,56.9 81.03,56.9 80.87,56.74 80.87,56.58 81.6,55.85 81.6,55.69 81.44,55.53 81.28,55.53 80.55,56.26 80.39,56.26 80.23,56.1 80.23,55.93 80.95,55.21 80.95,55.05 80.79,54.88 80.63,54.88 80.14,55.37 79.63,55.37 79.38,55.12 v1(79.38,53.72)
  L10-SIG4 w0.114: v1(66.93,53.98) 67.81,54.86 68.34,54.86 68.56,54.64 68.79,54.64 68.91,54.75 68.91,54.98 69.02,55.09 69.25,55.09 69.36,54.98 69.36,54.75 69.48,54.64 69.71,54.64 69.82,54.75 69.82,54.98 69.94,55.09 70.16,55.09 70.28,54.98 70.28,54.75 70.39,54.64 70.62,54.64 70.74,54.75 70.74,54.98 70.85,55.09 71.08,55.09 71.19,54.98 71.19,54.75 71.31,54.64 71.54,54.64 71.65,54.75 71.65,54.98 71.76,55.09 71.99,55.09 72.11,54.98 72.11,54.75 72.22,54.64 72.45,54.64 72.56,54.75 72.56,54.98 72.68,55.09 72.91,55.09 73.02,54.98 73.02,54.75 73.14,54.64 73.36,54.64 73.48,54.75 73.48,54.98 73.59,55.09 73.82,55.09 73.94,54.98 73.94,54.75 74.05,54.64 74.28,54.64 74.39,54.75 74.39,54.98 74.51,55.09 74.74,55.09 74.85,54.98 74.85,54.75 74.96,54.64 75.19,54.64 75.31,54.75 75.31,54.98 75.42,55.09 75.65,55.09 75.76,54.98 75.76,54.75 75.88,54.64 76.11,54.64 76.22,54.75 76.22,54.98 76.34,55.09 76.56,55.09 76.68,54.98 76.68,54.75 76.79,54.64 77.02,54.64 77.15,54.76 78.33,54.76 v1(79.38,53.72)
DDR2_DQ12: length 82.2
  TOP w0.165: U5.AM11 v2(92.95,83.2) ; J6.20 v1(57.53,48.88)
  L3-SIG1 w0.114: v1(73.53,48.88) 73.53,49.65 73.69,49.8 73.69,50.06 73.54,50.2 73.43,50.2 73.33,50.31 73.33,50.56 73.43,50.66 73.63,50.66 73.74,50.76 73.74,51.02 73.63,51.12 73.43,51.12 73.33,51.22 73.33,51.47 73.43,51.58 73.63,51.58 73.74,51.68 73.74,51.93 73.63,52.03 73.43,52.03 73.33,52.13 73.33,52.39 73.43,52.49 73.63,52.49 73.74,52.59 73.74,52.85 73.63,52.95 73.43,52.95 73.33,53.05 73.33,53.3 73.43,53.4 73.63,53.4 73.74,53.51 73.74,53.76 73.63,53.86 73.43,53.86 73.33,53.96 73.33,54.22 73.43,54.32 73.63,54.32 73.74,54.42 73.74,54.67 73.63,54.78 73.43,54.78 73.33,54.88 73.33,55.13 73.43,55.23 73.63,55.23 73.74,55.34 73.74,55.59 73.63,55.69 73.43,55.69 73.33,55.79 73.33,56.05 73.43,56.15 73.63,56.15 73.74,56.25 73.74,56.5 73.63,56.61 73.43,56.61 73.33,56.71 73.33,56.96 73.43,57.06 73.63,57.06 73.74,57.16 73.74,57.42 73.63,57.52 73.43,57.52 73.33,57.62 73.33,57.88 73.43,57.98 73.63,57.98 73.74,58.08 73.74,58.33 73.63,58.43 73.43,58.43 73.33,58.54 73.33,58.79 73.43,58.89 73.63,58.89 73.74,58.99 73.74,59.25 73.63,59.35 73.43,59.35 73.33,59.45 73.33,59.7 73.43,59.81 73.63,59.81 73.74,59.91 73.74,60.16 73.63,60.26 73.43,60.26 73.33,60.36 73.33,60.62 73.43,60.72 73.63,60.72 73.74,60.82 73.74,61.08 73.63,61.18 73.43,61.18 73.33,61.28 73.33,61.53 73.43,61.63 73.63,61.63 73.74,61.74 73.74,61.99 73.63,62.09 73.43,62.09 73.33,62.19 73.33,62.45 73.43,62.55 73.63,62.55 73.74,62.65 73.74,62.9 73.63,63.01 73.43,63.01 73.33,63.11 73.33,63.36 73.43,63.46 73.63,63.46 73.74,63.56 73.74,63.82 73.53,64.02 73.53,66.52 73.25,66.8 73.25,78.77 73.53,79.04 73.53,80.64 73.15,81.03 73.15,82.42 v1(73.53,82.8)
  L4-SIG2 w0.102: v2(92.95,83.2) 92.41,83.74 90.47,83.74
  L4-SIG2 w0.114: v1(73.53,48.88) 67.25,48.88 67.11,49.02 66.75,49.02 66.61,48.88 v1(57.53,48.88) ; v1(73.53,82.8) 73.86,83.13 75.46,83.13 75.82,82.78 80.19,82.78 80.71,83.3 83.5,83.3 84.07,82.73 89.46,82.73 90.47,83.74
DDR2_DQ13: length 82.3
  TOP w0.165: J6.22 v1(58.29,49.48) ; U5.AN12 v2(91.96,82.19)
  L4-SIG2 w0.114: v1(74.3,48.9) 73.71,49.48 66.56,49.48 66.42,49.34 58.43,49.34 v1(58.29,49.48)
  L9-SIG3 w0.114: v1(73.91,81.79) 73.91,79.36 73.28,78.72 73.28,75.38 73.79,74.87 73.79,66.67 74.07,66.4 74.07,64.83 74.3,64.6 74.3,64.38 74.18,64.26 73.95,64.26 73.84,64.15 73.84,63.92 73.95,63.8 74.18,63.8 74.3,63.69 74.3,63.46 74.18,63.35 73.95,63.35 73.84,63.23 73.84,63 73.95,62.89 74.18,62.89 74.3,62.78 74.3,62.55 74.18,62.43 73.95,62.43 73.84,62.32 73.84,62.09 73.95,61.98 74.18,61.98 74.3,61.86 74.3,61.63 74.18,61.52 73.95,61.52 73.84,61.4 73.84,61.18 73.95,61.06 74.18,61.06 74.3,60.95 74.3,60.72 74.18,60.6 73.95,60.6 73.84,60.49 73.84,60.26 73.95,60.15 74.18,60.15 74.3,60.03 74.3,59.8 74.18,59.69 73.95,59.69 73.84,59.58 73.84,59.35 73.95,59.23 74.18,59.23 74.3,59.12 74.3,58.89 74.18,58.78 73.95,58.78 73.84,58.66 73.84,58.43 73.95,58.32 74.18,58.32 74.3,58.2 74.3,57.98 74.18,57.86 73.95,57.86 73.84,57.75 73.84,57.52 73.95,57.4 74.18,57.4 74.3,57.29 74.3,57.06 74.18,56.95 73.95,56.95 73.84,56.83 73.84,56.6 73.95,56.49 74.18,56.49 74.3,56.38 74.3,56.15 74.18,56.03 73.95,56.03 73.84,55.92 73.84,55.69 73.95,55.58 74.18,55.58 74.3,55.46 74.3,55.23 74.18,55.12 73.95,55.12 73.84,55 73.84,54.78 73.95,54.66 74.18,54.66 74.3,54.55 74.3,54.32 74.18,54.2 73.95,54.2 73.84,54.09 73.84,53.86 73.95,53.75 74.18,53.75 74.3,53.63 74.3,53.4 74.18,53.29 73.95,53.29 73.84,53.17 73.84,52.95 73.95,52.83 74.18,52.83 74.3,52.72 74.3,52.49 74.18,52.37 73.95,52.37 73.84,52.26 73.84,52.03 73.95,51.92 74.18,51.92 74.3,51.8 74.3,51.57 74.18,51.46 73.95,51.46 73.84,51.35 73.84,51.12 73.95,51 74.18,51 74.3,50.89 74.3,50.66 74.07,50.43 74.07,49.12 v1(74.3,48.9)
  L10-SIG4 w0.102: v2(91.96,82.19) 91.34,81.57 90.8,81.57 90.79,81.57 90.3,81.57
  L10-SIG4 w0.114: 90.3,81.57 87.89,81.57 87.8,81.47 86.9,81.47 86.83,81.41 85.85,81.41 85.6,81.66 80.85,81.66 80.39,81.2 79.02,81.2 77.6,82.63 76.15,82.63 75.31,81.79 v1(73.91,81.79)
DDR2_DQ14: length 82.2
  TOP w0.165: v1(57.54,53.68) 57.54,53.68 J6.36 ; U5.AL11 v2(93.95,83.2)
  L3-SIG1 w0.114: v1(78.61,53.68) 78.61,54.22 78.82,54.42 78.82,54.68 78.71,54.78 78.51,54.78 78.41,54.88 78.41,55.13 78.51,55.23 78.71,55.23 78.82,55.34 78.82,55.59 78.71,55.69 78.51,55.69 78.41,55.79 78.41,56.05 78.51,56.15 78.71,56.15 78.82,56.25 78.82,56.5 78.71,56.61 78.51,56.61 78.41,56.71 78.41,56.96 78.51,57.06 78.71,57.06 78.82,57.16 78.82,57.42 78.71,57.52 78.51,57.52 78.41,57.62 78.41,57.88 78.51,57.98 78.71,57.98 78.82,58.08 78.82,58.33 78.71,58.43 78.51,58.43 78.41,58.54 78.41,58.79 78.51,58.89 78.71,58.89 78.82,58.99 78.82,59.25 78.71,59.35 78.51,59.35 78.41,59.45 78.41,59.7 78.51,59.81 78.71,59.81 78.82,59.91 78.82,60.16 78.71,60.26 78.51,60.26 78.41,60.37 78.41,60.62 78.51,60.72 78.71,60.72 78.82,60.82 78.82,61.08 78.71,61.18 78.51,61.18 78.41,61.28 78.41,61.53 78.51,61.64 78.71,61.64 78.82,61.74 78.82,61.99 78.71,62.09 78.51,62.09 78.41,62.19 78.41,62.45 78.51,62.55 78.71,62.55 78.82,62.65 78.82,62.91 78.71,63.01 78.51,63.01 78.41,63.11 78.41,63.36 78.51,63.46 78.71,63.46 78.82,63.57 78.82,63.82 78.71,63.92 78.51,63.92 78.41,64.02 78.41,64.28 78.51,64.38 78.71,64.38 78.82,64.48 78.82,64.73 78.71,64.84 78.51,64.84 78.41,64.94 78.41,65.19 78.51,65.29 78.71,65.29 78.82,65.39 78.82,65.65 78.71,65.75 78.51,65.75 78.41,65.85 78.41,66.11 78.51,66.21 78.71,66.21 78.82,66.31 78.82,66.56 78.71,66.66 78.51,66.66 78.41,66.77 78.41,67.02 78.51,67.12 78.71,67.12 78.82,67.22 78.82,67.48 78.71,67.58 78.51,67.58 78.41,67.68 78.41,67.93 78.51,68.04 78.71,68.04 78.82,68.14 78.82,68.76 78.44,69.14 78.44,75.06 78.79,75.41 78.79,75.67 78.61,75.84 78.61,76.04 78.94,76.37 78.94,76.57 78.82,76.7 78.66,76.7 78.59,76.77 78.59,77.08 78.66,77.15 78.82,77.15 78.89,77.23 78.89,77.53 78.82,77.61 78.66,77.61 78.59,77.69 78.59,77.99 78.66,78.07 78.82,78.07 78.89,78.14 78.89,78.45 78.82,78.53 78.66,78.53 78.59,78.6 78.59,78.91 78.66,78.98 78.82,78.98 78.89,79.06 78.89,79.36 78.82,79.44 78.66,79.44 78.59,79.52 78.59,79.82 78.66,79.9 78.82,79.9 78.89,79.97 78.89,80.28 78.82,80.35 78.66,80.35 78.59,80.43 78.59,80.74 78.66,80.81 78.82,80.81 78.89,80.89 78.89,81.19 78.82,81.27 78.66,81.27 78.59,81.34 78.59,81.65 78.66,81.73 78.82,81.73 78.89,81.8 78.89,82.11 78.82,82.18 78.66,82.18 78.59,82.26 78.59,82.56 78.66,82.64 78.82,82.64 79.02,82.84 79.02,83.29 v1(78.61,83.69)
  L4-SIG2 w0.114: v1(78.61,53.68) 78.48,53.54 66.55,53.54 66.22,53.87 65.44,53.87 65.16,53.59 57.62,53.59 v1(57.54,53.68)
  L10-SIG4 w0.114: v1(78.61,83.69) 78.99,83.31 88.01,83.31 88.77,84.07 90.07,84.07 90.46,83.69 93.46,83.69 v2(93.95,83.2)
DDR2_DQ15: length 82.2
  TOP w0.165: v1(58.29,54.28) J6.38 ; U5.AP12 v2(90.96,82.19)
  L3-SIG1 w0.114: v1(79.88,54.28) 79.5,54.66 79.5,69.36 78.92,69.94 78.92,74.6 79.63,75.31 v1(79.63,81.61)
  L4-SIG2 w0.114: v1(79.88,54.28) 78.51,55.65 76.54,55.65 76.27,55.38 76.27,55.23 76.15,55.12 75.93,55.12 75.81,55.23 75.81,55.77 75.7,55.88 75.47,55.88 75.35,55.77 75.35,55.23 75.24,55.12 75.01,55.12 74.9,55.23 74.9,55.77 74.78,55.88 74.55,55.88 74.44,55.77 74.44,55.23 74.33,55.12 74.1,55.12 73.98,55.23 73.98,55.77 73.87,55.88 73.64,55.88 73.53,55.77 73.53,55.23 73.41,55.12 73.18,55.12 73.07,55.23 73.07,55.77 72.95,55.88 72.73,55.88 72.61,55.77 72.61,55.23 72.5,55.12 72.27,55.12 72.15,55.23 72.15,55.77 72.04,55.88 71.81,55.88 71.7,55.77 71.7,55.23 71.58,55.12 71.35,55.12 71.24,55.23 71.24,55.77 71.13,55.88 70.9,55.88 70.78,55.77 70.78,55.23 70.67,55.12 70.44,55.12 70.33,55.23 70.33,55.77 70.21,55.88 69.98,55.88 69.87,55.77 69.87,55.23 69.75,55.12 69.53,55.12 69.41,55.23 69.41,55.77 69.3,55.88 69.07,55.88 68.95,55.77 68.95,55.23 68.84,55.12 68.61,55.12 68.5,55.23 68.5,55.77 68.38,55.88 68.15,55.88 68.04,55.77 68.04,55.23 67.92,55.12 67.7,55.12 67.58,55.23 67.58,55.77 67.47,55.88 67.24,55.88 67.12,55.77 67.12,55.23 67.01,55.12 66.78,55.12 66.67,55.23 66.67,55.77 66.55,55.88 66.32,55.88 66.21,55.77 66.21,55.23 66.1,55.12 65.87,55.12 65.75,55.23 65.75,55.77 65.64,55.88 65.41,55.88 65.3,55.77 65.3,55.23 65.18,55.12 64.95,55.12 64.84,55.23 64.84,55.77 64.72,55.88 64.5,55.88 64.38,55.77 64.38,55.23 64.27,55.12 64.04,55.12 63.92,55.23 63.92,55.38 63.81,55.5 59.51,55.5 v1(58.29,54.28)
  L10-SIG4 w0.102: 90.11,81.93 90.37,82.19 v2(90.96,82.19)
  L10-SIG4 w0.114: v1(79.63,81.61) 80.06,82.04 86.36,82.04 86.63,81.77 86.95,81.77 86.95,81.76 87.37,81.76 87.49,81.88 90.06,81.88 90.11,81.93
DDR2_DQ16: length 82.2
  TOP w0.165: U5.AL21 v2(93.95,72.2) ; J6.43 v1(65.84,59.38)
  L9-SIG3 w0.114: v1(79.38,72.64) 79.17,72.44 79.17,62.31 80.14,61.34 v1(80.14,59.38)
  L10-SIG4 w0.102: 91.44,72.01 91.63,71.82 91.79,71.82 91.79,71.82 92.11,71.82 92.11,71.82 92.79,71.82 92.79,71.82 93.11,71.82 93.11,71.82 93.54,71.82 93.93,72.21 93.96,72.21 v2(93.95,72.2)
  L10-SIG4 w0.114: v1(79.38,72.64) 79.38,72.57 79.68,72.26 83.72,72.26 84,71.98 86.39,71.98 87.12,72.72 88.72,72.72 88.82,72.62 91.21,72.62 91.44,72.39 91.44,72.01 ; v1(65.84,59.38) 65.84,58.64 66.4,58.09 66.95,58.09 67.07,57.98 67.07,57.49 67.18,57.38 67.41,57.38 67.52,57.49 67.52,58.69 67.64,58.8 67.87,58.8 67.98,58.69 67.98,57.49 68.09,57.38 68.32,57.38 68.44,57.49 68.44,58.69 68.55,58.8 68.78,58.8 68.89,58.69 68.89,57.49 69.01,57.38 69.24,57.38 69.35,57.49 69.35,58.69 69.47,58.8 69.69,58.8 69.81,58.69 69.81,57.49 69.92,57.38 70.15,57.38 70.27,57.49 70.27,58.69 70.38,58.8 70.61,58.8 70.72,58.69 70.72,57.49 70.84,57.38 71.07,57.38 71.18,57.49 71.18,58.69 71.29,58.8 71.52,58.8 71.64,58.69 71.64,57.49 71.75,57.38 71.98,57.38 72.09,57.49 72.09,58.69 72.21,58.8 72.44,58.8 72.55,58.69 72.55,57.49 72.67,57.38 72.89,57.38 73.01,57.49 73.01,58.69 73.12,58.8 73.35,58.8 73.47,58.69 73.47,57.49 73.58,57.38 73.81,57.38 73.92,57.49 73.92,58.69 74.04,58.8 74.27,58.8 74.38,58.69 74.38,57.49 74.49,57.38 74.72,57.38 74.84,57.49 74.84,58.69 74.95,58.8 75.18,58.8 75.3,58.69 75.3,57.49 75.41,57.38 75.64,57.38 75.75,57.49 75.75,58.69 75.87,58.8 76.1,58.8 76.21,58.69 76.21,57.49 76.32,57.38 76.55,57.38 76.67,57.49 76.67,58.69 76.78,58.8 77.01,58.8 77.12,58.69 77.12,57.49 77.24,57.38 77.47,57.38 77.58,57.49 77.58,58.69 77.7,58.8 77.92,58.8 78.04,58.69 78.04,57.49 78.15,57.38 78.38,57.38 78.5,57.49 78.5,58.69 78.61,58.8 78.84,58.8 78.95,58.69 78.95,57.93 79.15,57.73 79.65,57.73 80.14,58.22 v1(80.14,59.38)
DDR2_DQ17: length 82.3
  TOP w0.165: U5.AM21 v2(92.95,72.2) ; J6.45 v1(66.89,59.98)
  L4-SIG2 w0.102: v2(92.95,72.2) 93.34,72.6 93.34,73.38 93.14,73.59 92.72,73.59
  L4-SIG2 w0.114: v1(81.15,73.79) 81.17,73.77 84.96,73.77 85.1,73.63 85.62,73.63 85.93,73.94 87.58,73.94 88.09,73.43 92.56,73.43 92.72,73.59
  L9-SIG3 w0.114: v1(81.66,59.98) 80.64,60.99 80.64,61.32 80.88,61.55 81.06,61.55 81.18,61.67 81.18,61.9 81.06,62.01 80.23,62.01 80.11,62.13 80.11,62.35 80.23,62.47 81.06,62.47 81.18,62.58 81.18,62.81 81.06,62.93 80.23,62.93 80.11,63.04 80.11,63.27 80.23,63.38 81.06,63.38 81.18,63.5 81.18,63.73 81.06,63.84 80.23,63.84 80.11,63.95 80.11,64.18 80.23,64.3 81.06,64.3 81.18,64.41 81.18,64.64 81.06,64.75 80.23,64.75 80.11,64.87 80.11,65.1 80.23,65.21 81.06,65.21 81.18,65.33 81.18,65.55 81.06,65.67 80.23,65.67 80.11,65.78 80.11,66.01 80.23,66.13 81.06,66.13 81.18,66.24 81.18,66.47 81.06,66.58 80.23,66.58 80.11,66.7 80.11,66.93 80.23,67.04 81.06,67.04 81.18,67.15 81.18,67.38 81.06,67.5 80.23,67.5 80.11,67.61 80.11,67.84 80.23,67.95 81.06,67.95 81.18,68.07 81.18,68.3 80.64,68.83 80.64,69.6 81.41,70.36 81.41,72.26 81.15,72.52 v1(81.15,73.79)
  L10-SIG4 w0.114: v1(66.89,59.98) 67.08,59.79 67.42,59.79 67.53,59.68 67.53,59.42 67.65,59.31 67.88,59.31 67.99,59.42 67.99,60.16 68.11,60.27 68.33,60.27 68.45,60.16 68.45,59.42 68.56,59.31 68.79,59.31 68.91,59.42 68.91,60.16 69.02,60.27 69.25,60.27 69.36,60.16 69.36,59.42 69.48,59.31 69.71,59.31 69.82,59.42 69.82,60.16 69.94,60.27 70.16,60.27 70.28,60.16 70.28,59.42 70.39,59.31 70.62,59.31 70.74,59.42 70.74,60.16 70.85,60.27 71.08,60.27 71.19,60.16 71.19,59.42 71.31,59.31 71.54,59.31 71.65,59.42 71.65,60.16 71.76,60.27 71.99,60.27 72.11,60.16 72.11,59.42 72.22,59.31 72.45,59.31 72.56,59.42 72.56,60.16 72.68,60.27 72.91,60.27 73.02,60.16 73.02,59.42 73.14,59.31 73.36,59.31 73.48,59.42 73.48,60.16 73.59,60.27 73.82,60.27 73.94,60.16 73.94,59.42 74.05,59.31 74.28,59.31 74.39,59.42 74.39,60.16 74.51,60.27 74.74,60.27 74.85,60.16 74.85,59.42 74.96,59.31 75.19,59.31 75.31,59.42 75.31,60.16 75.42,60.27 75.65,60.27 75.76,60.16 75.76,59.42 75.88,59.31 76.11,59.31 76.22,59.42 76.22,60.16 76.34,60.27 76.56,60.27 76.68,60.16 76.68,59.42 76.79,59.31 77.02,59.31 77.14,59.42 77.14,60.16 77.25,60.27 77.48,60.27 77.59,60.16 77.59,59.42 77.71,59.31 77.94,59.31 78.05,59.42 78.05,60.16 78.16,60.27 78.39,60.27 78.51,60.16 78.51,59.42 78.62,59.31 78.85,59.31 78.96,59.42 78.96,60.16 79.08,60.27 79.31,60.27 79.42,60.16 79.42,59.91 79.54,59.79 79.81,59.79 80.29,60.27 81.37,60.27 v1(81.66,59.98)
DDR2_DQ18: length 82.2
  TOP w0.165: U5.AL19 v2(93.96,74.21) ; J6.55 v1(65.9,62.98)
  L3-SIG1 w0.114: v1(84.58,74.55) 84.07,74.04 84.07,71.45 84.45,71.07 84.45,63.7 84.07,63.32 v1(84.07,62.1)
  L4-SIG2 w0.102: 92.74,74.59 93.23,74.59 93.61,74.21
  L4-SIG2 w0.114: 92.74,74.59 92.65,74.5 92.3,74.5 92.18,74.63 90.7,74.63 90.2,74.12 88.42,74.12 87.93,74.6 84.63,74.6 v1(84.58,74.55) ; 93.61,74.21 v2(93.96,74.21)
  L10-SIG4 w0.114: v1(65.9,62.98) 66.85,62.03 67.16,62.03 67.27,61.91 67.27,60.9 67.38,60.78 67.61,60.78 67.73,60.9 67.73,63.16 67.84,63.27 68.07,63.27 68.18,63.16 68.18,60.9 68.3,60.78 68.53,60.78 68.64,60.9 68.64,63.16 68.76,63.27 68.99,63.27 69.1,63.16 69.1,60.9 69.21,60.78 69.44,60.78 69.56,60.9 69.56,63.16 69.67,63.27 69.9,63.27 70.01,63.16 70.01,60.9 70.13,60.78 70.36,60.78 70.47,60.9 70.47,63.16 70.59,63.27 70.81,63.27 70.93,63.16 70.93,60.9 71.04,60.78 71.27,60.78 71.39,60.9 71.39,63.16 71.5,63.27 71.73,63.27 71.84,63.16 71.84,60.9 71.96,60.78 72.19,60.78 72.3,60.9 72.3,63.16 72.41,63.27 72.64,63.27 72.76,63.16 72.76,60.9 72.87,60.78 73.1,60.78 73.21,60.9 73.21,63.16 73.33,63.27 73.56,63.27 73.67,63.16 73.67,60.9 73.79,60.78 74.01,60.78 74.13,60.9 74.13,63.16 74.24,63.27 74.47,63.27 74.59,63.16 74.59,62.19 74.68,62.1 74.96,62.1 75.83,62.98 76.34,62.98 76.94,62.38 82.73,62.38 82.96,62.61 83.57,62.61 v1(84.07,62.1)
DDR2_DQ19: length 82.2
  TOP w0.165: U5.AM19 v2(92.96,74.21) ; J6.57 v1(66.88,63.58)
  L4-SIG2 w0.114: v1(85.34,74.04) 85.55,74.24 87.78,74.24 88.24,73.79 92.25,73.79 92.67,74.21 v2(92.96,74.21)
  L9-SIG3 w0.114: v1(85.57,62.99) 85.59,62.97 85.59,62.1 79.38,55.88 78.99,55.88 78.74,56.13 78.74,56.69 78.85,56.81 79.39,56.81 79.5,56.92 79.5,57.15 79.39,57.27 78.85,57.27 78.74,57.38 78.74,57.61 78.85,57.72 79.39,57.72 79.5,57.84 79.5,58.07 79.39,58.18 78.85,58.18 78.74,58.29 78.74,58.8 78.99,59.05 79.63,59.05 80.01,58.67 81.41,58.67 85.09,62.36 85.09,63.25 84.52,63.81 84.52,64.87 84.41,64.98 84.19,64.98 84.08,65.1 84.08,65.33 84.19,65.44 84.72,65.44 84.86,65.58 84.86,65.79 84.75,65.9 84.19,65.9 84.08,66.01 84.08,66.24 84.19,66.36 84.77,66.36 84.86,66.45 84.86,66.73 84.77,66.81 84.19,66.81 84.08,66.93 84.08,67.16 84.19,67.27 84.41,67.27 84.52,67.38 84.52,68.7 85.34,69.52 85.34,69.7 85.13,69.91 85.13,70.15 85.24,70.26 85.45,70.26 85.56,70.37 85.56,70.61 85.45,70.72 85.24,70.72 85.13,70.83 85.13,71.07 85.24,71.18 85.45,71.18 85.56,71.28 85.56,71.53 85.45,71.63 85.24,71.63 85.13,71.74 85.13,71.98 85.24,72.09 85.45,72.09 85.56,72.2 85.56,72.44 85.45,72.55 85.24,72.55 85.13,72.66 85.13,72.9 85.24,73.01 85.45,73.01 85.56,73.11 85.56,73.35 85.34,73.57 v1(85.34,74.04)
  L10-SIG4 w0.114: v1(66.88,63.58) 67.18,63.88 67.85,63.88 68.17,63.56 68.42,63.56 68.52,63.67 68.52,63.88 68.63,63.98 68.88,63.98 68.98,63.88 68.98,63.67 69.09,63.56 69.33,63.56 69.44,63.67 69.44,63.88 69.54,63.98 69.79,63.98 69.9,63.88 69.9,63.67 70,63.56 70.25,63.56 70.35,63.67 70.35,63.88 70.46,63.98 70.71,63.98 70.81,63.88 70.81,63.67 70.91,63.56 71.16,63.56 71.27,63.67 71.27,63.88 71.37,63.98 71.62,63.98 71.72,63.88 71.72,63.67 71.83,63.56 72.08,63.56 72.18,63.67 72.18,63.88 72.29,63.98 72.53,63.98 72.64,63.88 72.64,63.67 72.74,63.56 72.99,63.56 73.1,63.67 73.1,63.88 73.2,63.98 73.45,63.98 73.55,63.88 73.55,63.67 73.66,63.56 73.91,63.56 74.01,63.67 74.01,63.88 74.11,63.98 74.36,63.98 74.47,63.88 74.47,63.67 74.57,63.56 74.82,63.56 74.92,63.67 74.92,63.88 75.03,63.98 75.28,63.98 75.38,63.88 75.38,63.67 75.49,63.56 75.73,63.56 75.84,63.67 75.84,63.88 75.94,63.98 76.19,63.98 76.4,63.77 77.49,63.77 77.61,63.66 77.61,63.64 77.72,63.53 77.95,63.53 78.06,63.64 78.06,63.9 78.18,64.02 78.41,64.02 78.52,63.9 78.52,63.64 78.64,63.53 78.87,63.53 78.98,63.64 78.98,63.9 79.09,64.02 79.32,64.02 79.44,63.9 79.44,63.64 79.55,63.53 79.78,63.53 79.89,63.64 79.89,63.9 80.01,64.02 80.24,64.02 80.35,63.9 80.35,63.64 80.47,63.53 80.69,63.53 80.81,63.64 80.81,63.9 80.92,64.02 81.15,64.02 81.27,63.9 81.27,63.64 81.38,63.53 81.61,63.53 81.72,63.64 81.72,63.9 81.84,64.02 82.07,64.02 82.18,63.9 82.18,63.64 82.29,63.53 82.52,63.53 82.64,63.64 82.64,63.9 82.75,64.02 82.98,64.02 83.09,63.9 83.09,63.64 83.21,63.53 83.44,63.53 83.55,63.64 83.55,63.9 83.67,64.02 83.89,64.02 84.01,63.9 84.01,63.89 84.27,63.63 84.71,63.63 85.34,62.99 85.6,62.99 85.6,62.99 v1(85.57,62.99)
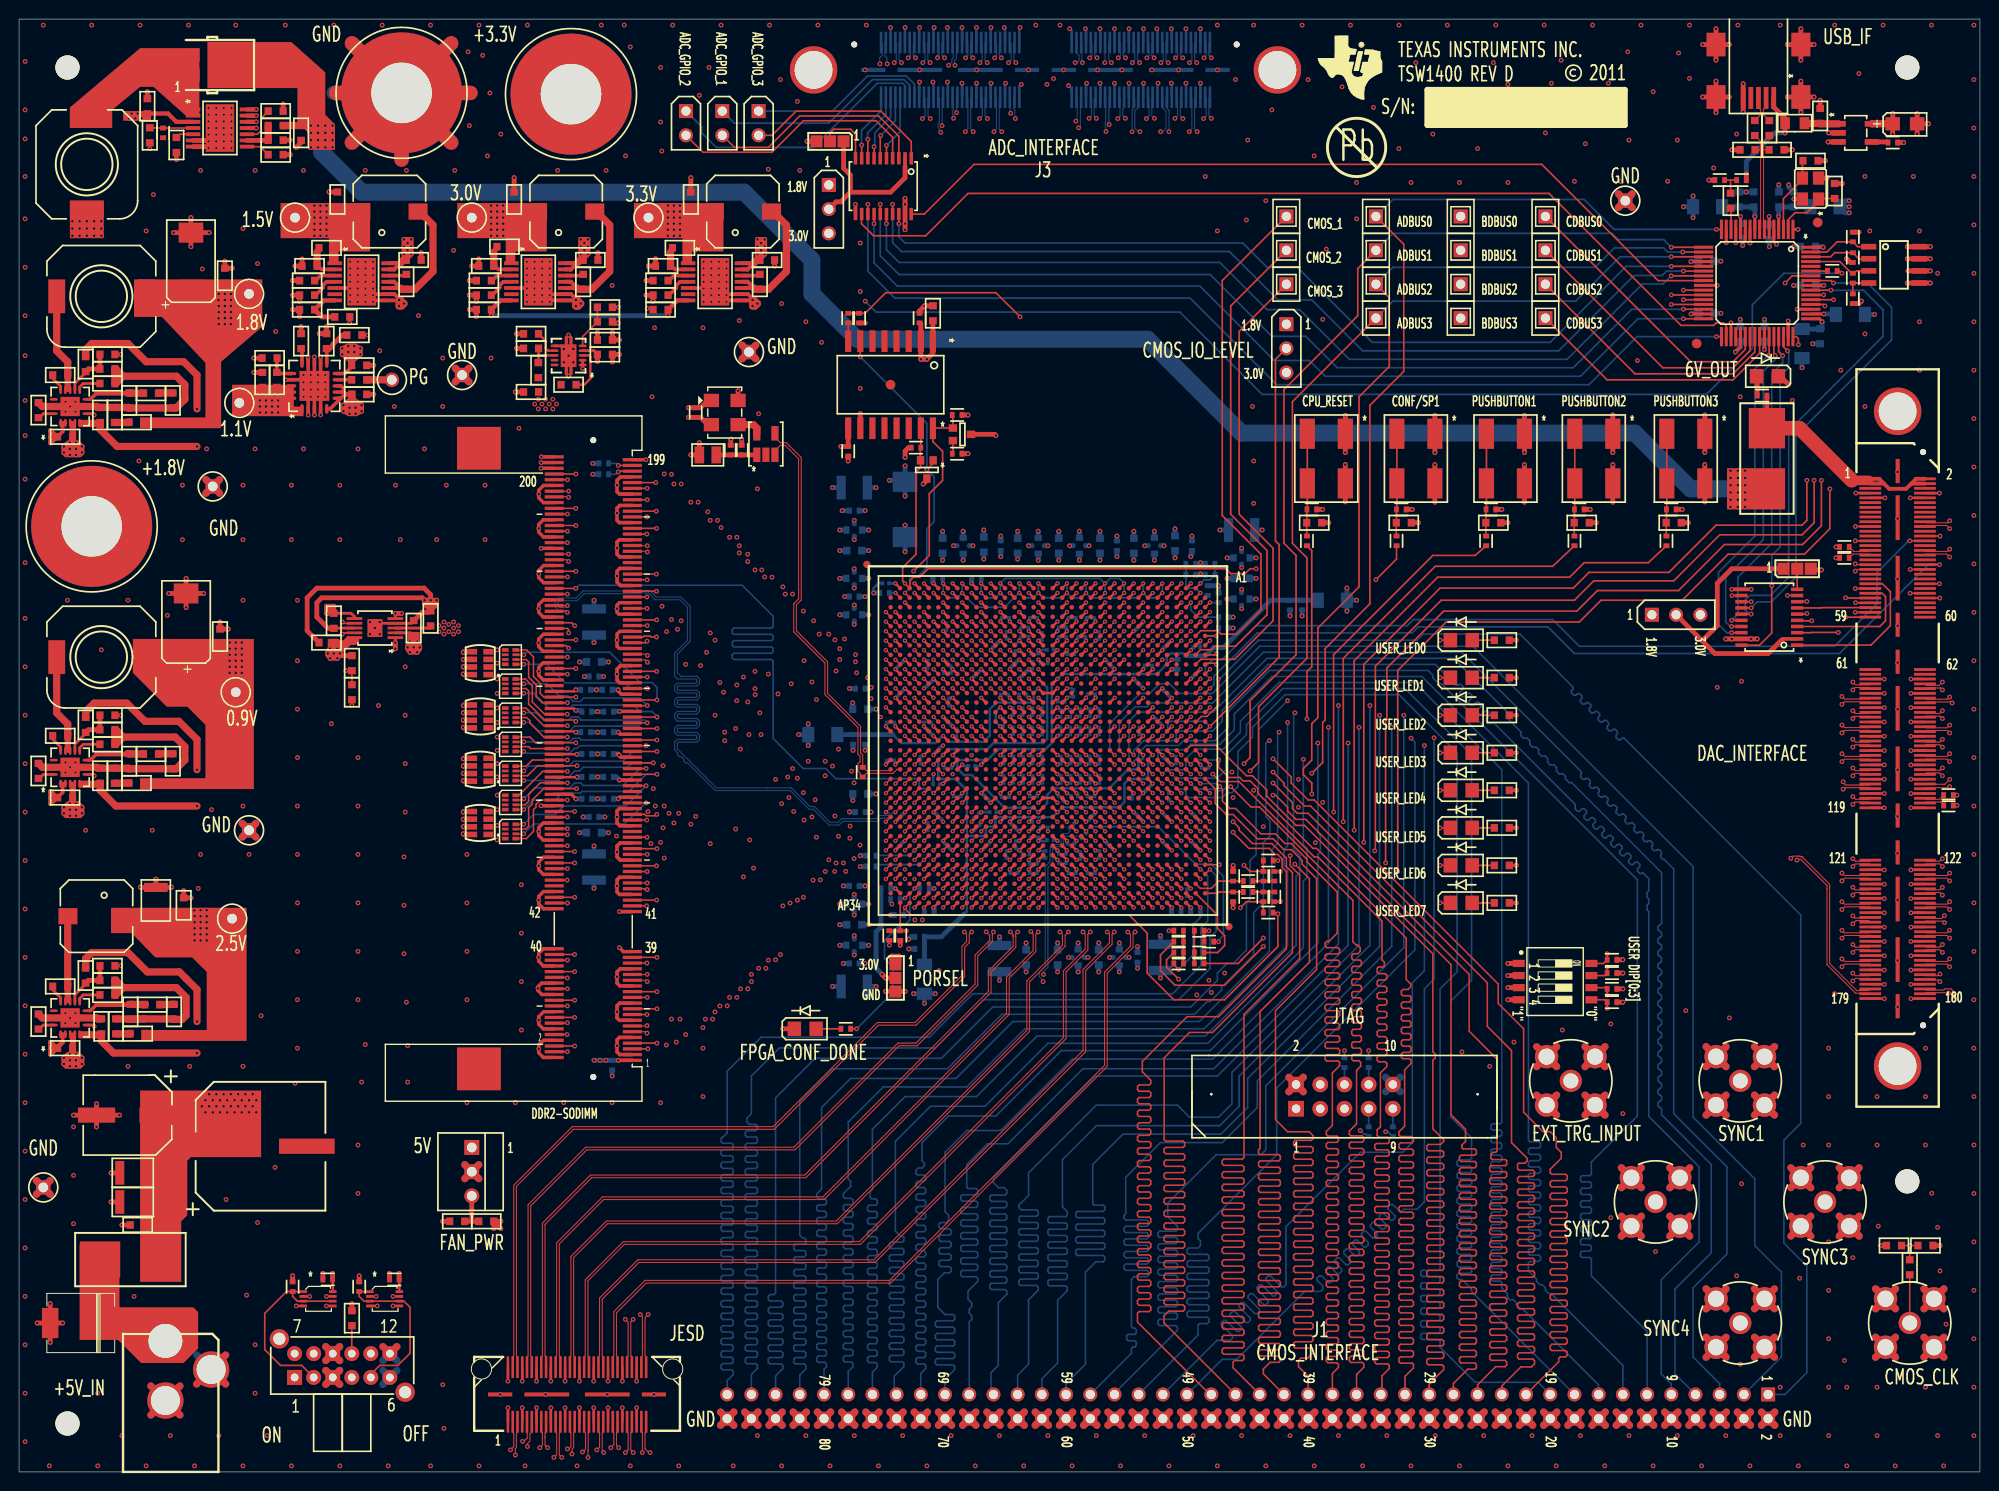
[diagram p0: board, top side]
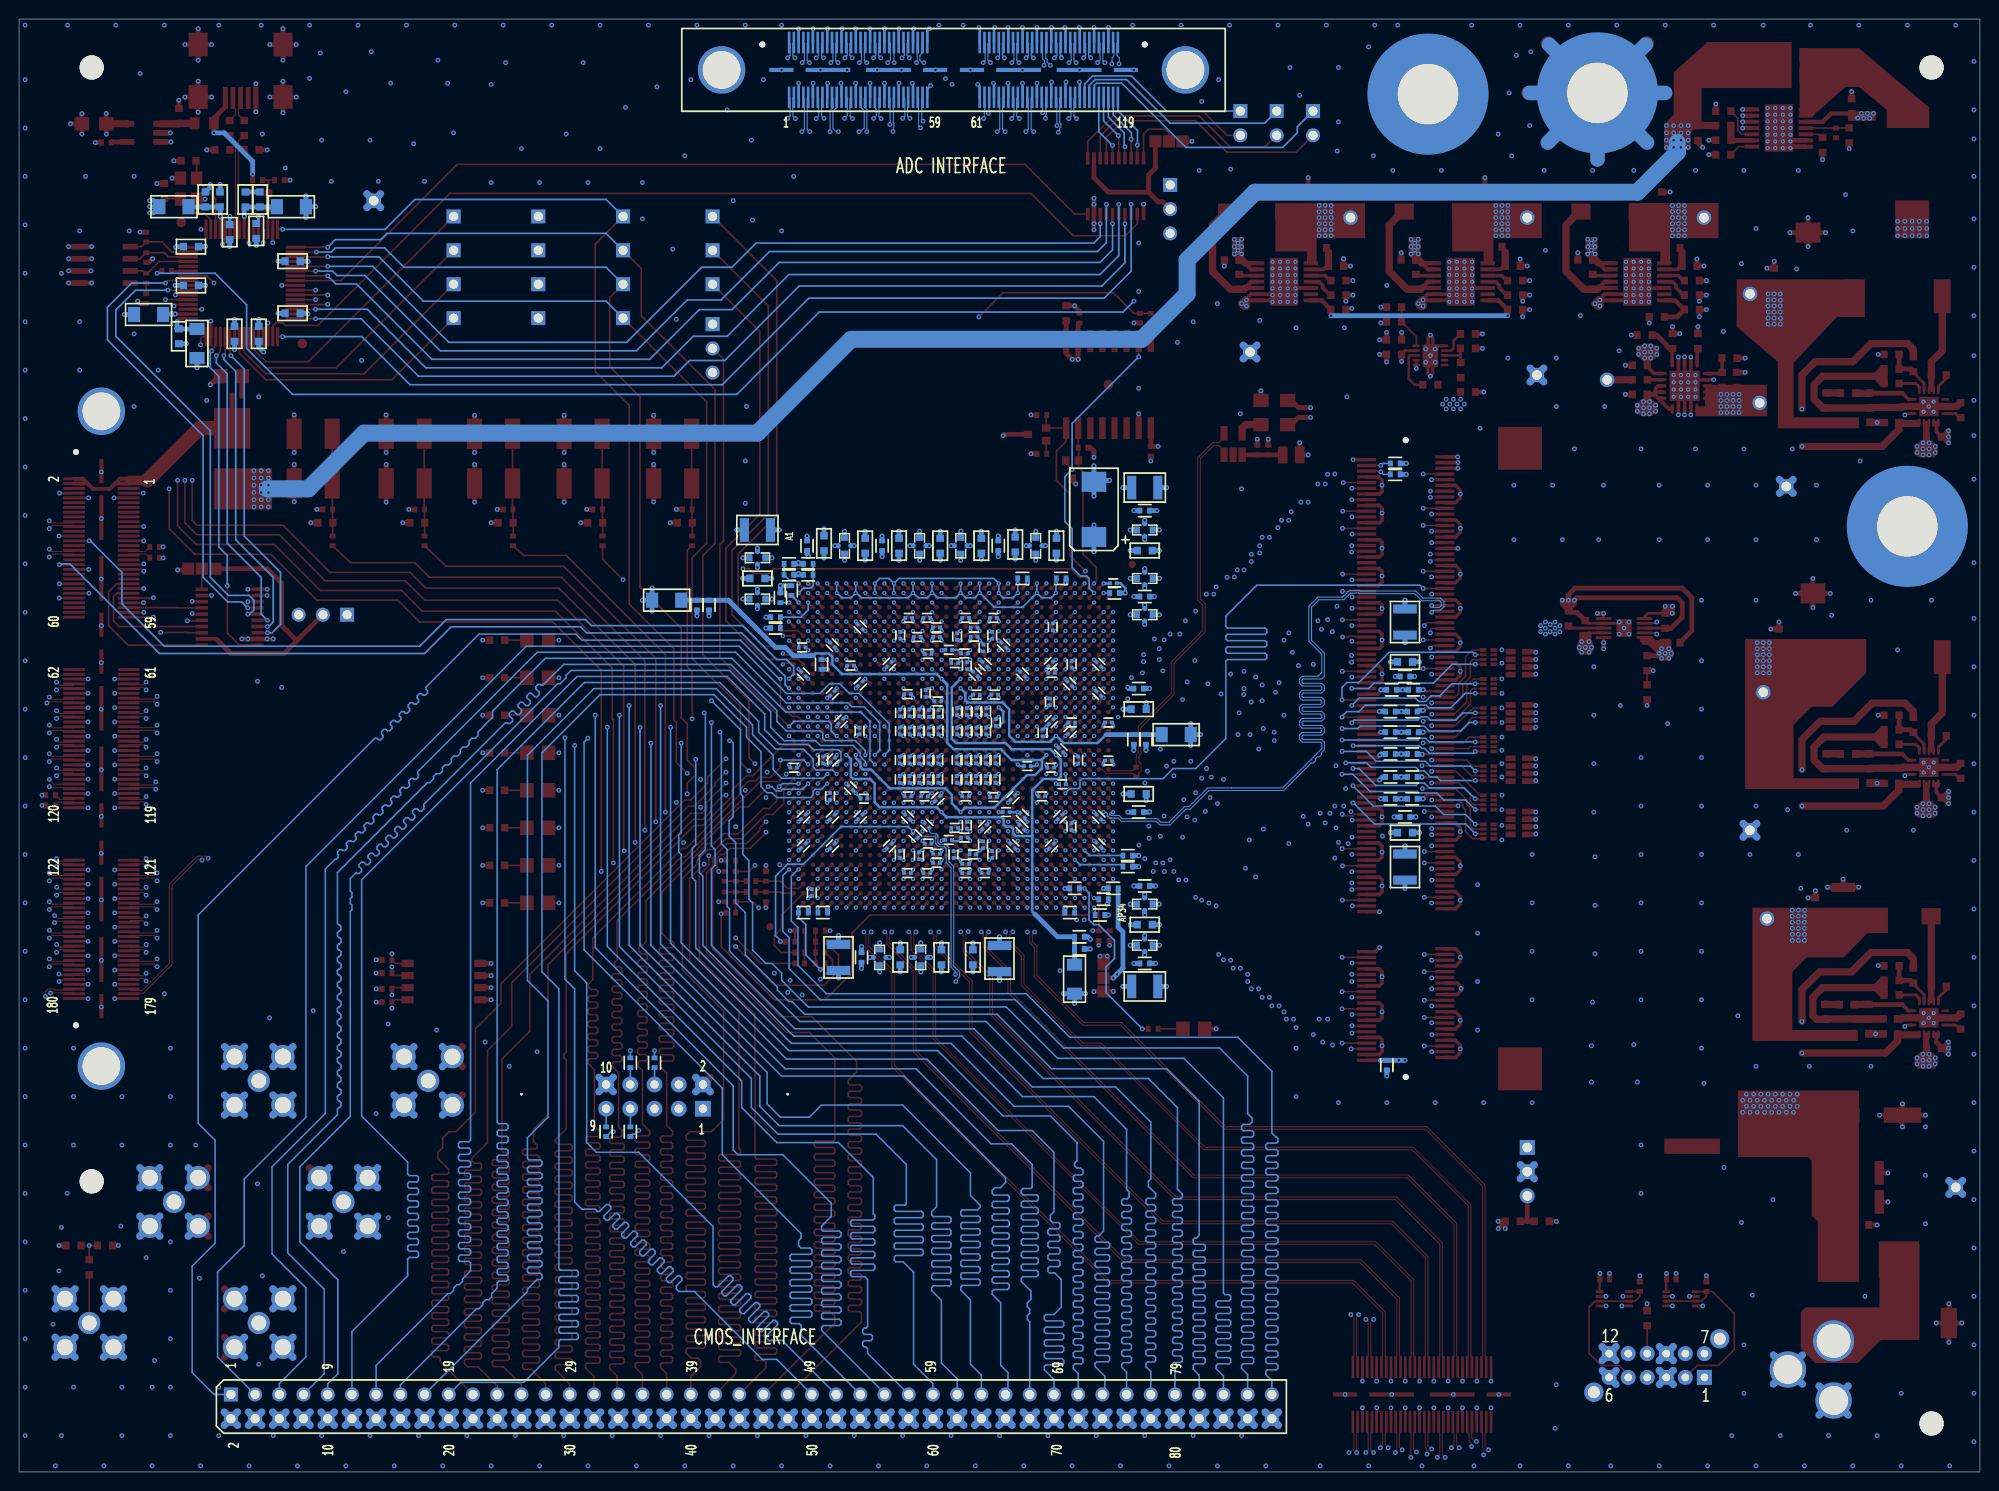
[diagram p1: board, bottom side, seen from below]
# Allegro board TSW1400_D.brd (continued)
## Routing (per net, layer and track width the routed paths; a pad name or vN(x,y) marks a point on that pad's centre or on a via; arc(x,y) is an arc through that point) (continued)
DDR2_DQ20: length 82.3
  TOP w0.165: v1(57.53,59.68) 57.66,59.68 J6.44 ; U5.AN21 v2(91.95,72.2)
  L3-SIG1 w0.114: v1(80.64,72.89) 81.21,72.32 81.21,70.35 80.84,69.98 80.84,59.74 v1(80.9,59.68)
  L4-SIG2 w0.102: v2(91.95,72.2) 91.96,72.21 91.52,72.64 90.47,72.64
  L4-SIG2 w0.114: v1(80.64,72.89) 80.66,72.89 81.17,72.38 81.47,72.38 81.49,72.36 81.83,72.36 81.85,72.38 82.16,72.38 82.37,72.59 84.39,72.59 84.4,72.59 84.76,72.59 84.77,72.59 87.04,72.59 87.15,72.7 87.96,72.7 88.02,72.64 90.47,72.64 ; v1(57.53,59.68) 59.81,57.4 65.78,57.4 65.9,57.52 65.9,58.46 66.01,58.57 66.24,58.57 66.36,58.46 66.36,57.52 66.47,57.4 66.7,57.4 66.81,57.52 66.81,58.46 66.93,58.57 67.16,58.57 67.27,58.46 67.27,57.52 67.38,57.4 67.61,57.4 67.73,57.52 67.73,58.46 67.84,58.57 68.07,58.57 68.18,58.46 68.18,57.52 68.3,57.4 68.53,57.4 68.64,57.52 68.64,58.46 68.76,58.57 68.98,58.57 69.1,58.46 69.1,57.52 69.21,57.4 69.44,57.4 69.56,57.52 69.56,58.46 69.67,58.57 69.9,58.57 70.01,58.46 70.01,57.52 70.13,57.4 70.36,57.4 70.47,57.52 70.47,58.46 70.58,58.57 70.81,58.57 70.93,58.46 70.93,57.52 71.04,57.4 71.27,57.4 71.38,57.52 71.38,58.46 71.5,58.57 71.73,58.57 71.84,58.46 71.84,57.52 71.96,57.4 72.18,57.4 72.3,57.52 72.3,58.46 72.41,58.57 72.64,58.57 72.76,58.46 72.76,57.52 72.87,57.4 73.1,57.4 73.21,57.52 73.21,58.46 73.33,58.57 73.56,58.57 73.67,58.46 73.67,57.52 73.78,57.4 74.01,57.4 74.13,57.52 74.13,58.46 74.24,58.57 74.47,58.57 74.58,58.46 74.58,57.52 74.7,57.4 74.93,57.4 75.04,57.52 75.04,58.46 75.16,58.57 75.38,58.57 75.5,58.46 75.5,57.52 75.61,57.4 75.84,57.4 75.96,57.52 75.96,58.46 76.07,58.57 76.3,58.57 76.41,58.46 76.41,57.52 76.53,57.4 76.76,57.4 76.87,57.52 76.87,58.46 76.99,58.57 77.21,58.57 77.33,58.46 77.33,57.52 77.44,57.4 77.67,57.4 77.79,57.52 77.79,58.46 77.9,58.57 78.13,58.57 78.24,58.46 78.24,57.52 78.36,57.4 78.97,57.4 80.9,59.33 v1(80.9,59.68)
DDR2_DQ21: length 82.3
  TOP w0.165: v1(58.29,60.28) J6.46 ; U5.AK21 v2(94.95,72.2)
  L3-SIG1 w0.114: v1(82.3,60.28) 81.79,60.79 81.79,72.64 v1(81.66,72.77)
  L4-SIG2 w0.114: v1(82.3,60.28) 82.3,60.33 82.14,60.48 81.2,60.48 81.09,60.37 81.09,60.34 80.98,60.22 80.75,60.22 80.64,60.34 80.64,60.82 80.52,60.93 80.29,60.93 80.18,60.82 80.18,60.34 80.07,60.22 79.84,60.22 79.72,60.34 79.72,60.82 79.61,60.93 79.38,60.93 79.27,60.82 79.27,60.34 79.15,60.22 78.92,60.22 78.81,60.34 78.81,60.82 78.69,60.93 78.47,60.93 78.35,60.82 78.35,60.34 78.24,60.22 78.01,60.22 77.89,60.34 77.89,60.82 77.78,60.93 77.55,60.93 77.44,60.82 77.44,60.34 77.32,60.22 77.09,60.22 76.98,60.34 76.98,60.82 76.87,60.93 76.64,60.93 76.52,60.82 76.52,60.34 76.41,60.22 76.18,60.22 76.07,60.34 76.07,60.82 75.95,60.93 75.72,60.93 75.61,60.82 75.61,60.34 75.49,60.22 75.27,60.22 75.15,60.34 75.15,60.82 75.04,60.93 74.81,60.93 74.69,60.82 74.69,60.34 74.58,60.22 74.35,60.22 74.24,60.34 74.24,60.82 74.12,60.93 73.89,60.93 73.78,60.82 73.78,60.34 73.66,60.22 73.44,60.22 73.32,60.34 73.32,60.82 73.21,60.93 72.98,60.93 72.86,60.82 72.86,60.34 72.75,60.22 72.52,60.22 72.41,60.34 72.41,60.82 72.29,60.93 72.06,60.93 71.95,60.82 71.95,60.34 71.84,60.22 71.61,60.22 71.49,60.34 71.49,60.82 71.38,60.93 71.15,60.93 71.04,60.82 71.04,60.34 70.92,60.22 70.69,60.22 70.58,60.34 70.58,60.82 70.46,60.93 70.24,60.93 70.12,60.82 70.12,60.34 70.01,60.22 69.78,60.22 69.66,60.34 69.66,60.82 69.55,60.93 69.32,60.93 69.21,60.82 69.21,60.34 69.09,60.22 68.86,60.22 68.75,60.34 68.75,60.82 68.64,60.93 68.41,60.93 68.29,60.82 68.29,60.34 68.18,60.22 67.95,60.22 67.84,60.34 67.84,60.46 67.49,60.81 66.7,60.81 66.07,60.17 65.16,60.17 64.97,59.98 64.97,59.7 64.86,59.59 64.63,59.59 64.51,59.7 64.51,60.49 64.4,60.6 64.17,60.6 64.06,60.49 64.06,59.7 63.94,59.59 63.71,59.59 63.6,59.7 63.6,60.49 63.48,60.6 63.26,60.6 63.14,60.49 63.14,59.7 63.03,59.59 62.8,59.59 62.68,59.7 62.68,60.49 62.57,60.6 62.34,60.6 62.23,60.49 62.23,59.7 62.11,59.59 61.88,59.59 61.77,59.7 61.77,60.49 61.66,60.6 61.43,60.6 61.31,60.49 61.31,59.7 61.2,59.59 60.97,59.59 60.86,59.7 60.86,60.49 60.74,60.6 60.51,60.6 60.4,60.49 60.4,59.7 60.28,59.59 60.06,59.59 59.94,59.7 59.94,60.49 59.83,60.6 59.6,60.6 59.48,60.49 59.48,59.7 59.37,59.59 58.98,59.59 58.88,59.69 58.88,60.07 58.67,60.27 58.3,60.27 v1(58.29,60.28)
  L10-SIG4 w0.102: 89.99,73.05 90.12,72.92 92.15,72.92 92.49,72.59 94.58,72.59 94.96,72.21 v2(94.95,72.2)
  L10-SIG4 w0.114: v1(81.66,72.77) 83.64,72.77 84.12,72.29 86.06,72.29 86.82,73.05 89.99,73.05
DDR2_DQ22: length 82.2
  TOP w0.165: U5.AM20 v2(92.95,73.2) ; J6.56 v1(57.53,63.28)
  L4-SIG2 w0.102: 92.94,73.21 92.95,73.2 v2(92.95,73.2)
  L4-SIG2 w0.114: 92.94,73.21 92.76,73.03 87.89,73.03 87.86,72.99 84.61,72.99 v1(84.58,73.03) ; v1(57.53,63.28) 58.51,63.28 58.63,63.39 58.63,63.42 58.74,63.53 58.97,63.53 59.09,63.42 59.09,63.14 59.2,63.03 59.43,63.03 59.54,63.14 59.54,63.42 59.66,63.53 59.89,63.53 60,63.42 60,63.14 60.12,63.03 60.34,63.03 60.46,63.14 60.46,63.42 60.57,63.53 60.8,63.53 60.92,63.42 60.92,63.14 61.03,63.03 61.26,63.03 61.37,63.14 61.37,63.42 61.49,63.53 61.72,63.53 61.83,63.42 61.83,63.14 61.94,63.03 62.17,63.03 62.29,63.14 62.29,63.42 62.4,63.53 62.63,63.53 62.74,63.42 62.74,63.14 62.86,63.03 63.09,63.03 63.2,63.14 63.2,63.42 63.32,63.53 63.54,63.53 63.66,63.42 63.66,63.14 63.77,63.03 64,63.03 64.12,63.14 64.12,63.16 64.23,63.28 64.66,63.28 64.88,63.5 66.19,63.5 66.6,63.09 67.34,63.09 67.45,62.98 67.45,62.93 67.56,62.81 67.79,62.81 67.91,62.93 67.91,63.26 68.02,63.37 68.25,63.37 68.36,63.26 68.36,62.93 68.48,62.81 68.71,62.81 68.82,62.93 68.82,63.26 68.94,63.37 69.17,63.37 69.28,63.26 69.28,62.93 69.39,62.81 69.62,62.81 69.74,62.93 69.74,63.26 69.85,63.37 70.08,63.37 70.19,63.26 70.19,62.93 70.31,62.81 70.54,62.81 70.65,62.93 70.65,63.26 70.77,63.37 70.99,63.37 71.11,63.26 71.11,62.93 71.22,62.81 71.45,62.81 71.57,62.93 71.57,63.26 71.68,63.37 71.91,63.37 72.02,63.26 72.02,62.93 72.14,62.81 72.37,62.81 72.48,62.93 72.48,63.26 72.59,63.37 72.82,63.37 72.94,63.26 72.94,62.93 73.05,62.81 73.28,62.81 73.39,62.93 73.39,63.26 73.51,63.37 73.74,63.37 73.85,63.26 73.85,62.93 73.97,62.81 74.19,62.81 74.31,62.93 74.31,63.26 74.42,63.37 74.65,63.37 74.77,63.26 74.77,62.93 74.88,62.81 75.11,62.81 75.22,62.93 75.22,63.26 75.34,63.37 75.57,63.37 75.73,63.21 76.14,63.21 76.56,62.79 77.29,62.79 77.57,63.07 77.88,63.07 78.04,62.9 78.16,62.79 78.38,62.79 78.5,62.9 78.5,63.23 78.61,63.35 78.84,63.35 78.96,63.23 78.96,62.9 79.07,62.79 79.3,62.79 79.41,62.9 79.41,63.23 79.53,63.35 79.76,63.35 79.87,63.23 79.87,62.9 79.98,62.79 80.21,62.79 80.33,62.9 80.33,63.23 80.44,63.35 80.67,63.35 80.78,63.23 80.78,62.9 80.9,62.79 81.13,62.79 81.24,62.9 81.24,63.23 81.36,63.35 81.58,63.35 81.7,63.23 81.7,62.9 81.81,62.79 82.04,62.79 82.16,62.9 82.16,63.23 82.27,63.35 82.5,63.35 82.61,63.23 82.61,62.9 82.73,62.79 82.96,62.79 83.07,62.9 83.07,63.23 83.18,63.35 83.41,63.35 83.53,63.23 83.53,62.9 83.64,62.79 84.02,62.79 84.58,62.23 84.58,61.79 84.7,61.68 85.1,61.68 85.22,61.56 85.22,61.33 85.1,61.22 84.46,61.22 84.33,61.09 84.33,60.45 84.71,60.07 85.47,60.07 85.85,60.45 85.85,61.85 85.41,62.29 85.28,62.29 v1(84.58,62.99)
  L9-SIG3 w0.114: v1(84.58,73.03) 84.33,72.77 84.33,72.5 84.21,72.38 84.16,72.38 84.05,72.27 84.05,72.04 84.16,71.93 84.49,71.93 84.61,71.81 84.61,71.58 84.49,71.47 84.16,71.47 84.05,71.36 84.05,71.13 84.16,71.01 84.49,71.01 84.61,70.9 84.61,70.67 84.49,70.56 84.16,70.56 84.05,70.44 84.05,70.21 84.16,70.1 84.49,70.1 84.61,69.98 84.61,69.76 84.49,69.64 83.94,69.64 83.77,69.47 83.77,68.3 82.75,67.28 82.75,67.04 82.64,66.92 82.46,66.92 82.35,66.81 82.35,66.58 82.46,66.46 83.05,66.46 83.16,66.35 83.16,66.12 83.05,66.01 82.46,66.01 82.35,65.89 82.35,65.66 82.46,65.55 83.05,65.55 83.16,65.44 83.16,65.21 83.05,65.09 82.46,65.09 82.35,64.98 82.35,64.75 82.46,64.64 83.05,64.64 83.16,64.52 83.16,64.29 83.05,64.18 82.87,64.18 82.75,64.06 82.75,63.65 83.41,62.99 v1(84.58,62.99)
DDR2_DQ23: length 82.2
  TOP w0.165: J6.58 v1(58.29,63.88) ; U5.AP21 v2(90.95,72.2)
  L4-SIG2 w0.102: 90.93,61.21 90.93,60.76 90.83,60.66 90.53,60.66 90.42,60.56 90.42,60.36 90.53,60.26 90.83,60.26 90.93,60.15 90.93,59.95 90.83,59.85 90.53,59.85 90.42,59.75 90.42,59.54 90.53,59.44 90.83,59.44 90.93,59.34 90.93,59.14 90.83,59.04 90.53,59.04 90.42,58.93 90.42,58.73 90.53,58.63 90.83,58.63 90.93,58.53 90.93,58.29
  L4-SIG2 w0.114: v1(58.29,63.88) 61.29,63.88 61.47,64.06 62.04,64.06 62.16,64.17 62.16,64.18 62.27,64.3 62.5,64.3 62.61,64.18 62.61,63.94 62.73,63.82 62.96,63.82 63.07,63.94 63.07,64.18 63.18,64.3 63.41,64.3 63.53,64.18 63.53,63.94 63.64,63.82 63.87,63.82 63.98,63.94 63.98,64.18 64.1,64.3 64.33,64.3 64.44,64.18 64.44,63.94 64.56,63.82 64.78,63.82 64.9,63.94 64.9,64.18 65.01,64.3 65.24,64.3 65.36,64.18 65.36,63.94 65.47,63.82 65.7,63.82 65.81,63.94 65.81,64.18 65.93,64.3 66.16,64.3 66.27,64.18 66.27,64.17 66.38,64.06 67.23,64.06 67.52,63.77 85.09,63.77 85.09,63.75 85.44,63.4 85.75,63.4 86.11,63.04 86.11,62.48 87,61.59 87,59.96 87.11,59.84 88.53,59.84 88.65,59.73 88.65,59.5 88.53,59.39 87.11,59.39 87,59.27 87,58.04 87.22,57.82 88.04,57.82 88.16,57.93 88.16,58.81 88.27,58.93 88.5,58.93 88.61,58.81 88.61,57.93 88.73,57.82 88.96,57.82 89.07,57.93 89.07,58.81 89.19,58.93 89.41,58.93 89.53,58.81 89.53,57.93 89.64,57.82 90.71,57.82 90.93,58.04 90.93,58.29 ; 90.93,61.21 90.68,61.47 89.66,61.47 89.15,60.96 88.65,60.96 87.25,62.36 87.25,63.15 87,63.4 86.2,63.4 v1(85.72,63.88)
  L9-SIG3 w0.102: 90.68,63.75 92.58,63.75 93.47,64.64 93.47,71.25 92.96,71.75 91.41,71.75 90.96,72.21 v2(90.95,72.2)
  L9-SIG3 w0.114: 90.68,63.75 89.5,62.58 86.47,62.58 85.98,63.07 85.98,63.62 v1(85.72,63.88)
DDR2_DQ24: length 82.2
  TOP w0.165: J6.61 v1(65.9,64.78) ; U5.AM10 v2(92.95,84.2)
  L3-SIG1 w0.114: v1(85.72,84.02) 85.85,83.9 85.85,83.4 86.08,83.17 86.08,82.95 85.97,82.83 85.74,82.83 85.62,82.72 85.62,82.49 85.74,82.37 85.97,82.37 86.08,82.26 86.08,82.03 85.97,81.92 85.74,81.92 85.62,81.8 85.62,81.57 85.74,81.46 85.97,81.46 86.08,81.34 86.08,81.12 85.97,81 85.74,81 85.62,80.89 85.62,80.66 85.74,80.54 85.97,80.54 86.08,80.43 86.08,80.2 85.97,80.09 85.74,80.09 85.62,79.97 85.62,79.74 85.74,79.63 85.97,79.63 86.08,79.52 86.08,79.29 85.97,79.17 85.74,79.17 85.62,79.06 85.62,78.83 85.74,78.72 85.97,78.72 86.08,78.6 86.08,78.37 85.97,78.26 85.74,78.26 85.62,78.14 85.62,77.92 85.74,77.8 85.97,77.8 86.08,77.69 86.08,77.46 85.85,77.23 85.85,76.83 86.39,76.3 86.39,75.65 86.36,75.62 86.36,69.72 86.49,69.6 v1(86.49,63.88)
  L4-SIG2 w0.102: 90.17,85.27 90.3,85.27 90.45,85.12 90.45,84.91 90.32,84.79 90.17,84.79 ; 90.14,84.12 90.75,84.73 91.62,84.73 91.62,84.73 94.11,84.73 94.44,84.4 94.44,84.07 94.16,83.79 94.16,83.62 94.31,83.46 94.54,83.46 94.79,83.72 95.28,83.72 95.45,83.54 95.45,83.06 95.25,82.85 95.25,82.55 95.45,82.35 95.45,81.92 95.22,81.69 94.56,81.69 94.41,81.84 94.41,82.45 94.23,82.63 93.65,82.63 93.47,82.45 93.47,81.81 93.34,81.69 92.61,81.69 92.46,81.84 92.46,82.55 92.66,82.75 93.24,82.75 93.45,82.96 93.45,83.72 92.96,84.2 v2(92.95,84.2)
  L4-SIG2 w0.114: 90.17,85.27 89.94,85.27 89.79,85.42 89.79,85.7 89.69,85.8 89.41,85.8 89.31,85.7 89.31,84.68 89.2,84.58 88.87,84.58 88.77,84.68 88.77,85.72 88.67,85.83 88.37,85.83 88.27,85.72 88.27,84.53 88.06,84.33 87.53,84.33 87.35,84.51 87.35,84.71 87.25,84.81 86.97,84.81 86.84,84.68 86.84,84.45 86.72,84.33 86.51,84.33 86.2,84.02 85.73,84.02 v1(85.72,84.02) ; 90.14,84.12 89.7,83.68 89.44,83.68 89.28,83.85 88.93,83.85 88.8,83.72 88.54,83.72 88.42,83.84 88.42,84.05 88.57,84.2 89.46,84.2 90.04,84.79 90.17,84.79
  L10-SIG4 w0.114: v1(86.49,63.88) 86.49,64.31 86.08,64.72 84.66,64.72 84.33,64.39 77.99,64.39 77.88,64.5 77.54,64.5 77.48,64.45 77.48,64.33 77.42,64.27 77.08,64.27 77.02,64.33 77.02,64.45 76.96,64.5 76.62,64.5 76.56,64.45 76.56,64.33 76.51,64.27 76.16,64.27 76.11,64.33 76.11,64.45 76.05,64.5 75.71,64.5 75.65,64.45 75.65,64.33 75.59,64.27 75.25,64.27 75.19,64.33 75.19,64.45 75.13,64.5 74.79,64.5 74.73,64.45 74.73,64.33 74.68,64.27 74.33,64.27 74.28,64.33 74.28,64.45 74.22,64.5 73.88,64.5 73.82,64.45 73.82,64.33 73.76,64.27 73.42,64.27 73.36,64.33 73.36,64.45 73.3,64.5 72.96,64.5 72.91,64.45 72.91,64.33 72.85,64.27 72.51,64.27 72.45,64.33 72.45,64.45 72.39,64.5 72.05,64.5 71.99,64.45 71.99,64.33 71.93,64.27 71.59,64.27 71.53,64.33 71.53,64.45 71.48,64.5 71.13,64.5 71.08,64.45 71.08,64.33 71.02,64.27 70.68,64.27 70.56,64.39 69.93,64.39 69.44,64.87 66,64.87 v1(65.9,64.78)
DDR2_DQ25: length 82.2
  TOP w0.165: J6.63 v1(66.93,65.38) ; U5.AL10 v2(93.95,84.2)
  L3-SIG1 w0.102: 92.46,58.29 92.46,62.46 92.95,62.95 v2(92.95,63.2) ; 90.11,61.09 90.65,61.09 91.47,61.9 91.47,62.41 91.8,62.74 92.1,62.74 92.53,63.17 92.53,63.55 93.5,64.52 93.5,70.46 93.75,70.71 94.06,70.71 94.41,71.07 94.41,71.48 94.64,71.7 95.02,71.7 95.48,72.16 95.48,75.49 95.71,75.72 97.05,75.72 97.51,76.17 99.21,76.17 99.57,76.53 99.57,78.61 99.47,78.71 99.47,79.43 99.09,79.81 95.73,79.81 95.56,79.98 95.56,80.52 95.81,80.77 96.09,80.77 96.42,81.1 96.42,82.4 96.11,82.7 95.81,82.7 95.45,83.06 95.45,83.26 95,83.72 94.84,83.72 94.36,84.2 v2(93.95,84.2)
  L3-SIG1 w0.114: 90.11,61.09 89.99,60.97 89.99,60.81 90.11,60.69 90.79,60.69 90.91,60.58 90.91,60.35 90.79,60.23 90.11,60.23 89.99,60.12 89.99,59.89 90.11,59.78 90.79,59.78 90.91,59.66 90.91,59.43 90.79,59.32 90.11,59.32 89.99,59.21 89.99,58.98 90.11,58.86 90.79,58.86 90.91,58.75 90.91,58.52 90.79,58.41 90.11,58.41 89.99,58.29 89.99,58.01 90.27,57.73 91.95,57.73 92.46,58.24 92.46,58.29
  L10-SIG4 w0.102: v2(92.95,63.2) 92.95,63.2 92.99,63.2 93.18,63.39 93.18,63.53 91.97,64.74 90.17,64.74
  L10-SIG4 w0.114: v1(66.93,65.38) 70.05,65.38 70.59,64.85 84.12,64.85 84.48,65.2 89.41,65.2 89.87,64.74 90.17,64.74
DDR2_DQ26: length 82.2
  TOP w0.165: U5.AL9 v2(93.95,85.2) ; J6.73 v1(65.86,68.38)
  L3-SIG1 w0.114: v1(82.37,85.1) 82.07,84.8 82.07,84.45 82.18,84.34 82.44,84.34 82.55,84.22 82.55,83.99 82.44,83.88 81.7,83.88 81.58,83.76 81.58,83.54 81.7,83.42 82.44,83.42 82.55,83.31 82.55,83.08 82.44,82.96 81.7,82.96 81.58,82.85 81.58,82.62 81.7,82.51 82.44,82.51 82.55,82.39 82.55,82.16 82.44,82.05 81.7,82.05 81.58,81.93 81.58,81.71 81.7,81.59 82.44,81.59 82.55,81.48 82.55,81.25 82.44,81.13 81.7,81.13 81.58,81.02 81.58,80.79 81.7,80.68 82.44,80.68 82.55,80.56 82.55,80.33 82.44,80.22 81.7,80.22 81.58,80.11 81.58,79.88 81.7,79.76 82.44,79.76 82.55,79.65 82.55,79.42 82.44,79.31 82.18,79.31 81.69,78.81 81.69,78.23 82.27,77.65 82.27,77.11 81.66,76.5 81.66,76.06 81.78,75.95 82.16,75.95 82.27,75.83 82.27,75.6 82.16,75.49 81.78,75.49 81.66,75.38 81.66,75.15 81.78,75.03 82.16,75.03 82.27,74.92 82.27,74.69 82.16,74.58 81.78,74.58 81.66,74.46 81.66,73.61 82.73,72.54 82.73,70.92 82.37,70.56 v1(82.37,68.38)
  L4-SIG2 w0.102: v2(93.95,85.2) 94.34,85.2 94.49,85.34 94.49,85.47 94.23,85.72 92.71,85.72 92.46,85.98 92.46,86.36 92.33,86.49 92.33,86.87 92.46,87 92.46,87.38 92.71,87.63 93.07,87.63 93.45,88.01 93.45,88.54 93.22,88.77 92.66,88.77 92.41,88.52 92.41,87.96 92.2,87.76 91.57,87.76 91.44,87.63 91.44,86.87
  L4-SIG2 w0.114: v1(82.37,85.1) 82.37,85.6 82.5,85.72 86.31,85.72 86.59,86 86.59,86.69 86.84,86.94 87.12,86.94 87.27,86.79 87.27,86.59 87.39,86.47 87.62,86.47 87.73,86.59 87.73,87.1 87.85,87.21 88.07,87.21 88.19,87.1 88.19,86.59 88.3,86.47 88.53,86.47 88.65,86.59 88.65,87.1 88.76,87.21 88.99,87.21 89.1,87.1 89.1,86.59 89.22,86.47 89.45,86.47 89.56,86.59 89.56,87 89.71,87.15 90.25,87.15 90.45,86.94 90.45,86.84 90.68,86.61 91.19,86.61 91.44,86.87
  L10-SIG4 w0.114: v1(82.37,68.38) 81.94,67.94 81.58,67.94 81.4,68.12 81.12,68.12 81.03,68.03 81.03,67.86 80.95,67.77 80.67,67.77 80.58,67.86 80.58,68.03 80.49,68.12 80.21,68.12 80.12,68.03 80.12,67.86 80.03,67.77 79.75,67.77 79.66,67.86 79.66,68.03 79.57,68.12 79.3,68.12 79.21,68.03 79.21,67.86 79.12,67.77 78.84,67.77 78.75,67.86 78.75,68.03 78.66,68.12 78.38,68.12 78.29,68.03 78.29,67.86 78.2,67.77 77.92,67.77 77.83,67.86 77.83,68.03 77.75,68.12 77.47,68.12 77.38,68.03 77.38,67.86 77.29,67.77 77.01,67.77 76.92,67.86 76.92,68.03 76.83,68.12 76.55,68.12 76.46,68.03 76.46,67.86 76.37,67.77 76.09,67.77 75.92,67.94 74.96,67.94 74.6,67.59 74.3,67.59 74.19,67.7 74.19,67.88 74.07,68 73.85,68 73.73,67.88 73.73,67.4 73.62,67.28 73.39,67.28 73.27,67.4 73.27,67.88 73.16,68 72.93,68 72.82,67.88 72.82,67.4 72.7,67.28 72.47,67.28 72.36,67.4 72.36,67.88 72.25,68 72.02,68 71.9,67.88 71.9,67.4 71.79,67.28 71.56,67.28 71.45,67.4 71.45,67.53 71.33,67.64 70.94,67.64 70.74,67.44 68.58,67.44 67.94,68.07 66.67,68.07 65.66,67.06 65.15,67.06 64.77,67.44 64.77,67.94 65.15,68.33 65.81,68.33 v1(65.86,68.38)
DDR2_DQ27: length 82.2
  TOP w0.165: J6.75 65.66,68.98 65.81,68.83 66.76,68.83 v1(66.91,68.98) ; U5.AL8 v2(93.95,86.2)
  L3-SIG1 w0.114: v1(67.46,90.81) 67.46,89.1 66.42,88.06 66.42,87.2 67.56,86.06 67.56,75.36 67.06,74.85 67.06,73.81 67.46,73.41 67.46,72.87 67.21,72.62 67.21,69.29 66.91,68.99 v1(66.91,68.98)
  L4-SIG2 w0.102: 90.17,92.61 90.3,92.48 90.3,91.44 91.44,90.3 91.44,89.92 91.69,89.66 93.34,89.66 93.47,89.53 93.47,89.03 93.85,88.65 94.23,88.65 94.46,88.42 94.46,87.88 94.21,87.63 93.6,87.63 93.47,87.5 93.47,87.12 93.04,86.69 93.04,86.54 93.38,86.2 v2(93.95,86.2)
  L4-SIG2 w0.114: v1(67.46,90.81) 67.72,91.06 68.35,91.06 68.56,90.86 68.81,90.86 68.91,90.96 68.91,91.16 69.01,91.26 69.27,91.26 69.37,91.16 69.37,90.96 69.47,90.86 69.72,90.86 69.83,90.96 69.83,91.16 69.93,91.26 70.18,91.26 70.28,91.16 70.28,90.96 70.38,90.86 70.64,90.86 70.74,90.96 70.74,91.16 70.84,91.26 71.1,91.26 71.2,91.16 71.2,90.96 71.3,90.86 71.55,90.86 71.65,90.96 71.65,91.16 71.76,91.26 72.01,91.26 72.11,91.16 72.11,90.96 72.21,90.86 72.47,90.86 72.57,90.96 72.57,91.16 72.67,91.26 72.92,91.26 73.03,91.16 73.03,90.96 73.13,90.86 73.38,90.86 73.48,90.96 73.48,91.16 73.59,91.26 73.84,91.26 73.94,91.16 73.94,90.96 74.04,90.86 74.3,90.86 74.4,90.96 74.4,91.16 74.5,91.26 74.75,91.26 74.86,91.16 74.86,90.96 74.96,90.86 75.21,90.86 75.31,90.96 75.31,91.16 75.41,91.26 75.67,91.26 75.77,91.16 75.77,90.96 75.87,90.86 76.13,90.86 76.23,90.96 76.23,91.16 76.33,91.26 76.58,91.26 76.68,91.16 76.68,90.96 76.79,90.86 77.04,90.86 77.14,90.96 77.14,91.16 77.24,91.26 77.5,91.26 77.6,91.16 77.6,90.96 77.7,90.86 77.95,90.86 78.06,90.96 78.06,91.16 78.16,91.26 78.41,91.26 78.51,91.16 78.51,90.96 78.61,90.86 78.87,90.86 78.97,90.96 78.97,91.16 79.07,91.26 79.33,91.26 79.43,91.16 79.43,90.96 79.53,90.86 79.78,90.86 79.88,90.96 79.88,91.16 79.99,91.26 80.24,91.26 80.34,91.16 80.34,90.96 80.44,90.86 80.82,90.86 81.69,91.72 81.69,92.99 81.95,93.25 81.95,93.41 81.79,93.57 81.63,93.57 81.37,93.32 81.21,93.32 81.04,93.48 81.04,93.64 81.3,93.9 81.3,94.06 81.14,94.22 80.98,94.22 80.72,93.96 80.56,93.96 80.4,94.13 80.4,94.29 80.66,94.54 80.66,94.71 80.49,94.87 80.33,94.87 79.95,94.49 79.41,94.49 78.99,94.9 78.99,96.01 79.5,96.52 80.52,96.52 84.48,92.56 86.82,92.56 87.35,92.02 88.04,92.02 88.75,92.74 90.04,92.74 90.17,92.61
DDR2_DQ28: length 82.2
  TOP w0.165: J6.62 v1(58.29,65.08) ; U5.AK11 v2(94.95,83.2)
  L10-SIG4 w0.102: 90.17,85.58 91.11,85.58 91.33,85.36 91.33,85.1 91.8,84.63 94.11,84.63 94.44,84.3 94.44,83.71 v2(94.95,83.2)
  L10-SIG4 w0.114: 90.17,85.58 89.2,85.58 86.28,88.49 82.19,88.49 81.82,88.87 67.23,88.87 66.65,88.29 58.09,88.29 57.94,88.44 57.05,88.44 55.19,86.59 55.19,84.18 56.03,83.34 56.03,80.82 56.41,80.44 56.41,80.26 56.2,80.05 55.87,80.05 55.75,79.93 55.75,79.71 55.87,79.59 56.2,79.59 56.31,79.48 56.31,79.25 56.2,79.13 55.87,79.13 55.75,79.02 55.75,78.79 55.87,78.68 56.2,78.68 56.31,78.56 56.31,78.33 56.2,78.22 55.87,78.22 55.75,78.11 55.75,77.88 55.87,77.76 56.2,77.76 56.31,77.65 56.31,77.42 56.2,77.31 55.87,77.31 55.75,77.19 55.75,76.96 55.87,76.85 56.2,76.85 56.31,76.73 56.31,76.51 56.2,76.39 55.87,76.39 55.75,76.28 55.75,76.05 55.87,75.93 56.2,75.93 56.31,75.82 56.31,75.59 56.2,75.48 55.87,75.48 55.75,75.36 55.75,75.13 55.87,75.02 56.2,75.02 56.31,74.9 56.31,74.68 56.2,74.56 55.87,74.56 55.75,74.45 55.75,74.22 55.87,74.1 56.2,74.1 56.31,73.99 56.31,73.76 56.2,73.65 55.87,73.65 55.75,73.53 55.75,73.3 55.87,73.19 56.2,73.19 56.31,73.08 56.31,72.85 56.2,72.73 55.87,72.73 55.75,72.62 55.75,72.39 55.87,72.28 56.2,72.28 56.31,72.16 56.31,71.93 56.2,71.82 55.87,71.82 55.75,71.7 55.75,71.48 55.87,71.36 56.2,71.36 56.31,71.25 56.31,71.02 56.2,70.9 55.87,70.9 55.75,70.79 55.75,70.56 55.87,70.45 56.2,70.45 56.31,70.33 56.31,70.1 56.2,69.99 55.87,69.99 55.75,69.88 55.75,69.65 55.87,69.53 56.2,69.53 56.31,69.42 56.31,69.19 56.2,69.08 55.87,69.08 55.75,68.96 55.75,68.73 55.87,68.62 56.2,68.62 56.31,68.5 56.31,68.28 56.2,68.16 55.87,68.16 55.75,68.05 55.75,67.82 55.87,67.7 56.2,67.7 56.31,67.59 56.31,67.36 56.2,67.25 56.15,67.25 56.03,67.13 56.03,66.27 57.22,65.08 v1(58.29,65.08)
DDR2_DQ29: length 82.2
  TOP w0.165: J6.64 v1(57.53,65.68) ; U5.AJ10 v2(95.95,84.2)
  L4-SIG2 w0.102: v2(97.95,64.2) 97.94,64.21 96.95,64.21 96.39,64.77 93.78,64.77 93.33,65.22 93.33,65.36 93.11,65.58 92.97,65.58 92.96,65.59 92.07,65.59 92.07,65.59 90.55,65.59 90.49,65.65 90.17,65.65
  L4-SIG2 w0.114: v1(57.53,65.68) 56.15,65.68 55.09,64.62 54.18,64.62 51.84,62.28 51.84,61.39 52.65,60.58 53.37,60.58 57.25,64.47 60.35,64.47 62.05,66.17 64.64,66.17 65.47,66.99 66.05,66.99 66.5,66.55 67.69,66.55 68.75,65.49 77.31,65.49 77.36,65.44 82.4,65.44 82.45,65.49 87.92,65.49 88.07,65.34 88.41,65.34 88.65,65.59 88.65,65.65 90.17,65.65
  L9-SIG3 w0.102: v2(95.95,84.2) 95.95,84.01 96.39,83.57 96.39,80.09 96.72,79.76 97.03,79.76 97.41,79.38 97.41,76.96 98.42,75.95 98.42,64.77 97.92,64.26 97.95,64.23 v2(97.95,64.2)
DDR2_DQ30: length 82.2
  TOP w0.165: v1(57.53,68.71) 57.56,68.68 J6.74 ; U5.AH11 v2(96.95,83.2)
  L3-SIG1 w0.114: v1(83.19,82.86) 83.19,79.25 83.31,79.12 83.31,74.3 83.19,74.17 83.19,70.87 82.93,70.61 82.93,69.92 83.19,69.66 v1(83.19,68.71)
  L4-SIG2 w0.114: v1(57.53,68.71) 58.32,67.92 58.83,67.92 58.94,67.81 58.94,67.78 59.06,67.67 59.28,67.67 59.4,67.78 59.4,68.06 59.51,68.17 59.74,68.17 59.86,68.06 59.86,67.78 59.97,67.67 60.2,67.67 60.31,67.78 60.31,68.06 60.43,68.17 60.66,68.17 60.77,68.06 60.77,67.78 60.89,67.67 61.11,67.67 61.23,67.78 61.23,68.06 61.34,68.17 61.57,68.17 61.69,68.06 61.69,67.78 61.8,67.67 62.03,67.67 62.14,67.78 62.14,68.06 62.26,68.17 62.49,68.17 62.6,68.06 62.6,67.78 62.71,67.67 62.94,67.67 63.06,67.78 63.06,68.06 63.17,68.17 63.4,68.17 63.51,68.06 63.51,67.78 63.63,67.67 63.86,67.67 63.97,67.78 63.97,67.78 65.05,68.86 65.81,68.86 65.82,68.85 66.16,68.85 66.17,68.86 66.19,68.86 66.51,68.54 69.29,68.54 69.95,69.2 71.17,69.2 71.58,68.8 72.1,68.8 72.28,68.97 72.56,68.97 72.65,68.88 72.65,68.71 72.74,68.62 73.02,68.62 73.11,68.71 73.11,68.88 73.19,68.97 73.47,68.97 73.56,68.88 73.56,68.71 73.65,68.62 73.93,68.62 74.02,68.71 74.02,68.88 74.11,68.97 74.39,68.97 74.48,68.88 74.48,68.71 74.57,68.62 74.85,68.62 74.93,68.71 74.93,68.88 75.02,68.97 75.3,68.97 75.39,68.88 75.39,68.71 75.48,68.62 75.76,68.62 75.85,68.71 75.85,68.88 75.94,68.97 76.22,68.97 76.31,68.88 76.31,68.71 76.39,68.62 76.67,68.62 76.76,68.71 76.76,68.88 76.85,68.97 77.13,68.97 77.22,68.88 77.22,68.71 77.31,68.62 77.59,68.62 77.68,68.71 77.68,68.88 77.77,68.97 78.05,68.97 78.13,68.88 78.13,68.71 78.22,68.62 78.5,68.62 78.68,68.8 79.31,68.8 79.65,68.45 81.55,68.45 81.92,68.82 83.08,68.82 v1(83.19,68.71)
  L10-SIG4 w0.102: v2(96.95,83.2) 96.47,83.68 96.47,85.55 96.65,85.72 97.23,85.72 97.43,85.52 97.43,83.9 97.61,83.72 98.27,83.72 98.45,83.9 98.45,86.54 98.63,86.72 99.24,86.72 99.44,86.51 99.44,83.03 99.16,82.75 95.86,82.75 95.79,82.82 92.8,82.82 92.79,82.81 91.8,82.81 91.8,82.81 91.09,82.81 91.08,82.81 90.75,82.81 90.74,82.83 90.73,82.83 89.83,83.72
  L10-SIG4 w0.114: v1(83.19,82.86) 83.31,82.98 88.19,82.98 88.61,83.41 88.61,83.48 88.86,83.72 89.83,83.72
DDR2_DQ31: length 82.2
  TOP w0.165: U5.AH12 v2(96.95,82.2) ; J6.76 v1(58.29,69.28)
  L4-SIG2 w0.114: v1(58.29,69.28) 58.82,69.28 58.96,69.14 59.27,69.14 59.34,69.21 59.34,69.35 59.41,69.42 59.73,69.42 59.8,69.35 59.8,69.21 59.87,69.14 60.19,69.14 60.26,69.21 60.26,69.35 60.33,69.42 60.64,69.42 60.71,69.35 60.71,69.21 60.78,69.14 61.1,69.14 61.17,69.21 61.17,69.35 61.24,69.42 61.56,69.42 61.63,69.35 61.63,69.21 61.7,69.14 62.02,69.14 62.09,69.21 62.09,69.35 62.16,69.42 62.47,69.42 62.54,69.35 62.54,69.21 62.61,69.14 62.93,69.14 63,69.21 63,69.35 63.07,69.42 63.39,69.42 63.46,69.35 63.46,69.21 63.53,69.14 63.84,69.14 63.98,69.28 64.43,69.28 64.87,69.72 66.19,69.72 66.5,69.41 67.87,69.41 67.88,69.42 67.91,69.42 68.34,69.85 71.95,69.85 72.16,70.07 72.4,70.07 72.51,69.96 72.51,69.74 72.62,69.63 72.86,69.63 72.97,69.74 72.97,69.96 73.08,70.07 73.32,70.07 73.43,69.96 73.43,69.74 73.53,69.63 73.77,69.63 73.88,69.74 73.88,69.96 73.99,70.07 74.23,70.07 74.34,69.96 74.34,69.74 74.45,69.63 74.69,69.63 74.8,69.74 74.8,69.96 74.9,70.07 75.15,70.07 75.25,69.96 75.25,69.74 75.36,69.63 75.6,69.63 75.71,69.74 75.71,69.96 75.82,70.07 76.06,70.07 76.17,69.96 76.17,69.74 76.28,69.63 76.52,69.63 76.63,69.74 76.63,69.96 76.73,70.07 76.97,70.07 77.08,69.96 77.08,69.74 77.19,69.63 77.43,69.63 77.54,69.74 77.54,69.96 77.65,70.07 77.89,70.07 78,69.96 78,69.74 78.1,69.63 78.35,69.63 78.45,69.74 78.45,69.96 78.56,70.07 78.8,70.07 79.02,69.85 79.5,69.85 79.76,69.6 80.96,69.6 v1(81.28,69.28)
  L10-SIG4 w0.102: 81.29,69.35 81.43,69.49 82.91,69.49 82.98,69.42 84.96,69.42 85.05,69.5 86.24,69.5 86.39,69.35 86.72,69.35 86.72,69.41 86.95,69.65 87.29,69.65 87.62,69.32 88.93,69.32 89.24,69.62 89.58,69.62 89.63,69.57 90.78,69.57 90.79,69.58 91.11,69.58 91.12,69.57 91.78,69.57 91.79,69.58 92.11,69.58 92.12,69.57 92.78,69.57 92.79,69.58 93.11,69.58 93.12,69.57 93.24,69.57 93.5,69.32 93.5,69.09 93.85,68.73 96.01,68.73 96.34,68.4 96.34,67.03 95.9,66.59 94.68,66.59 94.49,66.4 94.49,66.01 94.77,65.74 95.2,65.74 95.45,65.99 95.81,65.99 96.84,67.02 96.84,67.77 96.57,68.04 96.57,68.36 96.82,68.61 97.21,68.61 97.51,68.3 97.51,67.11 97.87,66.75 98.15,66.75 98.45,67.06 98.45,68.38 100.33,70.26 100.33,71.6 99.67,72.26 99.67,72.62 100.16,73.11 100.65,73.11 101.6,74.07 101.6,79.91 100.53,80.98 100.53,81.38 100.2,81.71 97.44,81.71 v2(96.95,82.2)
  L10-SIG4 w0.114: 81.29,69.35 81.28,69.34 v1(81.28,69.28)
DDR2_DQ32: length 82.2
  TOP w0.165: U5.AP31 v2(90.95,62.2) ; J6.123 v1(65.91,83.38)
  L3-SIG1 w0.114: v1(76.01,83.38) 76.01,85.1 76.25,85.34 76.68,85.34 76.99,85.04 76.99,84.53 76.5,84.05 76.5,82.54 76,82.04 76,79.71 76.07,79.64 76.07,76.2 76.2,76.07 76.2,75.56 75.56,74.93 75.56,67.64 75.6,67.61 75.6,67.27 75.56,67.23 75.56,62.86 v1(76.01,62.42)
  L10-SIG4 w0.102: 89.89,58.42 90.47,59 90.47,59.65 90.37,59.75 89.66,59.75 89.56,59.85 89.56,60.05 89.66,60.15 91.29,60.15 91.39,60.26 91.39,60.46 91.29,60.56 89.66,60.56 89.56,60.66 89.56,60.87 89.66,60.97 91.29,60.97 91.39,61.07 91.39,61.27 91.29,61.37 90.58,61.37 90.47,61.48 90.47,61.72 v2(90.95,62.2)
  L10-SIG4 w0.114: v1(76.01,62.42) 76.01,61.46 76.25,61.21 76.57,61.21 76.68,61.1 76.68,60.88 76.8,60.76 77.02,60.76 77.14,60.88 77.14,61.55 77.25,61.67 77.48,61.67 77.6,61.55 77.6,60.88 77.71,60.76 77.94,60.76 78.05,60.88 78.05,61.55 78.17,61.67 78.4,61.67 78.51,61.55 78.51,60.88 78.62,60.76 78.85,60.76 78.97,60.88 78.97,61.55 79.08,61.67 79.31,61.67 79.42,61.55 79.42,60.88 79.54,60.76 79.77,60.76 79.88,60.88 79.88,61.55 80,61.67 80.22,61.67 80.34,61.55 80.34,60.88 80.45,60.76 80.68,60.76 80.8,60.88 80.8,61.55 80.91,61.67 81.14,61.67 81.25,61.55 81.25,60.88 81.37,60.76 81.6,60.76 81.71,60.88 81.71,61.55 81.82,61.67 82.05,61.67 82.17,61.55 82.17,60.88 82.28,60.76 82.51,60.76 82.62,60.88 82.62,61.55 82.74,61.67 82.97,61.67 83.08,61.55 83.08,60.88 83.2,60.76 83.42,60.76 83.54,60.88 83.54,61.55 83.65,61.67 83.88,61.67 84,61.55 84,60.88 84.11,60.76 84.34,60.76 84.45,60.88 84.45,61.55 84.57,61.67 84.8,61.67 84.91,61.55 84.91,61.33 85.02,61.21 85.6,61.21 85.78,61.03 85.78,60.87 85.71,60.79 85.71,60.63 85.87,60.47 86.03,60.47 86.34,60.78 86.51,60.78 86.67,60.62 86.67,60.46 86.35,60.14 86.35,59.98 86.52,59.82 86.68,59.82 86.99,60.13 87.15,60.13 87.31,59.97 87.31,59.81 87,59.5 87,59.34 87.16,59.17 87.32,59.17 87.4,59.25 87.74,59.25 88.57,58.42 89.89,58.42 ; v1(65.91,83.38) v1(76.01,83.38)
DDR2_DQ33: length 82.3
  TOP w0.165: U5.AN30 v2(91.95,63.2) ; J6.125 v1(66.9,83.98)
  L3-SIG1 w0.114: v1(77.06,63.33) 77.34,63.62 77.34,63.88 77.56,64.1 77.56,64.34 77.45,64.45 77.24,64.45 77.13,64.56 77.13,64.8 77.24,64.91 77.45,64.91 77.56,65.01 77.56,65.26 77.45,65.36 77.24,65.36 77.13,65.47 77.13,65.71 77.34,65.93 77.34,66.87 77.13,67.09 77.13,67.33 77.24,67.43 77.45,67.43 77.56,67.54 77.56,67.78 77.45,67.89 77.24,67.89 77.13,68 77.13,68.24 77.24,68.35 77.45,68.35 77.56,68.46 77.56,68.7 77.45,68.81 77.24,68.81 77.13,68.91 77.13,69.16 77.24,69.26 77.45,69.26 77.56,69.37 77.56,69.61 77.45,69.72 77.24,69.72 77.13,69.83 77.13,70.07 77.24,70.18 77.45,70.18 77.56,70.29 77.56,70.53 77.45,70.63 77.24,70.63 77.13,70.74 77.13,70.98 77.24,71.09 77.45,71.09 77.56,71.2 77.56,71.44 77.45,71.55 77.24,71.55 77.13,71.66 77.13,71.9 77.24,72.01 77.45,72.01 77.56,72.11 77.56,72.36 77.45,72.46 77.24,72.46 77.13,72.57 77.13,72.81 77.24,72.92 77.45,72.92 77.56,73.03 77.56,73.27 77.45,73.38 77.24,73.38 77.13,73.49 77.13,73.73 77.39,73.99 77.39,79.1 77.24,79.25 77.24,79.96 77.95,80.67 77.95,81.11 78.16,81.31 78.16,81.56 78.05,81.66 77.85,81.66 77.75,81.77 77.75,82.02 77.85,82.12 78.05,82.12 78.16,82.22 78.16,82.48 78.05,82.58 77.85,82.58 77.75,82.68 77.75,82.93 77.85,83.04 78.05,83.04 78.16,83.14 78.16,83.39 77.95,83.59 77.95,83.92 78.44,84.4 78.44,88.06 77.95,88.54 76.81,88.54 76.71,88.44 76.71,88.04 76.78,87.96 77.62,87.96 77.72,87.86 77.72,87.5 77.6,87.38 76.81,87.38 76.71,87.27 76.71,87 76.81,86.89 77.6,86.89 77.72,86.77 77.72,86.46 77.65,86.39 76.81,86.39 76.73,86.31 76.73,85.95 76.83,85.85 77.19,85.85 77.75,85.29 77.75,84.51 v1(77.22,83.98)
  L10-SIG4 w0.102: 90.58,62.74 91.49,62.74 v2(91.95,63.2)
  L10-SIG4 w0.114: v1(66.9,83.98) 67.41,83.98 67.52,83.86 67.52,83.86 67.64,83.74 67.87,83.74 67.98,83.86 67.98,84.1 68.09,84.21 68.32,84.21 68.44,84.1 68.44,83.86 68.55,83.74 68.78,83.74 68.89,83.86 68.89,84.1 69.01,84.21 69.24,84.21 69.35,84.1 69.35,83.86 69.47,83.74 69.69,83.74 69.81,83.86 69.81,83.86 69.92,83.98 70.61,83.98 70.76,83.82 72.24,83.82 72.4,83.98 72.78,83.98 72.93,83.82 73.23,83.82 73.31,83.9 73.31,84.06 73.39,84.14 73.69,84.14 73.77,84.06 73.77,83.9 73.85,83.82 74.15,83.82 74.23,83.9 74.23,84.06 74.31,84.14 74.6,84.14 74.68,84.06 74.68,83.9 74.76,83.82 75.06,83.82 75.14,83.9 75.14,84.06 75.22,84.14 75.52,84.14 75.6,84.06 75.6,83.9 75.68,83.82 75.98,83.82 76.14,83.98 v1(77.22,83.98) ; 90.58,62.74 90.07,62.23 89.51,62.23 89.39,62.12 89.39,62.06 89.28,61.95 89.05,61.95 88.94,62.06 88.94,62.4 88.82,62.51 88.59,62.51 88.48,62.4 88.48,62.06 88.37,61.95 88.14,61.95 88.02,62.06 88.02,62.4 87.91,62.51 87.68,62.51 87.57,62.4 87.57,62.06 87.45,61.95 87.22,61.95 87.11,62.06 87.11,62.4 86.99,62.51 86.77,62.51 86.65,62.4 86.65,62.06 86.54,61.95 86.31,61.95 86.19,62.06 86.19,62.4 86.08,62.51 85.85,62.51 85.74,62.4 85.74,62.06 85.62,61.95 85.39,61.95 85.28,62.06 85.28,62.12 85.17,62.23 84.71,62.23 83.92,63.02 82.43,63.02 82.21,63.23 81.97,63.23 81.86,63.13 81.86,62.91 81.75,62.8 81.51,62.8 81.4,62.91 81.4,63.13 81.3,63.23 81.05,63.23 80.95,63.13 80.95,62.91 80.84,62.8 80.6,62.8 80.49,62.91 80.49,63.13 80.38,63.23 80.14,63.23 80.03,63.13 80.03,62.91 79.92,62.8 79.68,62.8 79.57,62.91 79.57,63.13 79.47,63.23 79.23,63.23 79.12,63.13 79.12,62.91 79.01,62.8 78.77,62.8 78.66,62.91 78.66,63.13 78.55,63.23 78.31,63.23 78.2,63.13 78.2,62.91 78.1,62.8 77.85,62.8 77.64,63.02 77.37,63.02 v1(77.06,63.33)
DDR2_DQ34: length 82.2
  TOP w0.165: U5.AP30 v2(90.95,63.2) ; v1(65.9,87.15) 65.73,86.98 J6.135
  L9-SIG3 w0.114: v1(86.11,86.36) 85.8,86.66 85.19,86.66 84.96,86.44 84.96,85.53 85.08,85.42 85.13,85.42 85.32,85.23 85.32,85.06 85.22,84.96 84.91,84.96 84.84,84.89 84.84,84.58 84.91,84.51 85.13,84.51 85.24,84.39 85.24,84.16 85.13,84.05 85.08,84.05 84.96,83.93 84.96,83.34 85.05,83.25 85.5,83.25 85.61,83.14 85.61,82.91 85.5,82.79 84.94,82.79 84.82,82.68 84.82,82.45 84.94,82.34 85.5,82.34 85.61,82.22 85.61,81.99 85.5,81.88 84.94,81.88 84.82,81.77 84.82,81.54 84.94,81.42 85.5,81.42 85.61,81.31 85.61,81.08 85.5,80.97 84.94,80.97 84.82,80.85 84.82,80.62 84.94,80.51 85.5,80.51 85.61,80.39 85.61,80.17 85.5,80.05 84.94,80.05 84.82,79.94 84.82,79.71 84.94,79.59 85.5,79.59 85.61,79.48 85.61,79.25 85.5,79.14 84.94,79.14 84.82,79.02 84.82,78.79 84.94,78.68 85.5,78.68 85.61,78.57 85.61,78.34 85.5,78.22 85.33,78.22 85.22,78.11 85.22,77.6 86.61,76.2 86.61,75.41 86.73,75.3 86.8,75.3 86.92,75.18 86.92,74.95 86.8,74.84 86.42,74.84 86.31,74.73 86.31,74.5 86.42,74.38 86.8,74.38 86.92,74.27 86.92,74.04 86.8,73.93 86.42,73.93 86.31,73.81 86.31,73.58 86.42,73.47 86.8,73.47 86.92,73.35 86.92,73.13 86.8,73.01 86.42,73.01 86.31,72.9 86.31,72.67 86.42,72.55 86.8,72.55 86.92,72.44 86.92,72.21 86.8,72.1 86.42,72.1 86.31,71.98 86.31,71.75 86.42,71.64 86.8,71.64 86.92,71.53 86.92,71.3 86.8,71.18 86.42,71.18 86.31,71.07 86.31,70.84 86.42,70.73 86.8,70.73 86.92,70.61 86.92,70.38 86.8,70.27 86.42,70.27 86.31,70.15 86.31,69.93 86.42,69.81 86.64,69.6 86.64,69.04 86.39,68.79 86.39,68.5 86.48,68.42 86.65,68.42 86.73,68.33 86.73,68.05 86.65,67.96 86.48,67.96 86.39,67.88 86.39,67.59 86.48,67.5 86.65,67.5 86.73,67.42 86.73,67.13 86.65,67.05 86.48,67.05 86.39,66.96 86.39,66.68 86.48,66.59 86.65,66.59 86.73,66.5 86.73,66.22 86.65,66.13 86.48,66.13 86.39,66.05 86.39,65.76 86.48,65.68 86.65,65.68 86.73,65.59 86.73,65.37 86.41,65.05 86.41,64.77 86.58,64.6 86.91,64.6 87.07,64.44 87.07,64.11 87.45,63.73 87.45,63.42 87.02,62.99 v1(86.74,62.99)
  L10-SIG4 w0.102: v2(90.95,63.2) 90.9,63.25 89,63.25
  L10-SIG4 w0.114: v1(65.9,87.15) 65.9,87.28 66.05,87.44 66.23,87.44 66.6,87.07 67.39,87.07 67.65,86.81 67.65,86.5 67.76,86.39 67.99,86.39 68.1,86.5 68.1,86.73 68.21,86.84 68.45,86.84 68.56,86.73 68.56,86.5 68.67,86.39 68.91,86.39 69.02,86.5 69.02,86.73 69.13,86.84 69.36,86.84 69.47,86.73 69.47,86.5 69.59,86.39 69.82,86.39 69.93,86.5 69.93,86.73 70.04,86.84 70.28,86.84 70.39,86.73 70.39,86.5 70.5,86.39 70.73,86.39 70.85,86.5 70.85,86.73 70.96,86.84 71.19,86.84 71.3,86.73 71.3,86.5 71.41,86.39 71.65,86.39 71.76,86.5 71.76,86.73 71.87,86.84 72.11,86.84 72.33,86.61 73.38,86.61 73.49,86.5 73.49,86.47 73.61,86.36 73.83,86.36 73.95,86.47 73.95,86.75 74.06,86.87 74.29,86.87 74.41,86.75 74.41,86.47 74.52,86.36 74.75,86.36 74.86,86.47 74.86,86.75 74.98,86.87 75.21,86.87 75.32,86.75 75.32,86.47 75.43,86.36 75.66,86.36 75.78,86.47 75.78,86.75 75.89,86.87 76.12,86.87 76.24,86.75 76.24,86.47 76.35,86.36 76.58,86.36 76.69,86.47 76.69,86.75 76.81,86.87 77.04,86.87 77.15,86.75 77.15,86.47 77.26,86.36 77.49,86.36 77.61,86.47 77.61,86.75 77.72,86.87 77.95,86.87 78.06,86.75 78.06,86.47 78.18,86.36 78.41,86.36 78.52,86.47 78.52,86.75 78.64,86.87 78.86,86.87 78.98,86.75 78.98,86.47 79.09,86.36 79.32,86.36 79.44,86.47 79.44,86.75 79.55,86.87 79.78,86.87 79.89,86.75 79.89,86.47 80.01,86.36 80.24,86.36 80.35,86.47 80.35,86.75 80.46,86.87 80.69,86.87 80.81,86.75 80.81,86.47 80.92,86.36 81.15,86.36 81.26,86.47 81.26,86.75 81.38,86.87 81.61,86.87 81.72,86.75 81.72,86.47 81.84,86.36 82.06,86.36 82.18,86.47 82.18,86.75 82.29,86.87 82.52,86.87 82.64,86.75 82.64,86.47 82.75,86.36 82.98,86.36 83.09,86.47 83.09,86.75 83.21,86.87 83.44,86.87 83.55,86.75 83.55,86.47 83.66,86.36 83.89,86.36 84.01,86.47 84.01,86.75 84.12,86.87 84.35,86.87 84.46,86.75 84.46,86.47 84.58,86.36 84.81,86.36 84.92,86.47 84.92,86.5 85.04,86.61 85.85,86.61 v1(86.11,86.36) ; v1(86.74,62.99) 88.75,62.99 89,63.25
DDR2_DQ35: length 82.3
  TOP w0.165: J6.137 65.48,87.58 65.58,87.68 66.22,87.68 66.32,87.58 v1(66.88,87.58) ; U5.AP29 v2(90.95,64.2)
  L3-SIG1 w0.114: v1(84.96,87.88) 84.63,87.55 84.63,87.28 84.52,87.16 84.35,87.16 84.24,87.05 84.24,86.82 84.35,86.71 84.91,86.71 85.03,86.59 85.03,86.36 84.91,86.25 84.35,86.25 84.24,86.13 84.24,85.91 84.35,85.79 84.91,85.79 85.03,85.68 85.03,85.45 84.91,85.33 84.35,85.33 84.24,85.22 84.24,84.99 84.35,84.88 84.91,84.88 85.03,84.76 85.03,84.53 84.91,84.42 84.35,84.42 84.24,84.31 84.24,84.08 84.35,83.96 84.91,83.96 85.03,83.85 85.03,83.62 84.91,83.51 84.35,83.51 84.24,83.39 84.24,83.16 84.35,83.05 84.91,83.05 85.03,82.93 85.03,82.71 84.91,82.59 84.35,82.59 84.24,82.48 84.24,82.25 84.35,82.13 84.91,82.13 85.03,82.02 85.03,81.79 84.91,81.68 84.35,81.68 84.24,81.56 84.24,81.33 84.35,81.22 84.91,81.22 85.03,81.11 85.03,80.88 84.91,80.76 84.35,80.76 84.24,80.65 84.24,80.42 84.35,80.31 84.91,80.31 85.03,80.19 85.03,79.96 84.91,79.85 84.35,79.85 84.24,79.73 84.24,79.51 84.35,79.39 84.91,79.39 85.03,79.28 85.03,79.05 84.91,78.93 84.35,78.93 84.24,78.82 84.24,78.59 84.35,78.48 84.91,78.48 85.03,78.36 85.03,78.13 84.91,78.02 84.35,78.02 84.24,77.9 84.24,77.68 84.35,77.56 84.91,77.56 85.03,77.45 85.03,77.22 84.91,77.1 84.35,77.1 84.24,76.99 84.24,76.76 84.35,76.65 84.91,76.65 85.03,76.53 85.03,76.3 84.91,76.19 84.45,76.19 84.2,75.94 84.2,75.69 84.99,74.9 84.99,74.3 84.84,74.14 84.84,73.79 85.09,73.53 85.09,69.22 84.84,68.96 84.84,64.34 v1(84.96,64.21)
  L10-SIG4 w0.102: v2(90.95,64.2) 90.76,64.01
  L10-SIG4 w0.114: v1(66.88,87.58) 68.43,87.58 68.55,87.46 68.55,87.36 68.66,87.25 68.89,87.25 69,87.36 69,87.79 69.12,87.91 69.35,87.91 69.46,87.79 69.46,87.36 69.57,87.25 69.8,87.25 69.92,87.36 69.92,87.79 70.03,87.91 70.26,87.91 70.37,87.79 70.37,87.36 70.49,87.25 70.72,87.25 70.83,87.36 70.83,87.79 70.95,87.91 71.17,87.91 71.29,87.79 71.29,87.36 71.4,87.25 71.63,87.25 71.96,87.58 72.74,87.58 72.9,87.73 73.65,87.73 73.87,87.52 73.87,87.41 73.98,87.3 74.21,87.3 74.33,87.41 74.33,87.85 74.44,87.96 74.67,87.96 74.78,87.85 74.78,87.41 74.9,87.3 75.13,87.3 75.24,87.41 75.24,87.85 75.36,87.96 75.58,87.96 75.7,87.85 75.7,87.41 75.81,87.3 76.04,87.3 76.16,87.41 76.16,87.85 76.27,87.96 76.5,87.96 76.61,87.85 76.61,87.41 76.73,87.3 76.96,87.3 77.07,87.41 77.07,87.85 77.19,87.96 77.41,87.96 77.53,87.85 77.53,87.41 77.64,87.3 77.87,87.3 77.99,87.41 77.99,87.85 78.1,87.96 78.33,87.96 78.44,87.85 78.44,87.41 78.56,87.3 78.79,87.3 78.9,87.41 78.9,87.85 79.01,87.96 79.24,87.96 79.36,87.85 79.36,87.41 79.47,87.3 79.7,87.3 79.81,87.41 79.81,87.85 79.93,87.96 80.16,87.96 80.27,87.85 80.27,87.41 80.39,87.3 80.61,87.3 80.73,87.41 80.73,87.85 80.84,87.96 81.07,87.96 81.19,87.85 81.19,87.41 81.3,87.3 81.53,87.3 81.64,87.41 81.64,87.85 81.76,87.96 81.99,87.96 82.1,87.85 82.1,87.41 82.21,87.3 82.44,87.3 82.56,87.41 82.56,87.52 82.75,87.71 83.2,87.71 83.44,87.47 84.55,87.47 v1(84.96,87.88) ; 90.76,64.01 87.99,64.01 87.42,63.44 85.91,63.44 85.91,63.44 85.54,63.44 85.54,63.44 85.53,63.44 84.96,64.01 v1(84.96,64.21)
DDR2_DQ36: length 82.2
  TOP w0.165: U5.AN29 v2(91.95,64.2) ; J6.124 57.3,83.68 57.3,83.68 v1(57.53,83.68)
  L3-SIG1 w0.102: 90.17,67.51 90.35,67.51 90.45,67.61 90.45,67.79 90.36,67.89 ; 90.17,68.24 90.36,68.24 90.43,68.31 90.43,68.5 90.37,68.55 90.17,68.55 ; 90.4,66.73 90.47,66.8 90.47,67.03 90.4,67.11 90.17,67.11 ; 90.17,64.95 90.4,64.95 90.53,65.07 90.53,65.43 90.75,65.66 91.21,65.66 91.44,65.43 91.44,64.71 v2(91.95,64.2) ; 90.17,66.27 90.4,66.27 90.5,66.17 90.5,65.89 90.37,65.76 90.17,65.76 ; 90.17,75.44 90.2,75.44 90.29,75.54 90.29,75.7 90.2,75.79 90.17,75.79
  L3-SIG1 w0.114: 90.17,68.55 89.81,68.55 89.71,68.66 89.71,68.78 89.94,69.01 89.94,69.42 89.69,69.67 89.48,69.67 89.33,69.83 89.33,69.97 89.46,70.1 89.81,70.1 89.94,70.23 89.94,70.41 89.46,70.89 89.46,71.5 89.59,71.63 89.89,71.63 90.04,71.78 90.04,72.32 89.81,72.55 89.81,72.88 89.88,72.94 90,72.94 90.07,73.01 90.07,73.34 90,73.4 89.88,73.4 89.81,73.46 89.81,73.79 89.88,73.86 90,73.86 90.07,73.92 90.07,74.25 90,74.31 89.49,74.31 89.41,74.39 89.41,74.6 89.48,74.68 89.99,74.68 90.07,74.75 90.07,74.98 89.99,75.06 89.33,75.06 89.23,75.16 89.23,75.36 89.31,75.44 90.17,75.44 ; 90.17,65.76 90.09,65.76 89.92,65.58 89.92,65.07 90.04,64.95 90.17,64.95 ; 90.17,67.51 89.56,67.51 89.43,67.39 89.43,67.21 89.53,67.11 90.17,67.11 ; 90.17,66.27 89.64,66.27 89.48,66.42 89.48,66.6 89.61,66.73 90.4,66.73 ; v1(89.03,83.31) 88.44,82.73 88.44,82.27 88.6,82.12 88.6,81.81 88.52,81.74 88.37,81.74 88.29,81.66 88.29,81.36 88.37,81.28 88.52,81.28 88.6,81.2 88.6,80.9 88.52,80.82 88.37,80.82 88.29,80.75 88.29,80.44 88.37,80.37 88.52,80.37 88.6,80.29 88.6,79.99 88.52,79.91 88.37,79.91 88.29,79.83 88.29,79.53 88.37,79.45 88.52,79.45 88.6,79.38 88.6,79.07 88.52,78.99 88.37,78.99 88.29,78.92 88.29,78.61 88.37,78.54 88.52,78.54 88.6,78.46 88.6,78.16 88.52,78.08 88.37,78.08 88.29,78 88.29,77.7 88.44,77.55 88.44,77.11 88.57,76.99 89,76.99 89.15,76.84 89.15,76.62 89.03,76.5 88.6,76.5 88.51,76.42 88.51,76.21 88.6,76.12 89.2,76.12 89.38,76.3 89.59,76.3 89.76,76.12 89.76,75.87 89.84,75.79 90.17,75.79 ; 90.17,68.24 89.52,68.24 89.41,68.12 89.41,67.97 89.49,67.89 90.36,67.89
  L4-SIG2 w0.114: v1(57.53,83.68) 57.53,83.08 57.86,82.75 58.94,82.75 59.09,82.6 59.39,82.6 59.47,82.68 59.47,82.83 59.55,82.91 59.85,82.91 59.93,82.83 59.93,82.68 60,82.6 60.31,82.6 60.38,82.68 60.38,82.83 60.46,82.91 60.76,82.91 60.84,82.83 60.84,82.68 60.92,82.6 61.22,82.6 61.3,82.68 61.3,82.83 61.37,82.91 61.68,82.91 61.76,82.83 61.76,82.68 61.83,82.6 62.14,82.6 62.21,82.68 62.21,82.83 62.29,82.91 62.59,82.91 62.67,82.83 62.67,82.68 62.75,82.6 63.05,82.6 63.13,82.68 63.13,82.83 63.2,82.91 63.51,82.91 63.58,82.83 63.58,82.68 63.66,82.6 63.97,82.6 64.04,82.68 64.04,82.83 64.12,82.91 64.42,82.91 64.5,82.83 64.5,82.68 64.57,82.6 64.88,82.6 64.96,82.68 64.96,82.83 65.03,82.91 65.34,82.91 65.41,82.83 65.41,82.68 65.49,82.6 65.79,82.6 65.87,82.68 65.87,82.83 65.95,82.91 66.25,82.91 66.33,82.83 66.33,82.68 66.4,82.6 66.71,82.6 66.78,82.68 66.78,82.83 66.86,82.91 67.17,82.91 67.24,82.83 67.24,82.68 67.32,82.6 67.62,82.6 67.7,82.68 67.7,82.83 67.78,82.91 68.08,82.91 68.16,82.83 68.16,82.68 68.23,82.6 68.54,82.6 68.61,82.68 68.61,82.83 68.74,82.96 68.94,82.96 69.07,82.83 69.07,82.68 69.15,82.6 69.45,82.6 69.53,82.68 69.53,82.83 69.65,82.96 69.86,82.96 69.99,82.83 69.99,82.68 70.06,82.6 70.37,82.6 70.44,82.68 70.44,82.83 70.57,82.96 70.77,82.96 70.9,82.83 70.9,82.68 70.98,82.6 71.28,82.6 71.36,82.68 71.36,82.83 71.48,82.96 71.69,82.96 71.99,82.65 72.26,82.65 72.44,82.83 72.44,83.09 72.26,83.27 72.26,83.48 72.42,83.64 72.58,83.64 72.76,83.46 72.92,83.46 73.1,83.64 73.1,83.77 73.23,83.9 73.63,83.9 73.96,83.57 74.27,83.57 74.6,83.9 74.93,83.9 75.26,83.57 75.46,83.57 75.77,83.87 76.3,83.87 76.92,83.25 77.29,83.25 77.62,83.59 77.95,83.59 78.36,83.19 79.02,83.19 79.49,83.65 83.83,83.65 84.33,83.16 86.67,83.16 86.9,83.39 87.22,83.39 87.59,83.02 87.85,83.02 88.14,83.31 v1(89.03,83.31)
DDR2_DQ37: length 82.3
  TOP w0.165: v1(58.42,84.28) 58.42,84.28 J6.126 ; U5.AP28 v2(90.95,65.2)
  L3-SIG1 w0.102: 90.17,62.69 90.3,62.81 90.3,64.34 90.95,64.99 v2(90.95,65.2)
  L3-SIG1 w0.114: 90.17,62.69 89.38,61.9 84.84,61.9 84.68,62.05 84.68,62.33 84.84,62.48 87.05,62.48 87.25,62.69 87.25,63.65 87.38,63.78 87.63,63.78 87.76,63.65 87.76,62.66 87.91,62.51 89.33,62.51 89.51,62.69 89.51,62.94 89.33,63.12 88.93,63.12 88.75,63.3 88.75,63.58 88.87,63.7 89.36,63.7 89.48,63.83 89.48,64.11 89.33,64.26 88.87,64.26 88.72,64.41 88.72,64.64 88.9,64.82 89.2,64.82 89.51,65.13 89.51,65.63 89,66.15 89,72.23 89.11,72.35 89.36,72.35 89.47,72.46 89.47,72.69 89.36,72.8 88.63,72.8 88.52,72.92 88.52,73.15 88.63,73.26 89.36,73.26 89.47,73.37 89.47,73.6 89.36,73.72 88.63,73.72 88.52,73.83 88.52,74.06 88.63,74.17 88.88,74.17 89,74.29 89,74.53 88.19,75.34 88.19,75.87 87.91,76.15 87.91,83.79 v1(87.88,83.82)
  L4-SIG2 w0.114: v1(87.88,83.82) 86.59,83.82 86.31,83.54 84.94,83.54 84.53,83.95 79.32,83.95 78.85,84.42 77.03,84.42 76.89,84.28 72.31,84.28 71.86,83.82 71.53,83.82 71.42,83.93 71.42,83.99 71.31,84.1 71.08,84.1 70.96,83.99 70.96,83.65 70.85,83.54 70.62,83.54 70.51,83.65 70.51,83.99 70.39,84.1 70.16,84.1 70.05,83.99 70.05,83.65 69.93,83.54 69.71,83.54 69.59,83.65 69.59,83.99 69.48,84.1 69.25,84.1 69.13,83.99 69.13,83.65 69.02,83.54 68.79,83.54 68.68,83.65 68.68,83.99 68.56,84.1 68.33,84.1 68.22,83.99 68.22,83.65 68.11,83.54 67.88,83.54 67.76,83.65 67.76,83.71 67.65,83.82 67.39,83.82 67.11,83.54 66.52,83.54 66.19,83.87 64.16,83.87 63.6,84.43 63.28,84.43 63.2,84.35 63.2,84.2 63.12,84.12 62.82,84.12 62.74,84.2 62.74,84.35 62.67,84.43 62.36,84.43 62.28,84.35 62.28,84.2 62.21,84.12 61.9,84.12 61.83,84.2 61.83,84.35 61.75,84.43 61.45,84.43 61.37,84.35 61.37,84.2 61.29,84.12 60.99,84.12 60.91,84.2 60.91,84.35 60.84,84.43 60.53,84.43 60.46,84.35 60.46,84.2 60.38,84.12 60.07,84.12 60,84.2 60,84.35 59.92,84.43 59.62,84.43 59.54,84.35 59.54,84.2 59.47,84.12 59.16,84.12 59.01,84.28 v1(58.42,84.28)
DDR2_DQ38: length 82.2
  TOP w0.165: U5.AP26 v2(90.95,67.2) ; J6.134 57.4,86.68 v1(57.66,86.42)
  L4-SIG2 w0.114: v1(57.66,86.42) 58.5,86.42 58.62,86.3 58.96,86.3 59.02,86.36 59.02,86.48 59.08,86.54 59.42,86.54 59.48,86.48 59.48,86.36 59.54,86.3 59.87,86.3 59.93,86.36 59.93,86.48 60,86.54 60.33,86.54 60.39,86.48 60.39,86.36 60.45,86.3 60.79,86.3 60.85,86.36 60.85,86.48 60.91,86.54 61.25,86.54 61.31,86.48 61.31,86.36 61.37,86.3 61.7,86.3 61.76,86.36 61.76,86.48 61.82,86.54 62.16,86.54 62.22,86.48 62.22,86.36 62.28,86.3 62.62,86.3 62.68,86.36 62.68,86.48 62.74,86.54 63.07,86.54 63.14,86.48 63.14,86.36 63.2,86.3 63.53,86.3 63.59,86.36 63.59,86.48 63.65,86.54 63.99,86.54 64.05,86.48 64.05,86.36 64.11,86.3 64.45,86.3 64.51,86.36 64.51,86.48 64.57,86.54 64.9,86.54 64.96,86.48 64.96,86.36 65.02,86.3 65.36,86.3 65.42,86.36 65.42,86.48 65.48,86.54 65.82,86.54 65.88,86.48 65.88,86.36 65.94,86.3 66.28,86.3 66.34,86.36 66.34,86.48 66.4,86.54 66.73,86.54 66.79,86.48 66.79,86.36 66.85,86.3 67.19,86.3 67.25,86.36 67.25,86.48 67.31,86.54 67.65,86.54 67.71,86.48 67.71,86.36 67.77,86.3 68.1,86.3 68.16,86.36 68.16,86.48 68.22,86.54 68.56,86.54 68.62,86.48 68.62,86.36 68.68,86.3 69.02,86.3 69.08,86.36 69.08,86.48 69.14,86.54 69.48,86.54 69.54,86.48 69.54,86.36 69.6,86.3 69.93,86.3 69.99,86.36 69.99,86.48 70.05,86.54 70.39,86.54 70.45,86.48 70.45,86.36 70.51,86.3 70.85,86.3 70.91,86.36 70.91,86.48 70.97,86.54 71.3,86.54 71.43,86.42 72.32,86.42 72.5,86.23 72.84,86.23 73.01,86.06 73.29,86.06 73.38,86.14 73.38,86.32 73.47,86.41 73.75,86.41 73.84,86.32 73.84,86.14 73.93,86.06 74.21,86.06 74.3,86.14 74.3,86.32 74.39,86.41 74.66,86.41 74.75,86.32 74.75,86.14 74.84,86.06 75.12,86.06 75.21,86.14 75.21,86.32 75.3,86.41 75.58,86.41 75.67,86.32 75.67,86.14 75.76,86.06 76.04,86.06 76.13,86.14 76.13,86.32 76.21,86.41 76.49,86.41 76.58,86.32 76.58,86.14 76.67,86.06 76.95,86.06 77.04,86.14 77.04,86.32 77.13,86.41 77.41,86.41 77.5,86.32 77.5,86.14 77.59,86.06 77.87,86.06 77.95,86.14 77.95,86.32 78.04,86.41 78.32,86.41 78.41,86.32 78.41,86.14 78.5,86.06 78.78,86.06 78.87,86.14 78.87,86.32 78.96,86.41 79.24,86.41 79.33,86.32 79.33,86.14 79.41,86.06 79.69,86.06 79.78,86.14 79.78,86.32 79.87,86.41 80.15,86.41 80.24,86.32 80.24,86.14 80.33,86.06 80.61,86.06 80.7,86.14 80.7,86.32 80.79,86.41 81.07,86.41 81.15,86.32 81.15,86.14 81.24,86.06 81.52,86.06 81.61,86.14 81.61,86.32 81.7,86.41 81.98,86.41 82.07,86.32 82.07,86.14 82.16,86.06 82.44,86.06 82.53,86.14 82.53,86.32 82.62,86.41 82.89,86.41 82.98,86.32 82.98,86.14 83.07,86.06 83.35,86.06 83.44,86.14 83.44,86.32 83.53,86.41 83.81,86.41 83.9,86.32 83.9,86.14 83.99,86.06 84.27,86.06 84.35,86.14 84.35,86.32 84.44,86.41 84.72,86.41 84.9,86.23 85.34,86.23 86.49,87.38 v1(86.61,87.38)
  L9-SIG3 w0.102: v2(90.95,67.2) 90.93,67.18 90.42,67.18
  L9-SIG3 w0.114: 90.42,67.18 88.7,67.18 88.39,67.49 88.39,67.77 88.28,67.89 88.14,67.89 88.03,68 88.03,68.23 88.14,68.34 88.64,68.34 88.76,68.46 88.76,68.69 88.64,68.8 88.14,68.8 88.03,68.91 88.03,69.14 88.14,69.26 88.64,69.26 88.76,69.37 88.76,69.6 88.64,69.71 88.14,69.71 88.03,69.83 88.03,70.06 88.14,70.17 88.64,70.17 88.76,70.29 88.76,70.51 88.64,70.63 88.14,70.63 88.03,70.74 88.03,70.97 88.14,71.09 88.64,71.09 88.76,71.2 88.76,71.43 88.64,71.54 88.14,71.54 88.03,71.66 88.03,71.89 88.14,72 88.64,72 88.76,72.11 88.76,72.34 88.64,72.46 88.14,72.46 88.03,72.57 88.03,72.8 88.14,72.91 88.64,72.91 88.76,73.03 88.76,73.26 88.64,73.37 88.14,73.37 88.03,73.49 88.03,73.71 88.14,73.83 88.64,73.83 88.76,73.94 88.76,74.17 88.64,74.29 88.14,74.29 88.03,74.4 88.03,74.63 88.14,74.74 88.28,74.74 88.39,74.86 88.39,75.18 88.14,75.44 88.14,75.82 87.5,76.46 87.34,76.46 87.32,76.44 87.16,76.44 87,76.61 87,76.77 87.19,76.96 87.19,77.12 87.03,77.28 86.87,77.28 86.67,77.09 86.51,77.09 86.35,77.25 86.35,77.41 86.37,77.43 86.37,77.59 86.06,77.9 86.06,78.29 86.18,78.4 86.59,78.4 86.71,78.52 86.71,78.75 86.59,78.86 86.18,78.86 86.06,78.97 86.06,79.2 86.18,79.32 86.59,79.32 86.71,79.43 86.71,79.66 86.59,79.77 86.18,79.77 86.06,79.89 86.06,80.12 86.18,80.23 86.59,80.23 86.71,80.35 86.71,80.57 86.59,80.69 86.18,80.69 86.06,80.8 86.06,81.03 86.18,81.15 86.59,81.15 86.71,81.26 86.71,81.49 86.59,81.6 86.18,81.6 86.06,81.72 86.06,81.95 86.18,82.06 86.59,82.06 86.71,82.18 86.71,82.4 86.59,82.52 86.18,82.52 86.06,82.63 86.06,82.86 86.18,82.98 86.59,82.98 86.71,83.09 86.71,83.32 86.59,83.43 86.5,83.43 86.39,83.55 86.39,83.87 86.61,84.1 v1(86.61,87.38)
DDR2_DQ39: length 82.2
  TOP w0.165: J6.136 v1(58.42,87.28) ; U5.AP25 v2(90.95,68.2)
  L4-SIG2 w0.114: v1(85.6,87.28) 85.11,86.79 72.85,86.79 72.52,87.12 66.65,87.12 66.01,87.76 65.35,87.76 65.12,87.99 64.89,87.99 64.78,87.87 64.78,87.64 64.66,87.53 64.44,87.53 64.32,87.64 64.32,87.87 64.21,87.99 63.98,87.99 63.86,87.87 63.86,87.64 63.75,87.53 63.52,87.53 63.14,87.91 62.59,87.91 62.26,87.58 62.06,87.58 61.78,87.86 61.53,87.86 61.43,87.76 61.43,87.55 61.32,87.45 61.07,87.45 60.97,87.55 60.97,87.76 60.87,87.86 60.61,87.86 60.51,87.76 60.51,87.55 60.41,87.45 60.16,87.45 60.05,87.55 60.05,87.76 59.95,87.86 59.7,87.86 59.6,87.76 59.6,87.46 58.93,86.79 58.12,86.79 58.04,86.87 57.4,86.87 56.01,85.47 55.63,85.47 55.5,85.6 55.5,85.98 56.78,87.26 58.4,87.26 v1(58.42,87.28)
  L9-SIG3 w0.114: v1(85.6,68.8) 85.22,68.42 85.22,64.85 85.56,64.51 85.87,64.51 85.98,64.62 85.98,65.96 85.55,66.4 85.55,67.01 86.08,67.54 86.08,69.04 85.93,69.19 85.93,75.16 85.51,75.58 85.51,76.8 85.37,76.94 85.13,76.94 85.01,76.82 85.01,75.44 84.84,75.26 84.55,75.26 84.39,75.43 84.39,75.59 84.55,75.74 84.55,75.9 84.35,76.1 84.35,76.71 84.47,76.83 84.57,76.83 84.68,76.94 84.68,77.17 84.57,77.28 84.47,77.28 84.35,77.4 84.35,77.63 84.47,77.74 84.57,77.74 84.68,77.85 84.68,78.08 84.57,78.2 84.47,78.2 84.35,78.31 84.35,80.11 84.51,80.26 84.51,80.57 84.35,80.72 84.35,81.03 84.51,81.18 84.51,81.48 84.35,81.64 84.35,81.94 84.51,82.09 84.51,82.4 84.35,82.55 84.35,82.86 84.51,83.01 84.51,83.31 84.35,83.47 84.35,83.77 84.51,83.92 84.51,84.23 84.35,84.38 84.35,84.68 84.51,84.84 84.51,85.14 84.35,85.29 84.35,85.6 84.51,85.75 84.51,86.06 84.35,86.21 84.35,86.72 84.92,87.28 v1(85.6,87.28)
  L10-SIG4 w0.102: 90.82,68.33 v2(90.95,68.2)
  L10-SIG4 w0.114: 90.82,68.33 89.03,68.33 88.85,68.5 85.9,68.5 v1(85.6,68.8)
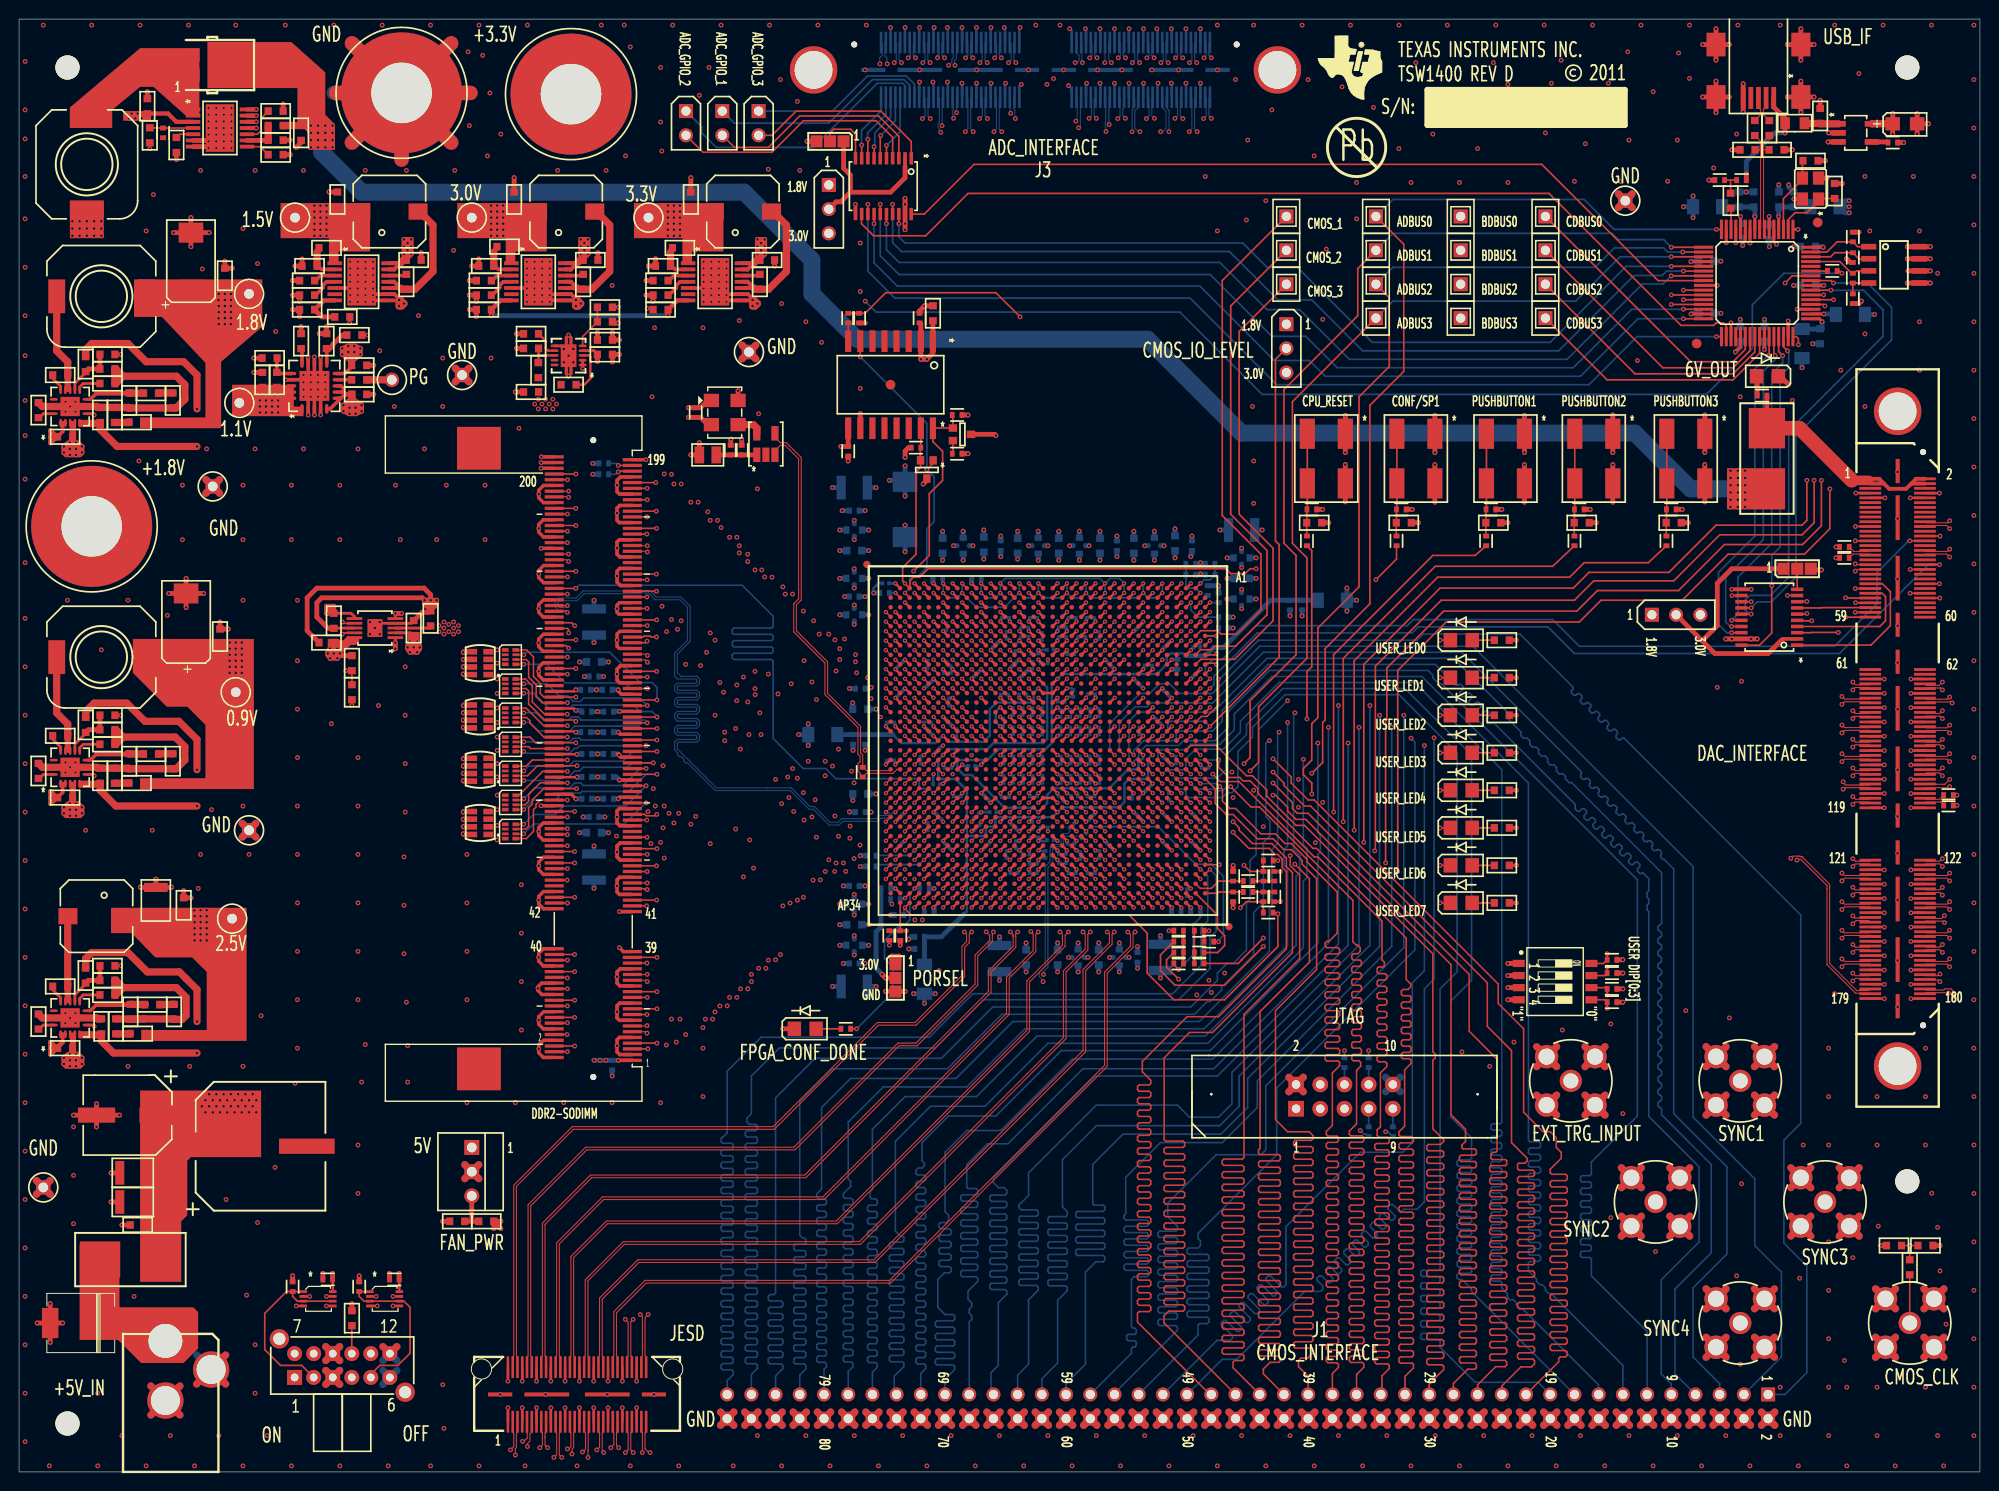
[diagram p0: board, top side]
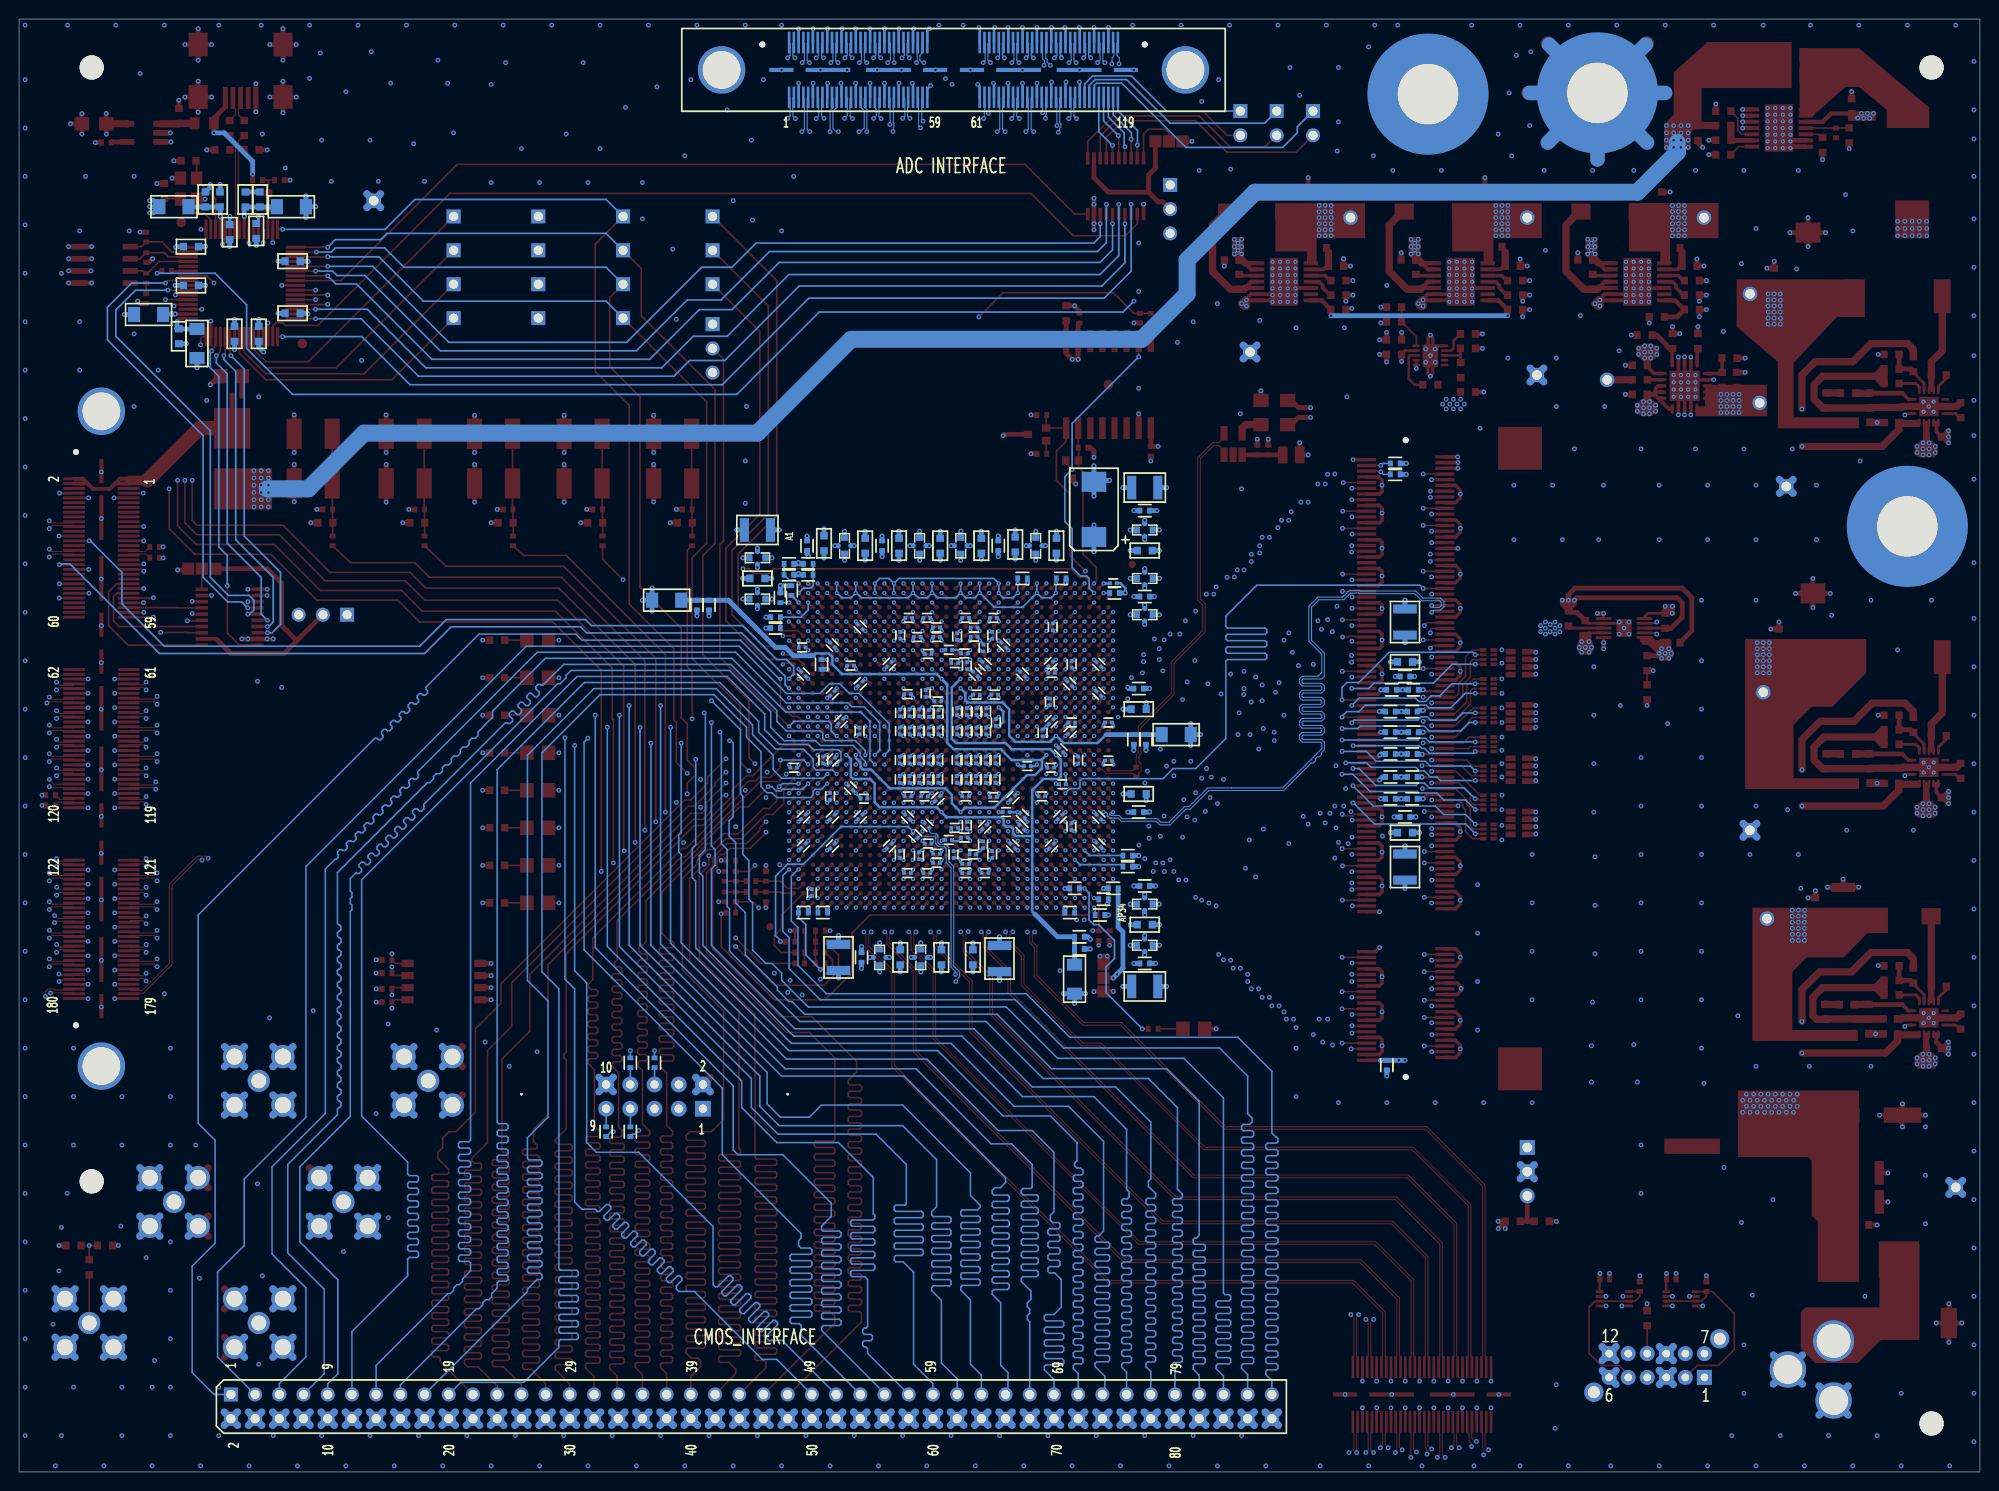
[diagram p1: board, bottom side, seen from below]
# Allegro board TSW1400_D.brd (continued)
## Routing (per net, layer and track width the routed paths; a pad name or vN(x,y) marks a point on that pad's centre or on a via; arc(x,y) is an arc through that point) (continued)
DDR2_DQ40: length 82.2
  TOP w0.165: U5.AP22 v2(90.95,71.2) ; J6.141 v1(65.91,88.78)
  L3-SIG1 w0.114: v1(65.99,69.27) 65,68.28 65,62.79 64.72,62.51 63.93,62.51 63.68,62.76 63.68,68.96 63.02,69.62 62.38,69.62 61.95,70.05 61.95,70.38 62.06,70.5 62.14,70.5 62.26,70.61 62.26,70.84 62.14,70.96 61.76,70.96 61.65,71.07 61.65,71.3 61.76,71.41 62.14,71.41 62.26,71.53 62.26,71.76 62.14,71.87 61.76,71.87 61.65,71.98 61.65,72.21 61.76,72.33 62.14,72.33 62.26,72.44 62.26,72.67 62.14,72.78 61.76,72.78 61.65,72.9 61.65,73.13 61.76,73.24 62.14,73.24 62.26,73.36 62.26,73.58 62.14,73.7 61.76,73.7 61.65,73.81 61.65,74.04 61.76,74.16 62.14,74.16 62.26,74.27 62.26,74.5 62.14,74.61 61.76,74.61 61.65,74.73 61.65,74.96 61.76,75.07 62.14,75.07 62.26,75.19 62.26,75.41 62.14,75.53 61.76,75.53 61.65,75.64 61.65,75.87 61.76,75.99 62.14,75.99 62.26,76.1 62.26,76.33 62.14,76.44 61.76,76.44 61.65,76.56 61.65,76.79 61.76,76.9 62.14,76.9 62.26,77.01 62.26,77.24 62.14,77.36 61.76,77.36 61.65,77.47 61.65,77.7 61.76,77.81 62.14,77.81 62.26,77.93 62.26,78.16 62.14,78.27 61.76,78.27 61.65,78.39 61.65,78.61 61.76,78.73 62.14,78.73 62.26,78.84 62.26,79.07 62.14,79.19 61.76,79.19 61.65,79.3 61.65,79.53 61.76,79.64 62.14,79.64 62.26,79.76 62.26,79.99 62.14,80.1 61.76,80.1 61.65,80.21 61.65,80.44 61.76,80.56 62.14,80.56 62.26,80.67 62.26,80.9 62.14,81.01 61.76,81.01 61.65,81.13 61.65,81.36 61.76,81.47 62.14,81.47 62.26,81.59 62.26,81.81 62.14,81.93 61.76,81.93 61.65,82.04 61.65,82.27 61.76,82.39 62.14,82.39 62.26,82.5 62.26,82.73 62.14,82.84 62.06,82.84 61.95,82.96 61.95,83.95 62.74,84.73 62.74,86.41 65.11,88.78 v1(65.91,88.78)
  L10-SIG4 w0.102: 90.17,71.63 90.6,71.2 v2(90.95,71.2)
  L10-SIG4 w0.114: v1(65.99,69.27) 65.25,69.27 64.9,69.62 64.9,70.51 65.38,70.99 67.08,70.99 67.54,71.45 81.03,71.45 81.79,70.69 82.45,70.69 83.16,71.4 84.43,71.4 84.56,71.27 86.66,71.27 86.86,71.46 89.37,71.46 89.59,71.68 90.12,71.68 90.17,71.63
DDR2_DQ41: length 82.2
  TOP w0.165: J6.143 v1(66.9,89.38) ; U5.AP23 v2(90.95,70.2)
  L3-SIG1 w0.114: v1(66.75,69.85) 66.75,70.33 66.09,70.99 65.58,70.99 64.62,71.96 64.62,71.97 64.01,72.58 64.01,72.81 64.12,72.92 65.11,72.92 65.23,73.04 65.23,73.27 65.11,73.38 64.12,73.38 64.01,73.49 64.01,73.72 64.12,73.84 65.11,73.84 65.23,73.95 65.23,74.18 65.11,74.29 64.12,74.29 64.01,74.41 64.01,74.64 64.12,74.75 65.11,74.75 65.23,74.87 65.23,75.09 65.11,75.21 64.12,75.21 64.01,75.32 64.01,75.55 64.12,75.67 65.11,75.67 65.23,75.78 65.23,76.01 65.11,76.12 64.12,76.12 64.01,76.24 64.01,76.47 64.12,76.58 65.11,76.58 65.23,76.69 65.23,76.92 65.11,77.04 64.12,77.04 64.01,77.15 64.01,77.38 64.12,77.49 65.11,77.49 65.23,77.61 65.23,77.84 65.11,77.95 64.12,77.95 64.01,78.07 64.01,78.29 64.12,78.41 65.11,78.41 65.23,78.52 65.23,78.75 65.11,78.87 64.12,78.87 64.01,78.98 64.01,79.21 64.12,79.32 65.11,79.32 65.23,79.44 65.23,79.67 65.11,79.78 64.12,79.78 64.01,79.89 64.01,80.12 64.12,80.24 65.11,80.24 65.23,80.35 65.23,80.58 65.11,80.7 64.12,80.7 64.01,80.81 64.01,81.04 64.12,81.15 65.11,81.15 65.23,81.27 65.23,81.5 65.11,81.61 64.12,81.61 64.01,81.72 64.01,81.95 64.12,82.07 65.11,82.07 65.23,82.18 65.23,82.41 65.11,82.52 64.12,82.52 64.01,82.64 64.01,82.87 64.12,82.98 65.11,82.98 65.23,83.1 65.23,83.32 65.11,83.44 64.12,83.44 64.01,83.55 64.01,83.78 64.12,83.9 65.11,83.9 65.23,84.01 65.23,84.24 65.11,84.35 64.12,84.35 64.01,84.47 64.01,84.7 64.12,84.81 65.11,84.81 65.23,84.92 65.23,85.15 65.11,85.27 64.12,85.27 64.01,85.38 64.01,85.61 64.12,85.72 65.11,85.72 65.23,85.84 65.23,86.07 65.11,86.18 64.73,86.18 64.62,86.3 64.62,86.82 66.9,89.1 v1(66.9,89.38)
  L10-SIG4 w0.102: v2(90.95,70.2) 90.78,70.03 90.17,70.03
  L10-SIG4 w0.114: 90.17,70.03 88.62,70.03 88.49,69.9 87.44,69.9 87.41,69.93 86.84,69.93 86.7,69.8 84.58,69.8 84.57,69.79 84.37,69.79 84.29,69.71 83.12,69.71 82.91,69.93 81.13,69.93 80.62,69.42 72.24,69.42 72.11,69.55 67.97,69.55 67.79,69.37 67.18,69.37 66.75,69.79 v1(66.75,69.85)
DDR2_DQ42: length 82.2
  TOP w0.165: J6.151 v1(65.87,91.78) ; U5.AN23 v2(91.95,70.2)
  L3-SIG1 w0.114: v1(80.01,70.1) 79.76,70.36 79.76,72.44 79.79,72.47 79.79,72.99 79.63,73.15 79.63,74.23 80.21,74.8 80.21,84.3 80.51,84.6 81.29,84.6 81.41,84.72 81.41,84.94 81.29,85.06 79.12,85.06 79.01,85.17 79.01,85.4 79.12,85.52 81.29,85.52 81.41,85.63 81.41,85.86 81.29,85.97 79.12,85.97 79.01,86.09 79.01,86.32 79.12,86.43 81.29,86.43 81.41,86.54 81.41,86.77 81.29,86.89 79.12,86.89 79.01,87 79.01,87.23 79.12,87.34 81.29,87.34 81.41,87.46 81.41,87.69 81.29,87.8 79.12,87.8 79.01,87.92 79.01,88.14 79.12,88.26 81.29,88.26 81.41,88.37 81.41,88.6 81.29,88.72 79.12,88.72 79.01,88.83 79.01,89.06 79.12,89.17 81.29,89.17 81.41,89.29 81.41,89.52 81.29,89.63 79.12,89.63 79.01,89.74 79.01,89.97 79.12,90.09 81.29,90.09 81.41,90.2 81.41,90.43 81.29,90.54 80.83,90.54 80.49,90.88 80.49,91.41 v1(81.15,92.08)
  L10-SIG4 w0.102: v2(91.95,70.2) 91.61,70.54 91.15,70.54 91.11,70.58 90.79,70.58 90.75,70.54 90.4,70.54
  L10-SIG4 w0.114: v1(81.15,92.08) 80.64,91.57 66.08,91.57 v1(65.87,91.78) ; v1(80.01,70.1) 80.75,70.1 80.98,70.33 82.98,70.33 83.29,70.03 84.01,70.03 84.11,70.13 86.49,70.13 87.2,70.85 87.93,70.85 88.34,70.43 89.55,70.43 89.6,70.38 90.24,70.38 90.4,70.54
DDR2_DQ43: length 82.2
  TOP w0.165: J6.153 v1(66.88,92.38) ; U5.AM23 v2(92.95,70.2)
  L9-SIG3 w0.102: 90.37,71.32 90.37,71.12 90.75,70.74 92.41,70.74 v2(92.95,70.2)
  L9-SIG3 w0.114: v1(80.14,92.84) 79.88,92.58 79.88,91.82 80.52,91.19 82.42,91.19 82.82,90.79 82.82,90.61 83.06,90.38 83.14,90.38 83.23,90.46 83.32,90.46 83.56,90.23 83.56,90.14 83.47,90.05 83.47,89.96 83.7,89.73 83.79,89.73 83.88,89.82 83.97,89.82 84.2,89.58 84.2,89.49 84.11,89.41 84.11,89.32 84.35,89.08 84.44,89.08 84.53,89.17 84.62,89.17 84.85,88.94 84.85,88.85 84.76,88.76 84.76,88.67 85,88.44 85.08,88.44 85.17,88.52 85.26,88.52 85.5,88.29 85.5,88.11 85.75,87.86 86.77,87.86 87.25,87.38 87.25,86.87 89.03,85.09 89.03,84.33 89.46,83.9 89.46,83.08 88.8,82.42 88.8,82.12 88.98,81.95 88.98,81.67 88.89,81.58 88.71,81.58 88.62,81.49 88.62,81.21 88.71,81.12 88.89,81.12 88.98,81.03 88.98,80.75 88.89,80.66 88.71,80.66 88.62,80.57 88.62,80.29 88.71,80.21 88.89,80.21 88.98,80.12 88.98,79.84 88.89,79.75 88.71,79.75 88.62,79.66 88.62,79.38 88.71,79.29 88.89,79.29 88.98,79.2 88.98,78.92 88.8,78.75 88.8,78.41 89.1,78.11 89.26,78.11 89.41,78.27 89.58,78.27 89.74,78.11 89.74,77.94 89.26,77.47 89.26,77.31 89.43,77.15 89.59,77.15 90.06,77.62 90.22,77.62 90.38,77.46 90.38,77.3 90.23,77.14 90.23,76.88 90.55,76.56 90.55,76.34 90.44,76.22 90.11,76.22 89.99,76.11 89.99,75.88 90.11,75.77 90.44,75.77 90.55,75.65 90.55,75.42 90.44,75.31 90.11,75.31 89.99,75.2 89.99,74.97 90.11,74.85 90.44,74.85 90.55,74.74 90.55,74.51 90.44,74.4 90.11,74.4 89.99,74.28 89.99,74.05 90.11,73.94 90.44,73.94 90.55,73.82 90.55,73.6 90.44,73.48 90.11,73.48 89.99,73.37 89.99,73.14 90.11,73.02 90.44,73.02 90.55,72.91 90.55,72.68 90.44,72.57 90.11,72.57 89.99,72.45 89.99,72.22 90.11,72.11 90.16,72.11 90.27,71.99 90.27,71.42 90.37,71.32
  L10-SIG4 w0.114: v1(66.88,92.38) 66.56,92.69 65.04,92.69 64.26,93.47 63.5,93.47 63.12,93.09 63.12,92.75 63.36,92.51 63.77,92.51 63.88,92.39 63.88,92.16 63.77,92.05 63.36,92.05 63.25,91.93 63.25,91.71 63.36,91.59 63.77,91.59 63.88,91.48 63.88,91.25 63.77,91.13 63.36,91.13 63.25,91.02 63.25,90.68 63.63,90.3 64.9,90.3 65.28,90.68 65.28,92.08 65.58,92.38 66.04,92.38 66.09,92.33 66.17,92.33 66.64,91.86 67.31,91.86 67.55,92.1 67.78,92.1 67.9,92.21 67.9,92.54 68.01,92.66 68.24,92.66 68.35,92.54 68.35,92.21 68.47,92.1 68.7,92.1 68.81,92.21 68.81,92.54 68.92,92.66 69.15,92.66 69.27,92.54 69.27,92.21 69.38,92.1 69.61,92.1 69.72,92.21 69.72,92.54 69.84,92.66 70.07,92.66 70.18,92.54 70.18,92.21 70.3,92.1 70.52,92.1 70.64,92.21 70.64,92.54 70.75,92.66 70.98,92.66 71.1,92.54 71.1,92.21 71.21,92.1 71.44,92.1 71.55,92.21 71.55,92.54 71.67,92.66 71.9,92.66 72.01,92.54 72.01,92.21 72.12,92.1 72.35,92.1 72.47,92.21 72.47,92.54 72.58,92.66 72.81,92.66 72.92,92.54 72.92,92.21 73.04,92.1 73.27,92.1 73.38,92.21 73.38,92.54 73.5,92.66 73.72,92.66 73.84,92.54 73.84,92.21 73.95,92.1 74.18,92.1 74.3,92.21 74.3,92.54 74.41,92.66 74.64,92.66 74.75,92.54 74.75,92.21 74.87,92.1 75.1,92.1 75.21,92.21 75.21,92.54 75.33,92.66 75.55,92.66 75.67,92.54 75.67,92.21 75.78,92.1 76.01,92.1 76.13,92.21 76.13,92.54 76.24,92.66 76.47,92.66 76.58,92.54 76.58,92.21 76.7,92.1 76.93,92.1 77.04,92.21 77.04,92.54 77.15,92.66 77.38,92.66 77.5,92.54 77.5,92.21 77.61,92.1 77.84,92.1 77.95,92.21 77.95,92.54 78.07,92.66 78.3,92.66 78.41,92.54 78.41,92.21 78.53,92.1 78.75,92.1 78.87,92.21 78.87,92.26 78.98,92.38 79.68,92.38 v1(80.14,92.84)
DDR2_DQ44: length 82.2
  TOP w0.165: v1(57.66,88.01) 57.66,88.36 57.54,88.48 J6.140 ; U5.AM22 v2(92.95,71.2)
  L3-SIG1 w0.102: v2(92.95,71.2) 92.63,71.2 92.16,71.67 90.69,71.67
  L3-SIG1 w0.114: v1(83.95,87.88) 83.95,88.01 84.33,88.39 85.34,88.39 86.11,87.63 86.11,87.12 86.56,86.66 86.56,84.76 87.07,84.25 88.07,84.25 88.38,83.95 89.03,83.95 89.46,83.52 89.46,82.98 88.93,82.45 88.93,77.67 90.86,75.74 91.97,75.74 92.08,75.64 92.08,75.51 91.98,75.42 90.94,75.42 90.83,75.31 90.83,75.13 90.93,75.03 92.25,75.03 92.36,74.93 92.36,74.78 92.23,74.65 90.73,74.65 90.45,74.37 90.45,71.91 90.69,71.67
  L4-SIG2 w0.114: v1(83.95,87.88) 83.82,87.76 72.88,87.76 72.7,87.57 67.75,87.57 67.18,88.14 65.93,88.14 65.59,88.48 64.89,88.48 64.7,88.66 64.43,88.66 64.34,88.57 64.34,88.38 64.25,88.29 63.98,88.29 63.88,88.38 63.88,88.57 63.79,88.66 63.52,88.66 63.43,88.57 63.43,88.38 63.33,88.29 63.06,88.29 62.97,88.38 62.97,88.57 62.88,88.66 62.61,88.66 62.51,88.57 62.51,88.38 62.42,88.29 62.15,88.29 62.05,88.38 62.05,88.57 61.96,88.66 61.69,88.66 61.6,88.57 61.6,88.38 61.5,88.29 61.23,88.29 61.14,88.38 61.14,88.57 61.05,88.66 60.78,88.66 60.68,88.57 60.68,88.38 60.59,88.29 60.32,88.29 60.23,88.38 60.23,88.57 60.13,88.66 59.86,88.66 59.77,88.57 59.77,88.38 59.68,88.29 59.26,88.29 58.98,88.01 58.39,88.01 57.94,87.55 56.39,87.55 54.43,85.6 53.7,85.6 53.34,85.24 52.5,85.24 52.43,85.32 49.45,85.32 49.15,85.62 49.15,85.88 49.25,85.98 49.61,85.98 49.89,85.7 50.27,85.7 50.75,86.18 54.46,86.18 56.29,88.01 v1(57.66,88.01)
DDR2_DQ45: length 82.2
  TOP w0.165: v1(58.29,88.77) 57.99,89.08 J6.142 ; U5.AL23 v2(93.95,70.2)
  L4-SIG2 w0.114: v1(83.36,89.28) 83.24,89.41 70.61,89.41 70.05,88.84 67.77,88.84 67.67,88.95 67.67,89.28 68.43,90.04 68.43,90.35 68.3,90.47 67.79,90.47 67.31,89.99 67.31,89.93 67.2,89.81 66.97,89.81 66.85,89.93 66.85,90.36 66.74,90.47 66.5,90.47 66.07,90.04 65.46,90.04 65.3,89.89 65.3,89.15 65.18,89.03 64.83,89.03 64.71,89.14 64.71,89.52 64.6,89.64 64.37,89.64 64.25,89.52 64.25,89.14 64.14,89.03 63.91,89.03 63.8,89.14 63.8,89.52 63.68,89.64 63.45,89.64 63.34,89.52 63.34,89.14 63.22,89.03 63,89.03 62.88,89.14 62.88,89.52 62.77,89.64 62.54,89.64 62.42,89.52 62.42,89.14 62.31,89.03 62.08,89.03 61.97,89.14 61.97,89.52 61.85,89.64 61.62,89.64 61.51,89.52 61.51,89.14 61.4,89.03 61.17,89.03 61.05,89.14 61.05,89.52 60.94,89.64 60.71,89.64 60.6,89.52 60.6,89.14 60.48,89.03 60.25,89.03 60.14,89.14 60.14,89.52 60.02,89.64 59.8,89.64 59.68,89.52 59.68,89.14 59.31,88.77 v1(58.29,88.77)
  L9-SIG3 w0.114: v1(83.54,70.51) 83.54,70.47 83.62,70.56 83.62,72.5 83.85,72.72 83.85,72.96 83.73,73.07 83.51,73.07 83.4,73.18 83.4,73.42 83.51,73.53 83.73,73.53 83.85,73.64 83.85,73.87 83.73,73.98 83.51,73.98 83.4,74.1 83.4,74.33 83.51,74.44 83.73,74.44 83.85,74.55 83.85,74.79 83.73,74.9 83.51,74.9 83.4,75.01 83.4,75.24 83.51,75.36 83.73,75.36 83.85,75.47 83.85,75.7 83.73,75.81 83.51,75.81 83.4,75.92 83.4,76.16 83.51,76.27 83.73,76.27 83.85,76.38 83.85,76.62 83.73,76.73 83.51,76.73 83.4,76.84 83.4,77.07 83.51,77.18 83.73,77.18 83.85,77.3 83.85,77.53 83.73,77.64 83.51,77.64 83.4,77.75 83.4,77.99 83.51,78.1 83.73,78.1 83.85,78.21 83.85,78.45 83.73,78.56 83.51,78.56 83.4,78.67 83.4,78.9 83.51,79.01 83.73,79.01 83.85,79.12 83.85,80.06 83.64,80.26 83.34,80.26 83.2,80.13 82.99,80.13 82.88,80.24 82.88,80.45 83.03,80.61 83.03,80.77 82.78,81.03 82.78,81.25 83.29,81.76 83.29,81.99 82.7,82.58 82.7,82.58 82.3,82.99 82.3,83.62 82.5,83.82 83.19,83.82 83.36,84 83.36,84.22 83.25,84.33 83.1,84.33 83.01,84.42 83.01,84.7 83.1,84.79 83.63,84.79 83.74,84.9 83.74,85.13 83.63,85.25 83.1,85.25 82.98,85.36 82.98,85.59 83.1,85.7 83.63,85.7 83.74,85.82 83.74,86.05 83.63,86.16 83.1,86.16 82.98,86.27 82.98,86.5 83.1,86.62 83.63,86.62 83.74,86.73 83.74,86.96 83.63,87.07 83.48,87.07 83.36,87.19 v1(83.36,89.28)
  L10-SIG4 w0.102: 89.97,70.71 90.16,70.71 90.27,70.82 92.16,70.82 92.26,70.71 92.26,70.65 92.36,70.54 92.56,70.54 92.66,70.65 92.66,70.71 92.77,70.82 93.01,70.82 93.63,70.2 v2(93.95,70.2)
  L10-SIG4 w0.114: v1(83.54,70.51) 83.26,70.51 83.11,70.66 83.11,70.92 83.24,71.04 84.3,71.04 84.46,70.88 84.46,70.54 84.58,70.42 84.81,70.42 84.92,70.54 84.92,70.78 85.03,70.89 85.26,70.89 85.38,70.78 85.38,70.54 85.49,70.42 85.72,70.42 85.83,70.54 85.83,70.82 85.91,70.89 86.74,70.89 87.02,71.17 89.2,71.17 89.67,70.71 89.97,70.71
DDR2_DQ46: length 82.3
  TOP w0.165: U5.AL22 v2(93.95,71.2) ; J6.152 56.15,92.08 v1(57.53,92.08)
  L4-SIG2 w0.114: v1(80.39,92.08) 79.67,92.08 79.39,91.8 79.08,91.8 79.01,91.87 79.01,92.01 78.93,92.08 78.62,92.08 78.55,92.01 78.55,91.87 78.48,91.8 78.16,91.8 78.09,91.87 78.09,92.01 78.02,92.08 77.71,92.08 77.64,92.01 77.64,91.87 77.56,91.8 77.25,91.8 77.18,91.87 77.18,92.01 77.11,92.08 76.79,92.08 76.72,92.01 76.72,91.87 76.65,91.8 76.34,91.8 76.26,91.87 76.26,92.01 76.19,92.08 75.88,92.08 75.81,92.01 75.81,91.87 75.73,91.8 75.42,91.8 75.35,91.87 75.35,92.01 75.28,92.08 74.96,92.08 74.89,92.01 74.89,91.87 74.82,91.8 74.51,91.8 74.44,91.87 74.44,92.01 74.36,92.08 74.05,92.08 73.98,92.01 73.98,91.87 73.91,91.8 73.59,91.8 73.52,91.87 73.52,92.01 73.45,92.08 73.14,92.08 73.06,92.01 73.06,91.87 72.99,91.8 72.68,91.8 72.61,91.87 72.61,92.01 72.53,92.08 72.22,92.08 72.15,92.01 72.15,91.87 72.08,91.8 71.76,91.8 71.69,91.87 71.69,92.01 71.62,92.08 71.31,92.08 71.23,92.01 71.23,91.87 71.16,91.8 70.85,91.8 70.78,91.87 70.78,92.01 70.71,92.08 70.39,92.08 70.32,92.01 70.32,91.87 70.25,91.8 69.94,91.8 69.86,91.87 69.86,92.01 69.79,92.08 69.48,92.08 69.41,92.01 69.41,91.87 69.33,91.8 69.02,91.8 68.95,91.87 68.95,92.01 68.88,92.08 68.56,92.08 68.49,92.01 68.49,91.87 68.42,91.8 68.11,91.8 67.96,91.94 66.33,91.94 66.05,92.22 65.04,92.22 64.72,91.9 64.44,91.9 64.35,91.99 64.35,92.16 64.27,92.25 63.98,92.25 63.9,92.16 63.9,91.99 63.81,91.9 63.53,91.9 63.44,91.99 63.44,92.16 63.35,92.25 63.07,92.25 62.98,92.16 62.98,91.99 62.89,91.9 62.61,91.9 62.53,91.99 62.53,92.16 62.44,92.25 62.16,92.25 62.07,92.16 62.07,91.99 61.98,91.9 61.7,91.9 61.61,91.99 61.61,92.16 61.52,92.25 61.24,92.25 61.15,92.16 61.15,91.99 61.07,91.9 60.78,91.9 60.7,91.99 60.7,92.16 60.61,92.25 60.33,92.25 60.24,92.16 60.24,91.99 60.15,91.9 59.87,91.9 59.78,91.99 59.78,92.16 59.69,92.25 59.41,92.25 59.32,92.16 59.32,91.99 59.24,91.9 58.96,91.9 58.87,91.99 58.87,92.16 58.78,92.25 58.5,92.25 58.32,92.08 58.32,91.85 57.96,91.49 56.48,91.49 56.26,91.71 56.02,91.71 55.91,91.6 55.91,91.38 55.8,91.27 55.56,91.27 55.45,91.38 55.45,91.6 55.35,91.71 55.1,91.71 55,91.6 55,91.38 54.89,91.27 54.65,91.27 54.54,91.38 54.54,91.6 54.43,91.71 54.19,91.71 54.08,91.6 54.08,91.38 53.97,91.27 53.73,91.27 53.52,91.49 53.01,91.49 52.81,91.69 52.81,92.02 52.98,92.2 55.58,92.2 55.73,92.35 55.73,92.61 55.55,92.79 52.98,92.79 52.83,92.94 52.83,93.24 53.04,93.45 55.75,93.45 56.18,93.01 56.18,92.18 56.28,92.08 v1(57.53,92.08)
  L9-SIG3 w0.102: 91.44,76.2 91.44,73.91 92.71,72.64 93.22,72.64 93.5,72.37 93.5,71.98 93.95,71.53 v2(93.95,71.2)
  L9-SIG3 w0.114: 91.44,76.2 91.44,77.09 89.46,79.07 89.46,80.42 89.84,80.8 89.84,82.14 90.04,82.35 90.04,83.95 89.41,84.58 89.41,85.34 87.78,86.97 87.78,87.45 86.69,88.54 85.88,88.54 82.85,91.57 80.77,91.57 80.39,91.95 v1(80.39,92.08)
DDR2_DQ47: length 82.2
  TOP w0.165: v1(58.42,92.68) 56.15,92.68 J6.154 ; U5.AJ22 v2(95.95,71.2)
  BOTTOM w0.165: v1(58.42,92.68) 58.76,93.01 75.87,93.01 79.12,89.76 79.12,88.68 78.96,88.52 74.99,88.52 74.83,88.35 74.83,88.02 74.99,87.86 78.96,87.86 79.12,87.69 79.12,87.36 78.96,87.2 74.99,87.2 74.83,87.03 74.83,86.7 74.99,86.54 78.96,86.54 79.12,86.37 79.12,86.04 78.96,85.88 74.99,85.88 74.83,85.71 74.83,85.38 74.99,85.22 78.96,85.22 79.12,85.05 79.12,76.94 82.27,73.79 84.63,73.79 85.7,72.72 94.23,72.72 94.44,72.52 94.44,71.86 94.61,71.68 95.47,71.68 v2(95.95,71.2)
DDR2_DQ48: length 82.2
  TOP w0.165: J6.157 v1(65.89,93.58) ; U5.AL16 v2(93.95,78.2)
  L3-SIG1 w0.102: v2(93.95,78.2) 93.92,78.23 93.47,78.23 92.96,78.74 92.84,78.74 91.47,80.11 91.47,80.33 91.12,80.67 90.67,80.67 90.42,80.91 90.42,83.69
  L3-SIG1 w0.114: 90.42,83.69 87.76,86.36 87.76,87.53 85.35,89.93 85.19,89.93 85.05,89.79 84.89,89.79 84.72,89.95 84.72,90.11 85.17,90.56 85.17,90.72 85.01,90.88 84.85,90.88 84.4,90.44 84.24,90.44 84.08,90.6 84.08,90.76 84.53,91.21 84.53,91.37 84.36,91.53 84.2,91.53 83.76,91.08 83.59,91.08 83.43,91.24 83.43,91.41 83.88,91.85 83.88,92.02 83.72,92.18 83.56,92.18 83.11,91.73 82.95,91.73 82.79,91.89 82.79,92.05 83.23,92.5 83.23,92.66 83.07,92.82 82.91,92.82 82.46,92.38 82.3,92.38 82.14,92.54 82.14,92.7 82.59,93.15 82.59,93.31 82.42,93.47 82.26,93.47 81.82,93.02 81.65,93.02 81.49,93.18 81.49,93.35 81.64,93.49 81.64,93.65 81.43,93.85 v1(78.99,93.85)
  L10-SIG4 w0.114: v1(65.89,93.58) 65.89,94.07 65.78,94.19 65.65,94.19 65.53,94.3 65.53,94.53 65.65,94.64 65.78,94.64 65.89,94.76 65.89,95.63 65.15,96.37 65.15,102.06 64.97,102.23 64.39,102.23 64.14,101.98 64.14,101.72 64.25,101.61 64.4,101.61 64.52,101.49 64.52,101.27 64.4,101.15 64.25,101.15 64.14,101.04 64.14,100.81 64.25,100.69 64.4,100.69 64.52,100.58 64.52,100.35 64.4,100.24 64.25,100.24 64.14,100.12 64.14,99.89 64.25,99.78 64.4,99.78 64.52,99.67 64.52,99.44 64.4,99.32 64.25,99.32 64.14,99.21 64.14,98.98 64.25,98.87 64.4,98.87 64.52,98.75 64.52,98.52 64.4,98.41 64.25,98.41 64.14,98.29 64.14,98.07 64.25,97.95 64.4,97.95 64.52,97.84 64.52,97.61 64.4,97.49 64.25,97.49 64.14,97.38 64.14,97.15 64.25,97.04 64.4,97.04 64.52,96.92 64.52,96.69 64.4,96.58 64.25,96.58 64.14,96.47 64.14,96.24 64.25,96.12 64.4,96.12 64.52,96.01 64.52,95.78 64.4,95.67 64.25,95.67 64.14,95.55 64.14,95.25 64.71,94.67 64.71,93.91 65.58,93.04 67.02,93.04 67.14,93.15 67.14,93.54 67.25,93.65 67.48,93.65 67.59,93.54 67.59,93.15 67.71,93.04 67.94,93.04 68.05,93.15 68.05,93.54 68.17,93.65 68.39,93.65 68.51,93.54 68.51,93.15 68.62,93.04 68.85,93.04 68.97,93.15 68.97,93.54 69.08,93.65 69.31,93.65 69.42,93.54 69.42,93.15 69.54,93.04 69.77,93.04 69.88,93.15 69.88,93.54 70,93.65 70.22,93.65 70.34,93.54 70.34,93.15 70.45,93.04 70.68,93.04 70.8,93.15 70.8,93.54 70.91,93.65 71.14,93.65 71.25,93.54 71.25,93.15 71.37,93.04 71.6,93.04 71.71,93.15 71.71,93.54 71.82,93.65 72.05,93.65 72.17,93.54 72.17,93.15 72.28,93.04 72.51,93.04 72.62,93.15 72.62,93.54 72.74,93.65 72.97,93.65 73.08,93.54 73.08,93.15 73.2,93.04 73.42,93.04 73.54,93.15 73.54,93.54 73.65,93.65 73.88,93.65 74,93.54 74,93.15 74.11,93.04 74.34,93.04 74.45,93.15 74.45,93.54 74.57,93.65 74.8,93.65 74.91,93.54 74.91,93.15 75.02,93.04 75.25,93.04 75.37,93.15 75.37,93.54 75.48,93.65 75.71,93.65 75.82,93.54 75.82,93.15 75.94,93.04 76.17,93.04 76.28,93.15 76.28,93.54 76.4,93.65 76.62,93.65 76.74,93.54 76.74,93.15 76.85,93.04 77.08,93.04 77.2,93.15 77.2,93.54 77.31,93.65 77.54,93.65 77.65,93.54 77.65,93.46 77.77,93.34 78.49,93.34 v1(78.99,93.85)
DDR2_DQ49: length 82.2
  TOP w0.165: U5.AM16 v2(92.95,78.2) ; J6.159 v1(66.87,94.18)
  L3-SIG1 w0.102: v2(92.95,78.2) 92.74,78.2 92.18,78.77
  L3-SIG1 w0.114: 92.18,78.77 91.59,78.77 90.42,79.93 90.42,80.26 89.92,80.77 89.92,83.69 89.06,84.55 87.48,84.55 87.25,84.79 87.25,87.38 85.81,88.81 83.78,88.81 83.26,88.29 83.26,87.86 83.54,87.58 83.54,87.36 83.42,87.24 83.1,87.24 82.99,87.13 82.99,86.89 83.41,86.46 83.41,86 83.08,85.67 82.42,85.67 82.25,85.85 82.25,86.13 82.36,86.25 82.49,86.25 82.6,86.36 82.6,86.59 82.49,86.71 82,86.71 81.89,86.82 81.89,87.05 82,87.16 82.49,87.16 82.6,87.28 82.6,87.51 82.49,87.62 82,87.62 81.89,87.73 81.89,87.96 82,88.08 82.49,88.08 82.6,88.19 82.6,88.42 82.49,88.53 82,88.53 81.89,88.65 81.89,89 82.85,89.97 82.85,90.53 81.74,91.64 81.74,92.23 80.62,93.34 79.73,93.34 79.4,93.01 79.4,91.26 78.92,90.78 76.81,90.78 76.63,90.96 76.63,91.16 76.78,91.31 78.74,91.31 78.84,91.41 78.84,91.72 78.74,91.82 76.78,91.82 76.63,91.97 76.63,92.23 76.76,92.35 78.61,92.35 78.71,92.46 78.71,92.71 78.59,92.84 78,92.84 77.72,93.12 77.72,94.42 v1(77.92,94.61)
  L10-SIG4 w0.114: v1(77.92,94.61) 77.44,95.1 76.71,95.1 76.28,94.67 75.82,94.67 75.7,94.55 75.7,94.22 75.59,94.11 75.36,94.11 75.25,94.22 75.25,95.11 75.13,95.22 74.9,95.22 74.79,95.11 74.79,94.22 74.68,94.11 74.45,94.11 74.33,94.22 74.33,95.11 74.22,95.22 73.99,95.22 73.88,95.11 73.88,94.22 73.76,94.11 73.53,94.11 73.42,94.22 73.42,95.11 73.3,95.22 73.08,95.22 72.96,95.11 72.96,94.22 72.85,94.11 72.62,94.11 72.5,94.22 72.5,95.11 72.39,95.22 72.16,95.22 72.05,95.11 72.05,94.22 71.93,94.11 71.7,94.11 71.59,94.22 71.59,95.11 71.48,95.22 71.25,95.22 71.13,95.11 71.13,94.22 71.02,94.11 70.79,94.11 70.68,94.22 70.68,95.11 70.56,95.22 70.33,95.22 70.22,95.11 70.22,94.22 70.1,94.11 69.88,94.11 69.76,94.22 69.76,95.11 69.65,95.22 69.42,95.22 69.3,95.11 69.3,94.22 69.19,94.11 68.96,94.11 68.85,94.22 68.85,95.11 68.73,95.22 68.5,95.22 68.39,95.11 68.39,94.22 68.27,94.11 68.05,94.11 67.93,94.22 67.93,94.55 67.82,94.67 67.36,94.67 v1(66.87,94.18)
DDR2_DQ50: length 82.2
  TOP w0.165: U5.AL17 v2(93.95,77.2) ; J6.173 v1(65.87,98.38)
  L9-SIG3 w0.114: v1(74.04,77.6) 74.55,78.11 74.55,83.34 75.87,84.66 75.87,85.29 75.98,85.41 76.57,85.41 76.68,85.52 76.68,85.75 76.57,85.86 75.17,85.86 75.06,85.98 75.06,86.21 75.17,86.32 76.57,86.32 76.68,86.43 76.68,86.66 76.57,86.78 75.17,86.78 75.06,86.89 75.06,87.12 75.17,87.23 76.57,87.23 76.68,87.35 76.68,87.58 76.57,87.69 75.17,87.69 75.06,87.81 75.06,88.04 75.17,88.15 76.57,88.15 76.68,88.26 76.68,88.49 76.57,88.61 75.17,88.61 75.06,88.72 75.06,88.95 75.17,89.06 76.57,89.06 76.68,89.18 76.68,89.41 76.57,89.52 75.17,89.52 75.06,89.64 75.06,89.86 75.17,89.98 76.57,89.98 76.68,90.09 76.68,90.32 76.57,90.44 75.17,90.44 75.06,90.55 75.06,90.78 75.17,90.89 76.57,90.89 76.68,91.01 76.68,91.24 76.57,91.35 75.17,91.35 75.06,91.46 75.06,91.69 75.17,91.81 76.57,91.81 76.68,91.92 76.68,92.15 76.57,92.26 75.17,92.26 75.06,92.38 75.06,92.61 75.17,92.72 76.57,92.72 76.68,92.84 76.68,93.06 76.57,93.18 75.17,93.18 75.06,93.29 75.06,93.52 75.17,93.64 76.57,93.64 76.68,93.75 76.68,93.98 76.57,94.09 75.98,94.09 75.87,94.21 75.87,95.1 74.55,96.42 v1(74.55,98.04)
  L10-SIG4 w0.102: 90.65,77.75 93.4,77.75 v2(93.95,77.2)
  L10-SIG4 w0.114: v1(65.87,98.38) 67.31,98.38 67.46,98.53 67.74,98.53 67.83,98.44 67.83,98.44 68.05,98.22 68.48,98.22 68.63,98.38 74.21,98.38 v1(74.55,98.04) ; v1(74.04,77.6) 74.07,77.57 75.63,77.57 75.91,77.85 78.49,77.85 78.62,77.72 78.95,77.72 79.08,77.85 82.04,77.85 82.33,77.57 83.15,77.57 83.82,78.23 87.22,78.23 87.38,78.08 90.32,78.08 90.65,77.75
DDR2_DQ51: length 82.2
  TOP w0.165: U5.AM15 v2(92.95,79.2) ; J6.175 v1(66.88,98.98)
  L4-SIG2 w0.102: v2(92.95,79.2) 92.87,79.12 90.98,79.12 90.64,78.78 90.51,78.78
  L4-SIG2 w0.114: 90.51,78.78 89.62,78.78 89.28,79.12 85.34,79.12 84.96,79.5 84.66,79.5 84.45,79.71 84.2,79.71 84.1,79.6 84.1,79.4 84,79.3 83.74,79.3 83.64,79.4 83.64,79.6 83.54,79.71 83.29,79.71 83.18,79.6 83.18,79.4 83.08,79.3 82.83,79.3 82.73,79.4 82.73,79.6 82.62,79.71 82.37,79.71 82.27,79.6 82.27,79.4 82.17,79.3 81.91,79.3 81.81,79.4 81.81,79.6 81.71,79.71 81.46,79.71 81.35,79.6 81.35,79.4 81.25,79.3 81,79.3 80.9,79.4 80.9,79.6 80.8,79.71 80.54,79.71 80.44,79.6 80.44,79.4 80.34,79.3 80.08,79.3 79.88,79.5 79.5,79.5 78.87,78.87 76.88,78.87 76.7,78.68 76.42,78.68 76.33,78.78 76.33,78.96 76.24,79.05 75.97,79.05 75.88,78.96 75.88,78.78 75.78,78.68 75.51,78.68 75.42,78.78 75.42,78.96 75.33,79.05 75.05,79.05 74.96,78.96 74.96,78.78 74.87,78.68 74.6,78.68 74.5,78.78 74.5,78.96 74.41,79.05 74.14,79.05 73.96,78.87 73.53,78.87 v1(73.03,79.38)
  L9-SIG3 w0.114: v1(73.03,79.38) 73.03,83.06 73.94,83.97 73.94,87.74 73.83,87.85 73.42,87.85 73.3,87.97 73.3,88.19 73.42,88.31 74.46,88.31 74.57,88.42 74.57,88.65 74.46,88.77 73.42,88.77 73.3,88.88 73.3,89.11 73.42,89.22 74.46,89.22 74.57,89.34 74.57,89.57 74.46,89.68 73.42,89.68 73.3,89.79 73.3,90.02 73.42,90.14 74.46,90.14 74.57,90.25 74.57,90.48 74.46,90.59 73.42,90.59 73.3,90.71 73.3,90.94 73.42,91.05 74.46,91.05 74.57,91.17 74.57,91.39 74.46,91.51 73.42,91.51 73.3,91.62 73.3,91.85 73.42,91.97 74.46,91.97 74.57,92.08 74.57,92.31 74.46,92.42 73.42,92.42 73.3,92.54 73.3,92.77 73.42,92.88 74.46,92.88 74.57,92.99 74.57,93.22 74.46,93.34 73.42,93.34 73.3,93.45 73.3,93.68 73.42,93.79 74.46,93.79 74.57,93.91 74.57,94.14 74.46,94.25 73.42,94.25 73.3,94.37 73.3,94.59 73.42,94.71 74.46,94.71 74.57,94.82 74.57,95.05 74.46,95.17 74.05,95.17 73.94,95.28 73.94,95.66 73.66,95.94 v1(73.66,99.06)
  L10-SIG4 w0.114: v1(66.88,98.98) 67.32,99.42 67.95,99.42 68.07,99.3 68.07,98.84 68.18,98.73 68.41,98.73 68.53,98.84 68.53,99.99 68.64,100.1 68.87,100.1 68.98,99.99 68.98,98.84 69.1,98.73 69.33,98.73 69.44,98.84 69.44,99.99 69.55,100.1 69.78,100.1 69.9,99.99 69.9,98.84 70.01,98.73 70.24,98.73 70.35,98.84 70.35,99.99 70.47,100.1 70.7,100.1 70.81,99.99 70.81,98.84 70.93,98.73 71.15,98.73 71.27,98.84 71.27,99.3 71.38,99.42 71.7,99.42 72.06,99.06 v1(73.66,99.06)
DDR2_DQ52: length 82.2
  TOP w0.165: J6.158 v1(57.54,93.88) ; U5.AM14 v2(92.95,80.2)
  L4-SIG2 w0.114: v1(78.23,93.88) 77.95,93.6 77.7,93.6 77.58,93.71 77.58,93.81 77.47,93.93 77.24,93.93 77.12,93.81 77.12,93.38 77.01,93.27 76.78,93.27 76.67,93.38 76.67,93.81 76.55,93.93 76.32,93.93 76.21,93.81 76.21,93.38 76.1,93.27 75.87,93.27 75.75,93.38 75.75,93.81 75.64,93.93 75.41,93.93 75.3,93.81 75.3,93.38 75.18,93.27 74.95,93.27 74.84,93.38 74.84,93.81 74.72,93.93 74.5,93.93 74.38,93.81 74.38,93.38 74.27,93.27 74.04,93.27 73.92,93.38 73.92,93.81 73.81,93.93 73.58,93.93 73.47,93.81 73.47,93.38 73.35,93.27 73.12,93.27 73.01,93.38 73.01,93.81 72.89,93.93 72.67,93.93 72.55,93.81 72.55,93.38 72.44,93.27 72.21,93.27 72.09,93.38 72.09,93.81 71.98,93.93 71.75,93.93 71.64,93.81 71.64,93.38 71.52,93.27 71.29,93.27 71.18,93.38 71.18,93.81 71.07,93.93 70.84,93.93 70.72,93.81 70.72,93.38 70.61,93.27 70.38,93.27 70.27,93.38 70.27,93.81 70.15,93.93 69.92,93.93 69.81,93.81 69.81,93.38 69.69,93.27 69.47,93.27 69.35,93.38 69.35,93.81 69.24,93.93 69.01,93.93 68.89,93.81 68.89,93.38 68.78,93.27 68.55,93.27 68.44,93.38 68.44,93.81 68.32,93.93 68.09,93.93 67.98,93.81 67.98,93.38 67.87,93.27 67.64,93.27 67.52,93.38 67.52,93.48 67.41,93.6 66.67,93.6 66.26,94.02 65.59,94.02 65.43,93.85 65.19,93.85 65.07,93.74 65.07,93.59 64.96,93.47 64.73,93.47 64.62,93.59 64.62,94.12 64.5,94.23 64.27,94.23 64.16,94.12 64.16,93.59 64.05,93.47 63.82,93.47 63.7,93.59 63.7,93.74 63.59,93.85 63.35,93.85 63.04,93.54 62.41,93.54 62.2,93.75 61.58,93.75 61.46,93.87 61.46,93.99 61.35,94.11 61.12,94.11 61,93.99 61,93.51 60.89,93.4 60.66,93.4 60.55,93.51 60.55,93.99 60.43,94.11 60.2,94.11 60.09,93.99 60.09,93.51 59.97,93.4 59.75,93.4 59.63,93.51 59.63,93.99 59.52,94.11 59.29,94.11 59.17,93.99 59.17,93.51 59.06,93.4 58.83,93.4 58.72,93.51 58.72,93.64 58.6,93.75 57.67,93.75 v1(57.54,93.88)
  L9-SIG3 w0.102: v2(92.95,80.2) 91.78,80.2 91.64,80.06 91.64,79.6 91.77,79.48 92.3,79.48 92.51,79.27 92.51,76.89 92.6,76.79 92.9,76.79 93.01,76.67 93.01,76.5 92.91,76.4 92.56,76.4 92.46,76.3 92.46,76.12 92.56,76.02 92.91,76.02 93.01,75.92 93.01,75.74 92.91,75.64 92.61,75.64 92.51,75.54 92.51,74.83 92.35,74.68 92,74.68 91.87,74.8 91.87,77.39 91.47,77.8 91.47,79.04 90.75,79.76
  L9-SIG3 w0.114: 90.75,79.76 90.25,80.26 90.25,81.81 90.5,82.07 90.5,84.12 89.92,84.71 89.92,85.48 89.67,85.72 89.66,85.72 88.34,87.05 88.34,88.24 88.09,88.49 87.88,88.49 87.78,88.39 87.48,88.39 87.02,88.85 87.02,89.43 86.89,89.56 86.61,89.56 86.44,89.38 85.85,89.38 85.63,89.6 85.63,89.93 85.25,90.32 85.08,90.32 84.98,90.21 84.82,90.21 84.66,90.38 84.66,90.54 85.03,90.91 85.03,91.07 84.87,91.23 84.7,91.23 84.33,90.86 84.17,90.86 84.01,91.02 84.01,91.18 84.38,91.56 84.38,91.72 84.22,91.88 84.06,91.88 83.69,91.51 83.52,91.51 83.36,91.67 83.36,91.83 83.47,91.94 83.47,92.3 83.35,92.42 83.07,92.42 82.93,92.28 82.93,92.1 82.75,91.92 82.5,91.92 82.37,92.05 82.37,92.76 82.04,93.09 81.1,93.09 80.64,93.55 79.68,93.55 79.35,93.22 78.87,93.22 78.23,93.85 v1(78.23,93.88)
DDR2_DQ53: length 82.2
  TOP w0.165: v1(58.42,94.48) 58.15,94.48 58.15,94.48 J6.160 ; U5.AL14 v2(93.95,80.2)
  L4-SIG2 w0.114: v1(77.22,94.61) 77.21,94.62 64.11,94.62 64.01,94.51 58.46,94.51 v1(58.42,94.48)
  L9-SIG3 w0.114: v1(77.72,79.63) 77.95,79.86 77.95,84.07 78.82,84.94 78.82,85.24 78.93,85.36 79.92,85.36 80.04,85.47 80.04,85.7 79.92,85.82 77.71,85.82 77.6,85.93 77.6,86.16 77.71,86.27 79.92,86.27 80.04,86.39 80.04,86.62 79.92,86.73 77.71,86.73 77.6,86.84 77.6,87.07 77.71,87.19 79.92,87.19 80.04,87.3 80.04,87.53 79.92,87.64 77.71,87.64 77.6,87.76 77.6,87.99 77.71,88.1 79.92,88.1 80.04,88.22 80.04,88.44 79.92,88.56 77.71,88.56 77.6,88.67 77.6,88.9 77.71,89.02 79.92,89.02 80.04,89.13 80.04,89.36 79.92,89.47 77.71,89.47 77.6,89.59 77.6,89.82 77.71,89.93 79.92,89.93 80.04,90.04 80.04,90.27 79.92,90.39 77.71,90.39 77.6,90.5 77.6,90.73 77.71,90.84 78.7,90.84 78.92,91.06 78.92,91.9 77.22,93.6 v1(77.22,94.61)
  L10-SIG4 w0.102: v2(93.95,80.2) 93.38,79.63 90.55,79.63
  L10-SIG4 w0.114: 90.55,79.63 90.17,79.63 89.92,79.38 77.98,79.38 v1(77.72,79.63)
DDR2_DQ54: length 82.2
  TOP w0.165: U5.AK14 v2(94.95,80.2) ; v1(57.54,98.68) 57.54,98.68 J6.174
  L4-SIG2 w0.102: 95.43,88.39 95.17,88.65 94.61,88.65 94.49,88.77 94.49,89.53 93.98,90.04 92.71,90.04 92.08,90.68 91.82,90.68 90.68,91.82 90.68,93.34 90.17,93.85 ; 96.42,81.81 96.27,81.66 95.76,81.66 95.38,81.28 95.38,80.63 v2(94.95,80.2)
  L4-SIG2 w0.114: v1(57.54,98.68) 65.23,98.68 65.37,98.82 66.17,98.82 66.45,98.54 76.11,98.54 76.22,98.43 76.22,97.75 76.34,97.64 76.57,97.64 76.68,97.75 76.68,99.33 76.8,99.44 77.02,99.44 77.14,99.33 77.14,97.75 77.25,97.64 77.48,97.64 77.6,97.75 77.6,99.33 77.71,99.44 77.94,99.44 78.05,99.33 78.05,97.75 78.17,97.64 78.4,97.64 78.51,97.75 78.51,99.33 78.62,99.44 78.85,99.44 78.97,99.33 78.97,97.75 79.08,97.64 79.31,97.64 79.42,97.75 79.42,99.33 79.54,99.44 79.77,99.44 79.88,99.33 79.88,97.75 80,97.64 80.22,97.64 80.34,97.75 80.34,99.33 80.45,99.44 80.68,99.44 80.8,99.33 80.8,97.75 80.91,97.64 81.14,97.64 81.25,97.75 81.25,99.33 81.37,99.44 81.6,99.44 81.71,99.33 81.71,98.76 82.8,97.66 83.16,97.66 83.46,97.96 83.62,97.96 83.78,97.8 83.78,97.64 83.39,97.24 83.39,97.08 83.55,96.92 83.71,96.92 84.11,97.31 84.27,97.31 84.43,97.15 84.43,96.99 84.03,96.59 84.03,96.43 84.2,96.27 84.36,96.27 84.75,96.67 84.92,96.67 85.08,96.51 85.08,96.35 84.68,95.95 84.68,95.79 84.84,95.62 85,95.62 85.4,96.02 85.56,96.02 85.72,95.86 85.72,95.7 85.33,95.3 85.33,95.14 85.49,94.98 85.65,94.98 86.05,95.38 86.21,95.38 86.37,95.21 86.37,95.05 85.97,94.65 85.97,94.49 86.23,94.23 89.79,94.23 90.17,93.85 ; 95.43,88.39 95.43,87.05 95.25,86.87 95.25,86.54 95.43,86.36 95.43,85.9 95.25,85.72 95.25,85.52 95.43,85.34 95.43,84.84 95.61,84.66 96.27,84.66 96.42,84.51 96.42,81.81
DDR2_DQ55: length 82.2
  TOP w0.165: U5.AP14 v2(90.95,80.2) ; J6.176 v1(58.42,99.28)
  L4-SIG2 w0.114: v1(58.42,99.28) 58.55,99.41 59.27,99.41 59.47,99.21 59.73,99.21 59.83,99.31 59.83,99.51 59.93,99.61 60.19,99.61 60.29,99.51 60.29,99.31 60.38,99.21 60.64,99.21 60.74,99.31 60.74,99.51 60.84,99.61 61.1,99.61 61.2,99.51 61.2,99.31 61.3,99.21 61.56,99.21 61.66,99.31 61.66,99.51 61.76,99.61 62.02,99.61 62.11,99.51 62.11,99.31 62.21,99.21 62.47,99.21 62.57,99.31 62.57,99.51 62.67,99.61 62.93,99.61 63.03,99.51 63.03,99.31 63.13,99.21 63.39,99.21 63.49,99.31 63.49,99.51 63.58,99.61 63.85,99.61 63.94,99.51 63.94,99.31 64.04,99.21 64.3,99.21 64.4,99.31 64.4,99.51 64.5,99.61 64.76,99.61 64.86,99.51 64.86,99.31 64.96,99.21 65.22,99.21 65.32,99.31 65.32,99.51 65.41,99.61 65.67,99.61 65.87,99.41 67.36,99.41 67.47,99.52 67.47,99.71 67.59,99.82 67.82,99.82 67.93,99.71 67.93,99.11 68.05,99 68.27,99 68.39,99.11 68.39,99.71 68.5,99.82 68.73,99.82 68.85,99.71 68.85,99.11 68.96,99 69.19,99 69.3,99.11 69.3,99.71 69.42,99.82 69.65,99.82 69.76,99.71 69.76,99.11 69.87,99 70.1,99 70.22,99.11 70.22,99.71 70.33,99.82 70.56,99.82 70.67,99.71 70.67,99.11 70.79,99 71.02,99 71.13,99.11 71.13,99.71 71.25,99.82 71.48,99.82 71.59,99.71 71.59,99.52 71.7,99.41 72.87,99.41 v1(73.28,99.82)
  L9-SIG3 w0.102: v2(90.95,80.2) 90.95,80.2 90.58,80.57 90.58,81.43 90.81,81.66 91.14,81.66 91.44,81.97 91.44,83.92
  L9-SIG3 w0.114: 91.44,83.92 91.44,84.33 91.06,84.71 90.68,84.71 90.33,85.06 90.33,85.69 88.9,87.12 88.9,88.27 86.64,90.53 86.11,90.53 83.03,93.6 81.74,93.6 80.84,94.5 80.68,94.5 80.23,94.05 80.07,94.05 79.9,94.21 79.9,94.37 80.96,95.43 80.96,95.59 80.8,95.76 80.64,95.76 79.58,94.7 79.42,94.7 79.26,94.86 79.26,95.02 80.32,96.08 80.32,96.24 80.15,96.4 79.99,96.4 78.93,95.34 78.77,95.34 78.61,95.51 78.61,95.67 79.67,96.73 79.67,96.89 79.51,97.05 79.35,97.05 78.29,95.99 78.13,95.99 77.96,96.15 77.96,96.31 79.02,97.37 79.02,97.53 78.86,97.7 78.7,97.7 77.64,96.64 77.48,96.64 77.32,96.8 77.32,96.96 78.38,98.02 78.38,98.18 78.21,98.34 78.05,98.34 76.99,97.28 76.83,97.28 76.67,97.45 76.67,97.61 77.73,98.67 77.73,98.83 77.57,98.99 77.41,98.99 76.35,97.93 76.19,97.93 76.02,98.09 76.02,98.25 77.08,99.31 77.08,99.47 76.92,99.63 76.76,99.63 75.7,98.58 75.54,98.58 75.38,98.74 75.38,98.9 75.83,99.35 75.83,99.69 75.7,99.82 v1(73.28,99.82)
DDR2_DQ56: length 82.2
  TOP w0.165: J6.179 v1(65.89,100.18) ; U5.AL27 v2(93.95,66.2)
  L9-SIG3 w0.114: v1(72.52,99.82) 72.52,98.96 72.5,98.95 72.62,98.83 72.62,98.6 72.5,98.49 71.87,98.49 71.75,98.37 71.75,98.14 71.87,98.03 72.5,98.03 72.62,97.92 72.62,97.69 72.5,97.57 71.87,97.57 71.75,97.46 71.75,97.23 71.87,97.12 72.5,97.12 72.62,97 72.62,96.77 72.5,96.66 71.87,96.66 71.75,96.54 71.75,96.32 71.87,96.2 72.5,96.2 72.62,96.09 72.62,95.86 72.5,95.74 71.87,95.74 71.75,95.63 71.75,95.4 71.87,95.29 72.5,95.29 72.62,95.17 72.62,94.94 72.5,94.83 71.87,94.83 71.75,94.72 71.75,94.49 71.87,94.37 72.5,94.37 72.62,94.26 72.62,94.03 72.5,93.92 71.87,93.92 71.75,93.8 71.75,93.57 71.87,93.46 72.5,93.46 72.62,93.34 72.62,93.12 72.5,93 71.87,93 71.75,92.89 71.75,92.66 71.87,92.54 72.5,92.54 72.62,92.43 72.62,92.2 72.5,92.09 71.87,92.09 71.75,91.97 71.75,91.74 71.87,91.63 72.5,91.63 72.62,91.52 72.62,91.29 72.5,91.17 71.87,91.17 71.75,91.06 71.75,90.83 71.87,90.72 72.5,90.72 72.62,90.6 72.62,90.37 72.5,90.26 71.87,90.26 71.75,90.14 71.75,89.92 71.87,89.8 72.5,89.8 72.62,89.69 72.62,89.46 72.5,89.34 71.87,89.34 71.75,89.23 71.75,89 71.87,88.89 72.07,88.89 72.19,88.77 72.19,88.57 72.01,88.39 72.01,87.43 72.64,86.79 72.64,84.23 72.01,83.59 72.01,74.27 72.26,74.02 72.26,66.17 v1(72.52,65.91)
  L10-SIG4 w0.102: 90.02,66.57 90.78,66.57 90.79,66.58 91.11,66.58 91.12,66.57 91.78,66.57 91.79,66.58 92.11,66.58 92.12,66.57 92.78,66.57 92.79,66.58 93.11,66.58 93.12,66.57 93.58,66.57 v2(93.95,66.2)
  L10-SIG4 w0.114: v1(72.52,65.91) 72.57,65.96 76.07,65.96 76.15,65.88 77.24,65.88 77.37,66.01 83.97,66.01 84.53,66.57 85.04,66.57 85.6,66.01 87.35,66.01 87.93,66.6 88.9,66.6 88.93,66.57 90.02,66.57 ; v1(65.89,100.18) 67.21,100.18 67.64,100.61 71.35,100.61 72.14,99.82 v1(72.52,99.82)
DDR2_DQ57: length 82.3
  TOP w0.165: U5.AL26 v2(93.95,67.2) ; J6.181 v1(66.86,100.78)
  L3-SIG1 w0.114: v1(66.86,100.78) 65.55,100.78 61.24,96.47 61.24,86.66 59.84,85.27 59.84,82.44 59.73,82.32 59.58,82.32 59.46,82.21 59.46,81.98 59.58,81.87 59.73,81.87 59.84,81.75 59.84,81.52 59.73,81.41 59.58,81.41 59.46,81.3 59.46,81.07 59.58,80.95 59.73,80.95 59.84,80.84 59.84,80.61 59.73,80.5 59.58,80.5 59.46,80.38 59.46,80.15 59.58,80.04 59.73,80.04 59.84,79.92 59.84,79.7 59.73,79.58 59.58,79.58 59.46,79.47 59.46,79.24 59.58,79.12 59.73,79.12 59.84,79.01 59.84,78.78 59.73,78.67 59.58,78.67 59.46,78.55 59.46,78.32 59.58,78.21 59.73,78.21 59.84,78.1 59.84,77.87 59.73,77.75 59.58,77.75 59.46,77.64 59.46,77.41 59.58,77.3 59.73,77.3 59.84,77.18 59.84,76.95 59.73,76.84 59.58,76.84 59.46,76.72 59.46,76.49 59.58,76.38 59.73,76.38 59.84,76.27 59.84,76.04 59.73,75.92 59.58,75.92 59.46,75.81 59.46,75.58 59.58,75.47 59.73,75.47 59.84,75.35 59.84,75.12 59.73,75.01 59.58,75.01 59.46,74.89 59.46,74.67 59.58,74.55 59.73,74.55 59.84,74.44 59.84,74.21 59.73,74.09 59.58,74.09 59.46,73.98 59.46,73.75 59.58,73.64 59.73,73.64 59.84,73.52 59.84,73.29 59.73,73.18 59.58,73.18 59.46,73.07 59.46,72.84 59.58,72.72 59.73,72.72 59.84,72.61 59.84,72.38 59.73,72.27 59.58,72.27 59.46,72.15 59.46,71.92 59.58,71.81 59.73,71.81 59.84,71.69 59.84,71.47 59.73,71.35 59.58,71.35 59.46,71.24 59.46,71.01 59.58,70.89 59.73,70.89 59.84,70.78 59.84,70.55 59.73,70.44 59.58,70.44 59.46,70.32 59.46,70.09 59.58,69.98 59.73,69.98 59.84,69.87 59.84,68.99 60.91,67.92 62.05,67.92 62.69,67.28 v1(62.69,66.7)
  L4-SIG2 w0.102: 90.17,67.59 90.58,67.59 90.59,67.58 90.78,67.58 90.79,67.59 93.56,67.59 v2(93.95,67.2)
  L4-SIG2 w0.114: 90.17,67.59 89.92,67.59 89.87,67.54 87.78,67.54 87.53,67.28 84.45,67.28 84.38,67.21 83.52,67.21 83.13,66.83 76.05,66.83 75.82,66.6 68.68,66.6 68.35,66.93 67.01,66.93 66.45,67.49 64.97,67.49 64.24,66.75 62.74,66.75 v1(62.69,66.7)
DDR2_DQ58: length 82.3
  TOP w0.165: U5.AL25 v2(93.95,68.2) ; J6.189 v1(65.91,103.18)
  L9-SIG3 w0.114: v1(69.22,69.09) 69.75,69.62 69.75,84.06 69.51,84.3 69.51,85.13 69.8,85.42 69.8,88.3 69.03,89.07 69.03,90.23 68.68,90.58 68.68,90.83 68.81,90.96 69.3,90.96 69.42,91.07 69.42,91.3 69.3,91.41 68.76,91.41 68.64,91.53 68.64,91.76 68.76,91.87 69.3,91.87 69.42,91.99 69.42,92.21 69.3,92.33 68.76,92.33 68.64,92.44 68.64,92.67 68.76,92.79 69.3,92.79 69.42,92.9 69.42,93.13 69.3,93.24 68.76,93.24 68.64,93.36 68.64,93.59 68.76,93.7 69.3,93.7 69.42,93.81 69.42,94.04 69.3,94.16 68.76,94.16 68.64,94.27 68.64,94.5 68.76,94.61 69.3,94.61 69.42,94.73 69.42,94.96 69.3,95.07 68.76,95.07 68.64,95.19 68.64,95.41 68.76,95.53 69.3,95.53 69.42,95.64 69.42,95.87 69.3,95.99 68.76,95.99 68.64,96.1 68.64,96.33 68.76,96.44 69.3,96.44 69.42,96.56 69.42,96.79 69.3,96.9 68.76,96.9 68.64,97.01 68.64,97.24 68.76,97.36 69.3,97.36 69.42,97.47 69.42,97.7 69.3,97.81 68.76,97.81 68.64,97.93 68.64,98.16 68.76,98.27 69.3,98.27 69.42,98.39 69.42,98.61 69.3,98.73 68.76,98.73 68.64,98.84 68.64,99.07 68.76,99.19 69.3,99.19 69.42,99.3 69.42,99.53 69.3,99.64 68.76,99.64 68.64,99.76 68.64,99.99 68.76,100.1 69.3,100.1 69.42,100.22 69.42,100.44 69.3,100.56 68.76,100.56 68.64,100.67 68.64,100.9 68.76,101.02 69.3,101.02 69.42,101.13 69.42,101.36 69.03,101.75 69.03,103.19 v1(69.47,103.63)
  L10-SIG4 w0.102: 90.28,68.73 93.45,68.73 93.95,68.23 v2(93.95,68.2)
  L10-SIG4 w0.114: 90.28,68.73 89.13,68.73 88.9,68.96 87.69,68.96 87.53,68.81 86.53,68.81 86.12,69.22 85.32,69.22 85.08,68.97 83.97,68.97 83.71,68.97 83.56,69.12 81.74,69.12 81.46,68.83 71.98,68.83 71.6,69.22 69.34,69.22 v1(69.22,69.09) ; v1(65.91,103.18) 69.02,103.18 v1(69.47,103.63)
DDR2_DQ59: length 82.2
  TOP w0.165: J6.191 v1(66.8,103.78) ; U5.AL24 v2(93.95,69.2)
  L3-SIG1 w0.114: v1(68.71,68.07) 68.71,69.39 68.96,69.65 68.96,87.5 69.5,88.04 69.5,88.61 68.89,89.22 68.89,89.96 68.78,90.08 68.68,90.08 68.57,90.19 68.57,90.42 68.68,90.54 69.1,90.54 69.22,90.65 69.22,90.88 69.1,90.99 68.68,90.99 68.57,91.11 68.57,91.34 68.68,91.45 69.1,91.45 69.22,91.56 69.22,91.79 69.1,91.91 68.68,91.91 68.57,92.02 68.57,92.25 68.68,92.36 69.1,92.36 69.22,92.48 69.22,92.71 69.1,92.82 68.68,92.82 68.57,92.94 68.57,93.16 68.68,93.28 69.1,93.28 69.22,93.39 69.22,93.62 69.1,93.74 68.68,93.74 68.57,93.85 68.57,94.08 68.68,94.19 69.1,94.19 69.22,94.31 69.22,94.54 69.1,94.65 68.68,94.65 68.57,94.77 68.57,94.99 68.68,95.11 69.1,95.11 69.22,95.22 69.22,95.45 69.1,95.57 68.68,95.57 68.57,95.68 68.57,95.91 68.68,96.02 69.1,96.02 69.22,96.14 69.22,96.37 69.1,96.48 68.68,96.48 68.57,96.59 68.57,96.82 68.68,96.94 69.1,96.94 69.22,97.05 69.22,97.28 69.1,97.39 68.68,97.39 68.57,97.51 68.57,97.74 68.68,97.85 69.1,97.85 69.22,97.97 69.22,98.19 69.1,98.31 68.68,98.31 68.57,98.42 68.57,98.65 68.68,98.77 69.1,98.77 69.22,98.88 69.22,99.11 69.1,99.22 68.68,99.22 68.57,99.34 68.57,99.57 68.68,99.68 69.1,99.68 69.22,99.79 69.22,100.02 69.1,100.14 68.68,100.14 68.57,100.25 68.57,100.48 68.68,100.59 69.1,100.59 69.22,100.71 69.22,100.94 69.1,101.05 68.68,101.05 68.57,101.17 68.57,101.39 68.68,101.51 69.1,101.51 69.22,101.62 69.22,101.85 69.1,101.97 68.68,101.97 68.57,102.08 68.57,102.31 68.68,102.42 69.1,102.42 69.22,102.54 69.22,102.77 69.1,102.88 69.01,102.88 68.89,102.99 68.89,103.45 v1(68.71,103.63)
  L4-SIG2 w0.102: v2(93.95,69.2) 93.57,68.82 93.11,68.82 93.11,68.82 92.79,68.82 92.78,68.83 92.12,68.83 92.11,68.82 91.79,68.82 91.78,68.83 91.12,68.83 91.11,68.82 90.79,68.82 90.78,68.83 90.42,68.83
  L4-SIG2 w0.114: v1(68.71,68.07) 69.6,68.07 69.91,68.38 70.67,68.38 70.72,68.33 79.12,68.33 79.4,68.05 82.08,68.05 82.18,67.94 82.56,67.94 82.86,68.25 83.46,68.25 84.51,69.29 86.33,69.29 86.82,68.8 87.45,68.8 87.6,68.96 89.08,68.96 89.24,68.8 89.58,68.8 89.61,68.83 90.42,68.83
  L10-SIG4 w0.114: v1(66.8,103.78) 66.95,103.63 v1(68.71,103.63)
DDR2_DQ60: length 82.3
  TOP w0.165: J6.180 57.54,100.48 v1(57.54,100.48) ; U5.AK24 v2(94.95,69.2)
  L4-SIG2 w0.114: v1(57.54,100.48) 57.66,100.36 58.61,100.36 58.72,100.24 58.72,100.11 58.84,100 59.07,100 59.18,100.11 59.18,100.6 59.29,100.71 59.52,100.71 59.64,100.6 59.64,100.11 59.75,100 59.98,100 60.09,100.11 60.09,100.6 60.21,100.71 60.44,100.71 60.55,100.6 60.55,100.11 60.67,100 60.89,100 61.01,100.11 61.01,100.6 61.12,100.71 61.35,100.71 61.47,100.6 61.47,100.47 61.58,100.36 62.1,100.36 62.31,100.15 64.84,100.15 65.31,100.62 66.17,100.62 66.45,100.33 67.18,100.33 67.44,100.58 67.82,100.58 67.93,100.47 67.93,100.42 68.05,100.3 68.27,100.3 68.39,100.42 68.39,100.75 68.5,100.86 68.73,100.86 68.85,100.75 68.85,100.42 68.96,100.3 69.19,100.3 69.3,100.42 69.3,100.75 69.42,100.86 69.65,100.86 69.76,100.75 69.76,100.42 69.88,100.3 70.1,100.3 70.22,100.42 70.22,100.75 70.33,100.86 70.56,100.86 70.68,100.75 70.68,100.42 70.79,100.3 71.02,100.3 71.13,100.42 71.13,100.75 71.25,100.86 71.48,100.86 71.59,100.75 71.59,100.7 71.7,100.58 72.14,100.58 v1(72.26,100.71)
  L9-SIG3 w0.102: 90.42,86.11 90.86,85.67 92.1,85.67 92.46,85.32 92.46,81.16 92.8,80.81 93.12,80.81 93.12,80.82 93.21,80.82 93.21,80.81 93.31,80.81 93.57,80.55 93.57,79.99 93.93,79.63 94.11,79.63 94.46,79.27 94.46,76.86 95.5,75.82 95.5,69.75 v2(94.95,69.2)
  L9-SIG3 w0.114: 90.42,86.11 89.51,87.02 89.51,88.85 88.42,89.94 88.42,91.06 86.74,92.74 85.7,92.74 85.47,92.51 85.06,92.51 84.85,92.72 84.85,93.06 85.14,93.36 85.14,93.52 84.98,93.68 84.82,93.68 84.53,93.39 84.36,93.39 84.2,93.55 84.2,93.71 84.5,94 84.5,94.17 84.34,94.33 84.17,94.33 83.88,94.03 83.72,94.03 83.56,94.19 83.56,94.36 83.85,94.65 83.85,94.81 83.69,94.97 83.53,94.97 83.23,94.68 83.07,94.68 82.91,94.84 82.91,95 83.2,95.3 83.2,95.46 83.04,95.62 82.88,95.62 82.59,95.33 82.42,95.33 82.26,95.49 82.26,95.65 82.56,95.94 82.56,96.11 82.4,96.27 82.23,96.27 81.94,95.97 81.78,95.97 81.62,96.13 81.62,96.3 81.91,96.59 81.91,96.75 81.75,96.91 81.59,96.91 81.29,96.62 81.13,96.62 80.97,96.78 80.97,96.94 81.26,97.24 81.26,97.4 81.1,97.56 80.94,97.56 80.65,97.27 80.48,97.27 80.32,97.43 80.32,97.59 80.62,97.88 80.62,98.05 80.46,98.21 80.29,98.21 80,97.91 79.84,97.91 79.68,98.07 79.68,98.24 79.97,98.53 79.97,98.69 79.81,98.85 79.65,98.85 79.35,98.56 79.19,98.56 79.03,98.72 79.03,98.88 79.32,99.18 79.32,99.34 79.16,99.5 79,99.5 78.71,99.21 78.54,99.21 78.38,99.37 78.38,99.53 78.68,99.82 78.68,99.99 78.52,100.15 78.35,100.15 78.06,99.85 77.9,99.85 77.74,100.01 77.74,100.17 77.8,100.24 77.8,100.51 77.6,100.71 v1(72.26,100.71)
DDR2_DQ61: length 82.2
  TOP w0.165: J6.182 v1(58.42,101.08) ; U5.AJ25 v2(95.95,68.2)
  L3-SIG1 w0.114: v1(71.25,101.73) 70.87,101.35 70.87,101.06 71.09,100.83 71.09,100.6 70.98,100.49 70.75,100.49 70.64,100.37 70.64,100.14 70.75,100.03 70.98,100.03 71.09,99.91 71.09,99.69 70.98,99.57 70.75,99.57 70.64,99.46 70.64,99.23 70.75,99.11 70.98,99.11 71.09,99 71.09,98.77 70.98,98.66 70.75,98.66 70.64,98.54 70.64,98.31 70.75,98.2 70.98,98.2 71.09,98.09 71.09,97.86 70.98,97.74 70.75,97.74 70.64,97.63 70.64,97.4 70.75,97.29 70.98,97.29 71.09,97.17 71.09,96.94 70.98,96.83 70.75,96.83 70.64,96.71 70.64,96.49 70.75,96.37 70.98,96.37 71.09,96.26 71.09,96.03 70.98,95.91 70.75,95.91 70.64,95.8 70.64,95.57 70.75,95.46 70.98,95.46 71.09,95.34 71.09,95.11 70.98,95 70.75,95 70.64,94.88 70.64,94.66 70.75,94.54 70.98,94.54 71.09,94.43 71.09,94.2 70.98,94.08 70.75,94.08 70.64,93.97 70.64,93.74 70.75,93.63 70.98,93.63 71.09,93.51 71.09,93.28 70.98,93.17 70.75,93.17 70.64,93.06 70.64,92.83 70.75,92.71 70.98,92.71 71.09,92.6 71.09,92.37 70.98,92.26 70.75,92.26 70.64,92.14 70.64,91.91 70.75,91.8 70.98,91.8 71.09,91.68 71.09,91.46 70.98,91.34 70.75,91.34 70.64,91.23 70.64,91 70.94,90.69 70.94,68.81 v1(70.99,68.76)
  L4-SIG2 w0.114: v1(71.25,101.73) 70.79,101.27 69.39,101.27 69.29,101.37 58.71,101.37 v1(58.42,101.08)
  L10-SIG4 w0.102: v2(95.95,68.2) 95.57,67.82 90.17,67.82
  L10-SIG4 w0.114: 90.17,67.82 90.06,67.93 87.9,67.93 87.66,68.17 82.95,68.17 82.78,68.34 82.78,68.55 82.52,68.82 82.19,68.82 81.83,68.45 71.38,68.45 71.07,68.76 v1(70.99,68.76)
DDR2_DQ62: length 82.2
  TOP w0.165: J6.192 57.54,104.08 v1(57.54,104.08) ; U5.AH24 v2(96.95,69.2)
  L4-SIG2 w0.102: 96.52,68.2 96.14,67.82 96.12,67.82 96.11,67.81 95.79,67.81 95.78,67.82 95.12,67.82 95.11,67.82 94.79,67.82 94.36,68.24 94.36,68.92 94.33,68.94 94.33,69.04 94.34,69.04 94.34,69.36 94.11,69.59 90.8,69.59 90.8,69.58 90.79,69.58
  L4-SIG2 w0.114: v1(57.54,104.08) 57.61,104.01 65.84,104.01 66.04,104.22 68.02,104.22 v1(68.45,104.65) ; v1(68.2,69.09) 68.6,69.09 69.03,69.53 71.44,69.53 71.63,69.34 79.38,69.34 79.88,68.84 81.46,68.84 82.09,69.47 84.1,69.47 84.3,69.67 89.53,69.67 89.62,69.58 90.48,69.58 90.48,69.58 90.68,69.58 90.68,69.58 90.79,69.58 ; v2(96.95,69.2) 96.52,68.77 96.52,68.2
  L9-SIG3 w0.114: v1(68.2,69.09) 68.2,69.16 68.58,69.55 68.58,88.39 68.01,88.96 68.01,99.8 67.9,99.92 67.88,99.92 67.77,100.03 67.77,100.26 67.88,100.37 67.9,100.37 68.01,100.49 68.01,100.72 67.9,100.83 67.88,100.83 67.77,100.95 67.77,101.17 67.88,101.29 67.9,101.29 68.01,101.4 68.01,101.63 67.9,101.75 67.88,101.75 67.77,101.86 67.77,102.09 67.88,102.2 67.9,102.2 68.01,102.32 68.01,102.55 67.79,102.77 67.79,103.99 v1(68.45,104.65)
DDR2_DQ63: length 82.2
  TOP w0.165: U5.AH23 v2(96.95,70.2) ; J6.194 v1(58.42,104.68)
  L3-SIG1 w0.114: v1(67.69,69.85) 68.15,70.31 68.15,87.32 67.51,87.97 67.51,88.49 68,88.98 68,96.62 67.82,96.8 67.82,96.94 67.7,97.06 67.65,97.06 67.54,97.17 67.54,97.4 67.65,97.51 67.7,97.51 67.82,97.63 67.82,97.86 67.7,97.97 67.65,97.97 67.54,98.09 67.54,98.31 67.65,98.43 67.7,98.43 67.82,98.54 67.82,98.77 67.7,98.89 67.65,98.89 67.54,99 67.54,99.23 67.65,99.34 67.7,99.34 67.82,99.46 67.82,99.69 67.7,99.8 67.65,99.8 67.54,99.91 67.54,100.14 67.65,100.26 67.7,100.26 67.82,100.37 67.82,100.6 67.7,100.72 67.65,100.72 67.54,100.83 67.54,101.06 67.65,101.17 67.7,101.17 67.82,101.29 67.82,101.52 67.7,101.63 67.65,101.63 67.54,101.74 67.54,101.97 67.65,102.09 67.7,102.09 67.82,102.2 67.82,102.43 67.7,102.54 67.65,102.54 67.54,102.66 67.54,102.89 67.65,103 67.7,103 67.82,103.12 67.82,104.55 v1(67.69,104.68)
  L4-SIG2 w0.102: 90.58,69.82 90.68,69.82 90.68,69.82 94.26,69.82 94.57,69.51 94.57,69.46 94.57,69.46 94.57,69.36 94.57,69.36 94.57,69.04 94.9,68.71 96.01,68.71 96.39,69.09 96.39,69.64 v2(96.95,70.2)
  L4-SIG2 w0.114: v1(58.42,104.68) 58.83,105.09 62.06,105.09 62.68,104.46 63.05,104.46 63.26,104.68 v1(67.69,104.68) ; v1(67.69,69.85) 68.38,70.54 80.19,70.54 80.5,70.23 81.01,70.23 81.43,69.81 83.91,69.81 84.2,70.1 87.12,70.1 87.25,69.98 90.42,69.98 90.58,69.82
DDR2_DQS0: length 82.2
  TOP w0.114: J6.13 65.85,46.78 v1(65.89,46.81) ; U5.AN8 v2(91.95,86.2)
  L4-SIG2 w0.102: v1(65.89,46.81) 66.14,46.56 69.1,46.56 69.25,46.71 70.52,46.71 71.11,46.13 72.93,46.13 72.93,46.13 74.17,46.13 74.83,46.79 74.91,46.79 75.31,46.39 75.46,46.39 75.6,46.53 75.6,46.68 75.35,46.93 75.35,47.31 75.65,47.61 76.03,47.61 76.28,47.36 76.43,47.36 76.57,47.5 76.57,47.65 76.32,47.9 76.32,48.27 76.62,48.58 77,48.58 77.25,48.33 77.4,48.33 77.54,48.47 77.54,48.62 77.29,48.87 77.29,49.24 77.59,49.55 77.97,49.55 78.22,49.3 78.37,49.3 78.51,49.44 78.51,49.59 78.26,49.84 78.26,50.21 78.56,50.52 78.94,50.52 79.19,50.27 79.34,50.27 79.48,50.41 79.48,51.44 84.68,56.64 86.52,56.64 86.98,57.1 88.18,57.1 88.51,56.77 91.06,56.77 91.82,57.53 93.47,57.53 93.73,57.28 94.23,57.28 94.23,57.66 v1(93.98,57.91)
  L9-SIG3 w0.102: v1(93.98,57.91) 93.98,57.62 94.26,57.9 94.26,58.27 94.33,58.34 94.33,59.19 94.33,59.19 94.33,60.71 94.33,60.71 94.33,60.9 96.25,62.82 99.11,62.82 99.33,63.04 99.33,69.77 99.57,70.01 99.57,74.27 99.11,74.73 99.11,76.02 98.33,76.8 98.33,79.42 98.17,79.58 97.69,79.58 97.33,79.94 97.33,80.36 97.32,80.37 97.32,81.03 97.33,81.04 97.33,81.36 97.32,81.37 97.32,82.03 97.33,82.04 97.33,82.36 97.32,82.37 97.32,83.03 97.33,83.04 97.33,83.36 97.32,83.37 97.32,84.03 97.33,84.04 97.33,84.36 97.11,84.58 93.69,84.58 93.33,84.94 93.33,85.58 92.35,86.56 91.44,86.56 91.39,86.51 91.39,86.28 91.47,86.2 v2(91.95,86.2)
DDR2_DQS1: length 82.3
  TOP w0.114: v1(65.91,52.2) 65.89,52.18 J6.31 ; U5.AN11 v2(91.96,83.19)
  L4-SIG2 w0.102: v2(91.96,83.19) 91.44,82.68 90.67,82.68 90.41,82.41 90.41,82.18 89.75,81.52 89.24,81.52 89.21,81.48 86.03,81.48 86,81.51 85.78,81.74 80.39,81.74 80.08,82.04 79.45,82.04 79.17,81.76 77.46,81.76 v1(77.23,81.53)
  L9-SIG3 w0.102: v1(76.83,52.2) 76.71,52.32 76.71,53.22 78.05,54.57 78.05,55.1 77.79,55.36 76.96,55.36 76.86,55.46 76.86,55.67 76.96,55.77 77.79,55.77 78.05,56.03 78.05,56.47 77.79,56.73 76.96,56.73 76.86,56.83 76.86,57.04 76.96,57.14 77.79,57.14 78.05,57.4 78.05,57.84 77.79,58.1 76.96,58.1 76.86,58.21 76.86,58.41 76.96,58.51 77.79,58.51 78.05,58.78 78.05,59.21 77.79,59.48 76.96,59.48 76.86,59.58 76.86,59.78 76.96,59.88 77.79,59.88 78.05,60.15 78.05,60.58 77.79,60.85 76.96,60.85 76.86,60.95 76.86,61.15 76.96,61.25 77,61.25 78.05,62.31 78.05,66.94 77.32,67.68 77.32,68.03 78.03,68.74 78.03,69.18 77.76,69.44 76.71,69.44 76.61,69.55 76.61,69.75 76.71,69.85 77.76,69.85 78.03,70.12 78.03,70.55 77.76,70.82 76.71,70.82 76.61,70.92 76.61,71.12 76.71,71.22 77.76,71.22 78.03,71.49 78.03,71.92 77.76,72.19 76.71,72.19 76.61,72.29 76.61,72.49 76.71,72.59 77.76,72.59 78.03,72.86 78.03,73.29 77.76,73.56 76.71,73.56 76.61,73.66 76.61,73.86 76.71,73.97 77.76,73.97 78.03,74.23 78.03,74.67 77.76,74.93 76.71,74.93 76.61,75.03 76.61,75.24 76.71,75.34 77.76,75.34 78.03,75.6 78.03,76.04 77.76,76.3 77.42,76.3 77.32,76.4 77.32,81.45 v1(77.23,81.53)
  L10-SIG4 w0.102: v1(65.91,52.2) 66.17,51.94 66.82,51.94 66.97,51.79 67.39,51.79 67.7,52.1 67.92,52.1 68.07,51.94 68.28,51.94 68.43,52.1 68.63,52.1 68.78,51.94 76.58,51.94 v1(76.83,52.2)
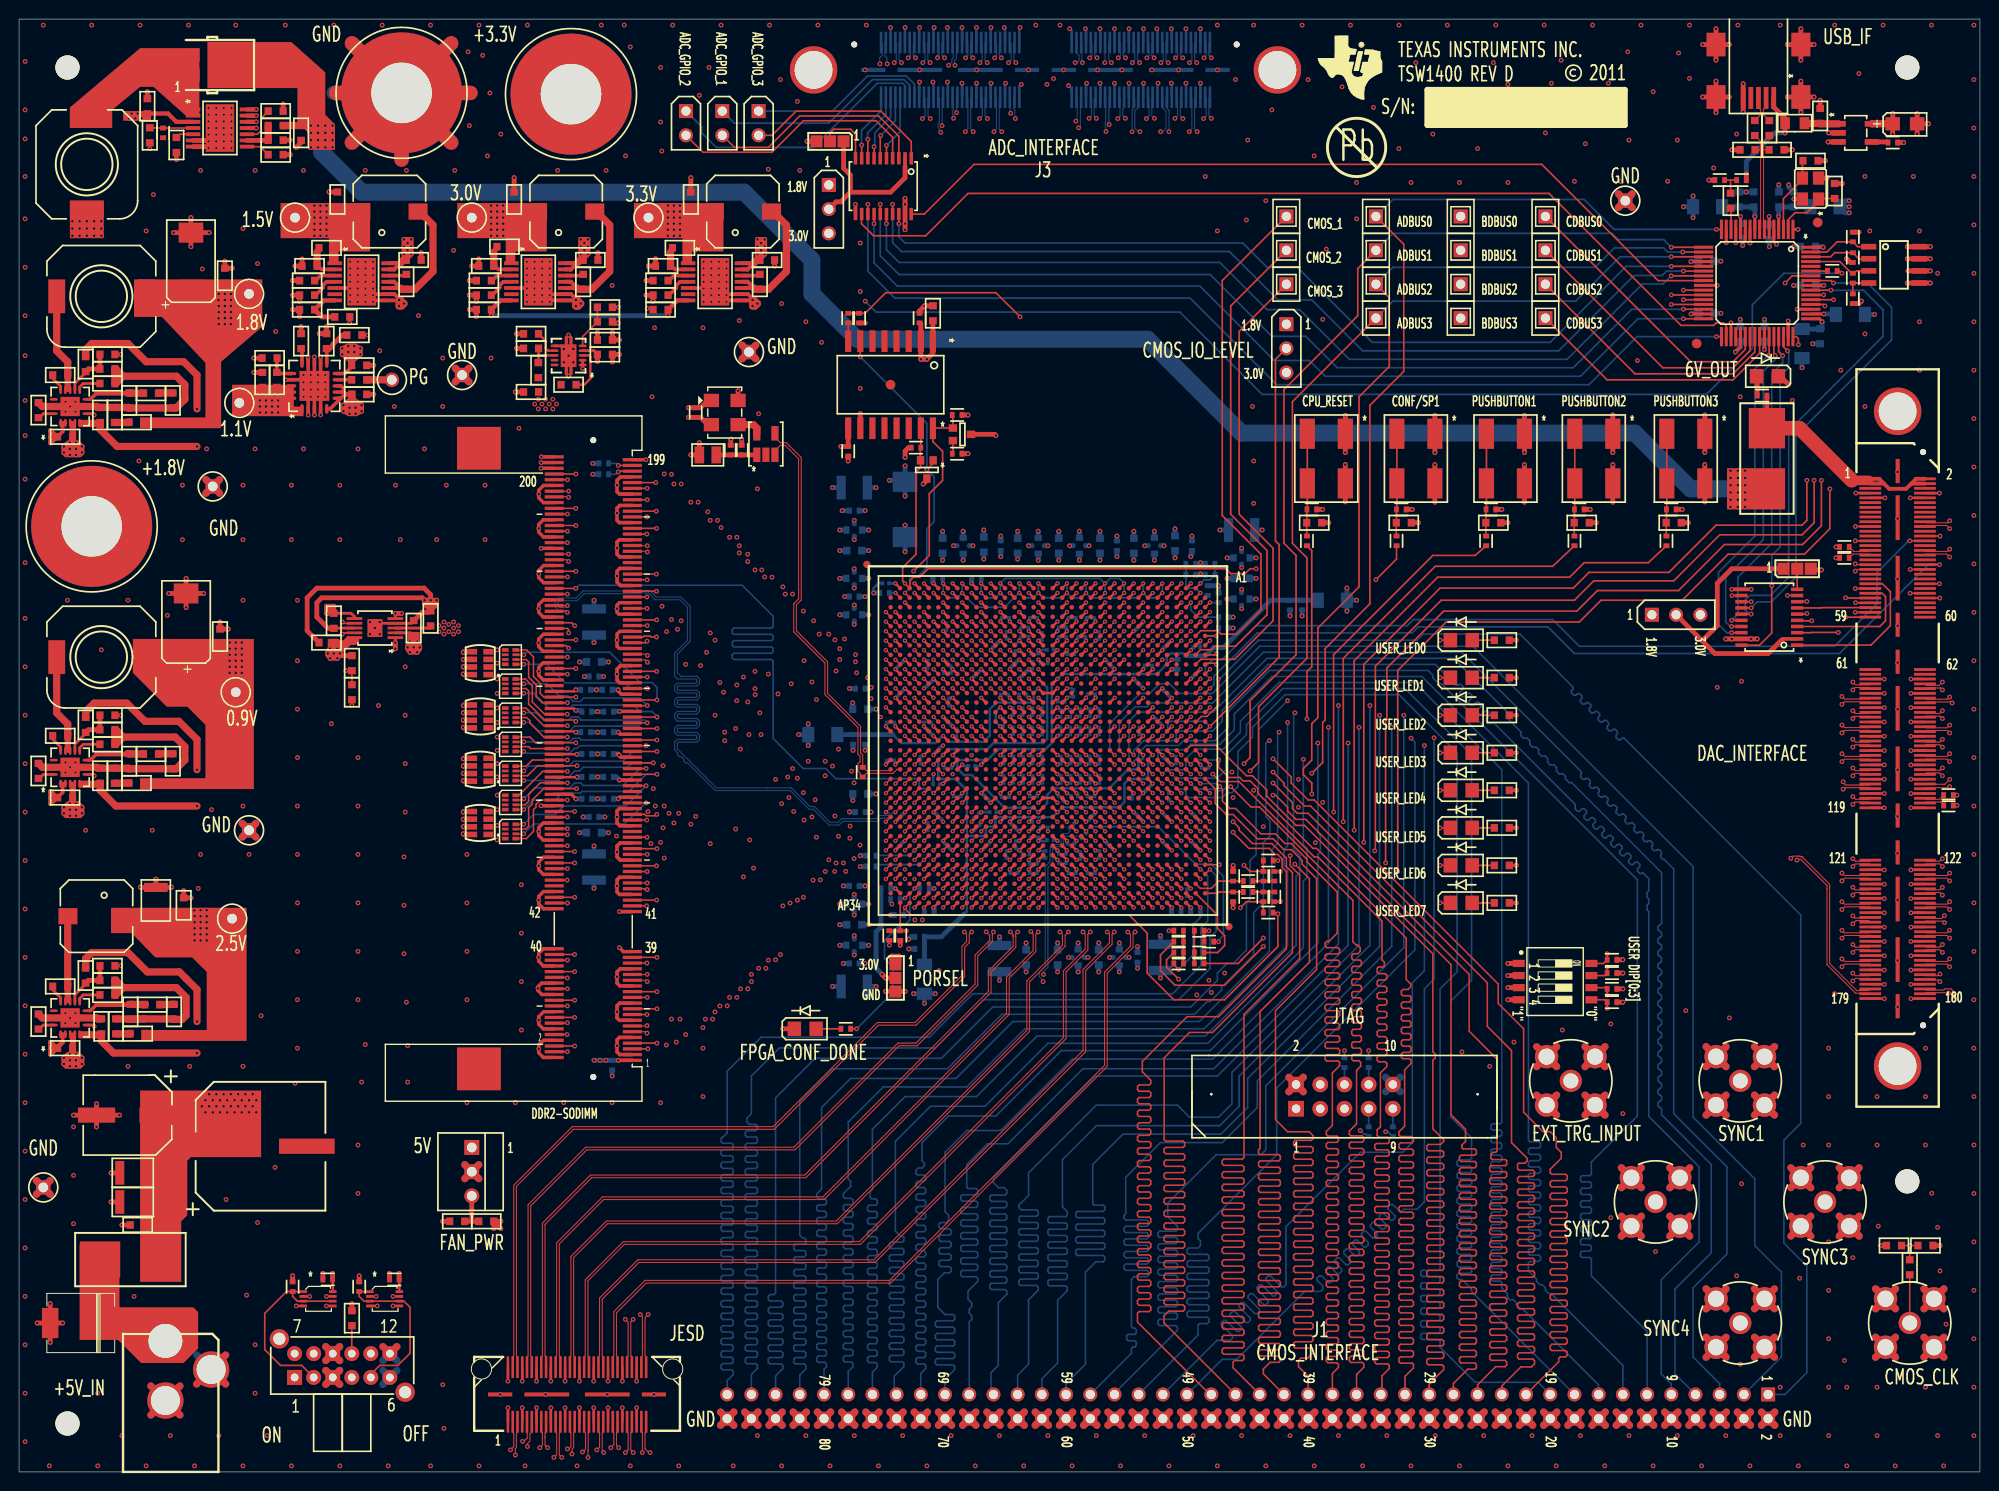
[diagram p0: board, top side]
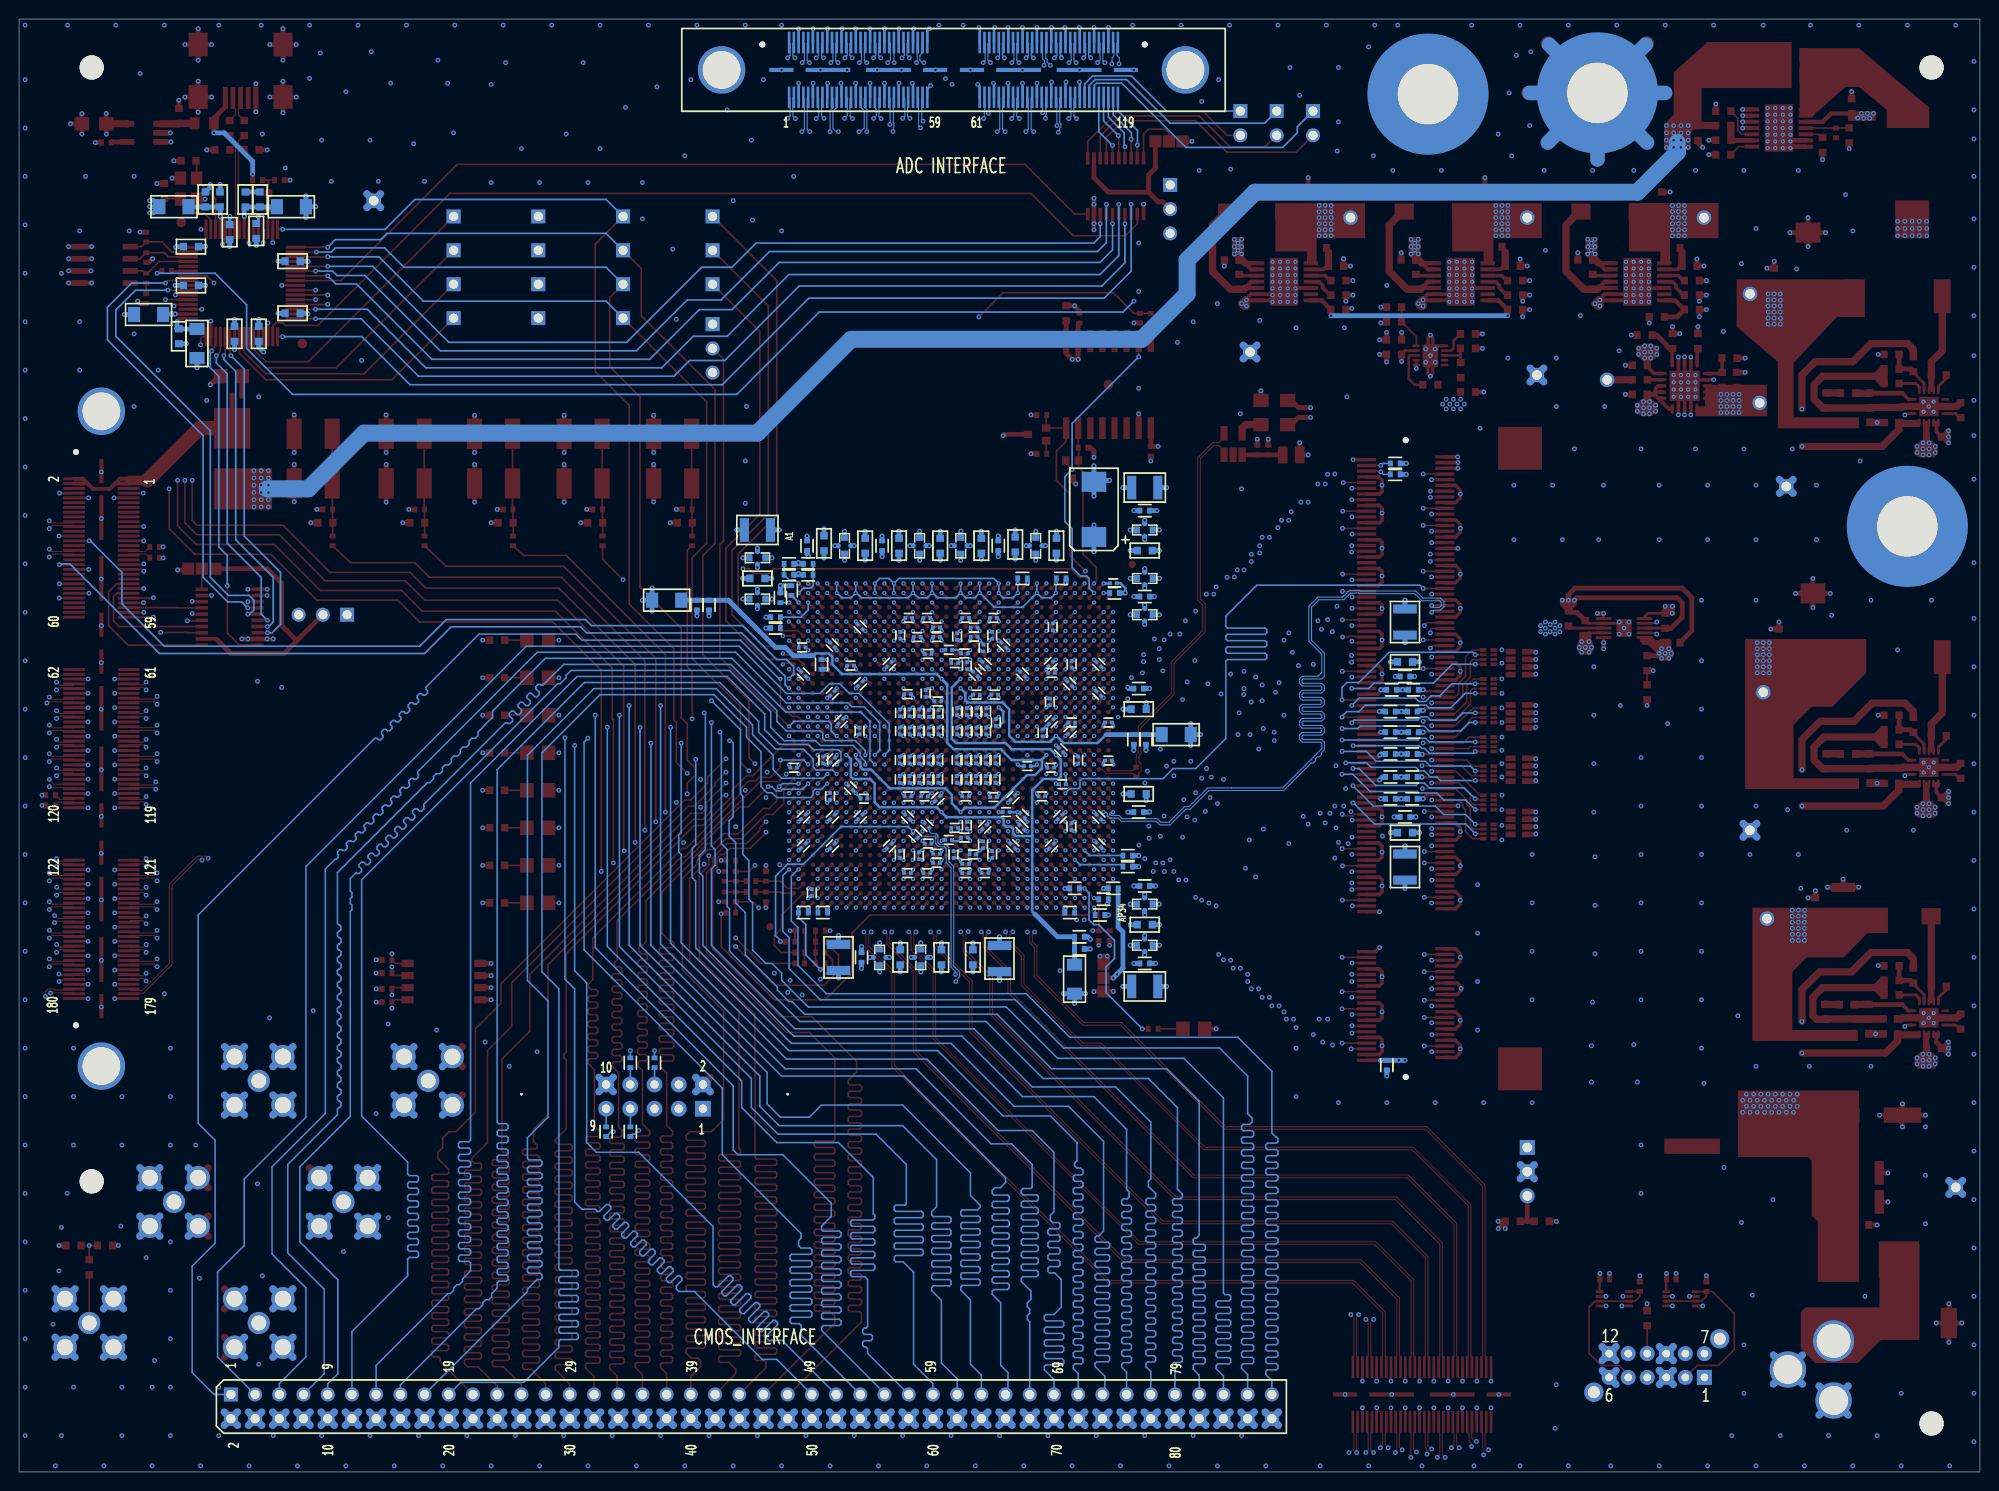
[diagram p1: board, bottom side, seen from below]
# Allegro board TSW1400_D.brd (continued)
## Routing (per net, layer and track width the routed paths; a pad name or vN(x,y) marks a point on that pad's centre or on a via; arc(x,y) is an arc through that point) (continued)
DDR2_DQS2: length 82.3
  TOP w0.114: J6.51 v1(65.91,61.78) ; U5.AK20 v2(94.95,73.2)
  L10-SIG4 w0.102: v2(94.95,73.2) 94.94,73.21 94.58,73.21 93.97,73.82 93.22,73.82 93.21,73.83 92.7,73.83 92.69,73.82 90.55,73.82 90.28,74.09 89.84,74.09 89.41,74.52 86.66,74.52 85.78,73.63 85.07,73.63 84.67,74.04 82.31,74.04 81.78,74.58 75.97,74.58 75.46,75.08 74.72,75.08 74.45,74.82 74.45,74.55 74.35,74.45 74.15,74.45 74.05,74.55 74.05,75.45 73.78,75.72 73.35,75.72 73.08,75.45 73.08,74.55 72.98,74.45 72.78,74.45 72.67,74.55 72.67,75.45 72.41,75.72 71.97,75.72 71.71,75.45 71.71,74.55 71.61,74.45 71.4,74.45 71.3,74.55 71.3,75.45 71.04,75.72 70.6,75.72 70.34,75.45 70.34,74.55 70.24,74.45 70.03,74.45 69.93,74.55 69.93,75.45 69.67,75.72 69.23,75.72 68.97,75.45 68.97,74.55 68.86,74.45 68.66,74.45 68.56,74.55 68.56,74.82 68.29,75.08 65.38,75.08 64.1,73.8 64.1,72.56 63.48,71.94 62.51,71.94 62.16,72.29 59.79,72.29 59.5,72 59.5,71.36 59.77,71.09 61.24,71.09 61.8,70.54 61.8,70.08 61.34,69.62 60.3,69.62 59.84,69.16 59.84,65.05 59.36,64.57 59.36,63.6 59.64,63.32 62.61,63.32 63.55,64.26 64.39,64.26 64.74,63.91 64.74,62.73 64.45,62.43 61.53,62.43 61.06,61.96 61.06,60.72 61.78,59.99 63.8,59.99 64.62,60.81 65.62,60.81 65.74,60.68 66.08,60.68 66.4,60.99 66.4,61.37 65.98,61.78 v1(65.91,61.78)
DDR2_DQS3: length 82.3
  TOP w0.114: U5.AH14 v2(96.95,80.2) ; J6.70 v1(57.53,67.48)
  L3-SIG1 w0.102: v2(96.95,80.2) 96.62,80.2 96.53,80.3 96.53,80.44 96.6,80.52 96.65,80.52 96.71,80.58 99.23,80.58 100.35,79.46 100.35,78.47 100.33,78.46 100.33,77.94 100.34,77.93 100.34,76.67 99.49,75.82 97.66,75.82 97.33,75.49 97.33,75.04 97.32,75.03 97.32,74.37 97.33,74.36 97.33,74.04 97.32,74.03 97.32,73.98 97.17,73.83 97.12,73.83 97.11,73.82 96.55,73.82 96.32,73.58 96.32,73.37 96.33,73.36 96.33,72.59 95.33,71.59 95.33,70.9 95.25,70.82 94.93,70.82 94.64,70.82 94.33,70.51 94.33,70.32 94.33,70.31 94.33,63.93 93.36,62.96 93.36,62.48 93.08,62.2 v2(92.95,62.2)
  L10-SIG4 w0.102: v1(57.53,67.48) 57.88,67.48 58.32,67.04 58.32,66.52 58.98,65.86 58.98,59.13 59.35,58.76 59.6,58.76 59.7,58.67 59.7,58.52 59.65,58.47 59.65,58.33 59.8,58.19 59.94,58.19 59.99,58.23 60.13,58.23 60.27,58.09 60.27,57.95 60.23,57.9 60.23,57.76 60.37,57.61 60.51,57.61 60.56,57.66 60.7,57.66 60.85,57.52 60.85,57.13 61.32,56.67 62.03,56.67 62.3,56.4 62.3,56.01 62.4,55.91 62.6,55.91 62.7,56.01 62.7,56.4 62.97,56.67 63.4,56.67 63.67,56.4 63.67,56.01 63.77,55.91 63.97,55.91 64.08,56.01 64.08,56.46 64.29,56.67 80.51,56.67 80.78,56.4 80.78,56.39 80.88,56.29 81.08,56.29 81.18,56.39 81.18,56.4 81.45,56.67 81.88,56.67 82.15,56.4 82.15,56.39 82.25,56.29 82.45,56.29 82.56,56.39 82.56,56.4 82.82,56.67 83.26,56.67 83.41,56.52 84.04,56.52 84.19,56.67 86.11,56.67 86.39,56.95 90.86,56.95 92.2,58.29 92.2,58.31 92.36,58.46 92.41,58.46 92.58,58.63 92.99,58.63 93.31,58.95 93.31,59.02 93.33,59.04 93.33,60.36 93.31,60.38 93.31,61.9 93.32,61.91 93.32,61.98 92.96,62.33 92.96,62.21 92.98,62.2 v2(92.95,62.2)
DDR2_DQS4: length 82.2
  TOP w0.114: U5.AN27 v2(91.95,66.2) ; J6.131 65.81,85.78 65.94,85.65 v1(65.94,85.65)
  L9-SIG3 w0.102: v2(91.95,66.2) 91.64,66.51 91.64,67.39 91.21,67.82 91.21,67.82 90.69,67.82 90.69,67.82 89.56,67.82 89.43,67.94 89.43,68.3 89.56,68.43 90.2,68.43 90.45,68.68 90.45,69.71 89.48,70.68 89.48,76.04 89.64,76.19 89.64,76.35 88.16,77.83 88.16,83.07 88.62,83.53 88.62,84.86 v1(87.76,85.72)
  L10-SIG4 w0.102: v1(65.94,85.65) 65.81,85.78 65.06,85.78 64.71,86.13 63.95,86.13 63.79,85.97 63.79,85.96 63.6,85.78 62.97,85.78 62.71,85.52 61.16,85.52 60.22,84.58 59.61,84.58 59.31,84.89 59.31,85.27 59.13,85.45 58.65,85.45 57.45,84.25 56.46,84.25 55.93,84.79 55.93,86.63 56.55,87.25 57.86,87.25 58.34,86.77 58.62,86.77 59.13,87.27 59.54,87.27 59.88,86.93 59.88,86.46 60.01,86.33 60.45,86.33 60.81,86.69 60.81,87.02 61.19,87.4 61.8,87.4 62.36,86.84 63.12,86.84 63.83,87.55 64.8,87.55 65.63,86.72 66.78,86.72 67.3,86.2 67.3,85.27 67.4,85.17 67.6,85.17 67.7,85.27 67.7,85.76 67.97,86.03 68.4,86.03 68.67,85.76 68.67,85.27 68.77,85.17 68.97,85.17 69.07,85.27 69.07,85.74 69.29,85.95 71.27,85.95 71.75,85.47 72.47,85.47 72.64,85.31 73.04,85.31 73.37,85.64 73.84,85.64 74.17,85.31 74.41,85.31 74.74,85.64 75.21,85.64 75.54,85.31 75.78,85.31 76.11,85.64 76.59,85.64 76.91,85.31 77.15,85.31 77.48,85.64 77.96,85.64 78.29,85.31 78.53,85.31 78.86,85.64 79.33,85.64 79.66,85.31 79.98,85.31 80.3,85.62 81.04,85.62 82.03,84.63 82.55,84.63 82.85,84.93 82.85,85.32 83.11,85.57 83.58,85.57 84.14,85.01 84.34,85.01 84.9,85.57 85.37,85.57 85.62,85.32 85.62,85.01 85.83,84.81 86.33,84.81 87,85.47 87.5,85.47 v1(87.76,85.72)
DDR2_DQS5: length 82.2
  TOP w0.114: J6.148 v1(57.53,90.88) ; U5.AN24 v2(91.95,69.2)
  BOTTOM w0.114: v2(91.95,69.2) 91.68,69.2 91.57,69.09 91.57,68.84 91.31,68.58 91.12,68.58 91.11,68.59 90.79,68.59 90.78,68.58 90.42,68.58 90.09,68.25 86.42,68.25 86.04,67.87 84.97,67.87 83.32,69.52 82.87,69.52 80.91,71.48 78.66,71.48 73.05,71.48 70.15,74.37 69.95,74.37 69.73,74.6 69.73,74.8 69.51,75.02 69.3,75.02 69.08,75.24 69.08,75.44 68.78,75.74 68.78,76.55 69.06,76.83 71.01,76.83 71.12,76.94 71.12,77.17 71.01,77.29 69.06,77.29 68.78,77.56 68.78,78.02 69.06,78.3 71.01,78.3 71.12,78.42 71.12,78.65 71.01,78.76 69.06,78.76 68.78,79.04 68.78,79.5 69.06,79.78 71.01,79.78 71.12,79.89 71.12,80.12 71.01,80.23 69.06,80.23 68.78,80.51 68.78,80.97 69.06,81.25 71.01,81.25 71.12,81.36 71.12,81.59 71.01,81.71 69.06,81.71 68.78,81.98 68.78,82.44 69.06,82.72 71.01,82.72 71.12,82.84 71.12,83.07 71.01,83.18 69.06,83.18 68.78,83.46 68.78,85.89 70.13,87.24 70.13,90.7 69.34,91.49 66.74,91.49 66.28,91.94 66.28,91.95 66.04,92.19 65.2,92.19 65.14,92.13 59.3,92.13 58.56,91.38 56.7,91.38 56.51,91.2 56.51,90.87 56.72,90.66 57.32,90.66 v1(57.53,90.88)
DDR2_DQS6: length 82.3
  TOP w0.114: U5.AK15 v2(94.95,79.2) ; v1(65.91,97.16) 64.37,97.16 J6.169
  L3-SIG1 w0.102: v1(75.56,97.16) 75.75,96.97 76.04,96.97 76.45,97.38 76.45,98.78 76.91,99.24 77.71,99.24 77.97,98.97 77.97,98.05 78.05,97.97 78.28,97.97 78.38,98.06 78.38,100.32 78.64,100.58 79.08,100.58 79.34,100.32 79.34,97.99 79.44,97.89 79.65,97.89 79.75,97.99 79.75,100.32 80.01,100.58 80.45,100.58 80.71,100.32 80.71,97.99 80.82,97.89 81.02,97.89 81.12,97.99 81.12,100.32 81.39,100.58 81.82,100.58 82.09,100.32 82.09,97.99 82.19,97.89 82.39,97.89 82.49,97.99 82.49,100.32 82.76,100.58 83.85,100.58 84.91,99.52 84.91,97.24 84.68,97.01 84.68,94.48 86.39,92.77 86.41,92.77 86.49,92.68 87.02,92.68 87.47,92.24 87.93,91.78 87.93,91.78 88.74,90.97 88.74,89.64 89.52,88.85 89.52,87.07 90.34,86.26 90.34,86.2 90.72,85.82 92.26,85.82 92.53,85.55 92.53,85.49 92.57,85.46 92.57,83.94 92.69,83.82 94.21,83.82 94.57,83.46 94.57,82.94 94.56,82.94 94.56,82.36 94.57,82.36 94.57,81.94 94.56,81.94 94.56,81.46 94.57,81.46 94.57,80.94 94.56,80.94 94.56,80.46 94.57,80.46 94.57,79.94 94.56,79.94 94.56,79.59 v2(94.95,79.2)
  L10-SIG4 w0.102: v1(75.56,97.16) 75.31,96.9 74.24,96.9 73.97,96.64 73.97,96.22 73.87,96.11 73.67,96.11 73.56,96.22 73.56,97.42 73.3,97.69 72.86,97.69 72.6,97.42 72.6,96.22 72.5,96.11 72.29,96.11 72.19,96.22 72.19,97.42 71.93,97.69 71.49,97.69 71.23,97.42 71.23,96.22 71.13,96.11 70.92,96.11 70.82,96.22 70.82,97.42 70.56,97.69 70.12,97.69 69.86,97.42 69.86,96.22 69.75,96.11 69.55,96.11 69.45,96.22 69.45,97.42 69.18,97.69 68.75,97.69 68.48,97.42 68.48,96.22 68.38,96.11 68.18,96.11 68.08,96.22 68.08,97.42 67.81,97.69 67.38,97.69 67.11,97.42 67.11,97 67.01,96.9 66.17,96.9 v1(65.91,97.16)
DDR2_DQS7: length 92.1
  TOP w0.114: U5.AJ23 v2(95.95,70.2) ; J6.188 v1(57.66,102.88)
  L4-SIG2 w0.102: v2(95.95,70.2) 95.47,69.72 94.87,69.72 94.36,70.23 94.36,70.33 94.11,70.58 90.35,70.58 90.2,70.43 89.63,70.43 89.15,70.92 83.15,70.92 82.71,70.48 81.6,70.48 81.18,70.9 81.18,70.91 80.94,71.15 80.3,71.15 80.13,70.97 67.97,70.97 67.68,70.68 64.97,70.68 64.11,69.82 57.84,69.82 57.48,69.47 57.48,69.47 55.65,67.64 55.65,67.14 54.65,66.14 52.69,66.14 50.25,68.58 49.92,68.58 48.26,70.24 48.26,93.99 56.96,102.7 57.48,102.7 v1(57.66,102.88)
DDR2_DQSN0: length 82.2
  TOP w0.114: U5.AP8 v2(90.95,86.2) ; v1(65.89,46.02) 65.89,46.18 J6.11
  L4-SIG2 w0.102: v1(65.89,46.02) 66.14,46.28 69.22,46.28 69.37,46.43 70.41,46.43 70.99,45.85 73.61,45.85 73.6,45.85 74.29,45.85 74.55,46.11 75.57,46.11 75.88,46.42 75.88,46.84 75.79,46.92 75.79,47.09 75.92,47.22 76.03,47.22 76.17,47.08 76.54,47.08 76.85,47.39 76.85,47.76 76.6,48.02 76.6,48.16 76.74,48.3 76.88,48.3 77.14,48.05 77.51,48.05 77.82,48.36 77.82,48.73 77.57,48.99 77.57,49.13 77.71,49.27 77.85,49.27 78.11,49.02 78.48,49.02 78.79,49.33 78.79,49.98 78.87,50.06 79.01,50.06 79.16,49.91 79.38,49.91 79.76,50.3 79.76,51.32 84.8,56.36 86.64,56.36 87.1,56.82 88.06,56.82 88.39,56.49 91.17,56.49 91.94,57.25 93.36,57.25 93.61,57 94.35,57 94.51,57.16 94.51,57.64 v1(94.78,57.91)
  L9-SIG3 w0.102: v1(94.78,57.91) 94.78,57.54 94.57,57.75 94.57,59.11 94.57,59.11 94.57,60.81 96.34,62.58 99.21,62.58 99.57,62.94 99.57,69.52 99.63,69.58 99.63,69.73 99.81,69.91 99.81,74.36 99.35,74.83 99.35,76.12 98.57,76.9 98.57,79.54 98.29,79.82 97.79,79.82 97.57,80.04 97.57,80.46 97.56,80.46 97.56,80.94 97.57,80.94 97.57,81.46 97.56,81.46 97.56,81.94 97.57,81.94 97.57,82.46 97.56,82.46 97.56,82.94 97.57,82.94 97.57,83.46 97.56,83.46 97.56,83.94 97.57,83.94 97.57,84.46 97.21,84.82 93.79,84.82 93.57,85.04 93.57,85.68 92.43,86.82 91.16,86.82 90.95,86.61 v2(90.95,86.2)
DDR2_DQSN1: length 82.3
  TOP w0.114: U5.AP11 v2(90.96,83.19) ; v1(65.91,51.44) 65.77,51.58 J6.29
  L4-SIG2 w0.102: v1(77.22,82.17) 77.34,82.04 79.05,82.04 79.33,82.32 80.21,82.32 80.5,82.03 85.87,82.03 86.15,81.76 89.09,81.76 89.13,81.8 89.62,81.8 90.13,82.3 90.13,82.53 90.55,82.96 90.72,82.96 v2(90.96,83.19)
  L9-SIG3 w0.102: v1(77.22,82.17) 77.22,82.09 76.83,81.7 76.83,81.31 77.04,81.1 77.04,76.29 77.3,76.02 77.65,76.02 77.75,75.92 77.75,75.72 77.65,75.62 76.59,75.62 76.33,75.35 76.33,74.92 76.59,74.65 77.65,74.65 77.75,74.55 77.75,74.35 77.65,74.25 76.59,74.25 76.33,73.98 76.33,73.55 76.59,73.28 77.65,73.28 77.75,73.18 77.75,72.98 77.65,72.87 76.59,72.87 76.33,72.61 76.33,72.17 76.59,71.91 77.65,71.91 77.75,71.81 77.75,71.6 77.65,71.5 76.59,71.5 76.33,71.24 76.33,70.8 76.59,70.54 77.65,70.54 77.75,70.44 77.75,70.23 77.65,70.13 76.59,70.13 76.33,69.87 76.33,69.43 76.59,69.17 77.65,69.17 77.75,69.06 77.75,68.86 77.04,68.15 77.04,67.56 77.77,66.83 77.77,62.46 76.58,61.27 76.58,60.83 76.85,60.57 77.67,60.57 77.77,60.47 77.77,60.26 77.67,60.16 76.85,60.16 76.58,59.9 76.58,59.46 76.85,59.2 77.67,59.2 77.77,59.09 77.77,58.89 77.67,58.79 76.85,58.79 76.58,58.52 76.58,58.09 76.85,57.82 77.67,57.82 77.77,57.72 77.77,57.52 77.67,57.42 76.85,57.42 76.58,57.15 76.58,56.72 76.85,56.45 77.67,56.45 77.77,56.35 77.77,56.15 77.67,56.05 76.85,56.05 76.58,55.78 76.58,55.35 76.85,55.08 77.38,55.08 77.67,54.79 77.67,54.58 76.43,53.34 76.43,51.84 v1(76.83,51.44)
  L10-SIG4 w0.102: v1(65.91,51.44) 66.04,51.56 66.81,51.56 66.86,51.51 67.51,51.51 67.66,51.66 76.61,51.66 v1(76.83,51.44)
DDR2_DQSN2: length 82.3
  TOP w0.114: v1(65.91,61.09) 65.82,61.18 J6.49 ; U5.AL20 v2(93.95,73.2)
  L10-SIG4 w0.102: v1(65.91,61.09) 64.5,61.09 63.69,60.27 61.9,60.27 61.34,60.83 61.34,61.85 61.65,62.15 64.57,62.15 65.02,62.61 65.02,64.02 64.5,64.54 63.44,64.54 62.5,63.6 59.79,63.6 59.64,63.75 59.64,64.41 60.12,64.9 61.87,64.9 62.18,65.2 62.18,66.09 61.75,66.52 60.48,66.52 60.12,66.88 60.12,69.05 60.42,69.34 61.62,69.34 62.08,69.8 62.08,70.8 61.51,71.37 59.89,71.37 59.78,71.48 59.78,71.87 59.92,72.01 62.04,72.01 62.39,71.66 63.66,71.66 64.38,72.38 64.38,73.69 65.5,74.8 68.18,74.8 68.28,74.7 68.28,74.43 68.55,74.17 68.98,74.17 69.25,74.43 69.25,75.34 69.35,75.44 69.55,75.44 69.65,75.34 69.65,74.43 69.92,74.17 70.35,74.17 70.62,74.43 70.62,75.34 70.72,75.44 70.92,75.44 71.02,75.34 71.02,74.43 71.29,74.17 71.72,74.17 71.99,74.43 71.99,75.34 72.09,75.44 72.29,75.44 72.4,75.34 72.4,74.43 72.66,74.17 73.1,74.17 73.36,74.43 73.36,75.34 73.46,75.44 73.67,75.44 73.77,75.34 73.77,74.43 74.03,74.17 74.47,74.17 74.73,74.43 74.73,74.7 74.83,74.8 75.34,74.8 75.84,74.3 81.66,74.3 82.19,73.76 84.55,73.76 84.96,73.36 85.89,73.36 86.78,74.24 89.29,74.24 89.72,73.81 90.22,73.81 90.45,73.58 92.79,73.58 92.8,73.59 93.12,73.59 93.12,73.58 93.59,73.58 93.96,73.21 v2(93.95,73.2)
DDR2_DQSN3: length 82.3
  TOP w0.114: v1(57.53,66.84) 57.5,66.88 J6.68 ; U5.AJ14 v2(95.95,80.2)
  L3-SIG1 w0.102: v2(95.95,80.2) 96.57,80.82 99.32,80.82 100.58,79.56 100.58,78.37 100.57,78.36 100.57,78 100.58,77.99 100.58,76.57 99.58,75.58 97.76,75.58 97.57,75.39 97.57,74.94 97.56,74.94 97.56,74.46 97.57,74.46 97.57,73.94 97.56,73.94 97.56,73.88 97.27,73.59 97.21,73.59 97.21,73.58 96.65,73.58 96.55,73.49 96.55,73.47 96.57,73.46 96.57,72.49 95.57,71.49 95.57,70.8 95.35,70.58 94.84,70.58 94.74,70.58 94.57,70.41 94.57,63.83 93.6,62.86 93.6,62.53 93.9,62.23 93.92,62.23 v2(93.95,62.2)
  L10-SIG4 w0.102: v1(57.53,66.84) 57.74,67.06 57.91,67.06 58.04,66.93 58.04,66.41 58.7,65.75 58.7,58.89 61.2,56.39 61.59,56.39 62.02,55.96 62.02,55.89 62.28,55.63 62.72,55.63 62.98,55.89 62.98,56.29 63.08,56.39 63.29,56.39 63.39,56.29 63.39,55.89 63.65,55.63 64.09,55.63 64.35,55.89 64.35,56.31 64.43,56.39 80.4,56.39 80.5,56.29 80.5,56.27 80.76,56.01 81.2,56.01 81.46,56.27 81.46,56.29 81.57,56.39 81.77,56.39 81.87,56.29 81.87,56.27 82.14,56.01 82.57,56.01 82.84,56.27 82.84,56.29 82.94,56.39 83.14,56.39 83.24,56.29 83.24,56.27 83.63,55.88 83.81,55.88 84.21,56.27 84.21,56.29 84.31,56.39 86.22,56.39 86.5,56.67 90.97,56.67 92.48,58.18 92.48,58.19 92.68,58.39 92.89,58.39 93.09,58.39 93.55,58.85 93.55,58.92 93.57,58.94 93.57,60.46 93.55,60.48 93.55,61.8 v2(93.95,62.2)
DDR2_DQSN4: length 82.3
  TOP w0.114: J6.129 65.7,85.18 v1(65.94,84.94) ; U5.AP27 v2(90.95,66.2)
  L9-SIG3 w0.102: v1(87.76,84.99) 87.86,85.09 88,85.09 88.32,84.77 88.32,83.62 87.88,83.19 87.88,77.71 89.2,76.39 89.2,70.56 90.21,69.55 90.21,68.85 90.07,68.71 89.43,68.71 89.15,68.43 89.15,67.77 89.38,67.54 90.2,67.54 90.25,67.58 90.79,67.58 91.11,67.58 91.39,67.3 91.39,66.52 91.07,66.2 v2(90.95,66.2)
  L10-SIG4 w0.102: v1(65.94,84.94) 66.37,85.37 66.37,85.83 66.14,86.06 65.18,86.06 64.82,86.41 63.83,86.41 63.47,86.06 62.84,86.06 62.59,85.8 61.05,85.8 60.11,84.86 59.73,84.86 59.59,85 59.59,85.38 59.25,85.72 58.53,85.72 57.34,84.53 56.72,84.53 56.21,85.04 56.21,86.51 56.67,86.97 57.75,86.97 58.23,86.49 58.74,86.49 59.25,87 59.42,87 59.6,86.81 59.6,86.35 59.89,86.06 60.57,86.06 61.09,86.57 61.09,86.9 61.3,87.12 61.68,87.12 62.24,86.56 63.23,86.56 63.95,87.27 64.68,87.27 65.52,86.44 66.66,86.44 67.02,86.08 67.02,85.15 67.28,84.89 67.72,84.89 67.98,85.15 67.98,85.65 68.08,85.75 68.29,85.75 68.39,85.65 68.39,85.15 68.65,84.89 69.09,84.89 69.35,85.15 69.35,85.61 69.42,85.67 71.16,85.67 71.64,85.19 72.35,85.19 72.52,85.03 73.16,85.03 73.49,85.36 73.73,85.36 74.06,85.03 74.53,85.03 74.86,85.36 75.1,85.36 75.43,85.03 75.9,85.03 76.23,85.36 76.47,85.36 76.8,85.03 77.27,85.03 77.6,85.36 77.84,85.36 78.17,85.03 78.64,85.03 78.97,85.36 79.21,85.36 79.54,85.03 80.1,85.03 80.41,85.34 80.92,85.34 81.92,84.35 82.67,84.35 83.13,84.82 83.13,85.2 83.22,85.29 83.46,85.29 84.02,84.73 84.45,84.73 85.01,85.29 85.25,85.29 85.34,85.2 85.34,84.9 85.71,84.53 86.45,84.53 87.11,85.19 87.55,85.19 v1(87.76,84.99)
DDR2_DQSN5: length 82.3
  TOP w0.114: v1(57.53,90.17) 57.45,90.17 57.35,90.28 J6.146 ; U5.AP24 v2(90.95,69.2)
  BOTTOM w0.114: v2(90.95,69.2) 91.19,69.2 91.29,69.09 91.29,68.96 91.2,68.87 90.67,68.87 90.67,68.86 90.31,68.86 89.98,68.53 86.31,68.53 85.93,68.15 85.09,68.15 83.44,69.8 82.98,69.8 81.03,71.75 78.54,71.75 78.54,71.75 73.17,71.75 69.06,75.86 69.06,76.44 69.18,76.55 71.12,76.55 71.4,76.83 71.4,77.29 71.12,77.57 69.18,77.57 69.06,77.68 69.06,77.91 69.18,78.02 71.12,78.02 71.4,78.3 71.4,78.76 71.12,79.04 69.18,79.04 69.06,79.15 69.06,79.38 69.18,79.5 71.12,79.5 71.4,79.77 71.4,80.23 71.12,80.51 69.18,80.51 69.06,80.63 69.06,80.86 69.18,80.97 71.12,80.97 71.4,81.25 71.4,81.71 71.12,81.99 69.18,81.99 69.06,82.1 69.06,82.33 69.18,82.44 71.12,82.44 71.4,82.72 71.4,83.18 71.12,83.46 69.45,83.46 69.06,83.85 69.06,85.78 70.41,87.12 70.41,90.82 69.46,91.77 66.85,91.77 66.56,92.06 66.56,92.07 66.16,92.47 65.09,92.47 65.02,92.41 59.18,92.41 58.44,91.66 56.59,91.66 56.24,91.31 56.24,90.75 56.61,90.38 57.32,90.38 v1(57.53,90.17)
DDR2_DQSN6: length 82.3
  TOP w0.114: J6.167 65.85,96.58 v1(65.94,96.5) ; U5.AL15 v2(93.95,79.2)
  L3-SIG1 w0.102: v2(93.95,79.2) 94.33,79.58 94.33,80.04 94.33,80.04 94.33,80.36 94.33,80.36 94.33,81.04 94.33,81.04 94.33,81.36 94.33,81.36 94.33,82.04 94.33,82.04 94.33,82.26 94.33,82.26 94.33,83.04 94.33,83.04 94.33,83.36 94.11,83.58 92.57,83.58 92.33,83.82 92.33,85.36 92.29,85.39 92.29,85.45 92.17,85.58 90.62,85.58 89.24,86.96 89.24,88.74 88.46,89.52 88.46,90.86 87.65,91.66 87.27,92.04 86.91,92.41 86.38,92.41 86.3,92.49 86.28,92.49 84.4,94.36 84.4,97.13 84.63,97.36 84.63,97.67 84.45,97.84 84.45,98.07 84.63,98.25 84.63,98.48 84.45,98.66 84.45,98.89 84.63,99.06 84.63,99.4 83.73,100.3 82.87,100.3 82.77,100.2 82.77,97.88 82.51,97.61 82.07,97.61 81.81,97.88 81.81,100.2 81.7,100.3 81.5,100.3 81.4,100.2 81.4,97.88 81.13,97.61 80.7,97.61 80.43,97.88 80.43,100.2 80.33,100.3 80.13,100.3 80.03,100.2 80.03,97.88 79.76,97.61 79.33,97.61 79.06,97.88 79.06,100.2 78.96,100.3 78.76,100.3 78.66,100.2 78.66,97.88 78.39,97.61 77.96,97.61 77.69,97.88 77.69,98.86 77.59,98.96 77.04,98.96 76.73,98.65 76.73,97.26 76.17,96.69 75.86,96.69 v1(75.56,96.39)
  L10-SIG4 w0.102: v1(75.56,96.39) 75.34,96.62 74.35,96.62 74.25,96.52 74.25,96.1 73.99,95.83 73.55,95.83 73.29,96.1 73.29,97.31 73.18,97.41 72.98,97.41 72.88,97.31 72.88,96.1 72.61,95.83 72.18,95.83 71.91,96.1 71.91,97.31 71.81,97.41 71.61,97.41 71.51,97.31 71.51,96.1 71.24,95.83 70.81,95.83 70.54,96.1 70.54,97.31 70.44,97.41 70.24,97.41 70.14,97.31 70.14,96.1 69.87,95.83 69.44,95.83 69.17,96.1 69.17,97.31 69.07,97.41 68.87,97.41 68.76,97.31 68.76,96.1 68.5,95.83 68.06,95.83 67.8,96.1 67.8,97.31 67.7,97.41 67.49,97.41 67.39,97.31 67.39,96.89 67.13,96.62 66.06,96.62 v1(65.94,96.5)
DDR2_DQSN7: length 89.8
  TOP w0.114: v1(57.66,102.24) 57.61,102.28 J6.186 ; U5.AK23 v2(94.95,70.2)
  L4-SIG2 w0.102: v2(94.95,70.2) 94.33,70.82 90.25,70.82 90.14,70.71 89.75,70.71 89.27,71.2 83.03,71.2 82.6,70.76 81.71,70.76 81.46,71.02 81.46,71.02 81.06,71.42 80.19,71.42 80.01,71.25 67.85,71.25 67.56,70.96 64.85,70.96 63.99,70.1 57.72,70.1 57.37,69.75 57.36,69.75 55.37,67.76 55.37,67.26 54.53,66.42 52.81,66.42 50.37,68.86 50.04,68.86 48.54,70.36 48.54,93.88 57.08,102.42 57.48,102.42 v1(57.66,102.24)
DDR2_ODT0: length 82.2
  TOP w0.165: U5.AG15 v2(97.95,79.2) ; v1(57.53,80.68) J6.114 54.91,80.68 54.25,81.33 54.25,82.58 53.47,83.36 53.47,84.96 53.21,85.22 RN8.6
  L4-SIG2 w0.102: 93.54,79.82 93.73,79.63 94.65,79.63 94.69,79.58 97.58,79.58 97.95,79.22 v2(97.95,79.2) ; 93.21,79.82 90.8,79.82 90.47,80.14
  L4-SIG2 w0.114: 93.54,79.82 93.21,79.82 ; v1(57.53,80.68) 56.48,80.68 56.26,80.9 56.26,81.06 56.67,81.47 56.67,81.63 56.51,81.79 56.35,81.79 55.94,81.38 55.5,81.38 55.37,81.51 55.37,82.08 55.49,82.19 56.53,82.19 56.64,82.31 56.64,82.54 56.53,82.65 55.49,82.65 55.37,82.77 55.37,82.99 55.49,83.11 56.53,83.11 56.64,83.22 56.64,83.45 56.53,83.57 55.49,83.57 55.37,83.68 55.37,83.91 55.49,84.02 56.53,84.02 56.64,84.14 56.64,84.37 56.53,84.48 55.49,84.48 55.37,84.59 55.37,84.84 55.5,84.96 56.77,84.96 57.02,84.71 57.02,82.04 58.24,80.83 66.46,80.83 66.75,80.54 67.31,80.54 67.54,80.77 67.84,80.77 67.95,80.66 67.95,80.63 68.07,80.52 68.29,80.52 68.41,80.63 68.41,80.91 68.52,81.03 68.75,81.03 68.87,80.91 68.87,80.63 68.98,80.52 69.21,80.52 69.32,80.63 69.32,80.91 69.44,81.03 69.67,81.03 69.78,80.91 69.78,80.63 69.9,80.52 70.12,80.52 70.24,80.63 70.24,80.91 70.35,81.03 70.58,81.03 70.7,80.91 70.7,80.63 70.81,80.52 71.04,80.52 71.15,80.63 71.15,80.91 71.27,81.03 71.5,81.03 71.61,80.91 71.61,80.63 71.72,80.52 71.95,80.52 72.07,80.63 72.07,80.91 72.18,81.03 72.41,81.03 72.52,80.91 72.52,80.89 72.64,80.77 73.3,80.77 74.03,80.04 76.61,80.04 77.72,81.15 77.99,81.15 78.11,81.03 78.11,80.56 78.23,80.45 78.46,80.45 78.57,80.56 78.57,81.08 78.68,81.2 78.91,81.2 79.03,81.08 79.03,80.56 79.14,80.45 79.37,80.45 79.48,80.56 79.48,81.08 79.6,81.2 79.83,81.2 79.94,81.08 79.94,80.56 80.06,80.45 80.28,80.45 80.4,80.56 80.4,81.08 80.51,81.2 80.74,81.2 80.86,81.08 80.86,80.56 80.97,80.45 81.2,80.45 81.31,80.56 81.31,81.08 81.43,81.2 81.66,81.2 81.77,81.08 81.77,80.56 81.88,80.45 82.11,80.45 82.23,80.56 82.23,80.96 82.42,81.15 82.68,81.15 83.29,80.54 84.07,80.54 84.22,80.39 84.53,80.39 84.6,80.47 84.6,80.62 84.68,80.7 84.98,80.7 85.06,80.62 85.06,80.47 85.14,80.39 85.44,80.39 85.52,80.47 85.52,80.62 85.59,80.7 85.9,80.7 85.98,80.62 85.98,80.47 86.05,80.39 86.36,80.39 86.51,80.54 86.79,80.54 87.15,80.19 89.46,80.19 89.69,80.42 90.19,80.42 90.47,80.14
DDR2_ODT1: length 82.3
  TOP w0.165: v1(65.91,82.18) J6.119 ; RN8.5 v1(52.95,84.72) ; U5.AM18 v2(92.96,75.21)
  L3-SIG1 w0.114: v1(75.68,75.83) 75.68,78.65 74.85,79.48 74.85,82.09 v1(75.31,82.55)
  L10-SIG4 w0.102: 90.81,75.21 v2(92.96,75.21)
  L10-SIG4 w0.114: v1(75.68,75.83) 76.48,75.03 83.86,75.03 84.29,75.46 85.57,75.46 85.83,75.21 90.81,75.21 ; v1(65.91,82.18) 65.43,82.66 65.43,83.67 65.61,83.85 65.61,84.35 65.51,84.45 65.28,84.45 65,84.73 65,85.19 64.85,85.34 64.57,85.34 64.44,85.22 64.44,84.56 64.31,84.43 63.91,84.43 63.78,84.56 63.78,85.22 63.65,85.34 63.22,85.34 63.07,85.19 63.07,84.66 62.84,84.43 61.62,84.43 61.32,84.73 61.04,84.73 60.78,84.48 60.78,84.12 60.96,83.95 61.85,83.95 62.08,83.72 62.08,83.36 62.33,83.11 63.09,83.11 63.74,83.76 64.58,83.76 65.07,83.26 65.07,82.12 65.43,81.76 66.98,81.76 67.09,81.88 67.09,82.77 67.2,82.88 67.43,82.88 67.55,82.77 67.55,81.88 67.66,81.76 67.89,81.76 68,81.88 68,82.77 68.12,82.88 68.35,82.88 68.46,82.77 68.46,81.88 68.58,81.76 68.8,81.76 68.92,81.88 68.92,82.77 69.03,82.88 69.26,82.88 69.38,82.77 69.38,81.88 69.49,81.76 69.72,81.76 69.83,81.88 69.83,82.77 69.95,82.88 70.18,82.88 70.29,82.77 70.29,81.88 70.4,81.76 70.63,81.76 70.75,81.88 70.75,82.77 70.86,82.88 71.09,82.88 71.2,82.77 71.2,81.88 71.32,81.76 71.55,81.76 71.66,81.88 71.66,82.77 71.78,82.88 72,82.88 72.12,82.77 72.12,81.88 72.23,81.76 72.46,81.76 72.58,81.88 72.58,82.21 72.69,82.32 75.08,82.32 v1(75.31,82.55)
  BOTTOM w0.165: v1(65.91,82.18) 64.13,82.18 63.55,82.75 57.33,82.75 55.36,84.72 v1(52.95,84.72)
DDR2_RAS_N: length 82.2
  TOP w0.165: U5.AE17 v2(99.95,77.2) ; RN9.6 53.21,82.17 53.47,81.92 53.47,80.54 55.13,78.88 J6.108 58.28,78.88 v1(58.42,78.74)
  L4-SIG2 w0.102: v2(99.95,77.2) 99.46,76.71 96.77,76.71 96.39,76.33 94.82,76.33 94.44,76.71 93.85,76.71 93.47,77.09 93.47,77.34 93.09,77.72 90.47,77.72 90.34,77.85
  L4-SIG2 w0.114: v1(58.42,78.74) 57.94,78.26 57.94,78.11 57.7,77.87 56.7,77.87 56.5,78.07 56.25,78.07 56.05,77.87 55.79,77.87 55.59,78.07 55.33,78.07 55.13,77.87 54.88,77.87 54.67,78.07 54.42,78.07 54.22,77.87 53.74,77.87 53.59,77.72 52.45,77.72 52.07,78.11 51.44,78.11 51.31,77.98 51.31,77.47 51.44,77.34 53.83,77.34 53.98,77.49 54.45,77.49 54.59,77.34 54.9,77.34 55.05,77.49 55.36,77.49 55.51,77.34 55.82,77.34 55.96,77.49 56.27,77.49 56.42,77.34 56.73,77.34 56.88,77.49 57.73,77.49 58.25,78.01 59.51,78.01 59.8,78.3 59.8,78.63 59.91,78.74 60.14,78.74 60.25,78.63 60.25,78.3 60.37,78.18 60.6,78.18 60.71,78.3 60.71,78.63 60.83,78.74 61.05,78.74 61.17,78.63 61.17,78.3 61.28,78.18 61.51,78.18 61.63,78.3 61.63,78.63 61.74,78.74 61.97,78.74 62.08,78.63 62.08,78.3 62.2,78.18 62.43,78.18 62.54,78.3 62.54,78.63 62.65,78.74 62.88,78.74 63,78.63 63,78.3 63.11,78.18 63.34,78.18 63.45,78.3 63.45,78.63 63.57,78.74 63.8,78.74 63.91,78.63 63.91,78.3 64.03,78.18 64.25,78.18 64.37,78.3 64.37,78.63 64.48,78.74 64.9,78.74 66.09,77.55 67.39,77.55 67.56,77.72 69.72,77.72 70.09,77.36 70.12,77.36 70.24,77.24 70.47,77.24 70.58,77.36 70.58,77.74 70.69,77.85 70.92,77.85 71.04,77.74 71.04,77.36 71.15,77.24 71.38,77.24 71.49,77.36 71.49,77.74 71.61,77.85 71.84,77.85 71.95,77.74 71.95,77.36 72.07,77.24 72.29,77.24 72.41,77.36 72.41,77.74 72.52,77.85 72.75,77.85 72.87,77.74 72.87,77.66 72.98,77.55 73.36,77.55 73.74,77.16 74.22,77.16 74.53,77.47 75.56,77.47 75.95,77.85 78.18,77.85 78.36,77.67 78.64,77.67 78.73,77.76 78.73,77.94 78.81,78.03 79.09,78.03 79.18,77.94 79.18,77.76 79.27,77.67 79.55,77.67 79.64,77.76 79.64,77.94 79.73,78.03 80.01,78.03 80.1,77.94 80.1,77.76 80.19,77.67 80.47,77.67 80.55,77.76 80.55,77.94 80.64,78.03 80.92,78.03 81.1,77.85 83.01,77.85 83.19,78.03 83.5,78.03 83.61,77.91 83.61,77.89 83.73,77.77 83.96,77.77 84.07,77.89 84.07,78.17 84.18,78.28 84.41,78.28 84.53,78.17 84.53,77.89 84.64,77.77 84.87,77.77 84.98,77.89 84.98,78.17 85.1,78.28 85.33,78.28 85.44,78.17 85.44,77.89 85.56,77.77 85.78,77.77 85.9,77.89 85.9,78.17 86.01,78.28 86.24,78.28 86.36,78.17 86.36,77.89 86.47,77.77 86.7,77.77 86.81,77.89 86.81,78.17 86.93,78.28 87.16,78.28 87.27,78.17 87.27,77.89 87.38,77.77 87.61,77.77 87.73,77.89 87.73,78.17 87.84,78.28 88.07,78.28 88.18,78.17 88.18,78.14 88.3,78.03 88.6,78.03 88.77,77.85 90.34,77.85
DDR2_SCL: length 2.6
  TOP w0.165: J6.197 v1(62.87,105.58)
  BOTTOM w0.165: 61.85,105.79 62.65,105.79 v1(62.87,105.58)
DDR2_SDA: length 2.6
  TOP w0.165: v1(62.87,104.9) 62.94,104.98 J6.195
  BOTTOM w0.165: 61.85,104.65 62.61,104.65 v1(62.87,104.9)
DDR2_WE_N: length 82.2
  TOP w0.165: U5.AF17 98.96,77.19 v2(98.95,77.19) ; v1(66.93,79.18) J6.109 ; RN9.5 v1(52.95,81.67)
  L3-SIG1 w0.102: v2(98.95,77.19) 98.96,77.19 98.43,77.72 91.79,77.72 91.57,77.94 91.57,78.1 91.33,78.34 91.33,78.36 91.11,78.58 91.09,78.58 90.49,79.18 v2(90.42,79.18)
  L10-SIG4 w0.114: v1(66.93,79.18) 66.85,79.1 65.76,79.1 64.77,78.11 62.19,78.11 62.08,77.99 62.08,77.94 61.96,77.83 61.74,77.83 61.62,77.94 61.62,78.27 61.51,78.38 61.28,78.38 61.16,78.27 61.16,78.22 61.05,78.11 59.97,78.11 59.69,78.38 59.69,78.82 60.01,79.13 60.32,79.13 60.51,78.94 60.78,78.94 60.88,79.04 60.88,79.23 60.97,79.32 61.24,79.32 61.33,79.23 61.33,79.04 61.43,78.94 61.69,78.94 61.79,79.04 61.79,79.23 61.89,79.32 62.15,79.32 62.25,79.23 62.25,79.04 62.34,78.94 62.61,78.94 62.7,79.04 62.7,79.23 62.8,79.32 63.07,79.32 63.16,79.23 63.16,79.04 63.26,78.94 63.52,78.94 63.62,79.04 63.62,79.23 63.71,79.32 63.98,79.32 64.17,79.13 64.55,79.13 65.05,79.63 67.23,79.63 67.87,78.99 68.13,78.99 68.24,79.11 68.24,79.9 68.36,80.01 68.59,80.01 68.7,79.9 68.7,79.11 68.82,78.99 69.04,78.99 69.16,79.11 69.16,79.9 69.27,80.01 69.5,80.01 69.62,79.9 69.62,79.11 69.73,78.99 69.96,78.99 70.07,79.11 70.07,79.9 70.19,80.01 70.42,80.01 70.53,79.9 70.53,79.11 70.64,78.99 70.87,78.99 70.99,79.11 70.99,79.9 71.1,80.01 71.33,80.01 71.45,79.9 71.45,79.62 71.56,79.5 72.08,79.5 72.64,78.94 73.35,78.94 73.58,79.17 73.9,79.17 74.01,79.06 74.01,78.88 74.12,78.77 74.35,78.77 74.47,78.88 74.47,79.46 74.58,79.58 74.81,79.58 74.92,79.46 74.92,78.88 75.04,78.77 75.27,78.77 75.38,78.88 75.38,79.46 75.5,79.58 75.72,79.58 75.84,79.46 75.84,78.88 75.95,78.77 76.18,78.77 76.3,78.88 76.3,79.46 76.41,79.58 76.64,79.58 76.75,79.46 76.75,79.29 76.87,79.17 77.32,79.17 77.55,78.94 90.18,78.94 v2(90.42,79.18)
  BOTTOM w0.165: v1(52.95,81.67) 54.01,81.67 55.52,80.16 57.84,80.16 58.12,80.44 64.47,80.44 65.15,79.76 66.42,79.76 66.93,79.25 v1(66.93,79.18)
DM: length 10.7
  TOP w0.114: U3.7 183.03,130.43 183.03,138.68 ; 183.03,138.68 183.03,139.57 R1.2 ; 183.03,138.68 C12.1
DP: length 10.7
  TOP w0.114: R2.2 182.73,139.57 182.73,138.68 ; C11.1 182.73,138.68 ; 182.73,138.68 182.73,130.44 U3.8
DS3N: length 135.4
  TOP w0.114: U5.N8 v2(112.95,86.2) ; v1(202.56,98.95) 202.23,99.28 200.08,99.28 J4.22
  L9-SIG3 w0.102: v2(112.95,86.2) 112.95,86.15 113.1,86 113.1,85.7 113.02,85.61 112.87,85.61 112.57,85.92 112.57,89.36 112.58,89.37 112.58,89.39 112.8,89.61 112.8,90.88 113.57,91.65 113.57,93.38 117.97,97.77 117.97,98.63 119.95,100.62 130.46,100.62 133.48,103.63 135.41,103.63 135.51,103.53 135.51,103.52 135.78,103.25 136.21,103.25 136.48,103.52 136.48,103.91 136.58,104.01 136.78,104.01 136.88,103.91 136.88,103.52 137.15,103.25 137.58,103.25 137.85,103.52 137.85,103.91 137.95,104.01 138.15,104.01 138.25,103.91 138.25,103.52 138.52,103.25 138.95,103.25 139.22,103.52 139.22,103.91 139.32,104.01 139.52,104.01 139.63,103.91 139.63,103.52 139.89,103.25 140.33,103.25 140.59,103.52 140.59,103.91 140.69,104.01 140.9,104.01 141,103.91 141,103.52 141.26,103.25 141.7,103.25 141.96,103.52 141.96,103.91 142.06,104.01 142.27,104.01 142.37,103.91 142.37,103.52 142.63,103.25 143.07,103.25 143.33,103.52 143.33,103.91 143.44,104.01 143.64,104.01 143.74,103.91 143.74,103.52 144.01,103.25 144.44,103.25 144.71,103.52 144.71,103.91 144.81,104.01 145.01,104.01 145.11,103.91 145.11,103.52 145.38,103.25 145.81,103.25 146.08,103.52 146.08,103.91 146.18,104.01 146.38,104.01 146.48,103.91 146.48,103.52 146.75,103.25 147.18,103.25 147.45,103.52 147.45,103.91 147.55,104.01 147.75,104.01 147.85,103.91 147.85,103.52 148.12,103.25 148.55,103.25 148.82,103.52 148.82,103.91 148.92,104.01 149.12,104.01 149.23,103.91 149.23,103.52 149.49,103.25 149.93,103.25 150.19,103.52 150.19,103.91 150.29,104.01 150.5,104.01 150.6,103.91 150.6,103.52 150.86,103.25 151.3,103.25 151.56,103.52 151.56,103.91 151.66,104.01 151.87,104.01 151.97,103.91 151.97,103.52 152.23,103.25 152.67,103.25 152.93,103.52 152.93,103.91 153.04,104.01 153.24,104.01 153.34,103.91 153.34,103.52 153.61,103.25 154.04,103.25 154.31,103.52 154.31,103.91 154.41,104.01 154.61,104.01 154.71,103.91 154.71,103.52 154.98,103.25 155.41,103.25 155.68,103.52 155.68,103.91 155.78,104.01 155.98,104.01 156.08,103.91 156.08,103.52 156.35,103.25 156.78,103.25 157.05,103.52 157.05,103.91 157.15,104.01 157.35,104.01 157.46,103.91 157.46,103.52 157.72,103.25 158.16,103.25 158.42,103.52 158.42,103.91 158.52,104.01 158.73,104.01 158.83,103.91 158.83,103.52 159.09,103.25 159.53,103.25 159.79,103.52 159.79,103.91 159.89,104.01 160.1,104.01 160.2,103.91 160.2,103.52 160.46,103.25 160.9,103.25 161.16,103.52 161.16,103.91 161.27,104.01 161.47,104.01 161.57,103.91 161.57,103.52 161.84,103.25 162.27,103.25 162.54,103.52 162.54,103.91 162.64,104.01 162.84,104.01 162.94,103.91 162.94,103.52 163.21,103.25 163.64,103.25 163.91,103.52 163.91,103.91 164.01,104.01 164.21,104.01 164.31,103.91 164.31,103.52 164.58,103.25 165.01,103.25 165.28,103.52 165.28,103.91 165.38,104.01 165.58,104.01 165.69,103.91 165.69,103.9 165.95,103.63 170.93,103.63 174.74,107.44 189.75,107.44 193.56,103.63 195.57,103.63 199.96,99.24 202.4,99.24 202.56,99.08 v1(202.56,98.95)
DS3P: length 135.5
  TOP w0.114: U5.N9 v2(112.95,85.2) ; v1(202.56,99.77) 202.35,99.56 200.08,99.56 J4.20
  L9-SIG3 w0.102: v1(202.56,99.77) 202.51,99.72 202.51,99.62 202.41,99.52 200.08,99.52 195.68,103.91 193.68,103.91 189.87,107.72 174.62,107.72 170.81,103.91 166.07,103.91 165.96,104.01 165.96,104.03 165.7,104.29 165.26,104.29 165,104.03 165,103.63 164.9,103.53 164.69,103.53 164.59,103.63 164.59,104.03 164.33,104.29 163.89,104.29 163.63,104.03 163.63,103.63 163.53,103.53 163.32,103.53 163.22,103.63 163.22,104.03 162.96,104.29 162.52,104.29 162.26,104.03 162.26,103.63 162.15,103.53 161.95,103.53 161.85,103.63 161.85,104.03 161.58,104.29 161.15,104.29 160.88,104.03 160.88,103.63 160.78,103.53 160.58,103.53 160.48,103.63 160.48,104.03 160.21,104.29 159.78,104.29 159.51,104.03 159.51,103.63 159.41,103.53 159.21,103.53 159.11,103.63 159.11,104.03 158.84,104.29 158.41,104.29 158.14,104.03 158.14,103.63 158.04,103.53 157.84,103.53 157.74,103.63 157.74,104.03 157.47,104.29 157.04,104.29 156.77,104.03 156.77,103.63 156.67,103.53 156.47,103.53 156.36,103.63 156.36,104.03 156.1,104.29 155.66,104.29 155.4,104.03 155.4,103.63 155.3,103.53 155.09,103.53 154.99,103.63 154.99,104.03 154.73,104.29 154.29,104.29 154.03,104.03 154.03,103.63 153.93,103.53 153.72,103.53 153.62,103.63 153.62,104.03 153.36,104.29 152.92,104.29 152.66,104.03 152.66,103.63 152.55,103.53 152.35,103.53 152.25,103.63 152.25,104.03 151.98,104.29 151.55,104.29 151.28,104.03 151.28,103.63 151.18,103.53 150.98,103.53 150.88,103.63 150.88,104.03 150.61,104.29 150.18,104.29 149.91,104.03 149.91,103.63 149.81,103.53 149.61,103.53 149.51,103.63 149.51,104.03 149.24,104.29 148.81,104.29 148.54,104.03 148.54,103.63 148.44,103.53 148.24,103.53 148.13,103.63 148.13,104.03 147.87,104.29 147.43,104.29 147.17,104.03 147.17,103.63 147.07,103.53 146.86,103.53 146.76,103.63 146.76,104.03 146.5,104.29 146.06,104.29 145.8,104.03 145.8,103.63 145.7,103.53 145.49,103.53 145.39,103.63 145.39,104.03 145.13,104.29 144.69,104.29 144.43,104.03 144.43,103.63 144.32,103.53 144.12,103.53 144.02,103.63 144.02,104.03 143.75,104.29 143.32,104.29 143.05,104.03 143.05,103.63 142.95,103.53 142.75,103.53 142.65,103.63 142.65,104.03 142.38,104.29 141.95,104.29 141.68,104.03 141.68,103.63 141.58,103.53 141.38,103.53 141.28,103.63 141.28,104.03 141.01,104.29 140.58,104.29 140.31,104.03 140.31,103.63 140.21,103.53 140.01,103.53 139.9,103.63 139.9,104.03 139.64,104.29 139.2,104.29 138.94,104.03 138.94,103.63 138.84,103.53 138.63,103.53 138.53,103.63 138.53,104.03 138.27,104.29 137.83,104.29 137.57,104.03 137.57,103.63 137.47,103.53 137.26,103.53 137.16,103.63 137.16,104.03 136.9,104.29 136.46,104.29 136.2,104.03 136.2,103.63 136.09,103.53 135.89,103.53 135.79,103.63 135.79,103.65 135.52,103.91 133.36,103.91 130.35,100.9 119.84,100.9 117.69,98.75 117.69,97.89 113.33,93.53 113.33,91.82 112.52,91.01 112.52,89.74 112.39,89.6 112.33,89.53 112.33,85.82 v2(112.95,85.2)
DS5N: length 135.5
  TOP w0.114: U5.M10 v2(113.95,84.2) ; v1(202.56,95.97) 202.26,96.28 200.08,96.28 J4.34
  L9-SIG3 w0.102: v2(113.95,84.2) 114.35,83.8 114.35,82.87 114.64,82.58 118.42,82.58 120.57,84.75 120.57,85.36 120.6,85.39 120.6,85.59 121.07,86.06 121.83,86.06 122.57,86.81 122.57,87.36 122.79,87.58 123.86,87.58 124.42,88.14 126.47,88.14 126.87,87.73 127.75,87.73 137.78,97.76 138.71,97.76 139.25,97.22 139.25,97.04 139.52,96.77 139.95,96.77 140.22,97.04 140.22,97.41 140.32,97.51 140.52,97.51 140.62,97.41 140.62,97.04 140.89,96.77 141.32,96.77 141.59,97.04 141.59,97.41 141.69,97.51 141.89,97.51 141.99,97.41 141.99,97.04 142.26,96.77 142.69,96.77 142.96,97.04 142.96,97.41 143.06,97.51 143.26,97.51 143.37,97.41 143.37,97.04 143.63,96.77 144.07,96.77 144.33,97.04 144.33,97.41 144.43,97.51 144.64,97.51 144.74,97.41 144.74,97.04 145,96.77 145.44,96.77 145.7,97.04 145.7,97.41 145.8,97.51 146.01,97.51 146.11,97.41 146.11,97.04 146.37,96.77 146.81,96.77 147.07,97.04 147.07,97.41 147.18,97.51 147.38,97.51 147.48,97.41 147.48,97.04 147.75,96.77 148.18,96.77 148.45,97.04 148.45,97.41 148.55,97.51 148.75,97.51 148.85,97.41 148.85,97.04 149.12,96.77 149.55,96.77 149.82,97.04 149.82,97.41 149.92,97.51 150.12,97.51 150.22,97.41 150.22,97.04 150.49,96.77 150.92,96.77 151.19,97.04 151.19,97.41 151.29,97.51 151.49,97.51 151.6,97.41 151.6,97.04 151.86,96.77 152.3,96.77 152.56,97.04 152.56,97.41 152.66,97.51 152.87,97.51 152.97,97.41 152.97,97.04 153.23,96.77 153.67,96.77 153.93,97.04 153.93,97.41 154.03,97.51 154.24,97.51 154.34,97.41 154.34,97.04 154.6,96.77 155.04,96.77 155.3,97.04 155.3,97.41 155.41,97.51 155.61,97.51 155.71,97.41 155.71,97.04 155.98,96.77 156.41,96.77 156.68,97.04 156.68,97.41 156.78,97.51 156.98,97.51 157.08,97.41 157.08,97.04 157.35,96.77 157.78,96.77 158.05,97.04 158.05,97.41 158.15,97.51 158.35,97.51 158.45,97.41 158.45,97.04 158.72,96.77 159.15,96.77 159.42,97.04 159.42,97.41 159.52,97.51 159.72,97.51 159.83,97.41 159.83,97.04 160.09,96.77 160.53,96.77 160.79,97.04 160.79,97.41 160.89,97.51 161.1,97.51 161.2,97.41 161.2,97.04 161.46,96.77 161.9,96.77 162.16,97.04 162.16,97.41 162.26,97.51 162.47,97.51 162.57,97.41 162.57,97.04 162.83,96.77 163.27,96.77 163.53,97.04 163.53,97.41 163.64,97.51 163.84,97.51 163.94,97.41 163.94,97.04 164.21,96.77 164.64,96.77 164.91,97.04 164.91,97.41 165.01,97.51 165.21,97.51 165.31,97.41 165.31,97.04 165.58,96.77 166.01,96.77 166.28,97.04 166.28,97.41 166.38,97.51 166.58,97.51 166.68,97.41 166.68,97.04 166.95,96.77 167.38,96.77 167.65,97.04 167.65,97.41 167.75,97.51 167.95,97.51 168.05,97.41 168.05,97.04 168.32,96.77 168.75,96.77 169.02,97.04 169.02,97.41 169.12,97.51 169.32,97.51 169.43,97.41 169.43,97.04 169.69,96.77 170.13,96.77 170.39,97.04 170.39,97.41 170.49,97.51 170.7,97.51 170.8,97.41 170.8,97.04 171.06,96.77 171.5,96.77 171.76,97.04 171.76,97.41 171.86,97.51 172.07,97.51 172.17,97.41 172.17,97.04 172.43,96.77 172.87,96.77 173.13,97.04 173.13,97.41 173.24,97.51 173.44,97.51 173.54,97.41 173.54,97.04 173.81,96.77 174.24,96.77 174.51,97.04 174.51,97.41 174.61,97.51 174.81,97.51 174.91,97.41 174.91,97.04 175.18,96.77 175.61,96.77 175.88,97.04 175.88,97.41 175.98,97.51 176.18,97.51 176.28,97.41 176.28,97.04 176.55,96.77 176.98,96.77 177.25,97.04 177.25,97.41 177.35,97.51 177.55,97.51 177.66,97.41 177.66,97.04 177.92,96.77 178.36,96.77 178.62,97.04 178.62,97.41 178.72,97.51 178.93,97.51 179.03,97.41 179.03,97.04 179.29,96.77 179.73,96.77 179.99,97.04 179.99,97.41 180.09,97.51 180.3,97.51 180.4,97.41 180.4,97.04 180.66,96.77 181.1,96.77 181.36,97.04 181.36,97.41 181.47,97.51 188.85,97.51 191.01,99.67 194.65,99.67 198.08,96.24 202.29,96.24 v1(202.56,95.97)
DS5P: length 135.4
  TOP w0.114: J4.32 200.08,96.56 202.33,96.56 v1(202.56,96.79) ; U5.L11 v2(114.95,83.2)
  L9-SIG3 w0.102: v1(202.56,96.79) 202.29,96.52 198.19,96.52 194.76,99.95 190.89,99.95 188.73,97.79 181.35,97.79 181.09,97.52 181.09,97.16 180.98,97.05 180.78,97.05 180.68,97.16 180.68,97.52 180.41,97.79 179.98,97.79 179.71,97.52 179.71,97.16 179.61,97.05 179.41,97.05 179.31,97.16 179.31,97.52 179.04,97.79 178.61,97.79 178.34,97.52 178.34,97.16 178.24,97.05 178.04,97.05 177.94,97.16 177.94,97.52 177.67,97.79 177.24,97.79 176.97,97.52 176.97,97.16 176.87,97.05 176.67,97.05 176.56,97.16 176.56,97.52 176.3,97.79 175.86,97.79 175.6,97.52 175.6,97.16 175.5,97.05 175.29,97.05 175.19,97.16 175.19,97.52 174.93,97.79 174.49,97.79 174.23,97.52 174.23,97.16 174.13,97.05 173.92,97.05 173.82,97.16 173.82,97.52 173.56,97.79 173.12,97.79 172.86,97.52 172.86,97.16 172.75,97.05 172.55,97.05 172.45,97.16 172.45,97.52 172.18,97.79 171.75,97.79 171.48,97.52 171.48,97.16 171.38,97.05 171.18,97.05 171.08,97.16 171.08,97.52 170.81,97.79 170.38,97.79 170.11,97.52 170.11,97.16 170.01,97.05 169.81,97.05 169.71,97.16 169.71,97.52 169.44,97.79 169.01,97.79 168.74,97.52 168.74,97.16 168.64,97.05 168.44,97.05 168.33,97.16 168.33,97.52 168.07,97.79 167.63,97.79 167.37,97.52 167.37,97.16 167.27,97.05 167.06,97.05 166.96,97.16 166.96,97.52 166.7,97.79 166.26,97.79 166,97.52 166,97.16 165.9,97.05 165.69,97.05 165.59,97.16 165.59,97.52 165.33,97.79 164.89,97.79 164.63,97.52 164.63,97.16 164.52,97.05 164.32,97.05 164.22,97.16 164.22,97.52 163.95,97.79 163.52,97.79 163.25,97.52 163.25,97.16 163.15,97.05 162.95,97.05 162.85,97.16 162.85,97.52 162.58,97.79 162.15,97.79 161.88,97.52 161.88,97.16 161.78,97.05 161.58,97.05 161.48,97.16 161.48,97.52 161.21,97.79 160.78,97.79 160.51,97.52 160.51,97.16 160.41,97.05 160.21,97.05 160.1,97.16 160.1,97.52 159.84,97.79 159.4,97.79 159.14,97.52 159.14,97.16 159.04,97.05 158.83,97.05 158.73,97.16 158.73,97.52 158.47,97.79 158.03,97.79 157.77,97.52 157.77,97.16 157.67,97.05 157.46,97.05 157.36,97.16 157.36,97.52 157.1,97.79 156.66,97.79 156.4,97.52 156.4,97.16 156.29,97.05 156.09,97.05 155.99,97.16 155.99,97.52 155.72,97.79 155.29,97.79 155.02,97.52 155.02,97.16 154.92,97.05 154.72,97.05 154.62,97.16 154.62,97.52 154.35,97.79 153.92,97.79 153.65,97.52 153.65,97.16 153.55,97.05 153.35,97.05 153.25,97.16 153.25,97.52 152.98,97.79 152.55,97.79 152.28,97.52 152.28,97.16 152.18,97.05 151.98,97.05 151.88,97.16 151.88,97.52 151.61,97.79 151.18,97.79 150.91,97.52 150.91,97.16 150.81,97.05 150.61,97.05 150.5,97.16 150.5,97.52 150.24,97.79 149.8,97.79 149.54,97.52 149.54,97.16 149.44,97.05 149.23,97.05 149.13,97.16 149.13,97.52 148.87,97.79 148.43,97.79 148.17,97.52 148.17,97.16 148.07,97.05 147.86,97.05 147.76,97.16 147.76,97.52 147.5,97.79 147.06,97.79 146.8,97.52 146.8,97.16 146.69,97.05 146.49,97.05 146.39,97.16 146.39,97.52 146.12,97.79 145.69,97.79 145.42,97.52 145.42,97.16 145.32,97.05 145.12,97.05 145.02,97.16 145.02,97.52 144.75,97.79 144.32,97.79 144.05,97.52 144.05,97.16 143.95,97.05 143.75,97.05 143.65,97.16 143.65,97.52 143.38,97.79 142.95,97.79 142.68,97.52 142.68,97.16 142.58,97.05 142.38,97.05 142.27,97.16 142.27,97.52 142.01,97.79 141.57,97.79 141.31,97.52 141.31,97.16 141.21,97.05 141,97.05 140.9,97.16 140.9,97.52 140.64,97.79 140.2,97.79 139.94,97.52 139.94,97.16 139.84,97.05 139.63,97.05 139.53,97.16 139.53,97.34 138.83,98.04 137.67,98.04 127.64,88.01 126.99,88.01 126.58,88.42 125.23,88.42 125.19,88.38 124.32,88.38 123.76,87.82 122.69,87.82 122.33,87.46 122.33,86.9 121.73,86.3 120.97,86.3 120.36,85.69 120.36,85.49 120.33,85.46 120.33,84.85 118.3,82.82 115.24,82.82 115.24,82.82 114.74,82.82 114.59,82.97 114.59,83.53 114.75,83.69 115.01,83.69 115.15,83.56 115.15,83.39 114.95,83.19 114.95,83.2 v2(114.95,83.2)
EEDATA: length 6.7
  TOP w0.178: U3.61 191.04,126.96 192.28,125.73 R8.1 192.53,125.73 192.79,125.98 U4.3
EN1: length 152.5
  TOP w0.178: R157.1 v1(13.72,138.81) ; R117.2 v1(10.67,79.38) ; v1(10.67,53.11) 10.64,53.09 R123.2 ; R119.2 v1(10.67,117.22) ; U14.7 v1(39.24,18.41)
  L3-SIG1 w0.178: v1(13.72,138.81) 10.67,135.76 v1(10.67,117.22) 10.67,113.67 16.51,107.82 16.51,88.01 10.67,82.17 v1(10.67,79.38) 10.67,77.22 13.34,74.55 13.34,69.72 10.67,67.06 v1(10.67,53.11) 10.67,50.55 14.86,46.35 14.86,30.48 28.57,16.76 37.97,16.76 38.48,17.27 38.48,17.65 39.24,18.41 v1(39.24,18.41)
EN2: length 108.2
  TOP w0.178: U1.7 v1(32.26,18.41) ; R122.2 v1(36.58,119.25)
  L3-SIG1 w0.178: v1(36.58,119.25) 37.59,119.25 41.02,115.82 41.02,94.61 38.48,92.08 38.48,28.83 34.04,24.38 34.04,20.19 32.26,18.41 v1(32.26,18.41)
EN3: length 109.2
  TOP w0.178: U1.5 v1(32.26,17.41) ; R121.2 v1(34.7,120.52)
  L3-SIG1 w0.178: v1(34.7,120.52) 34.67,120.52 32.77,118.62 32.77,95.63 36.2,92.2 36.2,73.03 34.29,71.12 34.29,29.84 31.11,26.67 31.11,18.53 32.23,17.41 v1(32.26,17.41)
EN4: length 66
  TOP w0.178: U1.2 v1(30.48,18.41) ; R118.2 v1(34.92,80.39)
  L3-SIG1 w0.178: v1(34.92,80.39) 34.92,77.47 30.48,73.03 30.48,30.61 29.34,29.46 29.34,19.55 v1(30.48,18.41)
EN5: length 117.4
  TOP w0.178: v1(65.91,122.05) 66.4,122.05 R115.2 ; U14.5 v1(39.24,17.41)
  L3-SIG1 w0.178: v1(39.24,17.41) 39.89,17.41 45.21,22.73 45.21,56.64 51.56,62.99 51.56,104.52 65.91,118.87 v1(65.91,122.05)
EN6: length 117.7
  TOP w0.178: U14.2 v1(37.46,18.41) ; R124.2 v1(62.87,122.17)
  L3-SIG1 w0.178: v1(62.87,122.17) 61.59,120.9 57.91,120.9 47.75,110.74 47.75,88.65 42.16,83.06 42.16,26.67 37.47,21.97 37.47,19.56 v1(37.46,18.41)
EXT_TRG_INPUT: length 121.3
  TOP w0.165: U5.G20 v2(118.95,73.2)
  L3-SIG1 w0.102: 125.35,70.9 125.35,71.5 124.21,72.64 119.51,72.64 v2(118.95,73.2)
  L3-SIG1 w0.114: 125.35,70.9 126.02,70.23 126.02,69.68 126.87,68.83 127.33,68.83 128.4,67.77 128.4,66.04 130.68,63.75 130.68,57.78 129.41,56.52 129.41,54.36 132.33,51.44 150.37,51.44 153.8,48.01 155.02,48.01 155.13,47.89 155.13,47.36 155.25,47.24 155.48,47.24 155.59,47.36 155.59,48.65 155.7,48.77 155.93,48.77 156.05,48.65 156.05,47.36 156.16,47.24 156.39,47.24 156.5,47.36 156.5,48.65 156.62,48.77 156.85,48.77 156.96,48.65 156.96,47.36 157.08,47.24 157.3,47.24 157.42,47.36 157.42,48.65 157.53,48.77 157.76,48.77 157.88,48.65 157.88,47.36 157.99,47.24 158.22,47.24 158.33,47.36 158.33,48.65 158.45,48.77 158.68,48.77 158.79,48.65 158.79,47.36 158.91,47.24 159.13,47.24 159.25,47.36 159.25,48.65 159.36,48.77 159.59,48.77 159.71,48.65 159.71,47.36 159.82,47.24 160.05,47.24 160.16,47.36 160.16,48.65 160.28,48.77 160.51,48.77 160.62,48.65 160.62,47.36 160.73,47.24 160.96,47.24 161.08,47.36 161.08,48.65 161.19,48.77 161.42,48.77 161.53,48.65 161.53,47.36 161.65,47.24 161.88,47.24 161.99,47.36 161.99,48.65 162.11,48.77 162.33,48.77 162.45,48.65 162.45,47.36 162.56,47.24 162.79,47.24 162.91,47.36 162.91,48.65 163.02,48.77 163.25,48.77 163.36,48.65 163.36,47.36 163.48,47.24 163.71,47.24 163.82,47.36 163.82,48.65 163.93,48.77 164.16,48.77 164.28,48.65 164.28,47.36 164.39,47.24 164.62,47.24 164.73,47.36 164.73,48.65 164.85,48.77 165.08,48.77 165.19,48.65 165.19,48.12 165.31,48.01 172.21,48.01 173.48,46.74 173.48,42.16 172.34,41.02 J11.1
FCLK_M: length 118.6
  TOP w0.114: U5.AC6 v2(101.95,88.2)
  L3-SIG1 w0.102: v2(101.95,88.2) 101.95,88.12 102.49,87.58 103.25,87.58 103.56,87.89 103.56,88.47 103.57,88.48 103.57,94.07 103.61,94.11 103.61,94.55 104.06,95.01 104.06,96.47 106.1,98.5 106.1,99.74 106.2,99.84 106.97,99.84 107.24,100.11 107.24,100.54 106.97,100.81 106.2,100.81 106.1,100.91 106.1,101.11 106.2,101.22 106.97,101.22 107.24,101.48 107.24,101.92 106.97,102.18 106.2,102.18 106.1,102.28 106.1,102.49 106.2,102.59 106.97,102.59 107.24,102.85 107.24,103.29 106.97,103.55 106.2,103.55 106.1,103.65 106.1,103.86 106.2,103.96 106.97,103.96 107.24,104.22 107.24,104.66 106.97,104.92 106.2,104.92 106.1,105.03 106.1,105.23 106.2,105.33 106.97,105.33 107.24,105.6 107.24,106.03 106.97,106.3 106.2,106.3 106.1,106.4 106.1,106.6 106.2,106.7 106.97,106.7 107.24,106.97 107.24,107.4 106.97,107.67 106.2,107.67 106.1,107.77 106.1,107.97 106.2,108.07 106.97,108.07 107.24,108.34 107.24,108.77 106.97,109.04 106.2,109.04 106.1,109.14 106.1,109.34 106.2,109.45 106.97,109.45 107.24,109.71 107.24,110.15 106.97,110.41 106.2,110.41 106.1,110.51 106.1,110.72 106.2,110.82 106.97,110.82 107.24,111.08 107.24,111.52 106.97,111.78 106.2,111.78 106.1,111.88 106.1,112.09 106.2,112.19 106.97,112.19 107.24,112.45 107.24,112.89 106.97,113.15 106.2,113.15 106.1,113.26 106.1,113.46 106.2,113.56 106.97,113.56 107.24,113.83 107.24,114.26 106.97,114.53 106.2,114.53 106.1,114.63 106.1,114.83 106.2,114.93 106.97,114.93 107.24,115.2 107.24,115.63 106.97,115.9 106.2,115.9 106.1,116 106.1,116.2 106.2,116.3 106.97,116.3 107.24,116.57 107.24,117 106.97,117.27 106.2,117.27 106.1,117.37 106.1,117.57 106.2,117.67 106.97,117.67 107.24,117.94 107.24,118.37 106.97,118.64 106.2,118.64 106.1,118.74 106.1,118.94 106.2,119.05 106.97,119.05 107.24,119.31 107.24,119.75 106.97,120.01 106.2,120.01 106.1,120.11 106.1,120.32 106.2,120.42 106.97,120.42 107.24,120.68 107.24,121.12 106.97,121.38 106.2,121.38 106.1,121.48 106.1,121.69 106.2,121.79 106.97,121.79 107.24,122.05 107.24,122.49 106.97,122.75 106.2,122.75 106.1,122.86 106.1,123.06 106.2,123.16 106.97,123.16 107.24,123.43 107.24,123.86 106.97,124.13 106.2,124.13 106.1,124.23 106.1,124.43 106.2,124.53 106.97,124.53 107.24,124.8 107.24,125.23 106.97,125.5 106.2,125.5 106.1,125.6 106.1,125.8 106.2,125.9 106.97,125.9 107.24,126.17 107.24,126.6 106.97,126.87 106.2,126.87 106.1,126.97 106.1,127.17 106.2,127.28 106.97,127.28 107.24,127.54 107.24,127.98 106.97,128.24 106.2,128.24 106.1,128.34 106.1,128.55 106.2,128.65 106.97,128.65 107.24,128.91 107.24,129.35 106.97,129.61 106.2,129.61 106.1,129.71 106.1,129.92 106.2,130.02 106.97,130.02 107.24,130.28 107.24,130.72 106.97,130.98 106.2,130.98 106.1,131.09 106.1,131.29 106.2,131.39 106.97,131.39 107.24,131.66 107.24,132.09 106.97,132.36 106.2,132.36 106.1,132.46 106.1,132.66 106.2,132.76 106.97,132.76 107.24,133.03 107.24,133.46 106.97,133.73 106.2,133.73 106.1,133.83 106.1,134.03 106.2,134.13 106.97,134.13 107.24,134.4 107.24,134.83 106.97,135.1 106.2,135.1 106.1,135.2 106.1,135.4 106.2,135.51 106.97,135.51 107.24,135.77 107.24,136.21 106.97,136.47 106.2,136.47 106.1,136.57 106.1,136.78 106.2,136.88 106.97,136.88 107.24,137.14 107.24,137.58 106.97,137.84 106.25,137.84 106.1,138 106.1,140.35 105.51,140.93 105.51,144.25 104.53,145.23 104.53,147.77 v1(104.58,147.83)
  BOTTOM w0.114: J3.64 104.38,149.87 104.38,148.03 v1(104.58,147.83)
FCLK_P: length 118.4
  TOP w0.114: U5.AB6 v2(102.95,88.2)
  L3-SIG1 w0.102: v2(102.95,88.2) 103,88.25 103,88.44 102.9,88.54 102.62,88.54 102.44,88.37 102.44,88.01 102.63,87.82 103.15,87.82 103.32,87.99 103.32,88.57 103.33,88.58 103.33,94.67 103.78,95.12 103.78,96.58 105.82,98.62 105.82,99.86 106.08,100.12 106.86,100.12 106.96,100.23 106.96,100.43 106.86,100.53 106.08,100.53 105.82,100.8 105.82,101.23 106.08,101.5 106.86,101.5 106.96,101.6 106.96,101.8 106.86,101.9 106.08,101.9 105.82,102.17 105.82,102.6 106.08,102.87 106.86,102.87 106.96,102.97 106.96,103.17 106.86,103.27 106.08,103.27 105.82,103.54 105.82,103.97 106.08,104.24 106.86,104.24 106.96,104.34 106.96,104.54 106.86,104.64 106.08,104.64 105.82,104.91 105.82,105.34 106.08,105.61 106.86,105.61 106.96,105.71 106.96,105.91 106.86,106.02 106.08,106.02 105.82,106.28 105.82,106.72 106.08,106.98 106.86,106.98 106.96,107.08 106.96,107.29 106.86,107.39 106.08,107.39 105.82,107.65 105.82,108.09 106.08,108.35 106.86,108.35 106.96,108.45 106.96,108.66 106.86,108.76 106.08,108.76 105.82,109.02 105.82,109.46 106.08,109.72 106.86,109.72 106.96,109.83 106.96,110.03 106.86,110.13 106.08,110.13 105.82,110.4 105.82,110.83 106.08,111.1 106.86,111.1 106.96,111.2 106.96,111.4 106.86,111.5 106.08,111.5 105.82,111.77 105.82,112.2 106.08,112.47 106.86,112.47 106.96,112.57 106.96,112.77 106.86,112.87 106.08,112.87 105.82,113.14 105.82,113.57 106.08,113.84 106.86,113.84 106.96,113.94 106.96,114.14 106.86,114.25 106.08,114.25 105.82,114.51 105.82,114.95 106.08,115.21 106.86,115.21 106.96,115.31 106.96,115.52 106.86,115.62 106.08,115.62 105.82,115.88 105.82,116.32 106.08,116.58 106.86,116.58 106.96,116.68 106.96,116.89 106.86,116.99 106.08,116.99 105.82,117.25 105.82,117.69 106.08,117.95 106.86,117.95 106.96,118.06 106.96,118.26 106.86,118.36 106.08,118.36 105.82,118.63 105.82,119.06 106.08,119.33 106.86,119.33 106.96,119.43 106.96,119.63 106.86,119.73 106.08,119.73 105.82,120 105.82,120.43 106.08,120.7 106.86,120.7 106.96,120.8 106.96,121 106.86,121.1 106.08,121.1 105.82,121.37 105.82,121.8 106.08,122.07 106.86,122.07 106.96,122.17 106.96,122.37 106.86,122.48 106.08,122.48 105.82,122.74 105.82,123.18 106.08,123.44 106.86,123.44 106.96,123.54 106.96,123.75 106.86,123.85 106.08,123.85 105.82,124.11 105.82,124.55 106.08,124.81 106.86,124.81 106.96,124.91 106.96,125.12 106.86,125.22 106.08,125.22 105.82,125.48 105.82,125.92 106.08,126.18 106.86,126.18 106.96,126.29 106.96,126.49 106.86,126.59 106.08,126.59 105.82,126.86 105.82,127.29 106.08,127.56 106.86,127.56 106.96,127.66 106.96,127.86 106.86,127.96 106.08,127.96 105.82,128.23 105.82,128.66 106.08,128.93 106.86,128.93 106.96,129.03 106.96,129.23 106.86,129.33 106.08,129.33 105.82,129.6 105.82,130.03 106.08,130.3 106.86,130.3 106.96,130.4 106.96,130.6 106.86,130.71 106.08,130.71 105.82,130.97 105.82,131.41 106.08,131.67 106.86,131.67 106.96,131.77 106.96,131.98 106.86,132.08 106.08,132.08 105.82,132.34 105.82,132.78 106.08,133.04 106.86,133.04 106.96,133.14 106.96,133.35 106.86,133.45 106.08,133.45 105.82,133.71 105.82,134.15 106.08,134.41 106.86,134.41 106.96,134.52 106.96,134.72 106.86,134.82 106.08,134.82 105.82,135.09 105.82,135.52 106.08,135.79 106.86,135.79 106.96,135.89 106.96,136.09 106.86,136.19 106.08,136.19 105.82,136.46 105.82,136.89 106.08,137.16 106.55,137.16 106.71,137.31 106.71,137.41 106.55,137.56 106.08,137.56 105.82,137.83 105.82,140.23 105.23,140.82 105.23,144.13 104.25,145.12 104.25,147.4 v1(103.82,147.83)
  BOTTOM w0.114: v1(103.82,147.83) 104.09,148.1 104.09,149.79 J3.66
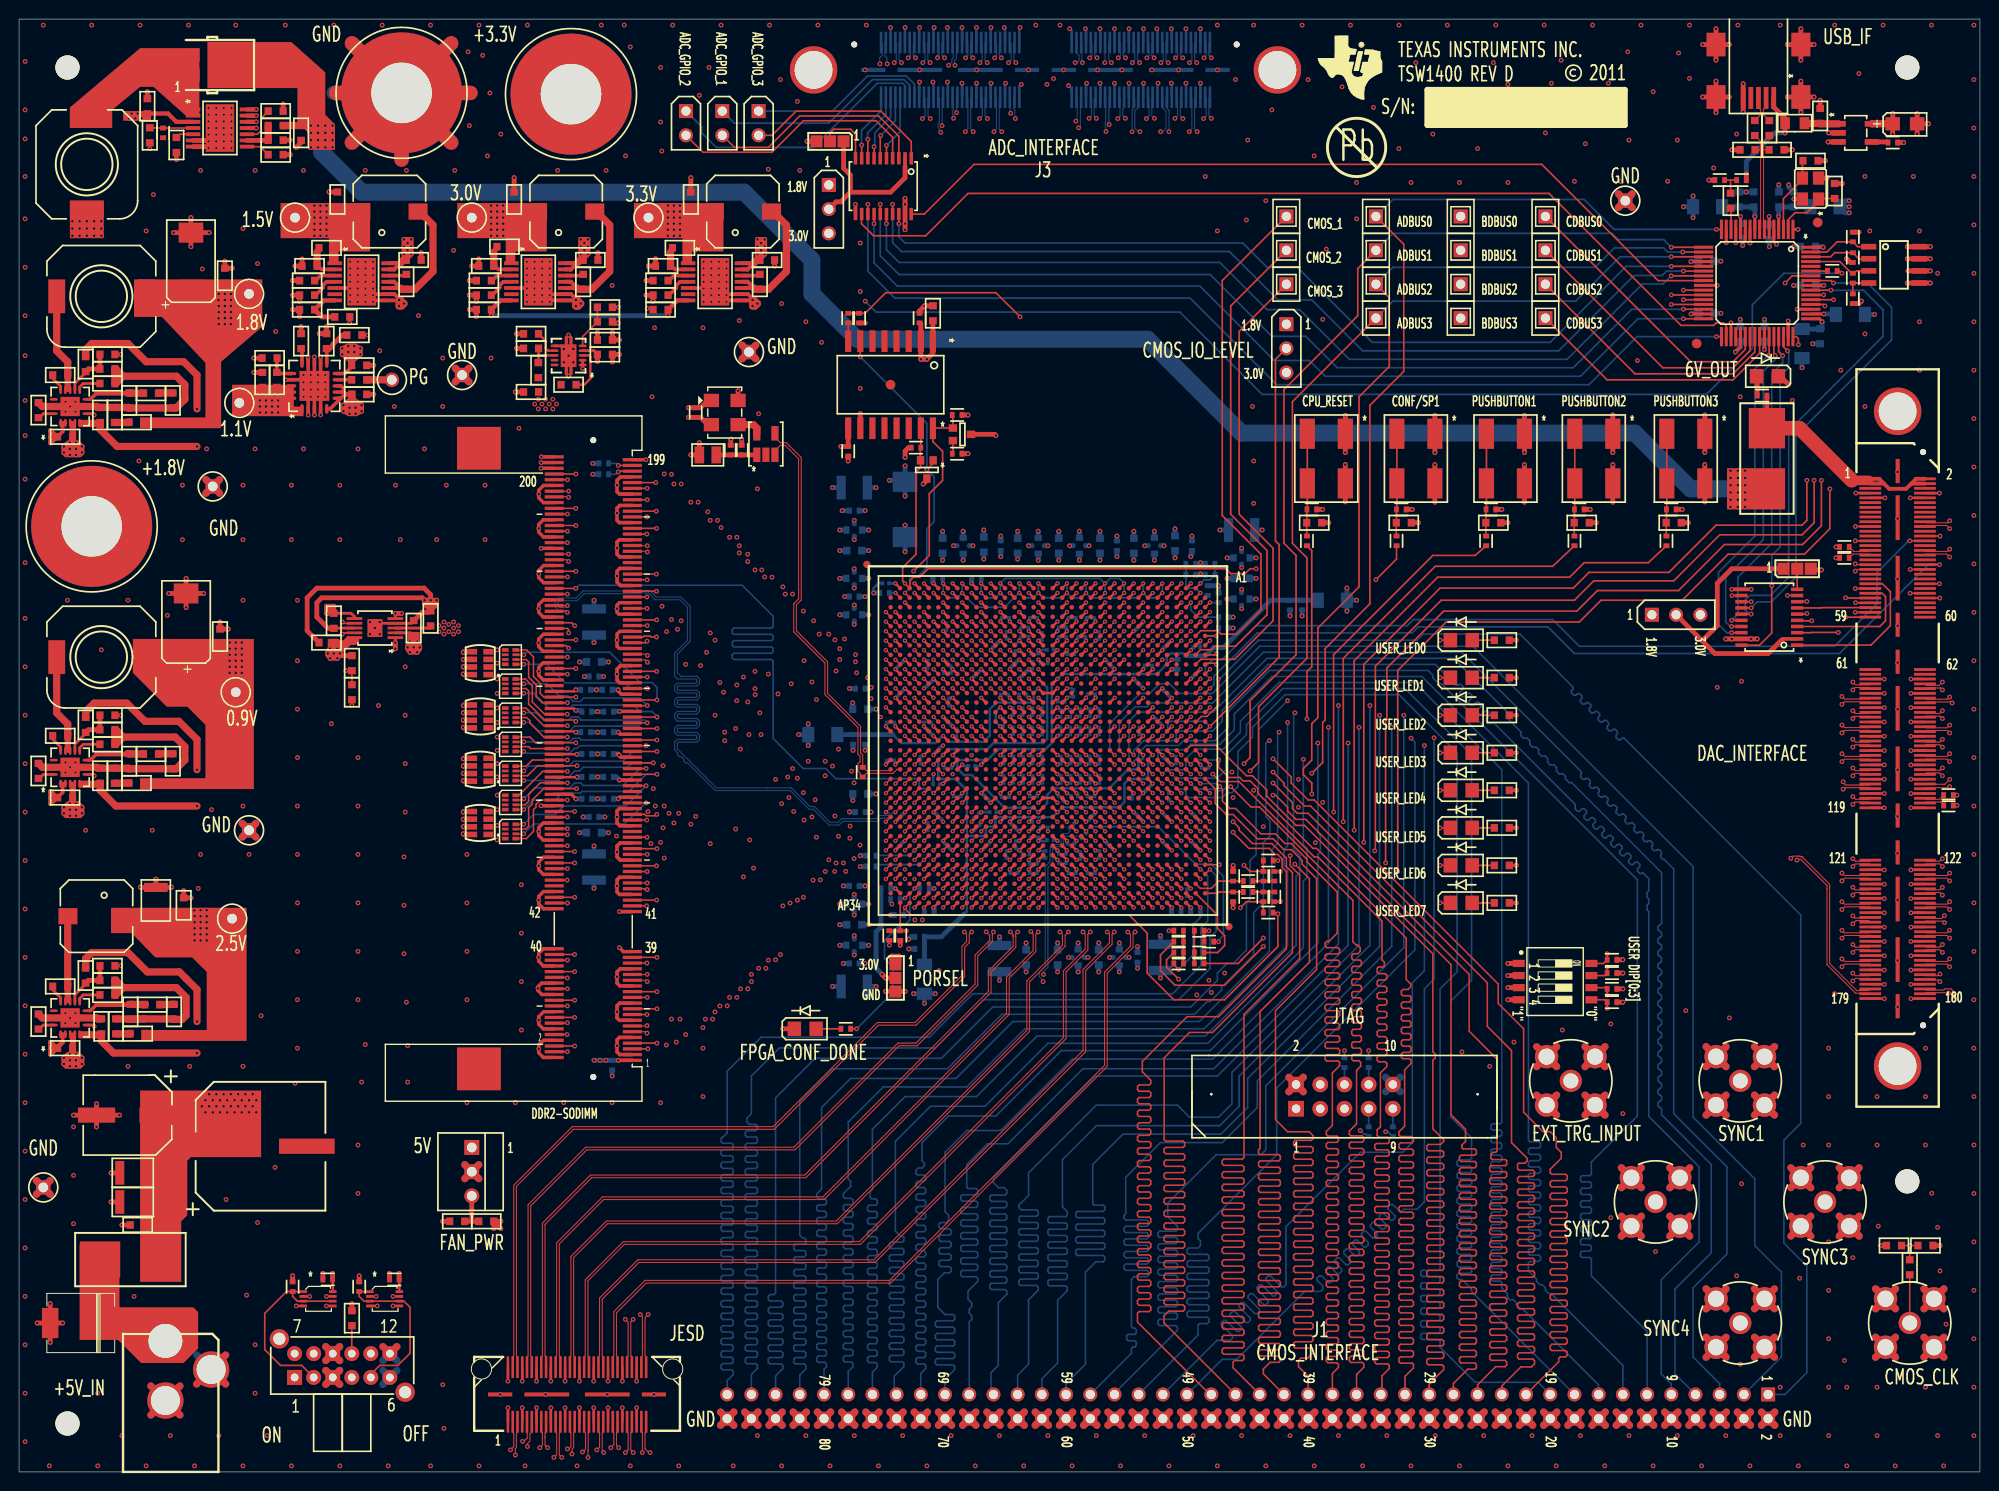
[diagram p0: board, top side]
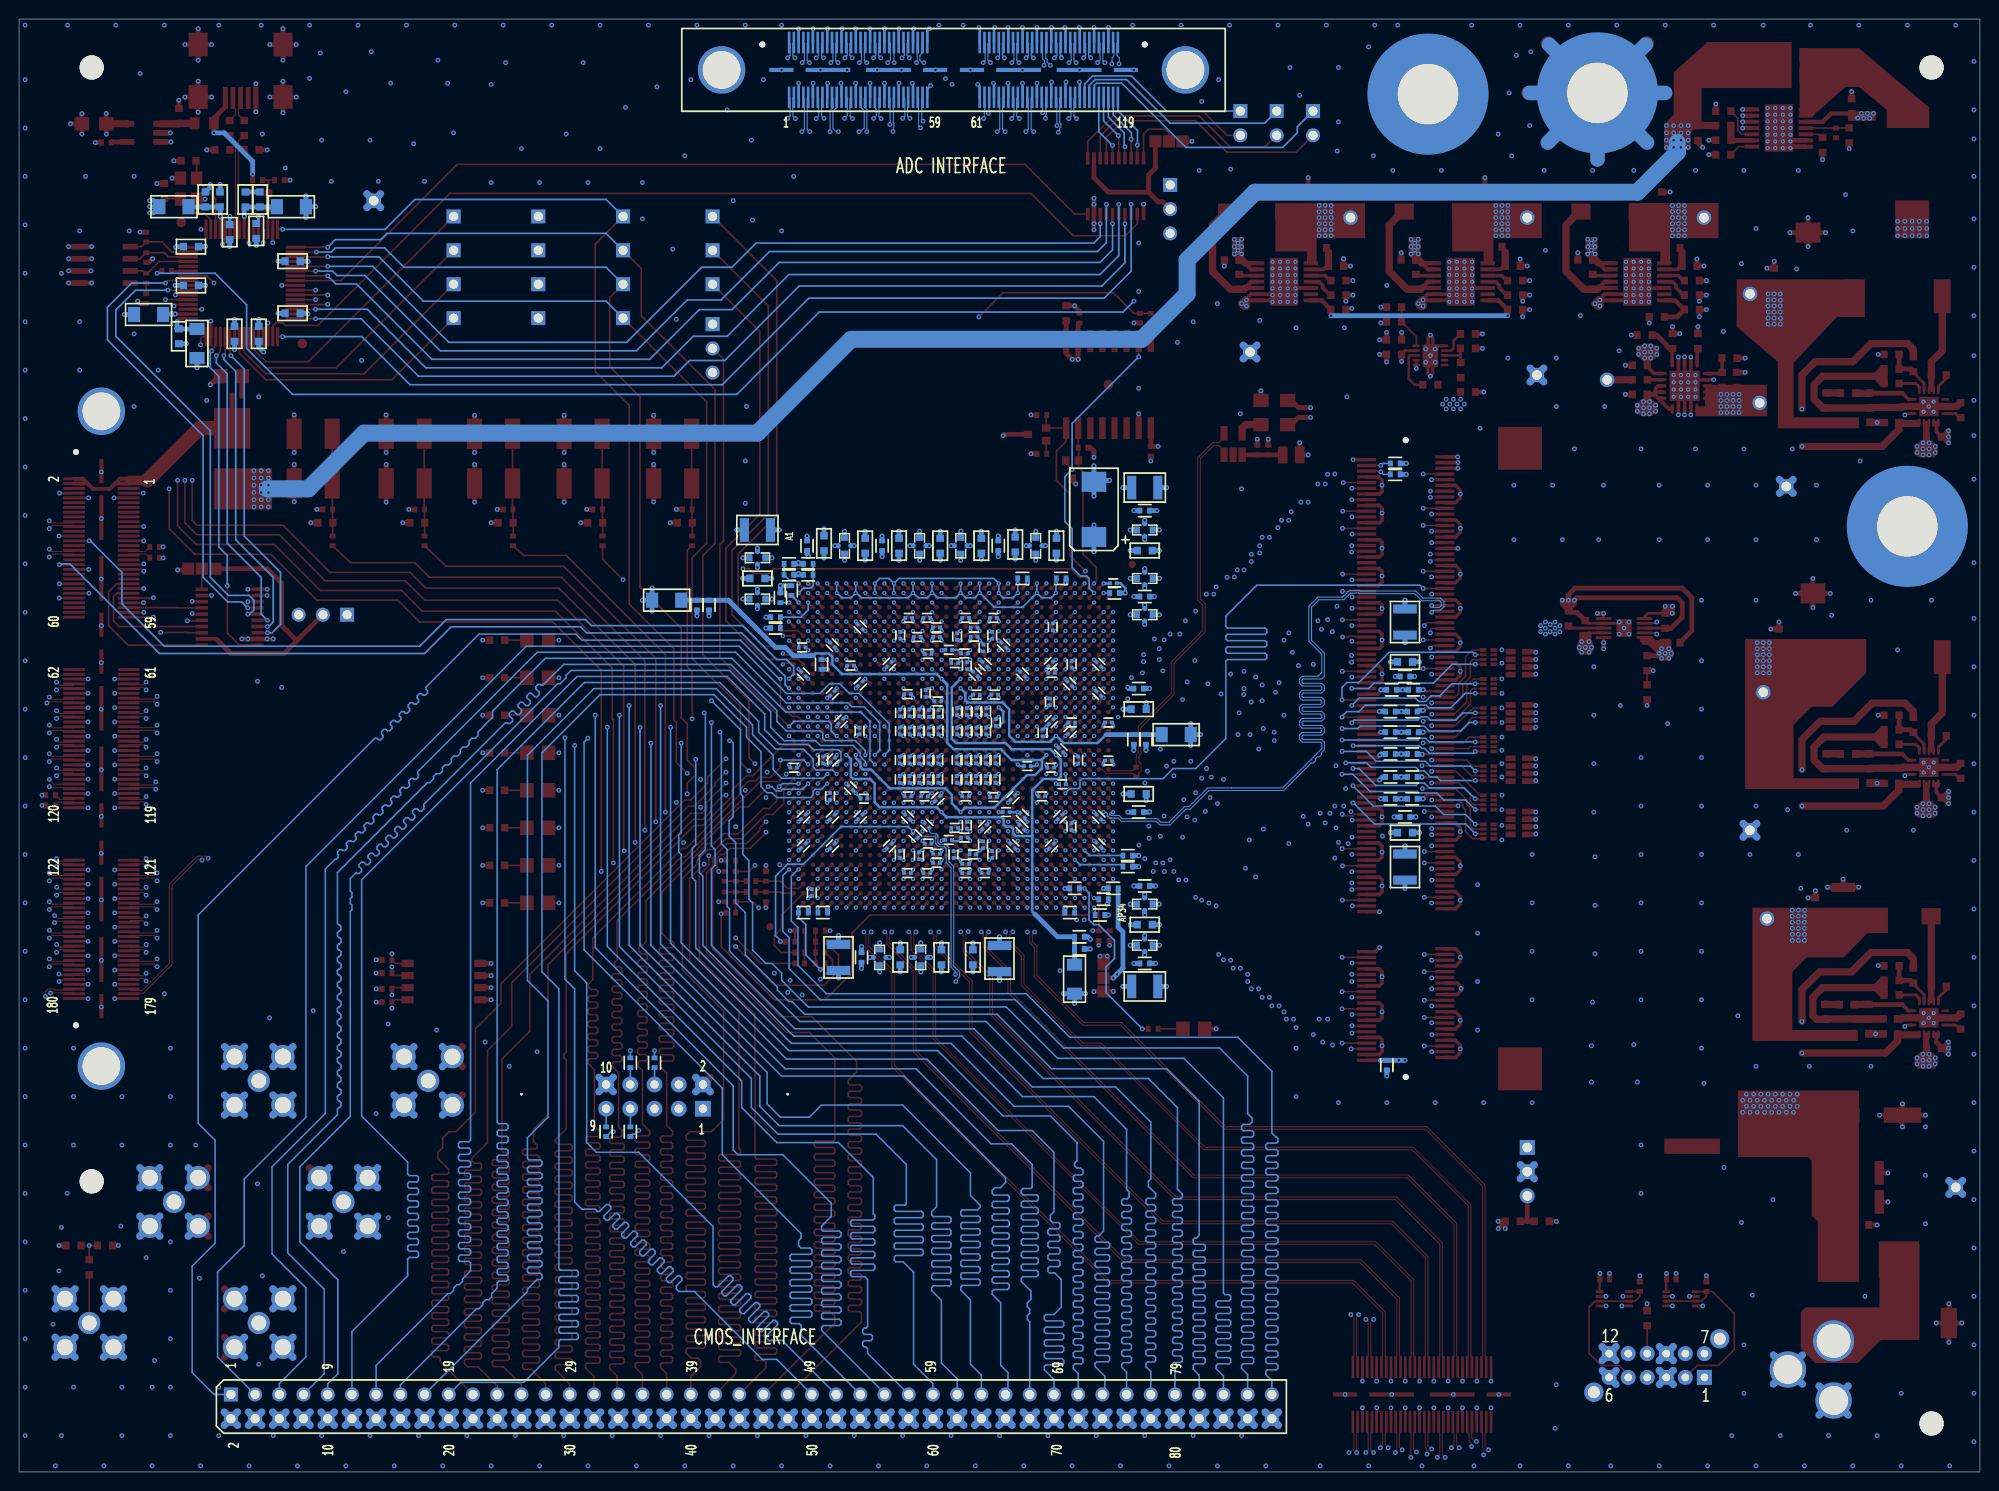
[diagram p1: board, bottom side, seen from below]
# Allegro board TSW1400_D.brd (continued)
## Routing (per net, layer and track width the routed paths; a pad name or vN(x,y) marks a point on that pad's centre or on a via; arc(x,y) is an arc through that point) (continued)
FPGA_BLAST_TDI: length 5.5
  TOP w0.178: R151.1 R52.1 125.86,61.98 125.09,61.21 123.94,61.21 U5.B32
FPGA_BLAST_TDO: length 9.2
  TOP w0.178: U5.B33 125.73,58.42 125.73,57.02 126.49,56.26 126.49,55.22 125.76,54.48 R150.1
FPGA_CLK2_N: length 2.4
  TOP w0.114: C293.2 192.42,96.28 194.13,96.28 J4.33
FPGA_CLK2_P: length 2.5
  TOP w0.114: J4.31 194.13,96.56 192.49,96.56 C292.2
FPGA_CLKN: length 2.2
  TOP w0.114: C264.2 201.57,70.27 200.08,70.27 J4.118
FPGA_CLKP: length 2.2
  TOP w0.114: J4.116 200.08,70.55 201.49,70.55 C291.2
FPGA_CONF_DONE: length 20.2
  TOP w0.178: U5.AL32 v2(93.95,61.2) ; v1(87.88,46.48) R67.2
  BOTTOM w0.178: R49.2 93.96,61.21 v2(93.95,61.2) 93.95,61.18 93.47,60.71 93.47,57.91 92.96,57.4 92.46,57.4 90.81,55.75 90.81,53.85 91.69,52.96 91.69,50.29 v1(87.88,46.48)
FPGA_NCONFIG: length 255.4
  TOP w0.178: R66.2 191.01,125.98 v1(191.26,125.73) ; DN1.1 95.91,105.82 v1(95.25,105.16) ; U19.7 v1(88.27,116.97) ; U5.AM2 v2(92.95,92.2)
  L4-SIG2 w0.102: 98.04,58.29 98.42,58.67 98.42,61.47 98.68,61.72 101.22,61.72 101.47,61.98 101.47,67.44 101.35,67.56 101.35,67.94 101.34,67.95 101.34,68.45 101.35,68.46 101.35,71.37 100.84,71.88 100.84,73.66 100.46,74.04 100.46,77.47 100.2,77.72 99.57,77.72 99.44,77.85 99.44,80.39 99.19,80.64 97.79,80.64 97.54,80.9 97.54,91.44 97.28,91.69 93.47,91.69 92.97,92.2 v2(92.95,92.2)
  L4-SIG2 w0.178: 98.04,58.29 97.92,58.17 97.92,53.98 v1(96.52,52.58) ; v1(88.27,116.97) 87.88,117.35 87.88,121.92 v1(88.77,122.81)
  L10-SIG4 w0.178: v1(141.6,44.2) 140.08,42.67 136.14,42.67 134.24,44.58 104.78,44.58 96.77,52.58 v1(96.52,52.58)
  BOTTOM w0.178: v1(88.27,116.97) 95.25,109.98 v1(95.25,105.16) 96.01,104.39 96.01,99.69 95.25,98.93 95.25,94.87 94.36,93.98 93.73,93.98 93.47,93.73 93.47,92.72 v2(92.95,92.2) ; R131.1 v1(141.6,44.2) ; v1(191.26,125.73) 185.17,125.73 181.86,122.43 181.86,117.86 177.04,113.03 130.43,113.03 121.79,121.67 89.92,121.67 v1(88.77,122.81)
FPGA_NSTATUS: length 1.3
  TOP w0.178: U5.AM33 v2(92.95,60.2)
  BOTTOM w0.178: R50.2 92.82,60.07 v2(92.95,60.2)
FPGA_TCK: length 9
  TOP w0.178: U5.B34 v2(123.95,59.2) ; v1(121.67,52.7) 121.16,53.21 R149.1
  BOTTOM w0.178: v1(121.67,52.7) 123.19,54.23 123.19,57.4 123.95,58.17 R55.2 123.95,59.2 v2(123.95,59.2)
FPGA_TMS: length 4.1
  TOP w0.178: U5.A33 125.73,60.7 125.86,60.83 R152.1
FPGACLK2N: length 119.9
  TOP w0.114: C293.1 v1(190.63,95.89) ; U5.N6 v2(112.95,88.2)
  L10-SIG4 w0.102: v1(190.63,95.89) 190.09,96.42 166.87,96.42 166.16,97.13 163.55,97.13 163.28,96.86 163.28,96.06 163.18,95.96 162.98,95.96 162.88,96.06 162.88,96.86 162.61,97.13 162.18,97.13 161.91,96.86 161.91,96.06 161.81,95.96 161.61,95.96 161.5,96.06 161.5,96.86 161.24,97.13 160.8,97.13 160.54,96.86 160.54,96.06 160.44,95.96 160.23,95.96 160.13,96.06 160.13,96.86 159.87,97.13 159.43,97.13 159.17,96.86 159.17,96.06 159.07,95.96 158.86,95.96 158.76,96.06 158.76,96.86 158.5,97.13 158.06,97.13 157.8,96.86 157.8,96.06 157.69,95.96 157.49,95.96 157.39,96.06 157.39,96.86 157.12,97.13 156.69,97.13 156.42,96.86 156.42,96.06 156.32,95.96 156.12,95.96 156.02,96.06 156.02,96.86 155.75,97.13 155.32,97.13 155.05,96.86 155.05,96.06 154.95,95.96 154.75,95.96 154.65,96.06 154.65,96.86 154.38,97.13 153.95,97.13 153.68,96.86 153.68,96.06 153.58,95.96 153.38,95.96 153.27,96.06 153.27,96.86 153.01,97.13 152.57,97.13 152.31,96.86 152.31,96.06 152.21,95.96 152,95.96 151.9,96.06 151.9,96.86 151.64,97.13 151.2,97.13 150.94,96.86 150.94,96.06 150.84,95.96 150.63,95.96 150.53,96.06 150.53,96.86 150.27,97.13 149.83,97.13 149.57,96.86 149.57,96.06 149.46,95.96 149.26,95.96 149.16,96.06 149.16,96.86 148.89,97.13 148.46,97.13 148.19,96.86 148.19,96.06 148.09,95.96 147.89,95.96 147.79,96.06 147.79,96.86 147.52,97.13 147.09,97.13 146.82,96.86 146.82,96.06 146.72,95.96 146.52,95.96 146.42,96.06 146.42,96.86 146.15,97.13 145.72,97.13 145.45,96.86 145.45,96.06 145.35,95.96 145.15,95.96 145.04,96.06 145.04,96.86 144.78,97.13 144.34,97.13 144.08,96.86 144.08,96.06 143.98,95.96 143.77,95.96 143.67,96.06 143.67,96.86 143.41,97.13 142.97,97.13 142.71,96.86 142.71,96.06 142.61,95.96 142.4,95.96 142.3,96.06 142.3,96.86 142.04,97.13 141.6,97.13 141.34,96.86 141.34,96.06 141.23,95.96 141.03,95.96 140.93,96.06 140.93,96.86 140.66,97.13 140.23,97.13 139.96,96.86 139.96,96.06 139.86,95.96 139.66,95.96 139.24,96.38 139.08,96.55 137.29,96.55 137.06,96.55 133.46,92.95 129.75,92.95 129.23,93.47 127.38,93.47 125.6,91.69 125.33,91.69 125.21,91.82 121.69,91.82 121.57,91.69 120.33,91.69 120.21,91.82 119.69,91.82 119.57,91.69 118.33,91.69 118.21,91.82 117.69,91.82 117.57,91.69 116.33,91.69 116.21,91.82 115.69,91.82 115.57,91.69 114.68,91.69 114.33,91.34 114.33,90.04 114.3,90.01 114.3,89.39 114.33,89.36 114.33,89.04 114.3,89.01 114.3,88.39 114.33,88.36 114.33,88.04 114.3,88.01 114.11,87.82 113.79,87.82 113.77,87.84 113.3,87.84 v2(112.95,88.2)
  BOTTOM w0.114: R105.2 113.04,88.11 v2(112.95,88.2)
FPGACLK2P: length 122.1
  TOP w0.114: C292.1 v1(190.63,97.03) ; U5.N7 v2(112.95,87.2)
  L10-SIG4 w0.102: v2(112.95,87.2) 113.35,87.6 113.67,87.6 113.69,87.58 114.21,87.58 114.57,87.94 114.57,88.46 114.54,88.49 114.54,88.91 114.57,88.94 114.57,89.46 114.54,89.49 114.54,89.91 114.57,89.94 114.57,91.25 114.78,91.46 115.67,91.46 115.79,91.58 116.11,91.58 116.23,91.46 117.67,91.46 117.79,91.58 118.11,91.58 118.23,91.46 119.67,91.46 119.79,91.58 120.11,91.58 120.23,91.46 121.67,91.46 121.79,91.58 125.11,91.58 125.27,91.41 125.72,91.41 127.5,93.19 129.11,93.19 129.64,92.67 133.58,92.67 137.17,96.27 138.96,96.27 139.54,95.68 139.98,95.68 140.24,95.95 140.24,96.75 140.35,96.85 140.55,96.85 140.65,96.75 140.65,95.95 140.92,95.68 141.35,95.68 141.62,95.95 141.62,96.75 141.72,96.85 141.92,96.85 142.02,96.75 142.02,95.95 142.29,95.68 142.72,95.68 142.99,95.95 142.99,96.75 143.09,96.85 143.29,96.85 143.39,96.75 143.39,95.95 143.66,95.68 144.09,95.68 144.36,95.95 144.36,96.75 144.46,96.85 144.66,96.85 144.77,96.75 144.77,95.95 145.03,95.68 145.47,95.68 145.73,95.95 145.73,96.75 145.83,96.85 146.04,96.85 146.14,96.75 146.14,95.95 146.4,95.68 146.84,95.68 147.1,95.95 147.1,96.75 147.2,96.85 147.41,96.85 147.51,96.75 147.51,95.95 147.77,95.68 148.21,95.68 148.47,95.95 148.47,96.75 148.58,96.85 148.78,96.85 148.88,96.75 148.88,95.95 149.15,95.68 149.58,95.68 149.85,95.95 149.85,96.75 149.95,96.85 150.15,96.85 150.25,96.75 150.25,95.95 150.52,95.68 150.95,95.68 151.22,95.95 151.22,96.75 151.32,96.85 151.52,96.85 151.62,96.75 151.62,95.95 151.89,95.68 152.32,95.68 152.59,95.95 152.59,96.75 152.69,96.85 152.89,96.85 152.99,96.75 152.99,95.95 153.26,95.68 153.69,95.68 153.96,95.95 153.96,96.75 154.06,96.85 154.26,96.85 154.37,96.75 154.37,95.95 154.63,95.68 155.07,95.68 155.33,95.95 155.33,96.75 155.43,96.85 155.64,96.85 155.74,96.75 155.74,95.95 156,95.68 156.44,95.68 156.7,95.95 156.7,96.75 156.8,96.85 157.01,96.85 157.11,96.75 157.11,95.95 157.38,95.68 157.81,95.68 158.07,95.95 158.07,96.75 158.18,96.85 158.38,96.85 158.48,96.75 158.48,95.95 158.75,95.68 159.18,95.68 159.45,95.95 159.45,96.75 159.55,96.85 159.75,96.85 159.85,96.75 159.85,95.95 160.12,95.68 160.55,95.68 160.82,95.95 160.82,96.75 160.92,96.85 161.12,96.85 161.22,96.75 161.22,95.95 161.49,95.68 161.92,95.68 162.19,95.95 162.19,96.75 162.29,96.85 162.49,96.85 162.6,96.75 162.6,95.95 162.86,95.68 163.3,95.68 163.56,95.95 163.56,96.75 163.66,96.85 166.04,96.85 166.75,96.14 189.74,96.14 190.37,95.5 190.43,95.5 190.46,95.48 190.8,95.48 190.82,95.5 190.88,95.5 191.13,95.76 191.13,96.14 190.63,96.65 v1(190.63,97.03)
  BOTTOM w0.114: R105.1 113.15,87.4 v2(112.95,87.2)
FPGACLKN: length 136.6
  TOP w0.114: v2(112.95,64.2) U5.N29 ; C264.1 v1(203.33,69.91)
  L4-SIG2 w0.102: v2(112.95,64.2) 113.2,64.45 113.23,64.45 113.36,64.58 116.19,64.58 116.26,64.52 122.35,64.52 123.29,63.58 125.11,63.58 125.33,63.36 125.33,63.29 125.61,63.01 125.62,63.01 125.69,62.94 126.76,62.94 128.65,61.05 128.65,59.31 129.01,58.95 132.42,58.95 132.73,58.65 150.46,58.65 157.98,66.17 159.04,66.17 159.15,66.07 159.15,65.77 159.41,65.51 159.85,65.51 160.11,65.77 160.11,66.73 160.21,66.83 160.42,66.83 160.52,66.73 160.52,65.77 160.78,65.51 161.22,65.51 161.48,65.77 161.48,66.73 161.58,66.83 161.79,66.83 161.89,66.73 161.89,65.77 162.15,65.51 162.59,65.51 162.85,65.77 162.85,66.73 162.96,66.83 163.16,66.83 163.26,66.73 163.26,65.77 163.53,65.51 163.96,65.51 164.23,65.77 164.23,66.73 164.33,66.83 164.53,66.83 164.63,66.73 164.63,65.77 164.9,65.51 165.33,65.51 165.6,65.77 165.6,66.73 165.7,66.83 165.9,66.83 166,66.73 166,65.77 166.27,65.51 166.7,65.51 166.97,65.77 166.97,66.73 167.07,66.83 167.27,66.83 167.38,66.73 167.38,65.77 167.64,65.51 168.08,65.51 168.34,65.77 168.34,66.73 168.44,66.83 168.65,66.83 168.75,66.73 168.75,65.77 169.01,65.51 169.45,65.51 169.71,65.77 169.71,66.73 169.81,66.83 170.02,66.83 170.12,66.73 170.12,65.77 170.38,65.51 170.82,65.51 171.08,65.77 171.08,66.73 171.19,66.83 171.39,66.83 171.49,66.73 171.49,65.77 171.76,65.51 172.19,65.51 172.46,65.77 172.46,66.73 172.56,66.83 172.76,66.83 172.86,66.73 172.86,65.77 173.13,65.51 173.56,65.51 173.83,65.77 173.83,66.73 173.93,66.83 174.13,66.83 174.23,66.73 174.23,65.77 174.5,65.51 174.93,65.51 175.2,65.77 175.2,66.73 175.3,66.83 175.5,66.83 175.61,66.73 175.61,65.77 175.87,65.51 176.31,65.51 176.57,65.77 176.57,66.73 176.67,66.83 176.88,66.83 176.98,66.73 176.98,65.77 177.24,65.51 177.68,65.51 177.94,65.77 177.94,66.73 178.04,66.83 178.25,66.83 178.35,66.73 178.35,65.77 178.61,65.51 179.05,65.51 179.31,65.77 179.31,66.73 179.42,66.83 179.62,66.83 179.72,66.73 179.72,65.77 179.99,65.51 180.42,65.51 180.69,65.77 180.69,66.73 180.79,66.83 180.99,66.83 181.09,66.73 181.09,66.57 181.49,66.17 197.58,66.17 199.9,68.49 199.9,69.76 200.47,70.33 203.2,70.33 203.33,70.21 v1(203.33,69.91)
  BOTTOM w0.114: v2(112.95,64.2) 113.16,64.41 R104.1
FPGACLKP: length 136.5
  TOP w0.114: C291.1 v1(203.33,70.99) ; v2(112.95,65.2) U5.N28
  L4-SIG2 w0.102: v2(112.95,65.2) 113.33,64.82 116.29,64.82 116.35,64.75 122.45,64.75 123.39,63.82 125.21,63.82 125.57,63.46 125.57,63.45 125.73,63.29 125.73,63.29 125.8,63.22 126.87,63.22 128.93,61.16 128.93,59.42 129.12,59.23 132.54,59.23 132.84,58.93 150.34,58.93 157.86,66.45 159.16,66.45 159.43,66.18 159.43,65.89 159.53,65.79 159.73,65.79 159.83,65.89 159.83,66.84 160.1,67.11 160.53,67.11 160.8,66.84 160.8,65.89 160.9,65.79 161.1,65.79 161.2,65.89 161.2,66.84 161.47,67.11 161.9,67.11 162.17,66.84 162.17,65.89 162.27,65.79 162.47,65.79 162.58,65.89 162.58,66.84 162.84,67.11 163.28,67.11 163.54,66.84 163.54,65.89 163.64,65.79 163.85,65.79 163.95,65.89 163.95,66.84 164.21,67.11 164.65,67.11 164.91,66.84 164.91,65.89 165.01,65.79 165.22,65.79 165.32,65.89 165.32,66.84 165.58,67.11 166.02,67.11 166.28,66.84 166.28,65.89 166.39,65.79 166.59,65.79 166.69,65.89 166.69,66.84 166.96,67.11 167.39,67.11 167.66,66.84 167.66,65.89 167.76,65.79 167.96,65.79 168.06,65.89 168.06,66.84 168.33,67.11 168.76,67.11 169.03,66.84 169.03,65.89 169.13,65.79 169.33,65.79 169.43,65.89 169.43,66.84 169.7,67.11 170.13,67.11 170.4,66.84 170.4,65.89 170.5,65.79 170.7,65.79 170.81,65.89 170.81,66.84 171.07,67.11 171.51,67.11 171.77,66.84 171.77,65.89 171.87,65.79 172.08,65.79 172.18,65.89 172.18,66.84 172.44,67.11 172.88,67.11 173.14,66.84 173.14,65.89 173.24,65.79 173.45,65.79 173.55,65.89 173.55,66.84 173.81,67.11 174.25,67.11 174.51,66.84 174.51,65.89 174.62,65.79 174.82,65.79 174.92,65.89 174.92,66.84 175.19,67.11 175.62,67.11 175.89,66.84 175.89,65.89 175.99,65.79 176.19,65.79 176.29,65.89 176.29,66.84 176.56,67.11 176.99,67.11 177.26,66.84 177.26,65.89 177.36,65.79 177.56,65.79 177.66,65.89 177.66,66.84 177.93,67.11 178.36,67.11 178.63,66.84 178.63,65.89 178.73,65.79 178.93,65.79 179.03,65.89 179.03,66.84 179.3,67.11 179.73,67.11 180,66.84 180,65.89 180.1,65.79 180.3,65.79 180.41,65.89 180.41,66.84 180.67,67.11 181.11,67.11 181.37,66.84 181.37,66.68 181.61,66.45 197.46,66.45 199.62,68.61 199.62,69.88 200.36,70.61 203.2,70.61 203.33,70.74 v1(203.33,70.99)
  BOTTOM w0.114: v2(112.95,65.2) 113.02,65.13 R104.2
FTDI_BLAST_TDI: length 107.3
  TOP w0.178: U3.52 189.32,122.46 v1(189.48,122.3) ; v1(132.33,62.99) R62.2 ; v1(141.1,66.04) 141.1,84.71 149.1,92.71 163.07,92.71 164.72,94.36 173.1,94.36 178.05,99.31 187.07,99.31 187.58,99.82 v1(187.58,104.01)
  L4-SIG2 w0.178: v1(189.48,122.3) 189.99,121.79 189.99,119.13 187.58,116.71 v1(187.58,104.01) ; v1(141.1,66.04) 138.18,63.12 132.46,63.12 v1(132.33,62.99)
FTDI_BLAST_TDO: length 123.2
  TOP w0.178: U3.53 v1(190.37,122.96) ; v1(143.38,63.88) 143.38,78.87 143.51,79 143.51,84.33 149.48,90.3 163.45,90.3 165.61,92.46 174.12,92.46 178.94,97.28 187.13,97.28 189.1,99.25 v1(189.1,104.01) ; v1(130.56,56.01) 128.27,53.72 128.27,53.7 127.91,53.34 R63.2
  L3-SIG1 w0.178: v1(143.38,63.88) 135.51,56.01 v1(130.56,56.01)
  L4-SIG2 w0.178: v1(190.37,122.96) 190.37,122.94 191.39,121.92 191.39,118.11 189.1,115.82 v1(189.1,104.01)
FTDI_NCE: length 209.4
  TOP w0.178: v1(185.29,124.71) 186.04,125.46 U3.58 ; R153.1 v1(91.31,55.24)
  L10-SIG4 w0.178: v1(185.29,124.71) 185.29,122.3 189.87,117.73 195.58,117.73 204.6,108.71 204.6,53.47 201.55,50.42 195.07,50.42 194.31,49.66 181.86,49.66 180.72,50.8 172.59,50.8 169.8,48.01 144.27,48.01 139.7,43.43 137.79,43.43 135.25,45.97 104.52,45.97 96.52,53.98 93.34,53.98 92.58,54.74 91.82,54.74 v1(91.31,55.24)
FTDI_NCONFIG: length 1.7
  TOP w0.178: U3.59 189.72,125.96 R66.1
FTDI_TCK: length 130.3
  TOP w0.178: v1(186.69,118.24) 186.69,118.87 186.47,119.09 U3.48 ; v1(130.56,55.12) 126.49,51.05 121.28,51.05 119.76,52.58 119.76,54.23 R61.2 ; v1(189.99,103.12) 189.99,98.93 187.32,96.27 179.32,96.27 174.5,91.44 165.99,91.44 163.7,89.15 149.73,89.15 144.65,84.07 v1(144.65,62.99)
  L3-SIG1 w0.178: v1(130.56,55.12) 136.78,55.12 v1(144.65,62.99)
  L4-SIG2 w0.178: v1(186.69,118.24) 186.31,117.86 186.31,115.44 186.69,115.06 186.69,104.14 187.71,103.12 v1(189.99,103.12)
FTDI_TMS: length 111.1
  TOP w0.178: v1(188.34,104.01) 188.34,99.57 187.07,98.3 178.44,98.3 173.61,93.47 165.23,93.47 163.19,91.44 149.22,91.44 142.3,84.52 142.3,65.21 v1(142.24,65.15) ; R64.2 v1(132.33,59.82) ; U3.54 v1(189.34,123.46)
  L4-SIG2 w0.178: v1(132.33,59.82) 136.91,59.82 v1(142.24,65.15) ; v1(189.34,123.46) 189.74,123.06 189.74,122.81 190.63,121.92 190.63,118.62 188.34,116.33 v1(188.34,104.01)
G22: length 121.3
  TOP w0.165: U5.G22 v2(118.95,71.2)
  L3-SIG1 w0.102: 125.35,70.48 125.09,70.74 124.71,70.74 124.46,70.99 124.46,71.37 124.08,71.75 119.51,71.75 118.95,71.2 v2(118.95,71.2)
  L3-SIG1 w0.114: J14.1 176.02,41.02 170.18,35.18 166.88,35.18 160.15,28.45 145.29,28.45 144.65,29.08 144.65,30.48 145.54,31.37 149.1,31.37 156.46,38.73 156.46,41.66 148.21,49.91 132.59,49.91 128.91,53.59 128.91,56.77 130.18,58.04 130.18,63.5 127.89,65.79 127.89,67.44 127.64,67.69 127.13,67.69 125.73,69.09 125.73,70.1 125.35,70.48
G23: length 121.8
  TOP w0.165: U5.G23 v2(118.95,70.2)
  L3-SIG1 w0.102: 125.35,68.58 125.35,69.47 125.09,69.72 124.84,69.72 124.46,70.1 124.46,70.36 124.08,70.74 119.51,70.74 118.97,70.2 v2(118.95,70.2)
  L3-SIG1 w0.114: 125.35,68.58 126.87,67.06 126.87,66.04 129.54,63.37 129.54,58.17 128.4,57.02 128.4,52.83 132.84,48.39 143.13,48.39 149.22,42.29 149.22,37.59 144.91,33.27 137.67,33.27 135,30.61 135,27.69 137.92,24.77 139.78,24.77 139.91,24.89 140.24,24.89 140.3,24.83 140.3,24.7 140.36,24.64 140.69,24.64 140.76,24.7 140.76,24.83 140.82,24.89 141.15,24.89 141.21,24.83 141.21,24.7 141.28,24.64 141.61,24.64 141.67,24.7 141.67,24.83 141.73,24.89 142.06,24.89 142.13,24.83 142.13,24.7 142.19,24.64 142.52,24.64 142.59,24.7 142.59,24.83 142.65,24.89 142.98,24.89 143.04,24.83 143.04,24.7 143.11,24.64 143.44,24.64 143.5,24.7 143.5,24.83 143.56,24.89 143.89,24.89 143.96,24.83 143.96,24.7 144.02,24.64 144.35,24.64 144.41,24.7 144.41,24.83 144.48,24.89 144.81,24.89 144.87,24.83 144.87,24.7 144.93,24.64 145.26,24.64 145.33,24.7 145.33,24.83 145.39,24.89 145.72,24.89 145.79,24.83 145.79,24.7 145.85,24.64 146.18,24.64 146.24,24.7 146.24,24.83 146.31,24.89 146.64,24.89 146.7,24.83 146.7,24.7 146.76,24.64 147.09,24.64 147.16,24.7 147.16,24.83 147.22,24.89 147.55,24.89 147.61,24.83 147.61,24.7 147.68,24.64 148.01,24.64 148.07,24.7 148.07,24.83 148.13,24.89 148.47,24.89 148.53,24.83 148.53,24.7 148.59,24.64 148.92,24.64 148.99,24.7 148.99,24.83 149.05,24.89 149.38,24.89 149.44,24.83 149.44,24.7 149.51,24.64 149.84,24.64 149.9,24.7 149.9,24.83 149.96,24.89 150.29,24.89 150.36,24.83 150.36,24.7 150.42,24.64 150.75,24.64 150.81,24.7 150.81,24.83 150.88,24.89 151.21,24.89 151.27,24.83 151.27,24.7 151.34,24.64 151.67,24.64 151.73,24.7 151.73,24.83 151.79,24.89 152.12,24.89 152.19,24.83 152.19,24.7 152.25,24.64 152.58,24.64 152.64,24.7 152.64,24.83 152.71,24.89 153.04,24.89 153.1,24.83 153.1,24.7 153.16,24.64 153.49,24.64 153.56,24.7 153.56,24.83 153.62,24.89 153.95,24.89 154.02,24.83 154.02,24.7 154.08,24.64 154.41,24.64 154.54,24.77 161.29,24.77 164.85,28.32 J15.1
G24: length 121.8
  TOP w0.165: U5.G24 v2(118.95,69.2)
  L3-SIG1 w0.102: 122.05,58.29 122.56,58.8 122.56,66.26 122.14,66.67 121.79,66.67 119.76,68.71 119.51,68.71 119.01,69.2 v2(118.95,69.2)
  L3-SIG1 w0.114: J16.1 183.9,28.32 177.42,21.84 155.94,21.84 155.81,21.72 155.48,21.72 155.42,21.78 155.42,21.91 155.35,21.97 155.02,21.97 154.96,21.91 154.96,21.78 154.89,21.72 154.56,21.72 154.5,21.78 154.5,21.91 154.44,21.97 154.11,21.97 154.04,21.91 154.04,21.78 153.98,21.72 153.65,21.72 153.59,21.78 153.59,21.91 153.52,21.97 153.19,21.97 153.13,21.91 153.13,21.78 153.07,21.72 152.74,21.72 152.67,21.78 152.67,21.91 152.61,21.97 152.28,21.97 152.22,21.91 152.22,21.78 152.15,21.72 151.82,21.72 151.76,21.78 151.76,21.91 151.69,21.97 151.36,21.97 151.3,21.91 151.3,21.78 151.24,21.72 150.91,21.72 150.84,21.78 150.84,21.91 150.78,21.97 150.45,21.97 150.39,21.91 150.39,21.78 150.32,21.72 149.99,21.72 149.93,21.78 149.93,21.91 149.87,21.97 149.54,21.97 149.47,21.91 149.47,21.78 149.41,21.72 149.08,21.72 149.01,21.78 149.01,21.91 148.95,21.97 148.62,21.97 148.56,21.91 148.56,21.78 148.49,21.72 148.16,21.72 148.1,21.78 148.1,21.91 148.04,21.97 147.71,21.97 147.64,21.91 147.64,21.78 147.58,21.72 147.25,21.72 147.19,21.78 147.19,21.91 147.12,21.97 146.79,21.97 146.73,21.91 146.73,21.78 146.67,21.72 146.33,21.72 146.27,21.78 146.27,21.91 146.21,21.97 145.88,21.97 145.81,21.91 145.81,21.78 145.75,21.72 145.42,21.72 145.36,21.78 145.36,21.91 145.29,21.97 144.96,21.97 144.9,21.91 144.9,21.78 144.84,21.72 144.51,21.72 144.44,21.78 144.44,21.91 144.38,21.97 144.05,21.97 143.99,21.91 143.99,21.78 143.92,21.72 143.59,21.72 143.53,21.78 143.53,21.91 143.46,21.97 143.13,21.97 143.07,21.91 143.07,21.78 143.01,21.72 142.68,21.72 142.61,21.78 142.61,21.91 142.55,21.97 142.22,21.97 142.16,21.91 142.16,21.78 142.09,21.72 141.76,21.72 141.7,21.78 141.7,21.91 141.64,21.97 141.31,21.97 141.24,21.91 141.24,21.78 141.18,21.72 140.85,21.72 140.79,21.78 140.79,21.91 140.72,21.97 140.39,21.97 140.33,21.91 140.33,21.78 140.26,21.72 139.93,21.72 139.81,21.84 135.13,21.84 119.13,37.85 119.13,56.39 120.4,57.66 121.41,57.66 122.05,58.29
G25: length 121.9
  TOP w0.165: U5.G25 v2(118.95,68.2)
  L3-SIG1 w0.102: v2(118.95,68.2) 119,68.2 121.54,65.66 121.54,62.07 121.57,62.04 121.57,60.61 121.41,60.45 121.41,58.93 120.78,58.29
  L3-SIG1 w0.114: 120.78,58.29 120.43,57.95 120.27,57.95 120.24,57.91 119.76,57.91 118.11,56.26 118.11,30.61 133.1,15.62 139.2,15.62 139.33,15.49 139.66,15.49 139.72,15.56 139.72,15.68 139.79,15.75 140.12,15.75 140.18,15.68 140.18,15.56 140.24,15.49 140.57,15.49 140.64,15.56 140.64,15.68 140.7,15.75 141.03,15.75 141.09,15.68 141.09,15.56 141.16,15.49 141.49,15.49 141.55,15.56 141.55,15.68 141.61,15.75 141.94,15.75 142.01,15.68 142.01,15.56 142.07,15.49 142.4,15.49 142.46,15.56 142.46,15.68 142.53,15.75 142.86,15.75 142.92,15.68 142.92,15.56 142.99,15.49 143.32,15.49 143.38,15.56 143.38,15.68 143.44,15.75 143.77,15.75 143.84,15.68 143.84,15.56 143.9,15.49 144.23,15.49 144.29,15.56 144.29,15.68 144.36,15.75 144.69,15.75 144.75,15.68 144.75,15.56 144.81,15.49 145.14,15.49 145.21,15.56 145.21,15.68 145.27,15.75 145.6,15.75 145.67,15.68 145.67,15.56 145.73,15.49 146.06,15.49 146.12,15.56 146.12,15.68 146.19,15.75 146.52,15.75 146.58,15.68 146.58,15.56 146.64,15.49 146.97,15.49 147.04,15.56 147.04,15.68 147.1,15.75 147.43,15.75 147.49,15.68 147.49,15.56 147.56,15.49 147.89,15.49 147.95,15.56 147.95,15.68 148.01,15.75 148.35,15.75 148.41,15.68 148.41,15.56 148.47,15.49 148.8,15.49 148.87,15.56 148.87,15.68 148.93,15.75 149.26,15.75 149.32,15.68 149.32,15.56 149.39,15.49 149.72,15.49 149.78,15.56 149.78,15.68 149.84,15.75 150.17,15.75 150.24,15.68 150.24,15.56 150.3,15.49 150.63,15.49 150.69,15.56 150.69,15.68 150.76,15.75 151.09,15.75 151.15,15.68 151.15,15.56 151.22,15.49 151.55,15.49 151.61,15.56 151.61,15.68 151.67,15.75 152,15.75 152.07,15.68 152.07,15.56 152.13,15.49 152.46,15.49 152.52,15.56 152.52,15.68 152.59,15.75 152.92,15.75 152.98,15.68 152.98,15.56 153.04,15.49 153.37,15.49 153.44,15.56 153.44,15.68 153.5,15.75 153.83,15.75 153.89,15.68 153.89,15.56 153.96,15.49 154.29,15.49 154.35,15.56 154.35,15.68 154.42,15.75 154.75,15.75 154.81,15.68 154.81,15.56 154.87,15.49 155.2,15.49 155.27,15.56 155.27,15.68 155.33,15.75 155.66,15.75 155.72,15.68 155.72,15.56 155.79,15.49 156.12,15.49 156.18,15.56 156.18,15.68 156.24,15.75 156.57,15.75 156.64,15.68 156.64,15.56 156.7,15.49 157.03,15.49 157.1,15.56 157.1,15.68 157.16,15.75 157.49,15.75 157.55,15.68 157.55,15.56 157.62,15.49 157.95,15.49 158.01,15.56 158.01,15.68 158.07,15.75 158.4,15.75 158.47,15.68 158.47,15.56 158.53,15.49 158.86,15.49 158.92,15.56 158.92,15.68 158.99,15.75 159.32,15.75 159.38,15.68 159.38,15.56 159.44,15.49 159.78,15.49 159.84,15.56 159.84,15.68 159.9,15.75 160.23,15.75 160.3,15.68 160.3,15.56 160.36,15.49 160.69,15.49 160.75,15.56 160.75,15.68 160.82,15.75 161.15,15.75 161.21,15.68 161.21,15.56 161.27,15.49 161.6,15.49 161.67,15.56 161.67,15.68 161.73,15.75 162.06,15.75 162.12,15.68 162.12,15.56 162.19,15.49 162.52,15.49 162.58,15.56 162.58,15.68 162.65,15.75 162.98,15.75 163.04,15.68 163.04,15.56 163.1,15.49 163.43,15.49 163.5,15.56 163.5,15.68 163.56,15.75 163.89,15.75 163.95,15.68 163.95,15.56 164.02,15.49 164.35,15.49 164.41,15.56 164.41,15.68 164.47,15.75 164.8,15.75 164.87,15.68 164.87,15.56 164.93,15.49 165.26,15.49 165.32,15.56 165.32,15.68 165.39,15.75 165.72,15.75 165.78,15.68 165.78,15.56 165.85,15.49 166.18,15.49 166.24,15.56 166.24,15.68 166.3,15.75 166.63,15.75 166.7,15.68 166.7,15.56 166.76,15.49 167.09,15.49 167.15,15.56 167.15,15.68 167.22,15.75 167.55,15.75 167.61,15.68 167.61,15.56 167.67,15.49 168,15.49 168.07,15.56 168.07,15.68 168.13,15.75 168.46,15.75 168.53,15.68 168.53,15.56 168.59,15.49 168.92,15.49 168.98,15.56 168.98,15.68 169.05,15.75 169.38,15.75 169.44,15.68 169.44,15.56 169.5,15.49 169.83,15.49 169.96,15.62 J17.1
GXB_RX0M: length 80.8
  TOP w0.114: J2.3 51.8,4.17 51.91,4.06 51.91,2.67 51.56,2.32 v1(51.56,2.31) ; U5.AH34 v2(96.95,59.2)
  L3-SIG1 w0.102: v1(51.56,2.31) 51.68,2.43 51.68,5.72 51.92,5.96 51.92,10.39 53.97,12.44 53.97,12.45 62.5,20.98 64.15,20.98 91.67,48.5 91.67,50.9 93.8,53.04 93.8,53.05 97.26,56.5 97.26,58.89 v2(96.95,59.2)
GXB_RX0P: length 82.9
  TOP w0.114: J2.5 52.3,4.19 52.18,4.08 52.18,2.55 52.07,2.44 v1(52.07,1.78) ; U5.AH33 v2(96.95,60.2)
  L3-SIG1 w0.102: v2(96.95,60.2) 97.03,60.2 97.54,59.69 97.54,59.03 97.49,58.99 97.49,58.45 97.54,58.41 97.54,56.39 94.08,52.93 94.08,52.92 91.95,50.79 91.95,48.39 64.26,20.7 62.61,20.7 54.25,12.34 54.25,12.32 52.2,10.27 52.2,5.84 51.96,5.6 51.96,2.43 52.07,2.31 v1(52.07,1.78)
GXB_RX1M: length 81.6
  TOP w0.114: U5.AF34 v2(98.95,59.2) ; J2.9 53.3,4.09 53.32,4.07 53.32,3.56 52.96,3.2 v1(52.83,3.2)
  L3-SIG1 w0.102: v2(98.95,59.2) 98.95,59.04 100.46,57.53 100.46,55.75 99.81,55.11 99.81,52.69 65.43,18.31 64.16,18.31 56.54,10.69 54.11,10.69 53.44,10.02 53.44,5.7 53.06,5.32 53.06,3.48 v1(52.83,3.2)
GXB_RX1P: length 83.6
  TOP w0.114: J2.11 53.8,4.19 53.6,3.99 53.6,3.24 53.34,2.98 v1(53.34,2.67) ; U5.AF33 v2(98.95,60.2)
  L3-SIG1 w0.102: v1(53.34,2.67) 53.34,5.21 53.72,5.59 53.72,9.91 54.23,10.41 56.66,10.41 64.28,18.03 65.55,18.03 100.09,52.58 100.09,54.99 100.74,55.64 100.74,57.65 99.92,58.46 99.86,58.46 99.44,58.88 99.44,59.69 98.95,60.18 v2(98.95,60.2)
GXB_RX2M: length 88.6
  TOP w0.114: U5.Y34 v2(104.95,59.2) ; J2.15 54.8,4.19 54.91,4.08 54.91,3.56 54.91,2.81 v1(54.64,2.54)
  L3-SIG1 w0.102: v2(104.95,59.2) 104.93,59.2 103.66,57.92 103.66,56.86 103.61,56.81 103.61,56.47 103.66,56.42 103.66,55.51 102.23,54.09 102.23,49.77 80.52,28.06 80.51,28.06 66.04,13.59 66.04,6.73 64.24,4.93 55.47,4.93 54.13,3.58 54.13,2.12 54.34,1.91 54.89,1.91 54.99,2.01 54.99,2.19 v1(54.64,2.54)
GXB_RX2P: length 90.5
  TOP w0.114: J2.17 55.3,4.19 55.18,4.08 55.18,3.67 55.18,2.81 v1(55.45,2.54) ; U5.Y33 v2(104.95,60.2)
  L3-SIG1 w0.102: v1(55.45,2.54) 55.27,2.36 55.27,1.89 55.01,1.63 54.23,1.63 53.85,2 53.85,3.7 55.36,5.21 64.12,5.21 65.76,6.85 65.76,13.7 80.39,28.34 80.41,28.34 101.96,49.89 101.96,54.2 103.38,55.63 103.38,56.31 103.33,56.36 103.33,56.93 103.38,56.98 103.38,58.04 104.52,59.18 104.52,59.69 104.95,60.12 v2(104.95,60.2)
GXB_RX3M: length 88.5
  TOP w0.114: U5.V34 v2(106.95,59.2) ; J2.21 56.3,4.19 56.41,4.08 56.41,1.81 v1(56.12,1.52)
  L3-SIG1 w0.102: v1(56.12,1.52) 56.49,1.9 56.49,2.91 57.03,3.45 65.68,3.45 70.1,7.87 70.1,14.48 82.55,26.92 82.55,26.94 104.62,49.01 104.62,55.61 105.38,56.38 105.38,57.01 105.87,57.49 105.87,57.75 106.69,58.57 106.8,58.57 106.95,58.72 v2(106.95,59.2)
GXB_RX3P: length 89.5
  TOP w0.114: J2.23 56.8,4.19 56.68,4.08 56.68,1.78 v1(56.94,1.52) ; U5.V33 v2(106.95,60.2)
  L3-SIG1 w0.102: v2(106.95,60.2) 106.95,59.8 107.34,59.41 107.34,58.78 106.86,58.29 106.81,58.29 106.15,57.63 106.15,57.38 105.66,56.9 105.66,56.26 104.9,55.5 104.9,48.9 82.83,26.82 82.83,26.81 70.38,14.36 70.38,7.76 65.8,3.17 57.15,3.17 56.77,2.79 56.77,1.69 v1(56.94,1.52)
GXB_RX4M: length 88.8
  TOP w0.114: U5.T34 v2(109.95,59.2) ; J2.27 57.8,4.19 57.91,4.08 57.91,2.67 57.65,2.41 v1(57.53,2.41)
  L4-SIG2 w0.102: v2(109.95,59.2) 109.87,59.2 109.86,59.19 109.74,59.19 109.57,59.02 109.57,58.94 108.96,58.33 108.84,58.33 108.81,58.31 101.66,58.31 101.65,58.29 101.65,58.18 100.74,57.26 100.74,53.1 76.09,28.45 74.17,28.45 56.67,10.95 56.67,2.91 57.16,2.41 v1(57.53,2.41)
GXB_RX4P: length 91.2
  TOP w0.114: v1(58.01,1.88) 58.04,1.91 58.04,2.41 58.18,2.55 58.18,4.06 58.3,4.17 J2.29 ; U5.T33 v2(109.95,60.2)
  L4-SIG2 w0.102: v1(58.01,1.88) 57.94,1.88 57.91,1.91 57.28,1.91 56.39,2.79 56.39,11.06 74.05,28.73 75.97,28.73 100.46,53.21 100.46,57.38 101.37,58.29 101.37,58.35 101.57,58.54 108.72,58.54 108.74,58.57 108.86,58.57 109.33,59.04 109.33,59.12 109.6,59.39 109.6,59.82 109.95,60.17 v2(109.95,60.2)
GXB_RX5M: length 88
  TOP w0.114: J2.33 59.3,4.2 59.44,4.06 59.44,2.41 v1(59.12,2.1) ; U5.P34 v2(111.95,59.2)
  L4-SIG2 w0.102: v1(59.12,2.1) 58.55,2.67 58.55,4.57 59.41,5.44 61.84,5.44 62.76,6.36 62.76,7.25 63.36,7.85 64.76,7.85 67.06,10.15 67.06,16.62 68.61,18.17 68.61,18.19 77.19,26.77 104.52,54.1 106.58,54.1 108.1,55.63 108.1,56.78 108.58,57.25 110.17,57.25 110.98,58.07 110.98,58.36 111.83,59.2 v2(111.95,59.2)
GXB_RX5P: length 90.8
  TOP w0.114: J2.35 59.8,4.19 59.72,4.11 59.72,2.3 59.7,2.28 v1(59.7,1.52) ; U5.P33 v2(111.95,60.2)
  L4-SIG2 w0.102: v2(111.95,60.2) 111.47,59.72 111.47,59.18 110.75,58.46 110.75,58.45 110.7,58.41 110.7,58.18 110.06,57.53 108.46,57.53 107.82,56.9 107.82,55.74 106.46,54.38 104.41,54.38 81.17,31.14 77.07,27.05 68.33,18.3 68.33,18.29 66.78,16.74 66.78,10.26 64.64,8.13 63.25,8.13 62.48,7.37 62.48,6.48 61.72,5.71 59.29,5.71 58.27,4.69 58.27,2.19 58.95,1.52 v1(59.7,1.52)
GXB_RX6M: length 91.1
  TOP w0.114: J2.39 60.8,4.19 60.91,4.08 60.91,2.6 v1(60.61,2.31) ; U5.H34 v2(117.95,59.2)
  L3-SIG1 w0.102: v1(60.61,2.31) 60.93,1.99 60.93,1.28 61.35,0.86 62.73,0.86 63.01,1.14 67.32,1.14 72.54,6.36 72.54,12.09 92.85,32.4 92.86,32.4 112.29,51.83 112.29,52.97 115.93,56.6 115.93,56.81 115.98,56.86 115.98,57.8 116.24,58.05 116.81,58.05 117.59,58.83 117.59,58.93 117.86,59.2 v2(117.95,59.2)
GXB_RX6P: length 91.1
  TOP w0.114: J2.41 61.3,4.19 61.18,4.08 61.18,2.19 v1(61.34,2.03) ; U5.H33 v2(117.95,60.2)
  L3-SIG1 w0.102: v2(117.95,60.2) 117.95,60.17 117.35,59.56 117.35,58.93 116.71,58.29 116.08,58.29 115.7,57.91 115.7,56.98 115.65,56.93 115.65,56.72 112.01,53.09 112.01,51.94 92.75,32.68 92.73,32.68 72.26,12.21 72.26,6.48 67.21,1.42 62.89,1.42 62.61,1.14 61.47,1.14 61.21,1.4 61.21,1.88 61.34,2.01 v1(61.34,2.03)
GXB_RX7M: length 91.6
  TOP w0.114: J2.45 62.3,4.17 62.41,4.06 62.41,2.86 v1(62.09,2.54) ; U5.F34 v2(119.95,59.2)
  L4-SIG2 w0.102: v1(62.09,2.54) 62.36,2.27 62.36,1.36 62.67,1.04 68.11,1.04 71.53,4.46 71.53,7.76 113.81,50.04 115.84,50.04 118.64,52.84 118.64,57.54 119.95,58.85 v2(119.95,59.2)
GXB_RX7P: length 91.8
  TOP w0.114: J2.47 62.8,4.19 62.68,4.08 62.68,2.76 v1(62.91,2.54) ; U5.F33 v2(119.95,60.2)
  L4-SIG2 w0.102: v2(119.95,60.2) 119.95,60.13 119.51,59.69 119.51,58.8 118.36,57.66 118.36,52.96 115.72,50.32 113.69,50.32 71.25,7.87 71.25,4.57 68,1.32 62.79,1.32 62.64,1.47 62.64,2.27 v1(62.91,2.54)
GXB_TX0M: length 86.1
  TOP w0.114: U5.AG32 v2(97.95,61.2) ; J2.4 51.8,12.06 51.91,12.18 51.91,30.08 58.05,36.22 79.13,36.22 90.05,47.14 94.01,47.14 98.93,52.07 98.93,55.14 99.42,55.63 99.42,56.41 v1(99.19,56.64)
  L3-SIG1 w0.102: v1(99.19,56.64) 99.4,56.85 99.4,57.69 98.33,58.75 98.33,60.87 98.01,61.2 v2(97.95,61.2)
GXB_TX0P: length 87.2
  TOP w0.114: U5.AG31 v2(97.95,62.2) ; J2.6 52.3,12.06 52.18,12.18 52.18,29.96 58.17,35.94 79.25,35.94 90.17,46.86 94.12,46.86 99.21,51.95 99.21,55.03 99.69,55.51 99.69,56.39 v1(99.95,56.64)
  L3-SIG1 w0.102: v1(99.95,56.64) 99.68,56.91 99.68,57.8 98.57,58.91 98.57,61.12 97.95,61.74 v2(97.95,62.2)
GXB_TX1M: length 85.9
  TOP w0.114: U5.AE32 v2(99.95,61.2) ; J2.10 53.3,12.06 53.41,12.18 53.41,28.02 59.45,34.06 81.29,34.06 92.21,44.98 94.12,44.98 100.3,51.17 100.3,54.22 101.84,55.75 101.84,56.29 v1(101.47,56.66)
  L3-SIG1 w0.102: v2(99.95,61.2) 100.33,60.82 100.33,60.36 100.33,59.36 100.33,58.79 101.7,57.42 101.7,56.88 v1(101.47,56.66)
GXB_TX1P: length 86.9
  TOP w0.114: J2.12 53.8,12.06 53.68,12.18 53.68,27.9 59.56,33.78 81.41,33.78 92.33,44.7 94.23,44.7 100.58,51.05 100.58,54.1 102.12,55.64 102.12,56.53 v1(102.23,56.64) ; U5.AE31 v2(99.95,62.2)
  L3-SIG1 w0.102: v2(99.95,62.2) 99.95,61.74 100.57,61.12 100.57,58.94 101.98,57.53 101.98,56.9 v1(102.23,56.64)
GXB_TX2M: length 86.1
  TOP w0.114: J2.16 54.8,12.06 54.91,12.18 54.91,26.09 59.96,31.14 82.43,31.14 101.7,50.41 101.7,52.54 104.3,55.14 104.3,56.16 104.29,56.27 104.29,56.27 104.27,56.38 v1(104.01,56.64) ; U5.W32 v2(105.95,61.2)
  L3-SIG1 w0.102: v2(105.95,61.2) 106.33,60.82 106.33,59 105.86,58.53 105.39,58.53 104.27,57.4 104.27,56.9 v1(104.01,56.64)
GXB_TX2P: length 87.1
  TOP w0.114: J2.18 55.3,12.06 55.18,12.18 55.18,25.97 60.07,30.86 82.55,30.86 101.98,50.29 101.98,52.43 104.58,55.02 104.58,56.17 104.56,56.3 104.55,56.42 v1(104.78,56.64) ; U5.W31 v2(105.95,62.2)
  L3-SIG1 w0.102: v1(104.78,56.64) 104.55,56.87 104.55,57.29 105.55,58.29 105.96,58.29 106.57,58.9 106.57,61.2 105.95,61.82 v2(105.95,62.2)
GXB_TX3M: length 87.5
  TOP w0.114: J2.22 56.3,12.06 56.41,12.18 56.41,24.03 61.23,28.85 84.35,28.85 103.61,48.11 103.61,51.91 106.4,54.7 106.4,56.44 106.16,56.68 v1(106.16,56.68) ; U5.U32 v2(108.95,61.2)
  L3-SIG1 w0.102: v2(108.95,61.2) 109.33,60.82 109.33,59.04 108.58,58.29 107.42,58.29 106.43,57.3 106.43,56.95 v1(106.16,56.68)
GXB_TX3P: length 88.5
  TOP w0.114: J2.24 56.8,12.08 56.68,12.19 56.68,23.92 61.34,28.57 84.47,28.57 103.89,47.99 103.89,51.79 106.68,54.58 106.68,56.39 v1(106.93,56.64) ; U5.U31 v2(108.95,62.2)
  L3-SIG1 w0.102: v1(106.93,56.64) 106.71,56.87 106.71,57.18 107.54,58.01 108.71,58.01 109.57,58.87 109.57,60.36 109.58,60.36 109.58,61.11 108.95,61.74 v2(108.95,62.2)
GXB_TX4M: length 87.8
  TOP w0.114: J2.28 57.8,12.06 57.91,12.18 57.91,22.6 61.62,26.31 85.74,26.31 105.74,46.32 105.74,51.51 109.47,55.24 109.47,56.39 v1(109.22,56.64) ; U5.R32 v2(110.95,61.2)
  L3-SIG1 w0.102: v1(109.22,56.64) 109.47,56.9 109.47,57.55 110.5,58.57 110.88,58.57 111.33,59.02 111.33,60.82 v2(110.95,61.2)
GXB_TX4P: length 88.9
  TOP w0.114: U5.R31 v2(110.95,62.2) ; v1(110.11,56.64) 109.75,56.29 109.75,55.13 106.02,51.4 106.02,46.2 85.85,26.04 61.74,26.04 58.18,22.48 58.18,12.19 58.3,12.08 J2.30
  L3-SIG1 w0.102: v2(110.95,62.2) 110.95,61.77 111.57,61.15 111.57,58.92 110.94,58.29 110.62,58.29 109.75,57.43 109.75,57 v1(110.11,56.64)
GXB_TX5M: length 88.2
  TOP w0.114: J2.34 59.3,12.08 59.41,12.19 59.41,20.16 63.4,24.16 88.16,24.16 109.58,45.57 109.58,52.57 111.86,54.85 111.86,56.41 111.77,56.51 111.77,56.51 v1(111.63,56.64) ; U5.N32 v2(112.95,61.2)
  L3-SIG1 w0.102: v2(112.95,61.2) 113.33,60.82 113.33,58.87 113.13,58.67 111.86,57.4 111.86,56.87 v1(111.63,56.64)
GXB_TX5P: length 89.3
  TOP w0.114: J2.36 59.8,12.06 59.68,12.18 59.68,20.05 63.51,23.88 88.28,23.88 109.86,45.45 109.86,52.45 112.14,54.74 112.14,56.39 v1(112.39,56.64) ; U5.N31 v2(112.95,62.2)
  L3-SIG1 w0.102: v2(112.95,62.2) 112.95,61.74 113.57,61.12 113.57,58.71 112.14,57.29 112.14,56.9 v1(112.39,56.64)
GXB_TX6M: length 91.4
  TOP w0.114: v1(114.17,56.64) 114.17,56.64 114.4,56.41 114.4,55.47 111.63,52.7 111.63,44.2 89.69,22.25 64.92,22.25 60.91,18.23 60.91,12.21 60.8,12.1 J2.40 ; U5.G32 v2(118.95,61.2)
  L3-SIG1 w0.102: v1(114.17,56.64) 114.17,56.67 114.4,56.9 114.4,57.9 115.33,58.83 115.33,60.51 115.64,60.82 118.57,60.82 v2(118.95,61.2)
GXB_TX6P: length 92.8
  TOP w0.114: U5.G31 v2(118.95,62.2) ; J2.42 61.3,12.06 61.18,12.18 61.18,18.12 65.04,21.97 89.8,21.97 111.91,44.08 111.91,52.59 114.68,55.36 114.68,56.41 v1(114.91,56.64)
  L3-SIG1 w0.102: v2(118.95,62.2) 119.38,61.77 119.38,61.05 118.91,60.58 115.79,60.58 115.57,60.36 115.57,58.66 115.24,58.33 115.23,58.33 114.68,57.78 114.68,56.9 114.91,56.67 v1(114.91,56.64)
GXB_TX7M: length 91.7
  TOP w0.114: J2.46 62.3,12.06 62.41,12.18 62.41,16.81 65.68,20.09 91.34,20.09 113.89,42.65 113.89,52.43 116.61,55.14 116.61,56.37 v1(116.33,56.64) ; U5.E32 v2(120.95,61.2)
  L3-SIG1 w0.102: v1(116.33,56.64) 116.44,56.75 116.44,56.77 116.46,56.78 116.46,56.78 116.56,56.88 116.56,57.27 117.84,58.55 119.94,58.55 120.33,58.94 120.33,60.58 120.51,60.76 v2(120.95,61.2)
GXB_TX7P: length 92.9
  TOP w0.114: J2.48 62.8,12.06 62.68,12.18 62.68,16.7 65.8,19.81 91.45,19.81 114.17,42.53 114.17,52.31 116.89,55.02 116.89,56.44 v1(117.09,56.64) ; U5.E31 v2(120.95,62.2)
  L3-SIG1 w0.102: v2(120.95,62.2) 121.33,61.82 121.33,61.01 121.12,60.8 120.97,60.8 120.57,60.4 120.57,58.82 120.04,58.29 117.98,58.29 116.84,57.15 116.84,56.9 v1(117.09,56.64)
INPUT0_M: length 118.6
  TOP w0.114: U5.AE29 v2(99.95,64.2)
  L10-SIG4 w0.102: v2(99.95,64.2) 99.79,64.36 99.16,64.36 98.98,64.54 98.98,64.69 99.57,65.28 99.57,65.44 99.71,65.58 100.21,65.58 100.28,65.66 100.32,65.66 100.46,65.8 100.46,65.83 100.57,65.94 100.57,66.46 100.69,66.58 101.21,66.58 101.57,66.94 101.57,67.36 101.62,67.41 101.62,67.99 101.57,68.04 101.57,68.36 101.58,68.37 101.58,70.03 101.57,70.04 101.57,70.36 101.58,70.37 101.58,70.57 101.93,70.92 101.93,72.82 102.69,73.58 103.21,73.58 103.57,73.94 103.57,93.89 104.07,94.4 104.07,129.69 104.17,129.79 104.51,129.79 104.78,130.05 104.78,130.49 104.51,130.75 104.17,130.75 104.07,130.86 104.07,131.06 104.17,131.16 104.51,131.16 104.78,131.43 104.78,131.86 104.51,132.13 104.48,132.13 104.07,132.53 104.07,133.65 104.8,134.38 104.8,134.81 104.54,135.08 104.54,135.48 104.8,135.75 104.8,136.18 104.54,136.45 104.54,136.86 104.8,137.12 104.8,137.56 104.54,137.82 104.43,137.82 104.14,138.11 104.14,139.51 106.02,141.39 106.02,145.17 110.12,149.28 125.5,149.28 126.57,148.21 126.57,146.76 126.21,146.41 125.48,146.41 124.84,147.04 124.84,148.08 v1(125.09,148.34)
  BOTTOM w0.114: J3.2 124.84,149.83 124.84,148.59 v1(125.09,148.34)
INPUT0_P: length 118.6
  TOP w0.114: U5.AF28 v2(98.95,65.2)
  L10-SIG4 w0.102: v1(124.33,148.34) 124.56,148.11 124.56,146.92 125.36,146.13 126.33,146.13 126.85,146.65 126.85,148.32 125.62,149.56 110.01,149.56 105.74,145.29 105.74,141.5 103.86,139.62 103.86,137.99 104.31,137.54 104.42,137.54 104.52,137.44 104.52,137.24 104.26,136.97 104.26,136.33 104.52,136.07 104.52,135.87 104.26,135.6 104.26,134.96 104.52,134.7 104.52,134.49 103.79,133.77 103.79,132.41 104.36,131.85 104.39,131.85 104.5,131.74 104.5,131.54 104.39,131.44 104.06,131.44 103.79,131.17 103.79,130.74 104.06,130.47 104.39,130.47 104.5,130.37 104.5,130.17 104.39,130.07 104.06,130.07 103.79,129.8 103.79,94.7 103.33,94.23 103.33,74.04 103.11,73.82 102.59,73.82 101.69,72.92 101.69,71.02 101.35,70.67 101.35,70.47 101.33,70.46 101.33,69.94 101.35,69.93 101.35,68.47 101.33,68.46 101.33,67.94 101.38,67.89 101.38,67.51 101.33,67.46 101.33,67.04 101.11,66.82 100.59,66.82 100.33,66.56 100.33,66.04 100.22,65.93 100.22,65.91 100.2,65.9 100.19,65.9 100.11,65.82 99.61,65.82 99.33,65.54 99.33,65.44 99.09,65.2 v2(98.95,65.2)
  BOTTOM w0.114: v1(124.33,148.34) 124.55,148.55 124.55,149.83 J3.4
INPUT1_M: length 118.5
  TOP w0.114: U5.AD29 101.42,64.7 100.95,64.23 v2(100.95,64.2)
  L10-SIG4 w0.102: v2(100.95,64.2) 100.75,64.2 100.59,64.36 100.59,64.5 100.67,64.58 101.21,64.58 101.57,64.94 101.57,65.36 101.79,65.58 102.21,65.58 102.6,65.97 102.6,66.01 102.57,66.04 102.57,66.36 102.6,66.39 102.6,67.01 102.57,67.04 102.57,67.36 102.6,67.39 102.6,68.01 102.57,68.04 102.57,68.36 102.6,68.39 102.6,68.43 102.47,68.56 102.47,69.62 103.57,70.72 103.57,71.62 103.58,71.63 103.58,72.03 103.57,72.04 103.57,72.36 103.79,72.58 104.21,72.58 104.57,72.94 104.57,93.55 104.85,93.83 104.87,93.83 105.5,94.45 105.5,97.8 105.82,98.12 105.82,107.2 108.58,109.97 108.58,111.37 107.9,112.05 107.9,112.26 108,112.36 108.5,112.36 108.76,112.62 108.76,113.06 108.5,113.32 108,113.32 107.9,113.42 107.9,113.63 108,113.73 108.5,113.73 108.76,113.99 108.76,114.43 108.5,114.69 108,114.69 107.9,114.8 107.9,115 108,115.1 108.5,115.1 108.76,115.37 108.76,115.8 108.5,116.07 108,116.07 107.9,116.17 107.9,116.37 108,116.47 108.5,116.47 108.76,116.74 108.76,117.17 108.5,117.44 108,117.44 107.9,117.54 107.9,117.74 108,117.84 108.5,117.84 108.76,118.11 108.76,118.54 108.5,118.81 108,118.81 107.9,118.91 107.9,119.11 108,119.21 108.5,119.21 108.76,119.48 108.76,119.91 108.5,120.18 108,120.18 107.9,120.28 107.9,120.48 108,120.59 108.5,120.59 108.76,120.85 108.76,121.29 108.5,121.55 108,121.55 107.9,121.65 107.9,121.86 108,121.96 108.5,121.96 108.76,122.22 108.76,122.66 108.5,122.92 108,122.92 107.9,123.02 107.9,123.23 108,123.33 108.5,123.33 108.76,123.59 108.76,124.03 108.5,124.29 108,124.29 107.9,124.4 107.9,124.6 108,124.7 108.5,124.7 108.76,124.97 108.76,125.4 108.5,125.67 108,125.67 107.9,125.77 107.9,125.97 108,126.07 108.5,126.07 108.76,126.34 108.76,126.77 108.5,127.04 108.09,127.04 108,127.13 108,127.43 108.33,127.76 108.33,140.87 110.72,143.26 121.55,143.26 123.15,144.85 123.15,147.57 123.41,147.83 v1(123.57,147.83)
  BOTTOM w0.114: J3.8 123.34,149.83 123.34,148.06 v1(123.57,147.83)
INPUT1_P: length 118.5
  TOP w0.114: U5.AE28 v2(99.95,65.2)
  L10-SIG4 w0.102: v2(99.95,65.2) 100.2,65.2 100.58,64.82 101.11,64.82 101.33,65.04 101.33,65.46 101.69,65.82 102.11,65.82 102.33,66.04 102.33,66.46 102.36,66.49 102.36,66.91 102.33,66.94 102.33,67.46 102.36,67.49 102.36,67.91 102.33,67.94 102.33,68.36 102.23,68.46 102.23,69.71 103.33,70.82 103.33,72.52 103.63,72.82 104.11,72.82 104.33,73.04 104.33,93.79 105.22,94.68 105.22,97.92 105.54,98.24 105.54,107.31 108.31,110.08 108.31,111.25 107.62,111.94 107.62,112.37 107.89,112.64 108.38,112.64 108.48,112.74 108.48,112.94 108.38,113.04 107.89,113.04 107.62,113.31 107.62,113.74 107.89,114.01 108.38,114.01 108.48,114.11 108.48,114.31 108.38,114.41 107.89,114.41 107.62,114.68 107.62,115.11 107.89,115.38 108.38,115.38 108.48,115.48 108.48,115.68 108.38,115.79 107.89,115.79 107.62,116.05 107.62,116.49 107.89,116.75 108.38,116.75 108.48,116.85 108.48,117.06 108.38,117.16 107.89,117.16 107.62,117.42 107.62,117.86 107.89,118.12 108.38,118.12 108.48,118.22 108.48,118.43 108.38,118.53 107.89,118.53 107.62,118.79 107.62,119.23 107.89,119.49 108.38,119.49 108.48,119.6 108.48,119.8 108.38,119.9 107.89,119.9 107.62,120.17 107.62,120.6 107.89,120.87 108.38,120.87 108.48,120.97 108.48,121.17 108.38,121.27 107.89,121.27 107.62,121.54 107.62,121.97 107.89,122.24 108.38,122.24 108.48,122.34 108.48,122.54 108.38,122.64 107.89,122.64 107.62,122.91 107.62,123.34 107.89,123.61 108.38,123.61 108.48,123.71 108.48,123.91 108.38,124.02 107.89,124.02 107.62,124.28 107.62,124.72 107.89,124.98 108.38,124.98 108.48,125.08 108.48,125.29 108.38,125.39 107.89,125.39 107.62,125.65 107.62,126.09 107.89,126.35 108.38,126.35 108.48,126.45 108.48,126.66 108.38,126.76 107.89,126.76 107.62,127.02 107.62,127.46 107.89,127.72 108.05,127.89 108.05,128.14 107.87,128.32 107.87,128.54 108.05,128.72 108.05,128.95 107.87,129.13 107.87,129.36 108.05,129.53 108.05,140.98 110.6,143.54 121.44,143.54 122.86,144.96 122.86,147.78 v1(122.81,147.83)
  BOTTOM w0.114: J3.10 123.05,149.83 123.05,148.07 v1(122.81,147.83)
INPUT2_M: length 118.4
  TOP w0.114: U5.AL6 v2(93.95,88.2)
  L9-SIG3 w0.102: v2(93.95,88.2) 93.57,87.82 91.79,87.82 91.57,88.04 91.57,90.46 91.56,90.47 91.56,90.72 90.66,91.61 90.66,94.07 90.7,94.11 90.7,106.38 90.93,106.6 91.23,106.6 91.49,106.87 91.49,107.3 91.23,107.57 90.93,107.57 90.83,107.67 90.83,107.87 90.93,107.98 91.23,107.98 91.49,108.24 91.49,108.68 91.23,108.94 90.93,108.94 90.83,109.04 90.83,109.25 90.93,109.35 91.23,109.35 91.49,109.61 91.49,110.05 91.23,110.31 90.93,110.31 90.83,110.41 90.83,110.62 90.93,110.72 91.23,110.72 91.49,110.98 91.49,111.42 91.23,111.68 90.93,111.68 90.83,111.79 90.83,111.99 90.93,112.09 91.23,112.09 91.49,112.36 91.49,112.79 91.23,113.06 90.93,113.06 90.83,113.16 90.83,113.36 90.93,113.46 91.23,113.46 91.49,113.73 91.49,114.16 91.23,114.43 90.93,114.43 90.83,114.53 90.83,114.73 90.93,114.83 91.23,114.83 91.49,115.1 91.49,115.53 91.23,115.8 90.93,115.8 90.83,115.9 90.83,116.1 90.93,116.21 91.23,116.21 91.49,116.47 91.49,116.91 91.23,117.17 90.93,117.17 90.83,117.27 90.83,117.48 90.93,117.58 91.23,117.58 91.49,117.84 91.49,118.28 91.23,118.54 90.93,118.54 90.83,118.64 90.83,118.85 90.93,118.95 91.23,118.95 91.49,119.21 91.49,119.65 91.23,119.91 90.93,119.91 90.83,120.02 90.83,120.22 90.93,120.32 91.23,120.32 91.49,120.59 91.49,121.02 91.23,121.29 90.93,121.29 90.83,121.39 90.83,121.59 90.93,121.69 91.23,121.69 91.49,121.96 91.49,122.39 91.23,122.66 90.93,122.66 90.83,122.76 90.83,122.96 90.93,123.06 91.23,123.06 91.49,123.33 91.49,123.76 91.23,124.03 90.93,124.03 90.83,124.13 90.83,124.79 90.93,124.89 91.24,124.89 91.34,124.99 91.34,125.2 91.24,125.3 90.93,125.3 90.83,125.4 90.83,125.6 90.93,125.7 91.24,125.7 91.34,125.81 91.34,126.01 91.24,126.11 90.93,126.11 90.83,126.21 90.83,126.42 90.93,126.52 91.24,126.52 91.34,126.62 91.34,126.82 91.24,126.92 90.93,126.92 90.83,127.02 90.83,128.44 88.57,130.7 88.57,135.1 86.36,137.31 86.36,146.67 90.06,150.37 117.85,150.37 117.98,150.24 118.38,150.24 118.51,150.37 120.48,150.37 122.1,148.75 122.1,148.34 v1(122.1,148.34)
  BOTTOM w0.114: J3.14 121.84,149.83 121.84,148.59 v1(122.1,148.34)
INPUT2_P: length 118.5
  TOP w0.114: U5.AM7 v2(92.95,87.2)
  L9-SIG3 w0.102: v2(92.95,87.2) 93.19,87.2 93.29,87.3 93.29,87.54 93.26,87.58 91.69,87.58 91.33,87.94 91.33,90.36 91.32,90.37 91.32,90.62 90.42,91.52 90.42,106.49 90.82,106.88 91.11,106.88 91.21,106.98 91.21,107.19 91.11,107.29 90.82,107.29 90.55,107.55 90.55,107.99 90.82,108.25 91.11,108.25 91.21,108.36 91.21,108.56 91.11,108.66 90.82,108.66 90.55,108.93 90.55,109.36 90.82,109.63 91.11,109.63 91.21,109.73 91.21,109.93 91.11,110.03 90.82,110.03 90.55,110.3 90.55,110.73 90.82,111 91.11,111 91.21,111.1 91.21,111.3 91.11,111.4 90.82,111.4 90.55,111.67 90.55,112.1 90.82,112.37 91.11,112.37 91.21,112.47 91.21,112.67 91.11,112.78 90.82,112.78 90.55,113.04 90.55,113.48 90.82,113.74 91.11,113.74 91.21,113.84 91.21,114.05 91.11,114.15 90.82,114.15 90.55,114.41 90.55,114.85 90.82,115.11 91.11,115.11 91.21,115.21 91.21,115.42 91.11,115.52 90.82,115.52 90.55,115.78 90.55,116.22 90.82,116.48 91.11,116.48 91.21,116.59 91.21,116.79 91.11,116.89 90.82,116.89 90.55,117.16 90.55,117.59 90.82,117.86 91.11,117.86 91.21,117.96 91.21,118.16 91.11,118.26 90.82,118.26 90.55,118.53 90.55,118.96 90.82,119.23 91.11,119.23 91.21,119.33 91.21,119.53 91.11,119.63 90.82,119.63 90.55,119.9 90.55,120.33 90.82,120.6 91.11,120.6 91.21,120.7 91.21,120.9 91.11,121.01 90.82,121.01 90.55,121.27 90.55,121.71 90.82,121.97 91.11,121.97 91.21,122.07 91.21,122.28 91.11,122.38 90.82,122.38 90.55,122.64 90.55,123.08 90.82,123.34 90.98,123.34 91.06,123.42 91.06,123.62 90.93,123.75 90.82,123.75 90.55,124.01 90.55,128.32 88.29,130.58 88.29,134.98 86.08,137.19 86.08,146.79 89.94,150.65 120.6,150.65 122.5,148.74 122.5,148.11 122.33,147.93 121.74,147.93 v1(121.33,148.34)
  BOTTOM w0.114: v1(121.33,148.34) 121.55,148.55 121.55,149.83 J3.16
INPUT3_M: length 118.5
  TOP w0.114: U5.AM5 v2(92.95,89.2)
  L3-SIG1 w0.102: v1(120.57,147.83) 120.57,147.83 120.05,148.35 120.05,149.11 118.59,150.57 90.42,150.57 86.84,146.99 86.84,131.4 86.94,131.29 87.33,131.29 87.43,131.19 87.43,130.99 87.33,130.89 86.94,130.89 86.84,130.79 86.84,130.58 86.94,130.48 87.33,130.48 87.43,130.38 87.43,130.18 87.33,130.08 86.94,130.08 86.84,129.97 86.84,129.77 86.94,129.67 87.33,129.67 87.43,129.57 87.43,129.36 87.33,129.26 86.94,129.26 86.84,129.16 86.84,128.8 86.94,128.7 87.31,128.7 87.58,128.43 87.58,128 87.31,127.73 86.94,127.73 86.84,127.63 86.84,127.43 86.94,127.32 87.31,127.32 87.58,127.06 87.58,126.62 87.31,126.36 86.94,126.36 86.84,126.26 86.84,126.05 86.94,125.95 87.31,125.95 87.58,125.69 87.58,125.25 87.31,124.99 86.94,124.99 86.84,124.89 86.84,124.68 86.94,124.58 87.31,124.58 87.58,124.32 87.58,123.88 87.31,123.62 86.94,123.62 86.84,123.51 86.84,123.31 86.94,123.21 87.31,123.21 87.58,122.94 87.58,122.51 87.31,122.24 86.94,122.24 86.84,122.14 86.84,121.94 86.94,121.84 87.31,121.84 87.58,121.57 87.58,121.14 87.31,120.87 86.94,120.87 86.84,120.77 86.84,120.57 86.94,120.47 87.31,120.47 87.58,120.2 87.58,119.77 87.31,119.5 86.94,119.5 86.84,119.4 86.84,119.2 86.94,119.1 87.31,119.1 87.58,118.83 87.58,118.4 87.31,118.13 86.94,118.13 86.84,118.03 86.84,117.83 86.94,117.72 87.31,117.72 87.58,117.46 87.58,117.02 87.31,116.76 86.94,116.76 86.84,116.66 86.84,116.45 86.94,116.35 87.31,116.35 87.58,116.09 87.58,115.65 87.31,115.39 86.94,115.39 86.84,115.29 86.84,115.08 86.94,114.98 87.31,114.98 87.58,114.72 87.58,114.28 87.31,114.02 86.94,114.02 86.84,113.91 86.84,113.71 86.94,113.61 87.31,113.61 87.58,113.34 87.58,112.91 87.31,112.64 86.94,112.64 86.84,112.54 86.84,112.34 86.94,112.24 87.31,112.24 87.58,111.97 87.58,111.54 87.31,111.27 86.94,111.27 86.84,111.17 86.84,110.97 86.94,110.87 87.31,110.87 87.58,110.6 87.58,110.17 87.31,109.9 86.94,109.9 86.84,109.8 86.84,109.02 88.19,107.67 88.19,103.57 90.14,101.61 90.14,93.07 90.43,92.79 90.68,92.79 92.57,90.9 92.57,89.02 92.76,88.82 92.91,88.82 92.96,88.87 92.96,89.19 v2(92.95,89.2)
  BOTTOM w0.114: v1(120.57,147.83) 120.35,148.05 120.35,149.84 J3.20
INPUT3_P: length 118.6
  TOP w0.114: U5.AM6 v2(92.95,88.2)
  L3-SIG1 w0.102: v2(92.95,88.2) 92.95,88.3 92.33,88.92 92.33,90.8 90.58,92.55 90.27,92.55 89.87,92.96 89.87,101.5 87.91,103.45 87.91,107.55 86.56,108.9 86.56,109.91 86.83,110.18 87.2,110.18 87.3,110.28 87.3,110.48 87.2,110.59 86.83,110.59 86.56,110.85 86.56,111.29 86.83,111.55 87.2,111.55 87.3,111.65 87.3,111.86 87.2,111.96 86.83,111.96 86.56,112.22 86.56,112.66 86.83,112.92 87.2,112.92 87.3,113.02 87.3,113.23 87.2,113.33 86.83,113.33 86.56,113.59 86.56,114.03 86.83,114.29 87.2,114.29 87.3,114.4 87.3,114.6 87.2,114.7 86.83,114.7 86.56,114.97 86.56,115.4 86.83,115.67 87.2,115.67 87.3,115.77 87.3,115.97 87.2,116.07 86.83,116.07 86.56,116.34 86.56,116.77 86.83,117.04 87.2,117.04 87.3,117.14 87.3,117.34 87.2,117.44 86.83,117.44 86.56,117.71 86.56,118.14 86.83,118.41 87.2,118.41 87.3,118.51 87.3,118.71 87.2,118.82 86.83,118.82 86.56,119.08 86.56,119.52 86.83,119.78 87.2,119.78 87.3,119.88 87.3,120.09 87.2,120.19 86.83,120.19 86.56,120.45 86.56,120.89 86.83,121.15 87.2,121.15 87.3,121.25 87.3,121.46 87.2,121.56 86.83,121.56 86.56,121.82 86.56,122.26 86.83,122.52 87.2,122.52 87.3,122.63 87.3,122.83 87.2,122.93 86.83,122.93 86.56,123.2 86.56,123.63 86.83,123.9 87.2,123.9 87.3,124 87.3,124.2 87.2,124.3 86.83,124.3 86.56,124.57 86.56,125 86.83,125.27 87.2,125.27 87.3,125.37 87.3,125.57 87.2,125.67 86.83,125.67 86.56,125.94 86.56,126.37 86.83,126.64 87.2,126.64 87.3,126.74 87.3,126.94 87.2,127.05 86.83,127.05 86.56,127.31 86.56,127.76 86.81,128.01 87.12,128.01 87.25,128.14 87.25,128.3 87.13,128.42 86.83,128.42 86.56,128.68 86.56,147.11 90.31,150.85 118.71,150.85 120.33,149.23 120.33,148.47 120.56,148.23 120.74,148.23 120.98,148 120.98,147.66 120.74,147.42 120.4,147.42 120.38,147.45 120.14,147.45 119.81,147.78 v1(119.81,147.83)
  BOTTOM w0.114: v1(119.81,147.83) 120.05,148.07 120.05,149.83 J3.22
INPUT4_M: length 118.5
  TOP w0.114: U5.AL5 v2(93.95,89.2)
  L3-SIG1 w0.102: v2(93.95,89.2) 94.24,89.2 94.34,89.1 94.34,88.9 94.26,88.82 93.87,88.82 93.57,89.12 93.57,92.04 93.57,92.04 93.57,92.36 93.57,92.36 93.57,93.04 93.57,93.04 93.57,93.46 92.86,94.16 92.86,94.22 92.49,94.6 92.47,94.6 92.07,95 92.07,102.49 90.07,104.5 90.07,105.18 90.17,105.28 90.29,105.28 90.55,105.55 90.55,105.98 90.29,106.25 89.69,106.25 89.59,106.35 89.59,106.55 89.69,106.65 90.29,106.65 90.55,106.92 90.55,107.35 90.29,107.62 89.69,107.62 89.59,107.72 89.59,107.92 89.69,108.02 90.29,108.02 90.55,108.29 90.55,108.72 90.29,108.99 89.69,108.99 89.59,109.09 89.59,109.29 89.69,109.4 90.29,109.4 90.55,109.66 90.55,110.1 90.29,110.36 89.69,110.36 89.59,110.46 89.59,110.67 89.69,110.77 90.29,110.77 90.55,111.03 90.55,111.47 90.29,111.73 89.69,111.73 89.59,111.83 89.59,112.04 89.69,112.14 90.29,112.14 90.55,112.4 90.55,112.84 90.29,113.1 89.69,113.1 89.59,113.21 89.59,113.41 89.69,113.51 90.29,113.51 90.55,113.78 90.55,114.21 90.29,114.48 89.69,114.48 89.59,114.58 89.59,114.78 89.69,114.88 90.29,114.88 90.55,115.15 90.55,115.58 90.29,115.85 89.69,115.85 89.59,115.95 89.59,116.15 89.69,116.25 90.29,116.25 90.55,116.52 90.55,116.95 90.29,117.22 89.69,117.22 89.59,117.32 89.59,117.52 89.69,117.63 90.29,117.63 90.55,117.89 90.55,118.33 90.29,118.59 89.69,118.59 89.59,118.69 89.59,118.9 89.69,119 90.29,119 90.55,119.26 90.55,119.7 90.29,119.96 89.69,119.96 89.59,120.06 89.59,120.27 89.69,120.37 90.29,120.37 90.68,120.76 90.68,120.94 90.29,121.33 89.69,121.33 89.59,121.44 89.59,121.64 89.69,121.74 90.29,121.74 90.68,122.13 90.68,122.31 90.07,122.92 90.07,123.33 90.17,123.43 90.32,123.43 90.42,123.54 90.42,123.74 90.32,123.84 90.17,123.84 90.07,123.94 90.07,124.15 90.17,124.25 90.32,124.25 90.42,124.35 90.42,124.55 90.32,124.65 90.17,124.65 90.07,124.76 90.07,124.96 90.17,125.06 90.32,125.06 90.42,125.16 90.42,125.37 90.32,125.47 90.17,125.47 90.07,125.57 90.07,125.77 90.17,125.87 90.32,125.87 90.42,125.97 90.42,126.18 90.32,126.28 90.17,126.28 90.07,126.38 90.07,126.58 90.17,126.69 90.32,126.69 90.42,126.79 90.42,126.99 90.32,127.09 90.17,127.09 90.07,127.19 90.07,127.4 90.17,127.5 90.32,127.5 90.42,127.6 90.42,127.8 90.32,127.91 90.17,127.91 90.07,128.01 90.07,128.63 89.37,129.32 89.37,129.83 88.54,130.66 88.54,137.91 87.91,138.55 87.91,140.6 89.71,142.4 89.71,148.01 91.49,149.78 118.07,149.78 119.1,148.76 v1(119.1,148.34)
  BOTTOM w0.114: J3.26 118.86,149.85 118.86,148.57 v1(119.1,148.34)
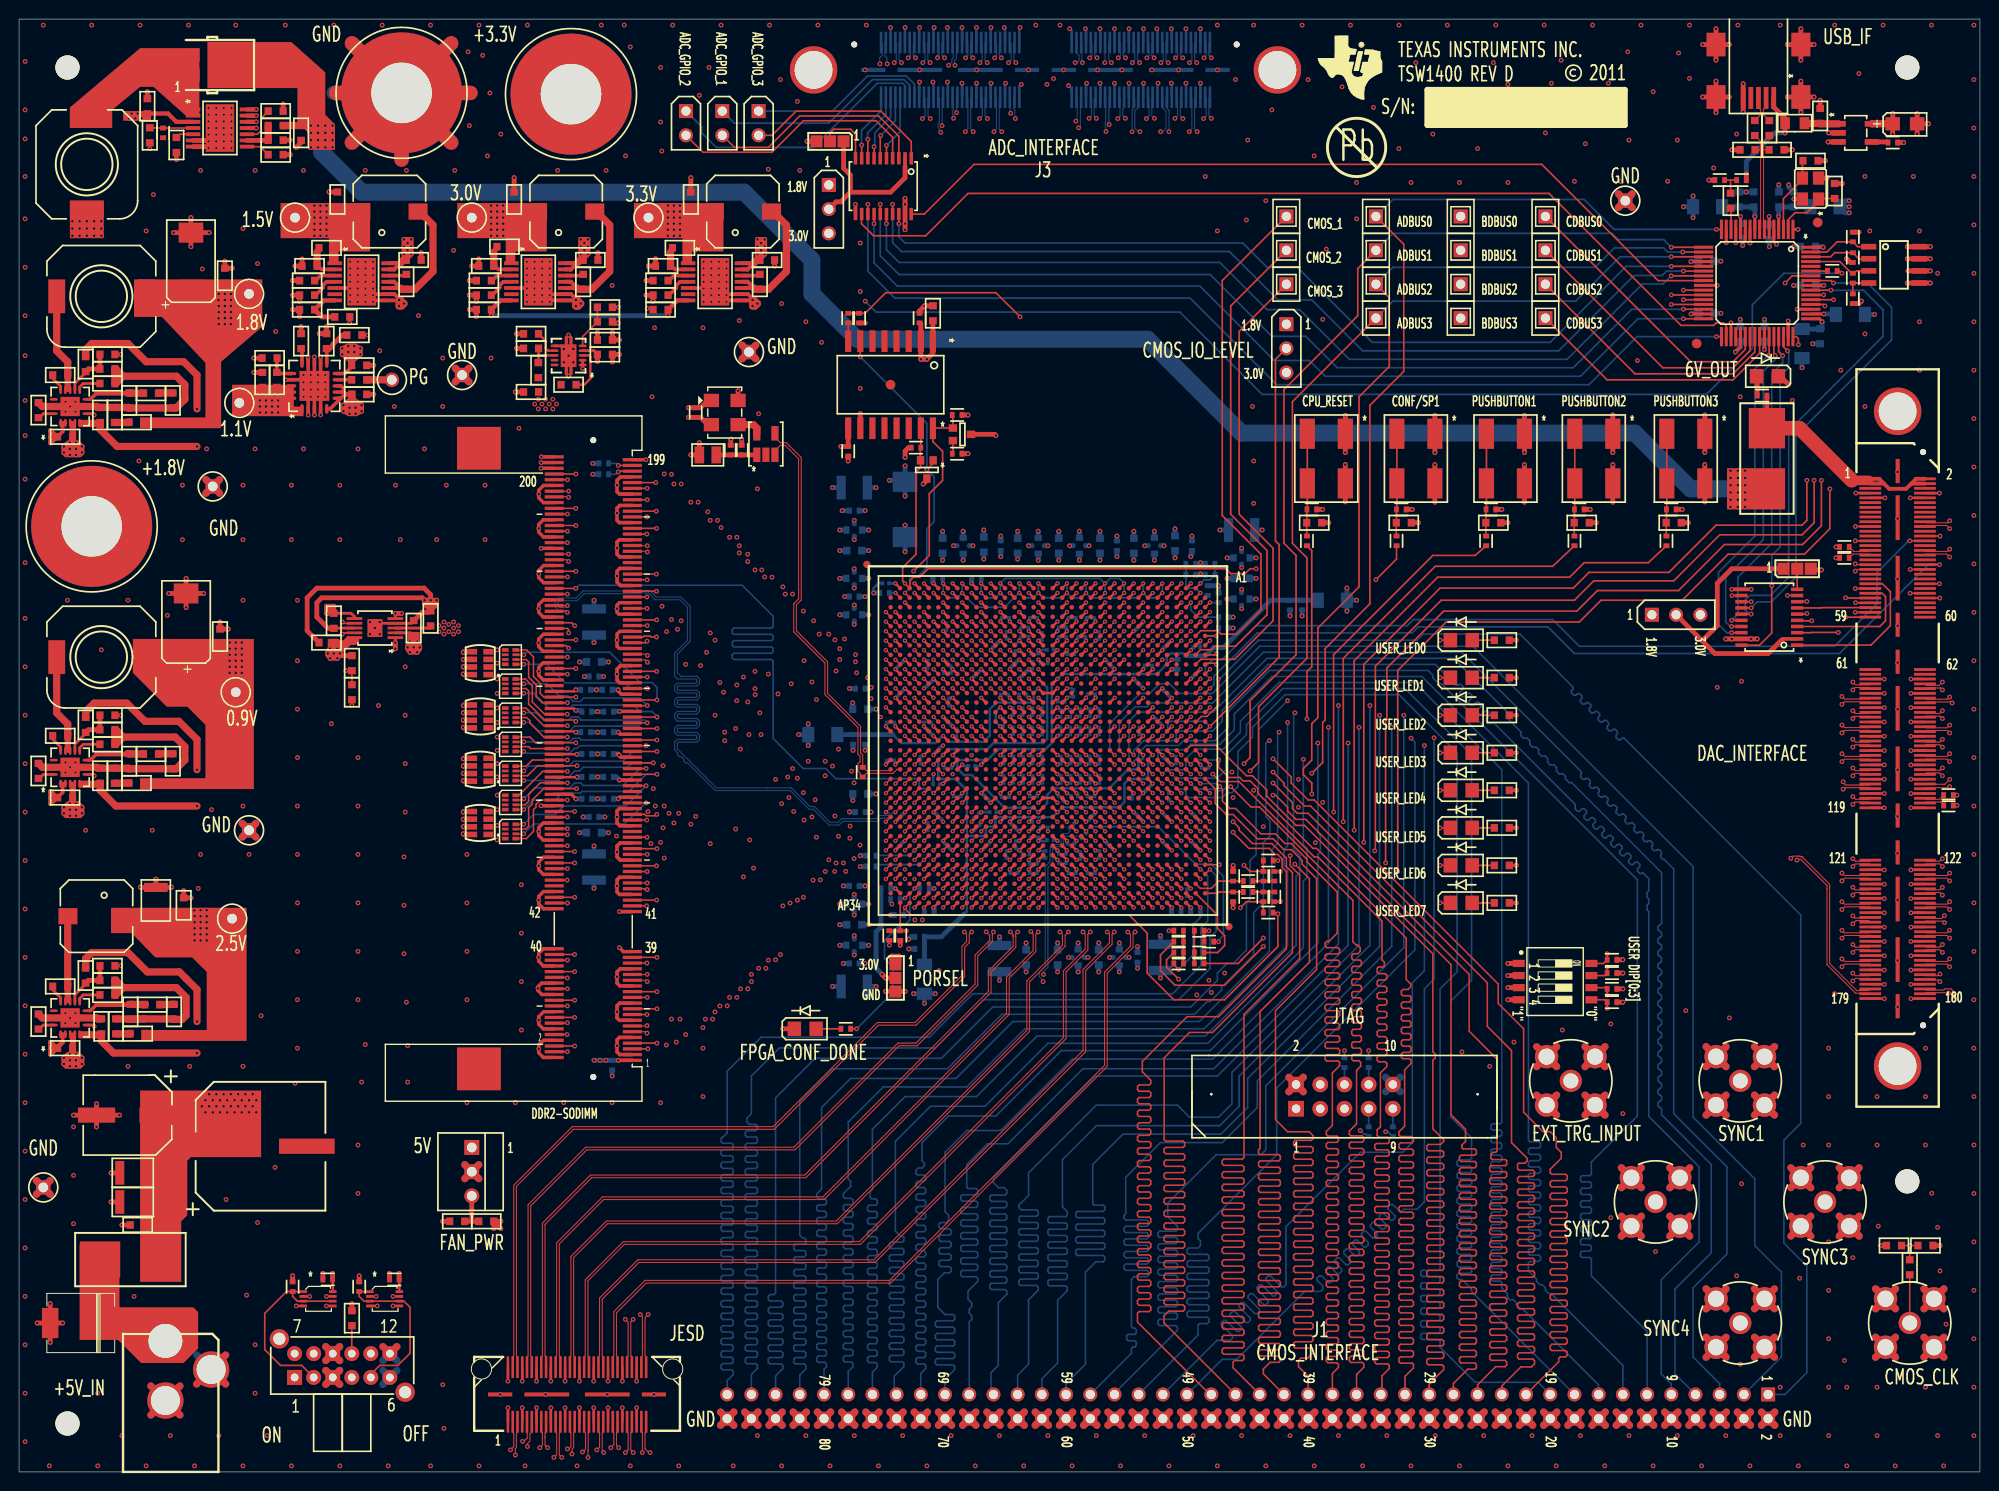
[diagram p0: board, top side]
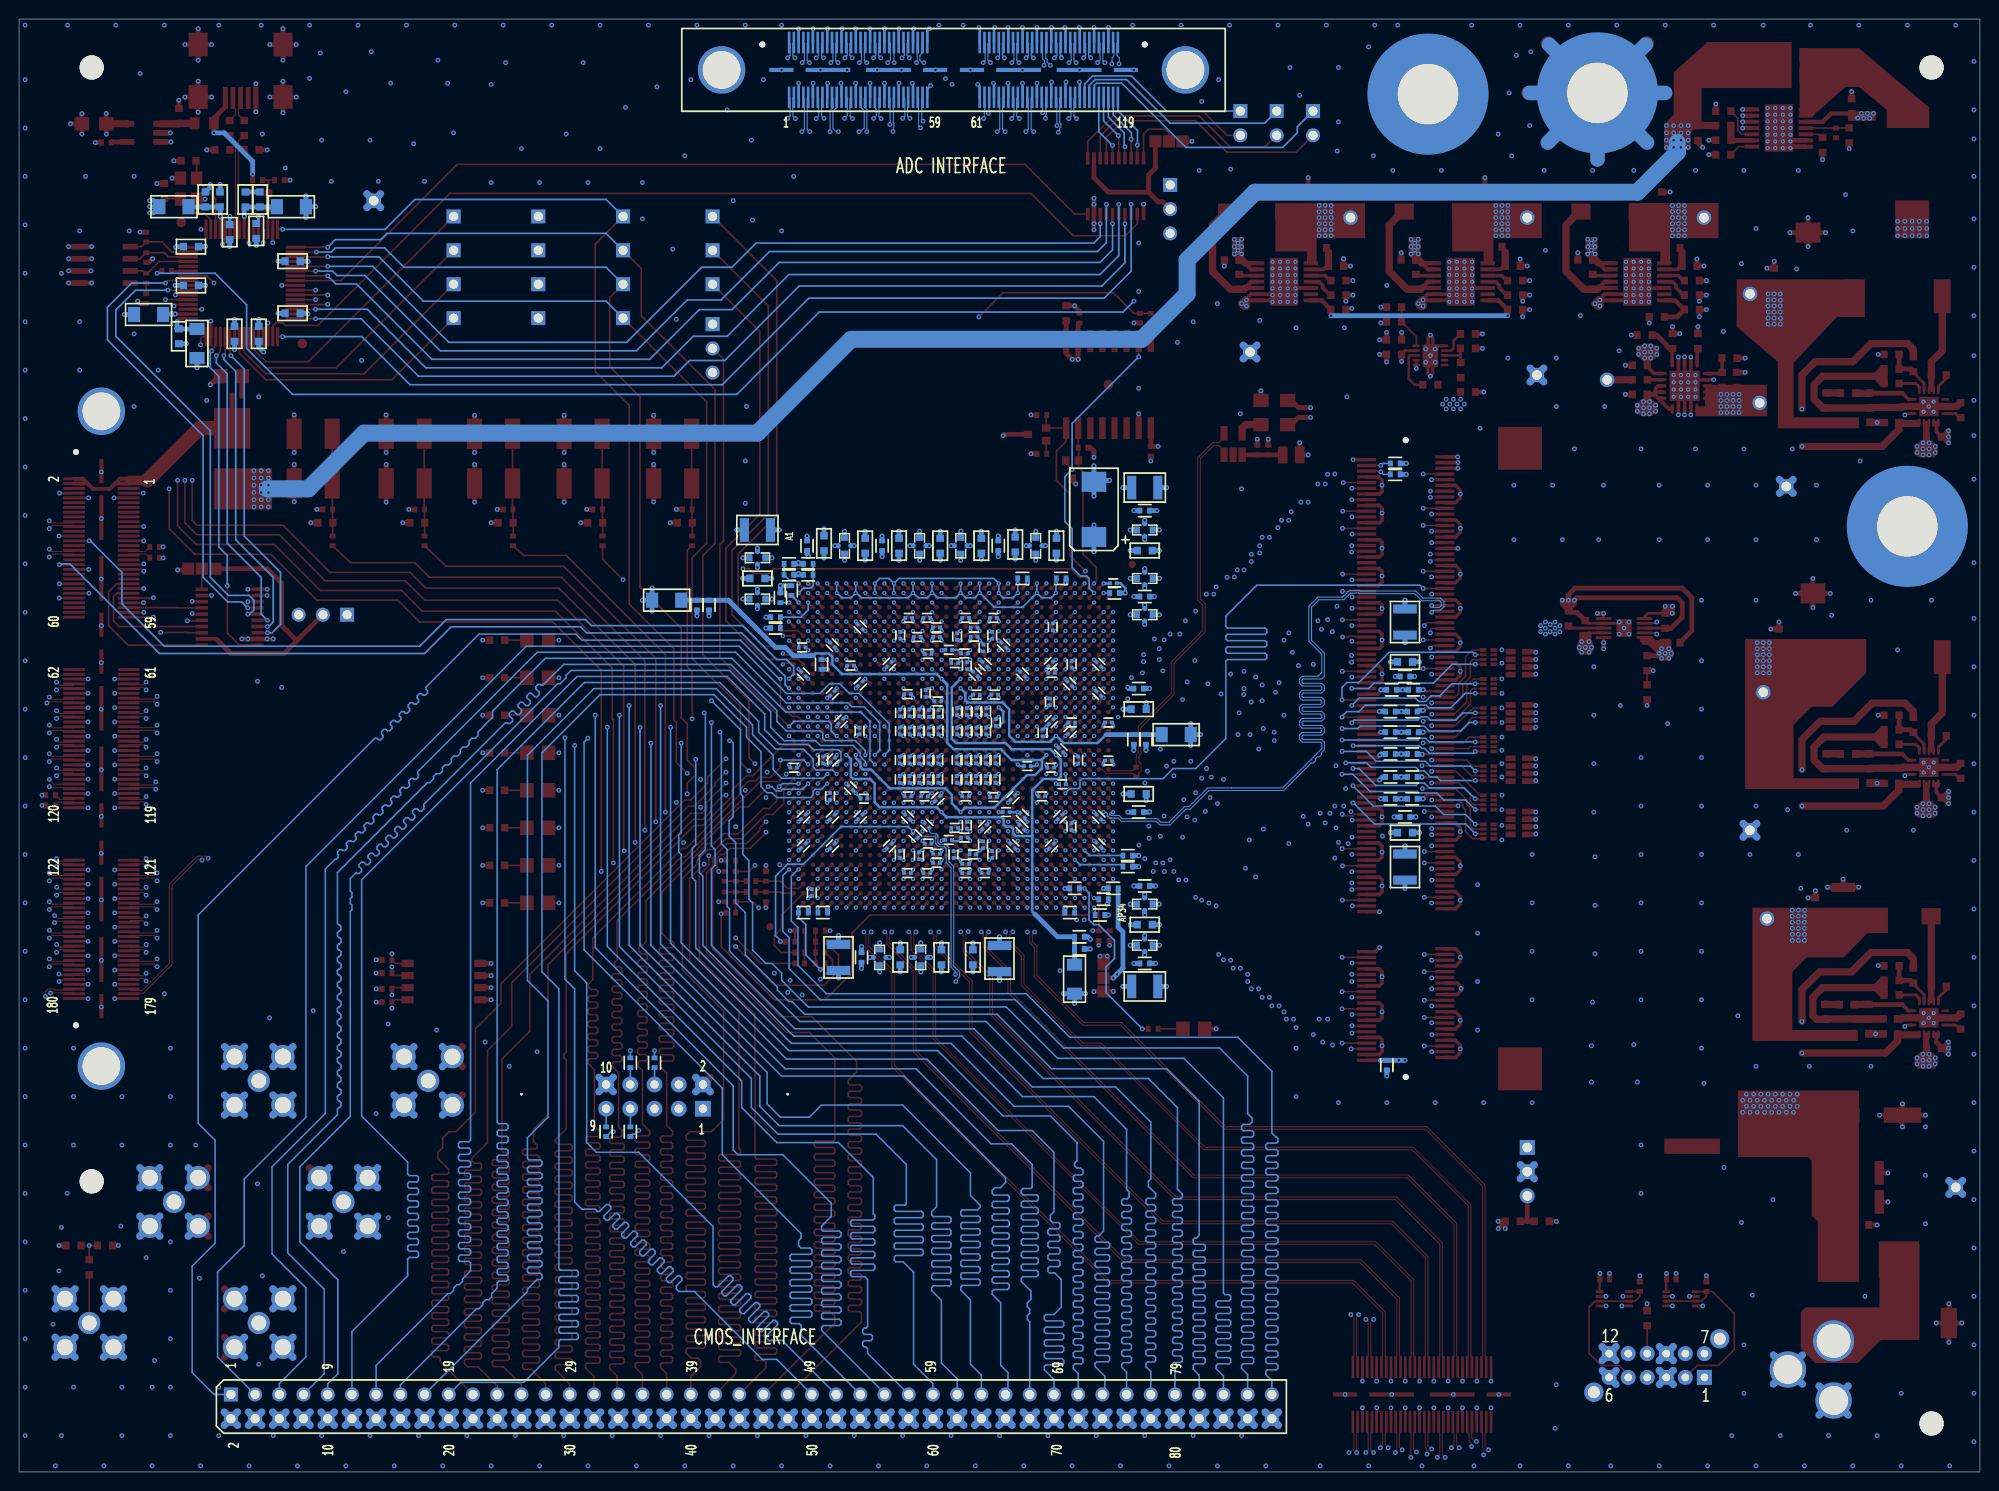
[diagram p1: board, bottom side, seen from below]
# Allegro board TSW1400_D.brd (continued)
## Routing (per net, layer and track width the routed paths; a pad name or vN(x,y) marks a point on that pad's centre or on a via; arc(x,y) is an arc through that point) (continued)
INPUT4_P: length 118.6
  TOP w0.114: U5.AK6 v2(94.95,88.2)
  L3-SIG1 w0.102: v1(118.33,148.34) 118.52,148.34 118.92,147.93 119.28,147.93 119.5,148.15 119.5,148.75 118.19,150.06 91.26,150.06 89.43,148.23 89.43,142.52 87.63,140.72 87.63,138.43 88.27,137.79 88.27,130.54 89.09,129.71 89.09,129.21 89.79,128.51 89.79,122.81 90.27,122.32 90.27,122.17 90.12,122.02 89.57,122.02 89.31,121.75 89.31,121.32 89.57,121.05 90.17,121.05 90.27,120.95 90.27,120.75 90.17,120.65 89.57,120.65 89.31,120.38 89.31,119.95 89.57,119.68 90.17,119.68 90.27,119.58 90.27,119.38 90.17,119.28 89.57,119.28 89.31,119.01 89.31,118.58 89.57,118.31 90.17,118.31 90.27,118.21 90.27,118.01 90.17,117.91 89.57,117.91 89.31,117.64 89.31,117.21 89.57,116.94 90.17,116.94 90.27,116.84 90.27,116.64 90.17,116.53 89.57,116.53 89.31,116.27 89.31,115.83 89.57,115.57 90.17,115.57 90.27,115.47 90.27,115.26 90.17,115.16 89.57,115.16 89.31,114.9 89.31,114.46 89.57,114.2 90.17,114.2 90.27,114.1 90.27,113.89 90.17,113.79 89.57,113.79 89.31,113.53 89.31,113.09 89.57,112.83 90.17,112.83 90.27,112.72 90.27,112.52 90.17,112.42 89.57,112.42 89.31,112.15 89.31,111.72 89.57,111.45 90.17,111.45 90.27,111.35 90.27,111.15 90.17,111.05 89.57,111.05 89.31,110.78 89.31,110.35 89.57,110.08 90.17,110.08 90.27,109.98 90.27,109.78 90.17,109.68 89.57,109.68 89.31,109.41 89.31,108.98 89.57,108.71 90.17,108.71 90.27,108.61 90.27,108.41 90.17,108.3 89.57,108.3 89.31,108.04 89.31,107.6 89.57,107.34 90.17,107.34 90.27,107.24 90.27,107.03 90.17,106.93 89.57,106.93 89.31,106.67 89.31,106.23 89.57,105.97 90.17,105.97 90.27,105.87 90.27,105.66 90.17,105.56 90.05,105.56 89.79,105.3 89.79,104.38 91.79,102.38 91.79,94.88 92.36,94.32 92.37,94.32 92.58,94.11 92.58,94.05 92.72,93.91 92.78,93.91 93.33,93.36 93.33,92.94 93.34,92.94 93.34,92.46 93.33,92.46 93.33,91.94 93.34,91.94 93.34,89.02 93.77,88.59 94.56,88.59 v2(94.95,88.2)
  BOTTOM w0.114: J3.28 118.57,149.81 118.57,148.57 v1(118.33,148.34)
INPUT5_M: length 118.6
  TOP w0.114: U5.AL7 v2(93.95,87.2)
  L9-SIG3 w0.102: v2(93.95,87.2) 94.16,87 94.28,87 94.33,87.04 94.33,88.37 94.12,88.58 92.69,88.58 92.33,88.94 92.33,94.33 93.83,95.83 93.83,101.72 95.86,103.75 95.86,104.95 96.12,105.21 96.57,105.21 96.67,105.32 96.67,105.52 96.57,105.62 96.12,105.62 95.86,105.89 95.86,106.32 96.12,106.59 96.57,106.59 96.67,106.69 96.67,106.89 96.57,106.99 96.12,106.99 95.86,107.26 95.86,107.69 96.12,107.96 96.57,107.96 96.67,108.06 96.67,108.26 96.57,108.36 96.12,108.36 95.86,108.63 95.86,109.06 96.12,109.33 96.57,109.33 96.67,109.43 96.67,109.63 96.57,109.74 96.12,109.74 95.86,110 95.86,110.44 96.12,110.7 96.57,110.7 96.67,110.8 96.67,111.01 96.57,111.11 96.12,111.11 95.86,111.37 95.86,111.81 96.12,112.07 96.57,112.07 96.67,112.17 96.67,112.38 96.57,112.48 96.12,112.48 95.86,112.74 95.86,113.18 96.12,113.44 96.57,113.44 96.67,113.55 96.67,113.75 96.57,113.85 96.12,113.85 95.86,114.12 95.86,114.55 96.12,114.82 96.57,114.82 96.67,114.92 96.67,115.12 96.57,115.22 96.12,115.22 95.86,115.49 95.86,115.92 96.12,116.19 96.57,116.19 96.67,116.29 96.67,116.49 96.57,116.59 96.12,116.59 95.86,116.86 95.86,117.29 96.12,117.56 96.57,117.56 96.67,117.66 96.67,117.86 96.57,117.97 96.12,117.97 95.86,118.23 95.86,118.66 96.12,118.93 96.57,118.93 96.67,119.03 96.67,119.24 96.57,119.34 96.12,119.34 95.86,119.6 95.86,120.04 96.12,120.3 96.57,120.3 96.67,120.4 96.67,120.61 96.57,120.71 96.12,120.71 95.86,120.97 95.86,121.41 96.12,121.67 96.53,121.67 96.6,121.74 96.6,121.92 96.44,122.08 96.12,122.08 95.86,122.35 95.86,122.82 96.39,123.36 96.39,125.53 91.52,130.4 91.52,131.84 90.91,132.45 90.91,134.32 86.94,138.28 86.94,146.5 89.98,149.53 116.69,149.53 117.32,148.89 117.32,148.08 v1(117.57,147.83)
  BOTTOM w0.114: v1(117.57,147.83) 117.35,148.05 117.35,149.84 J3.32
INPUT5_P: length 118.4
  TOP w0.114: U5.AK8 v2(94.95,86.2)
  L9-SIG3 w0.102: v2(94.95,86.2) 94.57,86.58 94.57,88.47 94.22,88.82 92.79,88.82 92.57,89.04 92.57,94.07 92.61,94.11 92.61,94.22 94.11,95.71 94.11,101.6 96.14,103.63 96.14,104.83 96.24,104.93 96.69,104.93 96.95,105.2 96.95,105.63 96.69,105.9 96.24,105.9 96.14,106 96.14,106.2 96.24,106.31 96.69,106.31 96.95,106.57 96.95,107.01 96.69,107.27 96.24,107.27 96.14,107.37 96.14,107.58 96.24,107.68 96.69,107.68 96.95,107.94 96.95,108.38 96.69,108.64 96.24,108.64 96.14,108.74 96.14,108.95 96.24,109.05 96.69,109.05 96.95,109.31 96.95,109.75 96.69,110.01 96.24,110.01 96.14,110.12 96.14,110.32 96.24,110.42 96.69,110.42 96.95,110.69 96.95,111.12 96.69,111.39 96.24,111.39 96.14,111.49 96.14,111.69 96.24,111.79 96.69,111.79 96.95,112.06 96.95,112.49 96.69,112.76 96.24,112.76 96.14,112.86 96.14,113.06 96.24,113.16 96.69,113.16 96.95,113.43 96.95,113.86 96.69,114.13 96.24,114.13 96.14,114.23 96.14,114.43 96.24,114.54 96.69,114.54 96.95,114.8 96.95,115.24 96.69,115.5 96.24,115.5 96.14,115.6 96.14,115.81 96.24,115.91 96.69,115.91 96.95,116.17 96.95,116.61 96.69,116.87 96.24,116.87 96.14,116.97 96.14,117.18 96.24,117.28 96.69,117.28 96.95,117.54 96.95,117.98 96.69,118.24 96.24,118.24 96.14,118.35 96.14,118.55 96.24,118.65 96.69,118.65 96.95,118.92 96.95,119.35 96.69,119.62 96.24,119.62 96.14,119.72 96.14,119.92 96.24,120.02 96.69,120.02 96.95,120.29 96.95,120.72 96.69,120.99 96.24,120.99 96.14,121.09 96.14,121.29 96.24,121.39 96.69,121.39 96.95,121.66 96.95,122.09 96.69,122.36 96.24,122.36 96.14,122.46 96.14,122.71 96.67,123.24 96.67,125.64 91.8,130.52 91.8,131.95 91.19,132.56 91.19,134.43 87.22,138.39 87.22,146.38 90.09,149.25 116.57,149.25 117.04,148.78 117.04,148.06 v1(116.81,147.83)
  BOTTOM w0.114: v1(116.81,147.83) 117.06,148.07 117.06,149.83 J3.34
INPUT6_M: length 118.6
  TOP w0.114: U5.AJ6 v2(95.95,88.2)
  L4-SIG2 w0.102: v1(116.1,148.34) 115.84,148.59 115.84,149 114.29,150.55 90.04,150.55 86.79,147.29 86.79,132.61 93.45,125.96 93.45,119.69 92.41,118.65 92.41,118.22 92.67,117.95 93.44,117.95 93.54,117.85 93.54,117.65 93.44,117.55 92.67,117.55 92.41,117.28 92.41,116.85 92.67,116.58 93.44,116.58 93.54,116.48 93.54,116.28 93.44,116.17 92.67,116.17 92.41,115.91 92.41,115.47 92.67,115.21 93.44,115.21 93.54,115.11 93.54,114.9 93.44,114.8 92.67,114.8 92.41,114.54 92.41,114.1 92.67,113.84 93.44,113.84 93.54,113.74 93.54,113.53 93.44,113.43 92.67,113.43 92.41,113.17 92.41,112.73 92.67,112.47 93.44,112.47 93.54,112.36 93.54,112.16 93.44,112.06 92.67,112.06 92.41,111.79 92.41,111.36 92.67,111.09 93.44,111.09 93.54,110.99 93.54,110.79 93.44,110.69 92.67,110.69 92.41,110.42 92.41,109.99 92.67,109.72 93.44,109.72 93.54,109.62 93.54,109.42 93.44,109.32 92.67,109.32 92.41,109.05 92.41,108.62 92.67,108.35 93.44,108.35 93.54,108.25 93.54,108.05 93.44,107.94 92.67,107.94 92.41,107.68 92.41,107.24 92.67,106.98 93.05,106.98 93.54,106.49 93.54,101.92 91.06,99.44 91.06,92.08 92.71,90.42 94.36,90.42 94.61,90.68 95.7,90.68 96.33,90.04 96.33,87.72 96.29,87.68 96.06,87.68 95.95,87.79 v2(95.95,88.2)
  BOTTOM w0.114: J3.38 115.84,149.83 115.84,148.59 v1(116.1,148.34)
INPUT6_P: length 118.5
  TOP w0.114: U5.AJ7 v2(95.95,87.2)
  L4-SIG2 w0.102: v1(115.33,148.34) 115.56,148.56 115.56,148.88 114.17,150.27 90.16,150.27 87.07,147.18 87.07,132.73 90.59,129.21 90.74,129.21 90.74,129.21 90.88,129.21 91.02,129.07 91.02,128.92 91.02,128.92 91.02,128.78 91.17,128.63 91.31,128.63 91.31,128.64 91.46,128.64 91.6,128.49 91.6,128.35 91.6,128.35 91.6,128.2 91.74,128.06 91.88,128.06 91.89,128.06 92.03,128.06 92.17,127.92 92.17,127.77 92.17,127.77 92.17,127.63 93.73,126.07 93.73,119.58 92.68,118.54 92.68,118.33 92.79,118.23 93.55,118.23 93.82,117.97 93.82,117.53 93.55,117.27 92.79,117.27 92.68,117.16 92.68,116.96 92.79,116.86 93.55,116.86 93.82,116.59 93.82,116.16 93.55,115.89 92.79,115.89 92.68,115.79 92.68,115.59 92.79,115.49 93.55,115.49 93.82,115.22 93.82,114.79 93.55,114.52 92.79,114.52 92.68,114.42 92.68,114.22 92.79,114.12 93.55,114.12 93.82,113.85 93.82,113.42 93.55,113.15 92.79,113.15 92.68,113.05 92.68,112.85 92.79,112.75 93.55,112.75 93.82,112.48 93.82,112.05 93.55,111.78 92.79,111.78 92.68,111.68 92.68,111.48 92.79,111.37 93.55,111.37 93.82,111.11 93.82,110.67 93.55,110.41 92.79,110.41 92.68,110.31 92.68,110.1 92.79,110 93.55,110 93.82,109.74 93.82,109.3 93.55,109.04 92.79,109.04 92.68,108.94 92.68,108.73 92.79,108.63 93.55,108.63 93.82,108.37 93.82,107.93 93.55,107.67 92.79,107.67 92.68,107.56 92.68,107.36 92.79,107.26 93.55,107.26 93.82,106.99 93.82,101.74 93.65,101.57 93.59,101.57 91.34,99.33 91.34,92.13 92.81,90.66 94.26,90.66 94.53,90.93 95.81,90.93 96.57,90.17 96.57,87.62 96.38,87.43 96.18,87.43 v2(95.95,87.2)
  BOTTOM w0.114: v1(115.33,148.34) 115.54,148.55 115.54,149.84 J3.40
INPUT7_M: length 118.5
  TOP w0.114: U5.AH7 v2(96.95,87.2)
  L3-SIG1 w0.102: v1(114.6,147.83) 114.18,147.4 113.72,147.4 113.51,147.61 113.51,148.7 113.17,149.05 99.12,149.05 98.78,148.7 98.78,148.07 98.98,147.87 98.98,146.62 98.35,145.99 98.35,143.51 95.99,141.15 95.99,139.75 96.09,139.65 96.1,139.65 96.34,139.41 96.34,138.94 96.09,138.69 96.09,138.69 95.99,138.58 95.99,138.15 96.09,138.05 96.53,138.05 96.8,137.79 96.8,137.35 96.53,137.09 96.09,137.09 95.99,136.98 95.99,136.78 96.09,136.68 96.53,136.68 96.8,136.41 96.8,135.98 96.53,135.71 96.09,135.71 95.99,135.61 95.99,135.41 96.09,135.31 96.53,135.31 96.8,135.04 96.8,134.61 96.53,134.34 96.09,134.34 95.99,134.24 95.99,134.04 96.09,133.94 96.53,133.94 96.8,133.67 96.8,133.24 96.53,132.97 96.09,132.97 95.99,132.87 95.99,132.67 96.09,132.56 96.53,132.56 96.8,132.3 96.8,131.86 96.53,131.6 96.09,131.6 95.99,131.5 95.99,131.29 96.09,131.19 96.53,131.19 96.8,130.93 96.8,130.49 96.53,130.23 96.09,130.23 95.99,130.13 95.99,129.92 96.09,129.82 96.53,129.82 96.8,129.56 96.8,129.12 96.53,128.86 96.09,128.86 95.99,128.75 95.99,128.55 96.09,128.45 96.53,128.45 96.8,128.18 96.8,127.75 96.53,127.48 96.09,127.48 95.99,127.38 95.99,127.18 96.09,127.08 96.53,127.08 96.8,126.81 96.8,126.38 96.53,126.11 96.09,126.11 95.99,126.01 95.99,125.81 96.09,125.71 96.53,125.71 96.8,125.44 96.8,125.01 96.53,124.74 96.09,124.74 95.99,124.64 95.99,124.44 96.09,124.34 96.53,124.34 96.8,124.07 96.8,123.64 96.53,123.37 96.09,123.37 95.99,123.27 95.99,123.07 96.09,122.96 96.53,122.96 96.8,122.7 96.8,122.26 96.53,122 96.09,122 95.99,121.9 95.99,121.69 96.09,121.59 96.53,121.59 96.8,121.33 96.8,120.89 96.53,120.63 96.09,120.63 95.99,120.53 95.99,120.32 96.09,120.22 96.53,120.22 96.8,119.96 96.8,119.52 96.53,119.26 96.09,119.26 95.99,119.15 95.99,118.95 96.09,118.85 96.53,118.85 96.8,118.58 96.8,118.15 96.53,117.88 96.09,117.88 95.99,117.78 95.99,117.58 96.09,117.48 96.53,117.48 96.8,117.21 96.8,116.78 96.53,116.51 96.09,116.51 95.99,116.41 95.99,116.21 96.09,116.11 96.53,116.11 96.8,115.84 96.8,115.41 96.53,115.14 96.09,115.14 95.99,115.04 95.99,114.84 96.09,114.73 96.53,114.73 96.8,114.47 96.8,114.03 96.53,113.77 96.09,113.77 95.99,113.67 95.99,113.46 96.09,113.36 96.53,113.36 96.8,113.1 96.8,112.66 96.53,112.4 96.09,112.4 95.99,112.3 95.99,112.09 96.09,111.99 96.53,111.99 96.8,111.73 96.8,111.29 96.53,111.03 96.09,111.03 95.99,110.92 95.99,110.72 96.09,110.62 96.53,110.62 96.8,110.35 96.8,109.92 96.53,109.65 96.09,109.65 95.99,109.55 95.99,109.35 96.09,109.25 96.53,109.25 96.8,108.98 96.8,108.55 96.53,108.28 96.09,108.28 95.99,108.18 95.99,107.98 96.09,107.88 96.53,107.88 96.8,107.61 96.8,107.18 96.53,106.91 96.09,106.91 95.99,106.81 95.99,106.61 96.09,106.5 96.53,106.5 96.8,106.24 96.8,105.8 96.53,105.54 96.09,105.54 95.99,105.44 95.99,105.23 96.09,105.13 96.53,105.13 96.8,104.87 96.8,104.43 96.53,104.17 96.09,104.17 95.99,104.07 95.99,103.86 96.09,103.76 96.53,103.76 96.8,103.5 96.8,103.06 96.53,102.8 96.09,102.8 95.99,102.69 95.99,102.49 96.09,102.39 96.53,102.39 96.8,102.12 96.8,101.69 96.53,101.42 96.09,101.42 95.99,101.32 95.99,101.12 96.09,101.02 96.53,101.02 96.8,100.75 96.8,100.32 96.53,100.05 96.09,100.05 95.99,99.95 95.99,95.65 96.62,95.01 96.62,94.11 96.58,94.07 96.58,94.01 96.57,93.99 96.57,86.82 96.65,86.74 96.85,86.74 96.95,86.84 v2(96.95,87.2)
  BOTTOM w0.114: v1(114.6,147.83) 114.33,148.11 114.33,149.82 J3.44
INPUT7_P: length 118.4
  TOP w0.114: U5.AJ8 v2(95.95,86.2)
  L3-SIG1 w0.102: v1(113.92,147.83) 113.79,147.96 113.79,148.82 113.28,149.33 99.01,149.33 98.5,148.82 98.5,147.96 98.7,147.75 98.7,146.74 98.07,146.1 98.07,143.63 95.71,141.26 95.71,140.99 95.61,140.89 95.35,140.89 95.25,140.79 95.25,140.59 95.35,140.48 95.61,140.48 95.71,140.38 95.71,139.64 95.97,139.37 95.99,139.37 96.06,139.3 96.06,139.05 95.97,138.97 95.97,138.97 95.71,138.7 95.71,138.04 95.97,137.77 96.42,137.77 96.52,137.67 96.52,137.47 96.42,137.37 95.97,137.37 95.71,137.1 95.71,136.67 95.97,136.4 96.42,136.4 96.52,136.3 96.52,136.1 96.42,135.99 95.97,135.99 95.71,135.73 95.71,135.29 95.97,135.03 96.42,135.03 96.52,134.93 96.52,134.72 96.42,134.62 95.97,134.62 95.71,134.36 95.71,133.92 95.97,133.66 96.42,133.66 96.52,133.56 96.52,133.35 96.42,133.25 95.97,133.25 95.71,132.99 95.71,132.55 95.97,132.29 96.42,132.29 96.52,132.18 96.52,131.98 96.42,131.88 95.97,131.88 95.71,131.61 95.71,131.18 95.97,130.91 96.42,130.91 96.52,130.81 96.52,130.61 96.42,130.51 95.97,130.51 95.71,130.24 95.71,129.81 95.97,129.54 96.42,129.54 96.52,129.44 96.52,129.24 96.42,129.14 95.97,129.14 95.71,128.87 95.71,128.44 95.97,128.17 96.42,128.17 96.52,128.07 96.52,127.87 96.42,127.76 95.97,127.76 95.71,127.5 95.71,127.06 95.97,126.8 96.42,126.8 96.52,126.7 96.52,126.49 96.42,126.39 95.97,126.39 95.71,126.13 95.71,125.69 95.97,125.43 96.42,125.43 96.52,125.33 96.52,125.12 96.42,125.02 95.97,125.02 95.71,124.76 95.71,124.32 95.97,124.06 96.42,124.06 96.52,123.95 96.52,123.75 96.42,123.65 95.97,123.65 95.71,123.38 95.71,122.95 95.97,122.68 96.42,122.68 96.52,122.58 96.52,122.38 96.42,122.28 95.97,122.28 95.71,122.01 95.71,121.58 95.97,121.31 96.42,121.31 96.52,121.21 96.52,121.01 96.42,120.91 95.97,120.91 95.71,120.64 95.71,120.21 95.97,119.94 96.42,119.94 96.52,119.84 96.52,119.64 96.42,119.53 95.97,119.53 95.71,119.27 95.71,118.83 95.97,118.57 96.42,118.57 96.52,118.47 96.52,118.26 96.42,118.16 95.97,118.16 95.71,117.9 95.71,117.46 95.97,117.2 96.42,117.2 96.52,117.1 96.52,116.89 96.42,116.79 95.97,116.79 95.71,116.53 95.71,116.09 95.97,115.83 96.42,115.83 96.52,115.72 96.52,115.52 96.42,115.42 95.97,115.42 95.71,115.15 95.71,114.72 95.97,114.45 96.42,114.45 96.52,114.35 96.52,114.15 96.42,114.05 95.97,114.05 95.71,113.78 95.71,113.35 95.97,113.08 96.42,113.08 96.52,112.98 96.52,112.78 96.42,112.68 95.97,112.68 95.71,112.41 95.71,111.98 95.97,111.71 96.42,111.71 96.52,111.61 96.52,111.41 96.42,111.3 95.97,111.3 95.71,111.04 95.71,110.6 95.97,110.34 96.42,110.34 96.52,110.24 96.52,110.03 96.42,109.93 95.97,109.93 95.71,109.67 95.71,109.23 95.97,108.97 96.42,108.97 96.52,108.87 96.52,108.66 96.42,108.56 95.97,108.56 95.71,108.3 95.71,107.86 95.97,107.6 96.42,107.6 96.52,107.49 96.52,107.29 96.42,107.19 95.97,107.19 95.71,106.92 95.71,106.49 95.97,106.22 96.42,106.22 96.52,106.12 96.52,105.92 96.42,105.82 95.97,105.82 95.71,105.55 95.71,105.12 95.97,104.85 96.42,104.85 96.52,104.75 96.52,104.55 96.42,104.45 95.97,104.45 95.71,104.18 95.71,103.75 95.97,103.48 96.42,103.48 96.52,103.38 96.52,103.18 96.42,103.08 95.97,103.08 95.71,102.81 95.71,102.38 95.97,102.11 96.42,102.11 96.52,102.01 96.52,101.81 96.42,101.7 95.97,101.7 95.71,101.44 95.71,101 95.97,100.74 96.42,100.74 96.52,100.64 96.52,100.43 96.42,100.33 95.97,100.33 95.71,100.07 95.71,95.53 96.34,94.89 96.34,94.08 96.33,94.07 96.33,86.58 v2(95.95,86.2)
  BOTTOM w0.114: v1(113.92,147.83) 113.92,147.93 113.95,147.95 J3.46
INPUT8_M: length 118.6
  TOP w0.114: U5.AH8 v2(96.95,86.2)
  L3-SIG1 w0.102: v2(96.95,86.2) 96.55,85.8 96.55,85.04 96.77,84.82 98.12,84.82 98.33,85.03 98.33,85.49 98.66,85.82 100.17,85.82 100.33,85.98 100.33,86.04 100.33,86.54 100.61,86.82 105.2,86.82 105.31,86.93 105.31,86.95 105.33,86.97 105.33,93.52 105.84,94.04 107.5,94.04 107.56,94.1 108.62,94.1 110.11,95.59 110.11,96.23 111.86,97.98 111.86,99.9 112.13,100.17 112.7,100.17 112.8,100.27 112.8,100.47 112.7,100.57 112.13,100.57 111.86,100.84 111.86,101.27 112.13,101.54 112.7,101.54 112.8,101.64 112.8,101.84 112.7,101.94 112.13,101.94 111.86,102.21 111.86,102.64 112.13,102.91 112.7,102.91 112.8,103.01 112.8,103.21 112.7,103.31 112.13,103.31 111.86,103.58 111.86,104.01 112.13,104.28 112.7,104.28 112.8,104.38 112.8,104.58 112.7,104.69 112.13,104.69 111.86,104.95 111.86,105.39 112.13,105.65 112.7,105.65 112.8,105.75 112.8,105.96 112.7,106.06 112.13,106.06 111.86,106.32 111.86,106.76 112.13,107.02 112.7,107.02 112.8,107.12 112.8,107.33 112.7,107.43 112.13,107.43 111.86,107.69 111.86,108.13 112.13,108.39 112.7,108.39 112.8,108.5 112.8,108.7 112.7,108.8 112.13,108.8 111.86,109.07 111.86,109.5 112.13,109.77 112.7,109.77 112.8,109.87 112.8,110.07 112.7,110.17 112.13,110.17 111.86,110.44 111.86,110.87 112.13,111.14 112.7,111.14 112.8,111.24 112.8,111.44 112.7,111.54 112.13,111.54 111.86,111.81 111.86,112.24 112.13,112.51 112.7,112.51 112.8,112.61 112.8,112.81 112.7,112.92 112.13,112.92 111.86,113.18 111.86,113.62 112.13,113.88 112.7,113.88 112.8,113.98 112.8,114.19 112.7,114.29 112.13,114.29 111.86,114.55 111.86,114.99 112.13,115.25 112.7,115.25 112.8,115.35 112.8,115.56 112.7,115.66 112.13,115.66 111.86,115.92 111.86,116.36 112.13,116.62 112.7,116.62 112.8,116.73 112.8,116.93 112.7,117.03 112.13,117.03 111.86,117.3 111.86,117.73 112.13,118 112.7,118 112.8,118.1 112.8,118.3 112.7,118.4 112.13,118.4 111.86,118.67 111.86,119.1 112.13,119.37 112.7,119.37 112.8,119.47 112.8,119.67 112.7,119.77 112.13,119.77 111.86,120.04 111.86,120.47 112.13,120.74 112.7,120.74 112.8,120.84 112.8,121.04 112.7,121.15 112.13,121.15 111.86,121.41 111.86,121.85 112.13,122.11 112.7,122.11 112.8,122.21 112.8,122.42 112.7,122.52 112.13,122.52 111.86,122.78 111.86,123.22 112.13,123.48 112.7,123.48 112.8,123.58 112.8,123.79 112.7,123.89 112.13,123.89 111.86,124.15 111.86,124.59 112.13,124.85 112.7,124.85 112.8,124.96 112.8,125.16 112.7,125.26 112.13,125.26 111.86,125.53 111.86,125.96 112.13,126.23 112.7,126.23 112.8,126.33 112.8,126.53 112.7,126.63 112.13,126.63 111.86,126.9 111.86,127.33 112.13,127.6 112.7,127.6 112.8,127.7 112.8,127.9 112.7,128 112.13,128 111.86,128.27 111.86,128.7 112.13,128.97 112.7,128.97 112.8,129.07 112.8,129.27 112.7,129.38 112.13,129.38 111.86,129.64 111.86,130.08 112.13,130.34 112.7,130.34 112.8,130.44 112.8,130.65 112.7,130.75 112.13,130.75 111.86,131.01 111.86,131.45 112.13,131.71 112.7,131.71 112.8,131.81 112.8,132.02 112.7,132.12 112.13,132.12 111.86,132.38 111.86,132.82 112.13,133.08 112.28,133.08 112.42,133.22 112.42,133.32 111.86,133.88 111.86,138.8 110.06,140.6 110.06,144.48 111,145.41 111,146.3 112.24,147.55 112.24,147.83 111.89,148.18 111.89,148.51 112.11,148.74 112.69,148.74 v1(113.1,148.34)
  BOTTOM w0.114: v1(113.1,148.34) 112.85,148.58 112.85,149.84 112.9,149.89 J3.50
INPUT8_P: length 118.4
  TOP w0.114: U5.AJ9 v2(95.95,85.2)
  L3-SIG1 w0.102: v1(112.33,148.34) 112.52,148.15 112.52,147.95 112.52,147.95 112.52,147.43 111.28,146.19 111.28,145.3 110.34,144.36 110.34,140.72 112.14,138.91 112.14,134.04 112.41,133.77 112.82,133.77 113.08,133.5 113.08,133.07 112.82,132.8 112.24,132.8 112.14,132.7 112.14,132.5 112.24,132.4 112.82,132.4 113.08,132.13 113.08,131.7 112.82,131.43 112.24,131.43 112.14,131.33 112.14,131.13 112.24,131.03 112.82,131.03 113.08,130.76 113.08,130.33 112.82,130.06 112.24,130.06 112.14,129.96 112.14,129.76 112.24,129.65 112.82,129.65 113.08,129.39 113.08,128.95 112.82,128.69 112.24,128.69 112.14,128.59 112.14,128.38 112.24,128.28 112.82,128.28 113.08,128.02 113.08,127.58 112.82,127.32 112.24,127.32 112.14,127.22 112.14,127.01 112.24,126.91 112.82,126.91 113.08,126.65 113.08,126.21 112.82,125.95 112.24,125.95 112.14,125.84 112.14,125.64 112.24,125.54 112.82,125.54 113.08,125.27 113.08,124.84 112.82,124.57 112.24,124.57 112.14,124.47 112.14,124.27 112.24,124.17 112.82,124.17 113.08,123.9 113.08,123.47 112.82,123.2 112.24,123.2 112.14,123.1 112.14,122.9 112.24,122.8 112.82,122.8 113.08,122.53 113.08,122.1 112.82,121.83 112.24,121.83 112.14,121.73 112.14,121.53 112.24,121.43 112.82,121.43 113.08,121.16 113.08,120.73 112.82,120.46 112.24,120.46 112.14,120.36 112.14,120.16 112.24,120.05 112.82,120.05 113.08,119.79 113.08,119.35 112.82,119.09 112.24,119.09 112.14,118.99 112.14,118.78 112.24,118.68 112.82,118.68 113.08,118.42 113.08,117.98 112.82,117.72 112.24,117.72 112.14,117.62 112.14,117.41 112.24,117.31 112.82,117.31 113.08,117.04 113.08,116.61 112.82,116.35 112.24,116.35 112.14,116.24 112.14,116.04 112.24,115.94 112.82,115.94 113.08,115.67 113.08,115.24 112.82,114.97 112.24,114.97 112.14,114.87 112.14,114.67 112.24,114.57 112.82,114.57 113.08,114.3 113.08,113.87 112.82,113.6 112.24,113.6 112.14,113.5 112.14,113.3 112.24,113.2 112.82,113.2 113.08,112.93 113.08,112.5 112.82,112.23 112.24,112.23 112.14,112.13 112.14,111.93 112.24,111.82 112.82,111.82 113.08,111.56 113.08,111.12 112.82,110.86 112.24,110.86 112.14,110.76 112.14,110.55 112.24,110.45 112.82,110.45 113.08,110.19 113.08,109.75 112.82,109.49 112.24,109.49 112.14,109.39 112.14,109.18 112.24,109.08 112.82,109.08 113.08,108.82 113.08,108.38 112.82,108.12 112.24,108.12 112.14,108.01 112.14,107.81 112.24,107.71 112.82,107.71 113.08,107.44 113.08,107.01 112.82,106.74 112.24,106.74 112.14,106.64 112.14,106.44 112.24,106.34 112.82,106.34 113.08,106.07 113.08,105.64 112.82,105.37 112.24,105.37 112.14,105.27 112.14,105.07 112.24,104.97 112.82,104.97 113.08,104.7 113.08,104.27 112.82,104 112.24,104 112.14,103.9 112.14,103.7 112.24,103.59 112.82,103.59 113.08,103.33 113.08,102.89 112.82,102.63 112.24,102.63 112.14,102.53 112.14,102.32 112.24,102.22 112.82,102.22 113.08,101.96 113.08,101.52 112.82,101.26 112.24,101.26 112.14,101.16 112.14,100.95 112.24,100.85 112.82,100.85 113.08,100.59 113.08,100.15 112.82,99.89 112.24,99.89 112.14,99.78 112.14,97.87 110.39,96.11 110.39,95.47 108.78,93.86 107.66,93.86 107.59,93.8 105.94,93.8 105.57,93.42 105.57,86.87 105.55,86.85 105.55,86.83 105.3,86.58 100.71,86.58 100.57,86.44 100.57,85.94 100.57,85.94 100.57,85.86 100.29,85.58 98.76,85.58 98.57,85.39 98.57,84.93 98.22,84.58 96.67,84.58 96.31,84.94 96.31,85.48 96.24,85.55 95.99,85.55 95.94,85.5 95.94,85.21 v2(95.95,85.2)
  BOTTOM w0.114: J3.52 112.57,149.81 112.57,148.57 v1(112.33,148.34)
INPUT9_M: length 135.5
  TOP w0.114: U5.AE27 v2(99.95,66.2)
  L3-SIG1 w0.102: v1(125.09,141.99) 124.92,141.81 124.92,141.38 130.86,135.43 133.19,135.43 134.75,133.87 134.75,112.36 135,112.11 135,111.68 134.74,111.41 133.48,111.41 133.38,111.31 133.38,111.11 133.48,111 134.74,111 135,110.74 135,110.3 134.74,110.04 133.48,110.04 133.38,109.94 133.38,109.73 133.48,109.63 134.74,109.63 135,109.37 135,108.93 134.74,108.67 133.48,108.67 133.38,108.57 133.38,108.36 133.48,108.26 134.74,108.26 135,108 135,107.56 134.74,107.3 133.48,107.3 133.38,107.19 133.38,106.99 133.48,106.89 134.74,106.89 135,106.62 135,106.19 134.74,105.92 133.48,105.92 133.38,105.82 133.38,105.62 133.48,105.52 134.74,105.52 135,105.25 135,104.82 134.74,104.55 133.48,104.55 133.38,104.45 133.38,104.25 133.48,104.15 134.74,104.15 135,103.88 135,103.45 134.74,103.18 133.48,103.18 133.38,103.08 133.38,102.88 133.48,102.77 134.74,102.77 135,102.51 135,102.07 134.74,101.81 134.58,101.81 133.38,100.61 133.38,100.6 128.32,95.54 127.94,95.54 126.25,93.85 124.96,93.85 124.6,93.49 124.2,93.49 124.11,93.58 123.79,93.58 123.57,93.36 123.57,92.88 123.55,92.87 123.55,92.47 123.57,92.46 123.57,92.26 123.57,92.26 123.57,91.94 123.55,91.93 123.55,91.47 123.57,91.46 123.57,90.94 123.55,90.93 123.55,89.47 123.57,89.46 123.57,88.94 123.55,88.93 123.55,88.9 123.57,88.88 123.57,88.36 123.57,88.36 123.57,86.94 123.55,86.93 123.55,86.47 123.57,86.46 123.57,85.94 123.55,85.93 123.55,83.47 123.57,83.46 123.57,82.94 123.55,82.93 123.55,82.66 123.42,82.52 122.43,81.53 121.15,81.53 121.11,81.58 120.79,81.58 120.76,81.55 118.14,81.55 118.11,81.58 117.79,81.58 117.75,81.53 116.08,81.53 115.57,81.03 115.57,78.36 115.57,77.36 115.57,76.2 115.11,75.74 114.79,75.74 113.63,74.58 111.67,74.58 111.57,74.48 111.57,73.94 111.57,73.94 111.57,73.56 111.57,73.56 111.57,72.94 111.57,72.94 111.57,72.56 111.57,72.56 111.57,71.94 111.57,71.94 111.57,71.56 111.57,71.56 111.57,70.94 111.57,70.94 111.57,70.56 111.57,70.56 111.57,69.94 111.57,69.94 111.57,69.56 111.57,69.56 111.57,68.94 111.57,68.94 111.57,68.56 111.57,68.56 111.57,67.94 111.57,67.94 111.57,67.56 111.57,67.56 111.57,66.94 111.57,66.94 111.57,66.56 111.57,66.56 111.57,65.94 111.57,65.94 111.57,65.56 111.57,65.56 111.57,64.94 111.21,64.58 110.69,64.58 110.69,64.58 110.31,64.58 110.31,64.58 109.69,64.58 109.69,64.58 109.31,64.58 109.31,64.58 108.69,64.58 108.69,64.58 107.31,64.58 107.31,64.58 106.69,64.58 106.69,64.58 106.31,64.58 106.31,64.58 105.69,64.58 105.69,64.58 105.31,64.58 105.31,64.58 104.69,64.58 104.69,64.58 104.31,64.58 104.31,64.58 103.69,64.58 103.69,64.58 103.31,64.58 103.31,64.58 102.69,64.58 102.69,64.58 102.31,64.58 102.31,64.58 101.69,64.58 101.69,64.58 101.31,64.58 101.31,64.58 100.69,64.58 100.33,64.94 100.33,66.32 100.28,66.37 100.12,66.37 v2(99.95,66.2)
  BOTTOM w0.114: J3.1 124.84,144.09 124.84,142.24 v1(125.09,141.99)
INPUT9_P: length 135.3
  TOP w0.114: U5.AD26 v2(100.95,67.2)
  L3-SIG1 w0.102: v1(124.28,141.96) 124.64,141.61 124.64,141.26 130.75,135.15 133.07,135.15 134.47,133.76 134.47,112.25 134.72,111.99 134.72,111.79 134.62,111.69 133.36,111.69 133.1,111.42 133.1,110.99 133.36,110.72 134.62,110.72 134.72,110.62 134.72,110.42 134.62,110.32 133.36,110.32 133.1,110.05 133.1,109.62 133.36,109.35 134.62,109.35 134.72,109.25 134.72,109.05 134.62,108.95 133.36,108.95 133.1,108.68 133.1,108.25 133.36,107.98 134.62,107.98 134.72,107.88 134.72,107.68 134.62,107.57 133.36,107.57 133.1,107.31 133.1,106.87 133.36,106.61 134.62,106.61 134.72,106.51 134.72,106.3 134.62,106.2 133.36,106.2 133.1,105.94 133.1,105.5 133.36,105.24 134.62,105.24 134.72,105.14 134.72,104.93 134.62,104.83 133.36,104.83 133.1,104.57 133.1,104.13 133.36,103.87 134.62,103.87 134.72,103.76 134.72,103.56 134.62,103.46 133.36,103.46 133.1,103.19 133.1,102.76 133.36,102.49 134.62,102.49 134.72,102.39 134.72,102.19 134.62,102.09 134.46,102.09 133.1,100.73 133.1,100.71 128.21,95.82 127.83,95.82 126.14,94.13 125.23,94.13 125.19,94.09 124.86,94.09 124.5,93.73 124.3,93.73 124.21,93.82 123.69,93.82 123.33,93.46 123.33,93.04 123.32,93.03 123.32,92.37 123.33,92.36 123.33,92.04 123.32,92.03 123.32,91.37 123.33,91.36 123.33,91.04 123.32,91.03 123.32,89.37 123.33,89.36 123.33,89.04 123.32,89.03 123.32,88.37 123.33,88.36 123.33,88.04 123.32,88.03 123.32,87.37 123.33,87.36 123.33,87.04 123.32,87.03 123.32,86.37 123.33,86.36 123.33,86.04 123.32,86.03 123.32,83.37 123.33,83.36 123.33,83.04 123.32,83.03 123.32,82.76 122.33,81.77 121.25,81.77 121.21,81.82 120.69,81.82 120.66,81.79 118.24,81.79 118.21,81.82 117.69,81.82 117.65,81.77 115.98,81.77 115.33,81.12 115.33,78.46 115.33,78.46 115.33,77.94 115.33,77.94 115.33,77.46 115.33,77.46 115.33,76.94 115.33,76.94 115.33,76.3 115.01,75.98 114.69,75.98 113.53,74.82 111.57,74.82 111.33,74.58 111.33,74.04 111.33,74.04 111.33,73.46 111.33,73.46 111.33,73.04 111.33,73.04 111.33,72.46 111.33,72.46 111.33,72.04 111.33,72.04 111.33,71.46 111.33,71.46 111.33,71.04 111.33,71.04 111.33,70.46 111.33,70.46 111.33,70.04 111.33,70.04 111.33,69.46 111.33,69.46 111.33,69.04 111.33,69.04 111.33,68.46 111.33,68.46 111.33,68.04 111.33,68.04 111.33,67.46 111.33,67.46 111.33,67.04 111.33,67.04 111.33,66.46 111.33,66.46 111.33,66.04 111.33,66.04 111.33,65.46 111.33,65.46 111.33,65.04 111.11,64.82 110.79,64.82 110.79,64.82 110.21,64.82 110.21,64.82 109.79,64.82 109.79,64.82 109.21,64.82 109.21,64.82 108.79,64.82 108.79,64.82 107.21,64.82 107.21,64.82 106.79,64.82 106.79,64.82 106.21,64.82 106.21,64.82 105.79,64.82 105.79,64.82 105.21,64.82 105.21,64.82 104.79,64.82 104.79,64.82 104.21,64.82 104.21,64.82 103.79,64.82 103.79,64.82 103.21,64.82 103.21,64.82 102.79,64.82 102.79,64.82 102.21,64.82 102.21,64.82 101.79,64.82 101.79,64.82 101.21,64.82 101.21,64.82 100.79,64.82 100.57,65.04 100.57,66.82 v2(100.95,67.2)
  BOTTOM w0.114: J3.3 124.55,144.09 124.55,142.22 v1(124.28,141.96)
INPUT10_M: length 118.6
  TOP w0.114: U5.AD27 v2(100.95,66.2)
  L3-SIG1 w0.102: v1(123.61,140.59) 123.34,140.32 123.34,138.58 127.6,134.32 127.6,128.01 127.76,127.84 127.76,125.73 127.6,125.57 127.6,124.34 127.7,124.24 128,124.24 128.27,123.97 128.27,123.54 128,123.27 127.7,123.27 127.6,123.17 127.6,122.97 127.7,122.87 128,122.87 128.27,122.6 128.27,122.17 128,121.9 127.7,121.9 127.6,121.8 127.6,121.6 127.7,121.5 128,121.5 128.27,121.23 128.27,120.8 128,120.53 127.7,120.53 127.6,120.43 127.6,120.23 127.7,120.13 128,120.13 128.27,119.86 128.27,119.43 128,119.16 127.7,119.16 127.6,119.06 127.6,118.86 127.7,118.75 128,118.75 128.27,118.49 128.27,118.05 128,117.79 127.7,117.79 127.6,117.69 127.6,117.48 127.7,117.38 128,117.38 128.27,117.12 128.27,116.68 128,116.42 127.7,116.42 127.6,116.32 127.6,116.11 127.7,116.01 128,116.01 128.27,115.74 128.27,115.31 128,115.05 127.7,115.05 127.6,114.94 127.6,114.74 127.7,114.64 128,114.64 128.27,114.37 128.27,113.94 128,113.67 127.7,113.67 127.6,113.57 127.6,113.37 127.7,113.27 128,113.27 128.27,113 128.27,112.57 128,112.3 127.7,112.3 127.6,112.2 127.6,112 127.7,111.9 128,111.9 128.27,111.63 128.27,111.2 128,110.93 127.7,110.93 127.6,110.83 127.6,110.63 127.7,110.52 128,110.52 128.27,110.26 128.27,109.82 128,109.56 127.7,109.56 127.6,109.46 127.6,109.25 127.7,109.15 128,109.15 128.27,108.89 128.27,108.45 128,108.19 127.7,108.19 127.6,108.09 127.6,107.88 127.7,107.78 128,107.78 128.27,107.52 128.27,107.08 128,106.82 127.7,106.82 127.6,106.71 127.6,106.51 127.7,106.41 128,106.41 128.27,106.14 128.27,105.71 128,105.44 127.7,105.44 127.6,105.34 127.6,105.14 127.7,105.04 128,105.04 128.27,104.77 128.27,104.34 128,104.07 127.7,104.07 127.6,103.97 127.6,103.77 127.7,103.67 128,103.67 128.27,103.4 128.27,102.97 128,102.7 127.7,102.7 127.6,102.6 127.6,102.4 127.7,102.29 128,102.29 128.27,102.03 128.27,101.59 128,101.33 127.7,101.33 127.6,101.23 127.6,99.01 124.91,96.32 124.37,96.32 123.84,95.78 123.78,95.78 123.55,95.55 123.55,95.49 121.57,93.52 121.57,93.04 121.6,93.01 121.6,92.97 121.54,92.91 121.54,92.49 121.57,92.46 121.57,91.94 121.54,91.91 121.54,89.49 121.57,89.46 121.57,88.94 121.54,88.91 121.54,88.49 121.57,88.46 121.57,87.94 121.54,87.91 121.54,87.49 121.57,87.46 121.57,86.94 121.54,86.91 121.54,85.49 121.57,85.46 121.57,84.94 121.54,84.91 121.54,84.49 121.57,84.46 121.57,83.94 121.08,83.46 117.23,83.46 117.11,83.58 114.14,83.58 113.75,83.19 113.75,76.89 113.37,76.51 113.17,76.51 113.15,76.53 110.17,76.53 109.57,75.93 109.57,67.22 108.93,66.58 101.33,66.58 v2(100.95,66.2)
  BOTTOM w0.114: v1(123.61,140.59) 123.34,140.85 123.34,144.09 J3.7
INPUT10_P: length 118.4
  TOP w0.114: U5.AC26 v2(101.95,67.2)
  L3-SIG1 w0.102: v2(101.95,67.2) 101.79,67.2 101.67,67.07 101.67,66.89 101.74,66.82 108.83,66.82 109.33,67.32 109.33,76.63 109.47,76.77 113.25,76.77 113.27,76.75 113.51,76.99 113.51,83.29 114.05,83.82 117.21,83.82 117.33,83.69 120.98,83.69 121.33,84.04 121.33,84.36 121.3,84.39 121.3,85.01 121.33,85.04 121.33,85.36 121.28,85.4 121.28,87 121.33,87.04 121.33,87.36 121.28,87.4 121.28,88 121.33,88.04 121.33,88.36 121.28,88.4 121.28,89 121.33,89.04 121.33,89.36 121.28,89.4 121.28,92 121.33,92.04 121.33,92.36 121.28,92.4 121.28,93 121.33,93.04 121.33,93.39 121.27,93.45 121.27,93.55 121.88,94.16 121.88,94.22 123.27,95.61 123.27,95.66 123.67,96.06 123.72,96.06 124.26,96.6 124.8,96.6 127.32,99.12 127.32,101.34 127.58,101.61 127.89,101.61 127.99,101.71 127.99,101.91 127.89,102.01 127.58,102.01 127.32,102.28 127.32,102.71 127.58,102.98 127.89,102.98 127.99,103.08 127.99,103.28 127.89,103.39 127.58,103.39 127.32,103.65 127.32,104.09 127.58,104.35 127.89,104.35 127.99,104.45 127.99,104.66 127.89,104.76 127.58,104.76 127.32,105.02 127.32,105.46 127.58,105.72 127.89,105.72 127.99,105.82 127.99,106.03 127.89,106.13 127.58,106.13 127.32,106.39 127.32,106.83 127.58,107.09 127.89,107.09 127.99,107.2 127.99,107.4 127.89,107.5 127.58,107.5 127.32,107.77 127.32,108.2 127.58,108.47 127.89,108.47 127.99,108.57 127.99,108.77 127.89,108.87 127.58,108.87 127.32,109.14 127.32,109.57 127.58,109.84 127.89,109.84 127.99,109.94 127.99,110.14 127.89,110.24 127.58,110.24 127.32,110.51 127.32,110.94 127.58,111.21 127.89,111.21 127.99,111.31 127.99,111.51 127.89,111.62 127.58,111.62 127.32,111.88 127.32,112.32 127.58,112.58 127.89,112.58 127.99,112.68 127.99,112.89 127.89,112.99 127.58,112.99 127.32,113.25 127.32,113.69 127.58,113.95 127.89,113.95 127.99,114.05 127.99,114.26 127.89,114.36 127.58,114.36 127.32,114.62 127.32,115.06 127.58,115.32 127.89,115.32 127.99,115.43 127.99,115.63 127.89,115.73 127.58,115.73 127.32,116 127.32,116.43 127.58,116.7 127.89,116.7 127.99,116.8 127.99,117 127.89,117.1 127.58,117.1 127.32,117.37 127.32,117.8 127.58,118.07 127.89,118.07 127.99,118.17 127.99,118.37 127.89,118.47 127.58,118.47 127.32,118.74 127.32,119.17 127.58,119.44 127.89,119.44 127.99,119.54 127.99,119.74 127.89,119.85 127.58,119.85 127.32,120.11 127.32,120.55 127.58,120.81 127.89,120.81 127.99,120.91 127.99,121.12 127.89,121.22 127.58,121.22 127.32,121.48 127.32,121.92 127.58,122.18 127.89,122.18 127.99,122.28 127.99,122.49 127.89,122.59 127.58,122.59 127.32,122.85 127.32,123.29 127.58,123.55 127.89,123.55 127.99,123.66 127.99,123.86 127.89,123.96 127.58,123.96 127.32,124.23 127.32,125.69 127.48,125.85 127.48,126.36 127.32,126.52 127.32,127.06 127.48,127.22 127.48,127.73 127.32,127.89 127.32,134.2 123.06,138.46 123.06,140.32 v1(122.78,140.59)
  BOTTOM w0.114: J3.9 123.05,144.09 123.05,140.85 v1(122.78,140.59)
INPUT11_M: length 118.5
  TOP w0.114: U5.AC28 v2(101.95,65.2)
  L3-SIG1 w0.102: v1(122.11,141.96) 121.84,141.69 121.84,141.59 121.97,141.45 123.86,141.45 124.36,140.96 124.36,139.78 129.84,134.29 129.84,132.88 130.86,131.87 130.86,127.33 131.7,126.49 131.7,126.04 131.43,125.78 130.96,125.78 130.86,125.67 130.86,125.47 130.96,125.37 131.43,125.37 131.7,125.1 131.7,124.67 131.43,124.4 130.96,124.4 130.86,124.3 130.86,124.1 130.96,124 131.43,124 131.7,123.73 131.7,123.3 131.43,123.03 130.96,123.03 130.86,122.93 130.86,122.73 130.96,122.63 131.43,122.63 131.7,122.36 131.7,121.93 131.43,121.66 130.96,121.66 130.86,121.56 130.86,121.36 130.96,121.25 131.43,121.25 131.7,120.99 131.7,120.56 131.43,120.29 130.96,120.29 130.86,120.19 130.86,119.98 130.96,119.88 131.43,119.88 131.7,119.62 131.7,119.18 131.43,118.92 130.96,118.92 130.86,118.82 130.86,118.61 130.96,118.51 131.43,118.51 131.7,118.25 131.7,117.81 131.43,117.55 130.96,117.55 130.86,117.44 130.86,117.24 130.96,117.14 131.43,117.14 131.7,116.87 131.7,116.44 131.43,116.17 130.96,116.17 130.86,116.07 130.86,115.87 130.96,115.77 131.43,115.77 131.7,115.5 131.7,115.07 131.06,114.43 131.06,101.09 124.59,94.61 123.79,94.61 123.77,94.59 123.69,94.59 123.3,94.2 123.28,94.2 123.23,94.17 123.23,94.13 122.92,93.83 122.87,93.83 122.57,93.53 122.57,92.94 122.55,92.92 122.55,92.48 122.57,92.46 122.57,91.94 122.55,91.92 122.55,91.48 122.57,91.46 122.57,90.94 122.55,90.92 122.55,90.48 122.57,90.46 122.57,89.94 122.55,89.92 122.55,89.48 122.57,89.46 122.57,88.94 122.55,88.92 122.55,88.48 122.57,88.46 122.57,87.94 122.55,87.92 122.55,87.48 122.57,87.46 122.57,86.94 122.55,86.92 122.55,83.47 121.65,82.57 121.45,82.57 120.12,82.57 120.11,82.58 119.79,82.58 119.78,82.57 118.12,82.57 118.11,82.58 117.79,82.58 117.78,82.57 114.65,82.57 114.44,82.35 114.44,76.64 113.64,75.84 110.9,75.84 110.58,75.52 110.58,75.36 110.57,75.36 110.57,75.04 110.58,75.04 110.58,74.36 110.57,74.36 110.57,74.04 110.58,74.04 110.58,73.36 110.57,73.36 110.57,73.04 110.58,73.04 110.58,72.36 110.57,72.36 110.57,71.04 110.58,71.04 110.58,70.36 110.57,70.36 110.57,70.04 110.58,70.04 110.58,69.36 110.57,69.36 110.57,69.04 110.58,69.04 110.58,68.36 110.57,68.36 110.57,68.04 110.58,68.04 110.58,67.36 110.57,67.36 110.57,67.04 110.58,67.04 110.58,66.36 110.57,66.36 110.57,65.94 110.21,65.58 102.33,65.58 v2(101.95,65.2)
  BOTTOM w0.114: v1(122.11,141.96) 121.84,142.22 121.84,144.09 J3.13
INPUT11_P: length 118.5
  TOP w0.114: U5.AB27 v2(102.95,66.2)
  L3-SIG1 w0.102: v2(102.95,66.2) 102.74,65.99 102.74,65.87 102.79,65.82 110.11,65.82 110.33,66.04 110.33,66.46 110.34,66.46 110.34,66.94 110.33,66.94 110.33,67.46 110.34,67.46 110.34,67.94 110.33,67.94 110.33,68.46 110.34,68.46 110.34,68.94 110.33,68.94 110.33,69.46 110.34,69.46 110.34,69.94 110.33,69.94 110.33,70.46 110.34,70.46 110.34,70.94 110.33,70.94 110.33,72.46 110.34,72.46 110.34,72.94 110.33,72.94 110.33,73.46 110.34,73.46 110.34,73.94 110.33,73.94 110.33,74.46 110.34,74.46 110.34,74.94 110.33,74.94 110.33,75.46 110.34,75.46 110.34,75.62 110.82,76.1 113.56,76.1 114.2,76.74 114.2,82.45 114.55,82.8 117.68,82.8 117.69,82.82 118.21,82.82 118.22,82.8 119.68,82.8 119.69,82.82 120.21,82.82 120.22,82.8 121.35,82.8 121.55,82.8 122.31,83.57 122.31,87.02 122.33,87.04 122.33,87.36 122.31,87.38 122.31,88.02 122.33,88.04 122.33,88.36 122.31,88.38 122.31,89.02 122.33,89.04 122.33,89.36 122.31,89.38 122.31,90.02 122.33,90.04 122.33,90.36 122.31,90.38 122.31,91.02 122.33,91.04 122.33,91.36 122.31,91.38 122.31,92.02 122.33,92.04 122.33,92.36 122.31,92.38 122.31,93.02 122.33,93.04 122.33,93.63 122.95,94.25 122.95,94.3 123.19,94.48 123.57,94.87 123.65,94.87 123.68,94.89 124.47,94.89 130.78,101.21 130.78,114.55 131.42,115.18 131.42,115.39 131.32,115.49 130.85,115.49 130.58,115.75 130.58,116.19 130.85,116.45 131.32,116.45 131.42,116.56 131.42,116.76 131.32,116.86 130.85,116.86 130.58,117.13 130.58,117.56 130.85,117.83 131.32,117.83 131.42,117.93 131.42,118.13 131.32,118.23 130.85,118.23 130.58,118.5 130.58,118.93 130.85,119.2 131.32,119.2 131.42,119.3 131.42,119.5 131.32,119.6 130.85,119.6 130.58,119.87 130.58,120.3 130.85,120.57 131.32,120.57 131.42,120.67 131.42,120.87 131.32,120.98 130.85,120.98 130.58,121.24 130.58,121.68 130.85,121.94 131.32,121.94 131.42,122.04 131.42,122.25 131.32,122.35 130.85,122.35 130.58,122.61 130.58,123.05 130.85,123.31 131.32,123.31 131.42,123.41 131.42,123.62 131.32,123.72 130.85,123.72 130.58,123.98 130.58,124.42 130.85,124.68 131.32,124.68 131.42,124.79 131.42,124.99 131.32,125.09 130.85,125.09 130.58,125.36 130.58,125.79 130.85,126.06 131.32,126.06 131.42,126.16 131.42,126.36 131.32,126.46 130.85,126.46 130.58,126.73 130.58,127.04 130.43,127.19 130.43,127.44 130.58,127.59 130.58,127.85 130.43,128 130.43,128.25 130.58,128.41 130.58,128.66 130.43,128.81 130.43,129.07 130.58,129.22 130.58,129.47 130.43,129.63 130.43,129.88 130.58,130.03 130.58,130.29 130.43,130.44 130.43,130.69 130.58,130.85 130.58,131.75 129.57,132.77 129.57,134.17 124.08,139.66 124.08,140.84 123.75,141.17 121.85,141.17 121.56,141.47 121.56,141.69 121.28,141.96 v1(121.28,141.99)
  BOTTOM w0.114: v1(121.28,141.99) 121.55,142.25 121.55,144.09 J3.15
INPUT12_M: length 118.6
  TOP w0.114: U5.L5 v2(114.95,89.2)
  L3-SIG1 w0.102: v1(120.65,140.59) 120.4,140.34 120.4,140 121.67,138.73 121.67,136.2 124.66,133.2 124.66,129.12 124.4,128.85 124.33,128.85 124.23,128.75 124.23,128.55 124.33,128.45 124.83,128.45 125.09,128.18 125.09,127.75 124.83,127.48 124.33,127.48 124.23,127.38 124.23,127.18 124.33,127.07 124.83,127.07 125.09,126.81 125.09,126.37 124.83,126.11 124.33,126.11 124.23,126.01 124.23,125.8 124.33,125.7 124.83,125.7 125.09,125.44 125.09,125 124.83,124.74 124.76,124.74 124.66,124.64 124.66,123.75 125.72,122.69 125.9,122.69 126.16,122.43 126.16,121.99 125.9,121.73 124.76,121.73 124.66,121.63 124.66,121.42 124.76,121.32 125.9,121.32 126.16,121.06 126.16,120.62 125.9,120.36 124.76,120.36 124.66,120.25 124.66,120.05 124.76,119.95 125.9,119.95 126.16,119.68 126.16,119.25 125.9,118.98 124.76,118.98 124.66,118.88 124.66,118.68 124.76,118.58 125.9,118.58 126.16,118.31 126.16,117.88 125.9,117.61 124.76,117.61 124.66,117.51 124.66,117.31 124.76,117.21 125.9,117.21 126.16,116.94 126.16,116.51 125.9,116.24 124.76,116.24 124.66,116.14 124.66,115.94 124.76,115.83 125.9,115.83 126.16,115.57 126.16,115.13 125.9,114.87 124.76,114.87 124.66,114.77 124.66,114.56 124.76,114.46 125.9,114.46 126.16,114.2 126.16,113.76 125.9,113.5 124.76,113.5 124.66,113.4 124.66,113.19 124.76,113.09 125.9,113.09 126.16,112.83 126.16,112.39 125.9,112.13 124.76,112.13 124.66,112.02 124.66,111.82 124.76,111.72 125.9,111.72 126.16,111.45 126.16,111.02 125.9,110.75 124.76,110.75 124.66,110.65 124.66,110.45 124.76,110.35 125.9,110.35 126.16,110.08 126.16,109.65 125.9,109.38 124.76,109.38 124.66,109.28 124.66,109.08 124.76,108.98 125.9,108.98 126.16,108.71 126.16,108.28 125.9,108.01 124.76,108.01 124.66,107.91 124.66,107.71 124.76,107.6 125.9,107.6 126.16,107.34 126.16,106.9 125.9,106.64 124.76,106.64 124.66,106.54 124.66,106.33 124.76,106.23 125.9,106.23 126.16,105.97 126.16,105.53 125.9,105.27 124.76,105.27 124.66,105.17 124.66,104.96 124.76,104.86 125.9,104.86 126.16,104.6 126.16,104.16 125.9,103.9 124.76,103.9 124.66,103.79 124.66,103.59 124.76,103.49 125.9,103.49 126.16,103.22 126.16,102.79 125.9,102.52 124.76,102.52 124.66,102.42 124.66,102.22 124.76,102.12 125.9,102.12 126.16,101.85 126.16,101.42 125.9,101.15 124.76,101.15 124.66,101.05 124.66,100.85 124.76,100.75 125.9,100.75 126.16,100.48 126.16,100.05 125.9,99.78 124.76,99.78 124.66,99.68 124.66,98.61 122.3,96.25 122.3,95.5 120.99,94.19 120.99,94.01 120.8,93.83 120.62,93.83 120.57,93.77 120.57,85.85 120.31,85.59 120.21,85.59 120.21,85.58 120.01,85.58 116.27,85.58 116.26,85.59 116.21,85.59 116.21,85.58 115.69,85.58 115.69,85.59 115.68,85.59 115.33,85.94 115.33,88.82 v2(114.95,89.2)
  BOTTOM w0.114: v1(120.65,140.59) 120.65,142.82 120.35,143.13 120.35,144.1 J3.19
INPUT12_P: length 118.6
  TOP w0.114: U5.K6 v2(115.95,88.2)
  L3-SIG1 w0.102: v1(119.78,140.59) 119.79,140.59 120.12,140.26 120.12,139.89 121.39,138.62 121.39,136.08 124.38,133.09 124.38,132.16 124.08,131.85 124.08,131.52 124.18,131.42 124.28,131.42 124.38,131.31 124.38,131.11 124.28,131.01 124.18,131.01 124.08,130.91 124.08,130.7 124.18,130.6 124.28,130.6 124.38,130.5 124.38,130.3 124.28,130.2 124.18,130.2 124.08,130.09 124.08,129.89 124.18,129.79 124.28,129.79 124.38,129.69 124.38,129.23 124.28,129.13 124.22,129.13 123.95,128.87 123.95,128.43 124.22,128.17 124.71,128.17 124.82,128.06 124.82,127.86 124.71,127.76 124.22,127.76 123.95,127.49 123.95,127.06 124.22,126.79 124.71,126.79 124.82,126.69 124.82,126.49 124.71,126.39 124.22,126.39 123.95,126.12 123.95,125.69 124.22,125.42 124.71,125.42 124.82,125.32 124.82,125.12 124.71,125.02 124.65,125.02 124.38,124.75 124.38,123.63 125.6,122.41 125.78,122.41 125.88,122.31 125.88,122.11 125.78,122.01 124.65,122.01 124.38,121.74 124.38,121.31 124.65,121.04 125.78,121.04 125.88,120.94 125.88,120.74 125.78,120.63 124.65,120.63 124.38,120.37 124.38,119.93 124.65,119.67 125.78,119.67 125.88,119.57 125.88,119.36 125.78,119.26 124.65,119.26 124.38,119 124.38,118.56 124.65,118.3 125.78,118.3 125.88,118.2 125.88,117.99 125.78,117.89 124.65,117.89 124.38,117.63 124.38,117.19 124.65,116.93 125.78,116.93 125.88,116.82 125.88,116.62 125.78,116.52 124.65,116.52 124.38,116.25 124.38,115.82 124.65,115.55 125.78,115.55 125.88,115.45 125.88,115.25 125.78,115.15 124.65,115.15 124.38,114.88 124.38,114.45 124.65,114.18 125.78,114.18 125.88,114.08 125.88,113.88 125.78,113.78 124.65,113.78 124.38,113.51 124.38,113.08 124.65,112.81 125.78,112.81 125.88,112.71 125.88,112.51 125.78,112.41 124.65,112.41 124.38,112.14 124.38,111.71 124.65,111.44 125.78,111.44 125.88,111.34 125.88,111.14 125.78,111.03 124.65,111.03 124.38,110.77 124.38,110.33 124.65,110.07 125.78,110.07 125.88,109.97 125.88,109.76 125.78,109.66 124.65,109.66 124.38,109.4 124.38,108.96 124.65,108.7 125.78,108.7 125.88,108.6 125.88,108.39 125.78,108.29 124.65,108.29 124.38,108.03 124.38,107.59 124.65,107.33 125.78,107.33 125.88,107.22 125.88,107.02 125.78,106.92 124.65,106.92 124.38,106.65 124.38,106.22 124.65,105.95 125.78,105.95 125.88,105.85 125.88,105.65 125.78,105.55 124.65,105.55 124.38,105.28 124.38,104.85 124.65,104.58 125.78,104.58 125.88,104.48 125.88,104.28 125.78,104.18 124.65,104.18 124.38,103.91 124.38,103.48 124.65,103.21 125.78,103.21 125.88,103.11 125.88,102.91 125.78,102.8 124.65,102.8 124.38,102.54 124.38,102.1 124.65,101.84 125.78,101.84 125.88,101.74 125.88,101.53 125.78,101.43 124.65,101.43 124.38,101.17 124.38,100.73 124.65,100.47 125.78,100.47 125.88,100.37 125.88,100.16 125.78,100.06 124.65,100.06 124.38,99.8 124.38,98.73 122.02,96.37 122.02,95.62 120.71,94.3 120.71,94.11 120.67,94.07 120.53,94.07 120.33,93.87 120.33,85.95 120.21,85.83 120.12,85.83 120.11,85.82 116.36,85.82 116.36,85.83 116.12,85.83 116.11,85.82 115.79,85.82 115.78,85.83 115.78,85.83 115.57,86.04 115.57,88.26 115.67,88.36 115.79,88.36 v2(115.95,88.2)
  BOTTOM w0.114: v1(119.78,140.59) 120.02,140.59 120.35,140.92 120.35,142.72 120.02,143.05 120.02,144.13 J3.21
INPUT13_M: length 118.5
  TOP w0.114: U5.K5 v2(115.95,89.2)
  L3-SIG1 w0.102: v1(119.13,141.99) 118.85,141.71 118.85,135.37 119.37,134.85 120.94,134.85 121.64,134.15 121.64,132.78 121.54,132.68 121.44,132.68 121.34,132.57 121.34,132.37 121.44,132.27 121.54,132.27 121.64,132.17 121.64,131.97 121.54,131.86 121.44,131.86 121.34,131.76 121.34,131.56 121.44,131.46 121.54,131.46 121.64,131.36 121.64,130.95 121.91,130.69 122.86,130.69 122.96,130.59 122.96,130.38 122.86,130.28 121.91,130.28 121.64,130.02 121.64,129.58 121.91,129.32 122.86,129.32 122.96,129.22 122.96,129.01 122.86,128.91 121.91,128.91 121.64,128.65 121.64,128.21 121.91,127.95 122.86,127.95 122.96,127.84 122.96,127.64 122.86,127.54 121.91,127.54 121.64,127.27 121.64,126.84 121.91,126.57 122.86,126.57 122.96,126.47 122.96,126.27 122.86,126.17 121.91,126.17 121.64,125.9 121.64,125.47 121.91,125.2 122.86,125.2 122.96,125.1 122.96,124.9 122.86,124.8 121.91,124.8 121.64,124.53 121.64,124.1 121.91,123.83 122.86,123.83 122.96,123.73 122.96,123.53 122.86,123.43 121.91,123.43 121.64,123.16 121.64,122.73 121.91,122.46 122.86,122.46 122.96,122.36 122.96,122.16 122.86,122.05 121.91,122.05 121.64,121.79 121.64,121.35 121.91,121.09 122.86,121.09 122.96,120.99 122.96,120.78 122.86,120.68 121.91,120.68 121.64,120.42 121.64,119.98 121.91,119.72 122.86,119.72 122.96,119.62 122.96,119.41 122.86,119.31 121.91,119.31 121.64,119.05 121.64,118.61 121.91,118.35 122.86,118.35 122.96,118.24 122.96,118.04 122.86,117.94 121.91,117.94 121.64,117.67 121.64,117.24 121.91,116.97 122.86,116.97 122.96,116.87 122.96,116.67 122.86,116.57 121.91,116.57 121.64,116.3 121.64,115.87 121.91,115.6 122.86,115.6 122.96,115.5 122.96,115.3 122.86,115.2 121.91,115.2 121.64,114.93 121.64,114.5 121.91,114.23 122.86,114.23 122.96,114.13 122.96,113.93 122.86,113.82 121.91,113.82 121.64,113.56 121.64,113.12 121.91,112.86 122.86,112.86 122.96,112.76 122.96,112.55 122.86,112.45 121.91,112.45 121.64,112.19 121.64,111.75 121.91,111.49 122.86,111.49 122.96,111.39 122.96,111.18 122.86,111.08 121.91,111.08 121.64,110.82 121.64,110.38 121.91,110.12 122.86,110.12 122.96,110.01 122.96,109.81 122.86,109.71 121.91,109.71 121.64,109.44 121.64,109.01 121.91,108.74 122.86,108.74 122.96,108.64 122.96,108.44 122.86,108.34 121.91,108.34 121.64,108.07 121.64,107.64 121.91,107.37 122.86,107.37 122.96,107.27 122.96,107.07 122.86,106.97 121.91,106.97 121.64,106.7 121.64,106.27 121.91,106 122.86,106 122.96,105.9 122.96,105.7 122.86,105.59 121.91,105.59 121.64,105.33 121.64,104.89 121.91,104.63 122.86,104.63 122.96,104.53 122.96,104.32 122.86,104.22 121.91,104.22 121.64,103.96 121.64,103.52 121.91,103.26 122.86,103.26 122.96,103.16 122.96,102.95 122.86,102.85 121.91,102.85 121.64,102.59 121.64,102.15 121.91,101.89 122.86,101.89 122.96,101.78 122.96,101.58 122.86,101.48 121.91,101.48 121.64,101.21 121.64,100.95 120.12,99.43 120.12,98.79 119.29,97.97 119.29,96.45 119.53,96.2 119.53,94.65 119.33,94.45 119.33,93.53 119.33,93.52 119.33,92.85 119.33,92.85 119.33,92.36 119.33,92.36 119.33,91.94 119.33,91.94 119.33,89.36 119.33,89.36 119.33,89.04 119.33,89.04 119.33,88.36 119.33,88.36 119.33,88.04 119.33,88.04 119.33,87.36 119.33,87.36 119.33,87.04 119.33,87.04 119.33,86.9 119.25,86.82 116.59,86.82 116.57,86.84 116.57,88.36 116.57,88.71 116.68,88.82 117.11,88.82 117.38,89.09 117.38,89.35 117.12,89.61 116.36,89.61 v2(115.95,89.2)
  BOTTOM w0.114: J3.25 118.85,144.1 118.85,142.27 v1(119.13,141.99)
INPUT13_P: length 118.6
  TOP w0.114: U5.J5 v2(116.95,89.2)
  L3-SIG1 w0.102: v1(118.28,141.96) 118.72,142.39 119.29,142.39 119.53,142.15 119.53,141.82 119.13,141.41 119.13,135.49 119.48,135.13 121.05,135.13 121.92,134.26 121.92,131.07 122.02,130.97 122.98,130.97 123.24,130.7 123.24,130.27 122.98,130 122.02,130 121.92,129.9 121.92,129.7 122.02,129.6 122.98,129.6 123.24,129.33 123.24,128.9 122.98,128.63 122.02,128.63 121.92,128.53 121.92,128.33 122.02,128.23 122.98,128.23 123.24,127.96 123.24,127.53 122.98,127.26 122.02,127.26 121.92,127.16 121.92,126.96 122.02,126.85 122.98,126.85 123.24,126.59 123.24,126.15 122.98,125.89 122.02,125.89 121.92,125.79 121.92,125.58 122.02,125.48 122.98,125.48 123.24,125.22 123.24,124.78 122.98,124.52 122.02,124.52 121.92,124.42 121.92,124.21 122.02,124.11 122.98,124.11 123.24,123.85 123.24,123.41 122.98,123.15 122.02,123.15 121.92,123.04 121.92,122.84 122.02,122.74 122.98,122.74 123.24,122.47 123.24,122.04 122.98,121.77 122.02,121.77 121.92,121.67 121.92,121.47 122.02,121.37 122.98,121.37 123.24,121.1 123.24,120.67 122.98,120.4 122.02,120.4 121.92,120.3 121.92,120.1 122.02,120 122.98,120 123.24,119.73 123.24,119.3 122.98,119.03 122.02,119.03 121.92,118.93 121.92,118.73 122.02,118.62 122.98,118.62 123.24,118.36 123.24,117.92 122.98,117.66 122.02,117.66 121.92,117.56 121.92,117.35 122.02,117.25 122.98,117.25 123.24,116.99 123.24,116.55 122.98,116.29 122.02,116.29 121.92,116.19 121.92,115.98 122.02,115.88 122.98,115.88 123.24,115.62 123.24,115.18 122.98,114.92 122.02,114.92 121.92,114.81 121.92,114.61 122.02,114.51 122.98,114.51 123.24,114.24 123.24,113.81 122.98,113.54 122.02,113.54 121.92,113.44 121.92,113.24 122.02,113.14 122.98,113.14 123.24,112.87 123.24,112.44 122.98,112.17 122.02,112.17 121.92,112.07 121.92,111.87 122.02,111.77 122.98,111.77 123.24,111.5 123.24,111.07 122.98,110.8 122.02,110.8 121.92,110.7 121.92,110.5 122.02,110.4 122.98,110.4 123.24,110.13 123.24,109.7 122.98,109.43 122.02,109.43 121.92,109.33 121.92,109.13 122.02,109.02 122.98,109.02 123.24,108.76 123.24,108.32 122.98,108.06 122.02,108.06 121.92,107.96 121.92,107.75 122.02,107.65 122.98,107.65 123.24,107.39 123.24,106.95 122.98,106.69 122.02,106.69 121.92,106.59 121.92,106.38 122.02,106.28 122.98,106.28 123.24,106.01 123.24,105.58 122.98,105.32 122.02,105.32 121.92,105.21 121.92,105.01 122.02,104.91 122.98,104.91 123.24,104.64 123.24,104.21 122.98,103.94 122.02,103.94 121.92,103.84 121.92,103.64 122.02,103.54 122.98,103.54 123.24,103.27 123.24,102.84 122.98,102.57 122.02,102.57 121.92,102.47 121.92,102.27 122.02,102.17 122.98,102.17 123.24,101.9 123.24,101.47 122.98,101.2 122.02,101.2 121.92,101.1 121.92,100.84 120.4,99.31 120.4,98.68 119.57,97.85 119.57,96.56 119.81,96.32 119.81,94.53 119.61,94.33 119.61,93.99 119.57,93.95 119.57,93.62 119.57,93.62 119.57,92.75 119.57,92.75 119.57,92.46 119.57,92.46 119.57,91.84 119.57,91.84 119.57,89.46 119.57,89.46 119.57,88.94 119.57,88.94 119.57,88.46 119.57,88.46 119.57,87.94 119.57,87.94 119.57,87.46 119.57,87.46 119.57,86.94 119.57,86.94 119.57,86.8 119.35,86.58 116.49,86.58 116.33,86.74 116.33,88.46 116.33,88.46 116.33,89.08 116.59,89.33 116.82,89.33 v2(116.95,89.2)
  BOTTOM w0.114: J3.27 118.55,144.09 118.55,142.23 v1(118.28,141.96)
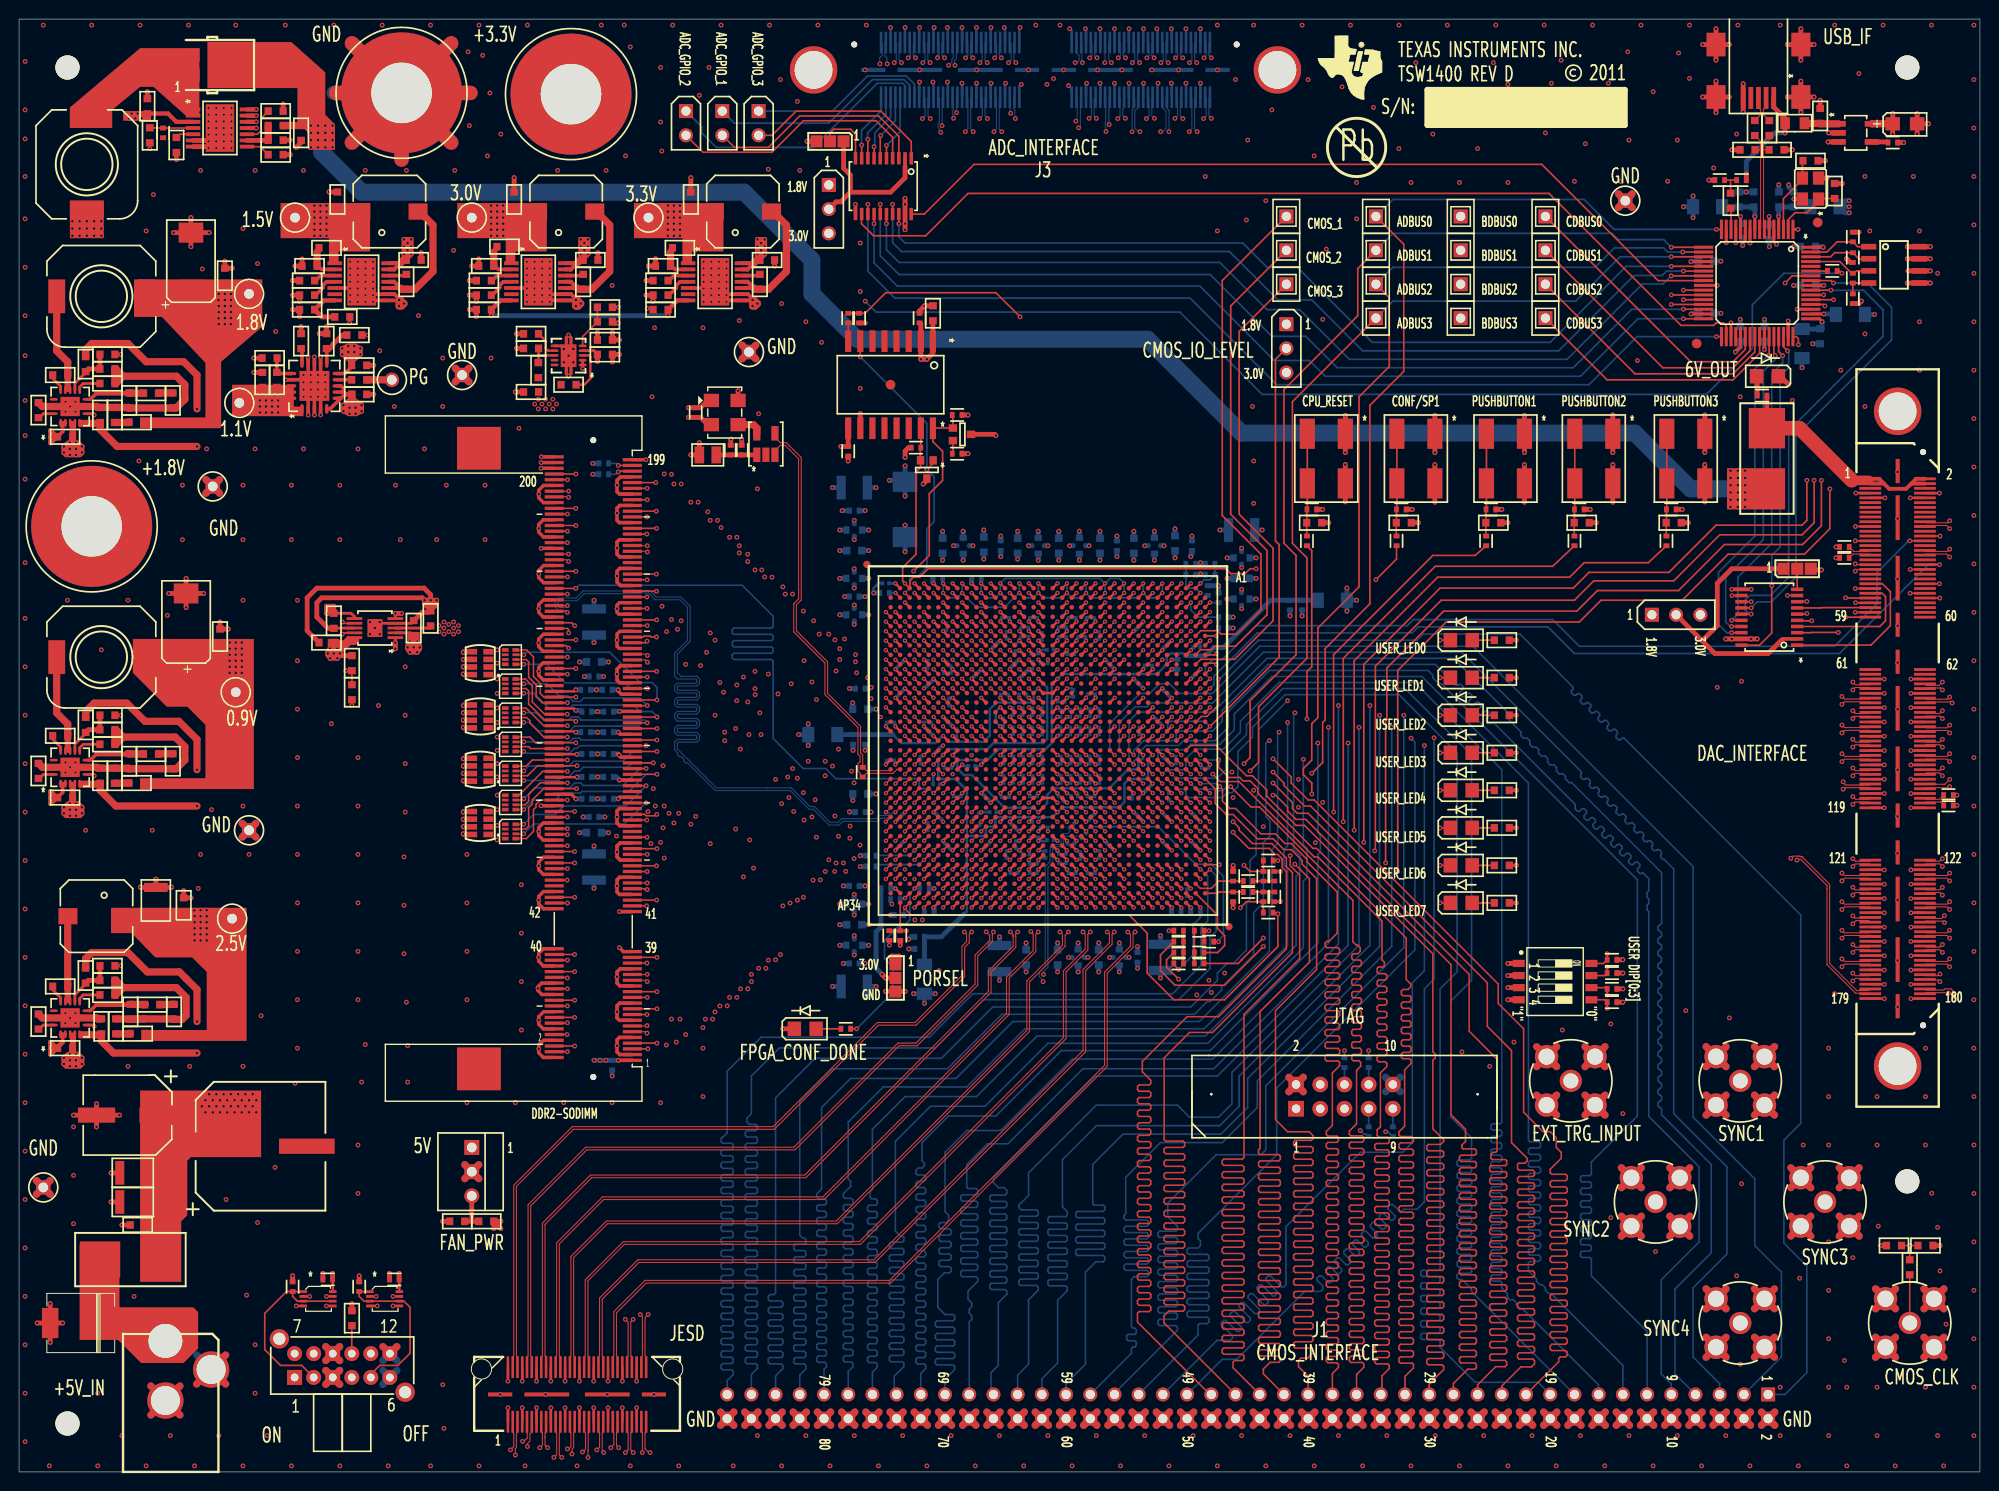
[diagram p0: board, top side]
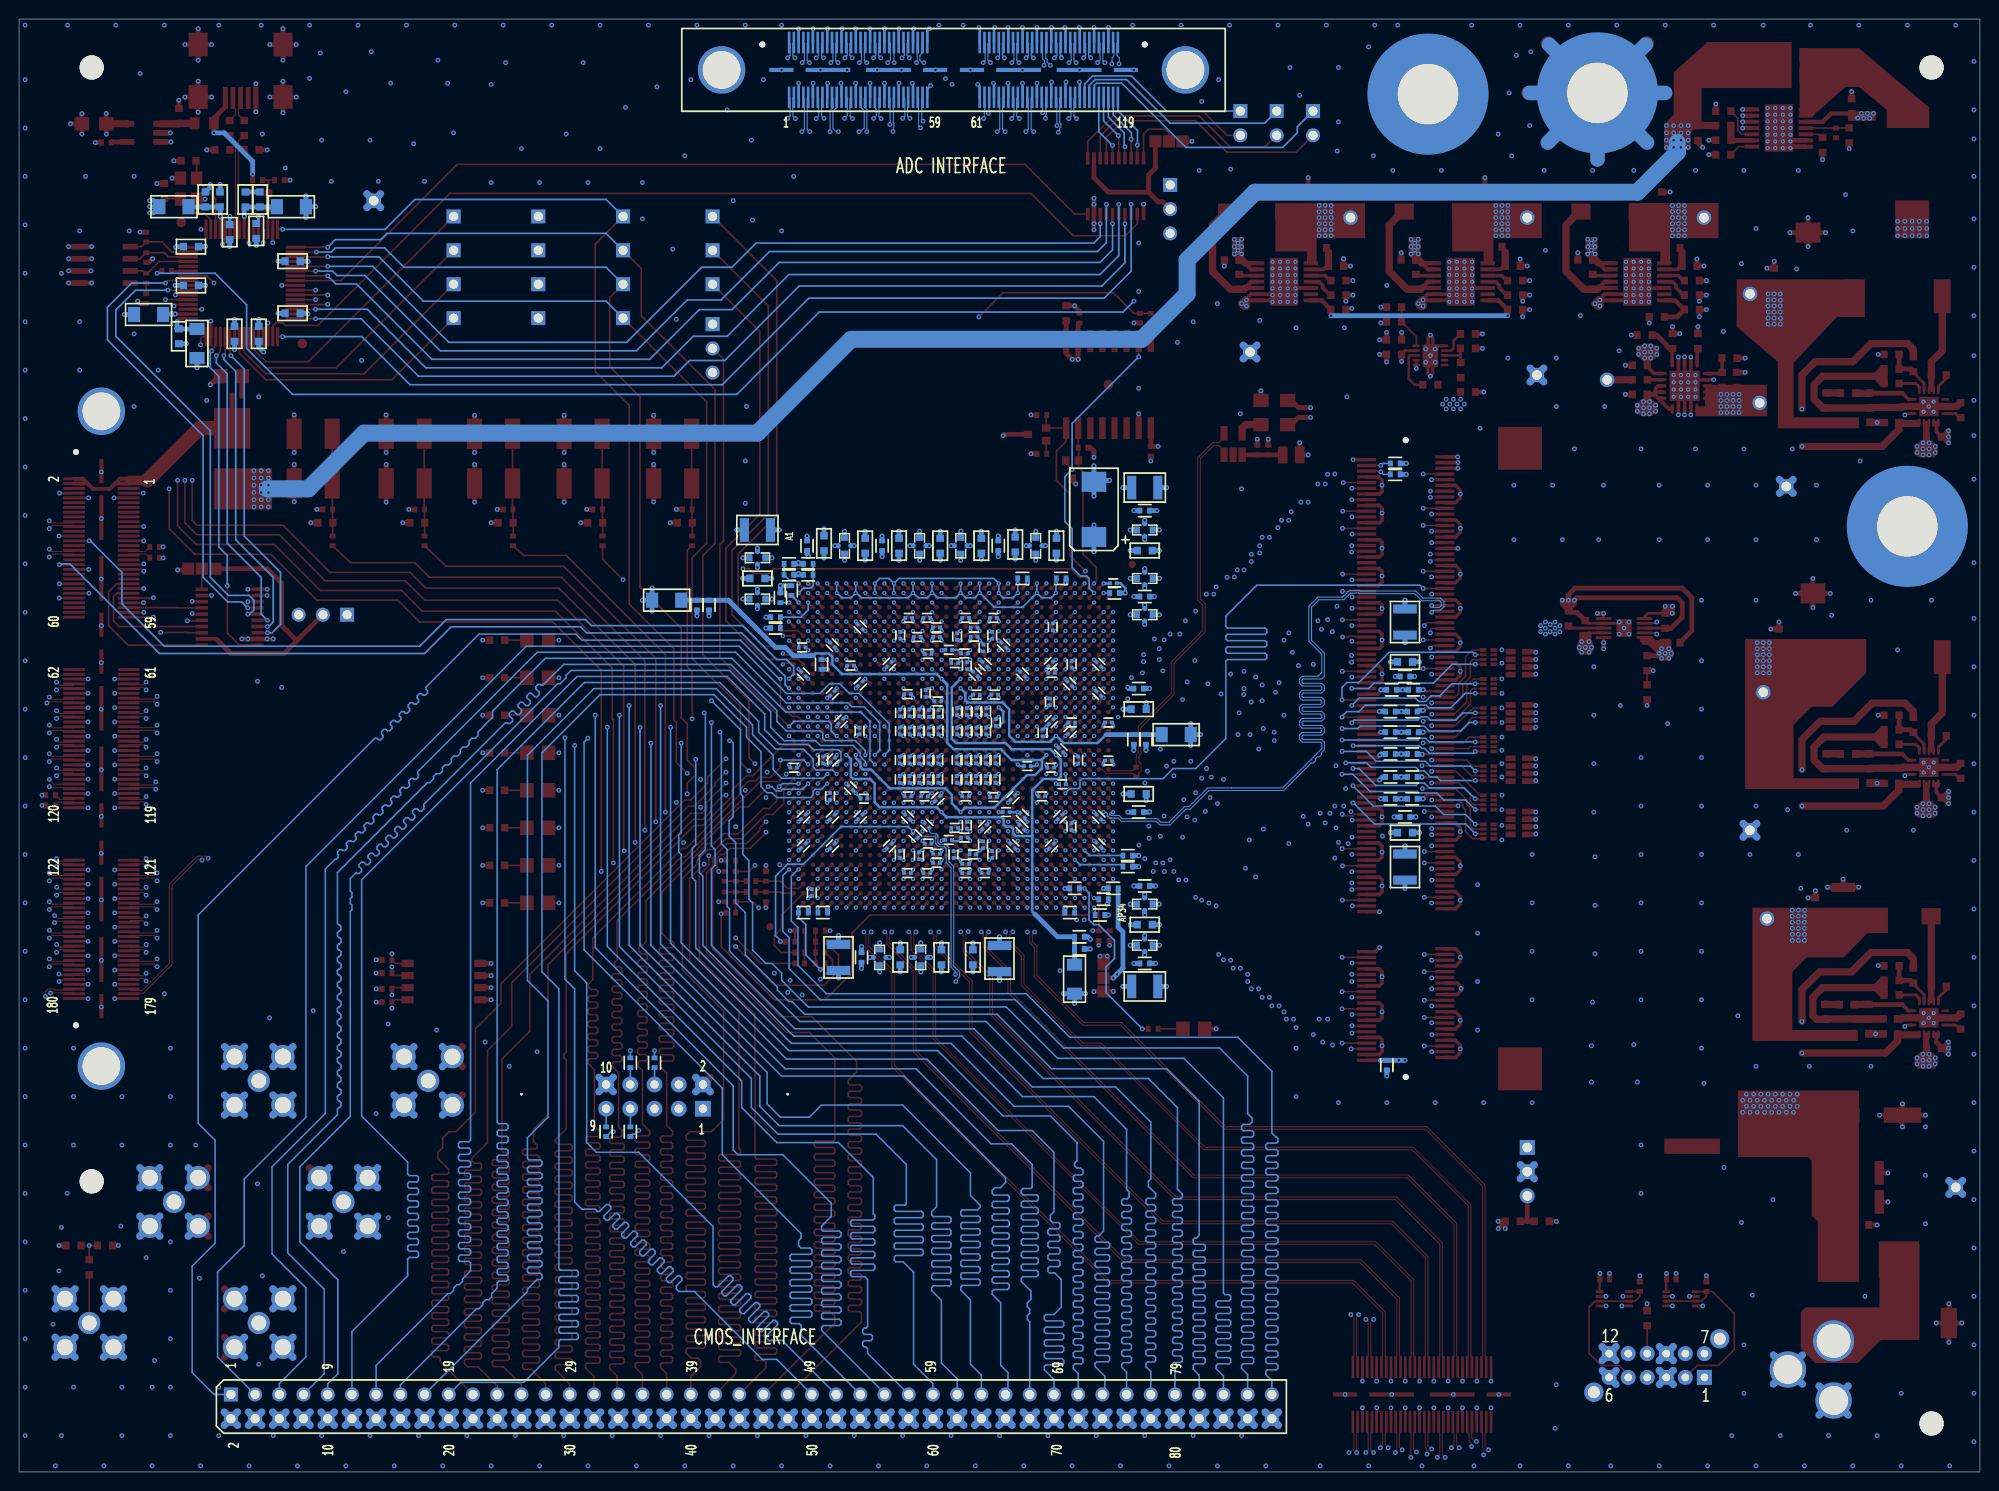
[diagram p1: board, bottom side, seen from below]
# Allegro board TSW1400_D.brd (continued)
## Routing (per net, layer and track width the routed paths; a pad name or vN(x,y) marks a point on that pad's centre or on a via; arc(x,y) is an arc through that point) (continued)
INPUT14_M: length 118.4
  TOP w0.114: U5.H6 v2(117.95,88.2)
  L3-SIG1 w0.102: v2(117.95,88.2) 117.94,88.21 117.45,88.21 117.4,88.16 117.4,87.96 117.53,87.83 118.21,87.83 118.33,87.96 118.33,88.45 118.33,88.46 118.33,93.72 118.11,93.94 118.11,93.97 117.69,94.38 117.69,96.41 117.3,96.81 117.3,97.68 117.83,98.21 117.83,98.72 119.19,100.08 119.19,100.73 119.46,100.99 120.52,100.99 120.62,101.09 120.62,101.3 120.52,101.4 119.46,101.4 119.19,101.66 119.19,102.1 119.46,102.36 120.52,102.36 120.62,102.47 120.62,102.67 120.52,102.77 119.46,102.77 119.19,103.04 119.19,103.47 119.46,103.74 120.52,103.74 120.62,103.84 120.62,104.04 120.52,104.14 119.46,104.14 119.19,104.41 119.19,104.84 119.46,105.11 120.52,105.11 120.62,105.21 120.62,105.41 120.52,105.51 119.46,105.51 119.19,105.78 119.19,106.21 119.46,106.48 120.52,106.48 120.62,106.58 120.62,106.78 120.52,106.89 119.46,106.89 119.19,107.15 119.19,107.59 119.46,107.85 120.52,107.85 120.62,107.95 120.62,108.16 120.52,108.26 119.46,108.26 119.19,108.52 119.19,108.96 119.46,109.22 120.52,109.22 120.62,109.32 120.62,109.53 120.52,109.63 119.46,109.63 119.19,109.89 119.19,110.33 119.46,110.59 120.52,110.59 120.62,110.7 120.62,110.9 120.52,111 119.46,111 119.19,111.27 119.19,111.7 119.46,111.97 120.52,111.97 120.62,112.07 120.62,112.27 120.52,112.37 119.46,112.37 119.19,112.64 119.19,113.07 119.46,113.34 120.52,113.34 120.62,113.44 120.62,113.64 120.52,113.74 119.46,113.74 119.19,114.01 119.19,114.44 119.46,114.71 120.52,114.71 120.62,114.81 120.62,115.01 120.52,115.12 119.46,115.12 119.19,115.38 119.19,115.82 119.46,116.08 120.52,116.08 120.62,116.18 120.62,116.39 120.52,116.49 119.46,116.49 119.19,116.75 119.19,117.19 119.46,117.45 120.52,117.45 120.62,117.55 120.62,117.76 120.52,117.86 119.46,117.86 119.19,118.12 119.19,118.56 119.46,118.82 120.52,118.82 120.62,118.93 120.62,119.13 120.52,119.23 119.46,119.23 119.19,119.5 119.19,119.93 119.46,120.2 120.52,120.2 120.62,120.3 120.62,120.5 120.52,120.6 119.46,120.6 119.19,120.87 119.19,121.3 119.46,121.57 120.52,121.57 120.62,121.67 120.62,121.87 120.52,121.97 119.46,121.97 119.19,122.24 119.19,122.67 119.46,122.94 120.52,122.94 120.62,123.04 120.62,123.24 120.52,123.35 119.46,123.35 119.19,123.61 119.19,124.05 119.46,124.31 120.52,124.31 120.62,124.41 120.62,124.62 120.52,124.72 119.46,124.72 119.19,124.98 119.19,125.42 119.46,125.68 120.52,125.68 120.62,125.78 120.62,125.99 120.52,126.09 119.46,126.09 119.19,126.35 119.19,126.79 119.46,127.05 120.52,127.05 120.62,127.16 120.62,127.36 120.52,127.46 119.46,127.46 119.19,127.73 119.19,128.16 119.46,128.43 120.52,128.43 120.62,128.53 120.62,128.73 120.52,128.83 119.46,128.83 119.19,129.1 119.19,129.53 119.46,129.8 120.52,129.8 120.62,129.9 120.62,130.1 120.52,130.2 119.46,130.2 119.19,130.47 119.19,130.9 119.46,131.17 120.52,131.17 120.62,131.27 120.62,131.47 120.52,131.57 119.46,131.57 119.19,131.84 119.19,132.11 119.09,132.21 118.54,132.21 118.44,132.32 118.44,132.52 118.54,132.62 119.09,132.62 119.19,132.72 119.19,133.64 117.75,135.08 117.75,140.44 v1(117.61,140.59)
  BOTTOM w0.114: v1(117.61,140.59) 117.45,140.59 117.06,140.97 117.06,142.78 117.35,143.07 117.35,144.1 J3.31
INPUT14_P: length 118.6
  TOP w0.114: U5.J7 v2(116.95,87.2)
  L3-SIG1 w0.102: v2(116.95,87.2) 117.35,87.6 118.3,87.6 118.57,87.86 118.57,88.36 118.57,88.36 118.57,93.82 118.39,94 118.39,94.08 117.97,94.5 117.97,96.53 117.58,96.93 117.58,97.56 118.11,98.09 118.11,98.6 119.47,99.96 119.47,100.61 119.57,100.71 120.64,100.71 120.9,100.98 120.9,101.41 120.64,101.68 119.57,101.68 119.47,101.78 119.47,101.98 119.57,102.09 120.64,102.09 120.9,102.35 120.9,102.79 120.64,103.05 119.57,103.05 119.47,103.15 119.47,103.36 119.57,103.46 120.64,103.46 120.9,103.72 120.9,104.16 120.64,104.42 119.57,104.42 119.47,104.52 119.47,104.73 119.57,104.83 120.64,104.83 120.9,105.09 120.9,105.53 120.64,105.79 119.57,105.79 119.47,105.9 119.47,106.1 119.57,106.2 120.64,106.2 120.9,106.47 120.9,106.9 120.64,107.17 119.57,107.17 119.47,107.27 119.47,107.47 119.57,107.57 120.64,107.57 120.9,107.84 120.9,108.27 120.64,108.54 119.57,108.54 119.47,108.64 119.47,108.84 119.57,108.94 120.64,108.94 120.9,109.21 120.9,109.64 120.64,109.91 119.57,109.91 119.47,110.01 119.47,110.21 119.57,110.32 120.64,110.32 120.9,110.58 120.9,111.02 120.64,111.28 119.57,111.28 119.47,111.38 119.47,111.59 119.57,111.69 120.64,111.69 120.9,111.95 120.9,112.39 120.64,112.65 119.57,112.65 119.47,112.75 119.47,112.96 119.57,113.06 120.64,113.06 120.9,113.32 120.9,113.76 120.64,114.02 119.57,114.02 119.47,114.13 119.47,114.33 119.57,114.43 120.64,114.43 120.9,114.7 120.9,115.13 120.64,115.4 119.57,115.4 119.47,115.5 119.47,115.7 119.57,115.8 120.64,115.8 120.9,116.07 120.9,116.5 120.64,116.77 119.57,116.77 119.47,116.87 119.47,117.07 119.57,117.17 120.64,117.17 120.9,117.44 120.9,117.87 120.64,118.14 119.57,118.14 119.47,118.24 119.47,118.44 119.57,118.54 120.64,118.54 120.9,118.81 120.9,119.24 120.64,119.51 119.57,119.51 119.47,119.61 119.47,119.81 119.57,119.92 120.64,119.92 120.9,120.18 120.9,120.62 120.64,120.88 119.57,120.88 119.47,120.98 119.47,121.19 119.57,121.29 120.64,121.29 120.9,121.55 120.9,121.99 120.64,122.25 119.57,122.25 119.47,122.35 119.47,122.56 119.57,122.66 120.64,122.66 120.9,122.92 120.9,123.36 120.64,123.62 119.57,123.62 119.47,123.73 119.47,123.93 119.57,124.03 120.64,124.03 120.9,124.3 120.9,124.73 120.64,125 119.57,125 119.47,125.1 119.47,125.3 119.57,125.4 120.64,125.4 120.9,125.67 120.9,126.1 120.64,126.37 119.57,126.37 119.47,126.47 119.47,126.67 119.57,126.77 120.64,126.77 120.9,127.04 120.9,127.47 120.64,127.74 119.57,127.74 119.47,127.84 119.47,128.04 119.57,128.15 120.64,128.15 120.9,128.41 120.9,128.85 120.64,129.11 119.57,129.11 119.47,129.21 119.47,129.42 119.57,129.52 120.64,129.52 120.9,129.78 120.9,130.22 120.64,130.48 119.57,130.48 119.47,130.58 119.47,130.79 119.57,130.89 120.64,130.89 120.9,131.15 120.9,131.59 120.64,131.85 119.57,131.85 119.47,131.96 119.47,133.76 118.03,135.19 118.03,140.74 117.75,141.02 117.22,141.02 v1(116.78,140.59)
  BOTTOM w0.114: v1(116.78,140.59) 116.78,142.9 117.07,143.18 117.07,144.07 J3.33
INPUT15_M: length 118.6
  TOP w0.114: U5.M5 v2(113.95,89.2)
  L3-SIG1 w0.102: v1(116.08,141.99) 115.81,141.72 115.81,140.37 116.58,139.6 116.58,135.05 117.59,134.05 117.59,131.66 117.96,131.29 118.09,131.29 118.36,131.02 118.36,130.59 118.09,130.32 116.92,130.32 116.81,130.22 116.81,130.02 116.92,129.92 118.09,129.92 118.36,129.65 118.36,129.22 118.09,128.95 116.92,128.95 116.81,128.85 116.81,128.65 116.92,128.54 118.09,128.54 118.36,128.28 118.36,127.84 118.09,127.58 116.92,127.58 116.81,127.48 116.81,127.27 116.92,127.17 118.09,127.17 118.36,126.91 118.36,126.47 118.09,126.21 116.92,126.21 116.81,126.11 116.81,125.9 116.92,125.8 118.09,125.8 118.36,125.54 118.36,125.1 118.09,124.84 116.92,124.84 116.81,124.73 116.81,124.53 116.92,124.43 118.09,124.43 118.36,124.16 118.36,123.73 118.09,123.46 116.92,123.46 116.81,123.36 116.81,123.16 116.92,123.06 118.09,123.06 118.36,122.79 118.36,122.36 118.09,122.09 116.92,122.09 116.81,121.99 116.81,121.79 116.92,121.69 118.09,121.69 118.36,121.42 118.36,120.99 118.09,120.72 116.92,120.72 116.81,120.62 116.81,120.42 116.92,120.32 118.09,120.32 118.36,120.05 118.36,119.62 118.09,119.35 116.92,119.35 116.81,119.25 116.81,119.05 116.92,118.94 118.09,118.94 118.36,118.68 118.36,118.24 118.09,117.98 116.92,117.98 116.81,117.88 116.81,117.67 116.92,117.57 118.09,117.57 118.36,117.31 118.36,116.87 118.09,116.61 116.92,116.61 116.81,116.51 116.81,116.3 116.92,116.2 118.09,116.2 118.36,115.93 118.36,115.5 118.09,115.24 116.92,115.24 116.81,115.13 116.81,114.93 116.92,114.83 118.09,114.83 118.36,114.56 118.36,114.13 118.09,113.86 116.92,113.86 116.81,113.76 116.81,113.56 116.92,113.46 118.09,113.46 118.36,113.19 118.36,112.76 118.09,112.49 116.92,112.49 116.81,112.39 116.81,112.19 116.92,112.09 118.09,112.09 118.36,111.82 118.36,111.39 118.09,111.12 116.92,111.12 116.81,111.02 116.81,110.82 116.92,110.71 118.09,110.71 118.36,110.45 118.36,110.01 118.09,109.75 116.92,109.75 116.81,109.65 116.81,109.44 116.92,109.34 118.09,109.34 118.36,109.08 118.36,108.64 118.09,108.38 116.92,108.38 116.81,108.28 116.81,108.07 116.92,107.97 118.09,107.97 118.36,107.71 118.36,107.27 118.09,107.01 116.92,107.01 116.81,106.9 116.81,106.7 116.92,106.6 118.09,106.6 118.36,106.33 118.36,105.9 118.09,105.63 116.92,105.63 116.81,105.53 116.81,105.33 116.92,105.23 118.09,105.23 118.36,104.96 118.36,104.53 118.09,104.26 116.92,104.26 116.81,104.16 116.81,103.96 116.92,103.86 118.09,103.86 118.36,103.59 118.36,103.16 118.09,102.89 116.92,102.89 116.81,102.79 116.81,102.59 116.92,102.48 118.09,102.48 118.36,102.22 118.36,101.78 118.09,101.52 116.92,101.52 116.81,101.42 116.81,101.21 116.92,101.11 117.32,101.11 117.59,100.85 117.59,100.26 116.54,99.21 116.54,94.11 116.49,94.07 116.49,93.77 116.54,93.72 116.54,93.48 116.57,93.46 116.57,90.92 116.23,90.58 115.57,90.58 114.55,89.56 113.69,89.56 113.6,89.47 113.6,88.9 113.65,88.85 113.65,88.84 113.74,88.75 113.88,88.75 113.97,88.83 113.97,89.18 v2(113.95,89.2)
  BOTTOM w0.114: J3.37 115.87,144.12 115.87,142.98 115.8,142.9 115.8,142.26 116.07,141.99 v1(116.08,141.99)
INPUT15_P: length 118.6
  TOP w0.114: U5.M6 v2(113.95,88.2)
  L3-SIG1 w0.102: v2(113.95,88.2) 113.41,88.74 113.41,88.75 113.36,88.8 113.36,89.59 113.59,89.81 114.47,89.81 115.48,90.82 116.14,90.82 116.33,91.01 116.33,93.36 116.31,93.38 116.31,93.62 116.23,93.7 116.23,99.3 117.31,100.38 117.31,100.73 117.21,100.83 116.8,100.83 116.54,101.1 116.54,101.53 116.8,101.8 117.98,101.8 118.08,101.9 118.08,102.1 117.98,102.2 116.8,102.2 116.54,102.47 116.54,102.9 116.8,103.17 117.98,103.17 118.08,103.27 118.08,103.47 117.98,103.58 116.8,103.58 116.54,103.84 116.54,104.28 116.8,104.54 117.98,104.54 118.08,104.64 118.08,104.85 117.98,104.95 116.8,104.95 116.54,105.21 116.54,105.65 116.8,105.91 117.98,105.91 118.08,106.01 118.08,106.22 117.98,106.32 116.8,106.32 116.54,106.58 116.54,107.02 116.8,107.28 117.98,107.28 118.08,107.39 118.08,107.59 117.98,107.69 116.8,107.69 116.54,107.96 116.54,108.39 116.8,108.66 117.98,108.66 118.08,108.76 118.08,108.96 117.98,109.06 116.8,109.06 116.54,109.33 116.54,109.76 116.8,110.03 117.98,110.03 118.08,110.13 118.08,110.33 117.98,110.43 116.8,110.43 116.54,110.7 116.54,111.13 116.8,111.4 117.98,111.4 118.08,111.5 118.08,111.7 117.98,111.81 116.8,111.81 116.54,112.07 116.54,112.51 116.8,112.77 117.98,112.77 118.08,112.87 118.08,113.08 117.98,113.18 116.8,113.18 116.54,113.44 116.54,113.88 116.8,114.14 117.98,114.14 118.08,114.24 118.08,114.45 117.98,114.55 116.8,114.55 116.54,114.81 116.54,115.25 116.8,115.51 117.98,115.51 118.08,115.62 118.08,115.82 117.98,115.92 116.8,115.92 116.54,116.19 116.54,116.62 116.8,116.89 117.98,116.89 118.08,116.99 118.08,117.19 117.98,117.29 116.8,117.29 116.54,117.56 116.54,117.99 116.8,118.26 117.98,118.26 118.08,118.36 118.08,118.56 117.98,118.66 116.8,118.66 116.54,118.93 116.54,119.36 116.8,119.63 117.98,119.63 118.08,119.73 118.08,119.93 117.98,120.04 116.8,120.04 116.54,120.3 116.54,120.74 116.8,121 117.98,121 118.08,121.1 118.08,121.31 117.98,121.41 116.8,121.41 116.54,121.67 116.54,122.11 116.8,122.37 117.98,122.37 118.08,122.47 118.08,122.68 117.98,122.78 116.8,122.78 116.54,123.04 116.54,123.48 116.8,123.74 117.98,123.74 118.08,123.85 118.08,124.05 117.98,124.15 116.8,124.15 116.54,124.42 116.54,124.85 116.8,125.12 117.98,125.12 118.08,125.22 118.08,125.42 117.98,125.52 116.8,125.52 116.54,125.79 116.54,126.22 116.8,126.49 117.98,126.49 118.08,126.59 118.08,126.79 117.98,126.89 116.8,126.89 116.54,127.16 116.54,127.59 116.8,127.86 117.98,127.86 118.08,127.96 118.08,128.16 117.98,128.27 116.8,128.27 116.54,128.53 116.54,128.97 116.8,129.23 117.98,129.23 118.08,129.33 118.08,129.54 117.98,129.64 116.8,129.64 116.54,129.9 116.54,130.34 116.8,130.6 117.98,130.6 118.08,130.7 118.08,130.82 117.89,131.01 117.84,131.01 117.31,131.54 117.31,133.93 116.3,134.94 116.3,139.49 115.53,140.26 115.53,141.54 115.28,141.79 v1(115.28,141.96)
  BOTTOM w0.114: v1(115.28,141.96) 115.52,142.19 115.52,144.12 J3.39
INPUT16_M: length 118.5
  TOP w0.114: U5.L6 v2(114.95,88.2)
  L3-SIG1 w0.102: v2(114.95,88.2) 114.57,87.82 112.79,87.82 112.57,88.04 112.57,89.76 113.39,90.58 114.21,90.58 114.57,90.94 114.57,93.99 114.57,93.99 114.57,99.78 114.67,99.89 115.66,99.89 115.93,100.15 115.93,100.59 115.66,100.85 114.67,100.85 114.57,100.95 114.57,101.16 114.67,101.26 115.66,101.26 115.93,101.52 115.93,101.96 115.66,102.22 114.67,102.22 114.57,102.32 114.57,102.53 114.67,102.63 115.66,102.63 115.93,102.89 115.93,103.33 115.66,103.59 114.67,103.59 114.57,103.7 114.57,103.9 114.67,104 115.66,104 115.93,104.27 115.93,104.7 115.66,104.97 114.67,104.97 114.57,105.07 114.57,105.27 114.67,105.37 115.66,105.37 115.93,105.64 115.93,106.07 115.66,106.34 114.67,106.34 114.57,106.44 114.57,106.64 114.67,106.74 115.66,106.74 115.93,107.01 115.93,107.44 115.66,107.71 114.67,107.71 114.57,107.81 114.57,108.01 114.67,108.12 115.66,108.12 115.93,108.38 115.93,108.82 115.66,109.08 114.67,109.08 114.57,109.18 114.57,109.39 114.67,109.49 115.66,109.49 115.93,109.75 115.93,110.19 115.66,110.45 114.67,110.45 114.57,110.55 114.57,110.76 114.67,110.86 115.66,110.86 115.93,111.12 115.93,111.56 115.66,111.82 114.67,111.82 114.57,111.93 114.57,112.13 114.67,112.23 115.66,112.23 115.93,112.5 115.93,112.93 115.66,113.2 114.67,113.2 114.57,113.3 114.57,113.5 114.67,113.6 115.66,113.6 115.93,113.87 115.93,114.3 115.66,114.57 114.67,114.57 114.57,114.67 114.57,114.87 114.67,114.97 115.66,114.97 115.93,115.24 115.93,115.67 115.66,115.94 114.67,115.94 114.57,116.04 114.57,116.24 114.67,116.35 115.66,116.35 115.93,116.61 115.93,117.04 115.66,117.31 114.67,117.31 114.57,117.41 114.57,117.62 114.67,117.72 115.66,117.72 115.93,117.98 115.93,118.42 115.66,118.68 114.67,118.68 114.57,118.78 114.57,118.99 114.67,119.09 115.66,119.09 115.93,119.35 115.93,119.79 115.66,120.05 114.67,120.05 114.57,120.16 114.57,120.36 114.67,120.46 115.66,120.46 115.93,120.73 115.93,121.16 115.66,121.43 114.67,121.43 114.57,121.53 114.57,121.73 114.67,121.83 115.66,121.83 115.93,122.1 115.93,122.53 115.66,122.8 114.67,122.8 114.57,122.9 114.57,123.1 114.67,123.2 115.66,123.2 115.93,123.47 115.93,123.9 115.66,124.17 114.67,124.17 114.57,124.27 114.57,124.47 114.67,124.57 115.66,124.57 115.93,124.84 115.93,125.27 115.66,125.54 114.67,125.54 114.57,125.64 114.57,125.84 114.67,125.95 115.66,125.95 115.93,126.21 115.93,126.65 115.66,126.91 114.67,126.91 114.57,127.01 114.57,127.22 114.67,127.32 115.66,127.32 115.93,127.58 115.93,128.02 115.66,128.28 114.67,128.28 114.57,128.38 114.57,128.59 114.67,128.69 115.66,128.69 115.93,128.95 115.93,129.39 115.66,129.65 114.67,129.65 114.57,129.76 114.57,129.96 114.67,130.06 115.66,130.06 115.93,130.33 115.93,130.76 115.66,131.03 114.67,131.03 114.57,131.13 114.57,131.33 114.67,131.43 115.66,131.43 115.93,131.7 115.93,132.13 115.66,132.4 114.67,132.4 114.57,132.5 114.57,132.7 114.67,132.8 115.66,132.8 115.93,133.07 115.93,133.5 115.66,133.77 114.67,133.77 114.57,133.87 114.57,134.44 114.67,134.54 114.73,134.54 114.83,134.64 114.83,134.85 114.73,134.95 114.67,134.95 114.57,135.05 114.57,135.25 114.67,135.35 114.73,135.35 114.83,135.45 114.83,135.66 114.73,135.76 114.67,135.76 114.57,135.86 114.57,140.12 114.53,140.16 114.53,141.19 v1(114.37,141.34)
  BOTTOM w0.114: v1(114.37,141.34) 114.35,141.37 114.35,144.1 J3.43
INPUT16_P: length 118.5
  TOP w0.114: U5.M7 v2(113.95,87.2)
  L3-SIG1 w0.102: v2(113.95,87.2) 113.95,87.2 114.35,87.2 114.43,87.27 114.43,87.45 114.3,87.58 112.69,87.58 112.33,87.94 112.33,89.86 113.29,90.82 114.11,90.82 114.33,91.04 114.33,93.95 114.29,93.99 114.29,99.9 114.56,100.17 115.54,100.17 115.65,100.27 115.65,100.47 115.54,100.57 114.56,100.57 114.29,100.84 114.29,101.27 114.56,101.54 115.54,101.54 115.65,101.64 115.65,101.84 115.54,101.94 114.56,101.94 114.29,102.21 114.29,102.64 114.56,102.91 115.54,102.91 115.65,103.01 115.65,103.21 115.54,103.31 114.56,103.31 114.29,103.58 114.29,104.01 114.56,104.28 115.54,104.28 115.65,104.38 115.65,104.58 115.54,104.69 114.56,104.69 114.29,104.95 114.29,105.39 114.56,105.65 115.54,105.65 115.65,105.75 115.65,105.96 115.54,106.06 114.56,106.06 114.29,106.32 114.29,106.76 114.56,107.02 115.54,107.02 115.65,107.12 115.65,107.33 115.54,107.43 114.56,107.43 114.29,107.69 114.29,108.13 114.56,108.39 115.54,108.39 115.65,108.5 115.65,108.7 115.54,108.8 114.56,108.8 114.29,109.07 114.29,109.5 114.56,109.77 115.54,109.77 115.65,109.87 115.65,110.07 115.54,110.17 114.56,110.17 114.29,110.44 114.29,110.87 114.56,111.14 115.54,111.14 115.65,111.24 115.65,111.44 115.54,111.54 114.56,111.54 114.29,111.81 114.29,112.24 114.56,112.51 115.54,112.51 115.65,112.61 115.65,112.81 115.54,112.92 114.56,112.92 114.29,113.18 114.29,113.62 114.56,113.88 115.54,113.88 115.65,113.98 115.65,114.19 115.54,114.29 114.56,114.29 114.29,114.55 114.29,114.99 114.56,115.25 115.54,115.25 115.65,115.35 115.65,115.56 115.54,115.66 114.56,115.66 114.29,115.92 114.29,116.36 114.56,116.62 115.54,116.62 115.65,116.73 115.65,116.93 115.54,117.03 114.56,117.03 114.29,117.3 114.29,117.73 114.56,118 115.54,118 115.65,118.1 115.65,118.3 115.54,118.4 114.56,118.4 114.29,118.67 114.29,119.1 114.56,119.37 115.54,119.37 115.65,119.47 115.65,119.67 115.54,119.77 114.56,119.77 114.29,120.04 114.29,120.47 114.56,120.74 115.54,120.74 115.65,120.84 115.65,121.04 115.54,121.15 114.56,121.15 114.29,121.41 114.29,121.85 114.56,122.11 115.54,122.11 115.65,122.21 115.65,122.42 115.54,122.52 114.56,122.52 114.29,122.78 114.29,123.22 114.56,123.48 115.54,123.48 115.65,123.58 115.65,123.79 115.54,123.89 114.56,123.89 114.29,124.15 114.29,124.59 114.56,124.85 115.54,124.85 115.65,124.96 115.65,125.16 115.54,125.26 114.56,125.26 114.29,125.53 114.29,125.96 114.56,126.23 115.54,126.23 115.65,126.33 115.65,126.53 115.54,126.63 114.56,126.63 114.29,126.9 114.29,127.33 114.56,127.6 115.54,127.6 115.65,127.7 115.65,127.9 115.54,128 114.56,128 114.29,128.27 114.29,128.7 114.56,128.97 115.54,128.97 115.65,129.07 115.65,129.27 115.54,129.38 114.56,129.38 114.29,129.64 114.29,130.08 114.56,130.34 115.54,130.34 115.65,130.44 115.65,130.65 115.54,130.75 114.56,130.75 114.29,131.01 114.29,131.45 114.56,131.71 115.54,131.71 115.65,131.81 115.65,132.02 115.54,132.12 114.56,132.12 114.29,132.38 114.29,132.82 114.56,133.08 115.54,133.08 115.65,133.19 115.65,133.39 115.54,133.49 114.56,133.49 114.29,133.76 114.29,140 114.25,140.05 114.25,140.41 v1(114.05,140.61)
  BOTTOM w0.114: v1(114.05,140.61) 114.01,140.64 114.01,141.12 113.96,141.17 113.96,141.51 114.01,141.57 114.01,144.13 J3.45
INPUT17_M: length 118.5
  TOP w0.114: U5.K7 v2(115.95,87.2)
  L10-SIG4 w0.102: v1(113.03,141.99) 112.71,141.67 112.71,140.65 115.7,137.67 115.7,135.02 115.9,134.81 117.13,134.81 117.4,134.54 117.4,134.11 117.13,133.84 115.8,133.84 115.7,133.74 115.7,133.54 115.8,133.44 117.13,133.44 117.4,133.17 117.4,132.74 117.13,132.47 115.8,132.47 115.7,132.37 115.7,132.17 115.8,132.07 117.13,132.07 117.4,131.8 117.4,131.37 117.13,131.1 115.8,131.1 115.7,131 115.7,130.8 115.8,130.69 117.13,130.69 117.4,130.43 117.4,129.99 117.13,129.73 115.8,129.73 115.7,129.63 115.7,129.42 115.8,129.32 117.13,129.32 117.4,129.06 117.4,128.62 117.13,128.36 115.8,128.36 115.7,128.26 115.7,128.05 115.8,127.95 117.13,127.95 117.4,127.69 117.4,127.25 117.13,126.99 115.8,126.99 115.7,126.88 115.7,126.68 115.8,126.58 117.13,126.58 117.4,126.31 117.4,125.88 117.13,125.61 115.8,125.61 115.7,125.51 115.7,125.31 115.8,125.21 117.13,125.21 117.4,124.94 117.4,124.51 117.13,124.24 115.8,124.24 115.7,124.14 115.7,123.94 115.8,123.84 117.13,123.84 117.4,123.57 117.4,123.14 117.13,122.87 115.8,122.87 115.7,122.77 115.7,122.57 115.8,122.46 117.13,122.46 117.4,122.2 117.4,121.76 117.13,121.5 115.8,121.5 115.7,121.4 115.7,121.19 115.8,121.09 117.13,121.09 117.4,120.83 117.4,120.39 117.13,120.13 115.8,120.13 115.7,120.03 115.7,119.82 115.8,119.72 117.13,119.72 117.4,119.46 117.4,119.02 117.13,118.76 115.8,118.76 115.7,118.65 115.7,118.45 115.8,118.35 117.13,118.35 117.4,118.08 117.4,117.65 117.13,117.38 115.8,117.38 115.7,117.28 115.7,117.08 115.8,116.98 117.13,116.98 117.4,116.71 117.4,116.28 117.13,116.01 115.8,116.01 115.7,115.91 115.7,115.71 115.8,115.61 117.13,115.61 117.4,115.34 117.4,114.91 117.13,114.64 115.8,114.64 115.7,114.54 115.7,114.34 115.8,114.23 117.13,114.23 117.4,113.97 117.4,113.53 117.13,113.27 115.8,113.27 115.7,113.17 115.7,112.96 115.8,112.86 117.13,112.86 117.4,112.6 117.4,112.16 117.13,111.9 115.8,111.9 115.7,111.8 115.7,111.59 115.8,111.49 117.13,111.49 117.4,111.23 117.4,110.79 117.13,110.53 115.8,110.53 115.7,110.42 115.7,110.11 115.8,110.01 115.9,110.01 116,109.91 116,109.71 115.9,109.6 115.8,109.6 115.7,109.5 115.7,108.86 115.7,108.86 115.7,108.66 112.61,105.58 112.61,98.31 113.03,97.89 113.03,96.84 112.84,96.64 112.84,93.63 112.57,93.36 112.57,89.04 112.57,89.04 112.57,88.36 112.57,88.36 112.57,88.04 112.57,88.04 112.57,87.36 112.57,87.36 112.57,87.04 112.79,86.82 115.57,86.82 v2(115.95,87.2)
  BOTTOM w0.114: v1(113.03,141.99) 112.8,142.21 112.8,144.05 J3.49
INPUT17_P: length 118.5
  TOP w0.114: U5.L8 v2(114.95,86.2)
  L10-SIG4 w0.102: v1(112.27,141.99) 112.43,141.82 112.43,140.54 115.42,137.55 115.42,134.9 115.79,134.53 117.02,134.53 117.12,134.43 117.12,134.22 117.02,134.12 115.68,134.12 115.42,133.86 115.42,133.42 115.68,133.16 117.02,133.16 117.12,133.06 117.12,132.85 117.02,132.75 115.68,132.75 115.42,132.49 115.42,132.05 115.68,131.79 117.02,131.79 117.12,131.68 117.12,131.48 117.02,131.38 115.68,131.38 115.42,131.11 115.42,130.68 115.68,130.41 117.02,130.41 117.12,130.31 117.12,130.11 117.02,130.01 115.68,130.01 115.42,129.74 115.42,129.31 115.68,129.04 117.02,129.04 117.12,128.94 117.12,128.74 117.02,128.64 115.68,128.64 115.42,128.37 115.42,127.94 115.68,127.67 117.02,127.67 117.12,127.57 117.12,127.37 117.02,127.26 115.68,127.26 115.42,127 115.42,126.56 115.68,126.3 117.02,126.3 117.12,126.2 117.12,125.99 117.02,125.89 115.68,125.89 115.42,125.63 115.42,125.19 115.68,124.93 117.02,124.93 117.12,124.83 117.12,124.62 117.02,124.52 115.68,124.52 115.42,124.26 115.42,123.82 115.68,123.56 117.02,123.56 117.12,123.45 117.12,123.25 117.02,123.15 115.68,123.15 115.42,122.88 115.42,122.45 115.68,122.18 117.02,122.18 117.12,122.08 117.12,121.88 117.02,121.78 115.68,121.78 115.42,121.51 115.42,121.08 115.68,120.81 117.02,120.81 117.12,120.71 117.12,120.51 117.02,120.41 115.68,120.41 115.42,120.14 115.42,119.71 115.68,119.44 117.02,119.44 117.12,119.34 117.12,119.14 117.02,119.04 115.68,119.04 115.42,118.77 115.42,118.34 115.68,118.07 117.02,118.07 117.12,117.97 117.12,117.77 117.02,117.66 115.68,117.66 115.42,117.4 115.42,116.96 115.68,116.7 117.02,116.7 117.12,116.6 117.12,116.39 117.02,116.29 115.68,116.29 115.42,116.03 115.42,115.59 115.68,115.33 117.02,115.33 117.12,115.23 117.12,115.02 117.02,114.92 115.68,114.92 115.42,114.66 115.42,114.22 115.68,113.96 117.02,113.96 117.12,113.85 117.12,113.65 117.02,113.55 115.68,113.55 115.42,113.28 115.42,112.85 115.68,112.58 117.02,112.58 117.12,112.48 117.12,112.28 117.02,112.18 115.68,112.18 115.42,111.91 115.42,111.48 115.68,111.21 117.02,111.21 117.12,111.11 117.12,110.91 117.02,110.81 115.68,110.81 115.42,110.54 115.42,108.78 112.33,105.69 112.33,98.19 112.75,97.78 112.75,96.95 112.56,96.76 112.56,94.11 112.6,94.07 112.6,93.72 112.33,93.46 112.33,88.94 112.33,88.94 112.33,88.46 112.33,88.46 112.33,87.94 112.33,87.94 112.33,87.46 112.33,87.46 112.33,86.94 112.69,86.58 115.3,86.58 115.39,86.49 115.39,86.28 115.29,86.18 114.97,86.18 v2(114.95,86.2)
  BOTTOM w0.114: v1(112.27,141.99) 112.52,142.24 112.52,144.12 J3.51
INPUT18_M: length 118.6
  TOP w0.114: U5.AA29 v2(103.95,64.2)
  L10-SIG4 w0.102: v1(111.16,141) 111.28,140.87 111.28,139.92 112.37,138.84 112.37,135.67 112.27,135.57 111.47,135.57 111.2,135.3 111.2,134.87 111.47,134.6 112.27,134.6 112.37,134.5 112.37,134.3 112.27,134.2 111.47,134.2 111.2,133.93 111.2,133.5 111.47,133.23 112.27,133.23 112.37,133.13 112.37,132.93 112.27,132.83 111.47,132.83 111.2,132.56 111.2,132.13 111.47,131.86 112.27,131.86 112.37,131.76 112.37,131.56 112.27,131.45 111.47,131.45 111.2,131.19 111.2,130.75 111.47,130.49 112.27,130.49 112.37,130.39 112.37,130.18 112.27,130.08 111.47,130.08 111.2,129.82 111.2,129.38 111.47,129.12 112.27,129.12 112.37,129.02 112.37,128.81 112.27,128.71 111.47,128.71 111.2,128.44 111.2,128.01 111.47,127.75 112.27,127.75 112.37,127.64 112.37,127.44 112.27,127.34 111.47,127.34 111.2,127.07 111.2,126.64 111.47,126.37 112.27,126.37 112.37,126.27 112.37,126.07 112.27,125.97 111.47,125.97 111.2,125.7 111.2,125.27 111.47,125 112.27,125 112.37,124.9 112.37,124.7 112.27,124.6 111.47,124.6 111.2,124.33 111.2,123.9 111.47,123.63 112.27,123.63 112.37,123.53 112.37,123.33 112.27,123.22 111.47,123.22 111.2,122.96 111.2,122.52 111.47,122.26 112.27,122.26 112.37,122.16 112.37,121.95 112.27,121.85 111.47,121.85 111.2,121.59 111.2,121.15 111.47,120.89 112.27,120.89 112.37,120.79 112.37,120.58 112.27,120.48 111.47,120.48 111.2,120.22 111.2,119.78 111.47,119.52 112.27,119.52 112.37,119.41 112.37,119.21 112.27,119.11 111.47,119.11 111.2,118.84 111.2,118.41 111.47,118.14 112.27,118.14 112.37,118.04 112.37,117.84 112.27,117.74 111.47,117.74 111.2,117.47 111.2,117.04 111.47,116.77 112.27,116.77 112.37,116.67 112.37,116.47 112.27,116.37 111.47,116.37 111.2,116.1 111.2,115.67 111.47,115.4 112.27,115.4 112.37,115.3 112.37,115.1 112.27,114.99 111.47,114.99 111.2,114.73 111.2,114.29 111.47,114.03 112.27,114.03 112.37,113.93 112.37,113.72 112.27,113.62 111.47,113.62 111.2,113.36 111.2,112.92 111.47,112.66 112.08,112.66 112.37,112.37 112.37,110.29 107.47,105.38 107.47,98.06 106.98,97.58 106.98,97.13 106.2,96.34 106.2,94.46 106.04,94.3 106.04,94.25 105.33,93.54 105.33,77.04 105.25,76.96 105.25,75.44 105.33,75.36 105.33,72.04 105.11,71.82 104.79,71.82 104.77,71.84 104.65,71.84 104.33,71.52 104.33,70.83 103.3,69.8 103.3,69.39 103.33,69.36 103.33,64.54 103.67,64.2 v2(103.95,64.2)
  BOTTOM w0.114: v1(111.16,141) 111.36,141.19 111.36,144.11 J3.55 ; v2(103.95,64.2) 103.74,64.41 R56.2
INPUT18_P: length 118.6
  TOP w0.114: U5.AA28 v2(103.95,65.2)
  L10-SIG4 w0.102: v1(110.88,141.69) 111.04,141.69 111.57,141.16 111.57,140.83 111.56,140.82 111.56,140.04 112.65,138.95 112.65,135.55 112.38,135.29 111.58,135.29 111.48,135.19 111.48,134.98 111.58,134.88 112.38,134.88 112.65,134.62 112.65,134.18 112.38,133.92 111.58,133.92 111.48,133.82 111.48,133.61 111.58,133.51 112.38,133.51 112.65,133.25 112.65,132.81 112.38,132.55 111.58,132.55 111.48,132.44 111.48,132.24 111.58,132.14 112.38,132.14 112.65,131.87 112.65,131.44 112.38,131.17 111.58,131.17 111.48,131.07 111.48,130.87 111.58,130.77 112.38,130.77 112.65,130.5 112.65,130.07 112.38,129.8 111.58,129.8 111.48,129.7 111.48,129.5 111.58,129.4 112.38,129.4 112.65,129.13 112.65,128.7 112.38,128.43 111.58,128.43 111.48,128.33 111.48,128.13 111.58,128.02 112.38,128.02 112.65,127.76 112.65,127.32 112.38,127.06 111.58,127.06 111.48,126.96 111.48,126.75 111.58,126.65 112.38,126.65 112.65,126.39 112.65,125.95 112.38,125.69 111.58,125.69 111.48,125.59 111.48,125.38 111.58,125.28 112.38,125.28 112.65,125.02 112.65,124.58 112.38,124.32 111.58,124.32 111.48,124.21 111.48,124.01 111.58,123.91 112.38,123.91 112.65,123.64 112.65,123.21 112.38,122.94 111.58,122.94 111.48,122.84 111.48,122.64 111.58,122.54 112.38,122.54 112.65,122.27 112.65,121.84 112.38,121.57 111.58,121.57 111.48,121.47 111.48,121.27 111.58,121.17 112.38,121.17 112.65,120.9 112.65,120.47 112.38,120.2 111.58,120.2 111.48,120.1 111.48,119.9 111.58,119.79 112.38,119.79 112.65,119.53 112.65,119.09 112.38,118.83 111.58,118.83 111.48,118.73 111.48,118.52 111.58,118.42 112.38,118.42 112.65,118.16 112.65,117.72 112.38,117.46 111.58,117.46 111.48,117.36 111.48,117.15 111.58,117.05 112.38,117.05 112.65,116.79 112.65,116.35 112.38,116.09 111.58,116.09 111.48,115.98 111.48,115.78 111.58,115.68 112.38,115.68 112.65,115.41 112.65,114.98 112.38,114.71 111.58,114.71 111.48,114.61 111.48,114.41 111.58,114.31 112.38,114.31 112.65,114.04 112.65,113.61 112.38,113.34 111.58,113.34 111.48,113.24 111.48,113.04 111.58,112.94 112.2,112.94 112.65,112.49 112.65,110.17 107.75,105.27 107.75,97.94 107.26,97.46 107.26,97.01 106.48,96.23 106.48,94.35 106.32,94.19 106.32,94.13 106.1,93.91 106.04,93.91 105.57,93.44 105.57,76.94 105.49,76.86 105.49,75.54 105.57,75.46 105.57,71.94 105.21,71.58 104.73,71.58 104.57,71.42 104.57,70.73 103.54,69.7 103.54,69.49 103.57,69.46 103.57,64.88 103.7,64.75 103.84,64.75 103.94,64.85 103.94,65.19 v2(103.95,65.2)
  BOTTOM w0.114: R56.1 103.88,65.13 v2(103.95,65.2) ; J3.57 111.02,144.12 111.02,141.83 v1(110.88,141.69)
INPUT19_M: length 118.6
  TOP w0.114: U5.AG8 v2(97.95,86.2)
  L3-SIG1 w0.102: v1(103.06,148.34) 102.8,148.08 102.8,142.42 103.94,141.29 103.94,140.09 103.4,139.56 103.4,138.2 103.84,137.76 104.26,137.76 104.52,137.5 104.52,137.06 104.26,136.8 103.5,136.8 103.4,136.7 103.4,136.49 103.5,136.39 104.26,136.39 104.52,136.13 104.52,135.69 104.26,135.43 103.5,135.43 103.4,135.33 103.4,135.12 103.5,135.02 104.26,135.02 104.52,134.76 104.52,134.32 104.26,134.06 103.5,134.06 103.4,133.95 103.4,133.75 103.5,133.65 104.26,133.65 104.52,133.38 104.52,132.95 104.26,132.68 103.5,132.68 103.4,132.58 103.4,132.38 103.5,132.28 104.26,132.28 104.52,132.01 104.52,131.58 104.26,131.31 103.5,131.31 103.4,131.21 103.4,131.01 103.5,130.91 104.26,130.91 104.52,130.64 104.52,130.21 104.26,129.94 103.5,129.94 103.4,129.84 103.4,129.64 103.5,129.53 104.26,129.53 104.52,129.27 104.52,128.83 104.26,128.57 103.5,128.57 103.4,128.47 103.4,128.26 103.5,128.16 104.26,128.16 104.52,127.9 104.52,127.46 104.26,127.2 103.5,127.2 103.4,127.1 103.4,126.89 103.5,126.79 104.26,126.79 104.52,126.53 104.52,126.09 104.26,125.83 103.5,125.83 103.4,125.72 103.4,125.52 103.5,125.42 104.26,125.42 104.52,125.15 104.52,124.72 104.26,124.45 103.5,124.45 103.4,124.35 103.4,124.15 103.5,124.05 104.26,124.05 104.52,123.78 104.52,123.35 104.26,123.08 103.5,123.08 103.4,122.98 103.4,122.78 103.5,122.68 104.26,122.68 104.52,122.41 104.52,121.98 104.26,121.71 103.5,121.71 103.4,121.61 103.4,121.41 103.5,121.31 104.26,121.31 104.52,121.04 104.52,120.61 104.26,120.34 103.5,120.34 103.4,120.24 103.4,120.04 103.5,119.93 104.26,119.93 104.52,119.67 104.52,119.23 104.26,118.97 103.5,118.97 103.4,118.87 103.4,118.66 103.5,118.56 104.26,118.56 104.52,118.3 104.52,117.86 104.26,117.6 103.5,117.6 103.4,117.5 103.4,117.29 103.5,117.19 104.26,117.19 104.52,116.93 104.52,116.49 104.26,116.23 103.5,116.23 103.4,116.12 103.4,115.92 103.5,115.82 104.26,115.82 104.52,115.55 104.52,115.12 104.26,114.85 103.5,114.85 103.4,114.75 103.4,114.55 103.5,114.45 104.26,114.45 104.52,114.18 104.52,113.75 104.26,113.48 103.5,113.48 103.4,113.38 103.4,113.18 103.5,113.08 104.26,113.08 104.52,112.81 104.52,112.38 104.26,112.11 103.5,112.11 103.4,112.01 103.4,111.81 103.5,111.7 104.26,111.7 104.52,111.44 104.52,111 104.26,110.74 103.5,110.74 103.4,110.64 103.4,110.43 103.5,110.33 104.26,110.33 104.52,110.07 104.52,109.63 104.26,109.37 103.5,109.37 103.4,109.27 103.4,109.06 103.5,108.96 104.26,108.96 104.52,108.7 104.52,108.26 104.26,108 103.5,108 103.4,107.89 103.4,107.69 103.5,107.59 104.26,107.59 104.52,107.32 104.52,106.89 104.26,106.62 103.5,106.62 103.4,106.52 103.4,106.32 103.5,106.22 104.26,106.22 104.52,105.95 104.52,105.52 104.26,105.25 103.5,105.25 103.4,105.15 103.4,104.95 103.5,104.85 104.26,104.85 104.52,104.58 104.52,104.15 104.26,103.88 103.5,103.88 103.4,103.78 103.4,103.58 103.5,103.47 104.26,103.47 104.52,103.21 104.52,102.77 104.26,102.51 103.5,102.51 103.4,102.41 103.4,102.2 103.5,102.1 104.26,102.1 104.52,101.84 104.52,101.4 104.26,101.14 103.5,101.14 103.4,101.04 103.4,100.48 102.23,99.31 102.23,95.73 100.57,94.07 100.57,93.46 100.57,93.46 100.57,92.94 100.57,92.94 100.57,92.46 100.57,92.46 100.57,91.94 100.57,91.94 100.57,89.46 100.57,89.46 100.57,88.94 100.57,88.94 100.57,88.46 100.57,88.46 100.57,87.89 100.26,87.58 99.79,87.58 99.57,87.36 99.57,86.84 99.31,86.58 97.79,86.58 97.6,86.39 97.6,85.89 97.73,85.76 97.87,85.76 97.97,85.85 97.97,86.18 v2(97.95,86.2)
  BOTTOM w0.114: J3.70 102.86,149.85 102.86,148.54 v1(103.06,148.34)
INPUT19_P: length 118.6
  TOP w0.114: U5.AG9 v2(97.95,85.2)
  L3-SIG1 w0.102: v1(102.36,148.34) 102.52,148.18 102.52,142.31 103.66,141.17 103.66,140.21 103.12,139.67 103.12,138.05 103.69,137.48 104.07,137.48 104.19,137.36 104.19,137.21 104.06,137.08 103.39,137.08 103.12,136.81 103.12,136.38 103.39,136.11 104.14,136.11 104.24,136.01 104.24,135.81 104.14,135.71 103.39,135.71 103.12,135.44 103.12,135.01 103.39,134.74 104.14,134.74 104.24,134.64 104.24,134.44 104.14,134.34 103.39,134.34 103.12,134.07 103.12,133.64 103.39,133.37 104.14,133.37 104.24,133.27 104.24,133.07 104.14,132.96 103.39,132.96 103.12,132.7 103.12,132.26 103.39,132 104.14,132 104.24,131.9 104.24,131.69 104.14,131.59 103.39,131.59 103.12,131.33 103.12,130.89 103.39,130.63 104.14,130.63 104.24,130.53 104.24,130.32 104.14,130.22 103.39,130.22 103.12,129.96 103.12,129.52 103.39,129.26 104.14,129.26 104.24,129.15 104.24,128.95 104.14,128.85 103.39,128.85 103.12,128.58 103.12,128.15 103.39,127.88 104.14,127.88 104.24,127.78 104.24,127.58 104.14,127.48 103.39,127.48 103.12,127.21 103.12,126.78 103.39,126.51 104.14,126.51 104.24,126.41 104.24,126.21 104.14,126.11 103.39,126.11 103.12,125.84 103.12,125.41 103.39,125.14 104.14,125.14 104.24,125.04 104.24,124.84 104.14,124.73 103.39,124.73 103.12,124.47 103.12,124.03 103.39,123.77 104.14,123.77 104.24,123.67 104.24,123.46 104.14,123.36 103.39,123.36 103.12,123.1 103.12,122.66 103.39,122.4 104.14,122.4 104.24,122.3 104.24,122.09 104.14,121.99 103.39,121.99 103.12,121.73 103.12,121.29 103.39,121.03 104.14,121.03 104.24,120.92 104.24,120.72 104.14,120.62 103.39,120.62 103.12,120.35 103.12,119.92 103.39,119.65 104.14,119.65 104.24,119.55 104.24,119.35 104.14,119.25 103.39,119.25 103.12,118.98 103.12,118.55 103.39,118.28 104.14,118.28 104.24,118.18 104.24,117.98 104.14,117.88 103.39,117.88 103.12,117.61 103.12,117.18 103.39,116.91 104.14,116.91 104.24,116.81 104.24,116.61 104.14,116.5 103.39,116.5 103.12,116.24 103.12,115.8 103.39,115.54 104.14,115.54 104.24,115.44 104.24,115.23 104.14,115.13 103.39,115.13 103.12,114.87 103.12,114.43 103.39,114.17 104.14,114.17 104.24,114.07 104.24,113.86 104.14,113.76 103.39,113.76 103.12,113.5 103.12,113.06 103.39,112.8 104.14,112.8 104.24,112.69 104.24,112.49 104.14,112.39 103.39,112.39 103.12,112.12 103.12,111.69 103.39,111.42 104.14,111.42 104.24,111.32 104.24,111.12 104.14,111.02 103.39,111.02 103.12,110.75 103.12,110.32 103.39,110.05 104.14,110.05 104.24,109.95 104.24,109.75 104.14,109.65 103.39,109.65 103.12,109.38 103.12,108.95 103.39,108.68 104.14,108.68 104.24,108.58 104.24,108.38 104.14,108.27 103.39,108.27 103.12,108.01 103.12,107.58 103.39,107.31 104.14,107.31 104.24,107.21 104.24,107 104.14,106.9 103.39,106.9 103.12,106.64 103.12,106.2 103.39,105.94 104.14,105.94 104.24,105.84 104.24,105.63 104.14,105.53 103.39,105.53 103.12,105.27 103.12,104.83 103.39,104.57 104.14,104.57 104.24,104.46 104.24,104.26 104.14,104.16 103.39,104.16 103.12,103.89 103.12,103.46 103.39,103.19 104.14,103.19 104.24,103.09 104.24,102.89 104.14,102.79 103.39,102.79 103.12,102.52 103.12,102.09 103.39,101.82 104.14,101.82 104.24,101.72 104.24,101.52 104.14,101.42 103.39,101.42 103.12,101.15 103.12,100.6 101.96,99.43 101.96,95.85 100.33,94.22 100.33,93.36 100.33,92.36 100.33,89.36 100.33,88.36 100.33,87.99 100.16,87.82 99.69,87.82 99.33,87.46 99.33,86.93 99.22,86.82 97.69,86.82 97.36,86.49 97.36,85.79 v2(97.95,85.2)
  BOTTOM w0.114: J3.72 102.57,149.82 102.57,148.54 v1(102.36,148.34)
INPUT20_M: length 118.6
  TOP w0.114: U5.AG6 v2(97.95,88.2)
  L3-SIG1 w0.102: v2(97.95,88.2) 98.27,88.52 98.7,88.52 99,88.82 99.23,88.82 99.25,88.83 99.26,88.83 99.34,88.91 99.34,88.93 99.33,88.94 99.33,93.26 99.33,93.26 99.33,93.65 99.42,93.73 99.42,93.96 99.31,94.06 99.16,94.06 99.06,94.16 99.06,94.37 99.16,94.47 99.31,94.47 99.42,94.57 99.42,95.07 99.92,95.58 99.92,95.85 98.93,96.84 98.93,97.17 99.82,98.06 99.82,98.34 100.09,98.6 100.33,98.6 100.43,98.7 100.43,98.91 100.33,99.01 100.09,99.01 99.82,99.27 99.82,100.2 100.54,100.92 101.7,100.92 101.8,101.02 101.8,101.22 101.7,101.32 100.95,101.32 100.69,101.59 100.69,102.02 100.95,102.29 101.7,102.29 101.8,102.39 101.8,102.59 101.7,102.69 100.95,102.69 100.69,102.96 100.69,103.39 100.95,103.66 101.7,103.66 101.8,103.76 101.8,103.96 101.7,104.07 100.95,104.07 100.69,104.33 100.69,104.77 100.95,105.03 101.7,105.03 101.8,105.13 101.8,105.34 101.7,105.44 100.95,105.44 100.69,105.7 100.69,106.14 100.95,106.4 101.7,106.4 101.8,106.5 101.8,106.71 101.7,106.81 100.95,106.81 100.69,107.07 100.69,108.59 100.95,108.85 101.47,108.85 101.57,108.95 101.57,109.16 101.47,109.26 100.95,109.26 100.69,109.52 100.69,110.25 100.95,110.52 101.7,110.52 101.8,110.62 101.8,110.82 101.7,110.92 100.95,110.92 100.69,111.19 100.69,111.62 100.95,111.89 101.7,111.89 101.8,111.99 101.8,112.19 101.7,112.3 100.95,112.3 100.69,112.56 100.69,113 100.95,113.26 101.7,113.26 101.8,113.36 101.8,113.57 101.7,113.67 100.95,113.67 100.69,113.93 100.69,114.37 100.95,114.63 101.7,114.63 101.8,114.73 101.8,114.94 101.7,115.04 100.95,115.04 100.69,115.3 100.69,115.74 100.95,116 101.7,116 101.8,116.11 101.8,116.31 101.7,116.41 100.95,116.41 100.69,116.68 100.69,117.11 100.95,117.38 101.7,117.38 101.8,117.48 101.8,117.68 101.7,117.78 100.95,117.78 100.69,118.05 100.69,118.48 100.95,118.75 101.7,118.75 101.8,118.85 101.8,119.05 101.7,119.15 100.95,119.15 100.69,119.42 100.69,119.85 100.95,120.12 101.7,120.12 101.8,120.22 101.8,120.42 101.7,120.53 100.95,120.53 100.69,120.79 100.69,121.23 100.95,121.49 101.7,121.49 101.8,121.59 101.8,121.8 101.7,121.9 100.95,121.9 100.69,122.16 100.69,122.6 100.95,122.86 101.7,122.86 101.8,122.96 101.8,123.17 101.7,123.27 100.95,123.27 100.69,123.53 100.69,123.97 100.95,124.23 101.7,124.23 101.8,124.34 101.8,124.54 101.7,124.64 100.95,124.64 100.69,124.91 100.69,125.34 100.95,125.61 101.7,125.61 101.8,125.71 101.8,125.91 101.7,126.01 100.95,126.01 100.69,126.28 100.69,126.71 100.95,126.98 101.7,126.98 101.8,127.08 101.8,127.28 101.7,127.38 100.95,127.38 100.69,127.65 100.69,128.08 100.95,128.35 101.7,128.35 101.8,128.45 101.8,128.65 101.7,128.75 100.95,128.75 100.69,129.02 100.69,129.45 100.95,129.72 101.7,129.72 101.8,129.82 101.8,130.02 101.7,130.13 100.95,130.13 100.69,130.39 100.69,130.83 100.95,131.09 101.7,131.09 101.8,131.19 101.8,131.4 101.7,131.5 100.95,131.5 100.69,131.76 100.69,132.2 100.95,132.46 101.7,132.46 101.8,132.56 101.8,132.77 101.7,132.87 100.95,132.87 100.69,133.13 100.69,133.57 100.95,133.83 101.7,133.83 101.8,133.94 101.8,134.14 101.7,134.24 100.95,134.24 100.69,134.51 100.69,134.94 100.95,135.21 101.7,135.21 101.8,135.31 101.8,135.51 101.7,135.61 100.95,135.61 100.69,135.88 100.69,136.31 100.95,136.58 101.7,136.58 101.8,136.68 101.8,136.88 101.7,136.98 100.95,136.98 100.69,137.25 100.69,137.68 100.95,137.95 101.7,137.95 101.8,138.05 101.8,138.25 101.7,138.36 100.95,138.36 100.69,138.62 100.69,139.06 100.95,139.32 101.7,139.32 101.8,139.42 101.8,139.63 101.7,139.73 100.95,139.73 100.69,139.99 100.69,140.87 99.99,141.56 99.99,142.52 101.07,143.6 101.07,144.11 101.33,144.38 101.73,144.38 101.83,144.48 101.83,144.68 101.73,144.78 101.33,144.78 101.07,145.05 101.07,147.3 101.58,147.81 v1(101.58,147.83)
  BOTTOM w0.114: v1(101.58,147.83) 101.35,148.06 101.35,149.84 J3.76
INPUT20_P: length 118.6
  TOP w0.114: U5.AF6 v2(98.95,88.2)
  L3-SIG1 w0.102: v2(98.95,88.2) 99.35,88.6 99.36,88.6 99.58,88.81 99.58,88.83 99.59,88.84 99.59,89.02 99.57,89.04 99.57,93.36 99.57,93.36 99.57,93.55 99.65,93.63 99.65,94.01 99.69,94.06 99.69,94.96 100.2,95.46 100.2,95.96 99.57,96.6 99.57,97.41 100.1,97.94 100.1,98.22 100.2,98.32 100.45,98.32 100.71,98.59 100.71,99.02 100.45,99.29 100.2,99.29 100.1,99.39 100.1,100.09 100.65,100.64 101.82,100.64 102.08,100.9 102.08,101.34 101.82,101.6 101.07,101.6 100.97,101.7 100.97,101.91 101.07,102.01 101.82,102.01 102.08,102.27 102.08,102.71 101.82,102.97 101.07,102.97 100.97,103.08 100.97,103.28 101.07,103.38 101.82,103.38 102.08,103.65 102.08,104.08 101.82,104.35 101.07,104.35 100.97,104.45 100.97,104.65 101.07,104.75 101.82,104.75 102.08,105.02 102.08,105.45 101.82,105.72 101.07,105.72 100.97,105.82 100.97,106.02 101.07,106.12 101.82,106.12 102.08,106.39 102.08,106.82 101.82,107.09 101.07,107.09 100.97,107.19 100.97,108.47 101.07,108.57 101.59,108.57 101.85,108.84 101.85,109.27 101.59,109.54 101.07,109.54 100.97,109.64 100.97,110.14 101.07,110.24 101.82,110.24 102.08,110.5 102.08,110.94 101.82,111.2 101.07,111.2 100.97,111.3 100.97,111.51 101.07,111.61 101.82,111.61 102.08,111.87 102.08,112.31 101.82,112.57 101.07,112.57 100.97,112.68 100.97,112.88 101.07,112.98 101.82,112.98 102.08,113.25 102.08,113.68 101.82,113.95 101.07,113.95 100.97,114.05 100.97,114.25 101.07,114.35 101.82,114.35 102.08,114.62 102.08,115.05 101.82,115.32 101.07,115.32 100.97,115.42 100.97,115.62 101.07,115.72 101.82,115.72 102.08,115.99 102.08,116.42 101.82,116.69 101.07,116.69 100.97,116.79 100.97,116.99 101.07,117.1 101.82,117.1 102.08,117.36 102.08,117.8 101.82,118.06 101.07,118.06 100.97,118.16 100.97,118.37 101.07,118.47 101.82,118.47 102.08,118.73 102.08,119.17 101.82,119.43 101.07,119.43 100.97,119.53 100.97,119.74 101.07,119.84 101.82,119.84 102.08,120.1 102.08,120.54 101.82,120.8 101.07,120.8 100.97,120.91 100.97,121.11 101.07,121.21 101.82,121.21 102.08,121.48 102.08,121.91 101.82,122.18 101.07,122.18 100.97,122.28 100.97,122.48 101.07,122.58 101.82,122.58 102.08,122.85 102.08,123.28 101.82,123.55 101.07,123.55 100.97,123.65 100.97,123.85 101.07,123.95 101.82,123.95 102.08,124.22 102.08,124.65 101.82,124.92 101.07,124.92 100.97,125.02 100.97,125.22 101.07,125.33 101.82,125.33 102.08,125.59 102.08,126.03 101.82,126.29 101.07,126.29 100.97,126.39 100.97,126.6 101.07,126.7 101.82,126.7 102.08,126.96 102.08,127.4 101.82,127.66 101.07,127.66 100.97,127.76 100.97,127.97 101.07,128.07 101.82,128.07 102.08,128.33 102.08,128.77 101.82,129.03 101.07,129.03 100.97,129.14 100.97,129.34 101.07,129.44 101.82,129.44 102.08,129.71 102.08,130.14 101.82,130.41 101.07,130.41 100.97,130.51 100.97,130.71 101.07,130.81 101.82,130.81 102.08,131.08 102.08,131.51 101.82,131.78 101.07,131.78 100.97,131.88 100.97,132.08 101.07,132.18 101.82,132.18 102.08,132.45 102.08,132.88 101.82,133.15 101.07,133.15 100.97,133.25 100.97,133.45 101.07,133.56 101.82,133.56 102.08,133.82 102.08,134.26 101.82,134.52 101.07,134.52 100.97,134.62 100.97,134.83 101.07,134.93 101.82,134.93 102.08,135.19 102.08,135.63 101.82,135.89 101.07,135.89 100.97,135.99 100.97,136.2 101.07,136.3 101.82,136.3 102.08,136.56 102.08,137 101.82,137.26 101.07,137.26 100.97,137.37 100.97,137.57 101.07,137.67 101.82,137.67 102.08,137.94 102.08,138.37 101.82,138.64 101.07,138.64 100.97,138.74 100.97,138.94 101.07,139.04 101.82,139.04 102.08,139.31 102.08,139.74 101.82,140.01 101.62,140.01 100.97,140.67 100.97,140.98 100.27,141.68 100.27,142.41 101.35,143.49 101.35,143.99 101.45,144.1 101.84,144.1 102.11,144.36 102.11,144.8 101.84,145.06 101.45,145.06 101.35,145.16 101.35,147.12 101.58,147.35 101.7,147.35 102.01,147.65 102.01,147.98 101.75,148.23 101.23,148.23 v1(100.82,147.83)
  BOTTOM w0.114: v1(100.82,147.83) 101.05,148.06 101.05,149.83 J3.78
INPUT21_M: length 118.4
  TOP w0.114: U5.AE6 v2(99.95,88.2)
  L3-SIG1 w0.102: v1(100.08,148.34) 99.8,148.06 99.8,143.66 99.36,143.23 99.36,141.94 98.3,140.87 98.3,140.04 98.4,139.94 99.81,139.94 100.08,139.67 100.08,139.24 99.81,138.97 98.4,138.97 98.3,138.87 98.3,138.61 98.52,138.38 99.18,138.38 99.44,138.12 99.44,137.68 99.18,137.42 98.4,137.42 98.3,137.32 98.3,137.11 98.4,137.01 99.18,137.01 99.44,136.75 99.44,136.31 99.18,136.05 98.4,136.05 98.3,135.95 98.3,135.74 98.4,135.64 99.18,135.64 99.44,135.38 99.44,134.94 99.18,134.68 98.4,134.68 98.3,134.57 98.3,134.37 98.4,134.27 99.18,134.27 99.44,134 99.44,133.57 99.18,133.3 98.4,133.3 98.3,133.2 98.3,133 98.4,132.9 99.18,132.9 99.44,132.63 99.44,132.2 99.18,131.93 98.4,131.93 98.3,131.83 98.3,131.63 98.4,131.53 99.18,131.53 99.44,131.26 99.44,130.83 99.18,130.56 98.4,130.56 98.3,130.46 98.3,130.26 98.4,130.16 99.18,130.16 99.44,129.89 99.44,129.46 99.18,129.19 98.4,129.19 98.3,129.09 98.3,128.89 98.4,128.78 99.18,128.78 99.44,128.52 99.44,128.08 99.18,127.82 98.4,127.82 98.3,127.72 98.3,127.51 98.4,127.41 99.18,127.41 99.44,127.15 99.44,126.71 99.18,126.45 98.4,126.45 98.3,126.35 98.3,126.14 98.4,126.04 99.18,126.04 99.44,125.78 99.44,125.34 99.18,125.08 98.4,125.08 98.3,124.97 98.3,124.77 98.4,124.67 99.18,124.67 99.44,124.4 99.44,123.97 99.18,123.7 98.4,123.7 98.3,123.6 98.3,123.4 98.4,123.3 99.18,123.3 99.44,123.03 99.44,122.6 99.18,122.33 98.4,122.33 98.3,122.23 98.3,122.03 98.4,121.93 99.18,121.93 99.44,121.66 99.44,121.23 99.18,120.96 98.4,120.96 98.3,120.86 98.3,120.66 98.4,120.55 99.18,120.55 99.44,120.29 99.44,119.85 99.18,119.59 98.4,119.59 98.3,119.49 98.3,119.28 98.4,119.18 99.18,119.18 99.44,118.92 99.44,118.48 99.18,118.22 98.4,118.22 98.3,118.12 98.3,117.91 98.4,117.81 99.18,117.81 99.44,117.55 99.44,117.11 99.18,116.85 98.4,116.85 98.3,116.74 98.3,116.54 98.4,116.44 99.18,116.44 99.44,116.17 99.44,115.74 99.18,115.47 98.4,115.47 98.3,115.37 98.3,115.17 98.4,115.07 99.18,115.07 99.44,114.8 99.44,114.37 99.18,114.1 98.4,114.1 98.3,114 98.3,113.8 98.4,113.7 99.18,113.7 99.44,113.43 99.44,113 99.18,112.73 98.65,112.73 98.3,112.38 98.3,111.86 98.4,111.76 98.79,111.76 99.06,111.5 99.06,111.06 98.79,110.8 98.61,110.8 98.3,110.49 98.3,109.86 98.57,109.58 99.18,109.58 99.44,109.32 99.44,108.88 99.18,108.62 98.4,108.62 98.3,108.51 98.3,107.71 98.4,107.61 98.67,107.61 98.93,107.34 98.93,106.91 98.67,106.64 98.4,106.64 98.3,106.54 98.3,105.57 98.4,105.47 99.18,105.47 99.44,105.2 99.44,104.77 99.18,104.5 98.4,104.5 98.3,104.4 98.3,104.2 98.4,104.09 99.18,104.09 99.44,103.83 99.44,103.39 99.18,103.13 98.4,103.13 98.3,103.03 98.3,102.82 98.4,102.72 99.18,102.72 99.44,102.46 99.44,102.02 99.18,101.76 98.4,101.76 98.3,101.66 98.3,101.45 98.4,101.35 99.18,101.35 99.44,101.09 99.44,100.65 99.18,100.39 98.4,100.39 98.3,100.28 98.3,99.67 97.59,98.96 97.59,97.74 97.32,97.47 96.77,97.47 96.67,97.37 96.67,97.17 96.77,97.07 97.32,97.07 97.59,96.8 97.59,95.74 97.69,95.64 98.29,95.64 98.55,95.37 98.55,94.94 98.29,94.67 97.85,94.67 97.56,94.39 97.56,93.46 97.57,93.46 97.57,88.94 97.56,88.94 97.56,88.46 97.57,88.46 97.57,88 97.75,87.82 98.21,87.82 98.22,87.81 99.24,87.81 99.63,88.2 v2(99.95,88.2)
  BOTTOM w0.114: v1(100.08,148.34) 99.83,148.58 99.83,149.82 J3.82
INPUT21_P: length 118.4
  TOP w0.114: U5.AF7 v2(98.95,87.2)
  L3-SIG1 w0.102: v1(99.31,148.34) 99.52,148.13 99.52,143.78 99.09,143.35 99.09,142.05 98.02,140.98 98.02,139.92 98.28,139.66 99.69,139.66 99.8,139.56 99.8,139.35 99.69,139.25 98.28,139.25 98.02,138.99 98.02,138.48 98.39,138.11 99.06,138.11 99.16,138 99.16,137.8 99.06,137.7 98.28,137.7 98.02,137.43 98.02,137 98.28,136.73 99.06,136.73 99.16,136.63 99.16,136.43 99.06,136.33 98.28,136.33 98.02,136.06 98.02,135.63 98.28,135.36 99.06,135.36 99.16,135.26 99.16,135.06 99.06,134.96 98.28,134.96 98.02,134.69 98.02,134.26 98.28,133.99 99.06,133.99 99.16,133.89 99.16,133.69 99.06,133.58 98.28,133.58 98.02,133.32 98.02,132.88 98.28,132.62 99.06,132.62 99.16,132.52 99.16,132.31 99.06,132.21 98.28,132.21 98.02,131.95 98.02,131.51 98.28,131.25 99.06,131.25 99.16,131.15 99.16,130.94 99.06,130.84 98.28,130.84 98.02,130.58 98.02,130.14 98.28,129.88 99.06,129.88 99.16,129.77 99.16,129.57 99.06,129.47 98.28,129.47 98.02,129.2 98.02,128.77 98.28,128.5 99.06,128.5 99.16,128.4 99.16,128.2 99.06,128.1 98.28,128.1 98.02,127.83 98.02,127.4 98.28,127.13 99.06,127.13 99.16,127.03 99.16,126.83 99.06,126.73 98.28,126.73 98.02,126.46 98.02,126.03 98.28,125.76 99.06,125.76 99.16,125.66 99.16,125.46 99.06,125.35 98.28,125.35 98.02,125.09 98.02,124.65 98.28,124.39 99.06,124.39 99.16,124.29 99.16,124.08 99.06,123.98 98.28,123.98 98.02,123.72 98.02,123.28 98.28,123.02 99.06,123.02 99.16,122.92 99.16,122.71 99.06,122.61 98.28,122.61 98.02,122.35 98.02,121.91 98.28,121.65 99.06,121.65 99.16,121.54 99.16,121.34 99.06,121.24 98.28,121.24 98.02,120.97 98.02,120.54 98.28,120.27 99.06,120.27 99.16,120.17 99.16,119.97 99.06,119.87 98.28,119.87 98.02,119.6 98.02,119.17 98.28,118.9 99.06,118.9 99.16,118.8 99.16,118.6 99.06,118.5 98.28,118.5 98.02,118.23 98.02,117.8 98.28,117.53 99.06,117.53 99.16,117.43 99.16,117.23 99.06,117.13 98.28,117.13 98.02,116.86 98.02,116.43 98.28,116.16 99.06,116.16 99.16,116.06 99.16,115.86 99.06,115.75 98.28,115.75 98.02,115.49 98.02,115.05 98.28,114.79 99.06,114.79 99.16,114.69 99.16,114.48 99.06,114.38 98.28,114.38 98.02,114.12 98.02,113.68 98.28,113.42 99.06,113.42 99.16,113.32 99.16,113.11 99.06,113.01 98.54,113.01 98.02,112.49 98.02,111.75 98.28,111.48 98.68,111.48 98.78,111.38 98.78,111.18 98.68,111.08 98.28,111.08 97.89,110.68 97.89,109.47 98.06,109.3 99.06,109.3 99.16,109.2 99.16,109 99.06,108.9 98.28,108.9 98.02,108.63 98.02,107.59 98.28,107.33 98.55,107.33 98.65,107.23 98.65,107.02 98.55,106.92 98.28,106.92 98.02,106.66 98.02,105.45 98.28,105.19 99.06,105.19 99.16,105.09 99.16,104.88 99.06,104.78 98.28,104.78 98.02,104.52 98.02,104.08 98.28,103.82 99.06,103.82 99.16,103.71 99.16,103.51 99.06,103.41 98.28,103.41 98.02,103.14 98.02,102.71 98.28,102.44 99.06,102.44 99.16,102.34 99.16,102.14 99.06,102.04 98.28,102.04 98.02,101.77 98.02,101.34 98.28,101.07 99.06,101.07 99.16,100.97 99.16,100.77 99.06,100.67 98.28,100.67 98.02,100.4 98.02,99.79 97.31,99.08 97.31,97.85 97.21,97.75 96.66,97.75 96.39,97.49 96.39,97.05 96.66,96.79 97.21,96.79 97.31,96.69 97.31,95.62 97.57,95.36 98.17,95.36 98.27,95.26 98.27,95.05 98.17,94.95 97.49,94.95 97.28,94.74 97.28,94.11 97.32,94.07 97.32,93.37 97.33,93.36 97.33,89.04 97.32,89.03 97.32,88.37 97.33,88.36 97.33,88.04 97.32,88.03 97.32,87.91 97.36,87.88 97.36,87.86 97.64,87.58 98.11,87.58 98.12,87.57 98.58,87.57 v2(98.95,87.2)
  BOTTOM w0.114: v1(99.31,148.34) 99.54,148.56 99.54,149.84 J3.84
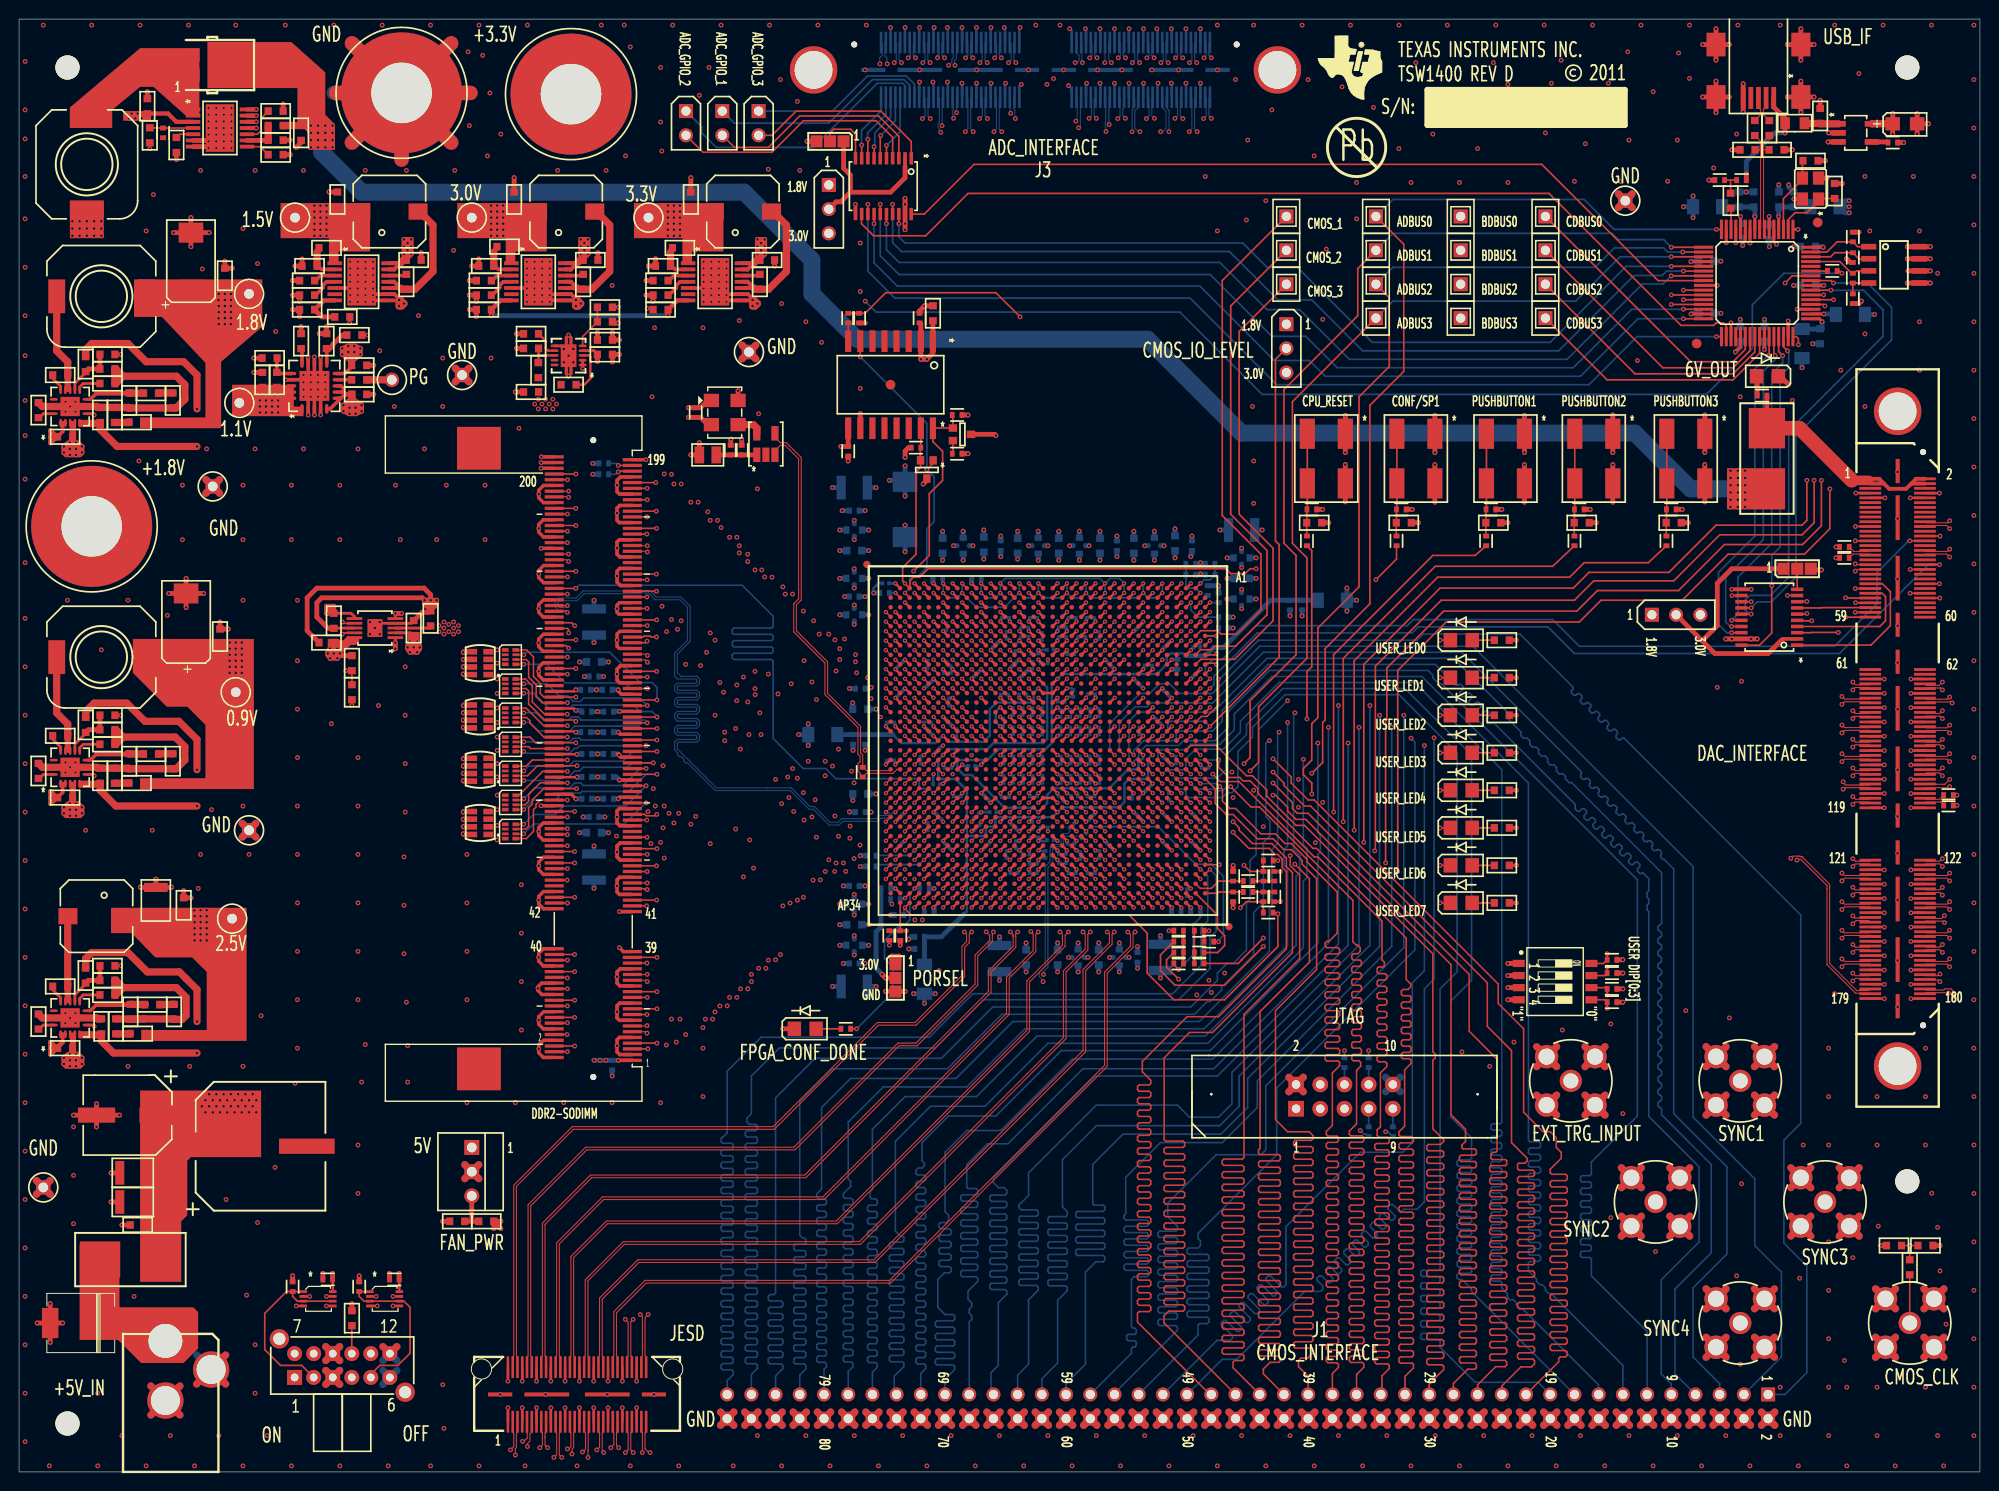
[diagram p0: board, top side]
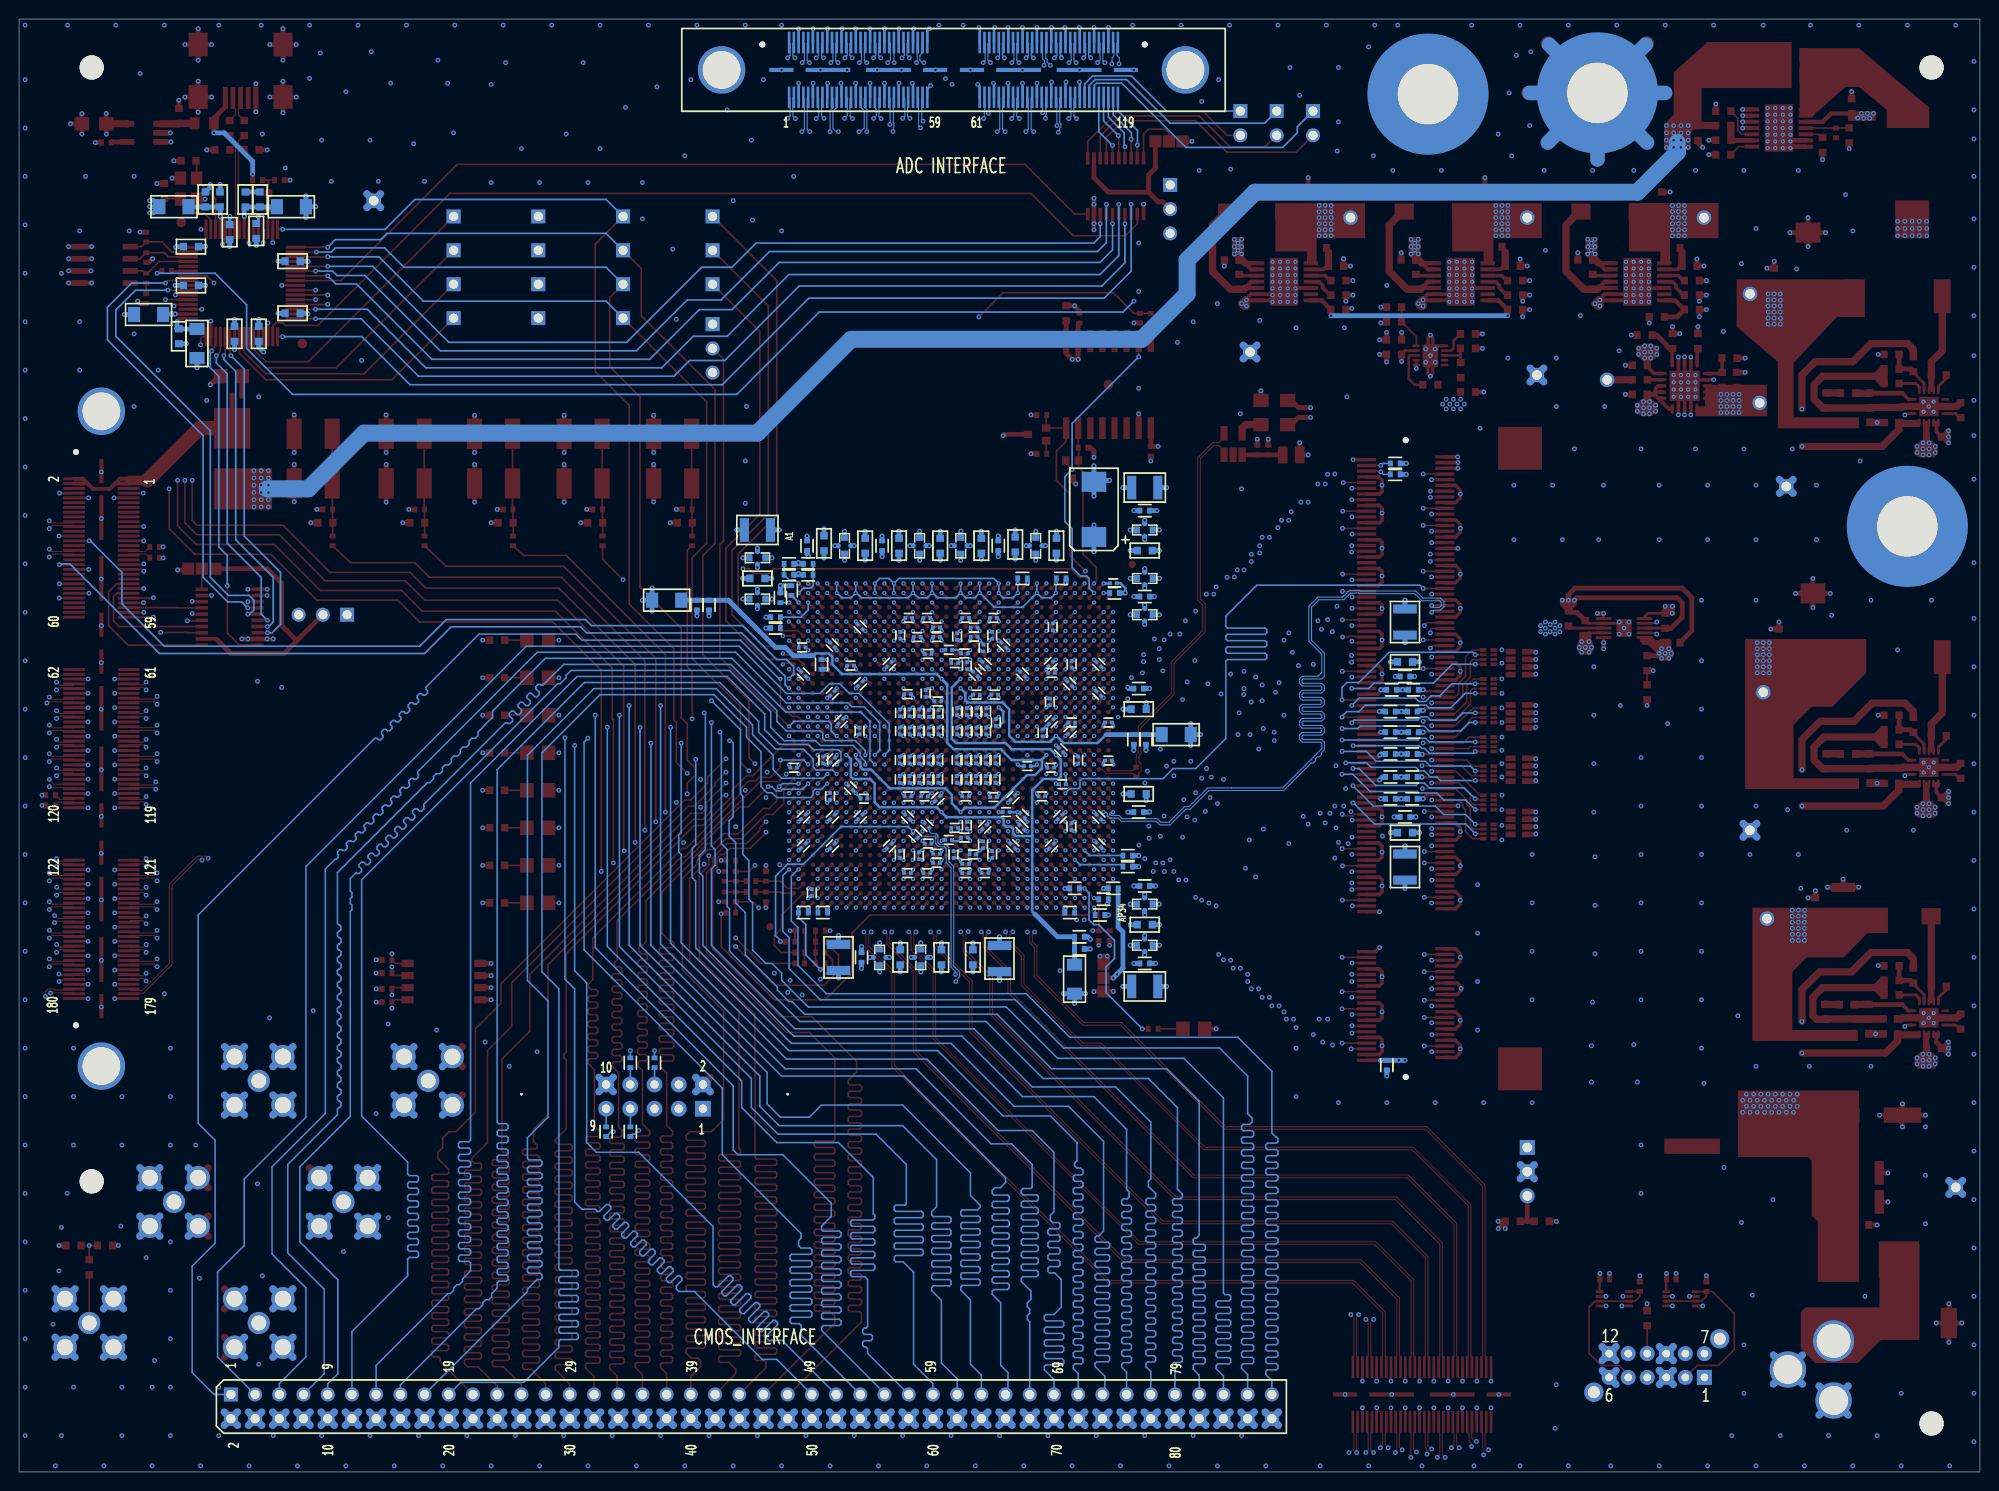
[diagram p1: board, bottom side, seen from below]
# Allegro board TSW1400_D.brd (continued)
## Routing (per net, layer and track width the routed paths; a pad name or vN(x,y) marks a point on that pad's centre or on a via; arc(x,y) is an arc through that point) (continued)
INPUT31_P: length 118.6
  TOP w0.114: U5.F7 v2(119.95,87.2)
  L4-SIG2 w0.102: v1(99.28,140.59) 99.54,140.33 99.54,139.64 110.38,128.8 110.38,128.3 110.28,128.2 108.9,128.2 108.63,127.93 108.63,127.5 108.9,127.23 110.28,127.23 110.38,127.13 110.38,126.93 110.28,126.82 108.9,126.82 108.63,126.56 108.63,126.12 108.9,125.86 110.28,125.86 110.38,125.76 110.38,125.55 110.28,125.45 108.9,125.45 108.63,125.19 108.63,124.75 108.9,124.49 110.28,124.49 110.38,124.39 110.38,124.18 110.28,124.08 108.9,124.08 108.63,123.82 108.63,123.38 108.9,123.12 110.28,123.12 110.38,123.01 110.38,122.81 110.28,122.71 108.9,122.71 108.63,122.44 108.63,122.01 108.9,121.74 110.28,121.74 110.38,121.64 110.38,121.44 110.28,121.34 108.9,121.34 108.63,121.07 108.63,120.64 108.9,120.37 110.28,120.37 110.38,120.27 110.38,120.07 110.28,119.97 108.9,119.97 108.63,119.7 108.63,119.27 108.9,119 110.28,119 110.38,118.9 110.38,118.7 110.28,118.59 108.9,118.59 108.63,118.33 108.63,117.89 108.9,117.63 110.28,117.63 110.38,117.53 110.38,117.32 110.28,117.22 108.9,117.22 108.63,116.96 108.63,116.52 108.9,116.26 110.28,116.26 110.38,116.16 110.38,115.95 110.28,115.85 108.9,115.85 108.63,115.59 108.63,115.15 108.9,114.89 110.28,114.89 110.38,114.78 110.38,114.58 110.28,114.48 108.9,114.48 108.63,114.21 108.63,113.78 108.9,113.51 110.28,113.51 110.38,113.41 110.38,113.21 110.28,113.11 108.9,113.11 108.63,112.84 108.63,112.41 108.9,112.14 110.28,112.14 110.38,112.04 110.38,111.84 110.28,111.74 108.9,111.74 108.63,111.47 108.63,111.04 108.9,110.77 110.28,110.77 110.38,110.67 110.38,110.47 110.28,110.37 108.9,110.37 108.63,110.1 108.63,109.67 108.9,109.4 110.28,109.4 110.38,109.3 110.38,109.1 110.28,108.99 108.9,108.99 108.63,108.73 108.63,108.29 108.9,108.03 110.28,108.03 110.38,107.93 110.38,107.72 110.28,107.62 108.9,107.62 108.63,107.36 108.63,106.92 108.9,106.66 110.28,106.66 110.38,106.56 110.38,106.35 110.28,106.25 108.9,106.25 108.63,105.99 108.63,105.55 108.9,105.29 110.08,105.29 110.38,104.98 110.38,104.26 115.93,98.72 115.93,98.11 116.46,97.58 116.68,97.35 116.72,97.35 117.08,96.99 117.08,96.96 118.11,95.93 118.11,95.34 119.25,94.19 119.25,93.99 119.29,93.95 119.29,93.53 119.33,93.49 119.33,87.65 119.78,87.2 v2(119.95,87.2)
  BOTTOM w0.114: J3.83 99.56,144.09 99.56,140.86 v1(99.28,140.59)
INPUT32_M: length 118.5
  TOP w0.114: U5.E6 v2(120.95,88.2)
  L4-SIG2 w0.102: v2(120.95,88.2) 120.95,88.2 120.95,87.86 121.06,87.76 121.21,87.76 121.33,87.88 121.33,94.64 121.95,95.25 121.95,99.09 117.1,103.93 116.96,103.93 116.81,103.78 116.66,103.78 116.52,103.93 116.52,104.07 116.67,104.22 116.67,104.36 116.52,104.51 116.38,104.51 116.23,104.36 116.09,104.36 115.94,104.5 115.94,104.65 116.09,104.79 116.09,104.94 115.95,105.08 115.81,105.08 115.66,104.93 115.51,104.93 115.37,105.08 115.37,105.22 115.52,105.37 115.52,105.51 115.37,105.66 115.23,105.66 115.08,105.51 114.94,105.51 114.8,105.65 114.8,105.79 114.94,105.94 114.94,106.09 114.5,106.53 114.5,107.66 114.77,107.93 116.1,107.93 116.2,108.03 116.2,108.23 116.1,108.33 114.77,108.33 114.5,108.6 114.5,109.03 114.77,109.3 116.1,109.3 116.2,109.4 116.2,109.6 116.1,109.7 114.77,109.7 114.5,109.97 114.5,110.4 114.77,110.67 116.1,110.67 116.2,110.77 116.2,110.97 116.1,111.08 114.77,111.08 114.5,111.34 114.5,111.78 114.77,112.04 116.1,112.04 116.2,112.14 116.2,112.35 116.1,112.45 114.77,112.45 114.5,112.71 114.5,113.15 114.77,113.41 116.1,113.41 116.2,113.51 116.2,113.72 116.1,113.82 114.77,113.82 114.5,114.08 114.5,114.52 114.77,114.78 116.1,114.78 116.2,114.89 116.2,115.09 116.1,115.19 114.77,115.19 114.5,115.46 114.5,115.89 114.77,116.16 116.1,116.16 116.2,116.26 116.2,116.46 116.1,116.56 114.77,116.56 114.5,116.83 114.5,117.26 114.77,117.53 116.1,117.53 116.2,117.63 116.2,117.83 116.1,117.93 114.77,117.93 114.5,118.2 114.5,118.63 114.77,118.9 116.1,118.9 116.2,119 116.2,119.2 116.1,119.31 114.77,119.31 114.5,119.57 114.5,120.01 114.77,120.27 116.1,120.27 116.2,120.37 116.2,120.58 116.1,120.68 114.77,120.68 114.5,120.94 114.5,121.38 114.77,121.64 116.1,121.64 116.2,121.74 116.2,121.95 116.1,122.05 114.77,122.05 114.5,122.31 114.5,122.75 114.77,123.01 116.1,123.01 116.2,123.12 116.2,123.32 116.1,123.42 114.77,123.42 114.5,123.69 114.5,124.12 114.77,124.39 116.1,124.39 116.2,124.49 116.2,124.69 116.1,124.79 114.77,124.79 114.5,125.06 114.5,125.49 114.77,125.76 116.1,125.76 116.2,125.86 116.2,126.06 116.1,126.16 114.77,126.16 114.5,126.43 114.5,126.86 114.77,127.13 116.1,127.13 116.2,127.23 116.2,127.43 116.1,127.54 114.77,127.54 114.5,127.8 114.5,132.47 105.8,141.17 104.18,141.17 102.68,142.67 98.48,142.67 98.4,142.59 v1(98.35,142.59)
  BOTTOM w0.114: v1(98.35,142.59) 98.35,142.59 98.35,144.1 J3.87
INPUT32_P: length 118.6
  TOP w0.114: U5.D7 v2(121.95,87.2)
  L4-SIG2 w0.102: v1(98.05,141.99) 97.94,142.1 97.94,142.62 97.94,142.62 97.94,142.75 98.18,142.99 98.52,142.99 98.56,142.95 102.79,142.95 104.29,141.45 105.92,141.45 114.78,132.59 114.78,127.92 114.88,127.81 116.22,127.81 116.48,127.55 116.48,127.11 116.22,126.85 114.88,126.85 114.78,126.75 114.78,126.54 114.88,126.44 116.22,126.44 116.48,126.18 116.48,125.74 116.22,125.48 114.88,125.48 114.78,125.38 114.78,125.17 114.88,125.07 116.22,125.07 116.48,124.81 116.48,124.37 116.22,124.11 114.88,124.11 114.78,124 114.78,123.8 114.88,123.7 116.22,123.7 116.48,123.43 116.48,123 116.22,122.73 114.88,122.73 114.78,122.63 114.78,122.43 114.88,122.33 116.22,122.33 116.48,122.06 116.48,121.63 116.22,121.36 114.88,121.36 114.78,121.26 114.78,121.06 114.88,120.96 116.22,120.96 116.48,120.69 116.48,120.26 116.22,119.99 114.88,119.99 114.78,119.89 114.78,119.69 114.88,119.59 116.22,119.59 116.48,119.32 116.48,118.89 116.22,118.62 114.88,118.62 114.78,118.52 114.78,118.32 114.88,118.21 116.22,118.21 116.48,117.95 116.48,117.51 116.22,117.25 114.88,117.25 114.78,117.15 114.78,116.94 114.88,116.84 116.22,116.84 116.48,116.58 116.48,116.14 116.22,115.88 114.88,115.88 114.78,115.78 114.78,115.57 114.88,115.47 116.22,115.47 116.48,115.21 116.48,114.77 116.22,114.51 114.88,114.51 114.78,114.4 114.78,114.2 114.88,114.1 116.22,114.1 116.48,113.83 116.48,113.4 116.22,113.13 114.88,113.13 114.78,113.03 114.78,112.83 114.88,112.73 116.22,112.73 116.48,112.46 116.48,112.03 116.22,111.76 114.88,111.76 114.78,111.66 114.78,111.46 114.88,111.36 116.22,111.36 116.48,111.09 116.48,110.66 116.22,110.39 114.88,110.39 114.78,110.29 114.78,110.09 114.88,109.98 116.22,109.98 116.48,109.72 116.48,109.28 116.22,109.02 114.88,109.02 114.78,108.92 114.78,108.71 114.88,108.61 116.22,108.61 116.48,108.35 116.48,107.91 116.22,107.65 114.88,107.65 114.78,107.55 114.78,106.64 122.22,99.2 122.22,95.1 121.61,94.48 121.61,93.99 121.57,93.95 121.57,87.58 v2(121.95,87.2)
  BOTTOM w0.114: J3.89 98.02,144.13 98.02,142.83 97.94,142.76 97.94,142.41 98.02,142.34 98.02,142.03 v1(98.05,141.99)
INPUT33_M: length 118.5
  TOP w0.114: U5.D6 v2(121.95,88.2)
  L4-SIG2 w0.102: v2(121.95,88.2) 121.97,88.18 121.97,87.83 122.07,87.73 122.25,87.73 122.33,87.81 122.33,94.77 123.62,96.06 123.62,100.51 120.61,103.52 120.47,103.52 120.28,103.33 120.14,103.33 119.99,103.47 119.99,103.62 120.18,103.8 120.18,103.95 120.04,104.09 119.89,104.09 119.71,103.91 119.56,103.91 119.42,104.05 119.42,104.19 119.61,104.38 119.61,104.52 119.46,104.67 119.32,104.67 119.13,104.48 118.99,104.48 118.85,104.62 118.85,104.77 119.03,104.95 119.03,105.1 118.89,105.24 118.74,105.24 118.56,105.06 118.41,105.06 118.27,105.2 118.27,105.34 118.46,105.53 118.46,105.67 118.24,105.89 118.24,106.89 118.5,107.15 119.41,107.15 119.51,107.26 119.51,107.46 119.41,107.56 118.5,107.56 118.24,107.83 118.24,108.26 118.5,108.53 119.41,108.53 119.51,108.63 119.51,108.83 119.41,108.93 118.5,108.93 118.24,109.2 118.24,109.63 118.5,109.9 119.41,109.9 119.51,110 119.51,110.2 119.41,110.3 118.5,110.3 118.24,110.57 118.24,111 118.5,111.27 119.41,111.27 119.51,111.37 119.51,111.57 119.41,111.68 118.5,111.68 118.24,111.94 118.24,112.38 118.5,112.64 119.41,112.64 119.51,112.74 119.51,112.95 119.41,113.05 118.5,113.05 118.24,113.31 118.24,113.75 118.5,114.01 119.41,114.01 119.51,114.11 119.51,114.32 119.41,114.42 118.5,114.42 118.24,114.68 118.24,115.12 118.5,115.38 119.41,115.38 119.51,115.49 119.51,115.69 119.41,115.79 118.5,115.79 118.24,116.06 118.24,116.49 118.5,116.76 119.41,116.76 119.51,116.86 119.51,117.06 119.41,117.16 118.5,117.16 118.24,117.43 118.24,117.86 118.5,118.13 119.41,118.13 119.51,118.23 119.51,118.43 119.41,118.53 118.5,118.53 118.24,118.8 118.24,119.23 118.5,119.5 119.41,119.5 119.51,119.6 119.51,119.8 119.41,119.91 118.5,119.91 118.24,120.17 118.24,120.61 118.5,120.87 119.41,120.87 119.51,120.97 119.51,121.18 119.41,121.28 118.5,121.28 118.24,121.54 118.24,121.98 118.5,122.24 119.41,122.24 119.51,122.34 119.51,122.55 119.41,122.65 118.5,122.65 118.24,122.91 118.24,123.35 118.5,123.61 119.41,123.61 119.51,123.72 119.51,123.92 119.41,124.02 118.5,124.02 118.24,124.29 118.24,124.72 118.5,124.99 119.41,124.99 119.51,125.09 119.51,125.29 119.41,125.39 118.5,125.39 118.24,125.66 118.24,126.09 118.5,126.36 119.41,126.36 119.51,126.46 119.51,126.66 119.41,126.76 118.5,126.76 118.24,127.03 118.24,127.46 118.5,127.73 119.41,127.73 119.51,127.83 119.51,128.03 119.41,128.13 118.5,128.13 118.24,128.4 118.24,128.83 118.5,129.1 119.41,129.1 119.51,129.2 119.51,129.4 119.41,129.51 118.5,129.51 118.24,129.77 118.24,132.47 107.22,143.48 97.41,143.48 96.85,142.93 96.85,141.41 96.84,141.4 v1(96.84,141.22)
  BOTTOM w0.114: v1(96.84,141.22) 96.85,141.23 96.85,144.1 J3.93
INPUT33_P: length 118.4
  TOP w0.114: U5.C7 v2(122.95,87.2)
  L4-SIG2 w0.102: v2(122.95,87.2) 122.57,87.58 122.57,94.07 122.61,94.11 122.61,94.66 123.9,95.95 123.9,100.62 118.52,106.01 118.52,106.77 118.62,106.88 119.52,106.88 119.79,107.14 119.79,107.58 119.52,107.84 118.62,107.84 118.52,107.94 118.52,108.15 118.62,108.25 119.52,108.25 119.79,108.51 119.79,108.95 119.52,109.21 118.62,109.21 118.52,109.31 118.52,109.52 118.62,109.62 119.52,109.62 119.79,109.88 119.79,110.32 119.52,110.58 118.62,110.58 118.52,110.69 118.52,110.89 118.62,110.99 119.52,110.99 119.79,111.26 119.79,111.69 119.52,111.96 118.62,111.96 118.52,112.06 118.52,112.26 118.62,112.36 119.52,112.36 119.79,112.63 119.79,113.06 119.52,113.33 118.62,113.33 118.52,113.43 118.52,113.63 118.62,113.73 119.52,113.73 119.79,114 119.79,114.43 119.52,114.7 118.62,114.7 118.52,114.8 118.52,115 118.62,115.1 119.52,115.1 119.79,115.37 119.79,115.8 119.52,116.07 118.62,116.07 118.52,116.17 118.52,116.37 118.62,116.48 119.52,116.48 119.79,116.74 119.79,117.18 119.52,117.44 118.62,117.44 118.52,117.54 118.52,117.75 118.62,117.85 119.52,117.85 119.79,118.11 119.79,118.55 119.52,118.81 118.62,118.81 118.52,118.91 118.52,119.12 118.62,119.22 119.52,119.22 119.79,119.48 119.79,119.92 119.52,120.18 118.62,120.18 118.52,120.29 118.52,120.49 118.62,120.59 119.52,120.59 119.79,120.86 119.79,121.29 119.52,121.56 118.62,121.56 118.52,121.66 118.52,121.86 118.62,121.96 119.52,121.96 119.79,122.23 119.79,122.66 119.52,122.93 118.62,122.93 118.52,123.03 118.52,123.23 118.62,123.33 119.52,123.33 119.79,123.6 119.79,124.03 119.52,124.3 118.62,124.3 118.52,124.4 118.52,124.6 118.62,124.71 119.52,124.71 119.79,124.97 119.79,125.41 119.52,125.67 118.62,125.67 118.52,125.77 118.52,125.98 118.62,126.08 119.52,126.08 119.79,126.34 119.79,126.78 119.52,127.04 118.62,127.04 118.52,127.14 118.52,127.35 118.62,127.45 119.52,127.45 119.79,127.71 119.79,128.15 119.52,128.41 118.62,128.41 118.52,128.52 118.52,128.72 118.62,128.82 119.52,128.82 119.79,129.09 119.79,129.57 119.57,129.79 118.62,129.79 118.52,129.89 118.52,132.59 107.34,143.76 97.64,143.76 97.29,143.76 96.57,143.04 96.57,142.81 96.57,141.52 96.44,141.39 96.44,141.05 96.7,140.78 v1(96.7,140.53)
  BOTTOM w0.114: v1(96.7,140.53) 96.56,140.67 96.56,140.92 96.43,141.05 96.43,141.39 96.56,141.52 96.56,144.08 J3.95
INPUT34_M: length 118.5
  TOP w0.114: U5.C5 v2(122.95,89.2)
  L4-SIG2 w0.102: v2(122.95,89.2) 122.95,88.89 123.05,88.78 123.66,88.78 123.69,88.82 124.12,88.82 124.33,89.03 124.33,92.58 124.93,93.18 124.93,94.07 124.89,94.11 124.89,102.59 121.31,106.17 121.31,107.19 121.58,107.46 122.17,107.46 122.28,107.56 122.28,107.76 122.17,107.86 121.58,107.86 121.31,108.13 121.31,108.56 121.58,108.83 122.17,108.83 122.28,108.93 122.28,109.13 122.17,109.24 121.58,109.24 121.31,109.5 121.31,109.94 121.58,110.2 122.17,110.2 122.28,110.3 122.28,110.51 122.17,110.61 121.58,110.61 121.31,110.87 121.31,111.31 121.58,111.57 122.17,111.57 122.28,111.67 122.28,111.88 122.17,111.98 121.58,111.98 121.31,112.24 121.31,112.68 121.58,112.94 122.17,112.94 122.28,113.05 122.28,113.25 122.17,113.35 121.58,113.35 121.31,113.62 121.31,114.05 121.58,114.32 122.17,114.32 122.28,114.42 122.28,114.62 122.17,114.72 121.58,114.72 121.31,114.99 121.31,115.42 121.58,115.69 122.17,115.69 122.28,115.79 122.28,115.99 122.17,116.09 121.58,116.09 121.31,116.36 121.31,116.79 121.58,117.06 122.17,117.06 122.28,117.16 122.28,117.36 122.17,117.46 121.58,117.46 121.31,117.73 121.31,118.16 121.58,118.43 122.17,118.43 122.28,118.53 122.28,118.73 122.17,118.84 121.58,118.84 121.31,119.1 121.31,119.54 121.58,119.8 122.17,119.8 122.28,119.9 122.28,120.11 122.17,120.21 121.58,120.21 121.31,120.47 121.31,120.91 121.58,121.17 122.17,121.17 122.28,121.27 122.28,121.48 122.17,121.58 121.58,121.58 121.31,121.84 121.31,122.28 121.58,122.54 122.17,122.54 122.28,122.65 122.28,122.85 122.17,122.95 121.58,122.95 121.31,123.22 121.31,123.65 121.58,123.92 122.17,123.92 122.28,124.02 122.28,124.22 122.17,124.32 121.58,124.32 121.31,124.59 121.31,125.02 121.58,125.29 122.17,125.29 122.28,125.39 122.28,125.59 122.17,125.69 121.58,125.69 121.31,125.96 121.31,126.39 121.58,126.66 122.17,126.66 122.28,126.76 122.28,126.96 122.17,127.07 121.58,127.07 121.31,127.33 121.31,127.77 121.58,128.03 122.17,128.03 122.28,128.13 122.28,128.34 122.17,128.44 121.58,128.44 121.31,128.7 121.31,129.14 121.58,129.4 122.17,129.4 122.28,129.5 122.28,129.71 122.17,129.81 121.58,129.81 121.31,130.07 121.31,130.51 121.58,130.77 122.17,130.77 122.28,130.88 122.28,131.08 122.17,131.18 121.58,131.18 121.31,131.45 121.31,131.88 121.58,132.15 122.17,132.15 122.28,132.25 122.28,132.45 122.17,132.55 121.58,132.55 121.31,132.82 121.31,133.25 121.58,133.52 122.17,133.52 122.28,133.62 122.28,133.82 122.17,133.92 121.58,133.92 121.31,134.19 121.31,134.62 121.58,134.89 122.17,134.89 122.28,134.99 122.28,135.19 121.31,136.16 121.31,137.68 120.64,138.35 120.5,138.35 120.37,138.22 120.23,138.22 120.08,138.36 120.08,138.51 120.21,138.64 120.21,138.78 120.07,138.92 119.92,138.92 119.79,138.79 119.65,138.79 119.51,138.94 119.51,139.08 119.64,139.21 119.64,139.35 119.49,139.5 119.35,139.5 119.22,139.37 119.08,139.37 118.93,139.51 118.93,139.66 119.06,139.79 119.06,139.93 114.54,144.45 96.92,144.45 95.34,142.87 95.34,142.23 v1(95.61,141.96)
  BOTTOM w0.114: J3.99 95.36,144.11 95.36,142.2 v1(95.61,141.96)
INPUT34_P: length 118.4
  TOP w0.114: U5.C6 v2(122.95,88.2)
  L4-SIG2 w0.102: v2(122.95,88.2) 123.27,88.52 123.73,88.52 123.79,88.58 124.22,88.58 124.57,88.93 124.57,92.48 125.17,93.08 125.17,102.71 121.59,106.29 121.59,107.08 121.69,107.18 122.29,107.18 122.56,107.44 122.56,107.88 122.29,108.14 121.69,108.14 121.59,108.24 121.59,108.45 121.69,108.55 122.29,108.55 122.56,108.81 122.56,109.25 122.29,109.51 121.69,109.51 121.59,109.62 121.59,109.82 121.69,109.92 122.29,109.92 122.56,110.19 122.56,110.62 122.29,110.89 121.69,110.89 121.59,110.99 121.59,111.19 121.69,111.29 122.29,111.29 122.56,111.56 122.56,111.99 122.29,112.26 121.69,112.26 121.59,112.36 121.59,112.56 121.69,112.66 122.29,112.66 122.56,112.93 122.56,113.36 122.29,113.63 121.69,113.63 121.59,113.73 121.59,113.93 121.69,114.04 122.29,114.04 122.56,114.3 122.56,114.74 122.29,115 121.69,115 121.59,115.1 121.59,115.31 121.69,115.41 122.29,115.41 122.56,115.67 122.56,116.11 122.29,116.37 121.69,116.37 121.59,116.47 121.59,116.68 121.69,116.78 122.29,116.78 122.56,117.04 122.56,117.48 122.29,117.74 121.69,117.74 121.59,117.85 121.59,118.05 121.69,118.15 122.29,118.15 122.56,118.42 122.56,118.85 122.29,119.12 121.69,119.12 121.59,119.22 121.59,119.42 121.69,119.52 122.29,119.52 122.56,119.79 122.56,120.22 122.29,120.49 121.69,120.49 121.59,120.59 121.59,120.79 121.69,120.89 122.29,120.89 122.56,121.16 122.56,121.59 122.29,121.86 121.69,121.86 121.59,121.96 121.59,122.16 121.69,122.27 122.29,122.27 122.56,122.53 122.56,122.97 122.29,123.23 121.69,123.23 121.59,123.33 121.59,123.54 121.69,123.64 122.29,123.64 122.56,123.9 122.56,124.34 122.29,124.6 121.69,124.6 121.59,124.7 121.59,124.91 121.69,125.01 122.29,125.01 122.56,125.27 122.56,125.71 122.29,125.97 121.69,125.97 121.59,126.08 121.59,126.28 121.69,126.38 122.29,126.38 122.56,126.65 122.56,127.08 122.29,127.35 121.69,127.35 121.59,127.45 121.59,127.65 121.69,127.75 122.29,127.75 122.56,128.02 122.56,128.45 122.29,128.72 121.69,128.72 121.59,128.82 121.59,129.02 121.69,129.12 122.29,129.12 122.56,129.39 122.56,129.82 122.29,130.09 121.69,130.09 121.59,130.19 121.59,130.39 121.69,130.5 122.29,130.5 122.56,130.76 122.56,131.19 122.29,131.46 121.69,131.46 121.59,131.56 121.59,131.77 121.69,131.87 122.29,131.87 122.56,132.13 122.56,132.57 122.29,132.83 121.69,132.83 121.59,132.93 121.59,133.14 121.69,133.24 122.29,133.24 122.56,133.5 122.56,133.94 122.29,134.2 121.69,134.2 121.59,134.31 121.59,134.51 121.69,134.61 122.29,134.61 122.56,134.88 122.56,135.38 121.59,136.35 121.59,137.79 121.02,138.36 121.02,138.56 120.84,138.75 120.64,138.75 120.45,138.94 120.45,139.14 120.26,139.32 120.06,139.32 119.87,139.51 119.87,139.71 119.69,139.9 119.49,139.9 114.66,144.73 96.8,144.73 95.06,142.99 95.06,142.23 v1(94.78,141.96)
  BOTTOM w0.114: J3.101 95.06,144.08 95.06,142.24 v1(94.78,141.96)
ISTROBE_N: length 135.4
  TOP w0.114: v1(202.44,50.23) 202.4,50.27 200.08,50.27 J4.178 ; U5.J25 v2(116.95,68.2)
  L9-SIG3 w0.102: v1(202.44,50.23) 202.44,51.95 203.95,53.46 203.95,63.32 200.32,66.95 198.75,66.95 198.34,66.55 197.94,66.55 197.53,66.95 197.13,66.95 196.72,66.55 196.31,66.55 195.91,66.95 195.5,66.95 195.09,66.55 194.69,66.55 194.28,66.95 193.87,66.95 193.47,66.55 193.06,66.55 192.65,66.95 192.35,66.95 190.25,69.06 176.05,69.06 175.87,68.88 175.39,68.88 175.21,69.06 174.68,69.06 174.47,68.86 173.94,68.86 173.69,69.11 172.9,69.11 172.8,69.01 172.8,68.95 172.53,68.68 172.1,68.68 171.83,68.95 171.83,69.01 171.73,69.11 171.53,69.11 171.42,69.01 171.42,68.95 171.16,68.68 170.57,68.68 170.26,69 170.26,69.42 170.15,69.52 169.95,69.52 169.85,69.42 169.85,68.87 169.58,68.61 169.15,68.61 168.88,68.87 168.88,69.42 168.78,69.52 168.58,69.52 168.48,69.42 168.48,68.87 168.21,68.61 167.78,68.61 167.51,68.87 167.51,69.42 167.41,69.52 167.21,69.52 167.11,69.42 167.11,68.87 166.84,68.61 166.41,68.61 166.14,68.87 166.14,69.42 166.04,69.52 165.84,69.52 165.73,69.42 165.73,68.87 165.47,68.61 165.03,68.61 164.77,68.87 164.77,69.42 164.67,69.52 164.46,69.52 164.36,69.42 164.36,68.87 164.1,68.61 163.66,68.61 163.4,68.87 163.4,69.42 163.3,69.52 163.09,69.52 162.99,69.42 162.99,68.87 162.73,68.61 162.29,68.61 162.03,68.87 162.03,69.42 161.92,69.52 161.72,69.52 161.62,69.42 161.62,68.87 161.35,68.61 160.92,68.61 160.65,68.87 160.65,69.42 160.55,69.52 160.35,69.52 160.25,69.42 160.25,68.87 159.98,68.61 159.55,68.61 159.28,68.87 159.28,69.42 159.18,69.52 158.98,69.52 158.88,69.42 158.88,68.87 158.61,68.61 158.18,68.61 157.91,68.87 157.91,69.42 157.81,69.52 157.61,69.52 157.51,69.42 157.51,68.87 157.24,68.61 156.81,68.61 156.54,68.87 156.54,69.42 156.44,69.52 156.24,69.52 156.13,69.42 156.13,68.87 155.87,68.61 155.43,68.61 155.17,68.87 155.17,69.42 155.07,69.52 154.86,69.52 154.76,69.42 154.76,68.87 154.5,68.61 154.06,68.61 153.8,68.87 153.8,69.42 153.7,69.52 153.49,69.52 153.39,69.42 153.39,68.87 153.13,68.61 152.69,68.61 152.43,68.87 152.43,69.42 152.32,69.52 152.12,69.52 152.02,69.42 152.02,68.87 151.75,68.61 151.32,68.61 151.05,68.87 151.05,69.42 150.95,69.52 150.75,69.52 150.65,69.42 150.65,68.87 150.38,68.61 149.95,68.61 149.68,68.87 149.68,69.42 149.58,69.52 149.38,69.52 149.28,69.42 149.28,68.87 149.01,68.61 148.58,68.61 148.31,68.87 148.31,68.96 148.21,69.06 147.18,69.06 142.33,64.21 134.4,64.21 133.51,65.1 125.78,65.1 125.3,65.58 119.68,65.58 119.6,65.58 119.12,66.07 119.12,66.94 118.24,67.82 117.33,67.82 v2(116.95,68.2)
ISTROBE_P: length 135.4
  TOP w0.114: J4.176 200.08,50.55 201.93,50.55 202.06,50.67 202.69,50.67 202.95,50.42 202.95,49.9 v1(202.97,49.88) ; U5.H24 v2(117.95,69.2)
  L9-SIG3 w0.102: v1(202.97,49.88) 202.85,50 202.85,50.4 202.72,50.52 202.72,51.83 204.23,53.34 204.23,63.44 200.44,67.23 198.63,67.23 198.58,67.18 197.7,67.18 197.65,67.23 192.47,67.23 190.36,69.34 173.85,69.34 173.8,69.39 172.78,69.39 172.45,69.06 172.18,69.06 171.85,69.39 171.41,69.39 171.15,69.13 171.15,69.06 171.04,68.96 170.81,68.96 170.54,69.24 170.54,69.53 170.27,69.8 169.84,69.8 169.57,69.53 169.57,68.99 169.47,68.88 169.27,68.88 169.16,68.99 169.16,69.53 168.9,69.8 168.46,69.8 168.2,69.53 168.2,68.99 168.1,68.88 167.89,68.88 167.79,68.99 167.79,69.53 167.53,69.8 167.09,69.8 166.83,69.53 166.83,68.99 166.73,68.88 166.52,68.88 166.42,68.99 166.42,69.53 166.16,69.8 165.72,69.8 165.46,69.53 165.46,68.99 165.35,68.88 165.15,68.88 165.05,68.99 165.05,69.53 164.78,69.8 164.35,69.8 164.08,69.53 164.08,68.99 163.98,68.88 163.78,68.88 163.68,68.99 163.68,69.53 163.41,69.8 162.98,69.8 162.71,69.53 162.71,68.99 162.61,68.88 162.41,68.88 162.31,68.99 162.31,69.53 162.04,69.8 161.61,69.8 161.34,69.53 161.34,68.99 161.24,68.88 161.04,68.88 160.93,68.99 160.93,69.53 160.67,69.8 160.23,69.8 159.97,69.53 159.97,68.99 159.87,68.88 159.66,68.88 159.56,68.99 159.56,69.53 159.3,69.8 158.86,69.8 158.6,69.53 158.6,68.99 158.5,68.88 158.29,68.88 158.19,68.99 158.19,69.53 157.93,69.8 157.49,69.8 157.23,69.53 157.23,68.99 157.12,68.88 156.92,68.88 156.82,68.99 156.82,69.53 156.55,69.8 156.12,69.8 155.85,69.53 155.85,68.99 155.75,68.88 155.55,68.88 155.45,68.99 155.45,69.53 155.18,69.8 154.75,69.8 154.48,69.53 154.48,68.99 154.38,68.88 154.18,68.88 154.08,68.99 154.08,69.53 153.81,69.8 153.38,69.8 153.11,69.53 153.11,68.99 153.01,68.88 152.81,68.88 152.7,68.99 152.7,69.53 152.44,69.8 152,69.8 151.74,69.53 151.74,68.99 151.64,68.88 151.43,68.88 151.33,68.99 151.33,69.53 151.07,69.8 150.63,69.8 150.37,69.53 150.37,68.99 150.27,68.88 150.06,68.88 149.96,68.99 149.96,69.53 149.7,69.8 149.26,69.8 149,69.53 149,68.99 148.89,68.88 148.69,68.88 148.59,68.99 148.59,69.08 148.32,69.34 147.07,69.34 142.21,64.49 134.52,64.49 133.63,65.38 125.98,65.38 125.54,65.82 119.79,65.82 119.77,65.84 119.68,65.84 119.35,66.17 119.35,67.08 118.36,68.07 118.36,68.79 v2(117.95,69.2)
JTAG_BLAST_TDI: length 45
  TOP w0.178: v1(128.52,63.63) 129.16,62.99 R58.1 R156.1
  L3-SIG1 w0.178: v1(128.52,63.63) 128.52,62.99 128.78,62.74 128.78,58.29 127.76,57.28 127.76,52.32 134.49,45.59 141.35,45.59 145.41,41.53 145.41,37.72 v1(143.38,35.69)
  BOTTOM w0.178: 144.15,35.18 143.64,35.69 v1(143.38,35.69)
JTAG_BLAST_TDO: length 25.2
  TOP w0.178: v1(124.84,56.77) R59.1 R127.1
  L3-SIG1 w0.178: v1(124.84,56.77) 124.84,52.45 125.35,51.94 125.35,50.93 135.25,41.02 135.25,39.37 J13.3
JTAG_TCK: length 24.7
  TOP w0.178: R57.1 v1(120.65,56.77)
  L3-SIG1 w0.178: v1(120.65,56.77) 120.65,51.44 J13.1
JTAG_TMS: length 33.1
  TOP w0.178: R128.1 R60.1 128.78,59.82 v1(128.14,59.18)
  L3-SIG1 w0.178: 139.06,38.1 140.34,39.37 140.34,41.53 137.67,44.2 134.62,44.2 127.13,51.69 127.13,57.66 128.14,58.67 v1(128.14,59.18)
NCE: length 56.7
  TOP w0.178: U5.AN34 92.45,57.54 92.46,57.53 92.46,56.77 ; 91.31,56.77 92.46,56.77 ; 92.46,56.77 v1(93.09,56.77)
  L10-SIG4 w0.178: v1(139.06,44.2) 138.68,44.2 135.64,47.24 104.39,47.24 94.87,56.77 v1(93.09,56.77)
  BOTTOM w0.178: R132.1 v1(139.06,44.2)
NCS: length 98.3
  TOP w0.178: v1(142.37,93.6) 144.53,95.76 R99.1 ; R128.2 v1(132.08,58.55) 132.08,55.12 126.49,49.53 121.16,49.53 118.36,52.32 118.36,56.52 116.46,58.42 93.6,58.42 92.95,59.07 v2(92.95,59.2) U5.AM34
  L3-SIG1 w0.178: v1(132.08,58.55) 132.97,59.44 132.97,64.26 132.72,64.52 132.72,76.07 131.7,77.09 131.7,81.92 142.37,92.58 v1(142.37,93.6)
  BOTTOM w0.178: R51.2 92.84,59.09 v2(92.95,59.2)
OSTROBE_N: length 135.5
  TOP w0.114: v1(192.41,51.5) 192.68,51.77 194.13,51.77 J4.171 ; U5.N11 v2(112.95,83.2)
  L10-SIG4 w0.102: v1(192.41,51.5) 192.68,51.77 192.98,51.77 193.5,52.28 193.5,65.83 191.35,67.97 188.09,67.97 187.99,68.07 187.99,68.21 187.73,68.48 187.29,68.48 187.03,68.21 187.03,68.07 186.93,67.97 186.72,67.97 186.62,68.07 186.62,68.21 186.36,68.48 185.92,68.48 185.66,68.21 185.66,68.07 185.55,67.97 185.35,67.97 185.25,68.07 185.25,68.21 184.98,68.48 184.55,68.48 184.28,68.21 184.28,68.07 184.18,67.97 183.98,67.97 183.88,68.07 183.88,68.21 183.61,68.48 183.18,68.48 182.91,68.21 182.91,68.07 182.81,67.97 182.61,67.97 182.51,68.07 182.51,68.21 182.24,68.48 181.81,68.48 181.54,68.21 181.54,68.07 181.44,67.97 181.24,67.97 181.13,68.07 181.13,68.21 180.87,68.48 180.43,68.48 180.17,68.21 180.17,68.07 180.07,67.97 179.86,67.97 179.76,68.07 179.76,68.21 179.5,68.48 179.06,68.48 178.8,68.21 178.8,68.07 178.7,67.97 178.49,67.97 178.39,68.07 178.39,68.21 178.13,68.48 177.69,68.48 177.43,68.21 177.43,68.07 177.32,67.97 177.12,67.97 177.02,68.07 177.02,68.21 176.75,68.48 176.32,68.48 176.05,68.21 176.05,68.07 175.95,67.97 175.75,67.97 175.65,68.07 175.65,68.21 175.38,68.48 174.95,68.48 174.68,68.21 174.68,68.07 174.58,67.97 174.38,67.97 174.28,68.07 174.28,68.21 174.01,68.48 173.58,68.48 173.31,68.21 173.31,68.07 173.21,67.97 173.01,67.97 172.9,68.07 172.9,68.21 172.64,68.48 172.2,68.48 171.94,68.21 171.94,68.07 171.84,67.97 171.63,67.97 171.53,68.07 171.53,68.21 171.27,68.48 170.83,68.48 170.57,68.21 170.57,68.07 170.47,67.97 170.26,67.97 170.16,68.07 170.16,68.21 169.9,68.48 169.46,68.48 169.2,68.21 169.2,68.07 169.09,67.97 168.89,67.97 168.79,68.07 168.79,68.21 168.52,68.48 168.09,68.48 167.82,68.21 167.82,68.07 167.72,67.97 167.52,67.97 167.42,68.07 167.42,68.21 167.15,68.48 166.72,68.48 166.45,68.21 166.45,68.07 166.35,67.97 166.15,67.97 166.05,68.07 166.05,68.21 165.78,68.48 165.35,68.48 165.08,68.21 165.08,68.07 164.98,67.97 164.78,67.97 164.68,68.07 164.68,68.21 164.41,68.48 163.98,68.48 163.71,68.21 163.71,68.07 163.61,67.97 163.41,67.97 163.3,68.07 163.3,68.21 163.04,68.48 162.6,68.48 162.34,68.21 162.34,68.07 162.24,67.97 162.03,67.97 161.93,68.07 161.93,68.21 161.67,68.48 161.23,68.48 160.97,68.21 160.97,68.07 160.87,67.97 160.66,67.97 160.56,68.07 160.56,68.21 160.3,68.48 159.86,68.48 159.6,68.21 159.6,68.07 159.49,67.97 159.29,67.97 159.19,68.07 159.19,68.21 158.92,68.48 156.04,68.48 154.01,66.45 142.4,66.45 141.54,65.58 126.38,65.58 125.61,64.82 125.23,64.82 125.23,64.82 124.79,64.82 124.79,64.82 124.11,64.82 124.11,64.82 123.26,64.82 122.26,63.82 111.79,63.82 111.57,64.04 111.57,64.46 111.57,64.46 111.57,64.94 111.57,64.94 111.57,65.46 111.57,65.46 111.57,65.94 111.57,65.94 111.57,66.46 111.57,66.46 111.57,66.94 111.57,66.94 111.57,67.46 111.57,67.46 111.57,67.94 111.57,67.94 111.57,68.36 111.79,68.58 112.22,68.58 112.57,68.93 112.57,81.36 112.79,81.58 112.87,81.58 113.01,81.72 113.01,81.73 113.33,82.04 113.33,82.82 v2(112.95,83.2)
OSTROBE_P: length 135.4
  TOP w0.114: J4.169 194.13,52.05 192.68,52.05 v1(192.41,52.32) ; U5.N12 v2(112.95,82.2)
  L10-SIG4 w0.102: v1(192.41,52.32) 192.68,52.05 192.87,52.05 193.22,52.4 193.22,65.71 191.24,67.69 189.67,67.69 189.57,67.59 189.57,67.26 189.47,67.16 189.27,67.16 189.17,67.26 189.17,67.59 189.06,67.69 188.86,67.69 188.76,67.59 188.76,67.26 188.66,67.16 188.45,67.16 188.35,67.26 188.35,67.59 188.25,67.69 187.98,67.69 187.71,67.96 187.71,68.1 187.61,68.2 187.41,68.2 187.31,68.1 187.31,67.96 187.04,67.69 186.61,67.69 186.34,67.96 186.34,68.1 186.24,68.2 186.04,68.2 185.93,68.1 185.93,67.96 185.67,67.69 185.23,67.69 184.97,67.96 184.97,68.1 184.87,68.2 184.66,68.2 184.56,68.1 184.56,67.96 184.3,67.69 183.86,67.69 183.6,67.96 183.6,68.1 183.5,68.2 183.29,68.2 183.19,68.1 183.19,67.96 182.93,67.69 182.49,67.69 182.23,67.96 182.23,68.1 182.12,68.2 181.92,68.2 181.82,68.1 181.82,67.96 181.55,67.69 181.12,67.69 180.85,67.96 180.85,68.1 180.75,68.2 180.55,68.2 180.45,68.1 180.45,67.96 180.18,67.69 179.75,67.69 179.48,67.96 179.48,68.1 179.38,68.2 179.18,68.2 179.08,68.1 179.08,67.96 178.81,67.69 178.38,67.69 178.11,67.96 178.11,68.1 178.01,68.2 177.81,68.2 177.71,68.1 177.71,67.96 177.44,67.69 177.01,67.69 176.74,67.96 176.74,68.1 176.64,68.2 176.44,68.2 176.33,68.1 176.33,67.96 176.07,67.69 175.63,67.69 175.37,67.96 175.37,68.1 175.27,68.2 175.06,68.2 174.96,68.1 174.96,67.96 174.7,67.69 174.26,67.69 174,67.96 174,68.1 173.9,68.2 173.69,68.2 173.59,68.1 173.59,67.96 173.33,67.69 172.89,67.69 172.63,67.96 172.63,68.1 172.52,68.2 172.32,68.2 172.22,68.1 172.22,67.96 171.95,67.69 171.52,67.69 171.25,67.96 171.25,68.1 171.15,68.2 170.95,68.2 170.85,68.1 170.85,67.96 170.58,67.69 170.15,67.69 169.88,67.96 169.88,68.1 169.78,68.2 169.58,68.2 169.48,68.1 169.48,67.96 169.21,67.69 168.78,67.69 168.51,67.96 168.51,68.1 168.41,68.2 168.21,68.2 168.1,68.1 168.1,67.96 167.84,67.69 167.4,67.69 167.14,67.96 167.14,68.1 167.04,68.2 166.83,68.2 166.73,68.1 166.73,67.96 166.47,67.69 166.03,67.69 165.77,67.96 165.77,68.1 165.67,68.2 165.46,68.2 165.36,68.1 165.36,67.96 165.1,67.69 164.66,67.69 164.4,67.96 164.4,68.1 164.29,68.2 164.09,68.2 163.99,68.1 163.99,67.96 163.72,67.69 163.29,67.69 163.02,67.96 163.02,68.1 162.92,68.2 162.72,68.2 162.62,68.1 162.62,67.96 162.35,67.69 161.92,67.69 161.65,67.96 161.65,68.1 161.55,68.2 161.35,68.2 161.25,68.1 161.25,67.96 160.98,67.69 160.55,67.69 160.28,67.96 160.28,68.1 160.18,68.2 159.98,68.2 159.87,68.1 159.87,67.96 159.61,67.69 159.17,67.69 158.91,67.96 158.91,68.1 158.81,68.2 156.16,68.2 154.13,66.17 142.52,66.17 141.66,65.3 126.49,65.3 125.73,64.54 125.23,64.54 125.19,64.58 124.69,64.58 124.69,64.58 124.21,64.58 124.21,64.58 123.36,64.58 122.36,63.58 111.69,63.58 111.33,63.94 111.33,64.36 111.33,64.36 111.33,65.04 111.33,65.04 111.33,65.36 111.33,65.36 111.33,66.04 111.33,66.04 111.33,66.36 111.33,66.36 111.33,67.04 111.33,67.04 111.33,67.36 111.33,67.36 111.33,68.04 111.33,68.04 111.33,68.46 111.69,68.82 112.13,68.82 112.33,69.02 112.33,81.46 112.69,81.82 112.77,81.82 112.95,82 v2(112.95,82.2)
PARITY_N: length 135.4
  TOP w0.114: J4.172 200.81,51.66 200.88,51.6 201.38,51.6 v1(201.54,51.44)
  L10-SIG4 w0.102: v1(201.54,51.44) 201.54,51.45 201.26,51.72 194.11,51.72 193.03,50.65 184.92,50.65 182.64,52.93 167.88,52.93 166.99,52.04 166,52.04 165.49,52.55 154.2,52.55 154.09,52.45 153.23,52.45 153.13,52.55 152.82,52.55 152.72,52.45 151.86,52.45 151.76,52.55 151.45,52.55 151.35,52.45 150.49,52.45 150.39,52.55 150.08,52.55 149.98,52.45 149.12,52.45 149.01,52.55 148.31,52.55 147.89,52.14 147.89,51.95 147.63,51.69 147.19,51.69 146.93,51.95 146.93,52.45 146.83,52.55 146.62,52.55 146.52,52.45 146.52,51.95 146.26,51.69 145.82,51.69 145.56,51.95 145.56,52.45 145.46,52.55 145.25,52.55 145.15,52.45 145.15,51.95 144.89,51.69 144.45,51.69 144.19,51.95 144.19,52.45 144.08,52.55 143.88,52.55 143.78,52.45 143.78,51.95 143.51,51.69 143.08,51.69 142.81,51.95 142.81,52.45 142.71,52.55 142.51,52.55 142.41,52.45 142.41,51.95 142.14,51.69 141.71,51.69 141.44,51.95 141.44,52.45 141.34,52.55 141.14,52.55 141.04,52.45 141.04,51.95 140.77,51.69 140.34,51.69 140.07,51.95 140.07,52.45 139.97,52.55 139.77,52.55 139.66,52.45 139.66,51.95 139.4,51.69 138.96,51.69 138.7,51.95 138.7,52.45 138.6,52.55 138.39,52.55 138.29,52.45 138.29,51.95 138.03,51.69 137.59,51.69 137.33,51.95 137.33,52.45 137.23,52.55 137.02,52.55 136.92,52.45 136.92,51.95 136.66,51.69 136.22,51.69 135.96,51.95 135.96,52.45 135.85,52.55 135.65,52.55 135.55,52.45 135.55,51.95 135.28,51.69 134.85,51.69 134.58,51.95 134.58,52.45 134.48,52.55 134.28,52.55 134.18,52.45 134.18,51.95 133.91,51.69 133.48,51.69 133.21,51.95 133.21,52.45 133.11,52.55 132.91,52.55 132.81,52.45 132.81,51.95 132.54,51.69 132.11,51.69 131.84,51.95 131.84,52.06 131.34,52.55 130.28,52.55 126.21,48.49 109.87,48.49 107.33,51.03 107.27,51.03 107.04,51.27 107.04,51.79 107.42,52.18 v1(107.49,52.18)
  BOTTOM w0.102: 108.61,65.53 108.67,65.58 109.23,65.58 109.56,65.91 109.56,65.95 109.56,65.95 109.56,66.62 109.59,66.66
  BOTTOM w0.114: R135.1 111.28,66.68 109.61,66.68 109.59,66.66 ; v1(107.49,52.18) 107.49,52.49 107.95,52.94 107.95,63.38 108.46,63.89 108.46,64.68 108.46,65.37 108.61,65.53
PARITY_P: length 135.3
  TOP w0.114: J4.170 200.08,52.05 201.28,52.05 201.43,52.2 201.52,52.2 v1(201.55,52.23)
  L10-SIG4 w0.102: v1(201.55,52.23) 201.55,52.23 201.52,52.2 201.43,52.2 201.23,52 193.99,52 192.91,50.93 185.04,50.93 182.75,53.21 167.77,53.21 166.88,52.32 166.12,52.32 165.61,52.83 161.01,52.83 160.88,52.96 160.61,52.96 160.48,52.83 160.2,52.83 160.07,52.96 159.79,52.96 159.67,52.83 159.39,52.83 159.26,52.96 158.98,52.96 158.85,52.83 158.57,52.83 158.45,52.96 158.17,52.96 158.04,52.83 157.76,52.83 157.63,52.96 157.35,52.96 157.23,52.83 154.08,52.83 153.98,52.73 153.35,52.73 153.24,52.83 152.71,52.83 152.61,52.73 151.97,52.73 151.87,52.83 151.34,52.83 151.23,52.73 150.6,52.73 150.5,52.83 149.96,52.83 149.86,52.73 149.23,52.73 149.13,52.83 148.19,52.83 147.61,52.25 147.61,52.07 147.51,51.97 147.31,51.97 147.21,52.07 147.21,52.57 146.94,52.83 146.51,52.83 146.24,52.57 146.24,52.07 146.14,51.97 145.94,51.97 145.84,52.07 145.84,52.57 145.57,52.83 145.14,52.83 144.87,52.57 144.87,52.07 144.77,51.97 144.57,51.97 144.46,52.07 144.46,52.57 144.2,52.83 143.76,52.83 143.5,52.57 143.5,52.07 143.4,51.97 143.19,51.97 143.09,52.07 143.09,52.57 142.83,52.83 142.39,52.83 142.13,52.57 142.13,52.07 142.03,51.97 141.82,51.97 141.72,52.07 141.72,52.57 141.46,52.83 141.02,52.83 140.76,52.57 140.76,52.07 140.65,51.97 140.45,51.97 140.35,52.07 140.35,52.57 140.08,52.83 139.65,52.83 139.38,52.57 139.38,52.07 139.28,51.97 139.08,51.97 138.98,52.07 138.98,52.57 138.71,52.83 138.28,52.83 138.01,52.57 138.01,52.07 137.91,51.97 137.71,51.97 137.61,52.07 137.61,52.57 137.34,52.83 136.91,52.83 136.64,52.57 136.64,52.07 136.54,51.97 136.34,51.97 136.23,52.07 136.23,52.57 135.97,52.83 135.53,52.83 135.27,52.57 135.27,52.07 135.17,51.97 134.96,51.97 134.86,52.07 134.86,52.57 134.6,52.83 134.16,52.83 133.9,52.57 133.9,52.07 133.8,51.97 133.59,51.97 133.49,52.07 133.49,52.57 133.23,52.83 132.79,52.83 132.53,52.57 132.53,52.07 132.42,51.97 132.22,51.97 132.12,52.07 132.12,52.57 131.85,52.83 130.16,52.83 126.1,48.77 109.98,48.77 107.44,51.31 v1(107.44,51.44)
  BOTTOM w0.102: 108.41,65.72 108.49,65.8 108.57,65.8 108.57,65.81 109.13,65.81 109.33,66 109.33,66.04 109.33,66.04 109.33,66.72 109.36,66.75 109.36,66.76 109.39,66.78 109.39,66.85 109.4,66.86
  BOTTOM w0.114: 109.4,66.86 109.5,66.96 110.01,66.96 110.24,67.19 R136.1 ; 108.41,65.72 108.18,65.49 108.18,65.14 108.18,64.01 107.67,63.5 107.67,53.06 107.06,52.45 107.06,51.94 107.44,51.56 v1(107.44,51.44)
PG: length 1.5
  TOP w0.381: U7.9 34.88,114.57 R20.2
PRESENT: length 77.8
  TOP w0.178: v2(125.6,84.7) 125.47,84.84 124.59,84.84 U5.A9 ; J4.21 v1(192.67,99.17)
  L9-SIG3 w0.178: v1(192.67,99.17) 193.17,98.68 193.17,97.28 190.12,94.23 189.35,94.23 189.29,94.17 188.92,94.17 188.86,94.23 137.03,94.23 128.02,85.22 126.12,85.22 v2(125.6,84.7)
PUSHBUTTON1: length 53.4
  TOP w0.178: U5.C23 v2(122.95,70.2) ; R100.1 152.78,96.14 148.34,96.14 137.92,85.72 v1(137.92,69.22)
  L9-SIG3 w0.178: v1(137.92,69.22) 137.79,69.09 128.27,69.09 127.64,69.72 123.43,69.72 v2(122.95,70.2)
PUSHBUTTON2: length 63.8
  TOP w0.178: v1(138.94,68.2) 138.94,85.34 148.59,95 160.91,95 R101.1 ; U5.C25 v2(122.95,68.2)
  L9-SIG3 w0.102: 125.35,67.82 125.3,67.82 125.29,67.82 125.11,67.82 125.11,67.82 123.33,67.82 v2(122.95,68.2)
  L9-SIG3 w0.178: 125.35,67.82 126.87,67.82 127,67.69 128.52,67.69 129.03,67.18 131.19,67.18 131.62,67.61 138.35,67.61 v1(138.94,68.2)
PUSHBUTTON3: length 74
  TOP w0.178: v1(140.08,67.31) 140.08,85.09 148.84,93.85 162.69,93.85 164.21,95.38 170.94,95.38 R102.1 ; U5.C26 v2(122.95,67.2)
  L9-SIG3 w0.178: v1(140.08,67.31) 139.75,66.98 132.59,66.98 132.28,66.67 128.6,66.67 128.6,66.67 128.47,66.67 128.3,66.5 126.54,66.5 126.36,66.67 125.35,66.67 125.34,66.67 123.47,66.67 v2(122.95,67.2)
SYNCA_N: length 135.5
  TOP w0.114: J4.177 194.18,50.22 192.69,50.22 189.69,53.22 189.69,61.18 189.69,61.52 186.96,64.26 186.62,64.26 v1(186.55,64.18) ; U5.J26 v2(116.95,67.2)
  L9-SIG3 w0.102: v1(186.55,64.18) 186.3,64.42 186.3,64.54 186.06,64.78 185.73,64.78 185.49,64.54 184.91,64.54 183.29,66.17 181.86,66.17 181.37,66.66 181.36,66.66 181.09,66.93 180.77,66.93 180.39,66.55 180.39,65.99 180.29,65.89 180.09,65.89 179.99,65.99 179.99,66.66 179.72,66.93 179.29,66.93 179.02,66.66 179.02,65.99 178.92,65.89 178.72,65.89 178.62,65.99 178.62,66.66 178.35,66.93 177.92,66.93 177.65,66.66 177.65,65.99 177.55,65.89 177.35,65.89 177.24,65.99 177.24,66.66 176.98,66.93 176.54,66.93 176.28,66.66 176.28,65.99 176.18,65.89 175.97,65.89 175.87,65.99 175.87,66.66 175.61,66.93 175.17,66.93 174.91,66.66 174.91,65.99 174.81,65.89 174.6,65.89 174.5,65.99 174.5,66.66 174.24,66.93 173.8,66.93 173.54,66.66 173.54,65.99 173.43,65.89 173.23,65.89 173.13,65.99 173.13,66.66 172.86,66.93 172.43,66.93 172.16,66.66 172.16,65.99 172.06,65.89 171.86,65.89 171.76,65.99 171.76,66.66 171.49,66.93 171.06,66.93 170.79,66.66 170.79,65.99 170.69,65.89 170.49,65.89 170.39,65.99 170.39,66.66 170.12,66.93 169.69,66.93 169.42,66.66 169.42,65.99 169.32,65.89 169.12,65.89 169.02,65.99 169.02,66.66 168.75,66.93 168.32,66.93 168.05,66.66 168.05,65.99 167.95,65.89 167.75,65.89 167.64,65.99 167.64,66.66 167.38,66.93 166.94,66.93 166.68,66.66 166.68,65.99 166.58,65.89 166.37,65.89 166.27,65.99 166.27,66.66 166.01,66.93 165.57,66.93 165.31,66.66 165.31,65.99 165.21,65.89 165,65.89 164.9,65.99 164.9,66.66 164.64,66.93 164.2,66.93 163.94,66.66 163.94,65.99 163.83,65.89 163.63,65.89 163.53,65.99 163.53,66.66 163.26,66.93 162.83,66.93 162.56,66.66 162.56,65.99 162.46,65.89 162.26,65.89 162.16,65.99 162.16,66.66 161.89,66.93 161.46,66.93 161.19,66.66 161.19,65.99 161.09,65.89 160.89,65.89 160.79,65.99 160.79,66.66 160.52,66.93 160.09,66.93 159.82,66.66 159.82,65.99 159.72,65.89 159.52,65.89 159.41,65.99 159.41,66.66 159.15,66.93 158.71,66.93 158.45,66.66 158.45,65.99 158.35,65.89 158.14,65.89 158.04,65.99 158.04,66.66 157.78,66.93 157.34,66.93 157.08,66.66 157.08,65.99 156.98,65.89 156.77,65.89 156.67,65.99 156.67,66.66 156.41,66.93 155.97,66.93 155.71,66.66 155.71,65.99 155.6,65.89 155.4,65.89 155.3,65.99 155.3,66.66 155.03,66.93 154.6,66.93 154.33,66.66 154.33,65.99 154.23,65.89 154.03,65.89 153.93,65.99 153.93,66.66 153.66,66.93 153.23,66.93 152.96,66.66 152.96,65.99 152.86,65.89 152.66,65.89 152.56,65.99 152.56,66.66 152.29,66.93 151.86,66.93 151.59,66.66 151.59,65.99 151.49,65.89 151.29,65.89 151.18,65.99 151.18,66.66 150.92,66.93 150.48,66.93 150.22,66.66 150.22,65.99 150.12,65.89 149.91,65.89 149.81,65.99 149.81,66.66 149.55,66.93 149.11,66.93 148.85,66.66 148.85,65.99 148.75,65.89 148.54,65.89 148.44,65.99 148.44,66.66 148.18,66.93 147.74,66.93 147.48,66.66 147.48,66.45 146.91,65.89 146.26,65.89 143.19,62.81 133.74,62.81 133.44,62.51 125.38,62.51 125.07,62.82 123.62,62.82 122.4,64.03 119.91,64.03 118.72,65.23 118.72,65.63 117.53,66.82 116.75,66.82 116.59,66.98 116.58,66.98 116.57,66.99 116.57,67.5 116.66,67.59 116.87,67.59 116.97,67.49 116.97,67.22 v2(116.95,67.2)
SYNCA_P: length 135.4
  TOP w0.114: v1(185.89,64.37) 186.11,64.59 186.72,64.59 186.72,64.59 186.87,64.59 186.92,64.54 187.07,64.54 189.97,61.64 189.97,61.41 189.97,61.29 189.97,53.33 192.8,50.5 194.08,50.5 J4.175 ; U5.K25 v2(115.95,68.2)
  L9-SIG3 w0.102: v1(185.89,64.37) 185.77,64.37 185.66,64.26 184.8,64.26 183.27,65.79 181.85,65.79 181.25,66.38 181.24,66.38 181.16,66.47 181.03,66.47 180.67,66.12 180.67,65.87 180.41,65.61 179.97,65.61 179.71,65.87 179.71,66.55 179.61,66.65 179.4,66.65 179.3,66.55 179.3,65.87 179.04,65.61 178.6,65.61 178.34,65.87 178.34,66.55 178.24,66.65 178.03,66.65 177.93,66.55 177.93,65.87 177.67,65.61 177.23,65.61 176.97,65.87 176.97,66.55 176.86,66.65 176.66,66.65 176.56,66.55 176.56,65.87 176.29,65.61 175.86,65.61 175.59,65.87 175.59,66.55 175.49,66.65 175.29,66.65 175.19,66.55 175.19,65.87 174.92,65.61 174.49,65.61 174.22,65.87 174.22,66.55 174.12,66.65 173.92,66.65 173.82,66.55 173.82,65.87 173.55,65.61 173.12,65.61 172.85,65.87 172.85,66.55 172.75,66.65 172.55,66.65 172.44,66.55 172.44,65.87 172.18,65.61 171.74,65.61 171.48,65.87 171.48,66.55 171.38,66.65 171.17,66.65 171.07,66.55 171.07,65.87 170.81,65.61 170.37,65.61 170.11,65.87 170.11,66.55 170.01,66.65 169.8,66.65 169.7,66.55 169.7,65.87 169.44,65.61 169,65.61 168.74,65.87 168.74,66.55 168.63,66.65 168.43,66.65 168.33,66.55 168.33,65.87 168.06,65.61 167.63,65.61 167.36,65.87 167.36,66.55 167.26,66.65 167.06,66.65 166.96,66.55 166.96,65.87 166.69,65.61 166.26,65.61 165.99,65.87 165.99,66.55 165.89,66.65 165.69,66.65 165.59,66.55 165.59,65.87 165.32,65.61 164.89,65.61 164.62,65.87 164.62,66.55 164.52,66.65 164.32,66.65 164.21,66.55 164.21,65.87 163.95,65.61 163.51,65.61 163.25,65.87 163.25,66.55 163.15,66.65 162.94,66.65 162.84,66.55 162.84,65.87 162.58,65.61 162.14,65.61 161.88,65.87 161.88,66.55 161.78,66.65 161.57,66.65 161.47,66.55 161.47,65.87 161.21,65.61 160.77,65.61 160.51,65.87 160.51,66.55 160.4,66.65 160.2,66.65 160.1,66.55 160.1,65.87 159.83,65.61 159.4,65.61 159.13,65.87 159.13,66.55 159.03,66.65 158.83,66.65 158.73,66.55 158.73,65.87 158.46,65.61 158.03,65.61 157.76,65.87 157.76,66.55 157.66,66.65 157.46,66.65 157.36,66.55 157.36,65.87 157.09,65.61 156.66,65.61 156.39,65.87 156.39,66.55 156.29,66.65 156.09,66.65 155.98,66.55 155.98,65.87 155.72,65.61 155.29,65.61 155.02,65.87 155.02,66.55 154.92,66.65 154.71,66.65 154.61,66.55 154.61,65.87 154.35,65.61 153.91,65.61 153.65,65.87 153.65,66.55 153.55,66.65 153.34,66.65 153.24,66.55 153.24,65.87 152.98,65.61 152.54,65.61 152.28,65.87 152.28,66.55 152.17,66.65 151.97,66.65 151.87,66.55 151.87,65.87 151.6,65.61 151.17,65.61 150.9,65.87 150.9,66.55 150.8,66.65 150.6,66.65 150.5,66.55 150.5,65.87 150.23,65.61 149.8,65.61 149.53,65.87 149.53,66.55 149.43,66.65 149.23,66.65 149.13,66.55 149.13,65.87 148.86,65.61 148.43,65.61 148.16,65.87 148.16,66.55 148.06,66.65 147.86,66.65 147.76,66.55 147.76,66.33 147.03,65.61 146.38,65.61 143.31,62.53 133.86,62.53 133.55,62.23 125.32,62.23 124.97,62.58 123.52,62.58 122.3,63.8 119.79,63.8 119.79,63.82 118.48,65.13 118.48,65.53 117.44,66.58 116.65,66.58 116.49,66.74 116.48,66.74 116.33,66.89 116.33,67.82 v2(115.95,68.2)
TP_CMOS_1: length 54
  TOP w0.178: U5.B6 123.99,88.24 125.75,88.24 126.11,87.88 127.76,87.88 130.3,90.42 130.3,96.27 126.24,100.33 126.24,124.97 TP29.1
TP_CMOS_2: length 51.5
  TOP w0.178: U5.B8 123.45,85.73 123.96,86.24 125.09,86.24 125.47,86.61 127.64,86.61 130.94,89.92 130.94,96.65 127.13,100.46 127.13,122.3 TP28.1
TP_CMOS_3: length 48.9
  TOP w0.178: U5.B9 123.99,85.24 127.53,85.24 131.57,89.28 131.57,96.9 128.02,100.46 128.02,119.63 TP13.1
TXEN: length 74.7
  TOP w0.178: v2(125.6,85.85) 125.45,85.7 U5.A8 ; J4.27 v1(192.67,97.67)
  L9-SIG3 w0.178: v2(125.6,85.85) 125.71,85.85 126.06,86.2 127.73,86.2 136.4,94.87 187.58,94.87 190.37,97.66 192.66,97.66 v1(192.67,97.67)
USB_EECLK: length 6.5
  TOP w0.178: U3.62 190.08,127.46 190.5,127.89 R6.2 193.04,127.25 U4.2
USB_EECS: length 6.7
  TOP w0.178: U4.1 192.91,128.52 R5.2 190.75,129.03 189.69,127.96 U3.63
USB_REF: length 2.2
  TOP w0.305: U3.6 v1(183.62,131.7)
  BOTTOM w0.305: R4.1 183.62,130.86 v1(183.62,131.7)
USB_RST: length 2.2
  TOP w0.178: U3.14 179.62,132.52 R3.1
USB_VBUS: length 11.4
  TOP w0.508: J5.1 184.1,143.18 185.29,141.99 L3.1 v1(185.29,140.46) ; R46.1 v1(181.23,136.14)
  BOTTOM w0.508: v1(181.23,136.14) 181.23,137.48 184.21,140.46 v1(185.29,140.46)
USER_DIP0: length 64.1
  TOP w0.178: v1(166.62,54.36) R80.2 166.24,53.34 SW1.8 ; U5.B23 v2(123.95,70.2)
  L3-SIG1 w0.178: v2(123.95,70.2) 123.95,69.85 124.43,69.37 124.43,68.1 124.84,67.69 125.2,67.69 126.11,66.78 126.11,64.52 126.49,64.14 126.49,63.25 126.24,62.99 126.24,56.26 126.49,56.01 v1(126.49,52.32)
  L4-SIG2 w0.178: v1(126.49,52.32) 126.75,52.07 155.58,52.07 156.03,52.51 156.39,52.51 156.84,52.07 164.34,52.07 v1(166.62,54.36)
USER_DIP1: length 65.6
  TOP w0.178: U5.B24 v2(123.95,69.2) ; SW1.7 166.37,52.07 R81.2 v1(166.62,52.96)
  L3-SIG1 w0.178: v2(123.95,69.2) 123.44,68.69 123.44,67.94 123.7,67.69 124.21,67.69 124.46,67.44 124.46,66.93 124.71,66.67 125.22,66.67 125.45,66.45 125.45,58.65 124.21,57.4 124.21,52.2 v1(124.84,51.56)
  L4-SIG2 w0.178: v1(124.84,51.56) 124.97,51.44 165.1,51.44 v1(166.62,52.96)
USER_DIP2: length 62.9
  TOP w0.178: SW1.6 166.5,50.8 R82.2 v1(166.62,50.04) ; U5.B26 v2(123.95,67.2)
  L3-SIG1 w0.178: v2(123.95,67.2) 123.95,66.93 124.46,66.42 124.46,58.8 123.44,57.78 123.44,51.94 v1(125.09,50.3)
  L4-SIG2 w0.178: v1(125.09,50.3) 125.09,50.29 166.37,50.29 v1(166.62,50.04)
USER_DIP3: length 63.9
  TOP w0.178: v1(166.62,48.64) R83.2 166.37,49.53 SW1.5 ; U5.B27 v2(123.95,66.2)
  L3-SIG1 w0.178: v2(123.95,66.2) 123.44,65.69 123.44,58.8 122.56,57.91 122.56,51.05 v1(123.57,50.04)
  L4-SIG2 w0.178: v1(123.57,50.04) 124.97,48.64 v1(166.62,48.64)
USER_LED0: length 40.7
  TOP w0.178: U5.A22 v2(124.95,71.2) ; D2.2 v1(149.1,87.25)
  L9-SIG3 w0.102: v2(124.95,71.2) 124.97,71.22
  L9-SIG3 w0.178: v1(149.1,87.25) 147.7,85.85 147.7,78.49 148.97,77.22 148.97,76.2 144.27,71.5 136.43,71.5 136.34,71.59 133.06,71.59 131.95,70.48 131.06,70.48 130.61,70.94 128.8,70.94 128.53,71.22 124.97,71.22
USER_LED1: length 38.1
  TOP w0.178: U5.A23 v2(124.95,70.2) ; D3.2 v1(149.1,83.31)
  L9-SIG3 w0.102: v2(124.95,70.2) 125.01,70.26
  L9-SIG3 w0.178: v1(149.1,83.31) 148.34,82.55 148.34,79.12 149.99,77.47 149.99,75.44 145.29,70.74 136.14,70.74 135.69,70.28 132.94,70.28 132.64,69.98 129.51,69.98 129.24,70.26 125.01,70.26
USER_LED2: length 35.6
  TOP w0.178: U5.A24 v2(124.95,69.2) ; D4.2 v1(149.1,79.38)
  L9-SIG3 w0.178: v2(124.95,69.2) 124.97,69.22 127.28,69.22 128.02,68.48 138.15,68.48 138.94,69.27 145.08,69.27 150.62,74.8 150.62,77.85 v1(149.1,79.38)
USER_LED3: length 28.9
  TOP w0.178: D5.2 v1(149.1,75.44) ; U5.A25 v2(124.95,68.2)
  L10-SIG4 w0.178: v2(124.95,68.2) 126.49,68.2 127,68.71 138.46,68.71 144.22,74.47 148.13,74.47 v1(149.1,75.44)
USER_LED4: length 27.7
  TOP w0.178: D6.2 v1(149.1,71.5) ; U5.A26 v2(124.95,67.2)
  L4-SIG2 w0.178: v1(149.1,71.5) 147.83,70.23 137.79,70.23 135.89,68.33 128.7,68.33 128.04,67.67 125.4,67.67 124.95,67.22 v2(124.95,67.2)
USER_LED5: length 27.8
  TOP w0.178: D7.2 v1(149.1,67.56) ; U5.A27 v2(124.95,66.2)
  L4-SIG2 w0.178: v1(149.1,67.56) 147.57,69.09 138.68,69.09 136.4,66.8 130.56,66.8 129.92,66.17 124.98,66.17 v2(124.95,66.2)
USER_LED6: length 30.7
  TOP w0.178: U5.A28 v2(124.95,65.2) ; D8.2 v1(149.1,63.63)
  L4-SIG2 w0.178: v2(124.95,65.2) 125.15,65 130.68,65 130.88,65.2 136.83,65.2 139.83,68.2 146.94,68.2 149.1,66.04 v1(149.1,63.63)
USER_LED7: length 33.6
  TOP w0.178: U5.A29 v2(124.95,64.2) ; D9.2 v1(149.1,59.69)
  L4-SIG2 w0.178: v2(124.95,64.2) 125.03,64.2 125.03,64.2 131.19,64.2 131.76,63.63 132.52,63.63 133.1,64.2 137.99,64.2 141.1,67.31 146.18,67.31 148.08,65.41 148.08,60.71 v1(149.1,59.69)
N16774346: length 64.4
  TOP w0.254: v2(108.95,70.2) U5.U23 U5.V23 v2(106.95,70.2) ; v2(108.95,82.2) U5.U12 U5.V12 v2(106.95,82.2) ; U5.AH17 v2(96.95,77.2) ; U5.G17 v2(118.95,77.2)
  L4-SIG2 w0.254: v2(118.95,77.2) 118.48,77.67 114.4,77.67 113.03,76.3 109.19,76.3 108.33,75.44 108.33,71.04 108.95,70.42 v2(108.95,70.2) v2(106.95,70.2)
  L10-SIG4 w0.254: v2(108.95,82.2) 109.47,81.68 109.47,70.72 v2(108.95,70.2)
  BOTTOM w0.254: 91.69,77.34 92.58,76.45 96.14,76.45 96.88,77.2 v2(96.95,77.2) 97.57,76.58 101.22,76.58 101.85,77.22 101.85,80.01 102.55,80.71 106.23,80.71 106.45,80.92 106.45,81.7 v2(106.95,82.2)
  BOTTOM w0.508: 91.69,77.34 FB6.2
N24747082: length 2.8
  TOP w0.178: U4.4 R8.2 R7.2
N25673570: length 5.7
  TOP w0.305: U3.9 v1(182.12,131.7)
  BOTTOM w0.508: v1(182.12,131.7) 182.12,132.56 C1.1 C2.1 178.79,132.69 FB1.2
N25674940: length 5.7
  TOP w0.305: U3.4 v1(184.62,131.7)
  BOTTOM w0.508: v1(184.62,131.7) 184.62,132.6 C6.1 C5.1 187.86,132.69 FB2.2
N26521020: length 3.4
  TOP w0.178: R63.1 R150.2 R59.2
N26523726: length 2.2
  TOP w0.178: R62.1 R58.2 R151.2
N26526427: length 3.4
  TOP w0.178: R149.2 R126.1 R61.1 R57.2
N26529134: length 2.2
  TOP w0.178: R152.2 131.7,60.83
N27224376: length 2.7
  TOP w0.114: J5.3 182.5,143.13 182.73,142.9 182.73,142.37 R2.1
N27224380: length 2.8
  TOP w0.114: R1.1 183.01,142.39 183.01,142.88 183.3,143.17 J5.2
N27319544: length 6.9
  TOP w0.178: C20.1 188.87,133.58 Y1.1 188.81,133.31 187.58,132.08 186.34,132.08 185.62,131.36 U3.2
N27322325: length 8.1
  TOP w0.178: U3.3 185.12,133.56 187.11,135.55 Y1.3 187.11,137.48 C21.1
N28576814: length 29
  BOTTOM w0.178: J3.109 92.95,145.41 92.69,145.67 90.04,145.67 83.31,138.94 73.15,138.94 71.63,140.46 71.63,141.1 JP7.1
N28621539: length 2.6
  TOP w0.178: 179.58,135.51 R3.2 ; 179.58,135.51 R46.2 ; 179.58,135.51 R45.1
N28765295: length 19.6
  BOTTOM w0.178: JP5.1 85.34,142.75 89.03,146.43 93.09,146.43 93.95,145.58 J3.105
N28765297: length 23.6
  BOTTOM w0.178: JP6.1 75.06,141.48 84.96,141.48 89.53,146.05 92.84,146.05 93.45,145.44 J3.107
N29450409: length 5.1
  TOP w0.165: J7.1 C46.1
N32875249: length 6
  TOP w0.178: U5.AK29 v2(94.95,64.2)
  BOTTOM w0.178: v2(94.95,64.2) 94.93,64.2 94.44,63.7 90.12,63.7 R17.2
N32875251: length 5
  TOP w0.178: U5.AL28 v2(93.95,65.2)
  BOTTOM w0.178: v2(93.95,65.2) 93.95,65.2 93.42,64.67 89.94,64.67 R18.2
N35298740: length 79.2
  TOP w0.254: U5.H18 v2(117.95,75.2) ; U5.V24 v2(106.95,69.2) ; U5.AG18 v2(97.95,75.2) ; U5.U11 v2(108.95,83.2)
  BOTTOM w0.254: v2(117.95,75.2) 117.95,74.9 117.45,74.4 117.45,73.94 117.2,73.69 116.36,73.69 114.38,71.71 108.56,71.71 107.87,71.02 107.87,70.15 106.97,69.25 106.97,69.22 v2(106.95,69.2) 106.47,69.68 103.39,69.68 99.97,73.1 99.14,73.1 98.42,73.81 98.42,74.72 ; 108.36,82.58 108.96,83.18 108.96,83.18 108.95,83.19 108.96,83.19 109.46,83.69 119.38,83.69 120.41,84.72 120.41,85.48 120.78,85.85 122.17,85.85 122.41,85.62 ; 108.36,82.58 108.36,76.48 107.7,75.82 102.74,75.82 101.6,74.68 98.47,74.68 98.42,74.72 ; 108.36,82.58 108.36,82.61 v2(108.95,83.2) ; 98.42,74.72 v2(97.95,75.2)
  BOTTOM w0.508: 122.41,85.62 124.48,85.62 125.35,86.49 126.36,86.49 131.32,91.44 C332.1 C329.1 FB5.2
